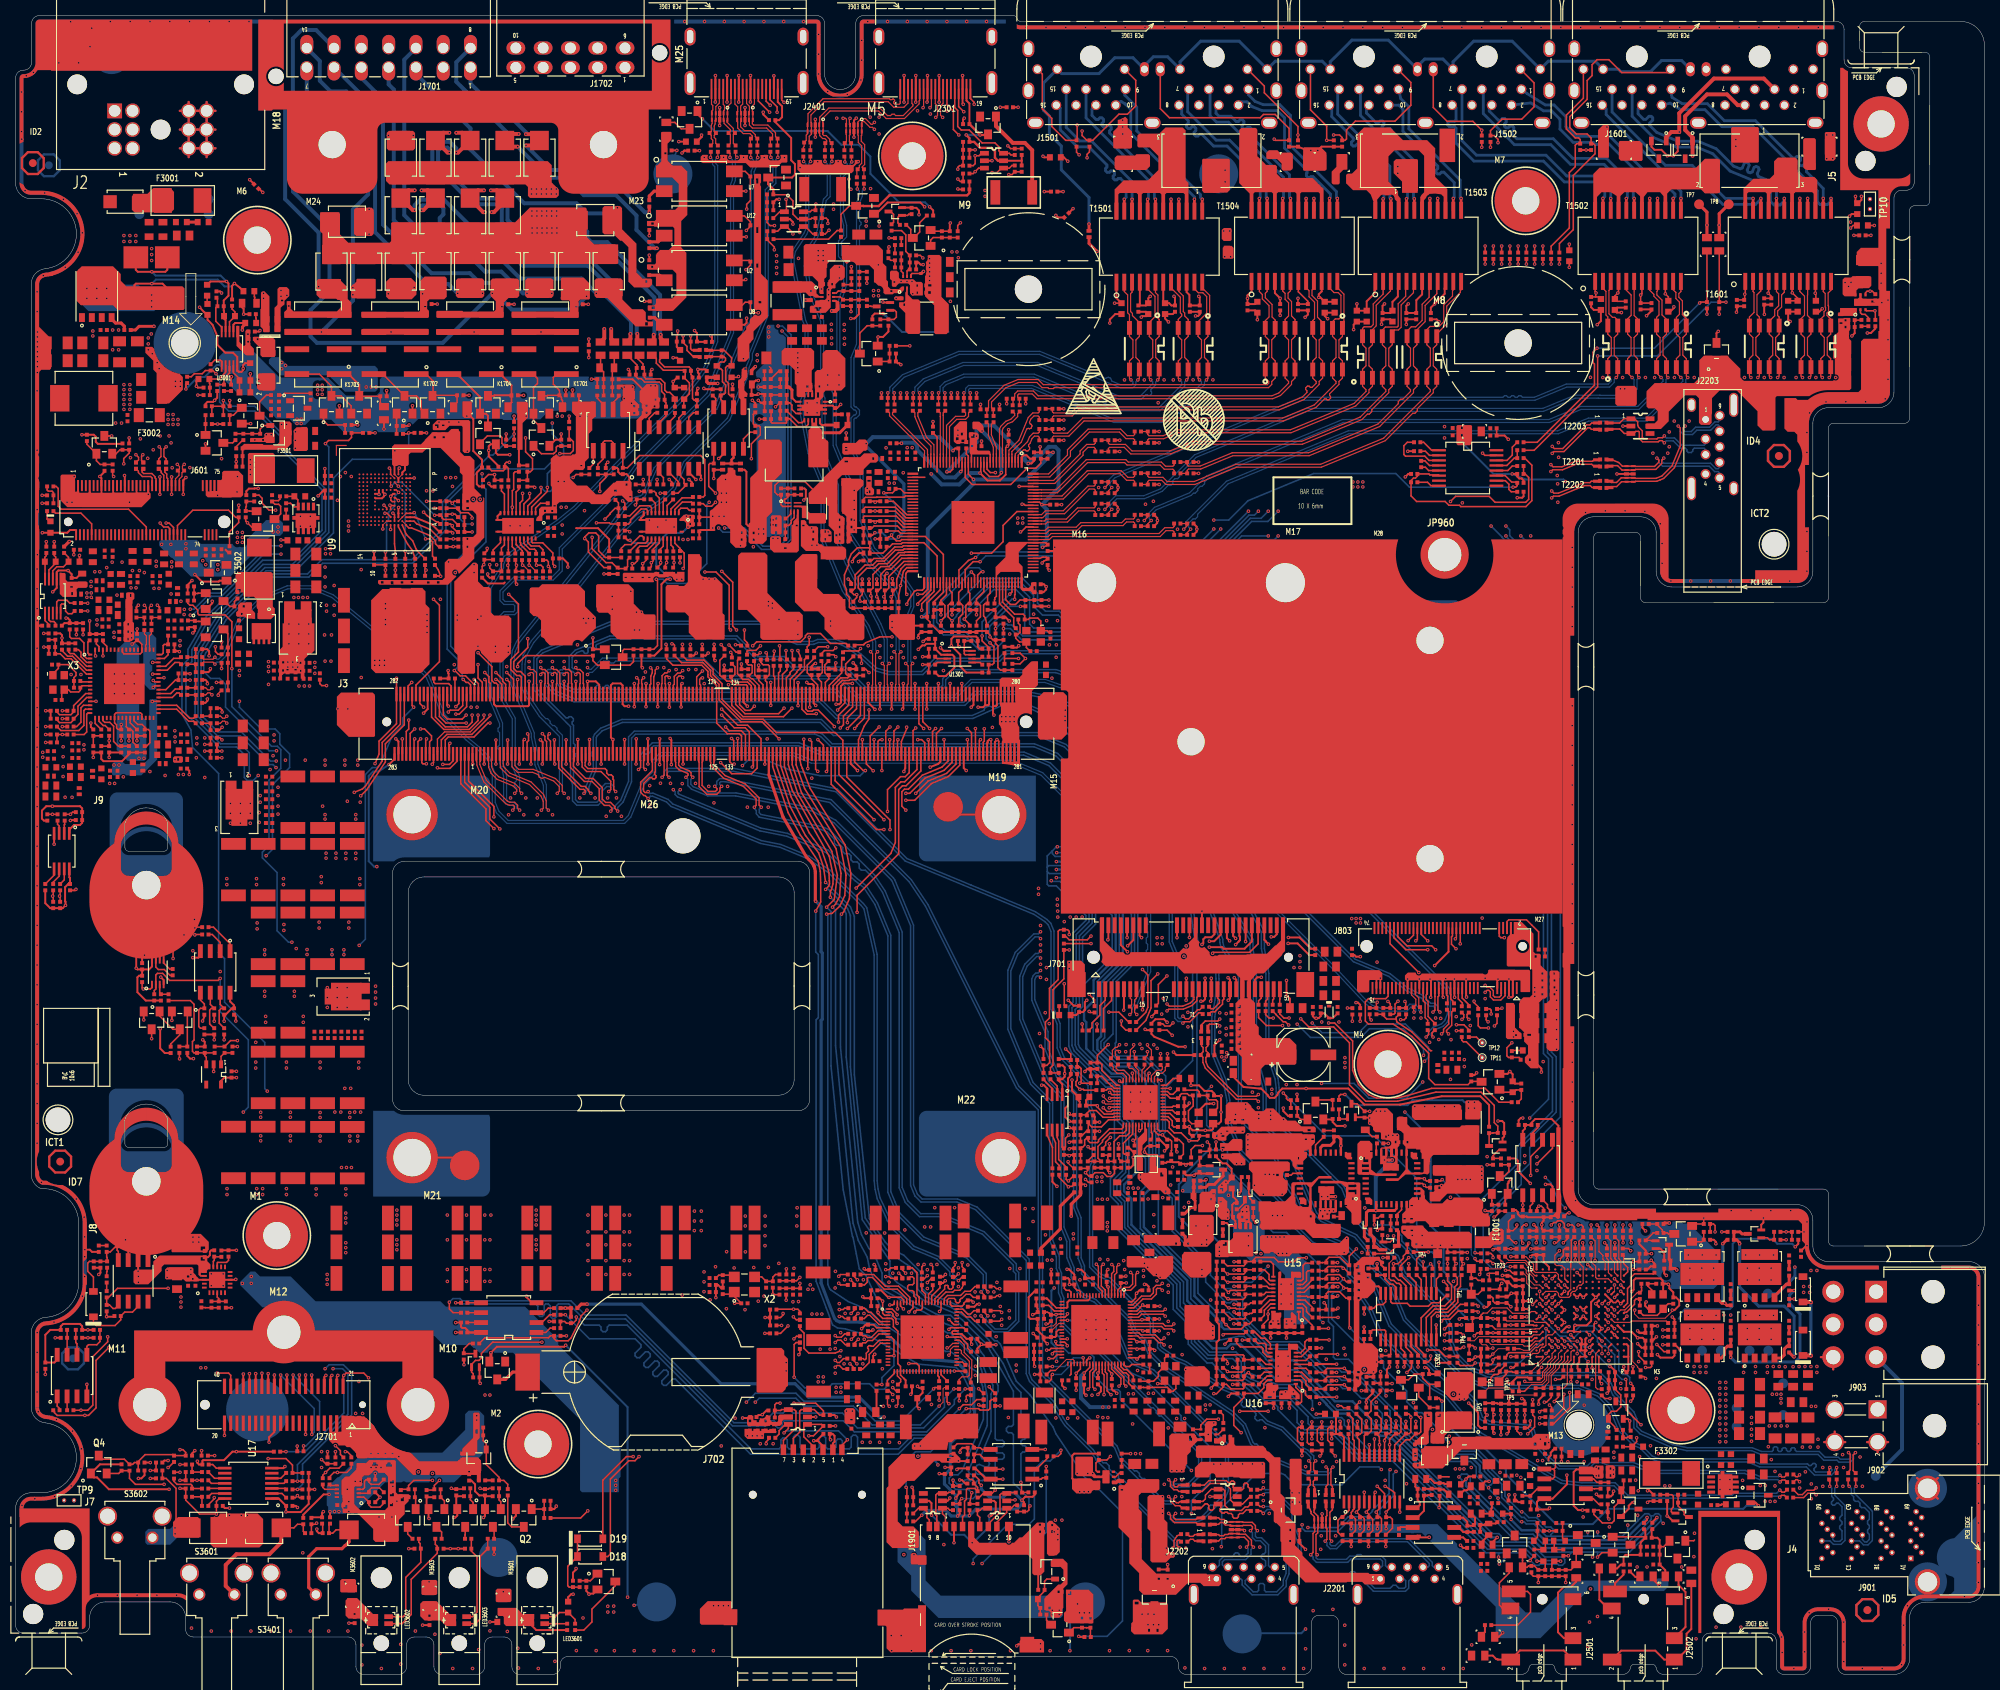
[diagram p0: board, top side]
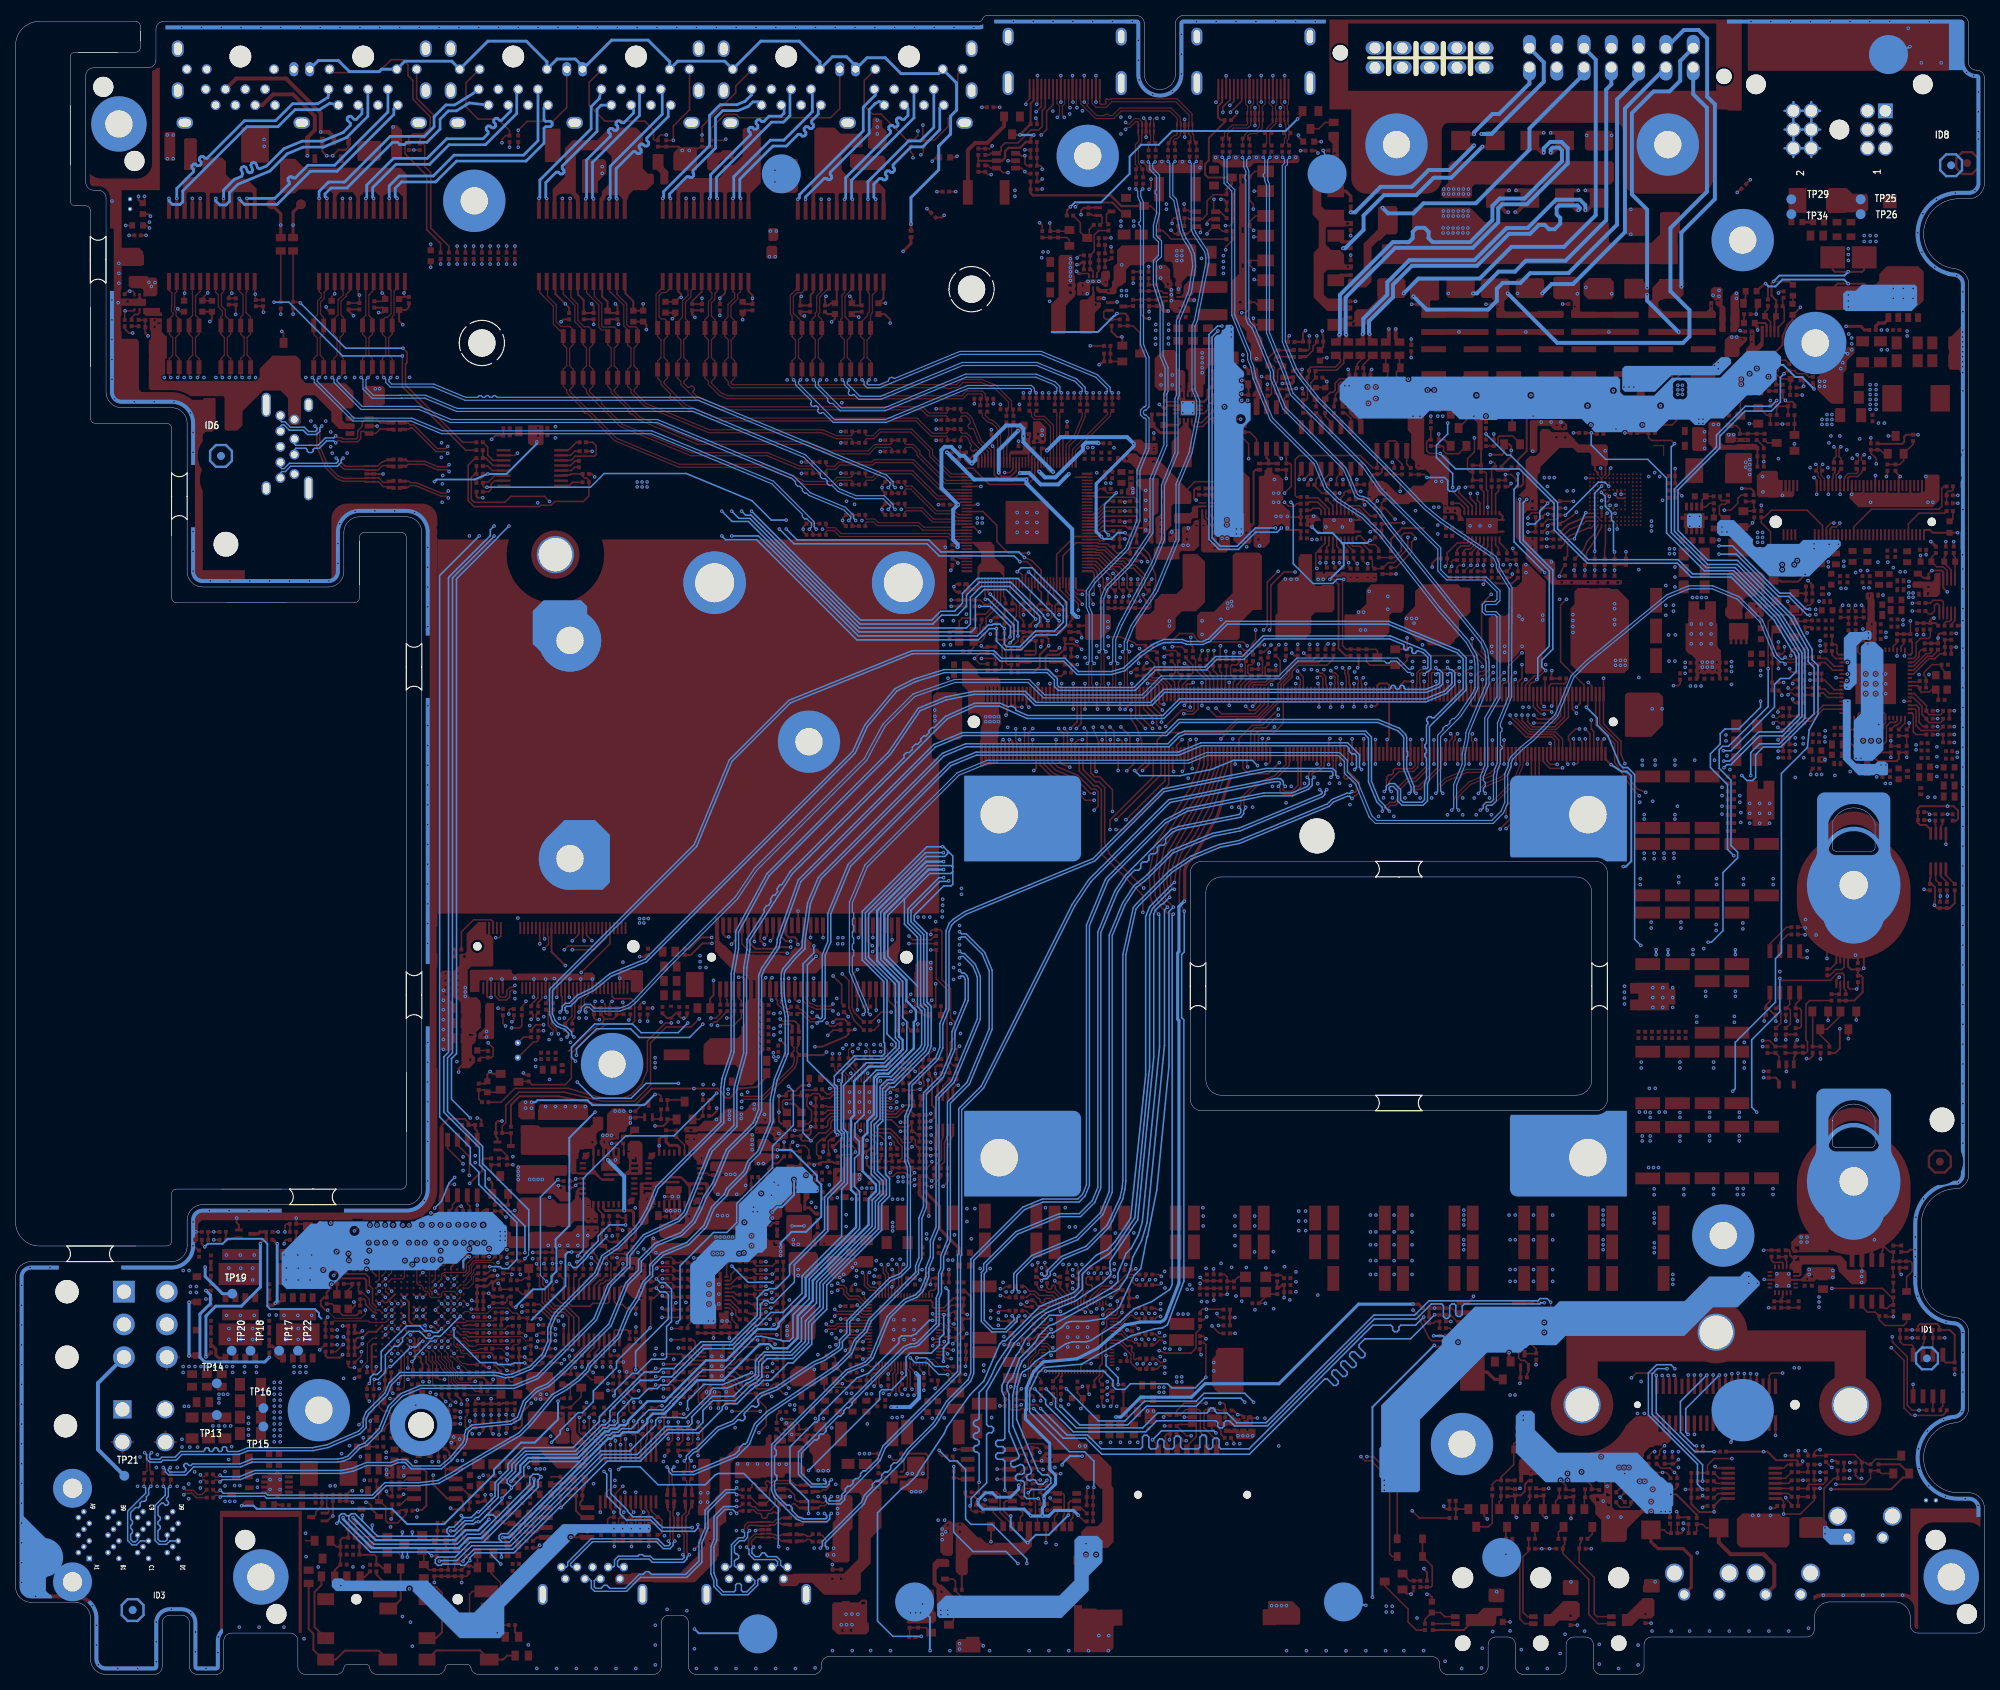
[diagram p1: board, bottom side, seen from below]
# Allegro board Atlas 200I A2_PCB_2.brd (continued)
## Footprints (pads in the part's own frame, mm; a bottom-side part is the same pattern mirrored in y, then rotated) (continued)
MLF8A-050-0203L
  rect 0.254x0.559 smd: 1(-0.75,-1.389) 2(-0.25,-1.389) 3(0.25,-1.389) 4(0.75,-1.389) 5(0.75,1.389) 6(0.25,1.389) 7(-0.25,1.389) 8(-0.75,1.389)
  rect 1.524x1.27 smd: 9(0,0)
MLF10B-050-0301L
  rect 0.254x0.533 smd: 1(-1,-0.417) 2(-0.5,-0.417) 4(0.5,-0.417) 5(1,-0.417) 6(1,0.417) 7(0.5,0.417) 9(-0.5,0.417) 10(-1,0.417)
  rect 0.432x0.686 smd: 3(0,-0.417) 8(0,0.417)
MLF14A-050-0404L
  rect 0.559x0.254 smd: 1(-1.629,-0.75) 7(1.629,-0.75) 8(1.629,0.75) 14(-1.629,0.75)
  rect 0.254x0.559 smd: 2(-1,-1.629) 3(-0.5,-1.629) 4(0,-1.629) 5(0.5,-1.629) 6(1,-1.629) 9(1,1.629) 10(0.5,1.629) 11(0,1.629) 12(-0.5,1.629) 13(-1,1.629)
  custom 0.508x0.508 smd: 15(0,0)
MLF20J-050-0404L
  rect 0.254x0.61 smd: 1(-1,-1.652) 2(-0.5,-1.652) 3(0,-1.652) 4(0.5,-1.652) 5(1,-1.652) 11(1,1.652) 12(0.5,1.652) 13(0,1.652) 14(-0.5,1.652) 15(-1,1.652)
  rect 0.61x0.254 smd: 6(1.652,-1) 7(1.652,-0.5) 8(1.652,0) 9(1.652,0.5) 10(1.652,1) 16(-1.652,1) 17(-1.652,0.5) 18(-1.652,0) 19(-1.652,-0.5) 20(-1.652,-1)
  rect 2.032x2.032 smd: 21(0,0)
MLF24D-050-0604L
  rect 0.559x0.254 smd: 1(-2.629,-0.75) 12(2.629,-0.75) 13(2.629,0.75) 24(-2.629,0.75)
  rect 0.254x0.559 smd: 2(-2.25,-1.629) 3(-1.75,-1.629) 4(-1.25,-1.629) 5(-0.75,-1.629) 6(-0.25,-1.629) 7(0.25,-1.629) 8(0.75,-1.629) 9(1.25,-1.629) 10(1.75,-1.629) 11(2.25,-1.629) 14(2.25,1.629) 15(1.75,1.629) 16(1.25,1.629) 17(0.75,1.629) 18(0.25,1.629) 19(-0.25,1.629) 20(-0.75,1.629) 21(-1.25,1.629) 22(-1.75,1.629) 23(-2.25,1.629)
  rect 4.064x2.032 smd: 25(0,0)
MLF36A-065-0707L
  rect 0.254x0.635 smd: 1(-2.604,-3.072) 9(2.602,-3.063) 27(-2.598,3.078)
  rect 0.305x0.813 smd: 2(-1.95,-3.306) 3(-1.3,-3.306) 4(-0.65,-3.306) 5(0,-3.306) 6(0.65,-3.306) 7(1.3,-3.306) 8(1.95,-3.306) 20(1.95,3.306) 21(1.3,3.306) 22(0.65,3.306) 23(0,3.306) 24(-0.65,3.306) 25(-1.3,3.306) 26(-1.95,3.306)
  custom 0.238x0.238 smd: 10(2.926,-2.926) 19(2.926,2.926) 28(-2.926,2.926) 36(-2.926,-2.926)
  rect 0.813x0.305 smd: 11(3.306,-1.95) 12(3.306,-1.3) 13(3.306,-0.65) 14(3.306,0) 15(3.306,0.65) 16(3.306,1.3) 17(3.306,1.95) 29(-3.306,1.95) 30(-3.306,1.3) 31(-3.306,0.65) 32(-3.306,0) 33(-3.306,-0.65) 34(-3.306,-1.3) 35(-3.306,-1.95)
  rect 0.635x0.254 smd: 18(3.059,2.599)
  rect 0.813x0.813 smd: 37(-1.421,-0.68) 38(-1.421,0.52)
  rect 0.305x2.591 smd: 39(-0.47,-0.65)
  rect 0.305x1.575 smd: 40(0.157,0.07)
MLF48A-040-0606L
  rect 0.203x0.61 smd: 1(-2.2,-2.879) 2(-1.8,-2.879) 3(-1.4,-2.879) 4(-1,-2.879) 5(-0.6,-2.879) 6(-0.2,-2.879) 7(0.2,-2.879) 8(0.6,-2.879) 9(1,-2.879) 10(1.4,-2.879) 11(1.8,-2.879) 12(2.2,-2.879) 25(2.2,2.879) 26(1.8,2.879) 27(1.4,2.879) 28(1,2.879) 29(0.6,2.879) 30(0.2,2.879) 31(-0.2,2.879) 32(-0.6,2.879) 33(-1,2.879) 34(-1.4,2.879) 35(-1.8,2.879) 36(-2.2,2.879)
  rect 0.61x0.203 smd: 13(2.879,-2.2) 14(2.879,-1.8) 15(2.879,-1.4) 16(2.879,-1) 17(2.879,-0.6) 18(2.879,-0.2) 19(2.879,0.2) 20(2.879,0.6) 21(2.879,1) 22(2.879,1.4) 23(2.879,1.8) 24(2.879,2.2) 37(-2.879,2.2) 38(-2.879,1.8) 39(-2.879,1.4) 40(-2.879,1) 41(-2.879,0.6) 42(-2.879,0.2) 43(-2.879,-0.2) 44(-2.879,-0.6) 45(-2.879,-1) 46(-2.879,-1.4) 47(-2.879,-1.8) 48(-2.879,-2.2)
  rect 4.445x4.445 smd: 49(0,0)
MLF64AG-050-0909L
  rect 0.254x0.559 smd: 1(-3.75,-4.379) 2(-3.25,-4.379) 3(-2.75,-4.379) 4(-2.25,-4.379) 5(-1.75,-4.379) 6(-1.25,-4.379) 7(-0.75,-4.379) 8(-0.25,-4.379) 9(0.25,-4.379) 10(0.75,-4.379) 11(1.25,-4.379) 12(1.75,-4.379) 13(2.25,-4.379) 14(2.75,-4.379) 15(3.25,-4.379) 16(3.75,-4.379) 33(3.75,4.379) 34(3.25,4.379) 35(2.75,4.379) 36(2.25,4.379) 37(1.75,4.379) 38(1.25,4.379) 39(0.75,4.379) 40(0.25,4.379) 41(-0.25,4.379) 42(-0.75,4.379) 43(-1.25,4.379) 44(-1.75,4.379) 45(-2.25,4.379) 46(-2.75,4.379) 47(-3.25,4.379) 48(-3.75,4.379)
  rect 0.559x0.254 smd: 17(4.379,-3.75) 18(4.379,-3.25) 19(4.379,-2.75) 20(4.379,-2.25) 21(4.379,-1.75) 22(4.379,-1.25) 23(4.379,-0.75) 24(4.379,-0.25) 25(4.379,0.25) 26(4.379,0.75) 27(4.379,1.25) 28(4.379,1.75) 29(4.379,2.25) 30(4.379,2.75) 31(4.379,3.25) 32(4.379,3.75) 49(-4.379,3.75) 50(-4.379,3.25) 51(-4.379,2.75) 52(-4.379,2.25) 53(-4.379,1.75) 54(-4.379,1.25) 55(-4.379,0.75) 56(-4.379,0.25) 57(-4.379,-0.25) 58(-4.379,-0.75) 59(-4.379,-1.25) 60(-4.379,-1.75) 61(-4.379,-2.25) 62(-4.379,-2.75) 63(-4.379,-3.25) 64(-4.379,-3.75)
  rect 5.207x5.207 smd: 65(0,0)
MLF76L-040-0909L
  rect 0.203x0.61 smd: 1(-3.6,-4.405) 2(-3.2,-4.405) 3(-2.8,-4.405) 4(-2.4,-4.405) 5(-2,-4.405) 6(-1.6,-4.405) 7(-1.2,-4.405) 8(-0.8,-4.405) 9(-0.4,-4.405) 10(0,-4.405) 11(0.4,-4.405) 12(0.8,-4.405) 13(1.2,-4.405) 14(1.6,-4.405) 15(2,-4.405) 16(2.4,-4.405) 17(2.8,-4.405) 18(3.2,-4.405) 19(3.6,-4.405) 39(3.6,4.405) 40(3.2,4.405) 41(2.8,4.405) 42(2.4,4.405) 43(2,4.405) 44(1.6,4.405) 45(1.2,4.405) 46(0.8,4.405) 47(0.4,4.405) 48(0,4.405) 49(-0.4,4.405) 50(-0.8,4.405) 51(-1.2,4.405) 52(-1.6,4.405) 53(-2,4.405) 54(-2.4,4.405) 55(-2.8,4.405) 56(-3.2,4.405) 57(-3.6,4.405)
  rect 0.61x0.203 smd: 20(4.405,-3.6) 21(4.405,-3.2) 22(4.405,-2.8) 23(4.405,-2.4) 24(4.405,-2) 25(4.405,-1.6) 26(4.405,-1.2) 27(4.405,-0.8) 28(4.405,-0.4) 29(4.405,0) 30(4.405,0.4) 31(4.405,0.8) 32(4.405,1.2) 33(4.405,1.6) 34(4.405,2) 35(4.405,2.4) 36(4.405,2.8) 37(4.405,3.2) 38(4.405,3.6) 58(-4.405,3.6) 59(-4.405,3.2) 60(-4.405,2.8) 61(-4.405,2.4) 62(-4.405,2) 63(-4.405,1.6) 64(-4.405,1.2) 65(-4.405,0.8) 66(-4.405,0.4) 67(-4.405,0) 68(-4.405,-0.4) 69(-4.405,-0.8) 70(-4.405,-1.2) 71(-4.405,-1.6) 72(-4.405,-2) 73(-4.405,-2.4) 74(-4.405,-2.8) 75(-4.405,-3.2) 76(-4.405,-3.6)
  rect 5.588x5.588 smd: 77(0,0)
MLF76Q-040-0909L
  rect 0.203x0.61 smd: 1(-3.6,-4.379) 2(-3.2,-4.379) 3(-2.8,-4.379) 4(-2.4,-4.379) 5(-2,-4.379) 6(-1.6,-4.379) 7(-1.2,-4.379) 8(-0.8,-4.379) 9(-0.4,-4.379) 10(0,-4.379) 11(0.4,-4.379) 12(0.8,-4.379) 13(1.2,-4.379) 14(1.6,-4.379) 15(2,-4.379) 16(2.4,-4.379) 17(2.8,-4.379) 18(3.2,-4.379) 19(3.6,-4.379) 39(3.6,4.379) 40(3.2,4.379) 41(2.8,4.379) 42(2.4,4.379) 43(2,4.379) 44(1.6,4.379) 45(1.2,4.379) 46(0.8,4.379) 47(0.4,4.379) 48(0,4.379) 49(-0.4,4.379) 50(-0.8,4.379) 51(-1.2,4.379) 52(-1.6,4.379) 53(-2,4.379) 54(-2.4,4.379) 55(-2.8,4.379) 56(-3.2,4.379) 57(-3.6,4.379)
  rect 0.61x0.203 smd: 20(4.379,-3.6) 21(4.379,-3.2) 22(4.379,-2.8) 23(4.379,-2.4) 24(4.379,-2) 25(4.379,-1.6) 26(4.379,-1.2) 27(4.379,-0.8) 28(4.379,-0.4) 29(4.379,0) 30(4.379,0.4) 31(4.379,0.8) 32(4.379,1.2) 33(4.379,1.6) 34(4.379,2) 35(4.379,2.4) 36(4.379,2.8) 37(4.379,3.2) 38(4.379,3.6) 58(-4.379,3.6) 59(-4.379,3.2) 60(-4.379,2.8) 61(-4.379,2.4) 62(-4.379,2) 63(-4.379,1.6) 64(-4.379,1.2) 65(-4.379,0.8) 66(-4.379,0.4) 67(-4.379,0) 68(-4.379,-0.4) 69(-4.379,-0.8) 70(-4.379,-1.2) 71(-4.379,-1.6) 72(-4.379,-2) 73(-4.379,-2.4) 74(-4.379,-2.8) 75(-4.379,-3.2) 76(-4.379,-3.6)
  rect 6.35x6.35 smd: 77(0,0)
MOUNT3-2009F
  round 2.591 hole 2.591 unplated: (-4.75,2) (4.75,-2)
  round 7.112 hole 3.505: 1(0,0)
PIDC36-DRF-C
  round 3.251 hole 2.489: 37(-3,-2.15) 38(9,-2.15)
  rect 0.711x0.711 hole 0.356: A1(0,0)
  round 0.711 hole 0.356: A2(0.75,-1.4) A3(1.5,-0.7) A4(2.25,0) A5(3,-1.4) A6(3.75,-0.7) A7(4.5,0) A8(5.25,-1.4) A9(6,-0.7) B1(0,3.8) B2(0.75,2.4) B3(1.5,3.1) B4(2.25,3.8) B5(3,2.4) B6(3.75,3.1) B7(4.5,3.8) B8(5.25,2.4) B9(6,3.1) C1(0,7.6) C2(0.75,6.2) C3(1.5,6.9) C4(2.25,7.6) C5(3,6.2) C6(3.75,6.9) C7(4.5,7.6) C8(5.25,6.2) C9(6,6.9) D1(0,11.4) D2(0.75,10) D3(1.5,10.7) D4(2.25,11.4) D5(3,10) D6(3.75,10.7) D7(4.5,11.4) D8(5.25,10) D9(6,10.7)
PMR0203-165RQ-A
  round 2.997 hole 2.997 unplated: (-8.4,-7.3) (0,-7.3)
  rect 2.794x2.794 hole 1.829: 1(0,0)
  round 2.794 hole 1.829: 2(-4.2,0) 3(-8.4,0) 4(0,5.5) 5(-4.2,5.5) 6(-8.4,5.5)
PPWC0304-RF
  round 2.54 hole 2.54 unplated: (-16.6,-3.4) (-5.9,2.4) (4.8,-3.4)
  rect 1.905x1.905 hole 1.499: 1(0,0)
  round 1.905 hole 1.499: 2(-2.3,0) 3(-9.5,0) 4(-11.8,0) 5(0,2.4) 6(-2.3,2.4) 7(-9.5,2.4) 8(-11.8,2.4) 9(0,4.8) 10(-2.3,4.8) 11(-9.5,4.8) 12(-11.8,4.8)
QFP128HG-040-1414L
  rect 0.305x1.397 smd: 1(-6.251,-7.717) 32(6.251,-7.717) 65(6.251,7.717) 96(-6.251,7.717)
  rect 0.203x1.397 smd: 2(-5.8,-7.717) 3(-5.4,-7.717) 4(-5,-7.717) 5(-4.6,-7.717) 6(-4.2,-7.717) 7(-3.8,-7.717) 8(-3.4,-7.717) 9(-3,-7.717) 10(-2.6,-7.717) 11(-2.2,-7.717) 12(-1.8,-7.717) 13(-1.4,-7.717) 14(-1,-7.717) 15(-0.6,-7.717) 16(-0.2,-7.717) 17(0.2,-7.717) 18(0.6,-7.717) 19(1,-7.717) 20(1.4,-7.717) 21(1.8,-7.717) 22(2.2,-7.717) 23(2.6,-7.717) 24(3,-7.717) 25(3.4,-7.717) 26(3.8,-7.717) 27(4.2,-7.717) 28(4.6,-7.717) 29(5,-7.717) 30(5.4,-7.717) 31(5.8,-7.717) 66(5.8,7.717) 67(5.4,7.717) 68(5,7.717) 69(4.6,7.717) 70(4.2,7.717) 71(3.8,7.717) 72(3.4,7.717) 73(3,7.717) 74(2.6,7.717) 75(2.2,7.717) 76(1.8,7.717) 77(1.4,7.717) 78(1,7.717) 79(0.6,7.717) 80(0.2,7.717) 81(-0.2,7.717) 82(-0.6,7.717) 83(-1,7.717) 84(-1.4,7.717) 85(-1.8,7.717) 86(-2.2,7.717) 87(-2.6,7.717) 88(-3,7.717) 89(-3.4,7.717) 90(-3.8,7.717) 91(-4.2,7.717) 92(-4.6,7.717) 93(-5,7.717) 94(-5.4,7.717) 95(-5.8,7.717)
  rect 1.397x0.305 smd: 33(7.717,-6.251) 64(7.717,6.251) 97(-7.717,6.251) 128(-7.717,-6.251)
  rect 1.397x0.203 smd: 34(7.717,-5.8) 35(7.717,-5.4) 36(7.717,-5) 37(7.717,-4.6) 38(7.717,-4.2) 39(7.717,-3.8) 40(7.717,-3.4) 41(7.717,-3) 42(7.717,-2.6) 43(7.717,-2.2) 44(7.717,-1.8) 45(7.717,-1.4) 46(7.717,-1) 47(7.717,-0.6) 48(7.717,-0.2) 49(7.717,0.2) 50(7.717,0.6) 51(7.717,1) 52(7.717,1.4) 53(7.717,1.8) 54(7.717,2.2) 55(7.717,2.6) 56(7.717,3) 57(7.717,3.4) 58(7.717,3.8) 59(7.717,4.2) 60(7.717,4.6) 61(7.717,5) 62(7.717,5.4) 63(7.717,5.8) 98(-7.717,5.8) 99(-7.717,5.4) 100(-7.717,5) 101(-7.717,4.6) 102(-7.717,4.2) 103(-7.717,3.8) 104(-7.717,3.4) 105(-7.717,3) 106(-7.717,2.6) 107(-7.717,2.2) 108(-7.717,1.8) 109(-7.717,1.4) 110(-7.717,1) 111(-7.717,0.6) 112(-7.717,0.2) 113(-7.717,-0.2) 114(-7.717,-0.6) 115(-7.717,-1) 116(-7.717,-1.4) 117(-7.717,-1.8) 118(-7.717,-2.2) 119(-7.717,-2.6) 120(-7.717,-3) 121(-7.717,-3.4) 122(-7.717,-3.8) 123(-7.717,-4.2) 124(-7.717,-4.6) 125(-7.717,-5) 126(-7.717,-5.4) 127(-7.717,-5.8)
  rect 5.512x5.512 smd: 129(0,0)
RF8-FSC-FDMS86181
  rect 0.762x1.143 smd: 1(-1.905,-2.725) 2(-0.635,-2.725) 3(0.635,-2.725) 4(1.905,-2.725)
  rect 5.588x2.819 smd: 5(0,0.313)
  rect 0.457x0.965 smd: 6(1.778,2.75) 8(-1.778,2.75)
  rect 4.699x1.397 smd: 7(0,2.814)
RF8-NXP-PSMN1R0
  rect 0.762x1.143 smd: 1(-1.905,-2.725) 2(-0.635,-2.725) 3(0.635,-2.725) 4(1.905,-2.725)
  rect 4.191x2.692 smd: 5(0,0.25)
  rect 0.457x0.965 smd: 6(1.778,2.75) 8(-1.778,2.75)
  rect 4.699x1.524 smd: 7(0,2.75)
RF8-TOS-TPCC8105
  rect 0.356x0.762 smd: 1(-0.975,-1.625) 2(-0.325,-1.625) 3(0.325,-1.625) 4(0.975,-1.625) 5(0.975,1.625) 6(0.325,1.625) 7(-0.325,1.625)
  custom 0.623x0.623 smd: 8(0,0.653)
RHOLE168-T244B188
  round 6.198 hole 4.267: 1(0,0)
RHOLE168-T244B188B
  round 6.198 hole 4.267: 1(0,0)
RHOLE189-254
  round 6.604 hole 4.801: 1(0,0)
RTSW4-RG
  round 1.575 hole 1.067: 1(-2.25,-0.825) 2(2.25,-0.825)
  round 2.438 hole 1.93: 3(-3.5,1.925) 4(3.5,1.925)
RUSB9-180-0726J
  round 1.27 hole 0.864: 1(-0.9,9.155) 2(-0.9,6.655) 3(-0.9,4.655) 4(-0.9,2.155) 5(0.9,1.655) 6(0.9,3.655) 7(0.9,5.655) 8(0.9,7.655) 9(0.9,9.655)
  oval 1.194x3.099 hole 0.787x2.692: 10(-2.71,0.325) 12(2.71,11.025)
  oval 1.194x1.803 hole 0.787x1.397: 11(2.71,0.325) 13(-2.71,11.025)
RUSB9-200-1417A
  round 1.118 hole 0.711: 1(-3.5,5.53) 2(-1,5.53) 3(1,5.53) 4(3.5,5.53) 5(4,7.03) 6(2,7.03) 7(0,7.03) 8(-2,7.03) 9(-4,7.03)
  oval 1.27x2.667 hole 0.762x2.159: 10(-6.4,3.53) 11(6.4,3.53)
RUSB19-050-1512
  rect 0.254x2.591 smd: 1(4.5,5.22) 2(4,5.22) 3(3.5,5.22) 4(3,5.22) 5(2.5,5.22) 6(2,5.22) 7(1.5,5.22) 8(1,5.22) 9(0.5,5.22) 10(0,5.22) 11(-0.5,5.22) 12(-1,5.22) 13(-1.5,5.22) 14(-2,5.22) 15(-2.5,5.22) 16(-3,5.22) 17(-3.5,5.22) 18(-4,5.22) 19(-4.5,5.22)
  oval 1.422x3.099 hole 0.813x2.489: 20(-7.25,4.46) 21(7.25,4.46)
  oval 1.422x2.286 hole 0.813x1.702: 22(-7.25,-1.5) 23(7.25,-1.5)
RWBC0202-165R-A
  round 2.997 hole 2.997 unplated: (-0.2,-3.368)
  rect 2.337x2.337 hole 1.829: 1(1.9,3.932)
  round 2.337 hole 1.829: 2(-2.3,3.932) 3(1.9,9.432) 4(-2.3,9.432)
SBAT2-3209
  rect 3.15x4.775 smd: 1(-16.47,0) 2(14.57,0)
SC0402
  rect 0.508x0.508 smd: 1(-0.406,0) 2(0.406,0)
SC0402-PA
  rect 0.508x0.508 smd: 1(-0.406,0) 2(0.406,0)
SC0402-PB
  rect 0.508x0.508 smd: 1(-0.406,0) 2(0.406,0)
SC0402-PD
  rect 0.508x0.508 smd: 1(-0.406,0) 2(0.406,0)
SC0603-TB
  rect 0.762x0.813 smd: 1(-0.699,0) 2(0.699,0)
SC0603-TC
  rect 0.762x0.813 smd: 1(-0.699,0) 2(0.699,0)
SC0603-TD
  rect 0.762x0.813 smd: 1(-0.699,0) 2(0.699,0)
SC0603B
  rect 0.762x1.041 smd: 1(-0.699,0) 2(0.699,0)
SC0805-TD
  rect 0.991x1.27 smd: 1(-0.813,0) 2(0.813,0)
SC1206-TD
  rect 1.295x1.651 smd: 1(-1.346,0) 2(1.346,0)
SC1206-TF
  rect 1.295x1.651 smd: 1(-1.346,0) 2(1.346,0)
SC1206E
  rect 1.295x1.905 smd: 1(-1.346,0) 2(1.346,0)
SCAPC2-0707B
  rect 3.302x1.397 smd: 1(-2.551,0) 2(2.551,0)
SD3-2618C
  rect 1.397x1.27 smd: 1(1.065,-2.795) 2(-1.065,-2.795)
  custom 0.887x0.887 smd: 3(0,0)
SD1107S
  rect 0.864x1.118 smd: 1(1.626,0) 2(-1.626,0)
SD1710A
  rect 1.727x1.676 smd: 1(-1.93,0) 2(1.93,0)
SD1814C
  rect 2.489x2.413 smd: 1(-2.195,0) 2(2.195,0)
SD2211
  rect 2.184x1.626 smd: 1(2.14,0) 2(-2.14,0)
SDA4-0606
  rect 1.118x0.61 smd: 1(-0.95,-0.45) 2(-0.95,0.45) 3(0.95,0.45) 4(0.95,-0.45)
SDIM0226-32
  round 1.651 hole 1.651 unplated: (-12.5,0)
  round 1.143 hole 1.143 unplated: (12.5,0)
  rect 0.508x2.032 smd: 1(-11.8,-4.1) 2(-11.4,4.1) 3(-11,-4.1) 4(-10.6,4.1) 5(-10.2,-4.1) 6(-9.8,4.1) 7(-9.4,-4.1) 8(-9,4.1) 9(-8.6,-4.1) 10(-8.2,4.1) 11(-7.8,-4.1) 12(-7.4,4.1) 13(-7,-4.1) 14(-6.6,4.1) 15(-6.2,-4.1) 16(-5.8,4.1) 17(-2.2,-4.1) 18(-1.8,4.1) 19(-1.4,-4.1) 20(-1,4.1) 21(-0.6,-4.1) 22(-0.2,4.1) 23(0.2,-4.1) 24(0.6,4.1) 25(1,-4.1) 26(1.4,4.1) 27(1.8,-4.1) 28(2.2,4.1) 29(2.6,-4.1) 30(3,4.1) 31(3.4,-4.1) 32(3.8,4.1) 33(4.2,-4.1) 34(4.6,4.1) 35(5,-4.1) 36(5.4,4.1) 37(5.8,-4.1) 38(6.2,4.1) 39(6.6,-4.1) 40(7,4.1) 41(7.4,-4.1) 42(7.8,4.1) 43(8.2,-4.1) 44(8.6,4.1) 45(9,-4.1) 46(9.4,4.1) 47(9.8,-4.1) 48(10.2,4.1) 49(10.6,-4.1) 50(11,4.1) 51(11.4,-4.1) 52(11.8,4.1)
  rect 2.286x3.2 smd: 53(-14.65,-3.5) 54(14.65,-3.5)
SDIM02161-20B
  round 1.143 hole 1.143 unplated: (-41,0.25)
  round 1.6 hole 1.6 unplated: (41,0.25)
  rect 0.305x1.778 smd: 1(-30,-3.861) 3(-29.5,-3.861) 5(-29,-3.861) 7(-28.5,-3.861) 9(-28,-3.861) 11(-27.5,-3.861) 13(-27,-3.861) 15(-26.5,-3.861) 17(-26,-3.861) 19(-25.5,-3.861) 21(-25,-3.861) 23(-24.5,-3.861) 25(-24,-3.861) 27(-23.5,-3.861) 29(-23,-3.861) 31(-22.5,-3.861) 33(-22,-3.861) 35(-21.5,-3.861) 37(-21,-3.861) 39(-20.5,-3.861) 41(-20,-3.861) 43(-19.5,-3.861) 45(-19,-3.861) 47(-18.5,-3.861) 49(-18,-3.861) 51(-17.5,-3.861) 53(-17,-3.861) 55(-16.5,-3.861) 57(-16,-3.861) 59(-15.5,-3.861) 61(-15,-3.861) 63(-14.5,-3.861) 65(-14,-3.861) 67(-13.5,-3.861) 69(-13,-3.861) 71(-12.5,-3.861) 73(-12,-3.861) 75(-11.5,-3.861) 77(-11,-3.861) 79(-10.5,-3.861) 81(-10,-3.861) 83(-9.5,-3.861) 85(-9,-3.861) 87(-8.5,-3.861) 89(-8,-3.861) 91(-7.5,-3.861) 93(-7,-3.861) 95(-6.5,-3.861) 97(-6,-3.861) 99(-5.5,-3.861) 101(-5,-3.861) 103(-4.5,-3.861) 105(-4,-3.861) 107(-3.5,-3.861) 109(-3,-3.861) 111(-2.5,-3.861) 113(-2,-3.861) 115(-1.5,-3.861) 117(-1,-3.861) 119(-0.5,-3.861) 121(0,-3.861) 123(0.5,-3.861) 125(1,-3.861) 133(3,-3.861) 135(3.5,-3.861) 137(4,-3.861) 139(4.5,-3.861) 141(5,-3.861) 143(5.5,-3.861) 145(6,-3.861) 147(6.5,-3.861) 149(7,-3.861) 151(7.5,-3.861) 153(8,-3.861) 155(8.5,-3.861) 157(9,-3.861) 159(9.5,-3.861) 161(10,-3.861) 163(10.5,-3.861) 165(11,-3.861) 167(11.5,-3.861) 169(12,-3.861) 171(12.5,-3.861) 173(13,-3.861) 175(13.5,-3.861) 177(14,-3.861) 179(14.5,-3.861) 181(15,-3.861) 183(15.5,-3.861) 185(16,-3.861) 187(16.5,-3.861) 189(17,-3.861) 191(17.5,-3.861) 193(18,-3.861) 195(18.5,-3.861) 197(19,-3.861) 199(19.5,-3.861) 201(20,-3.861) 203(20.5,-3.861) 205(21,-3.861) 207(21.5,-3.861) 209(22,-3.861) 211(22.5,-3.861) 213(23,-3.861) 215(23.5,-3.861) 217(24,-3.861) 219(24.5,-3.861) 221(25,-3.861) 223(25.5,-3.861) 225(26,-3.861) 227(26.5,-3.861) 229(27,-3.861) 231(27.5,-3.861) 233(28,-3.861) 235(28.5,-3.861) 237(29,-3.861) 239(29.5,-3.861) 241(30,-3.861) 243(30.5,-3.861) 245(31,-3.861) 247(31.5,-3.861) 249(32,-3.861) 251(32.5,-3.861) 253(33,-3.861) 255(33.5,-3.861) 257(34,-3.861) 259(34.5,-3.861) 261(35,-3.861) 263(35.5,-3.861) 265(36,-3.861) 267(36.5,-3.861) 269(37,-3.861) 271(37.5,-3.861) 273(38,-3.861) 275(38.5,-3.861) 277(39,-3.861) 279(39.5,-3.861) 281(40,-3.861) 283(-40,-3.861) 285(-39.5,-3.861) 287(-39,-3.861) 289(-38.5,-3.861) 291(-38,-3.861) 293(-37.5,-3.861) 295(-37,-3.861) 297(-36.5,-3.861) 299(-36,-3.861) 301(-35.5,-3.861) 303(-35,-3.861) 305(-34.5,-3.861) 307(-34,-3.861) 309(-33.5,-3.861) 311(-33,-3.861) 313(-32.5,-3.861) 315(-32,-3.861) 317(-31.5,-3.861) 319(-31,-3.861) 321(-30.5,-3.861)
  rect 0.305x1.88 smd: 2(-29.75,3.811) 4(-29.25,3.811) 6(-28.75,3.811) 8(-28.25,3.811) 10(-27.75,3.811) 12(-27.25,3.811) 14(-26.75,3.811) 16(-26.25,3.811) 18(-25.75,3.811) 20(-25.25,3.811) 22(-24.75,3.811) 24(-24.25,3.811) 26(-23.75,3.811) 28(-23.25,3.811) 30(-22.75,3.811) 32(-22.25,3.811) 34(-21.75,3.811) 36(-21.25,3.811) 38(-20.75,3.811) 40(-20.25,3.811) 42(-19.75,3.811) 44(-19.25,3.811) 46(-18.75,3.811) 48(-18.25,3.811) 50(-17.75,3.811) 52(-17.25,3.811) 54(-16.75,3.811) 56(-16.25,3.811) 58(-15.75,3.811) 60(-15.25,3.811) 62(-14.75,3.811) 64(-14.25,3.811) 66(-13.75,3.811) 68(-13.25,3.811) 70(-12.75,3.811) 72(-12.25,3.811) 74(-11.75,3.811) 76(-11.25,3.811) 78(-10.75,3.811) 80(-10.25,3.811) 82(-9.75,3.811) 84(-9.25,3.811) 86(-8.75,3.811) 88(-8.25,3.811) 90(-7.75,3.811) 92(-7.25,3.811) 94(-6.75,3.811) 96(-6.25,3.811) 98(-5.75,3.811) 100(-5.25,3.811) 102(-4.75,3.811) 104(-4.25,3.811) 106(-3.75,3.811) 108(-3.25,3.811) 110(-2.75,3.811) 112(-2.25,3.811) 114(-1.75,3.811) 116(-1.25,3.811) 118(-0.75,3.811) 120(-0.25,3.811) 122(0.25,3.811) 124(0.75,3.811) 134(3.25,3.811) 136(3.75,3.811) 138(4.25,3.811) 140(4.75,3.811) 142(5.25,3.811) 144(5.75,3.811) 146(6.25,3.811) 148(6.75,3.811) 150(7.25,3.811) 152(7.75,3.811) 154(8.25,3.811) 156(8.75,3.811) 158(9.25,3.811) 160(9.75,3.811) 162(10.25,3.811) 164(10.75,3.811) 166(11.25,3.811) 168(11.75,3.811) 170(12.25,3.811) 172(12.75,3.811) 174(13.25,3.811) 176(13.75,3.811) 178(14.25,3.811) 180(14.75,3.811) 182(15.25,3.811) 184(15.75,3.811) 186(16.25,3.811) 188(16.75,3.811) 190(17.25,3.811) 192(17.75,3.811) 194(18.25,3.811) 196(18.75,3.811) 198(19.25,3.811) 200(19.75,3.811) 202(20.25,3.811) 204(20.75,3.811) 206(21.25,3.811) 208(21.75,3.811) 210(22.25,3.811) 212(22.75,3.811) 214(23.25,3.811) 216(23.75,3.811) 218(24.25,3.811) 220(24.75,3.811) 222(25.25,3.811) 224(25.75,3.811) 226(26.25,3.811) 228(26.75,3.811) 230(27.25,3.811) 232(27.75,3.811) 234(28.25,3.811) 236(28.75,3.811) 238(29.25,3.811) 240(29.75,3.811) 242(30.25,3.811) 244(30.75,3.811) 246(31.25,3.811) 248(31.75,3.811) 250(32.25,3.811) 252(32.75,3.811) 254(33.25,3.811) 256(33.75,3.811) 258(34.25,3.811) 260(34.75,3.811) 262(35.25,3.811) 264(35.75,3.811) 266(36.25,3.811) 268(36.75,3.811) 270(37.25,3.811) 272(37.75,3.811) 274(38.25,3.811) 276(38.75,3.811) 278(39.25,3.811) 280(39.75,3.811) 282(-39.75,3.811) 284(-39.25,3.811) 286(-38.75,3.811) 288(-38.25,3.811) 290(-37.75,3.811) 292(-37.25,3.811) 294(-36.75,3.811) 296(-36.25,3.811) 298(-35.75,3.811) 300(-35.25,3.811) 302(-34.75,3.811) 304(-34.25,3.811) 306(-33.75,3.811) 308(-33.25,3.811) 310(-32.75,3.811) 312(-32.25,3.811) 314(-31.75,3.811) 316(-31.25,3.811) 318(-30.75,3.811) 320(-30.25,3.811)
  round 0 smd: 126(1.25,3.811) 127(1.5,-4.095) 128(1.75,3.811) 129(2,-4.095) 130(2.25,3.811) 131(2.5,-4.095) 132(2.75,3.811)
  rect 2.997x5.156 smd: 322(-44,1) 323(44,1)
SED40-32M-H
  round 1.245 hole 1.245 unplated: (-10.1,0)
  round 0.864 hole 0.864 unplated: (10.1,0)
  rect 0.406x1.981 smd: 1(7.6,-2.368) 2(6.8,-2.368) 3(6,-2.368) 4(5.2,-2.368) 5(4.4,-2.368) 6(3.6,-2.368) 7(2.8,-2.368) 8(2,-2.368) 9(1.2,-2.368) 10(0.4,-2.368) 11(-0.4,-2.368) 12(-1.2,-2.368) 13(-2,-2.368) 14(-2.8,-2.368) 15(-3.6,-2.368) 16(-4.4,-2.368) 17(-5.2,-2.368) 18(-6,-2.368) 19(-6.8,-2.368) 20(-7.6,-2.368) 21(7.6,2.368) 22(6.8,2.368) 23(6,2.368) 24(5.2,2.368) 25(4.4,2.368) 26(3.6,2.368) 27(2.8,2.368) 28(2,2.368) 29(1.2,2.368) 30(0.4,2.368) 31(-0.4,2.368) 32(-1.2,2.368) 33(-2,2.368) 34(-2.8,2.368) 35(-3.6,2.368) 36(-4.4,2.368) 37(-5.2,2.368) 38(-6,2.368) 39(-6.8,2.368) 40(-7.6,2.368)
SF2-0302A
  rect 1.295x1.803 smd: 1(-1.346,0) 2(1.346,0)
SF1913
  rect 1.27x3.15 smd: 1(-2.362,0) 2(2.362,0)
SF6127
  rect 2.286x3.175 smd: 1(-2.54,0) 2(2.54,0)
SL4-0102
  rect 0.406x0.889 smd: 1(-0.406,-0.864) 2(-0.406,0.864) 3(0.406,0.864) 4(0.406,-0.864)
SL0402C
  rect 0.483x0.66 smd: 1(-0.4,0) 2(0.4,0)
SL0805
  rect 0.94x1.27 smd: 1(-0.851,0) 2(0.851,0)
SL0805-TD
  rect 0.94x1.27 smd: 1(-0.851,0) 2(0.851,0)
SL0806A
  rect 0.762x1.651 smd: 1(-0.821,0) 2(0.821,0)
SL0806B
  rect 0.94x1.803 smd: 1(-0.851,0) 2(0.851,0)
SL1008H
  rect 1.321x2.032 smd: 1(-1.26,0) 2(1.26,0)
SOP4-100-256B
  rect 1.524x2.134 smd: 1(-1.27,-4.496) 2(1.27,-4.496) 3(1.27,4.496) 4(-1.27,4.496)
SOP8-20-91C
  rect 0.254x0.965 smd: 1(-0.75,-1.584) 2(-0.25,-1.584) 3(0.25,-1.584) 4(0.75,-1.584) 5(0.75,1.584) 6(0.25,1.584) 7(-0.25,1.584) 8(-0.75,1.584)
SOP8-26-118C
  rect 0.356x1.651 smd: 1(-0.975,-2.276) 2(-0.325,-2.276) 3(0.325,-2.276) 4(0.975,-2.276) 5(0.975,2.276) 6(0.325,2.276) 7(-0.325,2.276) 8(-0.975,2.276)
SOP8-50-150B
  rect 0.635x1.981 smd: 1(-1.905,-2.648) 2(-0.635,-2.648) 3(0.635,-2.648) 4(1.905,-2.648) 5(1.905,2.648) 6(0.635,2.648) 7(-0.635,2.648) 8(-1.905,2.648)
SOP8-50-154C
  rect 0.635x1.778 smd: 1(-1.905,-2.667) 2(-0.635,-2.667) 3(0.635,-2.667) 4(1.905,-2.667) 5(1.905,2.667) 6(0.635,2.667) 7(-0.635,2.667) 8(-1.905,2.667)
SOP8-50-154M
  rect 0.635x1.778 smd: 1(-1.905,-2.667) 2(-0.635,-2.667) 3(0.635,-2.667) 4(1.905,-2.667) 5(1.905,2.667) 6(0.635,2.667) 7(-0.635,2.667) 8(-1.905,2.667)
SOP8-50-173
  rect 0.635x1.778 smd: 1(-1.905,-2.667) 2(-0.635,-2.667) 3(0.635,-2.667) 4(1.905,-2.667) 5(1.905,2.667) 6(0.635,2.667) 7(-0.635,2.667) 8(-1.905,2.667)
SOP8-50-208
  rect 0.635x1.778 smd: 1(-1.905,-3.556) 2(-0.635,-3.556) 3(0.635,-3.556) 4(1.905,-3.556) 5(1.905,3.556) 6(0.635,3.556) 7(-0.635,3.556) 8(-1.905,3.556)
SOP10-20-118
  rect 0.254x1.473 smd: 1(-1,-2.212) 2(-0.5,-2.212) 3(0,-2.212) 4(0.5,-2.212) 5(1,-2.212) 6(1,2.212) 7(0.5,2.212) 8(0,2.212) 9(-0.5,2.212) 10(-1,2.212)
SOP10-20-124A
  rect 0.254x1.651 smd: 1(-1,-2.184) 2(-0.5,-2.184) 3(0,-2.184) 4(0.5,-2.184) 5(1,-2.184) 6(1,2.184) 7(0.5,2.184) 8(0,2.184) 9(-0.5,2.184) 10(-1,2.184)
SOP14-26-173C
  rect 0.356x1.727 smd: 1(-1.95,-3.014) 2(-1.3,-3.014) 3(-0.65,-3.014) 4(0,-3.014) 5(0.65,-3.014) 6(1.3,-3.014) 7(1.95,-3.014) 8(1.95,3.014) 9(1.3,3.014) 10(0.65,3.014) 11(0,3.014) 12(-0.65,3.014) 13(-1.3,3.014) 14(-1.95,3.014)
SOP14-50-150
  rect 0.635x1.778 smd: 1(-3.81,-2.667) 2(-2.54,-2.667) 3(-1.27,-2.667) 4(0,-2.667) 5(1.27,-2.667) 6(2.54,-2.667) 7(3.81,-2.667) 8(3.81,2.667) 9(2.54,2.667) 10(1.27,2.667) 11(0,2.667) 12(-1.27,2.667) 13(-2.54,2.667) 14(-3.81,2.667)
SOP16-26-208-255
  rect 0.305x1.778 smd: 1(-2.275,-3.683) 2(-1.625,-3.683) 3(-0.975,-3.683) 4(-0.325,-3.683) 5(0.325,-3.683) 6(0.975,-3.683) 7(1.625,-3.683) 8(2.275,-3.683) 9(2.275,3.683) 10(1.625,3.683) 11(0.975,3.683) 12(0.325,3.683) 13(-0.325,3.683) 14(-0.975,3.683) 15(-1.625,3.683) 16(-2.275,3.683)
SOP24-26-173A
  rect 0.356x1.676 smd: 1(-3.575,-2.988) 2(-2.925,-2.988) 3(-2.275,-2.988) 4(-1.625,-2.988) 5(-0.975,-2.988) 6(-0.325,-2.988) 7(0.325,-2.988) 8(0.975,-2.988) 9(1.625,-2.988) 10(2.275,-2.988) 11(2.925,-2.988) 12(3.575,-2.988) 13(3.575,2.988) 14(2.925,2.988) 15(2.275,2.988) 16(1.625,2.988) 17(0.975,2.988) 18(0.325,2.988) 19(-0.325,2.988) 20(-0.975,2.988) 21(-1.625,2.988) 22(-2.275,2.988) 23(-2.925,2.988) 24(-3.575,2.988)
SOT23
  rect 1.016x1.27 smd: 1(-1.016,-1.143) 2(1.016,-1.143) 3(0,1.143)
SOT23-3
  rect 0.635x1.016 smd: 1(-0.955,-1.122) 2(0.955,-1.122) 3(0,1.122)
SOT23-5
  rect 0.508x1.016 smd: 1(-0.95,-1.3) 2(0,-1.3) 3(0.95,-1.3) 4(0.95,1.3) 5(-0.95,1.3)
SOT23-6A
  rect 0.61x1.143 smd: 1(-0.95,-1.225) 2(0,-1.225) 3(0.95,-1.225) 4(0.95,1.225) 5(0,1.225) 6(-0.95,1.225)
SOT23D
  rect 0.61x1.118 smd: 1(-0.95,-1.135) 2(0.95,-1.135) 3(0,1.135)
SOT523-3A
  rect 0.381x1.016 smd: 1(-0.5,-0.864) 2(0.5,-0.864)
  rect 0.508x1.016 smd: 3(0,0.864)
SOT666-6
  rect 0.254x0.406 smd: 1(-0.5,-0.749) 2(0,-0.749) 3(0.5,-0.749) 4(0.5,0.749) 5(0,0.749) 6(-0.5,0.749)
SOT-PPAK-8-0303G
  rect 0.406x1.016 smd: 1(-0.975,-1.522) 2(-0.325,-1.522) 3(0.325,-1.522) 4(0.975,-1.522) 5(0.975,1.522) 6(0.325,1.522) 7(-0.325,1.522)
  custom 0.656x0.656 smd: 8(0,0.655)
SPL0302E
  rect 1.27x2.235 smd: 1(-1.035,0) 2(1.035,0)
SPL0404L
  rect 1.448x3.81 smd: 1(-1.775,0) 2(1.775,0)
SPL0707N
  rect 2.489x3.404 smd: 1(-3.094,0) 2(3.094,0)
SR3-4926B
  rect 2.007x4.293 smd: 1(0,1.975) 2(-4.8,-1.975) 3(4.8,-1.975)
SR0402-TA
  rect 0.508x0.508 smd: 1(-0.406,0) 2(0.406,0)
SR0402-TB
  rect 0.508x0.508 smd: 1(-0.406,0) 2(0.406,0)
SR0603-TB
  rect 0.711x0.813 smd: 1(-0.737,0) 2(0.737,0)
SR0603B
  rect 0.711x0.94 smd: 1(-0.737,0) 2(0.737,0)
SR0805-TB
  rect 0.838x1.143 smd: 1(-0.927,0) 2(0.927,0)
SR2512-TE
  rect 1.524x3.175 smd: 1(-3.302,0) 2(3.302,0)
SR2512B-TF
  rect 2.845x3.175 smd: 1(-2.64,0) 2(2.64,0)
SRLY8-87-224
  rect 0.762x3.175 smd: 1(-3.81,-2.718) 2(-0.61,-2.718) 3(1.6,-2.718) 4(3.81,-2.718) 5(3.81,2.718) 6(1.6,2.718) 7(-0.61,2.718) 8(-3.81,2.718)
SSIM0107-50-1927
  round 1.016 hole 1.016 unplated: (-7,7.45) (7,7.45)
  rect 0.711x1.372 smd: 1(3.27,13.22) 2(0.73,13.22) 3(-1.81,13.22) 4(4.42,13.22) 5(2,13.22) 6(-0.54,13.22) 7(-3.08,13.22)
  rect 1.727x1.981 smd: 8(9.875,-8.3) 9(-9.875,-8.3)
STFM24-40-280
  rect 0.508x2.184 smd: 1(-5.5,-4.56) 2(-4.5,-4.56) 3(-3.5,-4.56) 4(-2.5,-4.56) 5(-1.5,-4.56) 6(-0.5,-4.56) 7(0.5,-4.56) 8(1.5,-4.56) 9(2.5,-4.56) 10(3.5,-4.56) 11(4.5,-4.56) 12(5.5,-4.56) 13(5.5,4.56) 14(4.5,4.56) 15(3.5,4.56) 16(2.5,4.56) 17(1.5,4.56) 18(0.5,4.56) 19(-0.5,4.56) 20(-1.5,4.56) 21(-2.5,4.56) 22(-3.5,4.56) 23(-4.5,4.56) 24(-5.5,4.56)
SX4-0303K
  rect 1.397x1.346 smd: 1(-1.298,-0.973) 2(1.298,-0.973) 3(1.298,0.973) 4(-1.298,0.973)
TB10-138S-A
  oval 2.413x1.702 hole 1.397: 1(0,0) 2(3.5,0) 3(7,0) 4(10.5,0) 5(14,0) 6(0,-2.5) 7(3.5,-2.5) 8(7,-2.5) 9(10.5,-2.5) 10(14,-2.5)
TB14-138S
  oval 1.676x2.489 hole 1.321: 1(0,0) 2(3.5,0) 3(7,0) 4(10.5,0) 5(14,0) 6(17.5,0) 7(21,0) 8(0,-2.5) 9(3.5,-2.5) 10(7,-2.5) 11(10.5,-2.5) 12(14,-2.5) 13(17.5,-2.5) 14(21,-2.5)
TP2-50-5MIL
  round 0.559 hole 0.254: 1(0,0) 2(1.27,0)
TP45_45-SMD
  rect 1.143x1.143 smd: 1(0,0)
TP50-SMD
  round 1.27 smd: 1(0,0)
TP50-SMD-OSP
  round 1.27 smd: 1(0,0)
unnamed#2
  round 0 smd: 1(-0.027,1.163)
VAF6-1406E
  round 1.346 hole 1.346 unplated: (5.5,-0.1)
  rect 1.524x2.159 smd: 1(-2.25,-4.029) 3(0.5,-4.029) 6(5.5,-4.029)
  rect 1.524x2.388 smd: 2(-2.25,3.944)
  rect 1.524x2.286 smd: 4(4.3,3.993)
  rect 1.524x3.048 smd: 5(6.5,3.574)
WSA1-1405
  round 3.505 hole 3.505 unplated: (0,0)

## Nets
3V3_PWR_EN: R2849.2 R3205.1 R3206.2
AGND_AUDIO: C2501.2 C2502.2 C2503.2 C2504.2 C2505.1 C2506.1 C2507.1 C2508.1 C2509.2 C2510.2 C2511.2 C2512.2 C2515.2 C2519.2 C2520.2 C2521.2 C2523.2 C2527.2 C2528.2 C2529.2 C2530.2 C2531.2 C2532.2 D2501.1 D2502.1 D2503.2 D2504.1 J3.302 J3.305 LB2504.2 LB2509.2 R2508.1 R2509.1 R2510.2 R2515.2 R2520.2 SG1.1 U4.4
AVDDH: C1405.1 C1406.1 C1407.1 C1415.1 C1416.1 C1417.1 C1418.1 C1419.1 C1420.1 C1421.1 C1433.1 LB1402.2 U6.1 U6.11 U6.17 U6.23 U6.33 U6.36 U6.88 U6.96 U6.106 U6.119
AVDDL: C1409.1 C1410.1 C1413.1 C1414.1 C1422.1 C1423.1 C1424.1 LB1403.2 U6.6 U6.14 U6.28 U6.34 U6.101 U6.111 U6.124
DVDD_PHY0_RG: C1220.2 R1238.1 U1201.29
DVDDIO: C1401.1 C1429.1 LB1406.2 R118.2 R1351.1 R1352.1 R1353.1 R1354.1 R1355.1 R1356.1 R1357.1 R1358.1 R1359.1 R1360.1 R1361.1 U6.18 U6.70
DVDDIO_1: C1403.1 C1427.1 LB1407.2 R184.1 R185.1 R204.1 R257.1 R258.1 R273.1 U6.55 U6.69
DVDDIO_2: C1402.1 C1428.1 LB1405.2 U6.39 U6.54
DVDDL: C1404.1 C1411.1 C1412.1 C1425.1 LB1404.1 U6.21 U6.53 U6.71
GND: C1.2 C2.2 C3.2 C4.2 C5.2 C6.2 C7.2 C8.2 C9.2 C10.2 C11.1 C12.2 C13.2 C14.2 C15.2 C16.2 C17.2 C18.2 C19.2 C20.2 C21.2 C22.2 C23.2 C24.2 C25.2 C26.2 C27.2 C28.2 C29.2 C30.2 C31.2 C32.2 C33.2 C34.2 C35.2 C36.2 C37.2 C39.1 C40.1 C41.1 C42.2 C43.1 C44.1 C45.2 C46.2 C47.2 C48.2 C49.2 C50.2 C51.2 C52.2 C53.2 C54.2 C55.2 C56.2 C57.2 C58.2 C59.2 C60.2 C61.2 C62.2 C63.2 C64.2 C65.2 C66.2 C67.2 C68.2 C69.2 C70.2 C71.2 C72.2 C73.2 C74.1 C75.1 C76.2 C77.2 C78.1 C79.2 C80.1 C81.2 C82.2 C84.2 C85.2 C86.2 C87.2 C88.2 C89.2 C90.2 C91.2 C92.2 C93.1 C97.1 C102.1 C103.1 C104.1 C105.2 C106.1 C107.1 C108.1 C111.2 C112.2 C113.2 C114.2 C115.2 C116.2 C117.2 C118.2 C119.2 C120.2 C121.2 C122.2 C125.2 C126.2 C129.1 C130.1 C131.2 C137.2 C138.2 C139.1 C142.2 C143.2 C144.2 C145.2 C146.2 C147.2 C148.2 C149.2 C150.2 C151.2 C152.2 C153.2 C154.2 C155.2 C156.2 C157.2 C158.2 C159.2 C160.2 C161.2 C163.1 C164.1 C165.1 C166.2 C167.1 C168.2 C170.2 C171.2 C172.2 C173.2 C174.2 C175.2 C176.2 C177.2 C178.2 C179.2 C180.2 C181.2 C182.2 C183.2 C184.2 C185.2 C186.2 C187.2 C188.2 C189.1 C190.1 C191.1 C192.1 C193.1 C301.1 C401.2 C402.2 C403.2 C404.2 C405.2 C406.2 C407.2 C408.2 C409.2 C410.2 C411.2 C412.2 C413.2 C414.2 C415.2 C416.2 C417.2 C418.2 C419.2 C420.2 C421.2 C422.2 C423.2 C424.2 C425.2 C426.2 C601.2 C603.2 C604.2 C605.2 C606.2 C607.2 C608.2 C609.2 C610.2 C619.2 C620.2 C621.2 C622.2 C701.2 C706.2 C707.2 C708.2 C709.2 C710.2 C711.2 C712.2 C713.2 C714.2 C715.2 C716.2 C717.2 C718.2 C719.2 C724.2 C725.2 C726.2 C727.2 C728.2 C731.2 C802.2 C814.2 C815.2 C816.2 C817.2 C818.2 C819.2 C820.2 C821.2 C822.2 C834.1 C835.1 C836.1 C837.1 C839.2 C902.2 C903.2 C904.2 C905.2 C906.2 C907.2 C908.2 C909.2 C910.2 C911.2 C1001.2 C1002.2 C1003.2 C1004.2 C1005.2 C1008.2 C1009.2 C1010.2 C1011.2 C1012.2 C1013.2 C1014.2 C1015.1 C1016.2 C1105.2 C1106.2 C1107.2 C1108.2 C1201.1 C1202.2 C1203.1 C1204.1 C1205.1 C1206.1 C1207.1 C1208.1 C1209.1 C1210.1 C1211.1 C1212.1 C1213.2 C1214.1 C1215.1 C1216.1 C1217.1 C1218.1 C1219.1 C1220.1 C1301.2 C1302.2 C1303.2 C1304.2 C1305.2 C1306.2 C1307.2 C1308.2 C1309.2 C1310.2 C1311.2 C1312.2 C1313.2 C1314.2 C1315.2 C1316.2 C1317.1 C1318.2 C1319.2 C1320.1 C1321.1 C1322.2 C1323.2 C1324.2 C1325.2 C1326.2 C1327.2 C1328.2 C1329.2 C1330.2 C1331.2 C1332.2 C1333.2 C1334.2 C1335.2 C1336.2 C1337.2 C1401.2 C1402.2 C1403.2 C1404.2 C1405.2 C1406.2 C1407.2 C1408.2 C1409.2 C1410.2 C1411.2 C1412.2 C1413.2 C1414.2 C1415.2 C1416.2 C1417.2 C1418.2 C1419.2 C1420.2 C1421.2 C1422.2 C1423.2 C1424.2 C1425.2 C1426.1 C1427.2 C1428.2 C1429.2 C1430.2 C1431.2 C1432.2 C1433.2 C1434.1 C1435.2 C1436.2 C1437.2 C1439.2 C1440.2 C1441.2 C1442.2 C1443.2 C1445.2 C1501.1 C1502.1 C1503.1 C1504.1 C1505.1 C1506.1 C1507.1 C1509.1 C1510.1 C1511.1 C1512.1 C1513.1 C1514.1 C1515.1 C1516.1 C1517.1 C1518.1 C1519.1 C1520.1 C1521.1 C1522.1 C1523.1 C1524.1 C1525.1 C1526.1 C1527.1 C1528.1 C1529.1 C1601.1 C1602.2 C1603.2 C1604.1 C1606.1 C1607.1 C1608.2 C1609.2 C1610.2 C1611.2 C1612.2 C1613.2 C1615.2 C1616.2 C1617.2 C1620.1 C1621.1 C1622.1 C1623.1 C1624.1 C1625.1 C1626.1 C1630.1 C1631.2 C1632.2 C1633.2 C1634.2 C1635.1 C1636.1 C1637.1 C1638.2 C1639.2 C1640.2 C1641.2 C1644.1 C1645.1 C1646.1 C1647.1 C1701.2 C1702.2 C1707.2 C1708.2 C1709.2 C1710.2 C1711.2 C1712.2 C1803.2 C1805.1 C1806.1 C1809.1 C1811.1 C1812.1 C1813.2 C1815.2 C1818.2 C1819.2 C1820.2 C1821.2 C1822.2 C1823.2 C1901.2 C1902.2 C1903.2 C1906.2 C1907.2 C1908.2 C1909.2 C2001.2 C2002.2 C2003.1 C2004.1 C2005.1 C2006.1 C2007.2 C2008.2 C2009.2 C2010.2 C2011.1 C2012.2 C2013.2 C2014.2 C2015.2 C2016.2 C2017.2 C2018.2 C2019.2 C2020.1 C2021.1 C2022.2 C2023.2 C2024.2 C2025.1 C2026.2 C2027.2 C2028.2 C2029.2 C2030.2 C2031.2 C2032.2 C2033.1 C2034.1 C2035.1 C2036.1 C2037.1 C2038.1 C2039.1 C2040.1 C2041.2 C2042.2 C2043.2 C2044.2 C2045.1 C2046.1 C2047.1 C2111.2 C2112.2 C2113.2 C2114.2 C2115.2 C2116.2 C2117.1 C2118.1 C2119.2 C2120.2 C2121.2 C2122.2 C2123.2 C2124.2 C2125.2 C2126.2 C2127.2 C2128.2 C2129.2 C2202.1 C2206.1 C2210.1 C2301.2 C2302.2 C2303.2 C2401.2 C2402.2 C2403.2 C2513.2 C2514.2 C2701.2 C2702.2 C2703.2 C2704.2 C2705.2 C2706.2 C2711.2 C2712.2 C2713.2 C2714.1 C2801.2 C2802.2 C2803.2 C2804.2 C2805.2 C2806.2 C2807.2 C2808.2 C2809.2 C2810.2 C2811.2 C2812.2 C2813.2 C2909.1 C2910.1 C2911.1 C2912.1 C2913.1 C2914.1 C2915.1 C2916.1 C2921.2 C3002.2 C3004.1 C3005.2 C3006.2 C3007.2 C3009.2 C3011.2 C3012.2 C3013.2 C3015.2 C3016.1 C3017.1 C3018.2 C3019.1 C3020.1 C3102.1 C3103.2 C3104.2 C3105.2 C3106.2 C3107.2 C3108.2 C3111.2 C3112.2 C3113.2 C3114.2 C3115.2 C3116.2 C3117.2 C3119.2 C3122.2 C3123.2 C3124.2 C3126.2 C3127.2 C3128.2 C3129.2 C3130.2 C3131.2 C3132.2 C3133.2 C3136.2 C3137.2 C3138.2 C3140.2 C3141.2 C3142.2 C3143.2 C3144.2 C3145.2 C3146.2 C3147.2 C3201.2 C3202.2 C3203.2 C3208.2 C3209.2 C3210.2 C3212.2 C3213.1 C3215.2 C3216.2 C3217.2 C3218.2 C3220.2 C3223.2 C3224.2 C3225.2 C3302.2 C3304.2 C3305.2 C3306.2 C3307.2 C3308.2 C3309.2 C3310.2 C3311.2 C3312.2 C3313.2 C3316.2 C3401.2 C3402.1 C3403.1 C3404.2 C3406.2 C3407.2 C3408.1 C3501.2 C3503.2 C3504.2 C3505.2 C3507.2 C3508.2 C3509.2 C3510.2 C3511.2 C3512.2 C3513.2 C3514.2 C3515.2 C3516.2 C3517.2 C3519.2 C3521.2 C3522.2 C3523.2 C3524.2 C3525.2 C3526.2 C3527.2 C3528.2 C3529.2 C3530.2 C3531.2 C3532.2 C3601.2 C3602.2 C3603.2 C3604.2 C3605.2 C3606.2 C3607.2 C3610.2 C3611.2 C3612.2 C3613.2 C3614.2 C3615.2 C3616.2 C3617.2 D2.2 D3.3 D4.2 D5.2 D7.3 D8.3 D9.3 D2201.3 D2201.8 D2202.3 D2202.8 D2203.3 D2203.8 D2303.3 D2303.8 D2305.3 D2305.8 D2403.3 D2403.8 D2405.3 D2405.8 D3301.3 D3302.3 D3402.2 D3601.2 D3602.2 F3001.1 J1.2 J2.3 J2.4 J2.7 J2.8 J2.11 J2.12 J3.1 J3.7 J3.12 J3.13 J3.19 J3.25 J3.30 J3.31 J3.36 J3.37 J3.42 J3.43 J3.48 J3.49 J3.54 J3.55 J3.60 J3.61 J3.66 J3.67 J3.72 J3.73 J3.78 J3.79 J3.84 J3.85 J3.90 J3.91 J3.96 J3.97 J3.102 J3.103 J3.108 J3.109 J3.140 J3.151 J3.154 J3.168 J3.171 J3.176 J3.183 J3.190 J3.195 J3.204 J3.210 J3.216 J3.222 J3.223 J3.228 J3.234 J3.240 J3.241 J3.246 J3.252 J3.253 J3.258 J3.264 J3.265 J3.266 J3.267 J3.268 J3.269 J3.270 J3.271 J3.285 J3.298 J3.308 J3.311 J3.322 J3.323 J8.1 J9.1 J601.1 J601.3 J601.9 J601.15 J601.21 J601.27 J601.33 J601.39 J601.45 J601.51 J601.57 J601.69 J601.71 J601.73 J601.75 J601.76 J601.77 J701.4 J701.9 J701.15 J701.18 J701.21 J701.26 J701.27 J701.29 J701.34 J701.35 J701.37 J701.40 J701.43 J701.50 J701.53 J701.54 J702.5 J702.8 J702.9 J803.3 J803.5 J803.11 J803.27 J803.33 J803.39 J803.45 J803.51 J803.57 J803.71 J803.73 J803.76 J803.77 J901.37 J901.38 J901.A3 J901.A6 J901.A9 J901.B3 J901.B6 J901.B9 J901.C3 J901.C6 J901.C9 J901.D3 J901.D6 J901.D9 J902.2 J902.4 J903.6 J1901.6 J1901.10 J1901.11 J1901.12 J1901.13 J1901.14 J2001.2 J2201.4 J2201.7 J2201.10 J2201.11 J2202.4 J2202.7 J2202.10 J2202.11 J2203.4 J2203.7 J2203.10 J2203.11 J2301.2 J2301.5 J2301.8 J2301.11 J2301.17 J2301.20 J2301.21 J2301.22 J2301.23 J2401.2 J2401.5 J2401.8 J2401.11 J2401.17 J2401.20 J2401.21 J2401.22 J2401.23 J2701.7 J2701.12 J2701.20 J2701.26 J2701.28 J2701.30 J2701.33 J2701.35 J2701.37 JP960.1 M1.1 M2.1 M3.1 M4.1 M5.1 M10.1 M11.1 M12.1 M15.1 M16.1 M17.1 M19.1 M20.1 M21.1 M22.1 M27.1 M28.1 Q2.2 Q701.2 Q702.2 Q801.2 Q1003.2 Q1004.2 Q1102.1 Q1102.2 Q1102.3 Q1104.1 Q1104.2 Q1104.3 Q1105.2 Q1106.2 Q1107.2 Q1701.2 Q1702.2 Q1703.2 Q1704.2 Q1803.2 Q1804.2 Q1902.2 Q2101.2 Q2901.2 Q3101.2 Q3103.2 Q3104.2 Q3105.2 Q3106.2 Q3201.2 Q3302.2 Q3304.2 Q3401.2 Q3402.2 Q3502.2 Q3503.2 Q3601.2 Q3602.2 Q3604.2 Q3605.2 Q3606.2 R10.2 R11.2 R12.2 R13.2 R20.1 R23.1 R51.1 R55.2 R61.2 R62.1 R63.1 R83.1 R84.1 R85.1 R107.1 R108.1 R110.1 R111.1 R121.1 R127.1 R128.1 R129.1 R130.2 R131.2 R132.2 R135.2 R137.1 R142.2 R143.1 R149.1 R150.1 R151.1 R152.1 R153.2 R154.2 R155.2 R156.2 R166.2 R177.1 R179.2 R187.2 R208.1 R221.1 R235.1 R236.1 R240.1 R242.1 R244.1 R246.1 R255.1 R263.2 R276.1 R279.2 R283.1 R289.1 R292.2 R296.2 R297.2 R306.2 R308.2 R310.2 R311.2 R312.2 R313.2 R315.2 R317.2 R319.2 R321.2 R323.2 R334.1 R343.2 R347.2 R348.2 R349.2 R350.1 R353.2 R354.1 R357.1 R358.1 R361.2 R363.2 R365.2 R388.1 R391.2 R713.2 R822.1 R1001.1 R1005.1 R1013.1 R1014.1 R1016.1 R1033.1 R1034.1 R1035.1 R1105.1 R1113.2 R1114.1 R1117.1 R1201.2 R1203.2 R1204.1 R1205.2 R1213.2 R1214.2 R1216.2 R1217.2 R1218.2 R1222.2 R1239.2 R1241.2 R1242.2 R1243.2 R1244.2 R1245.2 R1362.2 R1363.2 R1364.2 R1365.2 R1366.2 R1367.2 R1368.2 R1369.2 R1370.2 R1371.2 R1372.2 R1373.1 R1374.1 R1375.1 R1376.1 R1377.1 R1378.1 R1379.1 R1380.1 R1381.1 R1382.1 R1401.2 R1403.1 R1405.1 R1408.1 R1606.2 R1609.1 R1616.1 R1620.1 R1621.1 R1626.1 R1632.2 R1633.1 R1634.2 R1635.2 R1636.2 R1637.1 R1638.1 R1639.1 R1641.1 R1643.1 R1702.1 R1709.1 R1712.1 R1715.1 R1806.1 R1820.2 R1822.1 R1833.2 R1901.2 R1916.2 R1917.2 R2006.1 R2007.2 R2037.2 R2101.1 R2141.1 R2201.2 R2204.1 R2205.2 R2208.1 R2213.2 R2216.1 R2217.1 R2310.1 R2408.1 R2623.2 R2624.2 R2625.2 R2626.2 R2627.2 R2628.2 R2646.2 R2647.2 R2706.2 R2707.2 R2708.2 R2727.1 R2728.1 R2729.1 R2730.1 R2731.1 R2732.1 R2733.1 R2734.1 R2735.1 R2736.1 R2737.1 R2738.1 R2739.1 R2740.1 R2741.1 R2742.1 R2746.1 R2747.1 R2748.1 R2781.2 R2815.2 R2816.2 R2819.2 R2821.2 R2822.2 R2824.2 R2828.2 R2890.1 R2894.1 R2895.1 R2896.1 R2897.1 R2898.1 R2899.1 R2932.1 R2933.1 R2943.1 R2986.2 R3001.2 R3007.2 R3008.1 R3010.1 R3014.1 R3015.1 R3021.1 R3109.1 R3111.2 R3114.1 R3118.1 R3120.1 R3128.1 R3132.2 R3137.2 R3138.2 R3201.1 R3202.2 R3210.1 R3214.2 R3216.1 R3219.1 R3305.1 R3310.2 R3407.1 R3506.2 R3507.1 R3508.1 R3509.1 R3510.1 R3511.1 R3512.1 R3513.2 R3514.2 R3515.2 R3516.2 R3517.2 R3518.2 R3519.2 R3520.2 R3521.2 R3522.2 R3523.2 R3524.2 R3525.2 R3526.2 R3527.1 R3528.1 R3529.1 R3530.1 R3531.1 R3532.1 R3533.1 R3534.1 R3540.2 R3541.2 R3542.2 R3543.2 R3544.2 R3545.2 R3546.2 R3547.2 R3548.2 R3549.2 R3550.2 R3551.1 R3552.1 R3553.1 R3554.1 R3555.1 R3556.1 R3557.1 R3558.1 R3559.1 R3560.1 R3561.1 R3562.1 R3563.1 R3564.1 R3565.1 R3566.1 R3567.1 R3568.1 R3569.2 R3570.1 R3571.2 R3572.2 R3573.1 R3574.2 R3575.2 R3576.1 R3577.1 R3578.1 R3579.2 R3580.1 R3581.2 R3582.2 R3583.1 R3584.2 R3585.2 R3586.1 R3587.1 R3588.1 R3589.1 R3590.1 R3591.1 R3592.1 R3603.2 R3604.1 R3616.2 R3617.1 R3801.1 S3401.1 S3401.3 S3401.4 S3601.1 S3601.3 S3601.4 S3602.1 S3602.3 S3602.4 SG1.2 TP4.1 TP9.1 TP10.1 TP15.1 TP16.1 TP19.1 TP29.1 TP34.1 U1.31 U1.32 U1.33 U1.34 U1.37 U1.38 U2.3 U3.B14 U3.D14 U3.E5 U3.E11 U3.G7 U3.G8 U3.G9 U3.G11 U3.H7 U3.H9 U3.H11 U3.J7 U3.J8 U3.J9 U3.J11 U3.K4 U3.L5 U3.L6 U3.L7 U3.L8 U3.N5 U3.N6 U3.P4 U3.R7 U5.4 U6.12 U6.118 U6.129 U7.3 U8.3 U9.A6 U9.C4 U9.D4 U9.E7 U9.G5 U9.H10 U9.J5 U9.K8 U9.N1 U9.N2 U9.N5 U9.P4 U9.P6 U10.4 U11.31 U11.32 U11.33 U11.34 U11.37 U11.38 U12.3 U13.2 U14.2 U15.11 U15.12 U15.13 U15.25 U16.11 U16.12 U16.13 U16.25 U17.7 U301.65 U701.2 U1001.2 U1002.12 U1201.49 U1301.1 U1401.7 U1601.15 U1602.6 U1602.7 U1603.5 U1604.2 U1901.2 U1902.2 U2001.4 U2002.77 U2003.4 U2101.51 U2101.61 U2101.77 U2201.5 U2201.7 U2202.5 U2202.7 U2203.5 U2203.7 U2205.2 U2206.2 U2701.4 U2701.9 U2703.12 U2704.4 U2801.4 U2802.2 U2803.4 U2804.4 U2805.4 U2903.11 U2903.12 U2903.13 U2903.25 U2904.11 U2904.12 U2904.13 U2904.25 U3001.5 U3002.7 U3101.2 U3101.3 U3101.15 U3102.3 U3103.3 U3201.8 U3201.18 U3201.21 U3202.2 U3401.2 U3402.3 X1.2 X1.4 X2.2 X1201.2 X1201.4 X1301.2 X1301.4 X2001.2 X2001.4
V11_VDD_CORE: C1426.2 C1432.1 C1437.1 C1441.1 C1442.1 C1443.1 C1445.1 L1401.2 LB1401.1 LB1403.1 LB1404.2 R1402.2 R1403.2 U1401.2
VCC_5G_1V8: C835.2 C836.2 C837.2 LB802.2 R829.2 R830.2 R841.2 R851.2
VCC_CAN: C1638.1 LB8.2 LB9.2 U1604.3
VDD: C43.2 C44.2 C45.1 C74.2 C75.2 C125.1 C126.1 F3002.2 J3.272 J3.273 J3.274 J3.275 J3.276 J3.277 J3.278 J3.279 J3.280 J3.281 L3001.2
VDDO2: C142.1 C143.1 C144.1 LB3.2 U301.33
VDDO3: C145.1 C146.1 C147.1 LB4.2 U301.36
VDDO4: C148.1 C149.1 C150.1 LB5.2 U301.43
VDDO5: C151.1 C152.1 C153.1 LB6.2 U301.49
VDDOX: C156.1 C157.1 C158.1 LB7.2 U301.22 U301.29 U301.52 U301.57
4G_PWR_EN: R2851.1 R3134.1
5G_PWR_EN: R2852.1 R3123.1
1911_HBOOT_OK: J3.284 R147.1 R362.2 R363.1
1911_HBOOT_OK_R: R160.2 R356.2 R357.2 R2840.2
1911_OS_OK: J3.286 R145.1 R352.2 R353.1
1911_OS_OK_R: R159.2 R350.2 R351.2 R2837.2
8367_XTAL_IN: C1318.1 R1310.2 U6.90 X1301.1
8367_XTAL_OUT: R1326.1 U6.89
$17I27535\1V8_VDD_0: C412.1 C415.1 C416.1 C417.1 LB403.2 U301.32
$17I27535\1V8_VDD_1: C418.1 C419.1 C420.1 C421.1 LB405.2 U301.46
$17I27535\1V8_VDD_2: C422.1 C423.1 C424.1 C425.1 LB406.2 U301.60
$17I27535\3V3_IO: C408.1 C409.1 C414.1 LB401.1 LB402.2 R262.1 R305.1 R307.1 R309.1 R314.1 R316.1 R318.1 R320.1 R322.1 R324.1 R325.1 R326.1 R327.1 R328.1 R329.1 R332.1 R333.1
$17I27535\3V3_VDDIN: C401.1 C403.1 C404.1 C407.1 C413.1 LB404.2 U301.13
$17I27535\3V3_VDDS: C402.1 C405.1 C406.1 C410.1 C411.1 LB401.2 U301.40
$17I27535\$10N2449: R302.2 U301.17
$17I27535\$10N2450: R303.2 U301.18
$17I27535\$10N2469: R301.2 U301.8
$17I27535\$10N2470: R304.2 U301.16
$17I27535\CLK_OUT0B_0_N: U301.23
$17I27535\CLK_OUT0B_0_P: U301.24
$17I27535\CLK_OUT0T_7_N: U301.58
$17I27535\CLK_OUT0T_7_P: U301.59
$17I27535\CLK_OUT1_1_N: U301.30
$17I27535\CLK_OUT1_1_P: U301.31
$17I27535\CLK_OUT7_6_N: U301.53
$17I27535\CLK_OUT7_6_P: U301.54
$17I27535\CSB_A0_LC33: R315.1 R318.2 U301.19
$17I27535\FDEC_LC33: R307.2 R308.1 U301.42
$17I27535\FINC_DFT_LC33: R305.2 R306.1 U301.48
$17I27535\I2C1_SPI0_LC33: R316.2 R317.1 U301.39
$17I27535\LOL_A_LC33: R324.2 U301.3
$17I27535\LOL_B_LC33: R325.2 U301.4
$17I27535\LOL_C_LC33: R326.2 U301.5
$17I27535\LOL_D_LC33: R327.2 U301.47
$17I27535\OE0_LC33: R312.1 R332.2 U301.11
$17I27535\OE1_LC33: R313.1 R333.2 U301.41
$17I27535\PLL_SEL0_LC33: R310.1 U301.26
$17I27535\PLL_SEL1_LC33: R309.2 R311.1 U301.27
$17I27535\SDO_A1_LC33: R302.1 R314.2 R319.1
$51I54824\3V3_ADC: C32.1 C33.1 LB1.1 R18.2 U3.J5
$51I54824\$2N4737: C12.1 R14.1 X1.3
$51I54824\$2N4739: C11.2 R15.1 X1.1
$51I54824\$2N39663: R61.1 U3.H1 U3.H2 U3.H3 U3.H4 U3.J1 U3.J2 U3.J3 U3.J4
$51I54824\$2N40757: R20.2 U3.A1 U3.B1
$51I54824\$3N2669: R18.1 U3.E4
$51I54824\$3N2675: C35.1 U3.F11
$51I54824\$3N6111: C34.1 C36.1 U3.K5
$51I54824\BREAKER_STATE10: U3.P7
$51I54824\BREAKER_STATE11: U3.P2
$51I54824\BREAKER_STATE13: U3.P3
$51I54824\GPIO6: U3.R15
$51I54824\GPIO7: U3.P12
$51I54824\GPIO14: U3.N15
$51I54824\GPIO15: U3.M12
$51I54824\GPIO16: U3.B13
$51I54824\GPIO18: U3.D12
$51I54824\GPIO22: U3.A11
$51I54824\MCU_RST_N: C10.1 R2.1 U3.M5
$51I54824\RST_OUT_N/NC: U3.M6
$51I54824\SD5000_ISP/NC: R5.1 U3.M7
$51I54824\SD5000_RTCK/NC: R13.1 U3.M10
$51I54824\SD5000_SEL/NC: R11.1 U3.R9
$51I54824\SD5000_TCK/BOOT0: R10.1 R16.2 U3.M9
$51I54824\SD5000_TDI/NC: R9.1 U3.M8
$51I54824\SD5000_TDO/NC: U3.P9
$51I54824\SD5000_TMS/NC: R7.1 U3.N9
$51I54824\SD5000_TRST_N/NC: R12.1 U3.N8
$51I54824\SD5000_XTAL1: R15.2 R17.1 U3.R8
$51I54824\SD5000_XTAL2: R14.2 R17.2 U3.P8
$51I54824\TEST_MOD/NC: R8.1 U3.M11 U3.N10 U3.P10 U3.R10
$51I54824\WDT_EN/NC: R6.1 U3.N7
$61I15303\$4N4760: C53.1 R74.1
$61I15303\CS: U11.12
$61I15303\MODE: U11.13
$61I15303\REF: U11.14
$61I15303\SW: R74.2 U11.1 U11.2 U11.3 U11.4 U11.36 U11.39
$71I24443\$4N4760: C1.1 R19.1
$71I24443\CS: U1.12
$71I24443\MODE: U1.13
$71I24443\PG: U1.23
$71I24443\PG_POWER: U1.35
$71I24443\REF: U1.14
$71I24443\SW: R19.2 U1.1 U1.2 U1.3 U1.4 U1.36 U1.39
/ALARM_IN0: D1712.2 J1701.1 R1705.1
/ALARM_IN1: D1713.2 J1701.8 R1704.1
/ALARM_IN2: D1711.2 J1701.3 R1707.1
/ALARM_IN3: D1714.2 J1701.10 R1706.1
/ALM_IN0: J3.263 R79.2 U7.4
/ALM_IN1: J3.261 R78.2 U12.4
/ALM_IN2: J3.259 R80.2 U2.4
/ALM_IN3: J3.257 R81.2 U8.4
/CLKREQ_5G_LTE: J3.315 R832.2
/CLKREQ_M2: D3.2 J601.52 R130.1 R604.2
/EMMC_RESET: C1812.2 J3.203 R1809.1 R1810.2
/EN_TEC_BACKWARD: R1024.2 R1104.1 R1105.2 R1106.2
/FACTORYSET_MCU: C3616.1 R2833.2 R3620.2
/LED_4G: J701.42 R30.1
/LED_5G: J803.10 R831.1 R848.1
/LED_HEALTHY_G: Q3602.3 R3602.1
/LED_HEALTHY_R: Q3601.3 R3601.1
/LED_M2_R: D701.2 R611.2
/LED_PHY0_ACT: R1211.2 R1214.1 R1630.2 U1201.37
/LED_PHY0_LINK: R1205.1 R1212.2 R1629.2 U1201.35
/LED_PHY1_ACT: R1354.2 R1367.1 R1506.2 U6.81
/LED_PHY1_LINK: R1353.2 R1368.1 R1505.2 U6.82
/LED_PHY2_ACT: R1356.2 R1366.1 R1508.2 U6.78
/LED_PHY2_LINK: R1355.2 R1371.1 R1507.2 U6.79
/LED_PHY3_ACT: R1358.2 R1363.1 R1504.2 U6.76
/LED_PHY3_LINK: R1357.2 R1365.1 R1503.2 U6.77
/LED_PHY4_ACT: R1360.2 R1362.1 R1501.2 U6.72
/LED_PHY4_LINK: R1359.2 R1364.1 R1502.2 U6.73
/LED_POWER_G: Q3606.3 R3615.1
/LED_POWER_R: Q3605.3 R3614.1
/LED_SATA: Q3604.3 R3609.1
/OC0_USB30_REAR_1: R2032.1 R2140.1 U2002.25
/OC1_USB30_REAR_1: R2139.1 R2143.2 U2101.67
/OC_USB30_REAR_1: R2139.2 R2140.2 R2215.1 U2203.3
/OE0: R2943.2 R2983.2 U2904.22
/OE1: R2933.2 R2988.2 U2903.22
/OE2: R143.2 R198.2 U16.22
/OE3: R108.2 R199.2 U15.22
/PCH_IRQ_TPM_SPI: R218.2 R283.2 R284.2 R2782.2
/PERST_5G_LTE: J3.294 R852.2
/PERST_M2_R: C601.1 D3.1 R56.2 R606.2
/PEWAKE_5G_LTE: J3.314 R833.2
/PEWAKE_M2: J601.54 R89.2 R131.1
/PFO_ADM708: Q3401.3 R3403.2 U10.6
/PFO_Q_ADM708: R3408.1 R3413.1 R3414.2 U3402.5
/PG_24711_POWER: R3022.1 R3023.1 U3.H14
/PLL_INT: R266.1 R268.1
/PLL_LOS: R265.1 R270.1
/PLL_RST: R267.1 R269.1
/POWER_BTN_MCU: C3617.1 R2827.2 R3621.2
/RESET_1V8: R235.2 R3420.1 U3401.1
/RST_4G_LTE: J3.290 R713.1 R714.1
/RST_4G_LTE_R: C701.1 C710.1 J701.22 Q701.3 R701.1
/RST_5G_LTE_R: C93.2 J803.67 Q801.3
/RST_ADM6823: R3419.2 U10.5
/RST_BTN_MCU: C3408.2 R2831.2 R3423.1 R3425.2 U10.1
/RST_MCU_1911_R: R2848.2 R3424.1 U10.2
/RST_Q_ADM6823: C3407.1 R234.1 R236.2 R3426.2 U3401.3
/RST_SPIRST_TPM: C168.1 J2701.39 Q4.3 R169.2 R174.1 R2780.1 R2781.1
/RST_USB_HUB: J3.229 R116.1 R346.2 R349.1
/RST_USB_HUB_R: C131.1 R137.2 R138.2 R229.2 R2038.2 U2002.24
/RTL8367_RST: C138.1 R118.1 R121.2 R139.2 U6.91
/SYS_RST_IN: J3.297 R234.2 R3420.2
/TEC_TRIM1_ON: Q1002.1 R1014.2 R1025.2
/TEC_TRIM2_ON: Q1001.1 R1013.2 R1026.2
/TPM_RST: J3.225 R2760.1
/TPM_RST_R: Q4.2 R168.2 R174.2 R2760.2
/WAKE_PHY0: J3.231 R70.1 R293.2 R296.1
/WAKE_PHY0_R: R179.1 R237.2 R1215.1 R1221.2
AC_HPOUT_L: C2521.1 R2519.2 R2524.1
AC_HPOUT_R: C2520.1 R2516.2 R2525.1
AC_IN_L: C2502.1 C2504.1 D2502.2 J3.306 LB2503.2 R2502.1 R2509.2
AC_IN_R: C2501.1 C2503.1 D2501.2 J3.304 LB2502.2 R2507.1 R2508.2
AC_MICBIAS0: J3.300 R2503.1 R2504.1
AC_MICBIAS0_L: C2506.2 R2501.1 R2503.2
AC_MICBIAS0_R: C2507.2 R2504.2 R2506.1
AC_OUT_L: C2524.1 J3.309
AC_OUT_R: C2517.1 J3.307
ALARM_OUT0_REF0: D1707.2 J1701.4 K1701.3 K1701.6
ALARM_OUT0_REF1: D1708.2 J1701.5 K1701.4 K1701.5 R1703.2
ALARM_OUT1_REF0: D1705.2 J1701.12 K1702.3 K1702.6
ALARM_OUT1_REF1: D1706.2 J1701.11 K1702.4 K1702.5 R1710.2
ALARM_OUT2_REF0: D1709.2 J1701.6 K1704.3 K1704.6
ALARM_OUT2_REF1: D1710.2 J1701.7 K1704.4 K1704.5 R1716.2
ALARM_OUT3_REF0: D1703.2 J1701.14 K1703.3 K1703.6
ALARM_OUT3_REF1: D1704.2 J1701.13 K1703.4 K1703.5 R1713.2
ALM_OUT0: J3.251 R1701.1 R1702.2
ALM_OUT1: J3.249 R1708.1 R1709.2
ALM_OUT2: J3.247 R1714.1 R1715.2
ALM_OUT3: J3.245 R1711.1 R1712.2
BOARD_ID0: R2718.1 R2734.2 R2853.1 U2703.4
BOARD_ID1: R2717.1 R2733.2 R2854.1 U2703.5
BOARD_ID2: R2716.1 R2732.2 R2855.1 U2703.6
BOARD_ID3: R2715.1 R2731.2 R2856.1 U2703.7
BOARD_ID4: R2714.1 R2730.2 R2857.1 U2703.8
BOARD_ID5: R2713.1 R2729.2 R2858.1 U2703.9
BOARD_ID6: R2712.1 R2728.2 R2859.1 U2703.10
BOARD_ID7: R2711.1 R2727.2 R2860.1 U2703.11
BOM_ID0: R2719.1 R2735.2 R2864.1 U2703.13
BOM_ID1: R2720.1 R2736.2 R2865.1 U2703.14
BOM_ID2: R2721.1 R2737.2 R2866.1 U2703.15
BOOT_SEL0: J3.137 R146.1
BOOT_SEL0_R: R85.2 R205.2 R259.1
BOOT_SEL1: J3.135 R148.1
BOOT_SEL1_R: R84.2 R158.2 R260.1
BOOT_SEL2: J3.133 R68.1
BOOT_SEL2_R: R67.2 R177.2 R261.1
BPWR_DET_USB2: R229.1 R2102.2 U2101.2
BPWR_VL817_HUB1: R2009.1 U2002.45
CAN0_RX: J3.145 R2931.1 R2999.2
CAN0_RX_R: R1640.2 R1647.2 U2904.6
CAN0_TX: J3.143 R44.2 R2934.1
CAN0_TX_R: R1648.2 R2938.2 U1604.1
CAN_H: C1640.1 R31.1 R188.2 R1649.1 T1602.1 U1604.7
CAN_H_R: C1643.1 D1722.2 J1702.7 R31.2 T1602.2
CAN_L: C1641.1 R87.1 R188.1 R1650.1 T1602.4(TP-4) U1604.6
CAN_L_R: C1642.1 D1719.2 J1702.6 R87.2 T1602.3
CARD_DETECT: J1901.9 R1912.2 U1902.6(TP-6)
CFG_PHY0_LDO0: R1210.2 R1213.1 U1201.36
CH1_MDI0_N: J1502.2 T1502.14
CH1_MDI0_P: J1502.1 T1502.13
CH1_MDI1_N: J1502.6 T1502.17
CH1_MDI1_P: J1502.3 T1502.16
CH1_MDI2_N: J1502.5 T1502.20
CH1_MDI2_P: J1502.4 T1502.19
CH1_MDI3_N: J1502.8 T1502.23
CH1_MDI3_P: J1502.7 T1502.22
CH1_TRX0N_N: R197.1 U6.108
CH1_TRX0P_P: R1315.1 U6.107
CH1_TRX1N_N: R1316.1 U6.110
CH1_TRX1P_P: R1314.1 U6.109
CH1_TRX2N_N: R1313.1 U6.113
CH1_TRX2P_P: R1312.1 U6.112
CH1_TRX3N_N: R1311.1 U6.115
CH1_TRX3P_P: R1309.1 U6.114
CH2_MDI0_N: J1502.10 T1503.14
CH2_MDI0_P: J1502.9 T1503.13
CH2_MDI1_N: J1502.14 T1503.17
CH2_MDI1_P: J1502.11 T1503.16
CH2_MDI2_N: J1502.13 T1503.20
CH2_MDI2_P: J1502.12 T1503.19
CH2_MDI3_N: J1502.16 T1503.23
CH2_MDI3_P: J1502.15 T1503.22
CH2_TRX0N_N: R1308.1 U6.121
CH2_TRX0P_P: R1307.1 U6.120
CH2_TRX1N_N: R1306.1 U6.123
CH2_TRX1P_P: R1305.1 U6.122
CH2_TRX2N_N: R1304.1 U6.126
CH2_TRX2P_P: R1303.1 U6.125
CH2_TRX3N_N: R1302.1 U6.128
CH2_TRX3P_P: R1301.1 U6.127
CH3_MDI0_N: J1501.2 T1504.14
CH3_MDI0_P: J1501.1 T1504.13
CH3_MDI1_N: J1501.6 T1504.17
CH3_MDI1_P: J1501.3 T1504.16
CH3_MDI2_N: J1501.5 T1504.20
CH3_MDI2_P: J1501.4 T1504.19
CH3_MDI3_N: J1501.8 T1504.23
CH3_MDI3_P: J1501.7 T1504.22
CH3_TRX0N_N: R1335.1 U6.3
CH3_TRX0P_P: R1336.1 U6.2
CH3_TRX1N_N: R1337.1 U6.5
CH3_TRX1P_P: R1338.1 U6.4
CH3_TRX2N_N: R1339.1 U6.8
CH3_TRX2P_P: R1340.1 U6.7
CH3_TRX3N_N: R1341.1 U6.10
CH3_TRX3P_P: R1342.1 U6.9
CH4_MDI0_N: J1501.10 T1501.14
CH4_MDI0_P: J1501.9 T1501.13
CH4_MDI1_N: J1501.14 T1501.17
CH4_MDI1_P: J1501.11 T1501.16
CH4_MDI2_N: J1501.13 T1501.20
CH4_MDI2_P: J1501.12 T1501.19
CH4_MDI3_N: J1501.16 T1501.23
CH4_MDI3_P: J1501.15 T1501.22
CH4_TRX0N_N: R1343.1 U6.25
CH4_TRX0P_P: R1344.1 U6.24
CH4_TRX1N_N: R1345.1 U6.27
CH4_TRX1P_P: R1346.1 U6.26
CH4_TRX2N_N: R1347.1 U6.30
CH4_TRX2P_P: R1348.1 U6.29
CH4_TRX3N_N: R1349.1 U6.32
CH4_TRX3P_P: R1350.1 U6.31
CLK_100M_5G_L2_N: C2633.1 R2643.2 R2647.1
CLK_100M_5G_L2_P: C2634.1 R2642.2 R2646.1
CLK_100M_BUF_5G_L1_N: R2643.1 U301.50
CLK_100M_BUF_5G_L1_P: R2642.1 U301.51
CLK_100M_BUF_5G_N: C2633.2 J803.53 R805.2
CLK_100M_BUF_5G_P: C2634.2 J803.55 R805.1
CLK_100M_BUF_M2_L1_N: R2617.1 U301.37
CLK_100M_BUF_M2_L1_P: R2618.1 U301.38
CLK_100M_BUF_M2_N: C2624.2 J601.53 R612.1
CLK_100M_BUF_M2_P: C2623.2 J601.55 R612.2
CLK_100M_BUF_PCIE_L1_N: R2615.1 U301.34
CLK_100M_BUF_PCIE_L1_P: R2616.1 U301.35
CLK_100M_BUF_WIFI_L1_N: R2614.1 U301.44
CLK_100M_BUF_WIFI_L1_P: R2613.1 U301.45
CLK_100M_BUF_WIFI_N: C2619.2 J701.11 R100.2
CLK_100M_BUF_WIFI_P: C2620.2 J701.13 R100.1
CLK_100M_M2_L2_N: C2624.1 R2617.2 R2625.1
CLK_100M_M2_L2_P: C2623.1 R2618.2 R2626.1
CLK_100M_PCIE_L2_N: C2622.1 R2615.2 R2627.1
CLK_100M_PCIE_L2_P: C2621.1 R2616.2 R2628.1
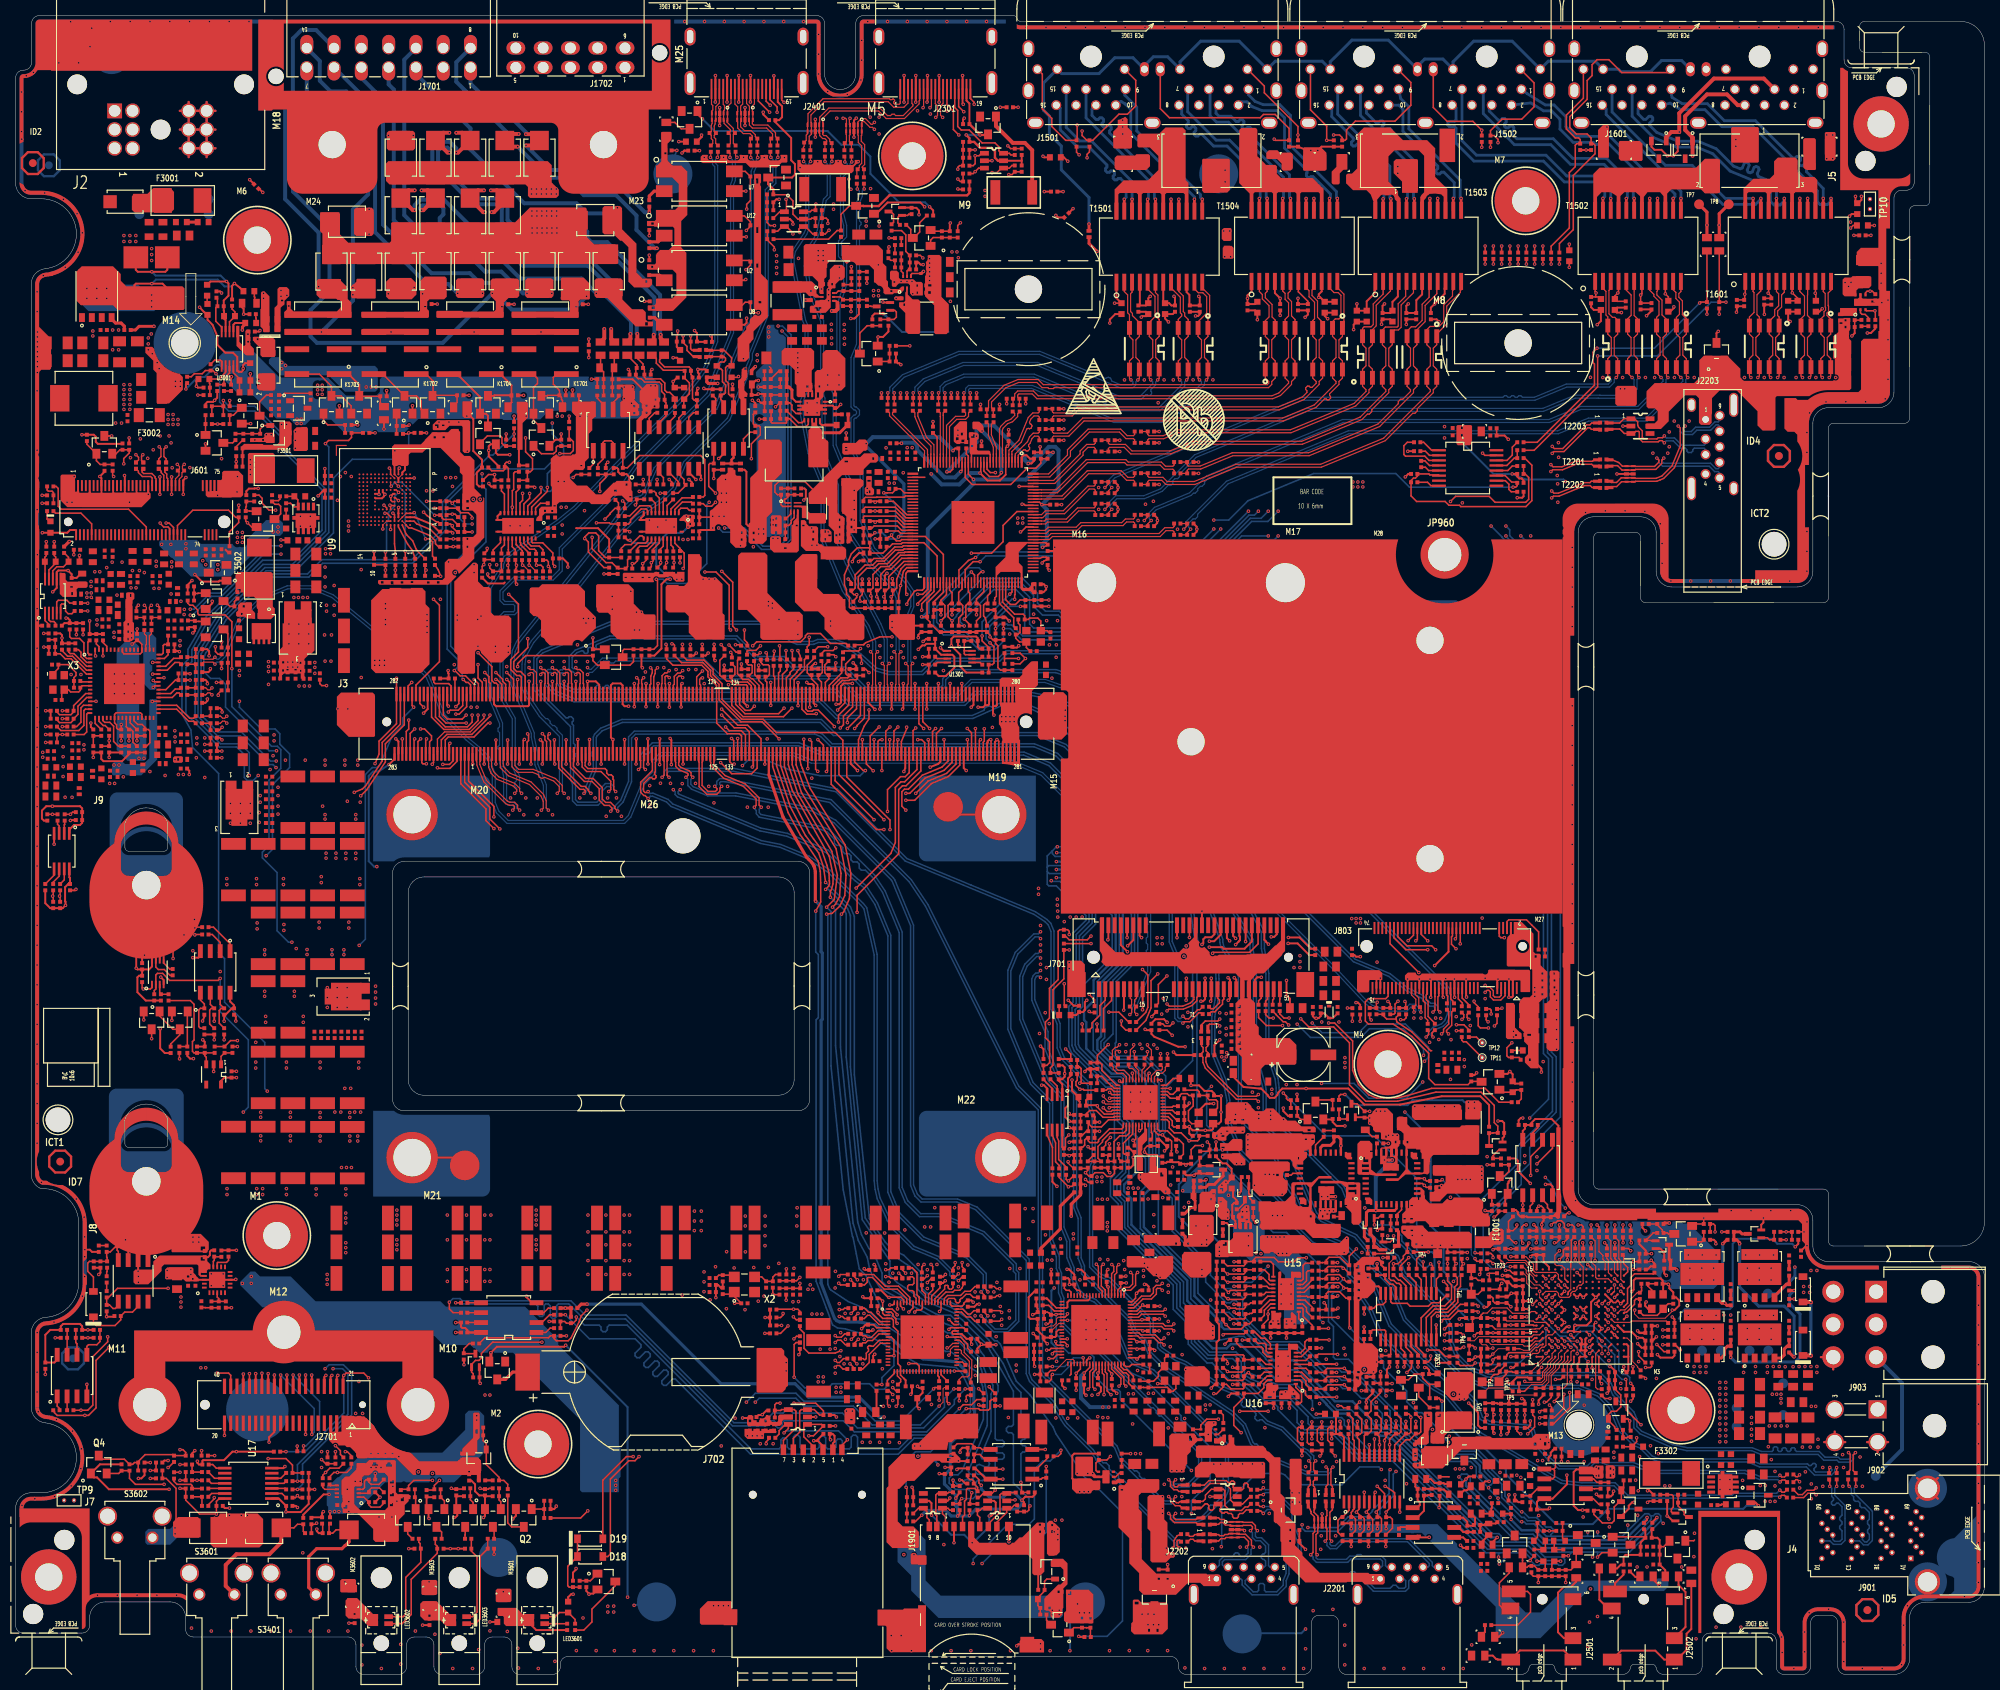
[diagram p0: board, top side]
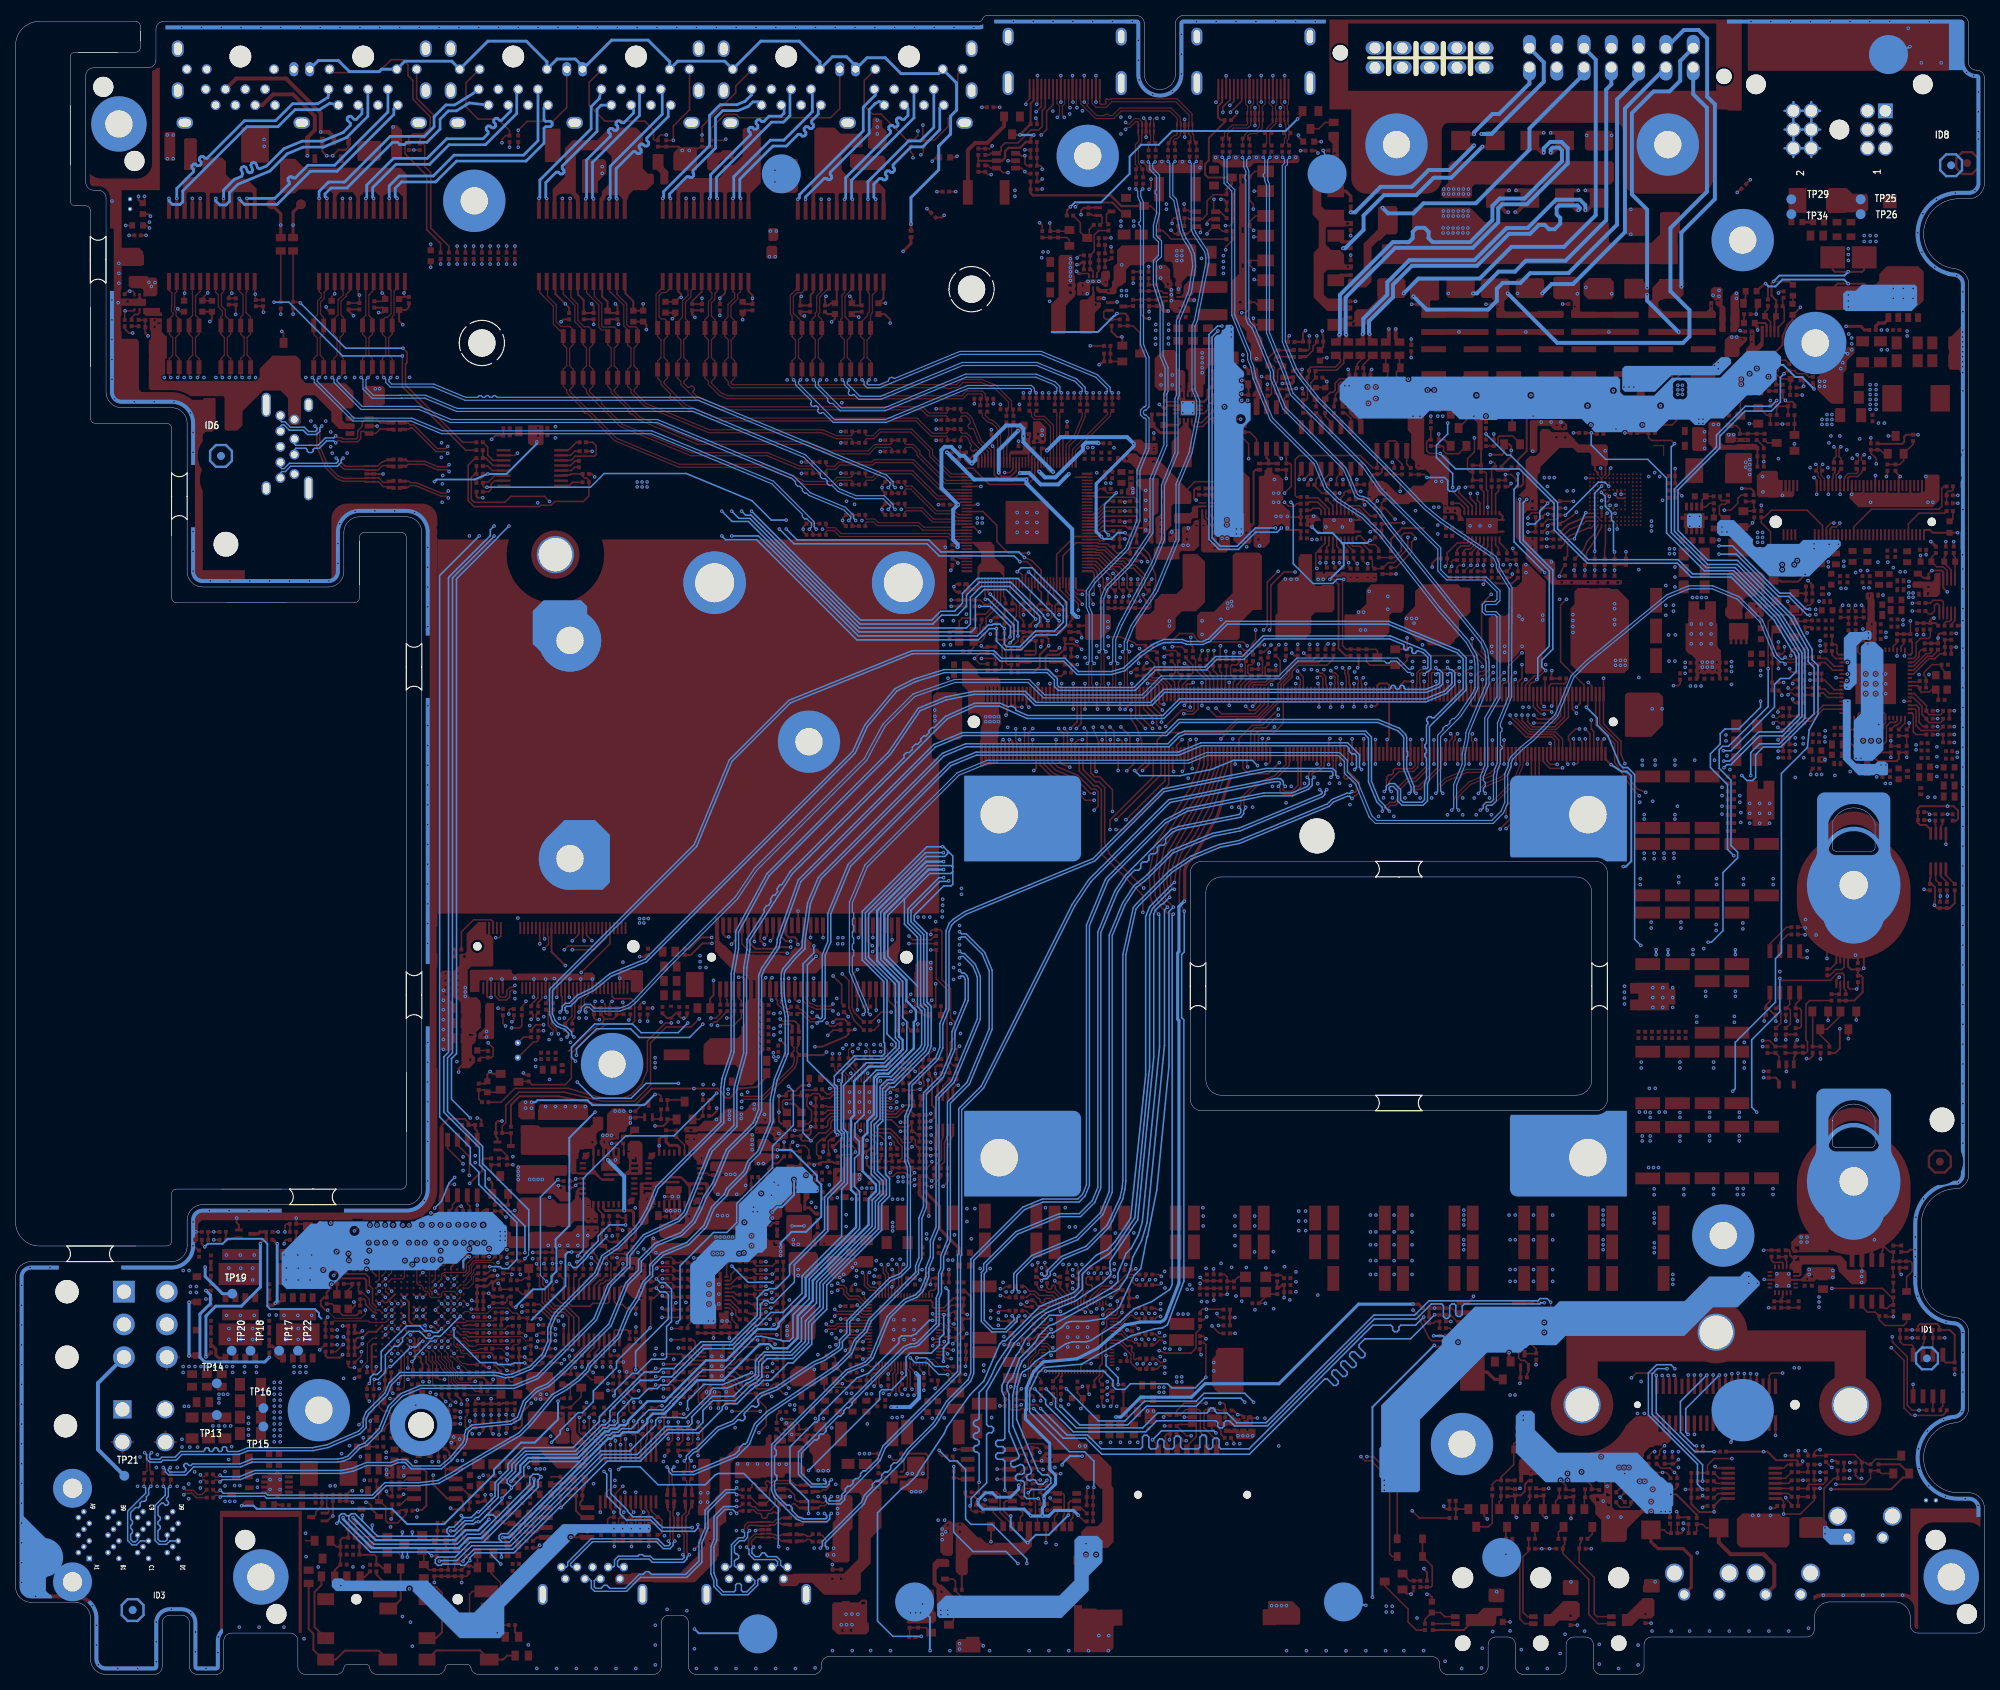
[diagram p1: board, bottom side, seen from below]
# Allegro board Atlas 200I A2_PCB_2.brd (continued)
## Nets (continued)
CLK_100M_WIFI_L2_N: C2619.1 R2614.2 R2623.1
CLK_100M_WIFI_L2_P: C2620.1 R2613.2 R2624.1
COUPON1: TP9.2
COUPON2: TP10.2
DEVSLP_M2: R55.1 R57.2 R602.1
EMMC_CLK: J3.199 R1808.1 R1833.1
EMMC_CMD: J3.201 R114.1 R1811.2
EMMC_DATA0: J3.207 R1816.2 R1825.1
EMMC_DATA0_R: R1825.2 U9.A3
EMMC_DATA1: J3.209 R1817.2 R1826.1
EMMC_DATA1_R: R1826.2 U9.A4
EMMC_DATA2: J3.211 R1818.2 R1827.1
EMMC_DATA2_R: R1827.2 U9.A5
EMMC_DATA3: J3.213 R1819.2 R1828.1
EMMC_DATA3_R: R1828.2 U9.B1 U9.B2
EMMC_DATA4: J3.215 R1815.2 R1829.1
EMMC_DATA4_R: R1829.2 U9.A2 U9.B3
EMMC_DATA5: J3.217 R1814.2 R1830.1
EMMC_DATA5_R: R1830.2 U9.B4 U9.C3 U9.D1 U9.D2
EMMC_DATA6: J3.219 R1813.2 R1831.1
EMMC_DATA6_R: R1831.2 U9.B5 U9.C5
EMMC_DATA7: J3.221 R1812.2 R1832.1
EMMC_DATA7_R: R1832.2 U9.A8 U9.B6 U9.B7
EMMC_DS: J3.205 R1807.1 R1820.1
EMMC_POWER_EN: J3.197 R1805.1 R1806.2 R1821.1 R1822.2
EN_MCU_HOT1: R2813.1 R3505.1
EN_MCU_HOT2: R2812.1 R3539.1
EN_TEC_FORWARD: R1022.2 R1117.2 R1119.1
EN_TEC_PWR: R1015.1 R1016.2 R1023.2
EN_TEC_PWR_R: C1011.1 Q1004.3 R1001.2 U11.22
FACTORYSET_1911: J3.288 R274.1 R278.2 R279.1
FACTORYSET_1911_R: R275.2 R276.2 R277.2 R2839.2
GATE_24711: C3003.1 R3009.1 U3001.7
GE_RV1: R1509.1 RV1501.3 T1501.15 T1501.18 T1501.21 T1501.24
GE_RV2: R1510.1 RV1501.2 T1504.15 T1504.18 T1504.21 T1504.24
GE_RV3: R1511.1 RV1502.3 T1503.15 T1503.18 T1503.21 T1503.24
GE_RV4: R1512.1 RV1601.2 T1502.15 T1502.18 T1502.21 T1502.24
GE_RV5: R1631.1 RV1601.3 T1601.15 T1601.18 T1601.21 T1601.24
HDMI0_CEC: J3.239 R2301.2 R2302.1
HDMI0_HOTPLUG: C2302.1 J3.237 R2308.1 R2309.2 R2310.2
HDMI0_SCL: J3.230 R2305.1 R2317.2
HDMI0_SDA: J3.232 R2306.1 R2307.2
HDMI0_TX0_C_N: D2305.4 D2305.7 J2301.9 R144.2 R212.2
HDMI0_TX0_C_P: D2305.5 D2305.6 J2301.7 R136.2 R212.1
HDMI0_TX0_N: J3.220 R144.1
HDMI0_TX0_P: J3.218 R136.1
HDMI0_TX1_C_N: D2303.1 D2303.10 J2301.6 R211.2 R300.2
HDMI0_TX1_C_P: D2303.2 D2303.9 J2301.4 R211.1 R299.2
HDMI0_TX1_N: J3.214 R300.1
HDMI0_TX1_P: J3.212 R299.1
HDMI0_TX2_C_N: D2303.4 D2303.7 J2301.3 R210.2 R331.2
HDMI0_TX2_C_P: D2303.5 D2303.6 J2301.1 R210.1 R330.2
HDMI0_TX2_N: J3.208 R331.1
HDMI0_TX2_P: J3.206 R330.1
HDMI0_TX_5V: C2301.1 D2307.3 J2301.18 R2307.1 R2308.2 R2317.1 U13.5
HDMI0_TX_CEC: J2301.13 R2302.2 U13.3
HDMI0_TX_DDC_SCL_C: J2301.15 R2305.2 U13.6(TP-6)
HDMI0_TX_DDC_SDA_C: J2301.16 R2306.2 U13.4
HDMI0_TX_HPD_C: J2301.19 R2309.1 U13.1
HDMI0_TXC_C_N: D2305.1 D2305.10 J2301.12 R213.2 R393.2
HDMI0_TXC_C_P: D2305.2 D2305.9 J2301.10 R213.1 R392.2
HDMI0_TXC_N: J3.226 R393.1
HDMI0_TXC_P: J3.224 R392.1
HDMI1_CEC: J3.235 R2401.2 R2402.1
HDMI1_HOTPLUG: C2402.1 J3.233 R2406.1 R2407.2 R2408.2
HDMI1_SCL: J3.27 R2403.1 R2417.2
HDMI1_SDA: J3.29 R2404.1 R2405.2
HDMI1_TX0_C_N: D2405.4 D2405.7 J2401.9 R215.2 R395.2
HDMI1_TX0_C_P: D2405.5 D2405.6 J2401.7 R215.1 R394.2
HDMI1_TX0_N: J3.17 R395.1
HDMI1_TX0_P: J3.15 R394.1
HDMI1_TX1_C_N: D2403.1 D2403.10 J2401.6 R214.2 R397.2
HDMI1_TX1_C_P: D2403.2 D2403.9 J2401.4 R214.1 R396.2
HDMI1_TX1_N: J3.11 R397.1
HDMI1_TX1_P: J3.9 R396.1
HDMI1_TX2_C_N: D2403.4 D2403.7 J2401.3 R217.2 R399.2
HDMI1_TX2_C_P: D2403.5 D2403.6 J2401.1 R217.1 R398.2
HDMI1_TX2_N: J3.5 R399.1
HDMI1_TX2_P: J3.3 R398.1
HDMI1_TX_3V3: C2303.1 C2403.1 D2408.3 R2301.1 R2401.1
HDMI1_TX_5V: C2401.1 D2407.3 J2401.18 R2405.1 R2406.2 R2417.1 U14.5
HDMI1_TX_CEC: J2401.13 R2402.2 U14.3
HDMI1_TX_DDC_SCL_C: J2401.15 R2403.2 U14.6(TP-6)
HDMI1_TX_DDC_SDA_C: J2401.16 R2404.2 U14.4
HDMI1_TX_HPD_C: J2401.19 R2407.1 U14.1
HDMI1_TXC_C_N: D2405.1 D2405.10 J2401.12 R216.2 R401.2
HDMI1_TXC_C_P: D2405.2 D2405.9 J2401.10 R216.1 R400.2
HDMI1_TXC_N: J3.23 R401.1
HDMI1_TXC_P: J3.21 R400.1
HEALTHY_LED_MCU_G: R2836.2 R3603.1 R3606.1
HEALTHY_LED_MCU_R: R2834.2 R3604.2 R3605.1
HOT_RST_FAULT: J3.295 R157.1 R360.2 R361.1
HOT_RST_FAULT_R: R161.2 R354.2 R355.2 R2838.2
HUB_1V2_LX: L2001.1 U2002.39
HUB_1V2_SWR: L2101.1 U2101.52
HUB_3V3_LX: LB2002.1 R2033.1 U2002.21
HUB_PWR_EN: R127.2 R2850.1 R3102.2 R3103.1
I2C0_MCU_SCL: R28.2 R2869.2 R3017.1
I2C0_MCU_SDA: R27.2 R2870.2 R3016.1
I2C3_MCU_SCL: R37.1 R2874.1 R2882.1 R2883.1 R2885.1
I2C3_MCU_SDA: R38.1 R2873.1 R2881.1 R2884.1 R2886.1
I2C4_MCU_SCL: R35.2 R120.1 R1029.2
I2C4_MCU_SDA: R36.2 R123.1 R1028.2
I2C6_SCL: J3.6 R98.1 R2871.2
I2C6_SDA: J3.4 R99.1 R2868.2
I2C7_MCU_SCL: R271.1 R304.1 R320.2 R321.1
I2C7_MCU_SDA: R272.1 R303.1 R322.2 R323.1
I2C7_SCL: J3.2 R53.2 R2026.1 R2754.2
I2C7_SCL_HUB0: R2024.1 U2002.36
I2C7_SCL_HUB1: R2022.1 U2101.34
I2C7_SCL_R: R2022.2 R2024.2 R2029.2 R2030.1
I2C7_SDA: J3.320 R52.2 R2027.1 R2755.2
I2C7_SDA_HUB0: R2023.1 U2002.37
I2C7_SDA_HUB1: R2021.1 U2101.35
I2C7_SDA_R: R2021.2 R2023.2 R2028.2 R2031.1
I2C8_SCL: J3.318 R92.2 R2750.1
I2C8_SCL_R: R90.1 R95.2 R2702.2 R2710.2 R2753.2
I2C8_SDA: J3.316 R93.2 R2751.1
I2C8_SDA_R: R91.1 R94.2 R2701.2 R2709.2 R2752.2
I2CS_SCL: J3.10 R96.1 R2867.2
I2CS_SDA: J3.8 R97.1 R2872.2
INT_1911_MCU: J3.255 R69.1 R364.2 R365.1
INT_1911_MCU_R: R65.1 R164.2 R358.2 R359.2
INT_MCU_1911: J3.243 R71.1 R294.2 R297.1
INT_MCU_1911_R: R66.1 R220.2 R286.2 R289.2
LM75_INLET0_A0: R2891.1 R2894.2 U2804.7
LM75_INLET0_A1: R2893.1 R2896.2 U2804.6
LM75_INLET0_A2: R2892.1 R2895.2 U2804.5
LM75_INLET1_A0: R23.2 R24.1 U2803.7
LM75_INLET1_A1: R21.1 R2899.2 U2803.6
LM75_INLET1_A2: R22.1 R62.2 U2803.5
LM75_INLET2_A0: R2887.1 R2890.2 U2805.7
LM75_INLET2_A1: R2889.1 R2898.2 U2805.6
LM75_INLET2_A2: R2888.1 R2897.2 U2805.5
M2_LED: J601.10 R611.1
MAC_GND: C139.2 C1508.2 C1530.2 C1531.2 C1532.2 C1533.2 C1534.2 C1535.2 C1536.2 C1537.2 C1538.2 C1539.2 C1540.2 C1627.2 C1628.2 C1629.2 C1630.2 C1635.2 C1636.2 C1637.2 D16.2 D17.2 J1501.25 J1501.26 J1501.27 J1501.28 J1501.29 J1501.30 J1501.31 J1502.25 J1502.26 J1502.27 J1502.28 J1502.29 J1502.30 J1502.31 J1601.4 J1601.5 J1601.25 J1601.26 J1601.27 J1601.28 J1601.29 J1601.30 J1601.31 M7.1 R1632.1 R1634.1 R1635.1 R1636.1 RV1501.1 RV1502.1 RV1601.1
MCU1_SWCLK: R25.2 R2802.2 U3.C7
MCU1_SWDIO: R26.2 R2801.2 U3.D7
MCU2_SWCLK: R4.1 R2807.2 U3.C1
MCU2_SWDIO: R3.1 R2808.2 U3.C2
MCU_BOOT0: R2828.1 R2829.1 TP6.1 U3.A8
MCU_EN_VCC_DISK: R1027.2 R3303.1 R3310.1
MCU_VREF: C2802.1 C2803.1 C2810.1 R2811.1 U3.F4 U3.K3 U2802.1
MDCK_V33: R1330.2 R1331.1 U6.93
MDI_CH1_0_N: C1316.1 D1501.2 D1501.7 R197.2 T1502.11
MDI_CH1_0_P: C1310.1 D1501.1 D1501.8(TP-8) R1315.2 T1502.12
MDI_CH1_1_N: C1311.1 D1501.4 D1501.5 R1316.2 T1502.8
MDI_CH1_1_P: C1312.1 D1501.3 D1501.6 R1314.2 T1502.9
MDI_CH1_2_N: C1313.1 D13.3 D13.6 R1313.2 T1502.5
MDI_CH1_2_P: C1314.1 D13.4 D13.5 R1312.2 T1502.6
MDI_CH1_3_N: C1315.1 D13.1 D13.8(TP-8) R1311.2 T1502.2
MDI_CH1_3_P: C1309.1 D13.2 D13.7 R1309.2 T1502.3
MDI_CH2_0_N: C1308.1 D1502.2 D1502.7 R1308.2 T1503.11
MDI_CH2_0_P: C1301.1 D1502.1 D1502.8(TP-8) R1307.2 T1503.12
MDI_CH2_1_N: C1302.1 D1502.4 D1502.5 R1306.2 T1503.8
MDI_CH2_1_P: C1303.1 D1502.3 D1502.6 R1305.2 T1503.9
MDI_CH2_2_N: C1304.1 D12.3 D12.6 R1304.2 T1503.5
MDI_CH2_2_P: C1305.1 D12.4 D12.5 R1303.2 T1503.6
MDI_CH2_3_N: C1306.1 D12.1 D12.8(TP-8) R1302.2 T1503.2
MDI_CH2_3_P: C1307.1 D12.2 D12.7 R1301.2 T1503.3
MDI_CH3_0_N: C1322.1 D1503.2 D1503.7 R1335.2 T1504.11
MDI_CH3_0_P: C1329.1 D1503.1 D1503.8(TP-8) R1336.2 T1504.12
MDI_CH3_1_N: C1328.1 D1503.4 D1503.5 R1337.2 T1504.8
MDI_CH3_1_P: C1327.1 D1503.3 D1503.6 R1338.2 T1504.9
MDI_CH3_2_N: C1326.1 D11.3 D11.6 R1339.2 T1504.5
MDI_CH3_2_P: C1325.1 D11.4 D11.5 R1340.2 T1504.6
MDI_CH3_3_N: C1324.1 D11.1 D11.8(TP-8) R1341.2 T1504.2
MDI_CH3_3_P: C1323.1 D11.2 D11.7 R1342.2 T1504.3
MDI_CH4_0_N: C1330.1 D1504.2 D1504.7 R1343.2 T1501.11
MDI_CH4_0_P: C1337.1 D1504.1 D1504.8(TP-8) R1344.2 T1501.12
MDI_CH4_1_N: C1336.1 D1504.4 D1504.5 R1345.2 T1501.8
MDI_CH4_1_P: C1335.1 D1504.3 D1504.6 R1346.2 T1501.9
MDI_CH4_2_N: C1334.1 D10.2 D10.7 R1347.2 T1501.5
MDI_CH4_2_P: C1333.1 D10.1 D10.8(TP-8) R1348.2 T1501.6
MDI_CH4_3_N: C1332.1 D10.4 D10.5 R1349.2 T1501.2
MDI_CH4_3_P: C1331.1 D10.3 D10.6 R1350.2 T1501.3
MDI_PHY0_0_N: D1601.1 D1601.8(TP-8) R196.2 T1601.12
MDI_PHY0_0_P: D1601.2 D1601.7 R195.2 T1601.11
MDI_PHY0_1_N: D1601.3 D1601.6 R1317.2 T1601.9
MDI_PHY0_1_P: D1601.4 D1601.5 R190.2 T1601.8
MDI_PHY0_2_N: D14.1 D14.8(TP-8) R191.2 T1601.6
MDI_PHY0_2_P: D14.2 D14.7 R192.2 T1601.5
MDI_PHY0_3_N: D14.3 D14.6 R193.2 T1601.3
MDI_PHY0_3_P: D14.4 D14.5 R194.2 T1601.2
MDIO_V33: R1332.1 R1333.2 U6.94
MUSIM1_CLK: J803.32 R801.1
MUSIM1_DATA: J803.34 R803.1
MUSIM1_RST: J803.30 R802.1
ONLINE_TPM: J2701.21 R200.1 R202.2
P0LED0: R1351.2 R1370.1 U6.86
P0LED2: R1352.2 R1369.1 U6.84
PCA9555A_A0: R2743.1 R2748.2 U2703.21
PCA9555A_A1: R2744.1 R2747.2 U2703.2
PCA9555A_A2: R2745.1 R2746.2 U2703.3
PCA9555B_A0: R1030.1 R1035.2 U1002.21
PCA9555B_A1: R1031.1 R1034.2 U1002.2
PCA9555B_A2: R1032.1 R1033.2 U1002.3
PCB_ID0: R2722.1 R2738.2 R2861.1 U2703.16
PCB_ID1: R2723.1 R2739.2 R2862.1 U2703.17
PCB_ID2: R2724.1 R2740.2 R2863.1 U2703.18
PCIE_EP_RC_FLAG: J3.313 R208.2
PG_ADJ_TEC: R73.2 R1006.2
PHX_GND: C1631.1 C1632.1 C1633.1 C1634.1 C1642.2 C1643.2 C1703.1 C1704.1 C1705.1 C1706.1 D1703.1 D1704.1 D1705.1 D1706.1 D1707.1 D1708.1 D1709.1 D1710.1 D1711.1 D1712.1 D1713.1 D1714.1 D1715.1 D1716.1 D1717.1 D1718.1 D1719.1 D1720.1 D1721.1 D1722.1 J1701.2 J1701.9 J1702.5 J1702.10 M6.1 M23.1 M24.1 R1633.2 R1637.2 R1638.2 R1639.2 R1703.1 R1710.1 R1713.1 R1716.1
PHY0_MDI0_N: J1601.10 T1601.13
PHY0_MDI0_P: J1601.9 T1601.14
PHY0_MDI1_N: J1601.14 T1601.16
PHY0_MDI1_P: J1601.11 T1601.17
PHY0_MDI2_N: J1601.13 T1601.19
PHY0_MDI2_P: J1601.12 T1601.20
PHY0_MDI3_N: J1601.16 T1601.22
PHY0_MDI3_P: J1601.15 T1601.23
PLL_X1: C140.2 R264.1 R301.1 X3.1
PLL_X2: C141.2 R264.2 U301.9 X3.3
PLLVDDL0: C1408.1 C1431.1 LB1401.2 U6.116
POWER_EN: J3.301 R51.2 R54.1 R250.1 R1036.2
POWER_LED_MCU_G: R2835.2 R3616.1 R3619.1
POWER_LED_MCU_R: R2832.2 R3617.2 R3618.1
PWR_EN_5G: R117.1 R850.2
PWR_TEC_BACKWARD: Q1105.3 R1101.1 R1102.1 R1112.1 R1115.2
PWR_TEC_FORWARD: C1107.1 Q1106.3 R1103.1 R1108.1 R1120.1
REFER_2V5: C2509.1 C2510.1 R2510.1 R2511.2 R2517.1 R2518.1
RGMII0_MDCK: J3.170 R1236.1 R1245.1 R1246.2
RGMII0_MDIO: J3.172 R1235.1 R1247.2
RGMII0_RST: J3.174 R122.1 R344.2 R347.1
RGMII0_RST_R: C1213.1 R140.2 R178.2 R1222.1 U1201.13
RGMII0_RXCK: J3.202 R1227.2
RGMII0_RXD0: J3.198 R1223.2
RGMII0_RXD1: J3.196 R1224.2
RGMII0_RXD2: J3.194 R1225.2
RGMII0_RXD3: J3.192 R1226.2
RGMII0_RXDV: J3.200 R1228.2
RGMII0_TXCK: R402.2 U1201.21
RGMII0_TXD0: R404.2 U1201.19
RGMII0_TXD1: R405.2 U1201.18
RGMII0_TXD2: R406.2 U1201.17
RGMII0_TXD3: R407.2 U1201.16
RGMII0_TXEN: R403.2 U1201.20
RGMII1_MDCK: J3.134 R1319.1 R1329.1
RGMII1_MDIO: J3.136 R1325.2 R1334.1
RGMII1_RST: J3.138 R119.1 R345.2 R348.1
RGMII1_RXCK: J3.166 R1324.2
RGMII1_RXCK_R: C97.2 R184.2 R1324.1 U6.62
RGMII1_RXD0: J3.162 R1322.2
RGMII1_RXD0_R: C190.2 R204.2 R1322.1 U6.60
RGMII1_RXD1: J3.160 R1321.2
RGMII1_RXD1_R: C191.2 R257.2 R1321.1 U6.59
RGMII1_RXD2: J3.158 R1320.2
RGMII1_RXD2_R: C192.2 R258.2 R1320.1 U6.58
RGMII1_RXD3: J3.156 R1318.2
RGMII1_RXD3_R: C193.2 R273.2 R1318.1 U6.57
RGMII1_RXDV: J3.164 R1323.2
RGMII1_RXDV_R: C189.2 R185.2 R1323.1 U6.61
RGMII1_TXCK: C1317.2 R408.2 U6.63
RGMII1_TXD0: R410.2 U6.65
RGMII1_TXD1: R411.2 U6.66
RGMII1_TXD2: R412.2 U6.67
RGMII1_TXD3: R413.2 U6.68
RGMII1_TXEN: R409.2 U6.64
RGMII_CLK_PHY0: C184.1 R1227.1 R1240.2 R1242.1 U1201.28
RGMII_DV_PHY0: C183.1 R1206.2 R1228.1 R1241.1 U1201.27
RGMII_PHY0_D0: C188.1 R1202.2 R1203.1 R1223.1 U1201.26
RGMII_PHY0_D1: C187.1 R1207.2 R1224.1 R1239.1 U1201.25
RGMII_PHY0_D2: C186.1 R1208.2 R1225.1 R1244.1 U1201.24
RGMII_PHY0_D3: C185.1 R1209.2 R1226.1 R1243.1 U1201.23
RS232_RX: D17.1 J1601.6 LB1604.2 TP8.1
RS232_TX: D16.1 J1601.3 LB1603.2 TP7.1
RS485_RXD_N: D1720.2 J1702.8 LB1605.2
RS485_RXD_P: D1721.2 J1702.9 LB1606.2
RS485_TXD_N: D1716.2 J1702.3 LB1608.2
RS485_TXD_P: D1717.2 J1702.4 LB1607.2
RST_5G_LTE: J3.292 R821.1
RSV_GPIO: J3.282 Q1.2 R280.2 R281.2 R288.1 R390.2 R391.1
RSV_GPIO_R: C170.1 Q1.3 R281.1 R282.2 R290.2 R388.2 R389.2 R2842.2
RSV_WAKE: J3.141 R247.2
RTL8367_INT: R1361.2 R1372.1 U6.19
SATA_LED: D18.1 D19.1 R135.1 R3611.1
SATA_RX+: C135.2 J601.41 R617.2
SATA_RX-: C134.2 J601.43 R616.2
SATA_TX+: C132.2 J601.49 R615.2
SATA_TX-: C133.2 J601.47 R614.2
SD_CLK: J1901.5 R63.2 R64.1 R77.2
SD_CMD: J1901.3 R1904.2 U1901.6(TP-6)
SD_DATA0: J1901.7 R1905.2 U1902.1
SD_DATA1: J1901.8 R1906.2 U1902.3
SD_DATA2: J1901.1 R1902.2 U1901.1
SD_DATA3: J1901.2 R1903.2 U1901.3
SDIO_CLK: J3.169 R77.1 U1901.4
SDIO_CMD: J3.167 R1904.1 R1911.2
SDIO_DATA0: J3.165 R1905.1 R1910.2
SDIO_DATA1: J3.163 R1906.1 R1909.2
SDIO_DATA2: J3.161 R1902.1 R1908.2
SDIO_DATA3: J3.159 R1903.1 R1907.2
SDIO_DETECT: C1901.1 J3.155 R1901.1 R1912.1 R1918.2
SDIO_POWER_EN: J3.157 R1915.1
SDIO_VOUT: J3.153 R64.2 R1907.1 R1908.1 R1909.1 R1910.1 R1911.1 R1918.1
SENSE_LTE_3V3: R2824.1 R2825.2 U3.L3
SENSE_LTE_3V8: R2820.2 R2821.1 U3.G4
SENSE_TEC_OUT: R2822.1 R2823.2 U3.K2
SENSE_VBAT_3V0: R3216.2 R3217.2 R3221.2 U3.K1
SENSE_VCC_3V3: R2818.2 R2819.1 U3.G3
SENSE_VCC_5V0: R2816.1 R2817.2 U3.F3
SENSE_VIN_12V0: R2814.2 R2815.1 U3.E3
SERDES0_RX_N: C134.1 J3.38 R616.1
SERDES0_RX_P: C135.1 J3.40 R617.1
SERDES0_TX_N: C133.1 J3.39 R614.1
SERDES0_TX_P: C132.1 J3.41 R615.1
SERDES1_RX_N: C95.2 J3.44
SERDES1_RX_P: C96.2 J3.46
SERDES1_TX_N: C915.1 J3.45
SERDES1_TX_P: C916.1 J3.47
SERDES2_RX_N: C83.2 J3.50
SERDES2_RX_P: C94.2 J3.52
SERDES2_TX_N: C901.1 J3.51
SERDES2_TX_P: C913.1 J3.53
SERDES3_RX_N: J3.56 J803.41
SERDES3_RX_P: J3.58 J803.43
SERDES3_TX_N: C810.1 J3.57
SERDES3_TX_P: C811.1 J3.59
SERDES4_RX_N: J3.86 J701.23
SERDES4_RX_P: J3.88 J701.25
SERDES4_TX_N: C722.1 J3.87
SERDES4_TX_P: C723.1 J3.89
SERDES_CLK0_N: C2622.2 J3.32
SERDES_CLK0_P: C2621.2 J3.34
SLOT_SEL0: J3.312 R142.1
SLOT_SEL1: J3.310 R187.1
SPI0_CLK: J3.189 R106.1
SPI0_CS0: J3.193 R101.1
SPI0_MISO: J3.185 R105.1
SPI0_MOSI: J3.187 R102.1
SPI2_CLK: J3.177 R2758.1
SPI2_CLK_R: R173.1 R376.2 R2758.2
SPI2_CS0: J3.181 R2763.1
SPI2_CS0_R: R170.1 R295.2 R2763.2
SPI2_MISO: J3.173 R2762.1
SPI2_MISO_R: R72.1 R378.2 R2762.2
SPI2_MOSI: J3.175 R2761.1
SPI2_MOSI_R: R171.1 R377.2 R2761.2
SPI_CLK_HUB0: R2019.1 U2002.34
SPI_CS_HUB: R2003.2 R2016.2 R2020.2 R2036.1 R2037.1
SPI_CS_HUB0: R2020.1 U2002.32
SPI_CS_HUB1: R2016.1 U2101.45
SPI_MCU_CLK: R2810.1 R2878.1 U2801.6
SPI_MCU_CS: R2805.2 R2876.2 U2801.1
SPI_MCU_MISO: R2803.1 R2806.2 U3.F13
SPI_MCU_MOSI: R2809.1 R2875.1 U2801.5
SPI_MISO_HUB: R2002.1 R2013.2 R2017.2
SPI_MISO_HUB0: R2017.1 U2002.33
SPI_MISO_HUB1: R2013.1 U2101.46
SPI_MOSI_HUB: R2004.1 R2014.2 R2018.2
SPI_MOSI_HUB0: R2018.1 U2002.35
SPI_MOSI_HUB1: R2014.1 U2101.47
SPI_SCK_HUB: R2001.2 R2015.2 R2019.2
SPI_SCK_HUB1: R2015.1 U2101.44
SPWR_DET_REAR_HUB1: R2008.1 U2002.44
SPWR_DET_USB2: R2103.2 U2101.76
SYS_RST_OUT: J3.293 R115.1 R342.2 R343.1
SYS_RST_OUT_R: R124.2 R334.2 R335.2 R2780.2 R2847.2
TAISHAN_POROFF_IN: R150.2 R2846.2 R2952.2 R2990.2
TAISHAN_POROFF_OUT: R152.2 R2845.2 R2955.2 R2993.2
TAISHAN_POWEROFF_IN: J3.299 R154.1 R2948.1 R2973.2
TAISHAN_POWEROFF_OUT: J3.287 R156.1 R2949.1 R2975.2
TAISHAN_SLEEP_IN: J3.291 R155.1 R2922.1 R2974.2
TAISHAN_SLEEP_IN_R: R151.2 R2843.2 R2921.2 R2991.2
TAISHAN_SLEEP_OUT: J3.289 R153.1 R2923.1 R2976.2
TAISHAN_SLEEP_OUT_R: R149.2 R2844.2 R2956.2 R2992.2
TEC+: C1101.2 D1102.2 J903.1 J903.5 Q1101.1 Q1101.2 Q1101.3 Q1104.5 Q1104.6 Q1104.7 Q1104.8 R1113.1 TP18.1 TP20.1
TEC-: C1102.2 D1101.2 J903.2 J903.4 Q1102.5 Q1102.6 Q1102.7 Q1102.8 Q1103.1 Q1103.2 Q1103.3 R1114.2 TP17.1 TP22.1
TEC_GND: J2001.1 Q1001.2 R1010.1 U11.11 U11.15
TEC_TRIM1: Q1002.3 R1002.2 R1011.2
TEC_TRIM2: Q1001.3 Q1002.2 R1008.1 R1010.2
TPM_CLK: R181.2 R182.2 R2776.2
TPM_CS_N: R175.2 R287.2 R2777.2
TPM_INT: J3.191 R2759.1
TPM_INT_R: R103.1 R291.2 R292.1 R2759.2
TPM_MISO: R219.2 R285.2 R2778.2
TPM_MOSI: R180.2 R183.2 R2779.2
TPM_ON_LINE1: J2701.6 J2701.31
TPM_ONLINE: J3.227 R202.1
TPM_TYPE: R203.2 R2783.2 R2784.1
TYPE_ID0: R125.1 R2725.1 R2741.2 U2703.19
TYPE_ID1: R126.1 R2726.1 R2742.2 U2703.20
UART0_RX: J3.14 R41.2 R2928.1
UART0_RX_R: R1614.1 R1644.1 U2904.3
UART0_TX: J3.16 R47.2 R2937.1
UART0_TX_R: R1642.1 R2941.2 U1601.11
UART1_RX: J3.18 R2946.1 R2997.2
UART1_RX_R: R33.2 R2879.1 U2904.8
UART1_TX: J3.20 R42.2 R2947.1
UART1_TX_R: R34.2 R2954.2 U3.D1
UART2_RX: J3.147 R40.2 R2929.1
UART2_RX_R: R1603.1 R1611.1 U2904.4
UART2_TX: J3.149 R46.2 R2936.1
UART2_TX_R: R1601.1 R2940.2 U1603.4
UART3_RX: J3.26 R39.2 R2930.1
UART3_RX_R: R1625.1 R1652.2 U2904.5
UART3_TX: J3.28 R45.2 R2935.1
UART3_TX_R: R1651.2 R2939.2 U1602.5
UART6_RX: J3.24 R82.2
UART6_TX: J3.22 R60.2
UART_DEBUG_MCU: R76.2 R227.2 U3.E1
UART_MCU_DEBUG: R29.2 R228.2 U3.E2
UART_RS485_N: D1715.2 J1702.1 LB1601.2
UART_RS485_P: D1718.2 J1702.2 LB1602.2
UART_RTX_EN: J3.321 R43.2 R2945.1
UART_RTX_EN_R: R1602.1 R1609.2 R1610.1 R2953.2
UART_RXD_5G: R806.1 TP12.1(TP-1)
UART_RXD_MODULE: J803.62 R806.2
UART_TXD_5G: R807.1 TP11.1(TP-1)
UART_TXD_MODULE: J803.64 R807.2
UHT_ALARM: J3.303 R414.2 R2841.2
UPDATE_MODE: J3.139 R83.2
USB1_5V0: C56.1 C57.1 C58.1 C59.1 C60.1 C73.1 C2202.2 D9.1 D9.2 J2201.1 LB2201.2 R2204.2
USB2_5V0: C61.1 C62.1 C63.1 C64.1 C65.1 C71.1 C2206.2 D7.1 D7.2 J2202.1 LB2202.2 R2208.2
USB2_CONN_DN2: R251.1 R2221.2 T2204.2 U2205.6(TP-6)
USB2_CONN_DN3: R253.1 R2231.2 T2209.2 U2205.1
USB2_CONN_DP2: R252.1 R2220.2 T2204.3 U2205.4
USB2_CONN_DP3: R254.1 R2230.2 T2209.3 U2205.3
USB2_DM1_HUB0: R2111.1 U2002.54
USB2_DM1_HUB1: R2112.1 U2101.57
USB2_DN1: J3.123 R2111.2 R2112.2
USB2_DN2: J3.116 R2221.1 T2204.1
USB2_DN3: J3.117 R2231.1 T2209.1
USB2_DP1: J3.125 R2109.2 R2110.2
USB2_DP1_HUB0: R2109.1 U2002.53
USB2_DP1_HUB1: R2110.1 U2101.56
USB2_DP2: J3.118 R2220.1 T2204.4(TP-4)
USB2_DP3: J3.119 R2230.1 T2209.4(TP-4)
USB3_0_CONN_RX_N: D2202.1 D2202.10 J2202.5 R2227.2 T2207.2
USB3_0_CONN_RX_P: D2202.2 D2202.9 J2202.6 R2226.2 T2207.3
USB3_0_CONN_TX_N: D2202.4 D2202.7 J2202.8 R2229.2 T2208.2
USB3_0_CONN_TX_P: D2202.5 D2202.6 J2202.9 R2228.2 T2208.3
USB3_0_RX_N: J3.104 R2227.1 T2207.1
USB3_0_RX_P: J3.106 R2226.1 T2207.4(TP-4)
USB3_0_TX_N: C123.1 J3.105
USB3_0_TX_P: C124.1 J3.107
USB3_1_CONN_RX_N: D2203.1 D2203.10 J2201.5 R2224.2 T2206.2
USB3_1_CONN_RX_P: D2203.2 D2203.9 J2201.6 R2225.2 T2206.3
USB3_1_CONN_TX_N: D2203.4 D2203.7 J2201.8 R2223.2 T2205.2
USB3_1_CONN_TX_P: D2203.5 D2203.6 J2201.9 R2222.2 T2205.3
USB3_1_RX_N: J3.98 R2224.1 T2206.1
USB3_1_RX_P: J3.100 R2225.1 T2206.4(TP-4)
USB3_1_TX_N: C127.1 J3.99
USB3_1_TX_P: C128.1 J3.101
USB3_2_RX_N: C99.1 C2132.1 J3.92
USB3_2_RX_N_HUB0: C99.2 U2002.47
USB3_2_RX_N_HUB1: C2132.2 U2101.59
USB3_2_RX_P: C98.1 C2133.1 J3.94
USB3_2_RX_P_HUB0: C98.2 U2002.48
USB3_2_RX_P_HUB1: C2133.2 U2101.60
USB3_2_TX_N: C101.1 C2130.1 J3.93
USB3_2_TX_N_HUB0: C101.2 U2002.50
USB3_2_TX_N_HUB1: C2130.2 U2101.62
USB3_2_TX_P: C100.1 C2131.1 J3.95
USB3_2_TX_P_HUB0: C100.2 U2002.51
USB3_2_TX_P_HUB1: C2131.2 U2101.63
USB3_5V0: C66.1 C67.1 C68.1 C69.1 C70.1 C72.1 C2210.2 D8.1 D8.2 J2203.1 LB2203.2 R2216.2 U2206.5
USB20_4G_DN: J701.36 R709.1 T1.1
USB20_4G_DP: J701.38 R708.1 T1.4(TP-4)
USB20_4G_HUB0_DN: R2130.1 U2002.66
USB20_4G_HUB0_DP: R2128.1 U2002.65
USB20_4G_HUB1_DN: R2129.1 U2101.21
USB20_4G_HUB1_DP: R2127.1 U2101.20
USB20_4G_HUB_DN: C715.1 R709.2 R2129.2 R2130.2 T1.2
USB20_4G_HUB_DP: C716.1 R708.2 R2127.2 R2128.2 T1.3
USB20_5G_HUB0_DN: R2126.1 U2002.75
USB20_5G_HUB0_DP: R2124.1 U2002.74
USB20_5G_HUB1_DN: R2125.1 U2101.6
USB20_5G_HUB1_DP: R2123.1 U2101.5
USB20_5G_HUB_DN: J803.9 R2125.2 R2126.2
USB20_5G_HUB_DP: J803.7 R2123.2 R2124.2
USB20_D_HUB0_DN: R2138.1 U2002.8
USB20_D_HUB0_DP: R2136.1 U2002.7
USB20_D_HUB1_DN: R2137.1 U2101.72
USB20_D_HUB1_DP: R2135.1 U2101.71
USB20_D_HUB_CONN_DN: J2203.2 R2219.2 T2203.2 U2206.1
USB20_D_HUB_CONN_DP: J2203.3 R2218.2 T2203.3 U2206.3
USB20_D_HUB_DN: R2137.2 R2138.2 R2219.1 T2203.1
USB20_D_HUB_DP: R2135.2 R2136.2 R2218.1 T2203.4(TP-4)
USB30_5G_HUB0_RX_N: R2122.1 U2002.72
USB30_5G_HUB0_RX_P: R2108.1 U2002.71
USB30_5G_HUB0_TX_N: C2106.1 U2002.69
USB30_5G_HUB0_TX_P: C2103.1 U2002.68
USB30_5G_HUB1_RX_N: R2121.1 U2101.12
USB30_5G_HUB1_RX_P: R2107.1 U2101.11
USB30_5G_HUB1_TX_N: C2105.1 U2101.9
USB30_5G_HUB1_TX_P: C2104.1 U2101.8
USB30_5G_HUB_RX_N: R231.1 R2121.2 R2122.2
USB30_5G_HUB_RX_P: R230.1 R2107.2 R2108.2
USB30_5G_HUB_TX_N: C2105.2 C2106.2 R233.1
USB30_5G_HUB_TX_P: C2103.2 C2104.2 R232.1
USB30_D_HUB0_RX_N: R2134.1 U2002.5
USB30_D_HUB0_RX_P: R2132.1 U2002.4
USB30_D_HUB0_TX_N: C2110.1 U2002.2
USB30_D_HUB0_TX_P: C2108.1 U2002.1
USB30_D_HUB1_RX_N: R2133.1 U2101.69
USB30_D_HUB1_RX_P: R2131.1 U2101.68
USB30_D_HUB1_TX_N: C2109.1 U2101.66
USB30_D_HUB1_TX_P: C2107.1 U2101.65
USB30_D_HUB_CONN_RX_N: D2201.5 D2201.6 J2203.5 R2210.2 T2201.2
USB30_D_HUB_CONN_RX_P: D2201.4 D2201.7 J2203.6 R2209.2 T2201.3
USB30_D_HUB_CONN_TX_N: D2201.2 D2201.9 J2203.8 R2211.2 T2202.2
USB30_D_HUB_CONN_TX_P: D2201.1 D2201.10 J2203.9 R2212.2 T2202.3
USB30_D_HUB_RX_N: R2133.2 R2134.2 R2210.1 T2201.1
USB30_D_HUB_RX_P: R2131.2 R2132.2 R2209.1 T2201.4(TP-4)
USB30_D_HUB_TX_N: C2109.2 C2110.2 R2211.1 T2202.1
USB30_D_HUB_TX_P: C2107.2 C2108.2 R2212.1 T2202.4(TP-4)
USB30_PWR0_EN1: R88.2 R238.2 R2217.2 U2002.26 U2203.4
USB30_PWR1_EN1: C80.2 Q2101.1 R189.1 R2141.2 R2142.1
USB_12M_X0_HUB1: C78.2 R109.2 R110.2 R222.1 U2101.75
USB_12M_XI_HUB1: R111.2 R112.2 R223.1 U2101.74
USB_25M_XI_HUB1: R2011.1 U2002.55
USB_25M_XO_HUB1: R2012.1 U2002.56
USB_PWR_EN: R58.2 R2203.2 R2207.2 U2201.4 U2202.4
USIM0_CLK: C104.2 J702.3 R705.2 R801.2 U701.3
USIM0_DATA: C105.1 J702.7 R706.2 R722.1 R803.2 U701.4
USIM0_DECT: R48.2 R50.2 R104.1
USIM0_DECT_R: J702.4 R104.2 U701.6(TP-6)
USIM0_PWR: C111.1 C724.1 C725.1 C726.1 C727.1 C728.1 J702.1 R32.2 R49.2 R722.2 U701.5
USIM0_RST: C103.2 J702.2 R704.2 R802.2 U701.1
USIM1_DECT: J803.66 R50.1
USIM1_PWR: J803.36 R49.1
V_3V3_4G: C112.1 C706.1 C707.1 C708.1 C709.1 C712.1 C717.1 C718.1 C719.1 J701.2 J701.24 J701.39 J701.41 J701.52 LB702.2 LB703.2
V_3V3_HUB: C2001.1 C2024.1 R162.2 R163.2 R2030.2 R2031.2 R2034.1 R2035.1 R2036.2 U2001.8 U2003.8
V_3V3_USBHUB0: C76.1 C77.1 C2111.1 C2113.1 C2114.1 C2115.1 C2116.1 C2117.2 C2118.2 C2119.1 LB2101.2 R109.1 R112.1 R162.1 R206.1 R207.1 R337.1 R2102.1 R2103.1 R2142.2 R2143.1 U2101.4 U2101.22 U2101.48 U2101.53 U2101.54 U2101.55 U2101.73
V_5V0_HUB: C2021.2 C2026.1 C2028.1 C2029.1 C2030.1 C2031.1 C2032.1 C2033.2 LB2001.2 U2002.20 U2002.38
V_12V0_CON_IN: C38.1 C3008.1 C3010.1 D3001.1 J2.1 J2.2 J2.5 J2.6 J2.9 J2.10 R3003.2 R3004.2 R3005.2 R3006.2 R3012.1 R3013.2 R3018.1 R3019.1 TP25.1 TP26.1 U3001.9
V_12V0_IN: C3016.2 C3017.2 C3018.1 C3019.2 C3020.2 D5.1 L3001.1 Q3001.1 Q3001.2 Q3001.3 R3002.2
V_12V0_SENSE: C3001.1 Q3001.5 Q3001.6 Q3001.7 Q3001.8 R86.2 R3011.2 R3018.2 R3019.2
V_ADJ_TEC: C1103.1 C1104.1 F1001.1 Q1101.5 Q1101.6 Q1101.7 Q1101.8 Q1103.5 Q1103.6 Q1103.7 Q1103.8
V_AVDD_1V0_PHY0: C1208.2 C1209.2 C1212.2 R59.2 U1201.4 U1201.9 U1201.47
V_AVDD_3V3_PHY0: C1205.2 C1206.2 C1207.2 LB1202.2 U1201.1 U1201.12
V_BAT_3V0: D15.2 J3.283 R3220.1 R3221.1
V_DV11_HUB: C2002.1 C2004.2 C2005.2 C2007.1 C2009.1 C2010.1 C2013.1 C2015.1 C2016.1 C2018.1 C2019.1 C2038.2 C2039.2 C2040.2 C2041.1 C2042.1 C2043.1 C2044.1 C2045.2 C2046.2 C2047.2 L2001.2 U2002.3 U2002.9 U2002.12 U2002.22 U2002.40 U2002.46 U2002.49 U2002.61 U2002.67 U2002.70 U2002.76
V_DV12_HUB: C42.1 C2120.1 C2121.1 C2122.1 C2123.1 C2124.1 C2125.1 C2126.1 C2127.1 C2128.1 C2129.1 L2101.2 U2101.3 U2101.7 U2101.13 U2101.19 U2101.25 U2101.31 U2101.49 U2101.50 U2101.58 U2101.64 U2101.70
V_DV33_HUB: C2003.2 C2006.2 C2008.1 C2011.2 C2012.1 C2014.1 C2017.1 C2020.2 C2034.2 C2035.2 C2036.2 C2037.2 LB2002.2 R163.1 R201.2 R298.2 R336.2 R2008.2 R2009.2 R2032.2 R2033.2 R2038.1 U2002.6 U2002.15 U2002.29 U2002.43 U2002.52 U2002.58 U2002.64 U2002.73
V_DVDD_1V0_PHY0: C1210.2 C1211.2 C1214.2 C1215.2 L1201.1 R59.1 U1201.22
V_HOT_12V0_D1: C3503.1 C3504.1 C3509.1 C3511.1 C3512.1 C3513.1 C3514.1 C3515.1 D3501.3 R3507.2 R3508.2 R3509.2 R3510.2 R3511.2 R3512.2 R3513.1 R3514.1 R3515.1 R3516.1 R3517.1 R3518.1 R3524.1 R3525.1 R3526.1 R3527.2 R3528.2 R3529.2 R3568.2 R3569.1 R3570.2 R3571.1 R3572.1 R3573.2 R3574.1 R3575.1 R3576.2 R3577.2 R3578.2 R3579.1 R3582.1 R3583.2
V_HOT_12V0_D2: C3525.1 C3526.1 C3527.1 C3528.1 C3529.1 C3530.1 C3531.1 C3532.1 D3502.3 R3561.2 R3562.2 R3563.2 R3564.2 R3565.2 R3566.2 R3567.2 R3584.1 R3585.1 R3586.2 R3587.2 R3588.2 R3589.2 R3590.2 R3591.2 R3592.2
V_HOT_12V0_D3: C113.1 C114.1 C115.1 C116.1 C117.1 C118.1 C119.1 C120.1 D6.3 R3519.1 R3520.1 R3521.1 R3522.1 R3523.1 R3530.2 R3531.2 R3532.2 R3533.2 R3534.2 R3541.1 R3542.1 R3543.1 R3544.1 R3545.1 R3546.1 R3547.1 R3548.1 R3549.1 R3550.1 R3551.2 R3552.2 R3553.2 R3554.2 R3555.2 R3556.2 R3557.2 R3558.2 R3559.2 R3560.2 R3580.2 R3581.1
V_HOT_12V_1: C3501.1 C3502.2 C3505.1 C3507.1 C3508.1 C3516.1 D6.1 D6.2 D3501.1 D3501.2 Q3501.5 Q3501.6 Q3501.7 Q3501.8
V_HOT_12V_2: C3517.1 C3518.2 C3519.1 C3521.1 C3522.1 C3524.1 D3502.1 D3502.2 Q3504.5 Q3504.6 Q3504.7 Q3504.8
V_HUB_3V3: C2112.1 LB2101.1 R176.2
V_HUB_5V0: C2027.1 LB2001.1 R186.2
V_LTE_3V3: C711.1 C731.1 C3136.1 C3137.1 C3138.1 C3140.1 D1.1 L3103.2 LB702.1 LB703.1 R128.2 R701.2 R2825.1 R3126.2
V_LTE_3V8: C84.1 C85.1 C86.1 C87.1 C88.1 C89.1 C90.1 C91.1 C92.1 C814.1 C815.1 C816.1 C817.1 C818.1 C819.1 C820.1 C821.1 C822.1 C839.1 C3122.1 C3123.1 C3124.1 C3126.1 D4.1 D801.1 J803.2 J803.4 J803.70 J803.72 J803.74 L3102.2 R117.2 R129.2 R831.2 R2820.1 R3116.2
V_LTV_3V3: C1703.2 C1704.2 C1705.2 C1706.2 LB1702.2 U2.1 U7.1 U8.1 U12.1
V_SDCARD_V33: C1902.1 C1903.1 C1904.1 C1906.1 J1901.4 Q1901.3 R1917.1 U1901.5 U1902.5
V_STBY_1V8: C107.2 C108.2 C164.2 C165.2 C166.1 C426.1 C834.2 C1320.2 C1801.2 C2025.2 C2714.2 C2911.2 C2912.2 C2915.2 C2916.2 C3217.1 C3218.1 C3406.1 LB403.1 LB405.1 LB406.1 LB802.1 LB1407.1 Q1.1 Q4.1 Q1801.2 R39.1 R40.1 R41.1 R42.1 R43.1 R44.1 R45.1 R46.1 R47.1 R78.1 R79.1 R80.1 R81.1 R92.1 R93.1 R167.2 R168.1 R200.2 R278.1 R280.1 R291.1 R293.1 R294.1 R295.1 R342.1 R344.1 R345.1 R346.1 R352.1 R360.1 R362.1 R364.1 R376.1 R377.1 R378.1 R390.1 R841.1 R1237.1 R1319.2 R1325.1 R1802.2 R2754.1 R2755.1 R2826.2 R2973.1 R2974.1 R2975.1 R2976.1 R2985.1 R2986.1 R2997.1 R2999.1 R3210.2 R3211.2 U15.23 U15.24 U16.23 U16.24 U17.1 U1301.2 U2003.1 U2704.1 U2903.23 U2903.24 U2904.23 U2904.24 U3201.1 U3201.19 U3201.20 U3401.5
V_STBY_3V3: C4.1 C5.1 C6.1 C7.1 C13.1 C14.1 C15.1 C16.1 C17.1 C18.1 C19.1 C20.1 C21.1 C22.1 C23.1 C24.1 C102.2 C106.2 C129.2 C130.2 C136.2 C154.1 C155.1 C1012.1 C1016.1 C1603.1 C1615.1 C1616.1 C1617.1 C1645.2 C1646.2 C1802.2 C1905.1 C1907.1 C1909.1 C2701.1 C2711.1 C2712.1 C2713.1 C2801.1 C2805.1 C2806.1 C2807.1 C2808.1 C2809.1 C2811.1 C2812.1 C2813.1 C2909.2 C2910.2 C2913.2 C2914.2 C3208.1 C3209.1 C3210.1 C3212.1 C3214.1 C3216.1 C3220.1 C3223.1 C3225.1 C3402.2 C3404.1 D1702.1 D2408.1 LB1.2 LB3.1 LB4.1 LB5.1 LB6.1 LB7.1 LB9.1 LB10.1 LB402.1 LB404.1 LB1610.2 LB1701.1 LB1703.1 LB1704.1 LB1705.1 LB2501.2 LB2506.1 LB2801.1 LB3001.2 LB3601.2 LB3602.2 LB3603.2 Q3.2 Q1802.2 Q1901.2 Q3202.1 Q3202.2 Q3202.3 R2.2 R3.2 R4.2 R5.2 R6.2 R7.2 R8.2 R9.2 R16.1 R21.2 R22.2 R24.2 R25.1 R26.1 R27.1 R28.1 R33.1 R34.1 R35.1 R36.1 R37.2 R38.2 R54.2 R90.2 R91.2 R96.2 R97.2 R98.2 R99.2 R141.1 R165.1 R209.1 R227.1 R228.1 R239.1 R241.1 R243.1 R245.1 R249.2 R277.1 R282.1 R284.1 R286.1 R335.1 R351.1 R355.1 R356.1 R359.1 R389.1 R414.1 R1019.2 R1030.2 R1031.2 R1032.2 R1106.1 R1601.2 R1607.1 R1610.2 R1611.2 R1619.2 R1622.2 R1627.1 R1628.2 R1642.2 R1644.2 R1647.1 R1648.1 R1651.1 R1652.1 R1804.2 R1914.1 R2025.1 R2215.2 R2703.1 R2704.1 R2705.1 R2711.2 R2712.2 R2713.2 R2714.2 R2715.2 R2716.2 R2717.2 R2718.2 R2719.2 R2720.2 R2721.2 R2722.2 R2723.2 R2724.2 R2725.2 R2726.2 R2743.2 R2744.2 R2745.2 R2749.1 R2784.2 R2803.2 R2804.2 R2805.1 R2809.2 R2810.2 R2818.1 R2829.2 R2830.2 R2887.2 R2888.2 R2889.2 R2891.2 R2892.2 R2893.2 R2942.1 R2984.2 R2990.1 R2991.1 R2992.1 R2993.1 R3023.2 R3102.1 R3125.2 R3136.2 R3202.1 R3204.1 R3206.1 R3213.2 R3403.1 R3404.1 R3405.1 R3406.2 R3408.2 R3410.2 R3412.1 R3422.1 R3423.2 R3424.2 R3607.1 R3613.1 U1.17 U1.18 U1.19 U1.20 U1.21 U3.A15 U3.C15 U3.D9 U3.E8 U3.E9 U3.E10 U3.L9 U3.L10 U3.P6 U3.R1 U3.R3 U3.R5 U5.8 U10.8 U15.1 U16.1 U1002.24 U1602.14 U1603.8 U2701.8 U2703.24 U2704.8 U2801.8 U2803.8 U2804.8 U2805.8 U2903.1 U2904.1 U3201.15 U3201.16 U3201.17 U3402.2
V_STBY_5V0: C159.1 C160.1 C161.1 C2513.1 C2514.1 C3108.1 C3115.1 C3116.1 C3117.1 F3301.1 L3101.2 LB8.1 LB2505.1 R172.1 R238.1 R1616.2 R2203.1 R2207.1 R2817.1 R3104.1 R3106.2 RT1.2(TP-2) RT2.2(TP-2) U2201.6 U2202.6 U2203.6
V_STBY_12V0: C2.1 C3.1 C8.1 C9.1 C37.1 C3105.1 C3106.1 C3111.1 C3119.1 C3127.1 C3128.1 C3129.1 C3131.1 C3201.1 C3202.1 C3203.1 F3002.1 F3302.1 F3501.1 F3502.1 L1001.1 L3104.1 R712.1 R1012.1 R1112.2 R1118.2 R1120.2 R2814.1 R3110.2 R3119.2 R3411.2 R3416.2 U1.24 U1.29 U1.40 U3101.4 U3101.5 U3101.6 U3102.1
V_STBY_TEC_12V0: C46.1 C47.1 C52.1 C54.1 C55.1 C1003.1 C1004.1 C1005.1 L1001.2 U11.24 U11.29 U11.40
V_TEC_OUT: D1101.1 D1102.1 R2823.1
V_TPM_3V3: C162.2 C167.2 C2702.1 C2703.1 C2704.1 C2705.1 C2706.1 J2701.1 J2701.2 J2701.3 Q3.3 R169.1 R182.1 R183.1 R209.2 R285.1 R287.1 R3801.2 U17.14
V_VCC_1V8_EMMC: C1805.2 C1806.2 C1809.2 C1814.2 C1821.1 C1822.1 C1823.1 Q1801.3 R1810.1 R1811.1 R1812.1 R1813.1 R1814.1 R1815.1 R1816.1 R1817.1 R1818.1 R1819.1 U9.C6 U9.M4 U9.N4 U9.P3 U9.P5
V_VCC_3V3: C109.2 C603.1 C604.1 C605.1 C606.1 C607.1 C608.1 C609.1 C610.1 C619.1 C620.1 C621.1 C622.1 C1216.2 C1430.1 C1435.1 C1436.1 C1439.1 D2.1 D701.1 J601.2 J601.4 J601.12 J601.14 J601.16 J601.18 J601.70 J601.72 J601.74 LB1203.1 LB1402.1 LB1405.1 LB1406.1 Q3202.5 Q3202.6 Q3202.7 Q3202.8 R89.1 R602.2 R604.1 R606.1 R1328.2 R1331.2 R1332.2 R1406.2 U1401.5
V_VCC_3V3_EMMC: C39.2 C40.2 C41.2 C1816.2 C1818.1 C1819.1 C1820.1 Q1802.3 U9.E6 U9.F5 U9.J10 U9.K9
V_VCC_AUDIO_5V0: C2511.1 C2512.1 C2515.1 LB2505.2 R2511.1 U4.8
V_VCC_DISK_5V0: C110.2 C905.1 C907.1 C909.1 C911.1 C3307.1 C3308.1 C3309.1 C3310.1 C3311.1 D3301.1 D3301.2 J902.1 Q3303.5 Q3303.6 Q3303.7 Q3303.8 TP14.1
V_VCC_DISK_12V0: C902.1 C903.1 C904.1 C906.1 C908.1 C910.1 C3302.1 C3303.2 C3305.1 C3306.1 C3313.1 C3316.1 D3302.1 D3302.2 J902.3 Q3301.5 Q3301.6 Q3301.7 Q3301.8 R3306.2 TP13.1
V_VCC_LED_3V3: C3606.1 LB3602.1 LED3601.1 LED3601.2 R3608.1
V_VDD_3V3_PHY0: C1204.2 C1217.2 C1218.2 C1219.2 LB2.1 LB1202.1 LB1203.2 R178.1 R1210.1 R1211.1 R1212.1 R1221.1 U1201.30 U1201.31
V_VDD_3V3_PHY0_LED: J1501.17 J1501.19 J1501.21 J1501.23 J1502.17 J1502.19 J1502.21 J1502.23 J1601.21 J1601.23 LB2.2
V_VDDI_EMMC: C1813.1 U9.C1 U9.C2
VRT: J903.3 R1018.1 R1020.1 TP21.1
VRT_DET: C1015.2 R1017.2 U3.L4
XGND: C140.1 C141.1 U301.7 U301.10 X3.2 X3.4
XTAL_IN_PHY0: C1202.1 R1219.1 U1201.45 X1201.1
XTAL_OUT_PHY0: R1220.1 U1201.46
$4N67725: C176.1 J3.188 R402.1
$4N67726: C175.1 J3.186 R403.1
$4N67727: C174.1 J3.184 R404.1
$4N67728: C173.1 J3.182 R405.1
$4N67729: C172.1 J3.180 R406.1
$4N67779: C182.1 J3.152 R408.1
$4N67780: C181.1 J3.150 R409.1
$4N67781: C180.1 J3.148 R410.1
$4N67782: C179.1 J3.146 R411.1
$4N67783: C178.1 J3.144 R412.1
$4N67784: C177.1 J3.142 R413.1
$4N68414: D18.2 J3.319
$4N68429: D19.2 J3.317
$4N70341: C171.1 J3.178 R407.1
$7N42483: L1201.2 U1201.32
$7N42484: R1204.2 U1201.48
$7N42485: R1235.2 U1201.15
$7N42486: R1216.1 U1201.38
$7N42487: R1201.1 U1201.39
$7N42488: R1218.1 U1201.40
$7N42489: R1217.1 U1201.41
$7N42494: C1201.2 R1236.2 U1201.14
$7N42503: R1215.2 U1201.34
$7N42505: R1202.1 R1206.1 R1207.1 R1208.1 R1209.1 R1237.2 R1238.2 R1240.1 R1246.1 R1247.1
$7N42508: C1203.2 R1219.2 R1220.2 X1201.3
$7N63630: R196.1 U1201.3
$7N63631: R1317.1 U1201.6
$7N63632: R190.1 U1201.5
$7N63633: R191.1 U1201.8
$7N63634: R192.1 U1201.7
$7N63635: R193.1 U1201.11
$7N63636: R194.1 U1201.10
$7N63637: R195.1 U1201.2
$8N44565: R1373.2 U6.20
$8N44574: R1377.2 U6.48
$8N44575: R1376.2 U6.46
$8N44576: R1375.2 U6.47
$8N44577: R1381.2 U6.52
$8N44578: R1380.2 U6.51
$8N44579: R1379.2 U6.50
$8N44580: R1378.2 U6.49
$8N44589: C1319.1 R1310.1 R1326.2 X1301.3
$8N44608: R1374.2 U6.56
$8N44609: R1382.2 U6.13
$8N114121: R1329.2 U1301.3
$8N114122: R1334.2 U1301.4
$8N114763: R1330.1 U1301.6
$8N114764: R1333.1 U1301.5
$8N118897: C1321.2 R1328.1 U1301.7 U1301.8
$9N34271: C1801.1 Q1801.1 R1801.1 R1802.1 R1823.1
$9N34273: C1816.1 R1803.2
$9N34274: C1803.1 Q1804.1 R1805.2
$9N34275: Q1804.3 R1824.2
$9N34276: C1802.1 Q1802.1 R1803.1 R1804.1 R1824.1
$9N34280: R1807.2 U9.H5
$9N34284: R1809.2 U9.K5
$9N34299: C1811.2 R1808.2 U9.M6
$9N34313: C1814.1 R1801.2
$9N34316: C1815.1 Q1803.1 R1821.2
$9N34317: Q1803.3 R1823.2
$9N48264: R114.2 U9.M5
$11N32664: C1904.2 C1905.2 Q1901.1 R1913.1 R1914.2
$11N32665: Q1902.3 R1913.2
$11N32666: C1908.1 Q1902.1 R1915.2 R1916.1
$12N62032: R2002.2 U2001.2
$12N62036: R2034.2 U2001.3
$12N62037: R2001.1 U2001.6
$12N65908: R2003.1 U2001.1
$12N67333: R2004.2 U2001.5
$12N67903: R2035.2 U2001.7
$12N120728: R2005.1 U2002.57
$12N120770: R2006.2 U2002.23
$12N120777: R2005.2 R2007.1
$12N135137: C2022.1 R2010.1 R2012.2 X2001.1
$12N135139: C2023.1 R2010.2 R2011.2 X2001.3
$12N159486: R2025.2 U2003.5
$12N159487: R2028.1 U2003.6
$12N159488: R2029.1 U2003.7
$12N159489: R2026.2 U2003.2
$12N159490: R2027.2 U2003.3
$12N201123: R201.1 U2002.18
$12N201711: R298.1 U2002.41
$12N202119: R336.1 U2002.27
$13N103139: LB2201.1 U2201.1
$13N103140: R2201.1 R2202.2
$13N103141: R2202.1 U2201.2
$13N103146: LB2202.1 U2202.1
$13N103147: R2205.1 R2206.2
$13N103148: R2206.1 U2202.2
$13N120944: LB2203.1 U2203.1
$13N120945: R2213.1 R2214.2
$13N120946: R2214.1 U2203.2
$13N183700: C123.2 R2229.1 T2208.1
$13N183701: C124.2 R2228.1 T2208.4(TP-4)
$13N184734: C127.2 R2223.1 T2205.1
$13N184735: C128.2 R2222.1 T2205.4(TP-4)
$13N189150: J2202.2 R253.2
$13N189151: J2202.3 R254.2
$13N189902: J2201.2 R251.2
$13N189903: J2201.3 R252.2
$14N18861: D2307.1 RT1.1
$15N26586: D2407.1 RT2.1
$16N25599: J2501.5 R2505.1
$16N25600: C2505.2 R2501.2 R2502.2
$16N25603: C2508.2 R2506.2 R2507.2
$16N25607: LB2501.1 R2505.2
$16N25609: J2501.4 LB2503.1
$16N25610: J2501.3 LB2502.1
$16N25611: J2501.1 J2501.2 LB2504.1
$16N31377: C2517.2 R2513.1
$16N31378: C2516.1 R2512.2 U4.2
$16N31379: C2519.1 R2512.1 R2513.2 R2514.1
$16N31380: C2516.2 C2518.1 R2514.2 U4.1
$16N31381: C2518.2 R2515.1 R2516.1
$16N31382: R2517.2 U4.3
$16N31384: R2518.2 U4.5
$16N31385: C2522.2 R2519.1 R2520.1
$16N31386: C2524.2 R2522.1
$16N31387: C2523.1 R2521.1 R2522.2 R2523.1
$16N31388: C2522.1 C2525.2 R2521.2 U4.7
$16N31389: C2525.1 R2523.2 U4.6
$16N33792: J2502.5 R2526.2
$16N33793: C2526.1 C2527.1 C2530.1 C2532.1 D2504.2 LB2507.1 R2525.2
$16N33794: LB2506.2 R2526.1
$16N33796: J2502.1 J2502.2 LB2509.1
$16N33797: C2526.2 C2528.1 C2529.1 C2531.1 D2503.1 LB2508.1 R2524.2
$16N33798: J2502.3 LB2507.2
$16N33799: J2502.4 LB2508.2
$17N28562: C301.2 R262.2 R263.1 R267.2 U301.6
$17N28564: R266.2 R329.2 U301.12
$17N28570: R265.2 R328.2 U301.25
$17N31574: R246.2 U301.62
$17N31614: R245.2 U301.61
$17N31654: R244.2 U301.15
$17N31694: R243.2 U301.14
$17N31774: R242.2 U301.2
$17N31814: R241.2 U301.1
$17N31854: R240.2 U301.64
$17N31894: R239.2 U301.63
$20N51827: Q3101.3 R3105.2
$20N51829: C3101.2 Q3102.4 R3104.2 R3105.1 R3307.1
$20N51832: C3102.2 Q3101.1 R3103.2
$20N51834: C3101.1 Q3102.1 Q3102.2 Q3102.3 R165.2 R172.2
$20N62168: C3109.1 R3107.1 R3115.2 U3101.7
$20N62169: C3113.1 R3109.2 R3110.1 U3101.10
$20N62170: C3110.2 L3101.1 R3113.2 U3101.11 U3101.12
$20N62171: C3112.1 U3101.9
$20N62172: C3110.1 U3101.13
$20N62173: R3114.2 U3101.1
$20N62174: C3104.1 R3108.1 U3101.8
$20N62175: C3107.1 R3113.1
$20N62176: C3103.1 C3114.1 R3108.2
$20N62177: C3109.2 R3106.1 R3107.2
$20N62178: R3112.1 R3115.1
$20N62179: R3111.1 R3112.2
$20N137111: C3121.1 U3102.4
$20N137112: R3120.2 R3121.2
$20N137115: R3121.1 R3122.1
$20N137116: C3120.1 R3117.1 R3122.2 U3102.6
$20N137117: C3120.2 R3116.1 R3117.2
$20N137118: C3121.2 L3102.1 U3102.2
$20N137120: Q3103.3 R134.1
$20N155997: C3132.1 Q3105.1 R3123.2 R3137.1
$20N155998: Q3105.3 R3124.1 R3125.1
$20N155999: C3133.1 Q3103.1 R3124.2
$20N181723: C3135.1 U3103.4
$20N181724: R3131.2 R3132.1
$20N181725: R3130.1 R3131.1
$20N181726: C3134.1 R3127.1 R3130.2 U3103.6
$20N181727: C3134.2 R3126.1 R3127.2
$20N181728: C3135.2 L3103.1 U3103.2
$20N181729: C3144.1 R133.2 R3128.2 R3129.1 U3103.5
$20N181730: C3141.1 C3142.1 C3143.1 C3145.1 L3104.2 R3129.2 U3103.1
$20N182986: C3146.1 Q3106.1 R3134.2 R3138.1
$20N182987: Q3106.3 R3135.1 R3136.1
$20N182988: C3147.1 Q3104.1 R3135.2
$20N206297: Q3104.3 R133.1
$20N206729: C3130.1 R134.2 R3118.2 R3119.1 U3102.5
$20N212013: C3314.2 Q3102.5 Q3102.6 Q3102.7 Q3102.8 R176.1 R186.1
$20N224028: C3314.1 R3307.2
$46N78710: J601.50 R56.1
$46N78948: J601.38 R57.1
$47N12417: Q702.3 R702.1 R712.2
$47N12418: C713.1 Q701.1 R702.2
$47N12419: C714.1 Q702.1 R714.2
$47N12435: J701.14 R704.1
$47N12436: J701.12 R705.1
$47N12437: J701.10 R706.1
$47N22092: D1.2 R30.2
$47N42209: C722.2 J701.31
$47N42210: C723.2 J701.33
$47N53979: J701.32 R52.1
$47N53980: J701.30 R53.1
$47N73755: J701.45 R101.2
$47N73822: J701.47 R102.2
$47N73889: J701.49 R105.2
$47N73956: J701.51 R106.2
$47N81118: J701.5 R60.1
$47N81388: J701.3 R82.1
$47N82024: J701.46 R247.1
$47N85605: J701.8 R32.1
$47N85919: J701.44 R48.1
$48N878: R2702.1 U2701.6
$48N879: R2701.1 U2701.5
$48N883: R2705.2 R2707.1 U2701.1
$48N884: R2703.2 R2706.1 U2701.2
$48N885: R2704.2 R2708.1 U2701.3
$48N77079: R2709.1 U2703.23
$48N77769: R2710.1 U2703.22
$48N193018: J2701.32 R2777.1
$48N195194: J2701.34 R2776.1
$48N196898: J2701.36 R2782.1
$48N218401: R2749.2 U2704.5
$48N218402: R2752.1 U2704.6
$48N218403: R2753.1 U2704.7
$48N218404: R2750.2 U2704.2
$48N218405: R2751.2 U2704.3
$48N306521: J2701.29 R2778.1
$48N306854: J2701.27 R2779.1
$48N317514: J2701.24 R2783.1
$48N323981: J2701.22 R94.1
$48N324314: J2701.23 R95.1
$48N350896: C162.1 R248.2
$48N350897: C137.1 Q2.1 R250.2 R255.2
$48N350898: Q2.3 R256.2
$48N350899: C136.1 Q3.1 R248.1 R249.1 R256.1
$48N361351: R167.1 U17.8
$48N361353: R173.2 U17.2
$48N361355: R171.2 U17.3
$48N361356: R180.1 U17.12
$48N361357: R181.1 U17.13
$48N361360: R170.2 U17.5
$48N361361: R72.2 U17.4
$48N361364: R175.1 U17.10
$48N361367: R219.1 U17.11
$49N882: R1604.1 U1603.6
$49N883: R1608.1 U1603.7
$49N884: R1603.2 U1603.1
$49N885: C1602.1 LB1601.1 R1605.2 R1606.1 R1608.2
$49N886: C1601.2 LB1602.1 R1604.2 R1605.1 R1607.2
$49N888: R1602.2 U1603.2 U1603.3
$49N2995: C1604.2 C1647.2 LB1610.1 U1601.16
$49N2996: C1612.1 U1601.2
$49N2997: C1613.1 R1645.2 R1646.2 U1601.6
$49N2998: C1605.1 U1601.3
$49N2999: C1614.1 U1601.5
$49N3000: R1615.1 U1601.14
$49N3001: R113.1 R1646.1 U1601.13
$49N3003: C1606.2 LB1603.1 R1615.2
$49N3004: C1607.2 LB1604.1 R113.2
$49N3011: R1623.1 U1602.10
$49N3012: R1624.1 U1602.9
$49N3013: R1618.1 U1602.12
$49N3014: R1617.1 U1602.11
$49N3015: R1625.2 U1602.2
$49N3016: R1626.2 U1602.3
$49N3017: R1627.2 U1602.4
$49N3019: C1609.1 LB1608.1 R1613.2 R1621.2 R1623.2
$49N3020: C1608.1 LB1607.1 R1613.1 R1622.1 R1624.2
$49N3021: C1611.1 LB1606.1 R1612.2 R1618.2 R1619.1
$49N3022: C1610.1 LB1605.1 R1612.1 R1617.2 R1620.2
$49N3024: R1628.1 U1602.13
$49N3026: R1614.2 U1601.12
$49N3027: C1614.2 U1601.4
$49N3028: C1605.2 U1601.1
$49N16304: C1620.2 C1621.2 C1622.2 C1623.2 C1624.2 C1625.2 C1626.2 T1601.1 T1601.4 T1601.7 T1601.10
$49N44760: C1627.1 R1631.2
$49N114414: R1641.2 U1604.8
$49N114415: R1640.1 U1604.4
$49N129020: C1644.2 R1649.2 R1650.2
$49N138534: R1643.2 U1601.10
$49N141022: R1645.1 U1601.8
$49N175637: C1629.1 J1601.24 R1630.1
$49N175638: C1628.1 J1601.22 R1629.1
$49N191454: C163.2 C1639.1 LB10.2 U1604.5
$50N3043: C1701.1 Q1701.1 R1701.2
$50N3048: D1701.1 K1701.8 Q1701.3
$50N3052: C1702.1 D1701.3 K1701.1 LB1701.2
$50N3713: R1704.2 U12.2
$50N3720: R1705.2 U7.2
$50N3727: D1702.3 LB1702.1
$50N4340: R1706.2 U8.2
$50N4347: R1707.2 U2.2
$50N21517: C1707.1 Q1702.1 R1708.2
$50N21522: D1723.1 K1702.8 Q1702.3
$50N21526: C1708.1 D1723.3 K1702.1 LB1703.2
$50N22342: C1709.1 Q1703.1 R1711.2
$50N22347: D1724.1 K1703.8 Q1703.3
$50N22351: C1710.1 D1724.3 K1703.1 LB1704.2
$50N23194: C1711.1 Q1704.1 R1714.2
$50N23199: D1725.1 K1704.8 Q1704.3
$50N23203: C1712.1 D1725.3 K1704.1 LB1705.2
$51N3749: R2806.1 U2801.2
$51N3750: R2804.1 U2801.7
$51N3751: R2830.1 U2801.3
$51N3757: R225.2 R2801.1 TP1.1
$51N24526: R226.2 R2802.1 TP2.1
$51N56983: C2804.1 LB2801.2 R2811.2
$51N107406: R2812.2 U3.P11
$51N107414: R2813.2 U3.N11
$51N178691: R2832.1 U3.R14
$51N179012: R2834.1 U3.R12
$51N179013: R2835.1 U3.R13
$51N179014: R2836.1 U3.R11
$51N189941: R2853.2 U3.C4
$51N189942: R2854.2 U3.C3
$51N189943: R2855.2 U3.D6
$51N189944: R2856.2 U3.D5
$51N189945: R2857.2 U3.K15
$51N189946: R2858.2 U3.B7
$51N189947: R2859.2 U3.A7
$51N189948: R2860.2 U3.B11
$51N189949: R2861.2 U3.C11
$51N189950: R2862.2 U3.D11
$51N189951: R2863.2 U3.A10
$51N189952: R2864.2 U3.B10
$51N189953: R2865.2 U3.C10
$51N189954: R2866.2 U3.D10
$51N190892: R2867.1 U3.B6
$51N190893: R2872.1 U3.B5
$51N190894: R2870.1 U3.A5
$51N190895: R2871.1 U3.A4
$51N190896: R2868.1 U3.A3
$51N190897: R2869.1 U3.A6
$51N190904: R2873.2 U3.B3
$51N190905: R2874.2 U3.B4
$51N218764: R2882.2 U2804.2
$51N218765: R2881.2 U2804.1
$51N218772: R2884.2 U2803.1
$51N218773: R2883.2 U2803.2
$51N218779: R2885.2 U2805.2
$51N218780: R2886.2 U2805.1
$51N221791: R123.2 U3.C5
$51N221836: R120.2 U3.C6
$51N230666: R2833.1 U3.G1
$51N230667: R2827.1 U3.G2
$51N230670: R2831.1 U3.N3
$51N231127: R2844.1 U3.L2
$51N231129: R2845.1 U3.A14
$51N231131: R2847.1 U3.M15
$51N231578: R2840.1 U3.F2
$51N231581: R2838.1 U3.F1
$51N231582: R2837.1 U3.L1
$51N234739: R2848.1 U3.P14
$51N234742: R2843.1 U3.N12
$51N234743: R2846.1 U3.P15
$51N235080: R2842.1 U3.P13
$51N235403: R2841.1 U3.N13
$51N235404: R2839.1 U3.N14
$51N243463: R65.2 U3.C8
$51N243466: R66.2 U3.R4
$51N249168: R203.1 U3.A13
$51N251938: R126.2 U3.B9
$51N251939: R125.2 U3.C9
$51N262712: R268.2 U3.B12
$51N262713: R269.2 U3.A12
$51N262907: R270.2 U3.C12
$51N266287: R2878.2 U3.E12
$51N266288: R2875.2 U3.F12
$51N266290: R2876.1 U3.E13
$51N266291: C25.1 C26.1 C27.1 C28.1 C29.1 C30.1 C31.1 R2826.1 U3.E6 U3.E7 U3.F5 U3.G5 U3.H5 U3.K11 U3.L11
$51N266293: R2879.2 U3.D2
$51N267635: R271.2 U3.D4
$51N267689: R272.2 U3.D3
$51N275573: R76.1 TP5.1
$51N275625: R29.1 TP3.1
$51N277380: R225.1 R2808.1 TP23.1
$51N277381: R226.1 R2807.1 TP24.1
$52N3046: J803.52 R829.1 R832.1
$52N3047: J803.54 R830.1 R833.1
$52N43522: D801.2 R848.2
$52N52006: J803.50 R851.1 R852.1
$52N58402: C810.2 J803.47
$52N58403: C811.2 J803.49
$52N66878: J803.6 R850.1
$52N80474: C802.1 Q801.1 R821.2 R822.2
$52N90661: J803.31 R230.2
$52N90662: J803.29 R231.2
$52N90958: J803.37 R232.2
$52N90959: J803.35 R233.2
$53N3925: C901.2 J901.A5
$53N3926: C913.2 J901.A4
$53N3927: C915.2 J901.B5
$53N3928: C916.2 J901.B4
$53N4325: C83.1 J901.C5
$53N4326: C94.1 J901.C4
$53N4327: C95.1 J901.D5
$53N4328: C96.1 J901.D4
$55N2035: R1401.1 U6.40
$55N9367: C1440.1 R1405.2 R1406.1 U1401.4
$55N9368: L1401.1 U1401.6
$55N9369: C1434.2 U1401.3
$55N9370: C1438.2 R1407.1 R1408.2 U1401.1
$55N9373: C1438.1 R1402.1 R1407.2
$59N2622: C1501.2 C1502.2 C1503.2 C1504.2 C1505.2 C1506.2 C1507.2 T1501.1 T1501.4 T1501.7 T1501.10
$59N14331: C1509.2 C1510.2 C1511.2 C1512.2 C1513.2 C1514.2 C1515.2 T1502.1 T1502.4 T1502.7 T1502.10
$59N15275: C1516.2 C1517.2 C1518.2 C1519.2 C1520.2 C1521.2 C1522.2 T1503.1 T1503.4 T1503.7 T1503.10
$59N16235: C1523.2 C1524.2 C1525.2 C1526.2 C1527.2 C1528.2 C1529.2 T1504.1 T1504.4 T1504.7 T1504.10
$59N71921: C1508.1 R1509.2
$59N72965: C1538.1 R1510.2
$59N73577: C1539.1 R1511.2
$59N73961: C1540.1 R1512.2
$59N94279: C1532.1 J1501.18 R1503.1
$59N94285: C1533.1 J1501.20 R1504.1
$59N94881: C1530.1 J1501.24 R1501.1
$59N94883: C1531.1 J1501.22 R1502.1
$59N95912: C1536.1 J1502.22 R1507.1
$59N95918: C1537.1 J1502.24 R1508.1
$59N96488: C1534.1 J1502.18 R1505.1
$59N96493: C1535.1 J1502.20 R1506.1
$60N1213: C3312.1 Q3302.1 R3303.2
$60N1214: Q3304.3 R3308.1 R3309.2
$60N1215: C3304.1 Q3304.1 R3305.2 R3306.1
$60N1222: Q3302.3 R3301.2 R3302.2
$60N1223: C3301.1 Q3301.4 R3301.1 R3304.1
$60N1224: C3303.1 R3304.2
$60N1225: C110.1 R75.2
$60N1226: C3315.1 Q3303.4 R75.1 R3309.1
$60N1227: C3301.2 F3302.2 Q3301.1 Q3301.2 Q3301.3 R3302.1
$60N1228: C3315.2 F3301.2 Q3303.1 Q3303.2 Q3303.3 R3308.2
$61N1194: R1002.1 R1003.1 R1004.2
$61N1196: R1006.1 R1007.2 U11.23
$61N1197: R1007.1 U11.35
$61N1198: R1003.2 R1004.1 U11.16
$61N1203: C1001.1 Q1003.1 R1015.2
$61N1204: Q1003.3 R1009.1 R1012.2
$61N1210: R1008.2 R1011.1
$61N1212: C1002.1 Q1004.1 R1009.2
$61N3534: R1017.1 R1021.2 U5.7
$61N3535: C1013.1 C1014.1 R1019.1 R1020.2 U1001.1
$61N3537: R1018.2 U5.5
$61N3538: R1021.1 U5.6
$61N11152: C48.1 C49.1 C50.1 C51.1 C82.1 C1008.1 C1009.1 C1010.1 F1001.2 R1005.2 U11.17 U11.18 U11.19 U11.20 U11.21
$61N12065: R1028.1 U1002.23
$61N12066: R1029.1 U1002.22
$61N12078: R1022.1 U1002.18
$61N12079: R1024.1 U1002.17
$61N12080: R1023.1 U1002.16
$61N12081: R1026.1 U1002.15
$61N12082: R1025.1 U1002.14
$61N12083: R1027.1 U1002.13
$61N12094: R1036.1 U1002.19
$61N14206: R2849.1 U1002.5
$61N14207: R2850.2 U1002.6
$61N14208: R2851.2 U1002.7
$61N14209: R2852.2 U1002.8
$61N15063: R73.1 U1002.4
$61N18483: R259.2 U1002.9
$61N18484: R260.2 U1002.10
$61N18485: R261.2 U1002.11
$61N21443: R58.1 U1002.20
$62N1670: Q1102.4 R1103.2 R1107.1
$62N1671: C1105.1 Q1105.1 R1104.2
$62N1672: Q1103.4 R1101.2 R1111.2
$62N1673: Q1101.4 R1108.2 R1110.2
$62N1674: C1103.2 R1110.1
$62N1675: C1104.2 R1111.1
$62N1681: C1101.1 R1109.2
$62N1682: C1102.1 R1107.2
$62N1688: Q1104.4 R1102.2 R1109.1
$62N1689: C1106.1 Q1106.1 R1116.2
$62N1690: C1108.1 Q1107.1 R1119.2
$62N1691: Q1107.3 R1115.1 R1116.1 R1118.1
$63N1348: R3001.1 R3006.1 U3001.10
$63N1354: R3022.2 U3001.1
$63N1355: R3020.1 R3021.2
$63N1356: C3006.1 C3008.2
$63N1357: D3001.2 F3001.2
$63N1358: C3007.1 R3004.1 R3005.1
$63N1361: C3002.1 C3009.1 U3001.4
$63N1362: C3011.1 R3020.2 U3001.3
$63N1363: C3003.2 R3007.1
$63N1364: C3005.1 R3002.1 R3008.2 U3001.6
$63N1366: Q3001.4 R3009.2
$63N1373: C3004.2 R3003.1 R3010.2 U3001.2
$63N6227: R3015.2 U3002.2
$63N6228: R3014.2 U3002.1
$63N6229: R3017.2 U3002.5
$63N6230: C3014.1 R3012.2 U3002.10
$63N6231: C3014.2 R3011.1 U3002.9
$63N6232: R3016.2 U3002.4
$63N6233: C3015.1 R3013.1 U3002.8
$63N6234: C3012.1 C3013.1 LB3001.1 U3002.6
$63N33494: C38.2 R86.1 U3001.8
$63N39199: C81.1 C3010.2
$63N39814: C3001.2 R132.1
$64N2060: R2101.2 U2101.1
$64N79526: C79.1 Q2101.3 R88.1
$64N90990: R189.2 U2101.40
$64N121818: C121.1 R223.2 R224.2 X2.3
$64N121819: C122.1 R206.2 R222.2 R224.1 X2.1
$64N128273: R207.2 R221.2 X2.4
$64N151332: R337.2 U2101.10 U2101.16 U2101.28
$65N2030: C3601.1 LED3602.4 R3601.2
$65N2031: C3602.1 LED3602.3 R3602.2
$65N2032: C3603.1 LB3601.1 LED3602.1 LED3602.2
$65N2035: C3604.1 Q3601.1 R3605.2
$65N2036: C3605.1 Q3602.1 R3606.2
$65N3589: D3601.1 R3607.2 R3620.1 S3601.2
$65N5635: C3607.1 LED3601.3 R3609.2
$65N5639: LED3601.4 R3608.2
$65N6291: D3602.1 R3613.2 R3621.1 S3602.2
$65N14395: C3611.1 LED3603.4 R3614.2
$65N14396: C3612.1 LED3603.3 R3615.2
$65N14399: C3614.1 Q3605.1 R3618.2
$65N14400: C3615.1 Q3606.1 R3619.2
$65N14401: C3613.1 LB3603.1 LED3603.1 LED3603.2
$65N31335: C3610.1 Q3604.1 R3611.2
$66N179178: R2921.1 U2904.10
$66N179179: R2922.2 U2904.14
$66N179181: R2923.2 U2903.14
$66N179183: R2931.2 U2904.18
$66N179184: R2930.2 U2904.19
$66N179185: R2929.2 U2904.20
$66N179186: R2928.2 U2904.21
$66N179206: R2934.2 U2903.18
$66N179207: R2935.2 U2903.19
$66N179210: R2936.2 U2903.20
$66N179211: R2937.2 U2903.21
$66N179213: R2938.1 U2903.6
$66N179214: R2939.1 U2903.5
$66N179215: R2940.1 U2903.4
$66N179216: R2941.1 U2903.3
$66N179223: R2932.2 U2903.2
$66N179232: R2942.2 U2904.2
$66N179233: R2948.2 U2904.15
$66N179234: R2949.2 U2903.15
$66N179235: R2946.2 U2904.16
$66N179236: R2947.2 U2903.16
$66N179237: R2945.2 U2903.17
$66N179250: R2952.1 U2904.9
$66N179251: R2956.1 U2903.10
$66N179252: R2954.1 U2903.8
$66N179253: R2955.1 U2903.9
$66N179254: R2953.1 U2903.7
$66N182594: C2921.1 Q2901.1 R2985.2
$66N182597: Q2901.3 R198.1 R199.1 R2983.1 R2984.1 R2988.1
$66N371722: R67.1 U16.10
$66N371723: R68.2 U16.14
$66N371725: R69.2 U15.14
$66N371727: R103.2 U16.18
$66N371729: R71.2 U16.20
$66N371730: R70.2 U16.21
$66N371746: R115.2 U15.18
$66N371747: R116.2 U15.19
$66N371750: R119.2 U15.20
$66N371751: R122.2 U15.21
$66N371753: R124.1 U15.6
$66N371754: R138.1 U15.5
$66N371755: R139.1 U15.4
$66N371756: R140.1 U15.3
$66N371763: R107.2 U15.2
$66N371772: R141.2 U16.2
$66N371773: R148.2 U16.15
$66N371774: R157.2 U15.15
$66N371775: R146.2 U16.16
$66N371776: R147.2 U15.16
$66N371777: R145.2 U15.17
$66N371787: R158.1 U16.9
$66N371788: R164.1 U15.10
$66N371789: R160.1 U15.8
$66N371790: R161.1 U15.9
$66N371796: R159.1 U15.7
$66N371797: R166.1 U16.7
$66N380792: R205.1 U16.8
$66N381197: R218.1 U16.6
$66N382007: R220.1 U16.4
$66N382412: R237.1 U16.3
$66N382709: R274.2 U2904.17
$66N382710: R275.1 U2904.7
$66N465451: R288.2 U16.19
$66N465452: R290.1 U16.5
$67N1252: C3510.1 Q3502.1 R3505.2 R3506.1
$67N1255: C3506.1 Q3501.4 R3502.1 R3504.1
$67N1256: Q3502.3 R3503.2 R3504.2
$67N1257: C3506.2 F3501.2 Q3501.1 Q3501.2 Q3501.3 R3503.1
$67N25225: C3523.1 Q3503.1 R3539.2 R3540.1
$67N25227: C3518.1 R3536.2
$67N25228: C3520.1 Q3504.4 R3536.1 R3538.1
$67N25229: Q3503.3 R3537.2 R3538.2
$67N25230: C3520.2 F3502.2 Q3504.1 Q3504.2 Q3504.3 R3537.1
$67N65911: C3502.1 R3502.2
$71N1685: R3201.2 U1.22
$71N1693: R3222.1 U1.16
$71N1694: J1.1 R3223.2 U1.11 U1.15
$71N1695: R3222.2 R3223.1
$71N10807: C3213.2 Q3201.1 R3205.2
$71N10810: C3214.2 Q3202.4 R1.1 R3203.1 R3204.2
$71N10812: Q3201.3 R3203.2
$71N22877: R3217.1 U5.1 U5.2
$71N22878: R3218.2 R3220.2 U5.3
$71N22879: R3218.1 R3219.2
$71N29605: C109.1 R1.2
$71N32366: C3222.1 R3208.1 R3214.1 U3201.3
$71N32367: C3215.1 U3201.13
$71N32368: C3224.1 R3213.1 U3201.14
$71N36219: C3222.2 R3208.2 R3211.1
$71N37634: D15.3 U3202.1
$73N2320: R3404.2 R3419.1 U10.7
$73N2325: C3403.2 D3401.2 R3401.2 R3409.1 R3411.1 R3416.1 U3402.4
$73N2326: R3405.2 R3426.1 U10.3
$73N2329: R3406.1 U3402.1
$73N2330: R3401.1 R3407.2
$73N2331: D3401.1 R3410.1 U3402.7
$73N2332: Q3401.1 Q3402.3 R3412.2
$73N2333: C3401.1 Q3402.1 R3413.2
$73N2338: R3409.2 R3415.1
$73N2339: R3414.1 R3415.2
$73N4160: D3402.1 R3422.2 R3425.1 S3401.2
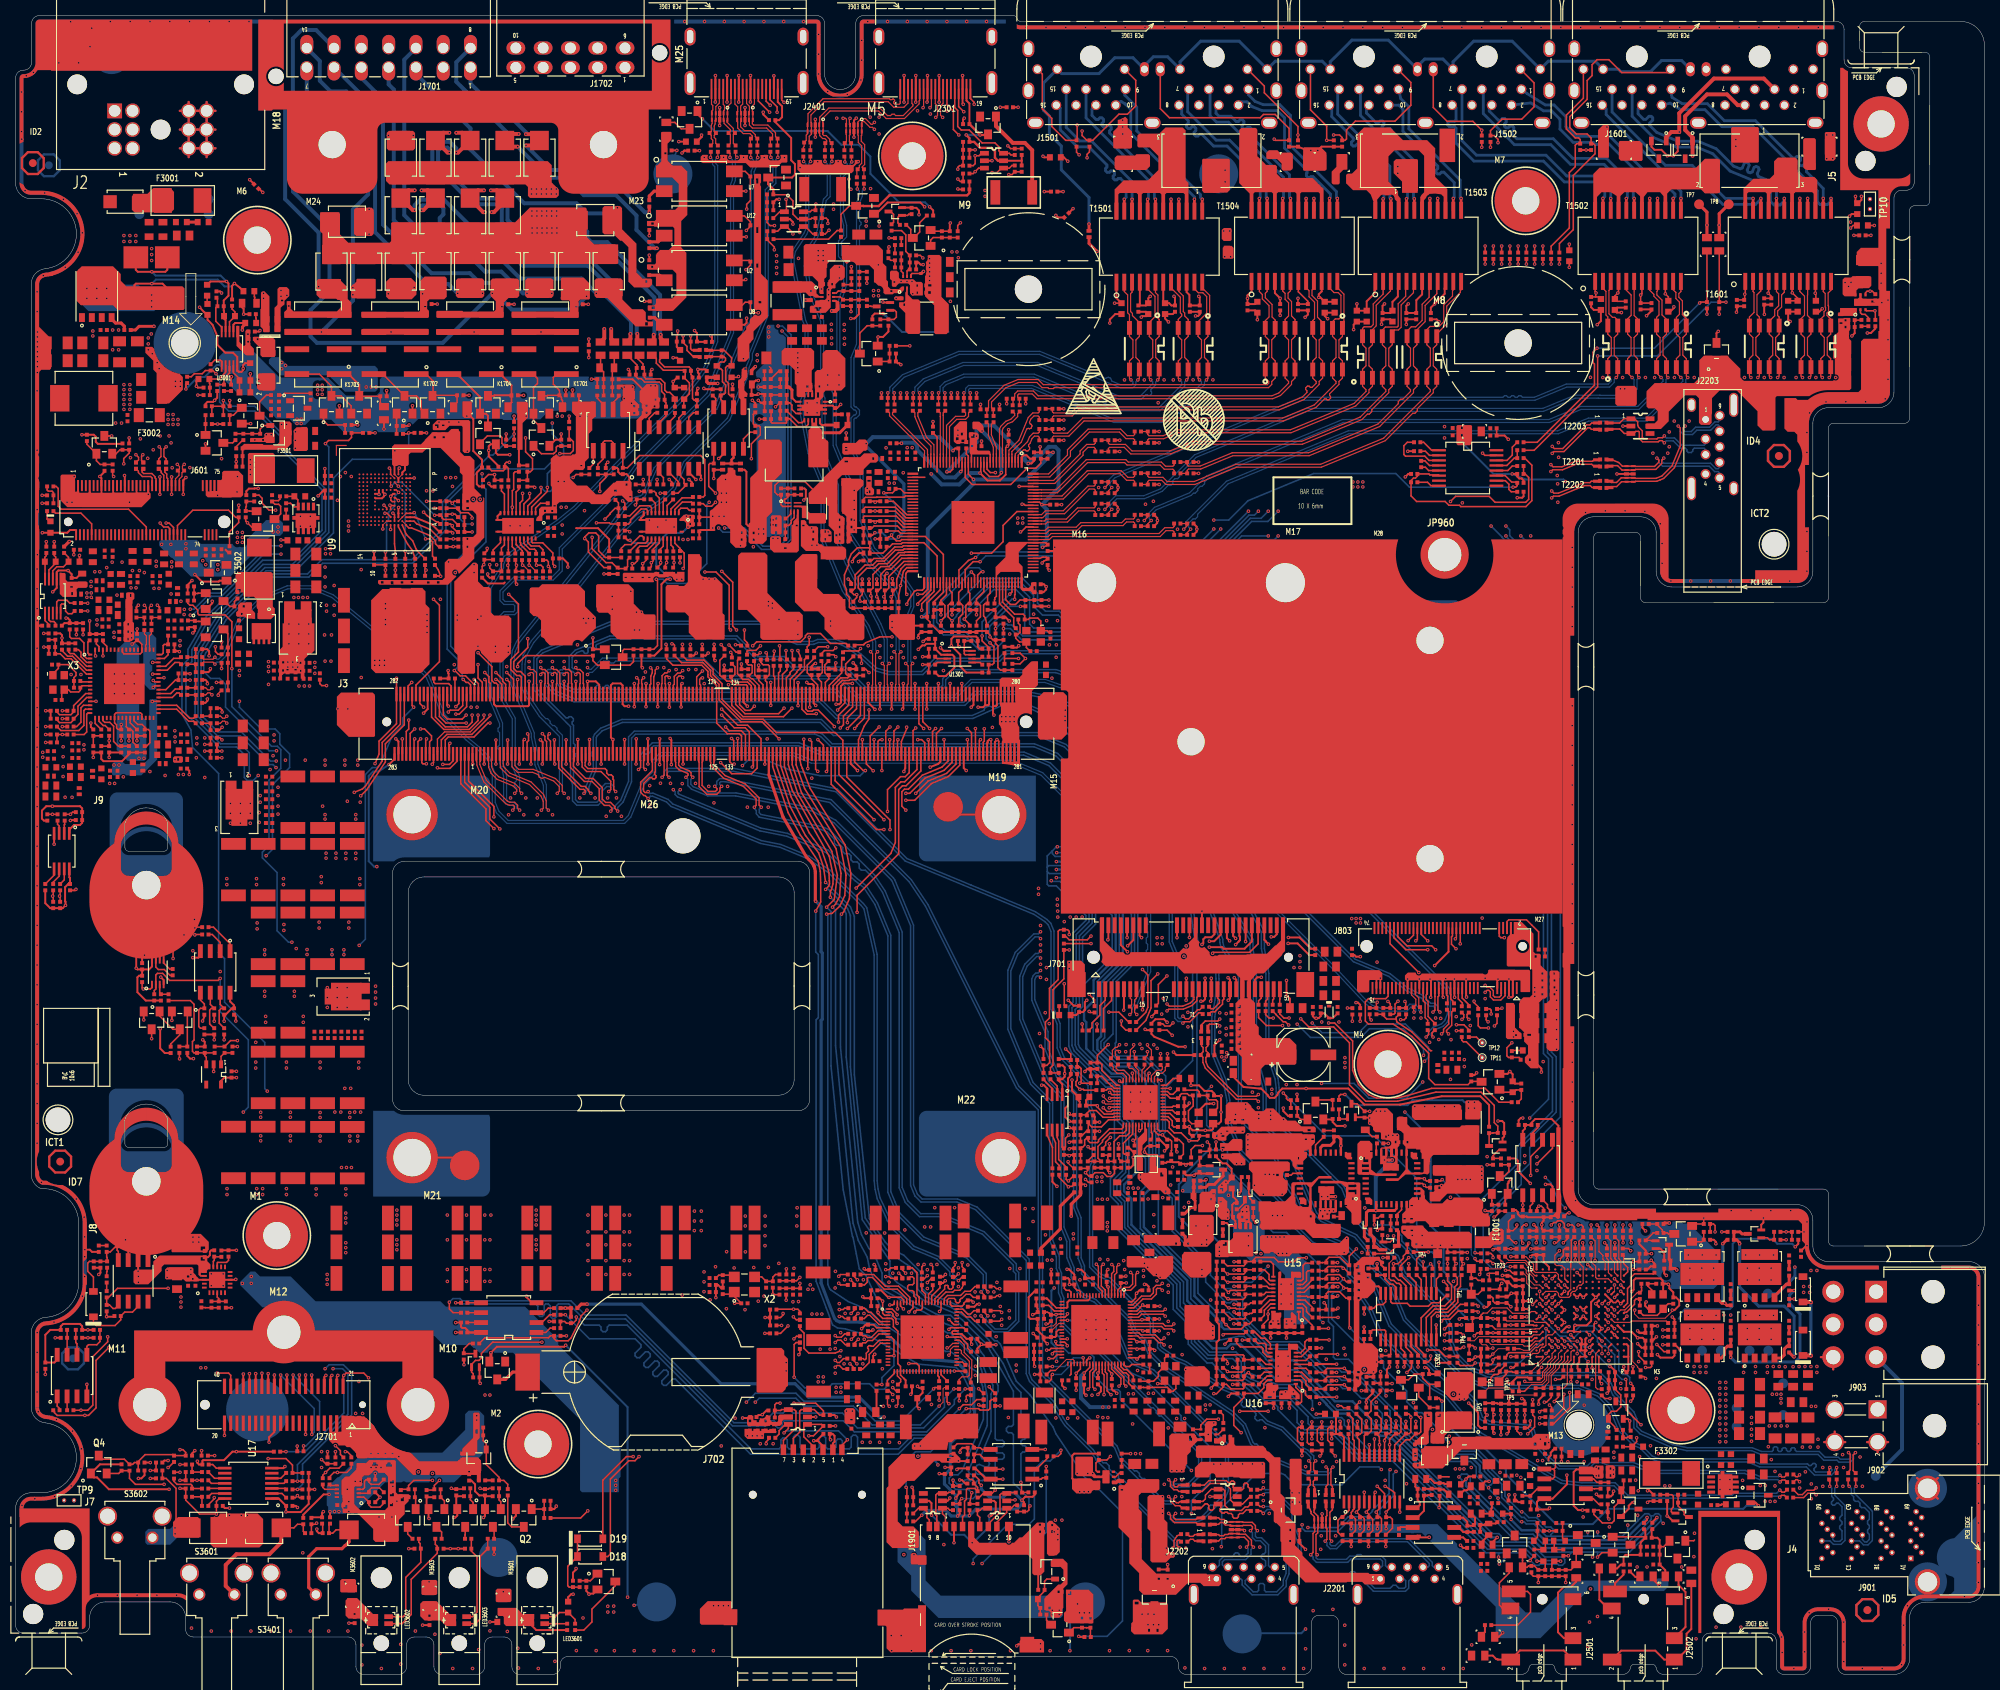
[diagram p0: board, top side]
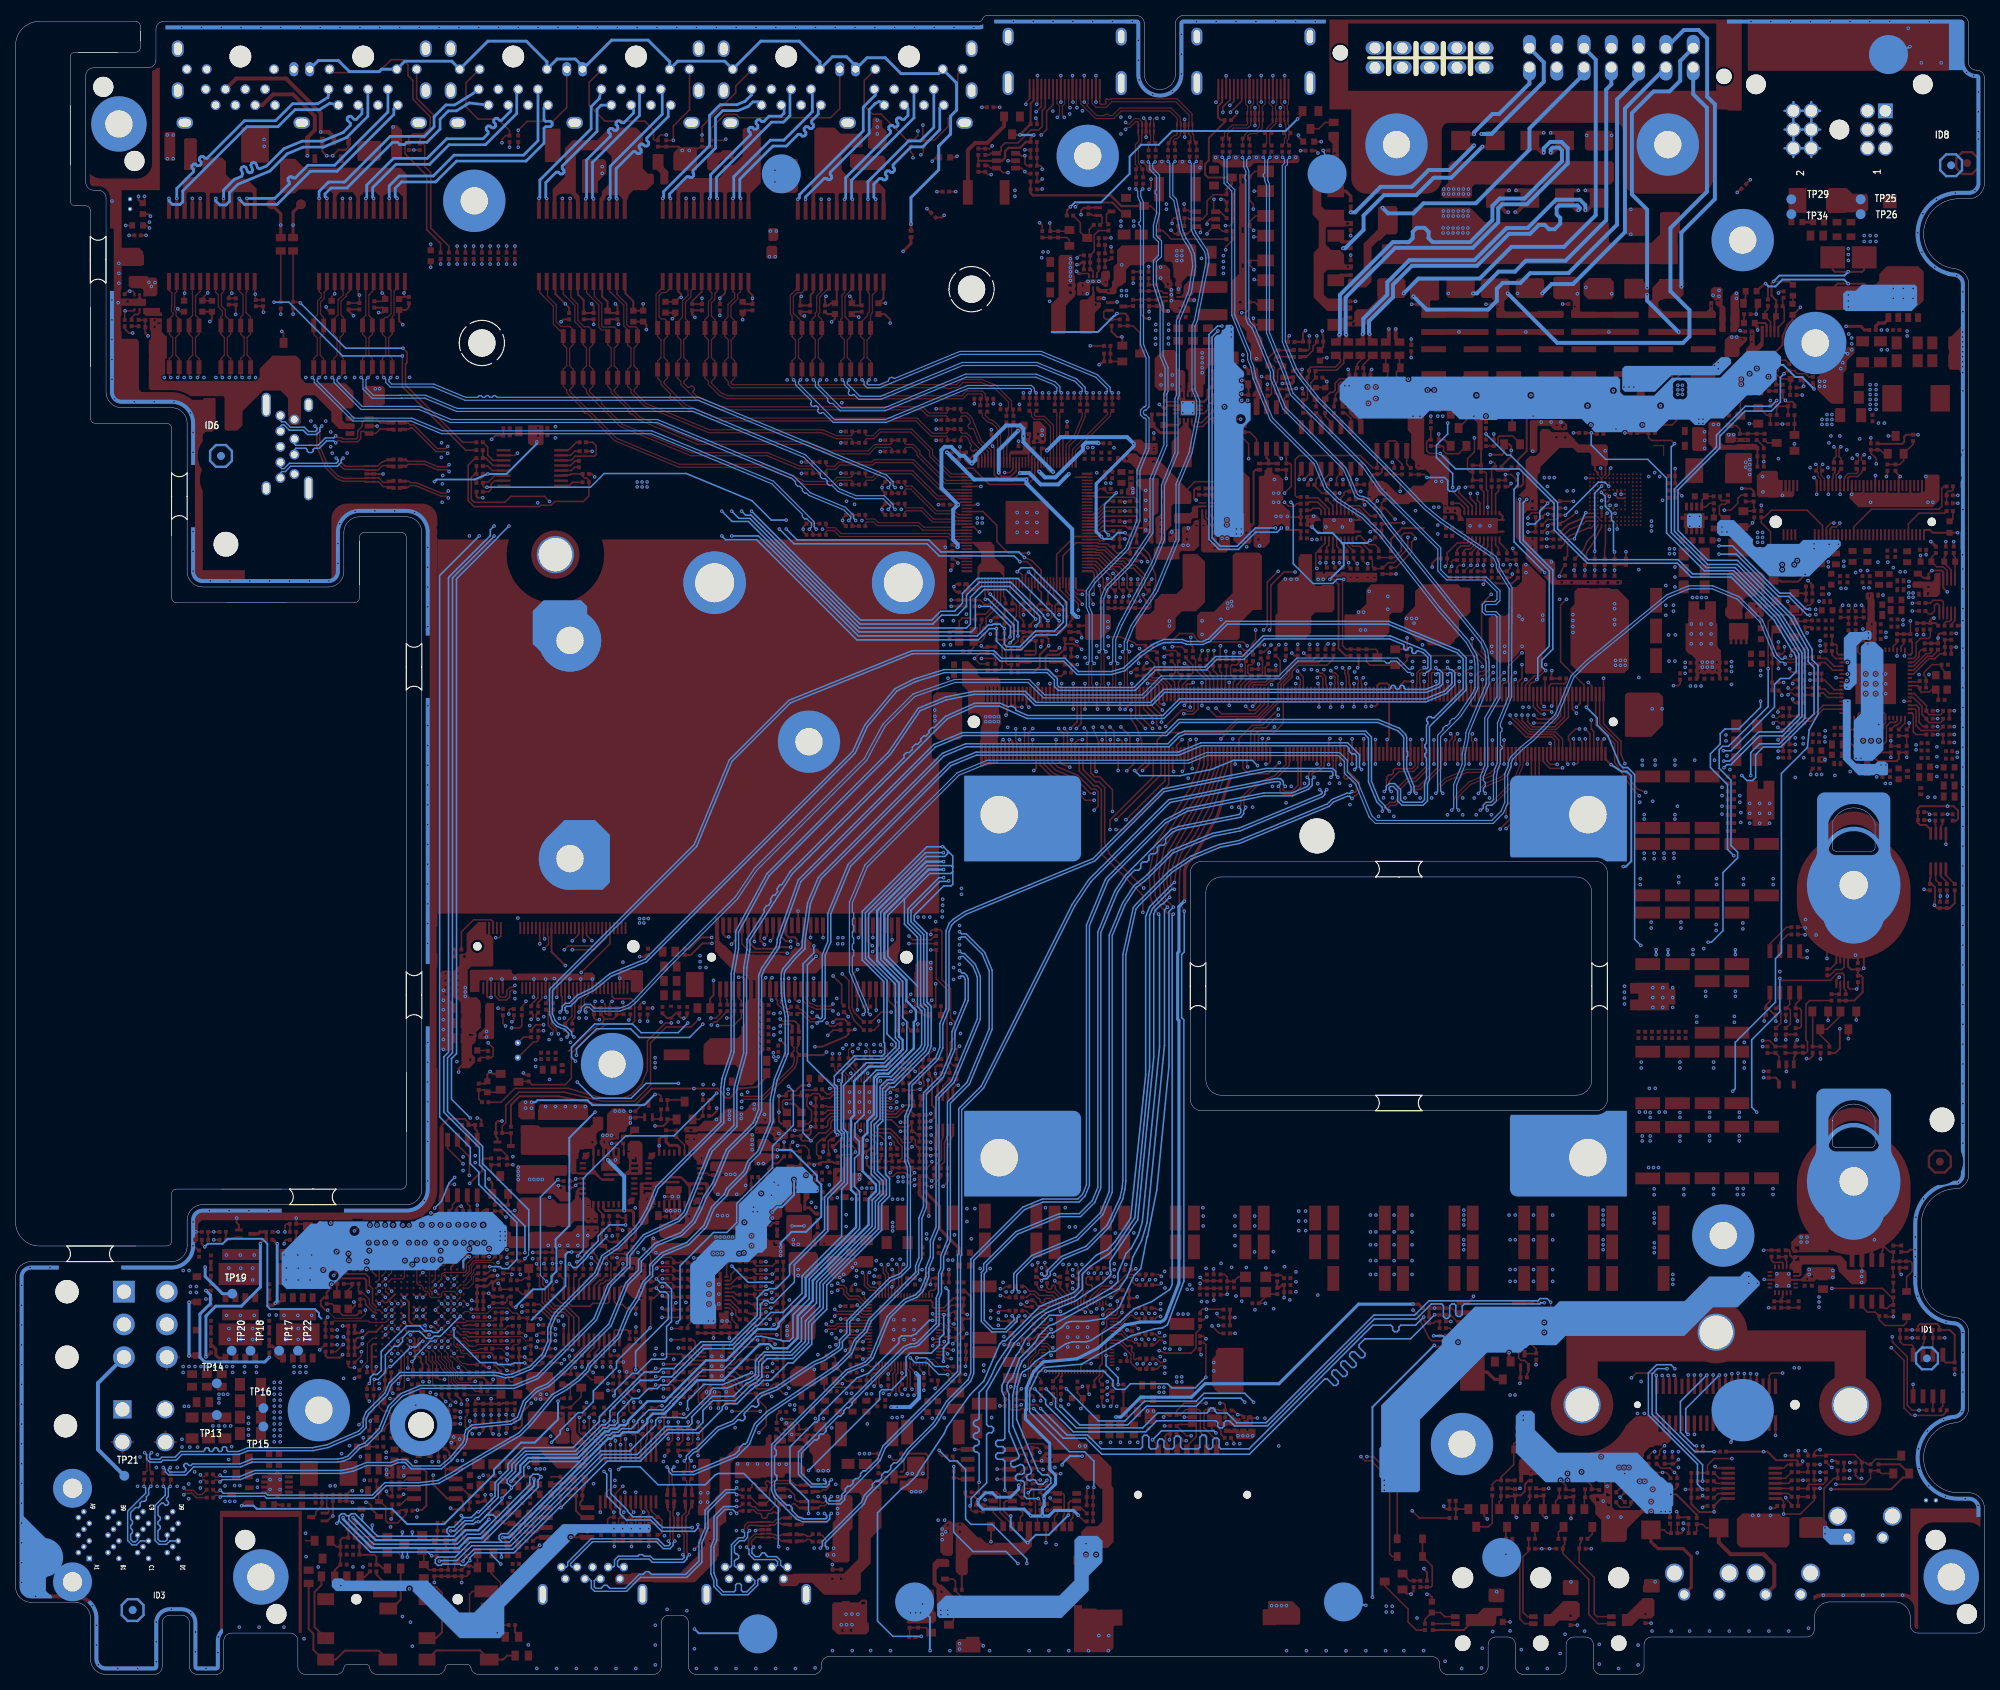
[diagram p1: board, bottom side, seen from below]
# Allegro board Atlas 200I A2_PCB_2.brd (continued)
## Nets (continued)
Pads without a net: D2 3; D15 1; D16 3; D17 3; D1701 2; D1702 2; D1723 2; D1724 2; D1725 2; D2307 2; D2407 2; D2408 2; D2501 3; D2502 3; D2503 3; D2504 3; ID1 1; ID2 1; ID3 1; ID4 1; ID5 1; ID6 1; ID7 1; ID8 1; J3 33 35 62 63 64 65 68 69 70 71 74 75 76 77 80 81 82 83 110 111 112 113 114 115 120 121 122 124 126 127 128 129 130 131 132 179 236 238 242 244 248 250 254 256 260 262 296; J4 1; J5 1; J7 1; J601 5 6 7 8 11 13 17 19 20 22 23 24 25 26 28 29 30 31 32 34 35 36 37 40 42 44 46 48 56 58 59 60 61 62 63 64 65 66 67 68; J701 1 6 7 16 17 19 20 28 48; J702 6; J803 1 8 12 13 14 15 16 17 18 19 20 21 22 23 24 25 26 28 38 40 42 44 46 48 56 58 59 60 61 63 65 68 69 75; J901 A1 A2 A7 A8 B1 B2 B7 B8 C1 C2 C7 C8 D1 D2 D7 D8; J1601 1 2 7 8 17 18 19 20; J2203 12 13; J2301 14; J2401 14; J2501 6; J2502 6; J2701 4 5 8 9 10 11 13 14 15 16 17 18 19 25 38 40; K1701 2 7; K1702 2 7; K1703 2 7; K1704 2 7; NOREF#2 1; NOREF#3 1; NOREF#5 1; NOREF#13 1; NOREF#15 1; NOREF#16 1; NOREF#19 1; NOREF#21 1; NOREF#22 1; NOREF#30 1; RV1502 2; U1 5 6 7 8 9 10 25 26 27 28 30; U3 A2 A9 B2 B8 B15 C13 C14 D8 D13 D15 E14 E15 F14 F15 G12 G13 G14 G15 H12 H13 H15 J12 J13 J14 J15 K12 K13 K14 L12 L13 L14 L15 M1 M2 M3 M4 M13 M14 N1 N2 N4 P1 P5 R2 R6; U6 15 16 22 35 37 38 41 42 43 44 45 74 75 80 83 85 87 92 95 97 98 99 100 102 103 104 105 117; U9 A1 A7 A9 A10 A11 A12 A13 A14 B8 B9 B10 B11 B12 B13 B14 C7 C8 C9 C10 C11 C12 C13 C14 D3 D12 D13 D14 E1 E2 E3 E5 E8 E9 E10 E12 E13 E14 F1 F2 F3 F10 F12 F13 F14 G1 G2 G3 G10 G12 G13 G14 H1 H2 H3 H12 H13 H14 J1 J2 J3 J12 J13 J14 K1 K2 K3 K6 K7 K10 K12 K13 K14 L1 L2 L3 L12 L13 L14 M1 M2 M3 M7 M8 M9 M10 M11 M12 M13 M14 N3 N6 N7 N8 N9 N10 N11 N12 N13 N14 P1 P2 P7 P8 P9 P10 P11 P12 P13 P14; U11 5 6 7 8 9 10 25 26 27 28 30; U16 17; U17 6 9; U301 20 21 28 55 56; U1001 3; U1002 1; U1201 33 42 43 44; U1601 7 9; U1602 1 8; U1902 4; U2002 10 11 13 14 16 17 19 28 30 31 42 59 60 62 63; U2101 14 15 17 18 23 24 26 27 29 30 32 33 36 37 38 39 41 42 43; U2201 3; U2202 3; U2205 5; U2206 4 6; U2701 7; U2703 1; U2802 3; U2803 3; U2804 3; U2805 3; U3002 3; U3101 14; U3201 2 4 5 6 7 9 10 11 12; U3401 4; U3402 6 8

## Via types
v1: diameter 0.457, hole 0.203, TOP to BOTTOM, 4335 vias

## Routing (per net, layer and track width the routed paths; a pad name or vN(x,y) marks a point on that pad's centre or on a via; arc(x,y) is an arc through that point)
3V3_PWR_EN: length 36.4
  TOP w0.203: v1(159.03,57.99) 158.72,58.29 R3206.2 R3205.1 ; R2849.2 178.15,39.54 v1(178.05,39.44)
  ART03 w0.178: v1(159.03,57.99) 161.47,57.99 163.53,55.93 163.53,50.85 164.62,49.76 164.62,44.09 167.3,41.41 168.28,41.41 169.18,42.3 172.08,42.3 173.44,40.94 176.55,40.94 v1(178.05,39.44)
AGND_AUDIO: length 1399.2
  TOP w0.178: 54.1,118.45 54.1,119.99 55.02,120.91 58.31,120.91 60.07,122.66 v1(60.07,123.06)
  TOP w0.203: 215.32,17.25 215.21,17.14 D2504.1 ; D2503.2 203.45,15.62 v1(202.88,15.05) ; C2504.2 194.65,12.6 194.4,12.85 C2502.2 ; C2504.2 R2509.1 R2508.1 C2503.2 C2501.2 v1(198.8,11.79) ; C2504.2 v1(195.29,11.79) ; C2508.1 v1(199.14,15.21) ; R2515.2 183.82,25.35 183.83,25.34 ; J3.302 53.85,122.81 55.1,121.55 57.94,121.55 58.55,122.16 v1(58.55,123.06) ; C2505.1 194.23,14.68 v1(194.23,14.6) ; 54.1,118.45 J3.305
  TOP w0.254: v1(181.29,17.59) 181.28,17.58 U4.4 ; v1(182.56,21.4) 182.63,21.46 C2519.2
  ART03 w0.152: 77.72,123.19 75.69,121.15 63.47,121.15 62.97,120.65 61.21,120.65
  ART03 w0.203: 81.71,134.72 81.71,134.04 79.6,131.93 78.71,131.93 ; 81.71,134.72 79.43,134.72 78.71,134.01 78.71,131.93 ; 81.71,134.72 82.4,134.72 83.49,135.81 92.15,135.81 97.24,140.91 103.82,140.91 105.18,142.26 108.3,142.26 108.99,142.95 114.79,142.95 115.48,142.26 120.8,136.94 120.8,134.53 132.1,123.24 132.1,121.69 132.1,108.67 130.89,107.45 130.89,104.2 132.35,102.74 134.01,102.74 ; 78.71,131.93 78.71,130.82 76.58,128.68 76.58,123.74 74.91,122.07 63.01,122.07 62.61,121.67 ; 134.01,102.74 134.01,103.48 133.73,103.76 132.74,103.76 131.8,104.7 131.8,107.07 133.02,108.29 133.02,122.07 133.02,125.23 127.64,130.6 127.64,131.52 125.2,133.96 125.2,134.65 123.17,136.68 122.41,136.68 115.23,143.87 105.48,143.87 103.44,141.82 96.86,141.82 96.25,141.21 91.77,136.73 83.11,136.73 82.07,135.69 79.1,135.69 77.8,134.39 77.8,130.98 75.69,128.87 75.69,124.21 74.31,122.83 62.63,122.83 ; 134.01,102.74 134.01,102.01 133.34,101.34 131.91,101.34 129.67,103.58 129.67,108.21 130.88,109.43 130.88,122.73 121.2,132.41 120.17,132.41 117.09,135.49 117.09,138.92 114.29,141.73 109.49,141.73 108.81,141.05 107.8,141.05 105.68,141.05 104.32,139.69 97.74,139.69 92.65,134.59 84.11,134.59 77.72,128.21 77.72,123.19 ; v1(60.07,123.06) 60.6,123.59 73.81,123.59 74.88,124.66 74.88,129.36 76.84,131.32 76.84,134.88 79.6,137.64 91.39,137.64 94.52,140.78 96.48,142.74 103.06,142.74 105.11,144.78 115.61,144.78 122.62,137.77 126.22,137.77 129.11,134.88 129.11,133.59 131.43,130.12 133.93,127.61 133.93,107.89 132.72,106.68 132.72,105.28 133.1,104.9 133.86,104.9 134.11,105.16 134.11,105.66 v1(133.6,106.17) 135.51,108.08 135.51,126.16 134.45,128.72 131.93,131.24 130.05,134.06 130.05,135.09 125.18,139.95 123.06,139.95 116.08,146.94 109.14,146.94 107.95,145.74 104.92,145.74 102.72,143.55 96.14,143.55 94.19,141.59 91.05,138.45 79.26,138.45 75.95,135.14 75.95,131.75 73.99,129.79 73.99,124.92 73.33,124.26 61.67,124.26
  ART04 w0.254: SG1.1 181.1,17.78 v1(181.29,17.59)
  BOTTOM w0.203: 195.07,20.12 v1(195.34,20.38) ; 195.07,20.12 196.29,18.9 196.9,18.9 197.18,18.61 197.18,18.21 196.88,17.91 196.88,17.73 ; 195.07,20.12 194.07,20.12 193.34,20.85 v1(193.17,20.85) 193.02,20.85 191.01,22.86 191.01,24.58 189.36,26.23 189.36,27 187.26,29.1 180.99,29.1 177.62,32.46 177.62,33.06 171.9,38.78 170.06,38.78 169.62,39.23 168.07,39.23 164.62,42.67 160.76,42.67 157.38,46.05 157.38,48.32 156.39,49.31 156.06,49.31 155.88,49.49 154.95,49.49 153.24,51.21 153.24,52.53 148.74,57.02 148.74,61.24 146.63,63.35 146.63,68.75 146.56,68.82 146.56,69.33 147.12,69.89 147.12,75.37 147.5,75.75 147.5,76.76 144.92,79.34 141.36,79.34 141.04,79.66 141.04,80.98 141.15,81.09 141.15,88.88 143.92,91.65 143.92,97.87 135.62,106.17 v1(133.6,106.17) 133.48,106.17 132.97,105.66 ; 138.51,99.51 138.51,96.24 136.84,94.58 136.84,88.31 ; 138.51,99.51 135.27,102.74 132.56,102.74 132.31,103 ; 138.51,99.51 140.63,97.38 140.63,92.1 136.84,88.31 ; 136.84,88.31 136.84,85.67 136.3,85.12 136.3,80.83 136.47,80.42 139.7,77.19 140.21,76.68 141.73,76.68 142.04,76.37 142.04,71.55 142.77,70.81 142.77,64.19 141.71,63.12 141.71,61.78 142.65,60.84 142.65,57.49 149.78,50.35 149.78,47.65 151.71,45.72 151.71,42.77 153.13,41.35 156.52,41.35 157.61,40.26 157.61,38.48 157.73,38.36 158.39,37.92 161.26,36.73 163.07,36.73 163.4,36.39 163.4,36.05 166.49,32.96 166.56,32.96 166.61,32.91 167.01,32.91 167.05,32.96 170.05,32.96 170.41,32.6 170.41,31.99 173.75,28.65 177.47,28.65 189.15,16.97 190.09,16.97 ; 190.09,16.97 192.52,16.97 ; 190.09,16.97 190.5,17.38 190.5,17.78 190.22,18.06 189.4,18.06 180.14,27.32 ; 192.52,16.97 194.19,16.97 195.46,15.7 ; 192.52,16.97 185.48,24.01 185.48,24.96 v1(185.1,25.34) 185.46,25.69 186.14,25.69 186.55,25.28 186.55,24.38 190.86,20.07 ; v1(202.25,15.05) 202.25,15.68 202.24,15.7 ; 192.29,20.21 192.96,19.53 193.12,19.53 ; 192.29,20.21 192.05,20.45 191.24,20.45 190.86,20.07 ; 192.29,20.21 192.29,20.22 190.12,22.4 v1(190.12,22.61) 188.91,23.81 v1(188.91,23.94) 188.91,24.09 ; 132.31,103 132.31,101.36 132.51,101.15 133.46,101.15 137.26,97.35 137.26,96.72 135.62,95.08 135.62,86.24 135.08,85.7 135.08,80.59 135.43,79.73 139.83,75.34 140.39,75.34 140.92,74.8 140.92,64.13 140.41,63.62 140.41,61.35 141.43,60.33 141.43,56.99 148.46,49.95 148.46,46.84 150.39,44.91 150.39,42.37 152.81,39.95 153.44,39.95 155.6,37.79 155.78,37.72 156.59,37.72 157.16,37.15 157.65,36.95 157.68,36.92 157.92,36.68 158.18,36.51 159.97,34.72 161.47,34.72 161.87,34.31 161.87,33.96 164.85,30.99 168.76,30.99 172.38,27.37 176.59,27.37 v1(182.56,21.4) 182.78,21.4 188.58,15.6 190.35,15.6 ; 132.31,103 132.31,103.56 ; 188.91,24.09 188.74,24.09 187.32,25.51 187.32,26.59 186.6,27.32 180.14,27.32 ; 188.91,24.09 189.1,24.28 189.18,24.28 189.46,24.56 189.46,24.96 188.38,26.05 188.38,26.83 186.98,28.23 180.52,28.23 177.13,31.62 176.67,31.62 176.31,31.98 175.62,31.98 175.29,32.31 175.29,33.45 174.02,34.72 174.02,34.82 173.43,35.41 172.59,35.41 171.33,36.67 170.21,36.67 169.77,37.11 168.87,37.11 168.41,37.57 164.19,41.78 160.5,41.78 157.53,44.75 157.33,44.75 155.64,46.44 154.1,46.44 151.64,48.89 151.64,51.11 146.56,56.19 146.56,62.27 145.82,63.01 145.82,69.53 146.3,70.01 146.3,75.55 143.4,78.46 141.09,78.46 139.19,80.36 139.19,81.19 139.67,81.67 139.67,88.56 143.1,91.99 143.1,97.53 135.71,104.93 133.32,104.93 132.97,105.28 132.97,105.66 ; 132.97,105.66 132.31,105 132.31,103.56 ; 209.77,20.35 209.7,20.35 209.43,20.61 208.96,20.61 208.03,19.68 ; 209.77,20.35 210.04,20.35 210.3,20.61 210.7,20.61 210.99,20.33 210.99,19.81 211.05,19.75 ; 209.77,20.35 209.77,19.9 206.58,16.71 195.89,16.71 194.62,17.98 192.95,17.98 190.86,20.07 ; 202.82,15.7 202.24,15.7 ; 202.82,15.7 207,15.7 211.05,19.75 ; 202.82,15.7 202.88,15.63 v1(202.88,15.05) ; 202.24,15.7 199.62,15.7 ; 203.02,17.73 206.08,17.73 206.76,18.41 ; 203.02,17.73 201.57,17.73 ; 203.02,17.73 202.9,17.86 v1(202.9,18.26) ; 196.88,17.73 201.57,17.73 ; 196.88,17.73 196.31,17.73 194.73,19.3 193.74,19.3 193.5,19.53 193.12,19.53 ; 199.62,15.7 v1(199.14,15.21) ; 199.62,15.7 195.46,15.7 ; 132.31,103.56 132.51,103.76 135.59,103.76 141.55,97.8 141.55,91.72 138.71,88.88 138.71,84.23 138.2,83.72 138.2,80.05 140.73,77.52 142.09,77.52 143.68,75.93 143.68,71.79 144.86,70.61 144.86,68.91 144.3,68.35 144.3,66.8 144.91,66.19 144.91,62.59 144.25,61.92 144.25,57.19 150.72,50.71 150.72,48.18 152.81,46.1 152.81,43.2 153.24,42.77 154.12,42.77 154.36,42.87 156.88,43.37 157.53,43.37 160.3,40.6 160.3,40.49 161.73,39.06 164.39,39.06 168.59,34.86 168.59,34.79 169.45,33.93 171.29,33.93 172.75,32.48 172.75,32.31 173.54,31.52 174.78,31.52 175.24,31.06 175.94,31.06 176.29,30.71 176.75,30.71 180.14,27.32 ; v1(208.03,20.42) 208.03,19.68 ; 208.03,19.68 206.76,18.41 ; 211.05,19.75 211.05,19.63 v1(211.3,19.38) ; 206.76,18.41 v1(206.76,19.15) ; 195.46,15.7 196.1,15.06 198.37,15.06 198.68,14.75 198.68,14.31 198.37,13.99 197.92,13.99 197.77,14.15 195.5,14.15 195.34,13.99 194.9,13.99 194.29,14.6 v1(194.23,14.6) 194.23,14.96 193.6,15.6 191.52,15.6 ; v1(201.63,18.26) 201.63,17.78 201.57,17.73 ; 190.35,15.6 190.18,15.43 v1(190.18,15.05) ; 190.35,15.6 191.52,15.6 ; 191.52,15.6 191.45,15.53 191.45,15.33 v1(190.28,14.16) ; 193.12,19.53 v1(193.17,19.58)
  vias: v1(186.74,3.78) v1(201.61,3.62) v1(201.85,6.71) v1(201.98,10.97) v1(202.88,7.43) v1(207.96,13.78) v1(209.23,13.78) v1(213.68,13.78) v1(215.24,15.11) v1(215.32,18.11)
AVDDH: length 57.2
  TOP w0.203: U6.23 120.18,154.6 119.85,154.27 v1(119.44,154.27) ; U6.17 122.58,156.7 122.68,156.79 ; v1(131.71,144.59) 132.23,144.8 C1415.1 132.11,145.18 U6.106 ; C1419.1 v1(131.62,150.06) 131.31,150.38 U6.119 ; U6.88 125.78,138.31 125.59,138.11 125.59,137.91 125.54,137.86 C1420.1 ; U6.11 124.98,156.5 124.77,156.72
  TOP w0.254: v1(129.87,155.35) 130.28,155.35 130.61,155.68 C1407.1 130.1,155.96 129.65,156.41 129.29,156.41 129.03,156.15 U6.1
  ART03 w0.381: v1(119.44,154.27) 118.61,153.43 116.7,153.43 115.98,154.15 v1(113.84,154.15)
  BOTTOM w0.508: v1(131.71,144.59) 131.67,144.63 131.67,144.98 132.26,145.57 132.26,149.43 v1(131.62,150.06) 133.76,152.2 133.76,157.06 133.34,157.48 132.51,157.48 131.37,156.34 130.86,156.34 v1(129.87,155.35) 129.41,155.8 129.41,156.29 125.48,160.22 123.66,160.22 123.24,159.81 v1(123.24,158.85) 123.24,158.06 v1(119.44,154.27)
AVDDL: length 48.3
  TOP w0.203: C1424.1 118.18,158.73 U6.28 118.18,154.3 118.16,154.28 ; U6.124 130.48,152.4 v1(128.7,152.4) ; U6.34 116.6,153.58 ; v1(127.2,157.57) 127.19,157.57 126.98,157.37 U6.6 126.98,153.91 ; v1(128.88,146.56) 128.96,146.56 129.6,147.2 130.48,147.2 U6.111 ; U6.14 123.78,154.21 v1(123.69,154.11) ; U6.101 131.36,143.18 131.74,143.33 132.16,143.33 C1422.1 132.2,142.96 131.89,142.84 131.7,142.65 131.7,142.62 v1(131.65,142.57)
  TOP w0.254: C1414.1 127.36,157.72 v1(127.2,157.57) ; v1(123.69,154.11) 124.64,153.16 126.24,153.16 126.98,153.91
  ART04 w0.254: v1(131.65,142.57) 131.65,143.05 129.54,145.16 129.54,145.9 v1(128.88,146.56) 128.67,146.56 127.99,147.24 127.99,151.74 128.55,152.3 128.61,152.3 v1(128.7,152.4) 128.7,156.07 v1(127.2,157.57)
  BOTTOM w0.508: v1(123.69,154.11) 122.49,154.11 121.03,152.65 118.77,152.65 v1(117.42,154)
DVDD_PHY0_RG: length 12.1
  TOP w0.203: U1201.29 143.65,70.49 143.65,68.67 143.51,68.53 v1(143.31,68.53) 143.31,68.48 143.51,68.27 C1220.2 ; R1238.1 137.59,63.12 v1(137.21,63.5)
  ART04 w0.254: v1(137.21,63.5) 139.14,65.43 140.21,65.43 v1(143.31,68.53)
DVDDIO: length 67.4
  TOP w0.203: R1353.1 R1354.1 ; R1354.1 125.68,132.26 125.98,131.95 125.98,129.16 126.31,128.83 R1358.1 ; R1354.1 125.35,132.71 v1(124.97,133.1) 124.97,133.33 R1351.1 ; C1401.1 116.9,137.46 118.58,139.14 U6.70 ; C1401.1 116.9,135.38 117.27,135.01 LB1406.2 117.61,134.53 118.43,133.72 R1360.1 ; C1401.1 v1(116.21,135.67) ; C1429.1 121.92,156.57 122.18,156.3 U6.18 122.18,153.96 v1(122.86,153.29) ; R1361.1 v1(133.05,156.77)
  TOP w0.254: R118.2 v1(128.87,137.02) ; R1351.1 124.44,133.86 123.37,133.86 R1352.1 R1355.1 R1357.1 R1359.1 R1360.1 ; R1358.1 R1356.1
  BOTTOM w0.203: v1(124.97,133.1) 124.92,133.15 124.92,134.44 127.49,137.02 v1(128.87,137.02)
  BOTTOM w0.508: v1(116.21,135.67) 116.44,135.67 116.99,136.22 116.99,146.91 122.86,152.78 v1(122.86,153.29) 129.57,153.29 v1(133.05,156.77)
DVDDIO_1: length 30.3
  TOP w0.203: U6.69 118.18,143.49 116.49,145.18 U6.55 113.73,145.18 113.59,145.03 112.47,145.03 112.09,144.65 C1427.1 111.71,144.32 111.24,143.85 LB1407.2 109.54,144.41 109.55,144.41 ; 109.55,144.41 C1403.1 ; 109.55,144.41 109.44,144.53 107.95,144.53 107.18,143.76 106.83,142.91 106.83,142.33 106.3,141.04 106.3,139.77 106.55,139.16 106.55,138.55 106.93,138.17 106.93,136.92 107.06,136.79 R273.1 R258.1 R257.1 R204.1 R185.1 R184.1
DVDDIO_2: length 14.5
  TOP w0.203: U6.54 113.62,145.58 113.46,145.41 112.95,145.41 112.34,146.02 v1(112.34,146.18) 112.09,145.92 111.96,145.92 C1428.1 ; v1(111.34,151.57) 111.77,151.57 111.78,151.58 112.46,151.58 112.85,151.97 C1402.1 113.49,152.09 114.01,151.58 U6.39
  BOTTOM w0.203: v1(111.34,151.57) 112.85,150.06 112.85,146.68 v1(112.34,146.18)
DVDDL: length 46.8
  TOP w0.203: U6.21 120.98,157.2 C1425.1 ; C1412.1 109.88,146.13 v1(110.21,146.46) ; v1(113.23,145.92) 113.29,145.98 U6.53 116.68,145.98 118.98,143.68 U6.71 118.98,138.82 117.81,137.65 C1411.1
  TOP w0.254: C1425.1 120.5,157.28 v1(120.22,157)
  BOTTOM w0.254: v1(110.21,146.46) 111.15,146.46 111.94,145.67 112.98,145.67 v1(113.23,145.92)
  BOTTOM w0.406: v1(113.23,145.92) 113.92,146.61 113.92,152.73 109.09,157.56 v1(109.09,157.89)
  BOTTOM w0.508: v1(120.22,157) 118.49,158.72 109.93,158.72 v1(109.09,157.89)
GND: length 1624.7
  TOP w0.127: v1(207.65,46.74) 207.63,46.72 207.63,46.24 208.18,45.69 211.56,45.69 212.47,46.61 v1(212.47,46.74) ; U9.N5 U9.P6
  TOP w0.203: 96.67,167.77 96.85,167.59 R3111.2 ; R2933.1 v1(85.21,142.6) ; v1(188.14,156.67) 188.42,156.39 U1601.15 ; U9.G5 48.31,150.45 48.13,150.62 48.13,151.11 v1(48.11,151.13) ; R323.2 v1(12,117.64) ; Q3502.2 30.28,147.19 v1(29.74,147.73) 29.52,147.95 C3510.2 ; v1(125.07,119.91) 125.1,119.88 J3.267 ; R2216.1 C2210.1 236.7,173.74 R2213.2 ; C1105.2 v1(227.08,55.75) ; v1(172.36,34.95) 171.96,34.54 R2748.1 ; v1(107.14,174.83) R3118.1 C3130.2 ; v1(129.08,150.11) 129.34,150.11 129.47,149.98 U6.118 ; v1(119.7,44.26) 119.91,44.47 U2101.51 121.62,44.47 C2115.2 ; v1(134.67,80.22) 135.33,79.56 R1245.2 ; U9.E7 47.6,149.63 v1(47.24,149.99) ; U9.N2 U9.N1 51.09,153.45 v1(51.12,153.48) ; R1369.2 v1(123.23,135.93) ; C1637.1 v1(238.38,185.88) ; v1(209.77,53.12) 209.6,52.96 C26.2 ; C35.2 199.9,57.4 199.64,57.66 v1(199.14,57.66) ; J3.271 126.1,119.71 125.9,119.91 v1(125.86,119.91) ; R312.2 v1(5.99,123.62) ; v1(125.65,154.18) 125.02,154.18 124.58,154.61 U6.12 ; v1(77.85,150.54) 78.13,150.26 R152.1 ; 140.28,67.44 v1(140.28,68.07) ; J601.57 v1(21.51,151.38) ; U9.P6 48.1,154.6 v1(47.94,154.75) ; C2125.2 115.89,36.74 v1(115.67,36.96) ; v1(167.28,28.02) 167.51,28.25 R2729.1 ; R1626.1 v1(82.27,153.29) ; C1647.1 C1604.1 ; R310.2 v1(15.56,119.77) ; C158.2 v1(13.55,119.77) ; C3104.2 97.97,163.12 v1(97.46,162.61) ; v1(118.49,46.56) 118.69,46.76 U2101.61 ; R3138.2 C3146.2 117.5,185.14 Q3106.2 ; v1(78.77,146.57) 78.61,146.73 R149.1 ; v1(216.51,58.55) R1117.1 215.27,57.78 Q1107.2 ; v1(169.26,28.02) 168.78,28.49 R2727.1 ; J601.51 v1(20.01,151.38) ; v1(89.41,148.56) 89.31,148.46 87.91,148.46 87.68,148.23 ; C1404.2 v1(106.53,159.26) ; J601.1 v1(7.51,153.67) ; U3.R7 v1(206.66,45.95) ; R308.2 v1(26.45,117.59) ; R313.2 26.2,120.16 v1(26.47,119.89) ; v1(128.17,22.39) 128.16,22.38 127.23,22.38 U1901.2 ; R2141.1 100.15,43.38 v1(99.82,43.05) ; C3402.1 14.92,54.67 14.44,54.19 U3402.3 ; U9.A6 v1(48.1,146.88) ; C2812.2 v1(3.81,38.48) ; R1364.2 v1(120.1,135.93) ; R2742.1 v1(173.23,34.92) ; R244.1 v1(3.86,121.59) ; R321.2 v1(3.86,119.56) ; C25.2 v1(209.8,53.97) ; R1105.1 v1(229.36,56.77) ; C139.1 v1(199.26,180.5) ; R263.2 v1(3.62,131.79) ; U9.P4 49.1,154.63 v1(49.21,154.75) ; R1113.2 v1(228.09,48.16)
  TOP w0.254: C3015.2 v1(8.19,143.55) ; C1626.1 231.33,174.81 v1(231.7,175.18) ; v1(111.23,176.07) 111.31,175.99 Q3103.2 ; C1622.1 C1621.1 220.75,174.8 v1(220.7,174.75) ; C1517.1 C1518.1 v1(178.36,173.18) ; C1416.2 131.87,139.85 v1(132.17,139.55) 132.17,139.18 131.83,138.84 C1406.2 ; v1(102.59,129.69) 102.46,129.69 102.08,129.31 C171.2 C172.2 ; U2904.11 61.81,148.59 U2904.12 63.69,148.09 U2904.25 63.69,146.59 U2904.13 ; C1328.2 v1(134.43,162.36) ; v1(39.66,154.69) C40.1 C41.1 ; v1(105.23,124.46) 105.64,124.46 105.85,124.67 J3.190 105.85,126.78 106.2,127.13 v1(107.32,127.13) ; J701.15 144.55,85.28 v1(144.53,85.25) ; U2803.4 v1(132.05,28.86) ; v1(125.73,42.29) C2119.2 123.95,42.29 v1(123.89,42.35) ; U3201.8 28.19,50.62 v1(28.25,50.67) ; J3.223 114.1,116.26 v1(113.92,115.82) ; C1815.2 v1(25.91,160.4) C1803.2 ; v1(67.55,116.79) 67.6,116.84 J3.37 67.6,119.6 v1(67.31,119.89) ; R3310.2 209.5,23.62 209.36,23.62 v1(209.3,23.56) ; v1(183.11,86.87) 183.11,86.89 183.03,86.98 J803.39 183.03,89 183.28,89.26 v1(183.41,89.26) ; C2025.1 135.2,78.94 R1245.2 ; v1(116.85,123.84) J3.234 v1(116.85,127.11) ; R361.2 v1(156.26,51.88) ; v1(207.26,49.1) 207.52,49.35 207.52,50.55 207.77,50.8 210.97,50.8 211.23,50.55 C12.2 ; v1(173.66,71.37) 173.61,71.42 C1011.2 172.95,71.48 Q1004.2 ; C3133.2 111.94,172.27 111.25,171.58 v1(110.62,171.58) 110.57,171.53 Q3105.2 ; v1(159.77,89.43) 159.26,89.43 158.95,89.12 J701.43 ; v1(188.72,65.38) C713.2 ; v1(89.15,171.73) 89.31,171.57 R1633.1 ; C1330.2 v1(120.81,164.4) ; U3.G8 v1(200.26,45.96) 199.86,45.56 U3.G7 ; C1504.1 C1501.1 151.87,174.47 151.66,174.27 v1(151.33,174.27) ; C2711.2 166.84,33.43 v1(166.81,33.4) ; v1(171.29,16.41) R2746.1 R2747.1 ; J2701.35 v1(30.79,38.58) ; v1(79.57,116.79) 79.57,117.04 79.6,117.07 J3.85 v1(79.6,120.01) ; v1(209.17,174.29) 209.8,174.93 C1510.1 C1509.1 ; U13.2 v1(125.22,194.18) ; C182.2 C181.2 v1(95.3,129.46) ; C3611.2 v1(61.37,15.42) ; v1(144.37,174.12) 144.5,174.24 145,174.24 C1507.1 144.97,174.8 C1503.1 ; v1(83.85,124.08) J3.102 v1(83.85,127.11) ; v1(31.34,172.39) 31.21,172.26 R3008.1 ; R242.1 R240.1 R246.1 ; R242.1 6.26,134.86 R3015.1 ; R242.1 6.95,135.25 6.69,135.51 v1(6.48,135.51) ; C1608.2 87.63,166.88 87.5,167 v1(87.5,167.41) 88.44,167.41 C1644.1 ; R3132.2 112.04,184.25 v1(112.01,184.28) ; v1(202.84,173.15) 203.31,173.62 C1515.1 202.4,175.04 202.06,175.39 C1512.1 ; C1428.2 R1381.1 ; C1428.2 v1(110.24,145.67) ; C1428.2 C1427.2 ; 125.35,124.21 125.35,123.19 v1(125.48,123.06) ; 125.35,124.21 J3.268 ; 125.35,124.21 125.72,124.21 125.85,124.33 J3.270 ; C619.2 v1(7.47,143.64) ; v1(112.41,135.06) 113.24,135.9 C1317.1 ; C1620.1 C1623.1 224.26,174.5 v1(224.28,174.47) ; v1(22.62,140.32) 22.07,139.78 R3540.2 C3523.2 ; v1(113.54,168.02) 113.36,168.2 113.16,168.2 112.93,168.43 C3132.2 R3137.2 ; R3214.2 v1(27.69,47.04) ; J3.265 124.6,119.47 124.66,119.53 124.66,119.72 124.85,119.91 v1(125.07,119.91) ; R349.2 v1(156.26,47.47) ; 196.6,27.43 196.6,27.81 196.88,28.09 196.88,28.45 197.13,28.7 197.13,28.75 197.33,28.96 R3216.1 ; R1217.2 150.24,72.9 150.52,73.18 v1(150.52,73.29) ; R1217.2 C1202.2 ; R1217.2 R1218.2 R1201.2 R1216.2 150.42,70.23 150.47,70.28 ; R315.2 R323.2 ; v1(186.08,86.89) 186.08,86.89 186.06,86.92 186.06,86.99 186.03,87.02 J803.27 v1(186.03,89.2) ; v1(128.65,131.95) 128.42,131.72 127.94,131.72 R1366.2 R1363.2 ; C104.1 105.02,33.27 v1(105.27,33.02) ; C1301.2 v1(146.66,152.65) ; C1302.2 v1(151.72,155.52) ; C1422.2 132.36,141.86 v1(132.56,141.66) ; v1(181.48,86.87) 181.53,86.91 J803.45 181.53,89.08 v1(181.4,89.2) ; R1822.1 24.36,162.99 24.61,163.25 25.32,163.25 v1(25.53,163.45) 25.86,163.78 C3011.2 ; D2201.3 D2201.8 v1(205.38,154) ; v1(36.14,21.41) 35.94,21.61 C166.2 ; C3616.2 38.01,20.15 C3408.1 39.31,20.71 v1(39.47,20.88) ; U3.J8 v1(201.06,46.76) ; v1(201.06,46.76) U3.H9 ; v1(201.06,46.76) U3.J9 ; v1(135.13,70.16) 135.23,70.06 R1243.2 R1244.2 ; v1(55.5,124.22) 55.35,124.37 J3.308 ; R2819.2 v1(191.52,35.38) ; R2819.2 R2822.2 R2824.2 193.55,35.13 193.29,35.38 v1(193.17,35.38) ; R2819.2 R2816.2 190.07,34.72 189.99,34.8 R2815.2 R2821.2 ; v1(169.42,39.8) 168.78,39.8 168.77,39.81 R166.2 ; C1641.2 v1(91.95,165.51) ; R1214.2 150.83,69.09 150.52,69.39 150.52,70.23 ; J3.195 107.1,116.83 v1(107.98,115.95) ; R1712.1 v1(46.1,159.27) ; C3402.1 C3403.1 13.83,55.49 v1(14.1,55.75) ; J601.15 11.01,153.46 v1(10.8,153.67) 11.4,154.28 C601.2 ; C1016.2 174.57,52.07 R1035.1 v1(174.61,52.68) ; v1(191.77,39.37) 192.13,39.37 R20.1 ; v1(173.23,34.92) 173.23,35.25 174.04,36.07 R2740.1 ; U9.J5 48.42,151.45 v1(48.11,151.13) ; v1(205.06,44.35) U3.N6 ; v1(78.1,116.79) J3.79 v1(78.1,119.93) ; v1(116.38,132.51) 116.43,132.51 116.76,132.84 C1320.1 ; C2116.2 C2127.2 ; C2127.2 108.84,48.26 v1(108.65,48.45) ; C2127.2 109.7,48.28 C2111.2 ; v1(26.49,123.45) 26.49,123.7 26.23,123.95 R2628.2 ; J3.252 v1(121.35,127.11) ; v1(121.54,201.42) 121.45,201.51 J2301.17 v1(121.45,205.1) ; R135.2 71.48,13.06 71.88,13.46 v1(71.88,13.59) ; v1(63.37,156.46) 61.85,156.46 61.6,156.72 Q1704.2 60.93,157.81 60.68,157.56 v1(60.68,157.02) 60.68,156.26 61.93,155.02 R150.1 ; v1(190.68,51.18) 191.29,51.18 C15.2 191.69,51.13 192.2,50.62 C16.2 C17.2 ; Q3302.2 212.51,19.69 211.89,20.32 v1(211.81,20.32) C3312.2 ; R187.2 R142.2 55.54,128.38 55.47,128.45 v1(55.47,128.78) ; v1(15.75,137.16) 15.49,136.91 R2646.2 ; v1(73.86,166.17) R1606.2 C1602.2 ; J3.73 v1(76.6,119.93) 76.35,120.18 J3.72 76.35,126.9 76.58,127.13 77.6,127.13 77.85,126.87 J3.78 77.85,124.46 78.1,124.21 v1(78.61,124.21) ; v1(52.32,123.32) 52.85,123.84 J3.298 ; v1(22.28,115.44) 22.28,115.93 C426.2 ; R357.1 v1(169.55,50.76) ; R2625.2 24.34,124.64 24.6,124.89 v1(24.6,125.13) ; v1(146.09,41.57) 145.9,41.76 C2013.2 ; C164.1 C165.1 v1(161.34,34.16) ; C1520.1 176.29,173.84 C1516.1 175.18,173.71 v1(175.18,173.2) ; v1(218.06,55.24) 218.06,55.5 217.81,55.75 C1108.2 ; J3.12 61.35,124.46 61.6,124.21 65.72,124.21 65.85,124.33 J3.30 v1(65.85,127.39) ; v1(107.82,199.64) 107.52,199.34 D2305.3 D2305.8 v1(107.52,197.21) ; R343.2 v1(156.26,48.76) ; R1204.1 150.72,75.59 v1(150.75,75.56) 151.77,75.56 152.48,74.85 153.39,74.85 153.7,74.55 C1203.1 153.76,74.2 v1(154.6,74.2) v1(154.6,72.14) 154.6,70.94 154.31,70.65 X1201.2 153.58,70.01 153.37,69.8 v1(152.58,69.8) 150.95,69.8 150.52,70.23 ; C1712.2 v1(65.15,164.08) ; v1(152.55,89.31) J701.27 152.55,86.61 152.3,86.36 v1(152.02,86.36) ; v1(101.47,127.25) 101.68,127.05 102.18,127.05 102.35,126.88 J3.176 102.35,124.57 v1(102.62,124.31) ; v1(79.35,124.14) J3.84 v1(79.35,127.11) ; C1809.1 57.85,157.76 57.91,157.7 57.91,156.93 v1(57.92,156.92) ; v1(110.85,127.11) 110.85,127.11 J3.210 v1(110.85,123.84) ; v1(132.82,51.94) C2021.1 C2026.2 ; v1(116.4,180.85) 116.38,180.86 116.07,180.86 115.8,181.13 R3128.1 C3144.2 ; R3801.1 58.45,24.87 58.93,24.38 58.93,23.49 59.46,22.96 R3617.1 ; J3.25 v1(64.6,116.79) ; R235.1 v1(28.45,80.54) ; v1(26.49,121.5) 26.12,121.13 R2627.2 ; v1(140.34,64.36) 140.08,64.62 R1241.2 R1203.2 C188.2 ; v1(72.1,116.79) J3.55 v1(72.1,119.93) ; C1305.2 v1(141.61,156.88) ; R1637.1 v1(73.51,168.93) ; v1(13.97,153.8) 14.01,153.76 J601.27 ; R354.1 v1(169.55,51.8) ; v1(95.89,200.41) 95.89,200.13 C2401.2 ; v1(9.65,122.05) 9.65,121.53 R319.2 ; U3.B14 v1(196.26,50.75) ; R1242.2 143,65 143.33,65.33 v1(143.33,66.32) 143.41,66.4 143.41,66.74 143.51,66.84 C1220.1 143.33,67.03 142.8,67.56 C184.2 ; R311.2 R310.2 ; v1(155.52,86.49) 155.75,86.71 J701.35 155.75,89.12 v1(155.5,89.37) ; C2804.2 207.01,31.39 v1(207.01,32.51) 207.01,32.53 206.76,32.79 U2802.2 ; Q1804.2 v1(30.15,160.45) ; U701.2 v1(102.62,33.02) ; Q3503.2 24.49,136.68 25.22,137.41 v1(25.22,137.67) ; R108.1 C108.1 ; C108.1 160.96,43.31 160.96,43.31 v1(160.96,43.15) ; C108.1 C107.1 C102.1 ; C1609.2 84.83,166.36 v1(84.33,165.86) 84.33,165.28 R1620.1 R1621.1 ; R2896.1 v1(9.27,43.18) R2895.1 ; C79.2 57.5,40.36 v1(57.5,39.73) ; C1201.1 137.9,77.62 R1222.2 ; v1(60.48,144.45) 60.48,144.18 R155.2 ; U3.L8 203.06,46.35 v1(202.66,45.96) U3.L7 ; C190.1 110.46,140.49 v1(110.44,140.51) ; v1(82.4,127.11) 82.35,127.06 J3.96 v1(82.35,124.14) ; v1(184.53,89.2) J803.33 184.53,86.89 v1(184.55,86.87) ; v1(115.45,205.1) J2301.5 115.45,201.71 v1(115.44,201.7) ; Q1702.2 v1(50.9,162.75) ; C1805.1 v1(28.3,155.57) C1806.1 ; C2010.2 139.19,36.83 139.19,36.32 138.84,35.97 138.84,35.94 v1(138.81,35.92) ; R1377.1 110.26,149.22 v1(110.24,149.25) 110.21,149.22 R1375.1 ; R2731.1 R2729.1 ; v1(147.35,67.16) 147.7,67.51 R1205.2 147.55,67.79 146.74,68.6 R179.2 ; v1(2.77,135.18) 2.77,134.79 3.02,134.53 R3014.1 ; C1313.2 141.36,149.78 141.36,149.48 v1(141.39,149.46) 141.36,149.43 141.36,149.13 C1314.2 ; v1(92.74,201.71) 92.75,201.73 J2401.8 v1(92.75,205.1) ; v1(120.73,26.29) 120.87,26.43 C2813.2 ; C2810.2 C2803.2 C2802.2 204.32,36.3 204.11,36.09 v1(204.11,36.07) ; v1(159.26,173.79) C1527.1 158.97,174.98 C1523.1 ; v1(93.85,124.21) 93.35,124.71 J3.140 ; C3617.2 19.08,27.43 v1(19.56,27.43) ; v1(199.23,44.61) 198.91,44.61 U3.E5 ; R1401.2 110.11,150.49 v1(110.24,150.37) 110.36,150.49 R1376.1 ; v1(95.25,163.45) 95.58,163.12 C3103.2 ; Q1701.2 69.24,158.39 C1701.2 v1(69.98,159.13) ; 102.41,162.76 104.8,162.76 C3107.2 105.36,162.45 v1(105.82,162.92) ; C2007.2 134.21,37.06 v1(134.58,36.69) ; v1(192.58,150.95) 193.22,150.95 193.4,151.13 R1643.1 ; C1901.2 R1901.2 115.12,23.64 v1(114.97,24.01) ; C92.2 166.37,84.43 166.62,84.18 v1(166.8,84.18) 166.85,84.18 166.88,84.2 167.13,84.2 167.39,84.45 C89.2 167.84,84.81 D4.2 168.94,84.2 C88.2 ; C105.2 96.29,33.86 v1(95.76,33.32) 95.71,33.27 95.28,33.27 C724.2 ; v1(140.08,94.23) 140.15,94.3 J701.4 ; v1(63.1,119.86) J3.19 v1(63.1,116.79) ; X2001.2 146.98,37.3 v1(146.47,37.3) ; v1(32.51,29.79) 32.51,30.43 33.19,31.11 J2701.12 ; v1(139.01,70.85) C186.2 138.38,71.53 138.2,71.71 C185.2 ; U3.J11 v1(201.06,48.36) U3.H11 v1(200.26,48.36) U3.G11 ; C725.2 102.72,29.97 ; 102.72,29.97 v1(102.36,29.97) ; 102.72,29.97 102.87,29.97 103.55,29.29 J702.5 ; R255.1 C137.2 69.06,21.21 69.34,21.49 v1(69.34,21.59) ; J3.253 121.6,116.27 v1(121.92,115.95) ; R2647.2 18.44,136.91 v1(18.19,137.16) ; C1401.2 117.72,136.46 C1411.2 R1362.2 v1(118.67,135.93) ; C1813.2 55.89,146.6 v1(56.05,146.43) ; C2009.2 137.03,36.07 v1(137.29,35.81) ; v1(121.08,24.94) 121.36,24.94 121.82,24.49 R63.1 ; v1(53.02,20) 52.96,20.07 Q3601.2 52.71,21.46 R3604.1 52.81,22.73 C3604.2 ; v1(155.53,35.67) 155.91,36.04 R143.1 ; R1222.2 C1213.2 ; R1222.2 137.47,77.67 v1(137.13,77.34) ; C1613.2 178.61,154 v1(178.23,153.62) ; v1(118.62,131.7) 119.01,131.31 U1301.1 ; v1(93.7,184.41) 92.33,184.41 U12.3 ; C2017.2 v1(146.76,47.24) ; v1(207.57,22.07) 207.32,22.07 206.88,21.64 206.88,21.25 U1001.2 ; C1610.2 81.46,167.25 v1(81.61,167.4) ; C1529.1 C1528.1 167.89,174.27 168.25,173.91 v1(168.28,173.91) ; R3518.2 114.95,134.75 115.16,134.54 C1430.2 ; v1(148.5,79.84) 148.89,79.45 C716.2 ; Q3101.2 152.06,64.24 ; 152.06,64.24 C3102.1 ; 152.06,64.24 151.35,64.24 v1(151.14,64.03) 150.14,64.03 149.89,64.29 C1208.1 ; C175.2 107.8,128.98 C176.2 107.82,129.36 v1(107.42,129.77) ; v1(110.19,41.07) 109.98,40.87 C2122.2 ; v1(112.45,140.56) 112.5,140.51 C97.1 ; v1(87.25,153.29) 86.33,154.2 U1602.6 ; J701.40 v1(157.75,94.01) ; U1602.7 87.6,154.08 87.88,153.8 v1(87.88,153.29) ; C1424.2 v1(117.65,160.72) ; R3007.2 v1(29.25,174.5) 29.25,175.17 29.05,175.37 R132.2 ; R365.2 v1(156.26,52.94) ; R358.1 v1(169.55,52.83) ; v1(107.14,190.51) 106.88,190.77 v1(106.88,191.82) ; v1(193.29,71.37) 193.04,71.37 192.76,71.09 C2801.2 ; U2805.4 23.7,92.2 23.44,91.95 v1(22.73,91.95) ; v1(101.09,150.65) 101.35,150.9 101.35,151.97 101.17,152.15 R1408.1 ; v1(209.77,53.12) 210.19,52.7 R11.2 209.7,52.35 209.3,51.94 R13.2 ; U17.7 34.34,26.46 v1(34.54,26.67) ; v1(85.47,127.11) 85.35,126.99 J3.108 85.35,125.53 85.35,125.53 v1(85.35,124.11) ; C3103.2 96.04,162.09 R3109.1 ; C3103.2 C3114.2 95.91,164.26 v1(95.25,164.26) 95.12,164.13 C163.1 94.39,165.44 C1639.2 94.93,165.99 v1(95.25,165.99) ; C28.2 C27.2 191.39,48.46 v1(191.82,48.89) C14.2 C13.2 C23.2 ; C102.1 v1(162.99,43.15) ; C102.1 C106.1 165,43.79 R107.1 ; v1(175.73,16.41) R2728.1 R2730.1 ; C1322.2 v1(134.43,159.77) ; R350.1 v1(169.57,49.73) ; C3113.2 C3112.2 C3104.2 ; v1(169.57,48.56) 169.43,48.42 R334.1 ; v1(18.51,153.62) J601.45 v1(18.51,151.38) ; v1(162.99,89.03) 162.99,87.12 163.44,86.68 C85.2 ; v1(111.76,141.25) 111.48,140.97 C189.1 ; v1(96.85,127.25) J3.154 v1(96.85,124.31) ; v1(105.19,129.76) 105.13,129.7 105.13,128.98 ; C103.1 v1(105.16,31.88) ; 105.13,128.98 105.1,129.01 C173.2 ; 105.13,128.98 C174.2 ; v1(27.69,166.47) 27.64,166.42 R3021.1 ; R3138.2 119.81,186.13 v1(119.88,186.19) ; R347.2 v1(156.24,44.97) ; v1(115.23,15.37) 115.23,14.91 115.46,14.67 J1901.11 ; C1310.2 151.47,146.59 151.47,146.89 v1(151.5,146.91) 151.47,146.94 151.47,147.23 C1316.2 ; C3406.2 v1(28.32,77.37) ; v1(194.72,57.68) 195.07,57.33 C34.2 C36.2 ; v1(101.09,119.96) 101.1,119.96 J3.171 ; v1(205.94,174.7) 205.36,174.7 205.11,174.95 C1514.1 205.4,175.34 C1511.1 ; J701.34 155.35,94.46 v1(155.7,94.11) ; v1(115.35,127.11) J3.228 v1(115.35,123.84) ; J2701.28 v1(36.39,38.4) ; v1(83.41,132.14) 83.49,132.07 R83.1 ; J803.71 v1(175.03,89.33) 174.62,89.33 174.53,89.23 J803.73 ; v1(196.22,62.86) 196.85,62.86 197.1,62.61 U2801.4 ; v1(91.24,201.71) 91.25,201.73 J2401.5 v1(91.25,205.1) ; v1(82.6,120.01) J3.97 v1(82.6,116.71) ; C1321.1 120.85,132 v1(121.03,131.83) ; v1(198.01,57.66) 197.99,57.64 R10.2 ; U3.G9 v1(200.26,46.76) ; v1(82.35,147.19) 82.35,146.67 82.27,146.59 U2903.13 ; U9.K8 47.1,151.66 v1(47.37,151.38) 47.24,151.26 47.24,151.13 46.99,150.88 46.17,150.88 U9.H10 ; U3401.2 v1(25.4,77.34) ; R1034.1 v1(172.94,44.57) ; v1(210.44,43.31) 210.08,42.95 209.83,42.95 ; v1(37.97,38.4) 37.97,38.25 37.99,38.23 J2701.26 ; C1711.2 v1(62.92,159.13) ; R236.1 C3407.2 24.26,81.15 v1(24,81.41) ; v1(93.65,178.95) 93.55,178.85 U2.3 ; Q3401.2 v1(16.43,83.96) ; R1702.1 v1(70.99,161.42) ; C192.1 v1(108.59,140.51) ; v1(115.89,34.1) 115.63,34.35 C2129.2 116.32,36.12 C2125.2 ; J1901.10 v1(127.4,17.02) ; Q801.2 191.34,77.04 v1(191.64,77.34) 192,76.99 C802.2 192.29,75.79 R822.1 ; C1634.2 84.82,168.91 v1(84.33,168.91) ; R1833.2 C1811.1 R1820.2 v1(58.55,146.56) ; 183.64,54.86 R85.1 R84.1 185.43,54.15 R177.1 v1(186.18,54.13) ; v1(89.41,147.07) 89.15,146.81 87.85,146.81 C2911.1 C2912.1 ; v1(227.58,173.56) 227.33,173.81 C1625.1 C1624.1 ; v1(48.77,120.01) 49.1,119.68 J3.285 ; R1239.2 C187.2 135.22,66.64 v1(135.13,66.55) 135.03,66.65 C2024.2 ; v1(113.85,127.11) 113.85,127.11 J3.222 113.85,123.93 v1(113.74,123.82) ; U7.3 v1(93.65,190.28) ; 25.76,177.42 26.21,177.42 v1(26.42,177.22) ; v1(123.44,124.08) 124.1,124.08 124.35,124.33 ; C157.2 v1(15.59,134.11) ; C3501.2 34.84,145.51 34.07,145.51 v1(34.04,145.54) ; U3.E11 v1(198.66,49.15) ; C1407.2 R1372.2 131.39,156.87 131.39,157.48 v1(131.39,157.48) ; v1(81.1,120.01) J3.91 v1(81.1,116.79) ; v1(89.75,205.1) J2401.2 89.75,201.73 v1(89.74,201.71) ; C3601.2 v1(55.75,16.13) v1(56.77,16.13) C3612.2 ; v1(4.76,138.87) 5.28,139.39 U3002.7 5.28,141.42 5.47,141.62 6.72,141.62 v1(6.73,141.6) 7.19,141.15 C3012.2 7.82,140.66 8.37,141.21 C3013.2 ; U2903.11 80.55,148.68 80.17,148.3 U2903.12 81.27,148.09 v1(81.28,148.08) ; R1371.2 R1369.2 ; C2006.1 135.79,51.28 135.1,51.97 v1(134.85,51.97) ; C3213.1 157.16,63.71 Q3201.2 157.16,61.98 v1(156.87,61.7) ; v1(161.04,94.61) 161.42,94.61 161.75,94.95 J701.50 ; C1525.1 C1524.1 165.74,174.45 v1(165.38,174.09) ; R2101.1 v1(96.09,43.75) ; R279.2 64.14,139.98 v1(64.26,139.85) ; C3607.2 70.87,9.91 71.25,10.29 v1(71.5,10.29) ; C1334.2 v1(114.31,164.4) ; Q2.2 64.16,20.34 v1(63.75,19.94) ; U3.P4 v1(205.06,43.55) U3.N5 ; C714.2 188.54,59.44 v1(188.47,59.51) ; J3.151 96.1,116.93 96.09,116.92 v1(96.09,116.78) ; C1606.1 v1(216.92,174.5) ; v1(30.02,191.74) 30.57,191.19 R1639.1 ; v1(94.25,205.1) J2401.11 94.25,201.73 v1(94.24,201.71) ; R1806.1 v1(27.46,163.42) ; v1(24.98,129.02) 24.98,128.83 24.73,128.57 R2623.2 ; v1(128.4,3.66) 128.6,3.87 J1901.14 ; v1(109.35,127.11) J3.204 109.35,124.66 v1(110.21,123.8) ; C1315.2 141.36,152.58 141.36,152.28 v1(141.39,152.26) 141.36,152.23 141.36,151.94 C1309.2 ; C1519.1 182.25,173.84 v1(182.55,173.53) ; v1(156.08,39.39) 156.16,39.32 R391.2 R292.2 ; J3.42 v1(68.85,127.39) ; R3506.2 29.59,151.79 29.92,152.12 30.63,152.12 30.66,152.15 v1(31.12,152.15) ; v1(169.6,46.99) 169.4,46.79 C131.2 ; J1.2 v1(168.28,61.29) ; J2701.20 v1(26.79,30.66) ; C2713.2 7.61,100.58 v1(7.74,100.71) ; C167.1 26.57,21.59 26.82,21.34 v1(27.43,21.34) ; R2781.2 22.63,28.35 v1(22.99,28.7) ; U2703.12 v1(177.52,20.81) ; R1632.2 133.68,186.9 v1(133.41,187.17) ; U3.D14 v1(197.06,50.75) ; v1(113.94,201.7) 113.95,201.71 J2301.2 v1(113.95,205.1) ; C1306.2 v1(146.66,159.44) ; v1(119.82,22.63) 119.8,22.61 119.8,22.54 119.52,22.27 U1902.2 ; C1812.1 v1(45.97,144.02) ; C1325.2 v1(129.55,163) ; R2741.1 175.87,39.12 v1(176.2,39.45) 176.2,39.45 R1033.1 ; v1(170.49,70.36) 169.42,70.36 168.91,70.87 C1002.2 168.86,71.2 Q1003.2 ; R1635.2 v1(126.29,201.04) ; C2014.2 C2013.2 ; C2013.2 C2012.2 ; C2001.2 v1(56.44,43.87) ; C1707.2 50.34,160.16 v1(50.47,160.28) ; C130.1 v1(163.37,34.16) ; v1(191.44,158.44) 190.96,158.93 C1604.1 ; U2001.4 66.24,47.68 65.53,48.39 v1(65.53,48.51) ; v1(191.8,63.55) 191.47,63.23 191.47,63.05 191.36,62.93 Q702.2 191.36,61.41 191.05,61.1 R713.2 ; J3.258 122.85,124.37 v1(122.56,124.08) ; v1(142.11,85.22) 142.15,85.25 J701.9 ; v1(212.47,46.74) 212.76,46.74 213.36,47.34 213.36,47.95 212.95,48.36 C11.1 212.6,49.02 212.09,49.53 212.09,49.91 v1(211.96,50.04) 211.89,50.11 C12.2 ; 73.53,10.36 v1(73.53,10.29) ; 73.53,10.36 73.2,10.7 C3610.2 ; 73.53,10.36 74.09,10.36 Q3604.2 ; v1(58.62,116.78) 58.62,117.17 58.6,117.19 J3.1 ; C1710.2 v1(47.59,164.69) ; J3.240 v1(118.35,127.11) ; C2301.2 121.51,199.49 v1(121.67,199.64) ; v1(60.01,20.13) 60.2,20.32 Q3605.2 R3617.1 ; C1331.2 v1(113.49,164.4) ; v1(112.35,123.84) J3.216 v1(112.35,127.11) ; C3602.2 v1(50.42,16.13) ; C731.2 135.71,85.78 v1(135,86.49) ; v1(182.19,44.83) 182.19,44.37 182.21,44.35 U1002.12 ; v1(229.74,54.99) 229.64,54.99 229.03,54.38 R1114.1 ; C42.2 108.99,51.89 v1(108.84,52.04) ; J3.264 124.35,124.33 ; 124.35,124.33 124.71,124.33 124.85,124.47 J3.266 ; C2117.1 114.96,36.09 v1(114.81,35.94) ; C93.1 187.1,76.89 v1(187.38,77.16) ; C1522.1 C1521.1 171.6,173.14 v1(171.6,172.52) ; U8.3 93.5,173.13 93.75,173.39 v1(93.75,173.98) ; R263.2 C301.1 ; Q1703.2 v1(41.53,162.75) ; R1370.2 C1420.2 125.68,136.42 R1367.2 R1368.2 126.98,135.61 v1(127.45,135.14) ; C2019.2 R2006.1 130.91,47.32 131.08,46.91 R137.1 130.97,46.37 v1(130.45,46.15) ; v1(235.97,189.61) 235.97,188.96 C1636.1 236.31,188.73 236.73,189.15 v1(236.73,189.61) ; v1(209.12,47.78) 208.99,47.65 208.99,47.28 209.37,46.9 X1.4 ; R3114.1 105.11,164.77 104.95,164.92 ; R3407.1 9.8,54.2 9.53,54.48 v1(8.89,54.48) ; C715.2 153.75,80.72 v1(154.43,81.41) ; TP4.1 182.37,54.99 ; v1(132.51,137.02) R121.1 C138.2 ; M19.1 120.31,110.3 ; C3224.2 26.52,54.38 26.54,54.41 C3215.2 v1(28.32,54.41) ; R1379.1 110.39,147.95 v1(110.24,147.8) 110.08,147.95 R1378.1 ; C90.2 171.7,92.28 171.91,92.07 v1(172.47,92.07) ; C1324.2 v1(123.75,162.93) ; v1(80.39,129.13) 80.26,129.26 C170.2 ; v1(70.6,116.79) J3.49 v1(70.6,119.89) ; R2899.1 R62.1 121.43,29.07 121.13,28.78 v1(121.13,28.5) ; C1611.2 78.74,167.25 v1(78.59,167.4) ; C1702.2 v1(70.56,164.77) ; C1215.1 136.47,73.47 136.31,73.63 C1214.1 135.48,74.9 v1(135.48,76.25) ; C2123.2 109.8,44.04 v1(109.96,44.2) ; v1(116.89,201.7) 116.95,201.76 J2301.8 v1(116.95,205.1) ; v1(29.21,38.53) 29.21,38.43 29.19,38.41 J2701.37 ; R2734.1 R2732.1 v1(173.51,16.41) ; v1(141.22,36.07) 140.9,36.39 140.77,36.39 140.59,36.58 C2011.1 ; C2020.1 v1(130.51,43.74) ; R23.1 118.5,25.72 v1(118.47,25.76) ; v1(28.25,83.82) 28.25,84.4 C2811.2 ; v1(117.3,116.38) 118.34,116.82 118.6,117.08 J3.241 ; J701.26 v1(152.15,97.92) ; C1603.2 v1(71.43,164.77) ; J2401.17 v1(97.25,205.07) ; v1(22.81,78.99) 22.38,78.99 22.02,79.35 C3401.2 ; R127.1 v1(153.95,68.3) ; v1(131.76,194.75) 131.9,194.61 C1635.1 ; J3.66 74.85,126.95 74.41,127.39 v1(73.35,127.39) J3.60 ; v1(169.85,32.47) 169.93,32.4 C2712.2 ; C2126.2 122.96,47.17 123.29,47.5 v1(123.57,47.5) ; v1(49.12,149.7) 49.1,149.68 U9.D4 U9.C4 ; v1(61.6,119.86) J3.13 v1(61.6,116.79) ; R353.2 v1(156.26,49.79) ; J3.31 v1(66.1,116.79) ; C24.2 C20.2 194.36,54.63 v1(194.31,54.58) ; J601.39 17.01,151.4 v1(17.02,151.38) ; J601.57 21.51,153.2 v1(21.84,153.54) ; v1(131.6,75.59) 131.88,75.59 132.29,75.18 U2003.4 ; C12.2 211.29,50.05 X1.2 ; U10.4 18.99,89.08 v1(18.62,89.45) ; R2216.1 235.86,172.06 v1(235.51,171.7) ; C2714.1 7.09,109.6 v1(7.04,109.55) ; v1(185.17,45.59) 185.29,45.72 R2828.2 ; C1526.1 v1(162.18,174.35) ; R2626.2 24.34,127.58 24.6,127.33 v1(24.6,127.09) ; 133.2,144.12 C1415.2 ; C1329.2 v1(134.43,158.32) ; C3002.2 C3009.2 v1(30.11,166.85) ; v1(60.55,141.16) 60.55,140.94 60.8,140.69 R154.2 ; U3.K4 v1(201.86,42.75) ; R2408.1 C2402.2 97.56,189.23 v1(97.92,189.23) ; v1(80.85,127.11) J3.90 v1(80.85,124.14) ; R2733.1 v1(164.97,28.07) ; C2003.1 139.93,51.79 v1(140.08,51.94) ; R2624.2 24.56,131.52 24.82,131.26 v1(24.82,130.68) ; R1609.1 75.69,155.24 v1(75.95,155.5) ; v1(218.36,172.29) 218.14,172.06 D8.3 ; C1333.2 v1(116.74,164.4) ; v1(75.46,141.17) R153.2 R156.2 ; v1(102.57,197.21) D2303.8 D2303.3 v1(102.57,199.49) ; C1640.2 R1641.1 88.37,164.87 v1(88.27,164.97) ; C193.1 107.16,140.13 v1(106.78,140.51) ; C2120.2 118.96,51.02 v1(119.25,51.31) ; v1(198.95,25.56) 198.95,25.11 198.97,25.08 198.97,24.4 197.12,22.54 U5.4 195.52,22.54 195.12,22.15 R3219.1 196.55,21.16 v1(196.72,21.34) ; C3613.2 v1(52.2,6.32) ; v1(147.75,14.1) R2208.1 147.73,13.46 C2206.1 ; v1(56.2,20.13) 56.39,20.13 56.64,20.38 Q3606.2 56.52,21.34 R3616.2 56.62,22.86 C3615.2 ; v1(136.25,51.92) 136.68,51.92 137.16,51.43 C2005.1 C2004.1 ; v1(202.74,23.11) 203.02,22.83 C1015.1 ; C2030.2 C2031.2 C2029.2 130.62,39.59 v1(130.68,39.52) ; 209.83,42.95 C30.2 ; 209.83,42.95 C21.2 C22.2 C18.2 ; v1(156.3,89.37) 156.55,89.12 J701.37 ; R2890.1 v1(26.75,81.41) ; v1(100.35,124.28) J3.168 v1(100.35,127.23) ; Q1105.2 223.88,57.68 224.16,57.96 v1(224.16,58.55) ; R1715.1 v1(63.93,161.42) ; R151.1 61.01,152.37 60.71,152.68 v1(60.71,152.78) ; v1(150.11,86.49) 150.15,86.52 J701.21 v1(150.15,89.31) ; v1(93.09,129.62) C179.2 C180.2 ; v1(23.6,175.39) 24.13,174.8 C81.2 24.61,173.77 25.27,173.12 25.88,171.63 25.88,170.56 26.9,169.54 27.89,169.54 28.43,169 U3001.5 28.43,167.27 28.61,167.09 28.97,167.09 29.18,167.31 v1(29.18,167.53) 29.18,167.96 29.44,168.21 C3005.2 ; D2202.3 D2202.8 157.48,18.57 v1(157.61,18.44) ; J803.51 v1(180.03,89.2) ; J3.48 v1(70.35,127.39) ; v1(213.49,41.63) 212.83,42.29 R12.2 ; 150.52,70.23 150.47,70.28 ; C1304.2 v1(141.61,158.33) ; J3.311 55.6,119.34 v1(55.7,119.44) ; U3.L6 v1(203.46,44.35) 203.06,43.95 U3.L5 ; R289.1 v1(169.42,36.63) ; v1(90.17,155.98) 90.2,155.98 90.81,156.59 U1604.2 ; v1(156.26,46.5) 156.53,46.23 R348.2 ; C1607.1 v1(218.49,174.5) ; C1336.2 v1(117.56,164.4) ; D3.3 v1(12.32,158.88) ; v1(93.55,200.99) D2405.3 D2405.8 v1(93.55,198.7) ; C3614.2 60.3,22.86 R3617.1 ; C1323.2 v1(126.19,162.93) ; J701.18 v1(148.95,94.52) ; v1(16.54,92.27) 16.22,91.96 C3404.2 ; v1(123.89,42.35) 123.34,41.81 C2114.2 ; v1(123.89,42.35) 123.34,42.9 C2128.2 ; C1335.2 v1(119.99,164.4) ; v1(162.59,72.64) 162.59,72.26 163.2,71.65 C1001.2 ; J2001.2 v1(175.56,65.99) ; C1502.1 148.4,174.51 C1506.1 147.42,173.94 v1(147.85,173.51) ; v1(66.57,152.27) 66.47,152.37 R276.1 ; v1(73.6,119.93) J3.61 v1(73.6,116.79) ; v1(140.34,173.35) 140.34,173.81 141.03,174.51 C1505.1 ; U2205.2 153.18,22.81 v1(153.18,22.81) ; Q1803.2 v1(24.36,157.86) ; v1(148.95,67.03) 148.84,67.13 R1213.2 ; C1326.2 v1(127.11,163) ; C3304.2 182.28,38.53 R3305.1 181.28,39.06 180.98,39.37 v1(180.72,39.37) ; R1016.1 164.36,74.4 v1(164.34,74.42) ; R297.2 v1(156.08,38.25) ; C2018.2 v1(146.69,45.59) ; v1(83.95,120.07) 83.95,120.01 84.1,119.86 J3.103 v1(84.1,116.71) ; v1(38.8,151.19) 39.49,151.88 C1820.2 39.66,151.07 39.68,151.05 C1819.2 ; R388.1 v1(169.42,37.68) ; C2002.2 142.37,51.03 142.39,51.05 v1(142.39,51.1) ; J3.7 v1(60.1,116.79) ; v1(69.15,116.79) 69.1,116.84 J3.43 v1(69.1,119.89) ; C2909.1 C2910.1 R2932.1 ; R317.2 v1(22.38,127.55) ; v1(59.58,37.34) 59.5,37.43 C80.1 59.5,39.4 Q2101.2 ; X1201.4 151.73,72.3 152.62,73.2 153.09,73.2 153.12,73.23 v1(153.65,73.23) ; C25.2 209.07,54.38 208.25,55.2 C1106.2 ; C3603.2 v1(42.75,6.58) ; v1(144.78,50.04) 145.03,50.04 145.31,49.76 C2016.2 ; R1636.2 v1(131.93,190.22) ; 150.47,70.28 v1(150.52,70.28) ; R2205.2 v1(143,28.32) ; v1(190.12,89.2) 190.12,89.15 190.03,89.06 J803.11 ; v1(174.65,56.97) 174.85,57.17 R1014.1 R1013.1 ; R1374.1 108.25,142.89 v1(108.1,142.75) ; C1612.2 178.56,156.92 v1(178.55,156.91) ; U14.2 99.31,186.69 99.7,186.31 v1(99.7,186.05) ; R130.2 v1(14.57,158.62) ; J2701.33 v1(32.39,38.58) ; R283.1 v1(169.42,38.74) ; v1(212.67,175.44) 212.67,175.28 212.2,174.81 C1513.1 ; C2302.2 R2310.1 v1(123.06,195.58) ; v1(25.48,81.41) R2898.1 R2897.1 ; C1327.2 v1(134.43,160.91) ; R55.2 v1(3.4,151.26) ; Q701.2 190.7,68.81 190.91,69.01 C701.2 190.91,70.74 190.65,70.99 v1(190.12,70.99) ; C2015.2 v1(146.66,44.07) ; C2202.1 R2204.1 164.64,16.83 v1(165.43,16.05) ; C1405.2 v1(123.88,158.21) ; Q3402.2 v1(20.04,83.9) ; J803.57 v1(178.53,89.2) ; v1(167.56,20.59) D2203.3 D2203.8 ; R1709.1 v1(52.71,159.27) ; v1(115.86,187.26) 115.86,187.8 115.52,188.14 C3147.2 114.78,188.14 114.75,188.17 Q3104.2 ; U3103.3 114.83,177.35 v1(115.06,177.11) ; Q1106.2 210.94,54.62 v1(211.33,54.23) 211.43,54.13 C1107.2 ; J2701.7 v1(37.19,30.78) ; U2206.2 v1(206.14,160.14) ; C168.2 16.54,25.55 16.13,25.15 v1(15.75,25.15) ; M21.1 56.31,66.3 ; R1634.2 v1(237.95,184.61) ; v1(90.3,200.99) D2403.3 D2403.8 v1(90.3,198.7) ; C3606.2 v1(60.83,6.73) ; C3004.1 23.19,165.91 v1(23.19,165.25) 23.37,165.07 R3010.1 ; C1337.2 v1(123.25,164.4) ; C1414.2 v1(127.36,159.68) ; v1(118.45,205.1) J2301.11 118.45,201.71 v1(118.44,201.7) ; v1(70.82,142.06) 70.82,142.54 70.2,143.16 R2943.1 ; J3.183 104.1,115.94 v1(103.99,115.82) ; v1(43.87,160.28) C1709.2 ; J3.269 125.6,119.63 125.86,119.89 v1(125.86,119.91) ; C710.2 145.72,84.43 v1(145.72,84.38) ; C2303.2 120.91,190.5 v1(120.84,190.56) ; R296.2 v1(156.08,37.19) ; U3.J7 v1(201.06,45.96) 200.66,45.56 U3.H7 ; J601.51 v1(20.01,153.62) ; J2701.30 v1(34.79,38.4) ; R3120.1 v1(109.17,178.46) ; J3.54 v1(71.85,127.39) ; C1311.2 146.42,148.35 146.42,148.06 v1(146.44,148.03) 146.42,148 146.42,147.71 C1312.2 ; J3.36 v1(67.35,127.39) ; J1901.6 v1(120.35,16.89) ; v1(90.88,129.46) C177.2 C178.2 ; v1(153.35,89.31) J701.29 153.35,86.55 153.29,86.49 153.29,86.38 v1(153.26,86.36) ; C191.1 v1(109.45,140.51) ; C1307.2 v1(146.66,157.99) ; C129.1 v1(162.36,34.16) ; R1364.2 R1365.2 ; C31.2 v1(191.72,45.85) ; R363.2 v1(156.26,50.85) ; C1308.2 v1(146.66,154.1) ; v1(58.17,164.08) C1708.2 ; U2804.4 v1(9.14,37.21) ; C1303.2 v1(151.72,154.07) ; C2008.2 v1(136.02,36.45) ; U2704.4 v1(4.94,106.5) ; v1(107.55,146.82) 107.8,147.07 R1380.1 C1412.2 C1403.2 ; R2037.2 v1(68.43,45.28) ; C19.2 v1(207.42,39.47) ; C1332.2 v1(111.05,164.4) ; R2894.1 v1(5.08,43.18) ; J3.67 v1(75.1,116.79) ; J3.246 v1(119.85,127.11) ; C1419.2 v1(134.15,150.06) ; J3.109 v1(85.6,116.79) ; R131.2 v1(28.62,149.99) ; J803.5 191.53,89.2 v1(191.52,89.2) 191.85,89.2 192.03,89.03 J803.3 192.03,87 191.9,86.87 v1(191.52,86.87) 191.53,86.88 J803.5
  TOP w0.305: 243.87,25.2 J901.38 ; J901.38 246.53,22.55 ; J901.38 246.53,25.2 ; J901.38 243.87,22.55 ; 22.2,197.05 J2.7 ; J2.7 21.07,198.18 ; J2.7 22.2,199.31 ; J2.7 23.33,198.18 ; 23.37,195.78 J2.12 ; J2.12 25.63,195.78 ; J2.12 24.5,194.65 ; J2.12 24.5,196.91 ; J902.4 233.3,31.15 ; J902.4 231.95,29.8 ; J902.4 234.65,29.8 ; R1638.1 v1(87.71,195.47) ; 21.07,200.58 J2.3 ; J2.3 22.2,199.45 ; J2.3 23.33,200.58 ; J2.3 22.2,201.71 ; 231.53,40.7 J903.6 233.11,39.12 ; 24.5,197.05 J2.8 ; J2.8 25.63,198.18 ; J2.8 24.5,199.31 ; J2.8 23.37,198.18 ; J2.11 22.2,196.91 ; J2.11 23.33,195.78 ; J2.11 22.2,194.65 ; J2.11 21.07,195.78 ; J2.4 24.5,201.71 ; J2.4 25.63,200.58 ; J2.4 23.37,200.58 ; J2.4 24.5,199.45 ; v1(210.57,44.7) 209.86,44.7 C29.2 C30.2 ; v1(87.97,197.47) 87.97,197.24 C1631.2 ; J902.2 240.15,29.8 ; J902.2 238.8,28.45 ; J902.2 237.45,29.8
  ART02 w0.305: 101,202.42 J2401.20 ; J2401.20 100.11,204.15 ; J2401.20 101.89,204.15 ; J2401.20 101,205.88 ; 161,11.53 J2202.4 ; J2202.4 160.26,12.26 ; J2202.4 161.74,12.26 ; S3401.1 34,11.22 ; S3401.1 33.03,10.25 ; S3401.1 34.97,10.25 ; S3401.1 34,9.28 ; 220.35,151.08 J2203.11 ; J2203.11 219.58,152.16 ; J2203.11 221.13,152.16 ; J2203.11 220.35,153.24 ; 22.58,10.25 S3601.1 ; S3601.1 23.55,11.22 ; S3601.1 24.52,10.25 ; S3601.1 23.55,9.28 ; 233.11,39.12 J903.6 ; J903.6 231.53,40.7 ; J903.6 233.11,42.27 ; J903.6 234.68,40.7 ; J2202.7 157.5,14.5 ; J2202.7 158.24,13.76 ; J2202.7 157.5,13.03 ; J2202.7 156.76,13.76 ; 11.8,18.9 S3602.3 ; S3602.3 11.8,21.7 ; S3602.3 13.2,20.3 ; S3602.3 10.4,20.3 ; J2401.22 101.89,210.11 ; J2401.22 101,208.79 ; J2401.22 100.11,210.11 ; J2401.22 101,211.43 ; 243.87,25.2 J901.38 ; J901.38 246.53,22.55 ; J901.38 243.87,22.55 ; J901.38 246.53,25.2 ; S3601.3 23.7,13 ; S3601.3 20.9,13 ; S3601.3 22.3,11.6 ; S3601.3 22.3,14.4 ; 39.75,11.6 S3401.4 ; S3401.4 39.75,14.4 ; S3401.4 41.15,13 ; S3401.4 38.35,13 ; 215.93,153.99 J2203.4 ; J2203.4 216.74,154.8 ; J2203.4 216.74,153.18 ; 177.76,13.76 J2201.7 ; J2201.7 179.24,13.76 ; J2201.7 178.5,13.03 ; J2201.7 178.5,14.5 ; 181.26,12.26 J2201.4 ; J2201.4 182.74,12.26 ; J2201.4 182,11.53 ; S3602.4 18.8,21.7 ; S3602.4 20.2,20.3 ; S3602.4 17.4,20.3 ; S3602.4 18.8,18.9 ; 27.9,13 S3601.4 ; S3601.4 30.7,13 ; S3601.4 29.3,11.6 ; S3601.4 29.3,14.4 ; J2401.23 86.5,211.43 ; J2401.23 87.39,210.11 ; J2401.23 86.5,208.79 ; J2401.23 85.61,210.11 ; J2201.11 184.9,12.03 ; J2201.11 183.83,10.26 ; J2201.11 185.97,10.26 ; J2201.11 184.9,8.5 ; J2301.21 111.59,204.14 ; J2301.21 110.7,205.87 ; J2301.21 109.81,204.14 ; J2301.21 110.7,202.41 ; J2202.10 151.1,12.03 ; J2202.10 150.03,10.26 ; J2202.10 152.17,10.26 ; J2202.10 151.1,8.5 ; J2202.11 164.97,10.26 ; J2202.11 163.9,12.03 ; J2202.11 162.83,10.26 ; J2202.11 163.9,8.5 ; J2203.10 215.71,152.16 ; J2203.10 214.16,152.16 ; J2203.10 214.93,153.89 ; J2203.10 214.93,150.43 ; J902.2 240.15,29.8 ; J902.2 238.8,28.45 ; J902.2 237.45,29.8 ; J902.2 238.8,31.15 ; J901.37 245.2,13.68 ; J901.37 247,11.87 ; J901.37 243.4,11.87 ; J901.37 245.2,10.07 ; J2401.21 86.5,205.88 ; J2401.21 86.5,202.42 ; J2401.21 87.39,204.15 ; J2401.21 85.61,204.15 ; S3602.1 14.02,17.55 ; S3602.1 13.05,16.58 ; S3602.1 13.05,18.52 ; S3602.1 12.08,17.55 ; J2301.22 126.09,210.1 ; J2301.22 124.31,210.1 ; J2301.22 125.2,211.42 ; J2301.22 125.2,208.78 ; 109.81,210.1 J2301.23 ; J2301.23 110.7,211.42 ; J2301.23 110.7,208.78 ; J2301.23 111.59,210.1 ; 233.3,28.45 J902.4 ; J902.4 233.3,31.15 ; J902.4 234.65,29.8 ; J902.4 231.95,29.8 ; 124.31,204.14 J2301.20 ; J2301.20 125.2,205.87 ; J2301.20 125.2,202.41 ; J2301.20 126.09,204.14 ; 172.1,8.5 J2201.10 ; J2201.10 172.1,12.03 ; J2201.10 173.17,10.26 ; J2201.10 171.03,10.26 ; J2203.7 219.35,157.49 ; J2203.7 218.54,156.68 ; J2203.7 218.54,158.3 ; 31.35,13 S3401.3 ; S3401.3 32.75,14.4 ; S3401.3 32.75,11.6 ; S3401.3 34.15,13
  ART03 w0.305: 22.2,194.65 J2.11 ; J2.11 22.2,196.91 ; J2.11 21.07,195.78 ; J2.11 23.33,195.78 ; J2.7 23.33,198.18 ; J2.7 21.07,198.18 ; J2.7 22.2,199.31 ; J2.7 22.2,197.05 ; J2401.20 101,205.88 ; J2401.20 101.89,204.15 ; J2401.20 101,202.42 ; J2401.20 100.11,204.15 ; J2.3 23.33,200.58 ; J2.3 22.2,199.45 ; J2.3 21.07,200.58 ; J2.3 22.2,201.71 ; 86.5,202.42 J2401.21 ; J2401.21 85.61,204.15 ; J2401.21 86.5,205.88 ; J2401.21 87.39,204.15 ; J2.12 25.63,195.78 ; J2.12 24.5,196.91 ; J2.12 23.37,195.78 ; J2.12 24.5,194.65 ; J2.4 25.63,200.58 ; J2.4 24.5,201.71 ; J2.4 24.5,199.45 ; J2.4 23.37,200.58 ; 23.37,198.18 J2.8 ; J2.8 25.63,198.18 ; J2.8 24.5,197.05 ; J2.8 24.5,199.31 ; J2203.10 215.71,152.16 ; J2203.10 214.93,150.43 ; J2203.10 214.16,152.16 ; J2203.10 214.93,153.89 ; 11.8,18.9 S3602.3 ; S3602.3 11.8,21.7 ; S3602.3 10.4,20.3 ; S3602.3 13.2,20.3 ; 109.81,204.14 J2301.21 ; J2301.21 110.7,205.87 ; J2301.21 110.7,202.41 ; J2301.21 111.59,204.14 ; 23.55,9.28 S3601.1 22.58,10.25 ; S3602.1 13.05,18.52 ; S3602.1 13.05,16.58 ; S3602.1 12.08,17.55 ; S3602.1 14.02,17.55 ; J2203.11 221.13,152.16 ; J2203.11 220.35,151.08 ; J2203.11 219.58,152.16 ; 216.74,153.18 J2203.4 ; J2203.4 215.93,153.99 ; J2203.4 216.74,154.8
  ART04 w0.254: v1(177.52,20.81) 177.52,20 SG1.2
  ART04 w0.305: J2.4 24.5,201.71 ; J2.4 23.37,200.58 ; J2.4 25.63,200.58 ; J2.4 24.5,199.45 ; J2.12 24.5,196.91 ; J2.12 24.5,194.65 ; J2.12 25.63,195.78 ; J2.12 23.37,195.78 ; 23.37,198.18 J2.8 ; J2.8 24.5,197.05 ; J2.8 24.5,199.31 ; J2.8 25.63,198.18 ; 21.07,195.78 J2.11 ; J2.11 23.33,195.78 ; J2.11 22.2,196.91 ; J2.11 22.2,194.65 ; 21.07,198.18 J2.7 ; J2.7 22.2,197.05 ; J2.7 23.33,198.18 ; J2.7 22.2,199.31 ; 23.55,9.28 S3601.1 22.58,10.25 ; 22.2,199.45 J2.3 ; J2.3 22.2,201.71 ; J2.3 23.33,200.58 ; J2.3 21.07,200.58
  ART05 w0.305: 31.35,13 S3401.3 ; S3401.3 34.15,13 ; S3401.3 32.75,11.6 ; S3401.3 32.75,14.4 ; 183.83,10.26 J2201.11 ; J2201.11 184.9,12.03 ; J2201.11 184.9,8.5 ; J2201.11 185.97,10.26 ; J901.37 245.2,13.68 ; J901.37 243.4,11.87 ; J901.37 245.2,10.07 ; J901.37 247,11.87 ; S3601.4 29.3,14.4 ; S3601.4 29.3,11.6 ; S3601.4 27.9,13 ; S3601.4 30.7,13 ; S3602.4 20.2,20.3 ; S3602.4 17.4,20.3 ; S3602.4 18.8,18.9 ; S3602.4 18.8,21.7 ; 23.55,9.28 S3601.1 ; S3601.1 23.55,11.22 ; S3601.1 24.52,10.25 ; S3601.1 22.58,10.25 ; S3401.4 39.75,14.4 ; S3401.4 39.75,11.6 ; S3401.4 38.35,13 ; S3401.4 41.15,13 ; J2203.7 218.54,158.3 ; J2203.7 219.35,157.49 ; J2203.7 218.54,156.68 ; J2202.7 157.5,14.5 ; J2202.7 156.76,13.76 ; J2202.7 158.24,13.76 ; J2202.7 157.5,13.03 ; J903.6 233.11,42.27 ; J903.6 234.68,40.7 ; J903.6 231.53,40.7 ; J903.6 233.11,39.12 ; 100.11,204.15 J2401.20 ; J2401.20 101,202.42 ; J2401.20 101.89,204.15 ; J2401.20 101,205.88 ; J2201.4 182.74,12.26 ; J2201.4 182,11.53 ; J2201.4 181.26,12.26 ; 10.4,20.3 S3602.3 ; S3602.3 11.8,18.9 ; S3602.3 11.8,21.7 ; S3602.3 13.2,20.3 ; 85.61,210.11 J2401.23 ; J2401.23 87.39,210.11 ; J2401.23 86.5,208.79 ; J2401.23 86.5,211.43 ; 177.76,13.76 J2201.7 ; J2201.7 178.5,13.03 ; J2201.7 178.5,14.5 ; J2201.7 179.24,13.76 ; J2401.22 101.89,210.11 ; J2401.22 101,208.79 ; J2401.22 100.11,210.11 ; J2401.22 101,211.43 ; J2202.10 152.17,10.26 ; J2202.10 151.1,8.5 ; J2202.10 151.1,12.03 ; J2202.10 150.03,10.26 ; J2301.23 111.59,210.1 ; J2301.23 110.7,211.42 ; J2301.23 110.7,208.78 ; J2301.23 109.81,210.1 ; 214.16,152.16 J2203.10 ; J2203.10 214.93,153.89 ; J2203.10 215.71,152.16 ; J2203.10 214.93,150.43 ; J2202.4 161.74,12.26 ; J2202.4 161,11.53 ; J2202.4 160.26,12.26 ; J2202.11 163.9,12.03 ; J2202.11 162.83,10.26 ; J2202.11 163.9,8.5 ; J2202.11 164.97,10.26 ; 109.81,204.14 J2301.21 ; J2301.21 110.7,205.87 ; J2301.21 111.59,204.14 ; J2301.21 110.7,202.41 ; 243.87,25.2 J901.38 ; J901.38 243.87,22.55 ; J901.38 246.53,25.2 ; J901.38 246.53,22.55 ; 172.1,8.5 J2201.10 ; J2201.10 171.03,10.26 ; J2201.10 173.17,10.26 ; J2201.10 172.1,12.03 ; S3601.3 22.3,14.4 ; S3601.3 22.3,11.6 ; S3601.3 20.9,13 ; S3601.3 23.7,13 ; 237.45,29.8 J902.2 ; J902.2 238.8,28.45 ; J902.2 238.8,31.15 ; J902.2 240.15,29.8 ; J2203.11 221.13,152.16 ; J2203.11 219.58,152.16 ; J2203.11 220.35,153.24 ; J2203.11 220.35,151.08 ; 12.08,17.55 S3602.1 ; S3602.1 14.02,17.55 ; S3602.1 13.05,16.58 ; S3602.1 13.05,18.52 ; 124.31,204.14 J2301.20 ; J2301.20 125.2,202.41 ; J2301.20 126.09,204.14 ; J2301.20 125.2,205.87 ; J2301.22 125.2,211.42 ; J2301.22 125.2,208.78 ; J2301.22 124.31,210.1 ; J2301.22 126.09,210.1 ; J2401.21 86.5,205.88 ; J2401.21 85.61,204.15 ; J2401.21 87.39,204.15 ; J2401.21 86.5,202.42 ; 233.3,28.45 J902.4 ; J902.4 231.95,29.8 ; J902.4 233.3,31.15 ; J902.4 234.65,29.8 ; 215.93,153.99 J2203.4 ; J2203.4 216.74,154.8 ; J2203.4 216.74,153.18 ; 33.03,10.25 S3401.1 ; S3401.1 34,11.22 ; S3401.1 34.97,10.25 ; S3401.1 34,9.28
  BOTTOM w0.254: v1(32.51,29.79) 32.26,30.33 ; v1(9.55,208.81) 10.01,208.56 ; v1(135.21,3.04) 135.24,3.07 135.24,7.32 136.25,8.33 ; v1(165.44,5.83) 164.89,5.28 159.46,5.28 ; 79.88,8.97 v1(79.32,8.86) ; v1(17.53,169.42) 18.11,169.65
  BOTTOM w0.305: 22.2,194.65 J2.11 ; J2.11 22.2,196.91 ; J2.11 21.07,195.78 ; J2.11 23.33,195.78 ; J2.4 25.63,200.58 ; J2.4 24.5,199.45 ; J2.4 23.37,200.58 ; J2.4 24.5,201.71 ; J2.12 25.63,195.78 ; J2.12 24.5,194.65 ; J2.12 24.5,196.91 ; J2.12 23.37,195.78 ; J2.8 25.63,198.18 ; J2.8 24.5,199.31 ; J2.8 23.37,198.18 ; J2.8 24.5,197.05 ; J2.7 22.2,199.31 ; J2.7 21.07,198.18 ; J2.7 22.2,197.05 ; J2.7 23.33,198.18 ; 21.07,200.58 J2.3 ; J2.3 22.2,201.71 ; J2.3 23.33,200.58 ; J2.3 22.2,199.45
  BOTTOM w0.381: v1(228.19,52.25) 228.19,51.05 225.98,48.84 TP19.1
  vias: v1(0.76,203) v1(0.76,200.46) v1(0.76,197.92) v1(0.79,196.95) v1(0.81,21.69) v1(1.21,190.34) v1(1.37,205.08) v1(2.29,205.51) v1(2.47,22.54) v1(2.76,177.37) v1(2.76,174.83) v1(2.79,172.21) v1(2.79,171.58) v1(2.79,170.94) v1(2.79,170.31) v1(2.79,169.67) v1(2.79,169.04) v1(2.79,168.4) v1(2.79,167.77) v1(2.79,167) v1(2.76,164.67) v1(2.76,157.05) v1(2.76,149.43) v1(2.79,143.64) v1(2.76,141.81) v1(2.76,139.27) v1(2.76,136.73) v1(2.76,131.65) v1(2.76,129.11) v1(2.76,126.57) v1(2.76,124.03) v1(2.76,121.49) v1(2.76,118.95) v1(2.76,116.41) v1(2.76,113.87) v1(2.76,111.33) v1(2.76,108.79) v1(2.76,106.25) v1(2.76,103.71) v1(2.76,101.17) v1(2.76,98.63) v1(2.76,96.09) v1(2.76,93.55) v1(2.76,91.01) v1(2.76,88.47) v1(2.76,85.93) v1(2.76,83.39) v1(2.76,80.85) v1(2.76,78.31) v1(2.76,75.77) v1(2.76,73.23) v1(2.76,70.69) v1(2.76,68.15) v1(2.76,43.85) v1(2.76,41.31) v1(2.76,38.77) v1(2.76,36.23) v1(2.9,33.69) v1(3.32,63.13) v1(3.56,179.45) v1(3.74,190.04) v1(4.92,45.19) v1(4.99,22.82) v1(5.24,32.69) v1(5.54,206.74) v1(6.14,189.23) v1(6.1,119) v1(6.1,117.73) v1(6.1,116.46) v1(6.1,115.19) v1(6.36,180.52) v1(6.6,150.37) v1(7.06,212.01) v1(7.13,24.19) v1(7.24,150.37) v1(7.3,31.22) v1(7.78,60.99) v1(7.89,187.38) v1(8.01,182.45) v1(8.08,206.74) v1(8.44,28.94) v1(8.37,26.4) v1(8.56,184.93) v1(8.56,48.52) v1(8.79,58.66) v1(8.86,56.12) v1(8.86,53.58) v1(8.86,51.04) v1(9.76,211.19) v1(10.16,141.45) v1(10.44,135.28) v1(10.44,134.64) v1(10.5,10.16) v1(10.8,141.45) v1(11.68,141.99) v1(12.07,114.3) v1(12.16,212.04) v1(12.45,172.47) v1(12.45,169.93) v1(12.38,142.68) v1(12.62,133.68) v1(12.62,133.04) v1(12.67,128.35) v1(12.67,127.08) v1(12.67,125.81) v1(12.7,114.3) v1(12.83,160.53) v1(13.04,10.16) v1(13.21,172.47) v1(13.21,169.93) v1(13.59,160.53) v1(13.65,142.68) v1(13.82,115.14) v1(13.94,128.35) v1(13.94,127.08) v1(13.94,125.81) v1(14.61,150.37) v1(14.7,212.04) v1(14.73,156.08) v1(14.99,141.6) v1(15.21,128.35) v1(15.21,127.08) v1(15.21,125.81) v1(15.58,10.16) v1(15.88,141.6) v1(16,158.5) v1(16.51,141.35) v1(16.94,156.01) v1(17.02,171.45) v1(17.02,170.69) v1(17.02,169.93) v1(17.24,212.04) v1(17.4,171.96) v1(17.65,157.1) v1(18.03,142.8) v1(18.03,142.16) v1(18.12,10.16) v1(18.16,168.27) v1(18.42,167.51) v1(18.54,158.88) v1(19.43,51.82) v1(19.43,50.93) v1(19.69,158.88) v1(19.78,212.04) v1(19.94,157.99) v1(20.02,142.72) v1(20.02,142.09) v1(20.08,154.8) v1(20.45,120.27) v1(20.45,119.63) v1(20.5,165.89) v1(20.5,165.23) v1(20.66,10.16) v1(21.13,165.89) v1(21.13,165.23) v1(21.08,132.61) v1(21.08,131.98) v1(21.64,136.63) v1(21.62,135.97) v1(22.32,212.04) v1(22.35,154.81) v1(22.48,51.94) v1(22.48,51.31) v1(22.56,5.94) v1(22.73,92.84) v1(22.75,56.09) v1(22.75,55.46) v1(23.51,56.09) v1(23.51,55.46) v1(24,142.87) v1(24.38,142.37) v1(24.86,212.04) v1(25.1,51.38) v1(25.1,49.86) v1(25.1,5.56) v1(25.91,151.26) v1(25.93,142.37) v1(25.93,141.73) v1(26.24,90.17) v1(26.62,51.38) v1(26.62,49.86) v1(27.09,102.08) v1(27.09,101.32) v1(27.11,62.32) v1(27.11,61.56) v1(27.4,212.04) v1(27.43,20.4) v1(27.64,5.56) v1(28.45,153.67) v1(28.4,151.69) v1(28.7,128.78) v1(28.7,128.14) v1(28.96,20.4) v1(29.72,20.4) v1(29.94,212.04) v1(30.18,5.56) v1(30.8,81.09) v1(30.8,78.55) v1(30.8,77.79) v1(30.9,102.08) v1(30.9,101.32) v1(30.92,62.32) v1(30.92,61.56) v1(30.98,96.41) v1(30.98,95.64) v1(31.19,166.15) v1(31.19,165.52) v1(31.69,62.32) v1(31.69,61.56) v1(31.8,177.16) v1(31.8,176.53) v1(32.07,84.42) v1(32.07,83.65) v1(32.44,129.92) v1(32.44,129.29) v1(32.44,128.65) v1(32.44,127) v1(32.64,116.08) v1(32.72,5.56) v1(33.02,117.86) v1(33.15,120.52) v1(33.15,119.76) v1(33.66,113.8) v1(33.66,112.74) v1(33.66,111.38) v1(33.66,110.36) v1(34.35,102.08) v1(34.35,101.32) v1(34.41,96.2) v1(34.41,95.44) v1(34.61,117.28) v1(34.73,78.55) v1(34.73,77.79) v1(34.73,62.32) v1(34.73,61.56) v1(35.26,5.56) v1(35.89,159.41) v1(35.88,158.31) v1(35.88,157.29) v1(36.35,126.8) v1(36.89,84.42) v1(36.89,83.65) v1(37.03,126.8) v1(37.15,117.28) v1(37.69,126.8) v1(37.8,5.56) v1(38.38,129.82) v1(38.38,129.18) v1(38.38,128.42) v1(38.54,62.29) v1(38.54,61.53) v1(38.93,96.51) v1(38.93,95.75) v1(39.05,78.55) v1(39.05,77.79) v1(39.2,102.34) v1(39.2,101.57) v1(39.24,28.57) v1(39.62,133.35) v1(39.69,142.05) v1(39.69,140.78) v1(39.69,139.51) v1(39.69,129.98) v1(39.69,117.28) v1(39.69,116.65) v1(39.75,144.4) v1(39.75,143.76) v1(39.88,137.16) v1(39.88,136.4) v1(39.96,51.31) v1(39.96,50.67) v1(39.96,50.04) v1(40.15,5.56) v1(40.39,144.4) v1(40.39,143.76) v1(40.51,133.35) v1(40.45,129.98) v1(40.86,139.69) v1(40.86,137.15) v1(40.86,135.88) v1(41.34,123.86) v1(41.8,65.02) v1(42.23,117.28) v1(42.23,116.65) v1(42.34,59.18) v1(42.34,58.55) v1(42.34,57.91) v1(42.34,55.37) v1(42.34,54.74) v1(42.34,54.1) v1(42.44,65.02) v1(42.35,62.29) v1(42.35,61.53) v1(42.55,23.75) v1(42.61,123.86) v1(42.62,5.56) v1(42.74,96.51) v1(42.74,95.75) v1(42.74,22.16) v1(42.74,20.89) v1(43.07,65.02) v1(43.56,24.76) v1(43.88,117.28) v1(43.88,116.65) v1(44.01,78.55) v1(44.01,77.79) v1(44.15,102.08) v1(44.15,101.32) v1(44.2,24.76) v1(44.41,3.76) v1(44.41,1.22) v1(45.59,26.54) v1(46.23,26.54) v1(46.61,20.19) v1(46.86,26.54) v1(46.91,0.76) v1(48.26,20.19) v1(48.39,24.13) v1(48.9,22.22) v1(49.39,3.86) v1(49.39,1.32) v1(51.27,5.56) v1(53.78,5.15) v1(54.31,160.65) v1(54.41,2.69) v1(55.37,58.93) v1(55.37,55.75) v1(55.37,51.94) v1(55.37,50.42) v1(55.58,160.65) v1(56.07,0.76) v1(56.64,135.89) v1(56.64,135.25) v1(56.85,160.65) v1(57.83,58.93) v1(57.83,55.75) v1(57.83,51.94) v1(57.83,50.42) v1(58.61,0.76) v1(58.8,142.37) v1(58.8,141.35) v1(59.26,135.33) v1(59.29,131.9) v1(59.39,3.18) v1(59.69,135.76) v1(60.17,58.93) v1(60.17,55.75) v1(60.17,51.94) v1(60.17,50.42) v1(60.83,55.75) v1(60.83,51.94) v1(60.83,50.42) v1(60.83,5.59) v1(60.96,58.93) v1(61.53,131.89) v1(61.53,131.13) v1(63.07,5.51) v1(63.18,131.89) v1(63.18,131.13) v1(63.22,110.28) v1(63.42,147.34) v1(63.48,112.43) v1(64.41,3.36) v1(64.5,0.82) v1(64.69,147.34) v1(65.18,110.28) v1(65.43,112.43) v1(65.85,129.93) v1(65.96,147.34) v1(66.91,112.43) v1(66.91,110.28) v1(67.03,0.76) v1(67.35,129.93) v1(68.85,129.93) v1(68.86,110.28) v1(69.16,1.68) v1(70.1,147.45) v1(70.1,146.3) v1(70.35,129.93) v1(70.89,112.43) v1(71.85,129.93) v1(71.92,3.05) v1(72.06,132.08) v1(72.37,112.43) v1(72.77,7.24) v1(73.35,129.93) v1(73.41,58.93) v1(73.41,56.77) v1(73.41,55.12) v1(73.41,53.09) v1(73.41,51.31) v1(74.32,112.43) v1(74.46,3.05) v1(75.75,110.08) v1(75.71,58.93) v1(75.71,56.77) v1(75.71,55.12) v1(75.71,53.09) v1(75.71,51.31) v1(75.92,112.43) v1(76.52,138.29) v1(76.52,136.65) v1(76.79,3.04) v1(77.06,112.45) v1(77.7,110.08) v1(78.04,58.93) v1(78.04,56.77) v1(78.04,55.12) v1(78.04,53.09) v1(78.04,51.31) v1(78.05,165.15) v1(78.05,163.67) v1(78.74,58.93) v1(78.74,56.77) v1(78.74,55.12) v1(78.74,53.09) v1(78.74,51.31) v1(78.9,138.95) v1(78.99,163.07) v1(79.12,165.15) v1(79.33,3.04) v1(79.38,133.98) v1(79.63,136.27) v1(80.01,133.98) v1(80.26,136.27) v1(80.77,128.6) v1(81.32,114.02) v1(81.37,111.58) v1(81.87,3.04) v1(82.7,114.32) v1(83.13,129.16) v1(83.41,148.08) v1(83.99,114.31) v1(84.41,3.04) v1(84.46,147.19) v1(84.71,128.9) v1(85.5,114.27) v1(85.5,48.67) v1(85.82,212.04) v1(86.31,128.9) v1(86.95,3.04) v1(87.25,128.9) v1(87.2,114.3) v1(88.32,194.61) v1(88.32,127.1) v1(88.29,51.64) v1(88.29,50.37) v1(88.29,49.1) v1(88.36,212.04) v1(88.9,113.92) v1(89.07,48.05) v1(89.51,8.81) v1(89.49,3.04) v1(89.76,52.3) v1(90.14,8.81) v1(90.22,148.56) v1(90.53,151.54) v1(90.53,150.37) v1(90.5,29.31) v1(90.8,194.61) v1(90.78,8.81) v1(90.9,212.04) v1(90.86,148.56) v1(91.06,153.29) v1(91.16,151.54) v1(91.16,150.37) v1(91.19,54.23) v1(91.16,46.91) v1(91.31,113.92) v1(91.41,8.81) v1(92.15,52.15) v1(92.28,32.87) v1(92.96,144.78) v1(93.44,212.04) v1(93.37,194.61) v1(93.55,46.79) v1(93.58,58.8) v1(93.58,57.53) v1(93.6,54.2) v1(93.85,111.25) v1(93.85,30.61) v1(94.49,30.61) v1(94.62,144.65) v1(94.67,52.2) v1(95.11,169.28) v1(95.12,168.53) v1(95.1,30.61) v1(95.25,47.88) v1(95.5,29.59) v1(95.73,30.61) v1(95.98,212.04) v1(96.01,194.59) v1(95.99,48.54) v1(96.12,58.8) v1(96.12,57.53) v1(96.11,56.27) v1(96.11,55) v1(96.53,137.07) v1(96.52,111.25) v1(96.55,52.22) v1(96.56,137.63) v1(97.04,136.79) v1(97.05,137.41) v1(97.16,148.11) v1(97.16,147.47) v1(97.6,182) v1(97.6,181.24) v1(97.6,180.48) v1(97.6,179.72) v1(97.91,135.34) v1(97.89,52.73) v1(98.52,212.04) v1(98.6,194.59) v1(98.83,40) v1(98.83,38.94) v1(99.7,47.8) v1(99.82,52.09) v1(100.33,135.15) v1(100.33,133.41) v1(100.41,47.83) v1(100.61,193.29) v1(101.06,212.04) v1(101.52,163.12) v1(101.52,161.85) v1(102.11,147.07) v1(102.13,144.86) v1(102.13,46.23) v1(102.79,163.12) v1(102.79,161.85) v1(102.77,144.86) v1(102.77,46.23) v1(102.87,194.06) v1(102.99,210.39) v1(102.99,207.85) v1(102.99,205.31) v1(103.19,41.72) v1(103.4,46.23) v1(104.15,203.05) v1(104.15,166.69) v1(104.15,165.42) v1(104.27,177.62) v1(104.27,176.99) v1(104.27,176.22) v1(104.46,41.72) v1(104.65,171.45) v1(104.65,170.69) v1(105.14,51.71) v1(105.1,49.58) v1(105.12,41.81) v1(105.12,38.64) v1(105.23,36.83) v1(105.23,36.19) v1(105.31,199.64) v1(105.49,194.08) v1(105.6,166.69) v1(105.6,165.42) v1(105.64,47.57) v1(105.65,180.53) v1(105.65,179.13) v1(105.71,40.78) v1(105.82,43.84) v1(105.84,36.83) v1(105.84,36.19) v1(106.25,39.84) v1(106.3,171.4) v1(106.3,170.64) v1(106.31,50.63) v1(106.39,46.31) v1(106.43,42.99) v1(106.66,202.69) v1(107.55,151.88) v1(107.55,150.61) v1(107.55,149.43) v1(107.55,148.07) v1(108.05,194.06) v1(108.41,204.54) v1(108.51,209.62) v1(108.51,207.08) v1(108.59,29.78) v1(108.72,50.63) v1(108.66,39.84) v1(108.8,46.31) v1(108.84,42.99) v1(109.09,186.44) v1(109.09,185.8) v1(109.09,56.64) v1(109.28,212.04) v1(109.35,131.96) v1(109.6,199.77) v1(109.6,29.78) v1(109.65,190.6) v1(110.74,199.77) v1(110.74,197.61) v1(110.74,186.44) v1(110.74,185.8) v1(110.85,131.96) v1(110.85,130.44) v1(110.81,29.78) v1(111.29,34.39) v1(111.45,56.62) v1(111.63,157.35) v1(111.6,52.68) v1(111.82,212.04) v1(112.05,152.82) v1(112.01,50.32) v1(112.08,29.78) v1(112.35,131.96) v1(112.35,130.44) v1(112.3,4.98) v1(112.41,134.3) v1(112.35,3.04) v1(112.5,51.47) v1(112.49,37.55) v1(112.49,35.14) v1(112.68,152.82) v1(113.35,29.73) v1(113.56,178.7) v1(113.57,4.98) v1(113.7,34.39) v1(113.85,131.96) v1(113.85,130.44) v1(113.92,15.37) v1(114.05,57.02) v1(114.33,178.7) v1(114.36,212.04) v1(114.35,157.38) v1(114.91,51.47) v1(114.89,3.04) v1(114.96,178.7) v1(114.99,157.38) v1(115.02,44.54) v1(115.02,43.27) v1(115.02,42) v1(115.35,130.44) v1(115.67,200.58) v1(115.75,52.59) v1(116.29,44.54) v1(116.29,43.27) v1(116.29,42) v1(116.9,212.04) v1(116.93,51.92) v1(116.93,49.51) v1(117.32,200.18) v1(117.43,3.04) v1(117.56,44.54) v1(117.56,43.27) v1(117.56,42) v1(118.16,52.59) v1(119.44,212.04) v1(119.48,200.56) v1(119.89,176.15) v1(119.97,3.04) v1(120.09,182.49) v1(120.73,182.49) v1(120.9,181.74) v1(120.85,159.61) v1(120.85,158.98) v1(120.92,52.16) v1(120.92,49.75) v1(121.51,149.05) v1(121.51,147.78) v1(121.51,146.51) v1(121.98,212.04) v1(122.12,52.53) v1(122.51,3.04) v1(122.78,149.05) v1(122.78,147.78) v1(122.78,146.51) v1(123.05,49.07) v1(123.05,46) v1(124.05,149.05) v1(124.05,147.78) v1(124.05,146.51) v1(124.52,212.04) v1(125.27,121.49) v1(125.46,49.07) v1(125.46,46) v1(125.86,50.29) v1(126.29,47.2) v1(126.46,44.79) v1(127.32,32.96) v1(127.5,133.46) v1(127.51,52.07) v1(127.59,3.04) v1(128.33,39.69) v1(128.33,38.93) v1(128.8,52.07) v1(129.48,59.75) v1(129.92,55.88) v1(130.49,59.75) v1(130.49,58.1) v1(130.56,136.02) v1(130.56,135) v1(131.32,82.22) v1(131.45,96.07) v1(131.45,93.59) v1(131.45,91.1) v1(131.45,3.94) v1(131.45,3.25) v1(132.05,84.89) v1(132.08,56.39) v1(132.23,135.18) v1(132.21,90.68) v1(132.21,89.15) v1(132.59,132.08) v1(132.56,83.49) v1(132.67,3.04) v1(132.91,127.8) v1(133.21,18.29) v1(133.27,144.6) v1(133.41,32.91) v1(133.48,132.08) v1(133.45,130.48) v1(133.63,135.18) v1(133.67,18.65) v1(133.67,17.96) v1(133.67,17.27) v1(133.99,55.88) v1(134.62,123.7) v1(134.59,122.91) v1(134.59,122.35) v1(134.94,32.85) v1(135.13,91.31) v1(135.13,90.55) v1(135.66,56.51) v1(135.66,55.88) v1(136.14,25.78) v1(136.21,32.91) v1(136.2,9.04) v1(136.45,7.9) v1(137.06,7.9) v1(137.29,45.49) v1(137.29,44.22) v1(137.29,42.95) v1(137.5,25.77) v1(137.72,7.9) v1(138.05,35.81) v1(138.14,25.77) v1(138.56,45.49) v1(138.56,44.22) v1(138.56,42.95) v1(138.76,60.96) v1(138.9,152.26) v1(138.9,149.46) v1(139.06,53.26) v1(139.37,60.96) v1(139.88,45.49) v1(139.88,44.22) v1(139.88,42.95) v1(140.03,60.96) v1(140.08,53.21) v1(140.29,3.04) v1(142.11,53.09) v1(142.22,166.07) v1(142.24,51.94) v1(142.42,80.8) v1(142.37,79.88) v1(142.72,35.99) v1(142.83,3.06) v1(143,74.7) v1(143,73.43) v1(143,72.16) v1(143.26,32.13) v1(143.36,35.99) v1(143.64,28.32) v1(143.89,38.99) v1(143.96,148.03) v1(144.2,80.85) v1(144.27,74.7) v1(144.27,73.43) v1(144.27,72.16) v1(144.27,28.32) v1(144.45,80.29) v1(144.48,7.72) v1(144.65,51.82) v1(144.65,51.05) v1(144.76,166.07) v1(144.78,52.73) v1(145.24,60.98) v1(145.19,52.22) v1(145.24,7.75) v1(145.24,6.37) v1(145.2,3.05) v1(145.29,36.07) v1(145.54,74.7) v1(145.54,73.43) v1(145.54,72.16) v1(145.92,36.07) v1(145.92,6.37) v1(145.97,80.77) v1(145.97,58.98) v1(145.97,57.45) v1(146,7.72) v1(146.3,51.31) v1(146.41,80.31) v1(146.38,50.49) v1(146.61,6.37) v1(146.79,50.93) v1(146.99,84.7) v1(147.12,61.16) v1(147.08,22.8) v1(147.08,21.28) v1(147.08,20.64) v1(147.19,86.72) v1(147.3,166.07) v1(147.32,24.38) v1(147.59,16.2) v1(147.57,15.34) v1(147.74,3.05) v1(147.83,49.91) v1(147.83,49.02) v1(147.83,45.29) v1(147.83,43.71) v1(147.83,31.62) v1(148.08,42.04) v1(148.39,15.32) v1(148.47,166.07) v1(148.91,32.83) v1(149.01,146.91) v1(149.61,41.02) v1(149.57,24.97) v1(149.57,22.81) v1(149.57,20.65) v1(149.89,59.92) v1(149.92,32.83) v1(149.96,0.84) v1(150.06,39.12) v1(150.08,16.2) v1(150.34,84.94) v1(150.36,83.07) v1(150.44,60.55) v1(151.01,166.07) v1(152.15,51.94) v1(152.15,51.18) v1(152.49,0.76) v1(152.59,34.56) v1(152.61,33.95) v1(152.96,30.78) v1(153.19,34.58) v1(153.55,166.07) v1(153.67,32.26) v1(153.67,26.97) v1(154.43,84.87) v1(154.43,82.39) v1(154.55,26.97) v1(154.81,66.42) v1(155.03,0.76) v1(155.07,181.86) v1(155.26,84.77) v1(155.26,82.87) v1(155.26,82.04) v1(155.83,181.86) v1(156.08,41.83) v1(156.08,27) v1(156.46,71.83) v1(156.59,65.53) v1(157.05,16.33) v1(157.23,65.53) v1(157.35,27) v1(157.57,0.76) v1(157.76,73.15) v1(157.76,72.52) v1(158.62,74.69) v1(158.62,27) v1(158.88,62.74) v1(159.39,72.7) v1(159.44,71.86) v1(159.44,71.32) v1(159.56,16.33) v1(159.89,27) v1(160.02,61.59) v1(160.02,24.71) v1(160.02,22.3) v1(160.06,18.44) v1(160.11,0.76) v1(160.25,64.15) v1(160.55,56.11) v1(160.81,64.15) v1(160.78,20.65) v1(160.96,72.26) v1(160.96,71.73) v1(160.96,71.2) v1(161.11,75.06) v1(161.11,74.47) v1(161.09,56.11) v1(161.37,64.13) v1(161.62,56.11) v1(161.93,40.82) v1(161.93,39.55) v1(161.93,38.28) v1(161.95,54) v1(162.15,56.11) v1(162.31,50.06) v1(162.31,48.79) v1(162.31,47.52) v1(162.43,61.59) v1(162.48,54) v1(162.61,71.2) v1(162.65,0.76) v1(162.69,56.11) v1(163.02,54) v1(163.2,40.82) v1(163.2,39.55) v1(163.2,38.28) v1(163.58,50.06) v1(163.58,48.79) v1(163.58,47.52) v1(163.72,23.3) v1(163.75,22.11) v1(163.96,90.68) v1(164.62,23.29) v1(164.72,92.2) v1(164.72,91.44) v1(164.72,90.68) v1(164.65,22.1) v1(165.19,0.76) v1(165.44,26.65) v1(165.44,3.29) v1(166.41,8.17) v1(167.36,59.49) v1(167.45,17.78) v1(167.38,16.05) v1(167.51,61.29) v1(167.64,27.3) v1(167.92,59.49) v1(168.48,59.49) v1(168.95,8.34) v1(169.01,59.46) v1(169.29,17.78) v1(169.42,27.3) v1(170.38,54.1) v1(170.49,79.12) v1(170.49,78.49) v1(170.49,77.85) v1(170.46,6.31) v1(170.46,3.77) v1(170.46,1.23) v1(170.71,55.93) v1(172.96,0.76) v1(173.66,70.74) v1(174.5,72.26) v1(174.5,34.92) v1(174.61,91.37) v1(175.06,72.26) v1(175.5,0.76) v1(175.62,72.26) v1(176.07,69.16) v1(176.63,69.16) v1(177.19,69.16) v1(178.04,0.76) v1(179.12,56.31) v1(179.32,84.2) v1(179.27,34.87) v1(179.45,72.85) v1(180.24,84.2) v1(180.39,56.31) v1(180.39,55.04) v1(180.58,0.76) v1(180.72,72.85) v1(181.34,81.09) v1(181.66,55.04) v1(181.99,72.85) v1(182.12,84.2) v1(182.52,81.45) v1(182.74,55.04) v1(182.77,84.15) v1(182.88,62.71) v1(183.12,0.76) v1(183.26,160.07) v1(183.26,158.62) v1(183.26,72.85) v1(184.09,81.43) v1(184.2,55.04) v1(184.53,72.85) v1(184.66,26.36) v1(184.76,84.38) v1(184.96,63.5) v1(185.22,26.36) v1(185.5,63.5) v1(185.66,0.76) v1(185.8,78.87) v1(185.8,77.98) v1(185.75,26.36) v1(186.03,63.5) v1(186.56,83.24) v1(186.56,63.5) v1(186.69,26.54) v1(188.04,65.07) v1(188.04,64.54) v1(188.04,64.01) v1(188.04,63.47) v1(188.09,97.03) v1(188.47,89.31) v1(188.47,86.69) v1(190.37,25.91) v1(192.11,82.49) v1(192.11,81.77) v1(195.2,27.43) v1(195.83,27.43) v1(197.63,87.76) v1(197.63,86.49) v1(197.63,85.27) v1(197.63,84) v1(197.63,82.73) v1(197.63,81.46) v1(197.63,80.19) v1(197.72,153.8) v1(197.76,152.73) v1(197.79,150.37) v1(197.87,158.01) v1(197.89,156.13) v1(199.08,27.29) v1(199.64,144.57) v1(199.64,142.03) v1(199.64,139.49) v1(199.64,136.95) v1(199.64,134.41) v1(199.64,124.25) v1(199.64,121.71) v1(199.64,119.17) v1(199.64,116.63) v1(199.64,114.09) v1(199.64,111.55) v1(199.64,109.01) v1(199.64,106.47) v1(199.64,103.93) v1(199.64,101.39) v1(199.64,98.85) v1(199.64,96.31) v1(199.64,93.77) v1(199.64,81.07) v1(199.64,78.53) v1(199.64,75.99) v1(199.64,73.45) v1(199.64,70.91) v1(199.64,68.37) v1(199.64,63.29) v1(200.06,60.79) v1(200.25,37.54) v1(201.17,34.54) v1(201.17,27.3) v1(201.35,149.05) v1(203.57,166.37) v1(203.88,149.26) v1(204.93,26.24) v1(204.93,25.68) v1(205.82,164.92) v1(206.11,166.37) v1(206.38,164.92) v1(206.42,149.26) v1(207.77,24.92) v1(208.1,23.56) v1(208.28,27.94) v1(209.03,166.37) v1(208.96,149.2) v1(209.68,29.34) v1(209.98,156.67) v1(210.2,166.37) v1(210.93,147.61) v1(211.16,145.08) v1(211.16,142.54) v1(211.89,156.67) v1(212.09,159.39) v1(212.09,157.49) v1(212.3,140.27) v1(212.74,166.37) v1(212.72,160.78) v1(214.63,160.78) v1(214.84,140.26) v1(215.28,166.37) v1(215.27,39.5) v1(215.27,38.73) v1(215.52,4.57) v1(216.03,39.5) v1(216.03,38.73) v1(216.79,39.5) v1(216.79,38.73) v1(217.38,140.26) v1(218.09,6.06) v1(218.57,37.46) v1(218.57,36.7) v1(218.57,35.94) v1(218.57,35.18) v1(218.57,34.42) v1(218.57,33.65) v1(218.57,32.89) v1(218.57,32.13) v1(218.57,31.37) v1(218.57,30.61) v1(218.57,29.84) v1(219.33,37.46) v1(219.33,36.7) v1(219.33,35.94) v1(219.33,35.18) v1(219.33,34.42) v1(219.33,33.65) v1(219.33,32.89) v1(219.33,32.13) v1(219.33,31.37) v1(219.33,30.61) v1(219.33,29.84) v1(219.92,140.26) v1(220.03,59.5) v1(221.26,6.06) v1(221.62,39.5) v1(221.62,38.73) v1(221.73,166.37) v1(222.46,140.26) v1(222.57,59.5) v1(223.14,39.5) v1(223.14,38.73) v1(223.75,24.23) v1(223.8,6.06) v1(224.27,166.37) v1(224.41,24.23) v1(224.38,22.2) v1(224.66,39.5) v1(224.66,38.73) v1(224.79,29.21) v1(225,140.26) v1(225.03,22.2) v1(225.11,59.5) v1(225.17,27.56) v1(225.43,39.5) v1(225.64,26.03) v1(225.64,24.18) v1(225.64,22.2) v1(226.19,39.5) v1(226.49,4.8) v1(226.56,2.81) v1(226.81,166.37) v1(226.95,39.47) v1(227.54,140.26) v1(227.65,59.5) v1(227.97,39.47) v1(228.07,0.76) v1(228.35,166.37) v1(228.73,39.5) v1(228.8,23.91) v1(229.16,29.16) v1(229.44,5.44) v1(229.44,2.9) v1(229.49,39.5) v1(229.54,25.99) v1(229.74,159.31) v1(229.74,156.77) v1(229.74,146.61) v1(229.74,144.07) v1(229.74,141.53) v1(229.74,58.05) v1(230.02,7.91) v1(230.08,161.83) v1(230.16,29.16) v1(230.25,51.82) v1(230.25,39.5) v1(230.3,34.39) v1(230.3,24.43) v1(230.3,22.53) v1(230.89,166.37) v1(230.86,34.39) v1(231.01,51.82) v1(231.01,39.5) v1(231.01,38.73) v1(231.16,30.16) v1(231.16,29.16) v1(231.78,26.54) v1(231.78,24.13) v1(232.19,163.24) v1(232.52,8.36) v1(233.43,166.37) v1(234.32,28.19) v1(234.44,26.54) v1(234.35,24.13) v1(234.46,6.72) v1(234.46,4.18) v1(234.46,1.64) v1(234.73,163.26) v1(236.55,27.89) v1(236.85,0.76) v1(236.86,24.13) v1(237.27,163.26) v1(239.26,181.01) v1(239.26,179.74) v1(239.26,178.47) v1(239.34,175.97) v1(239.39,0.76) v1(239.78,163.63) v1(240.14,189.01) v1(240.14,176.31) v1(240.14,173.77) v1(240.14,171.23) v1(240.14,168.69) v1(240.14,166.15) v1(241.88,1.24) v1(242.14,6.31) v1(242.14,3.77) v1(242.62,8.81) v1(248.1,52.2) v1(249.93,10.01) v1(250.64,52.19) v1(251.74,49.9) v1(251.74,47.36) v1(251.74,44.82) v1(251.74,42.28) v1(251.74,39.74) v1(251.74,37.2) v1(251.74,34.66) v1(251.74,32.12) v1(251.74,29.58) v1(251.74,27.04) v1(251.74,24.5) v1(251.74,21.96) v1(251.74,19.42) v1(251.74,16.88) v1(251.74,14.34) v1(251.74,11.8)
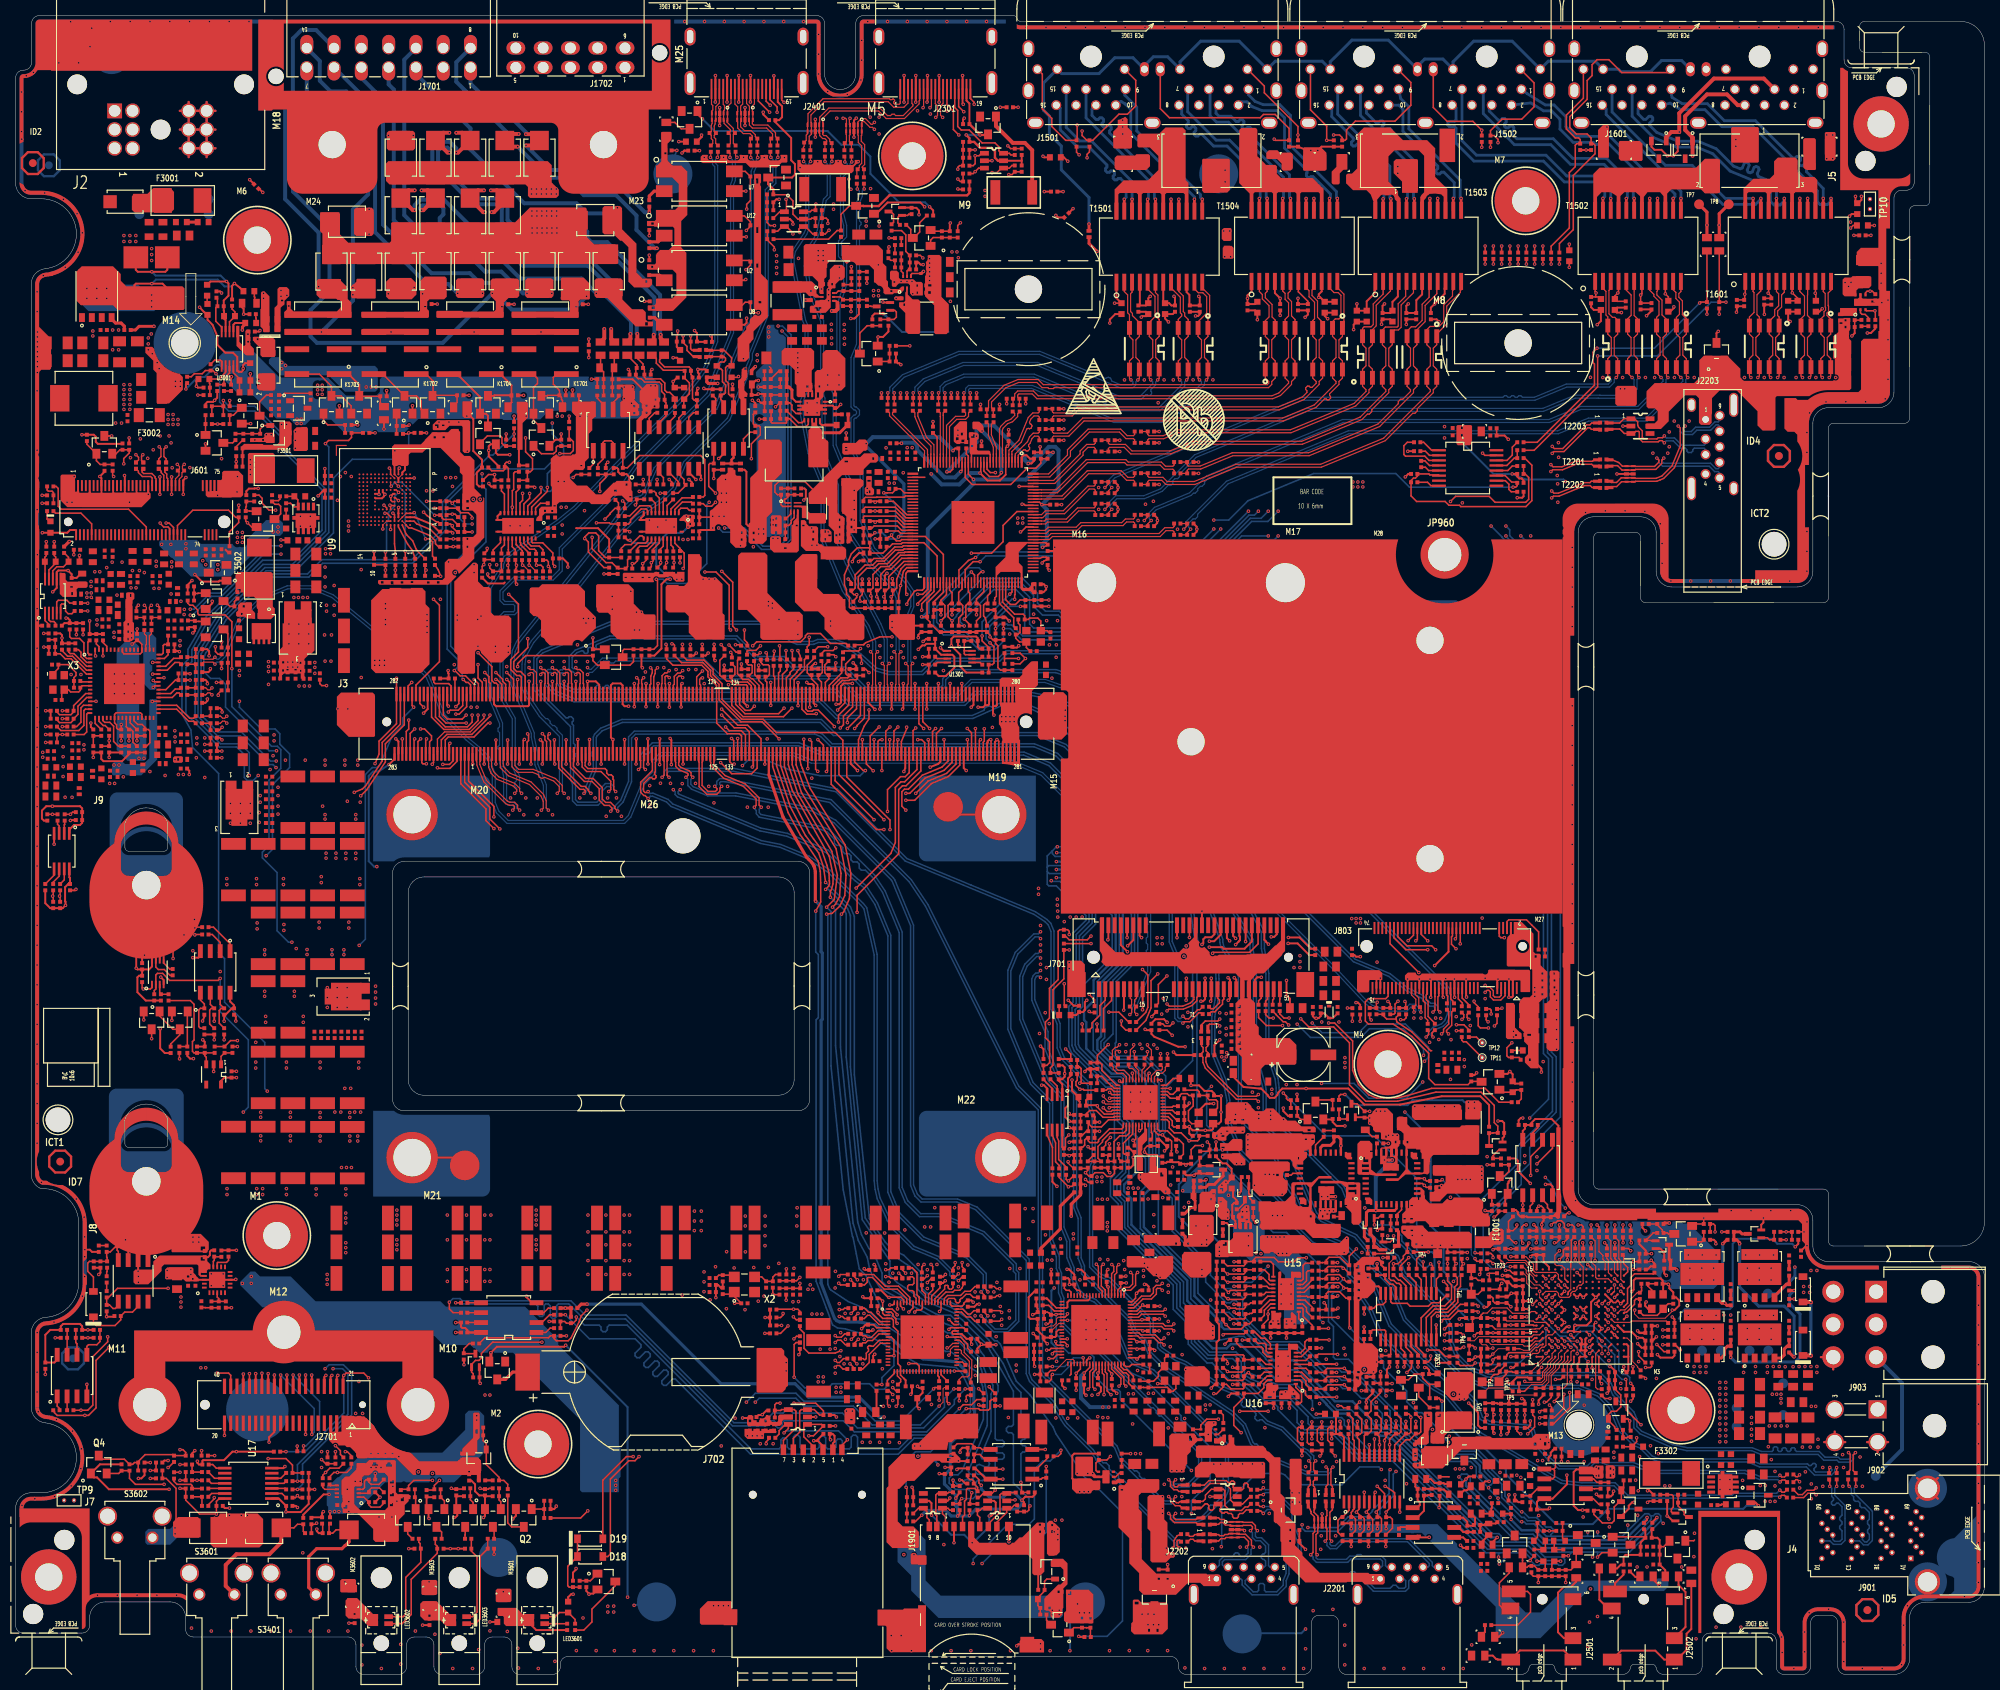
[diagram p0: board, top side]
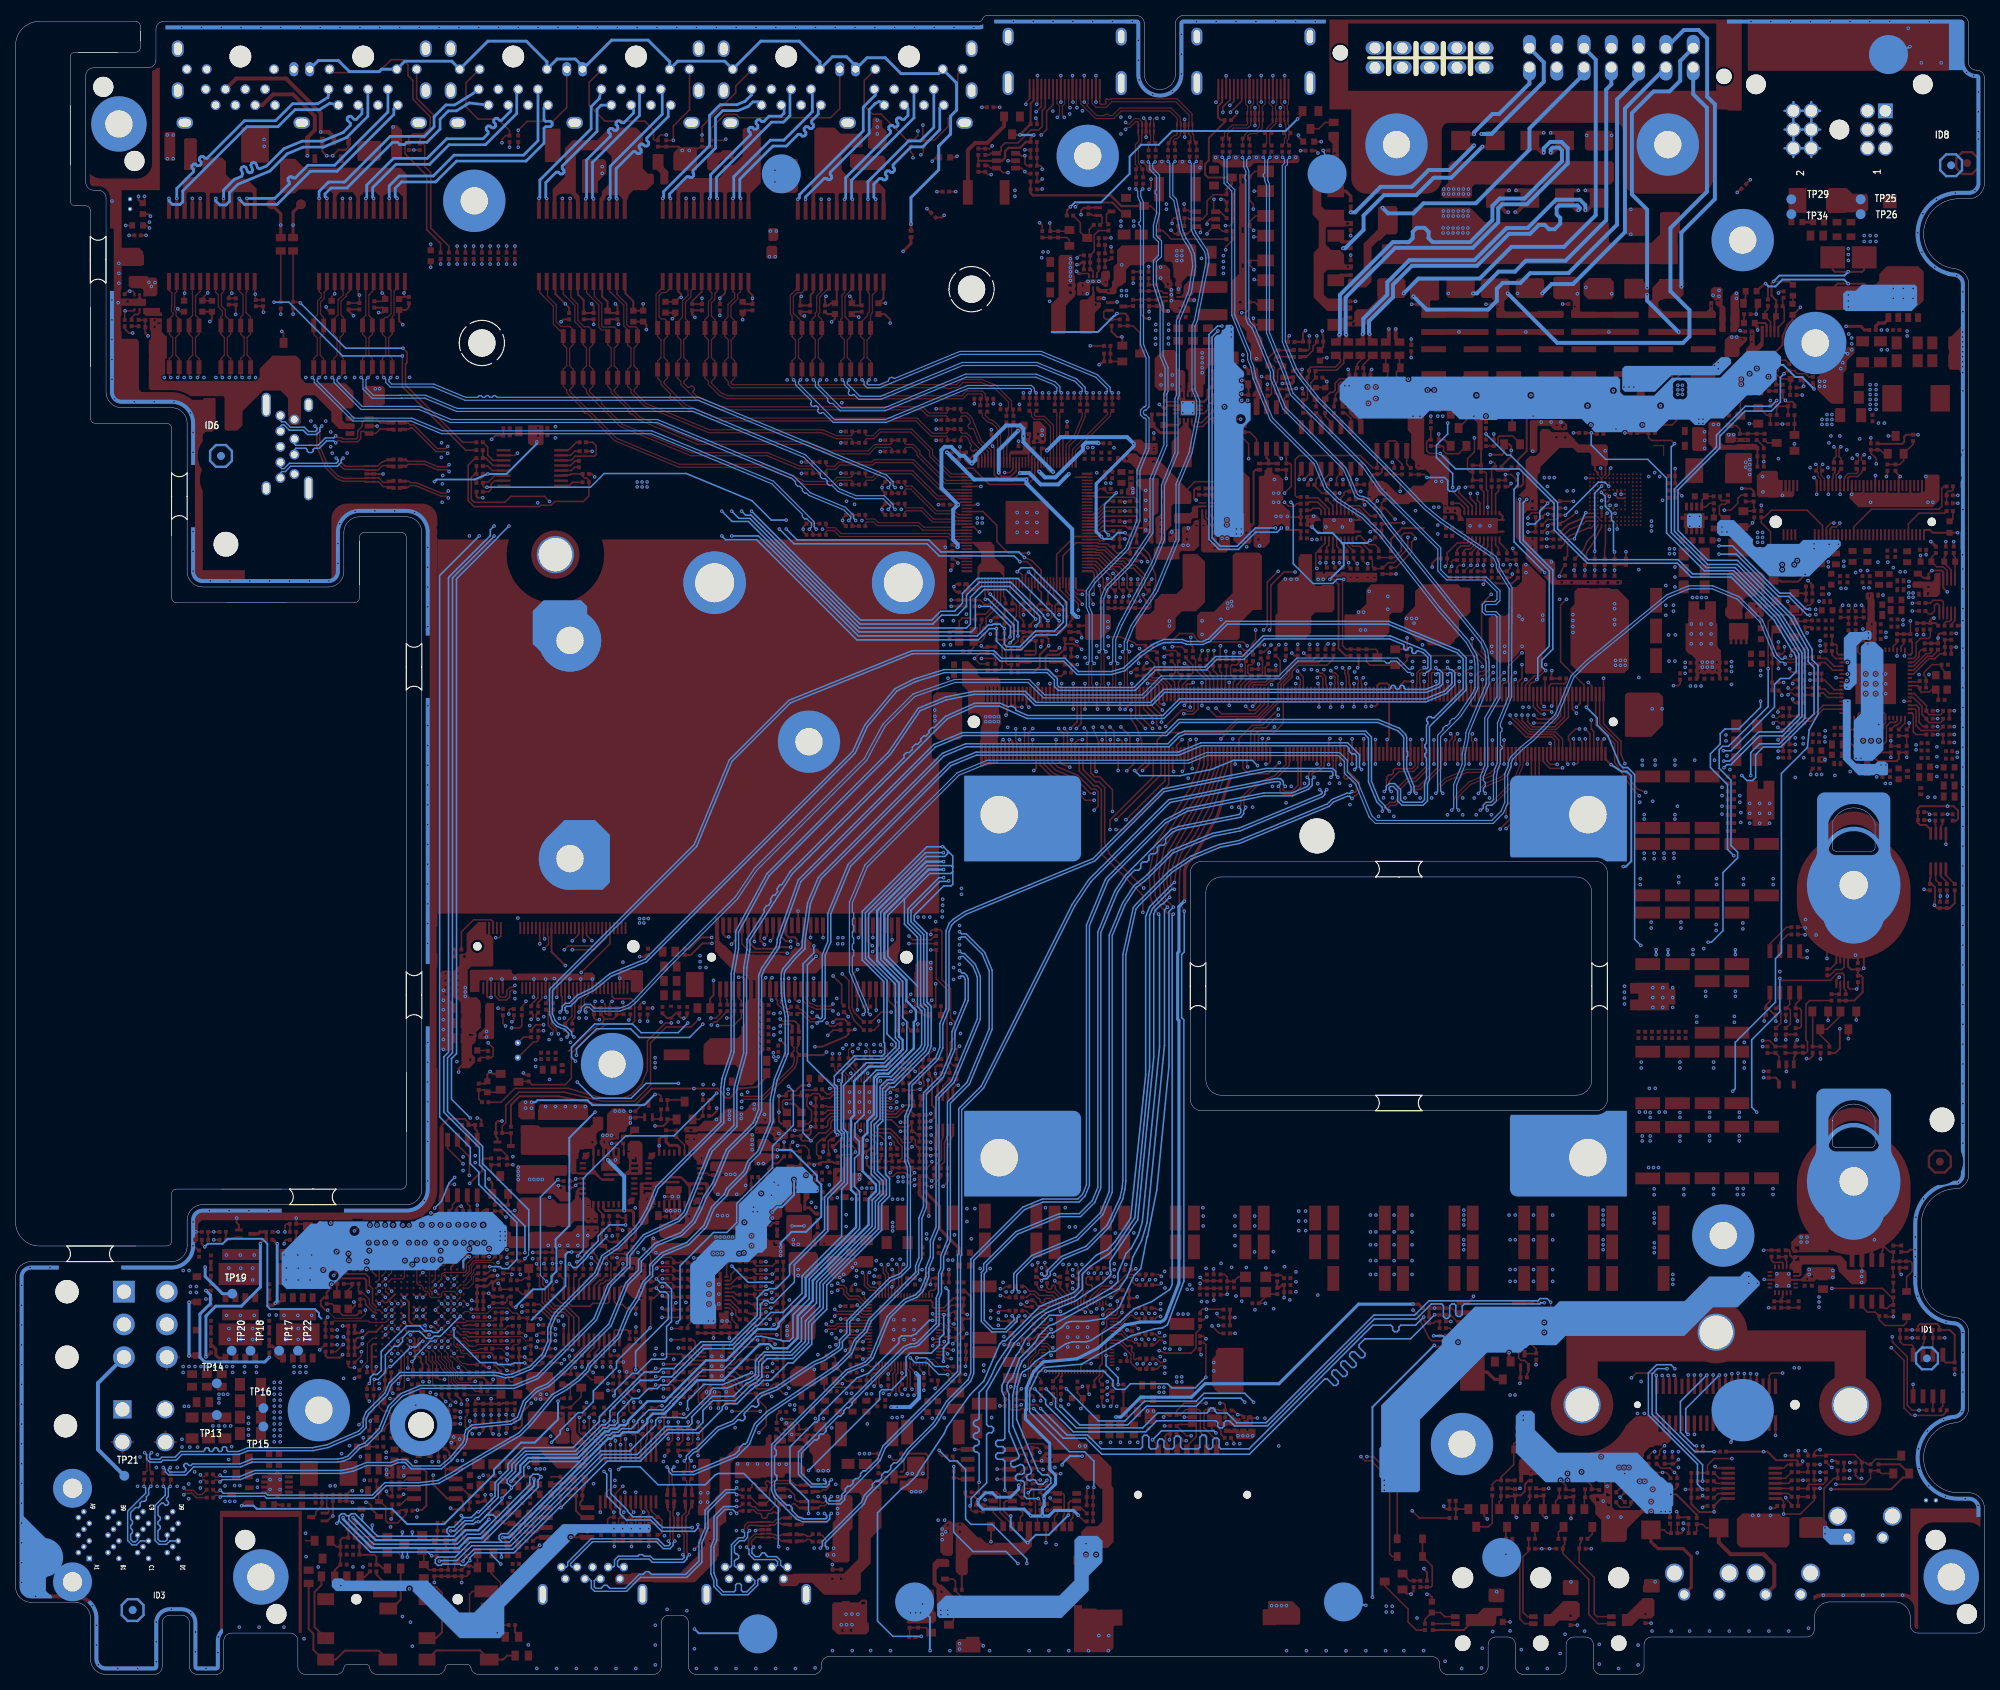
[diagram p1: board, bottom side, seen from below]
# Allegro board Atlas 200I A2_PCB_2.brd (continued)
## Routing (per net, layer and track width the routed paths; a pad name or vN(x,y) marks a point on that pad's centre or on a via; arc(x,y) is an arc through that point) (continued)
V11_VDD_CORE: length 11.1
  TOP w0.203: L1401.2 102.77,151.49 101.24,153.01 97.87,153.01 97.38,152.53 97.38,151.66 97.71,151.33 R1402.2 98.17,150.04 98.37,149.84 U1401.2
VCC_5G_1V8: length 9.9
  TOP w0.203: 177.06,84.07 177.06,84.3 R851.2 ; 177.06,84.07 177.14,83.71 179.07,82.42 181.48,80.01 181.61,80.01 ; 177.06,84.07 175.85,84.07 175.41,84.51 R829.2 R830.2
VCC_CAN: length 4.3
  TOP w0.305: C1638.1 91.82,155.83 92.08,156.08 U1604.3 ; C1638.1 LB8.2 ; C1638.1 LB9.2
VDD:
  vias: v1(13.89,165.46) v1(13.89,164.82) v1(13.89,164.19) v1(13.89,163.55) v1(13.89,162.92) v1(13.89,162.28) v1(14.66,165.46) v1(14.66,164.82) v1(14.66,164.19) v1(14.66,163.55) v1(14.66,162.92) v1(14.66,162.28) v1(126.47,122.86) v1(126.47,122.22) v1(127,122.86) v1(127,122.22) v1(127.53,122.86) v1(127.53,122.22) v1(128.07,122.86) v1(128.07,122.22)
VDDO3: length 0.8
  TOP w0.203: v1(17.53,124.82) 17.54,124.83 U301.36
  vias: v1(12.62,116.66) v1(13.26,116.66)
VDDO4: length 0.7
  TOP w0.203: v1(17.58,128.32) 17.58,128.33 U301.43
  vias: v1(17.75,139.32) v1(18.39,139.32)
VDDOX: length 13
  TOP w0.203: v1(13.55,121.85) C158.1 13.16,121.22 12.95,121.42 12.95,121.81 12.69,122.07 U301.22 12.69,123.15 12.9,123.36 16.01,123.36 16.19,123.17 U301.29 ; v1(14.94,132.18) 15.04,132.18 15.52,132.66 C157.1 15.67,132.66 16.19,132.14 U301.52 16.19,131.13 15.99,130.92 13.9,130.92 13.69,131.12 U301.57
  vias: v1(15.82,117.53) v1(16.46,117.53)
4G_PWR_EN: length 210.7
  TOP w0.203: v1(121.17,186.22) 120.83,185.88 R3134.1 ; R2851.1 v1(179.86,39.44)
  ART03 w0.178: v1(179.86,39.44) 176.72,42.58 174.26,42.58 172.06,44.79 172.06,48.49 170.31,50.24 169.4,50.24 166.4,53.25 166.4,69.52 161.87,74.04 161.87,75.29 161.28,75.88 159.12,75.88 155.99,72.76 153.46,72.76 152.02,74.2 152.02,76.1 149.48,78.64 149.48,80.14 148.95,80.67 146.31,81.76 141.03,81.76 140.71,82.08 136.04,82.08 130.54,87.58 130.54,99.43 v1(131.19,100.08)
  ART04 w0.178: v1(121.17,186.22) 117.7,182.75 116.31,182.75 115.6,182.04 115.6,178.96 123.48,171.07 128.54,171.07 137.69,161.92 137.69,149.92 144.87,142.74 144.87,127.61 131.95,114.69 131.95,100.84 v1(131.19,100.08)
5G_PWR_EN: length 197.1
  TOP w0.203: R2852.1 181.15,40.08 181.48,40.41 v1(181.48,40.84) ; R3123.1 v1(114.68,170.43)
  ART03 w0.178: v1(131.19,100.84) 131.66,100.37 131.66,99.66 130.92,98.92 130.92,87.74 135.99,82.68 142.11,82.68 142.62,82.17 146.26,82.17 147.05,81.97 149.09,81.12 150.13,81.03 150.51,80.87 151.33,80.05 151.33,78.14 153.74,75.73 157.31,75.73 158.61,77.02 162.37,77.02 163.44,75.96 163.44,73.95 166.78,70.61 166.78,53.9 169.4,51.28 170.62,51.28 172.44,49.46 172.44,46.1 173.76,44.78 175.53,44.78 179.47,40.84 v1(181.48,40.84)
  ART04 w0.178: v1(114.68,170.43) 128.64,170.43 137.19,161.89 137.19,149.71 144.49,142.4 144.49,127.76 131.19,114.46 v1(131.19,100.84)
1911_HBOOT_OK: length 269.5
  TOP w0.203: J3.284 49.35,121.88 47.02,119.55 47.02,117.17 44.89,113.99 44.49,113.59 v1(43.43,113.16) ; R147.1 158.21,50.84 158.2,50.85 R363.1 157.72,50.55 157.51,50.34 155.51,50.34 v1(155.47,50.3) 155.39,50.3 R362.2
  ART04 w0.178: v1(43.43,113.16) 40.36,113.16 35.94,108.74 35.94,99.88 33.05,96.98 33.05,74.7 29.24,70.89 29.24,54.99 45.9,38.33 45.9,35.61 56.62,24.89 70.74,24.89 76.87,18.76 128.07,18.76 131.37,15.46 136.87,15.46 145.24,23.82 154.84,23.82 158.15,27.14 158.15,27.57 159.36,28.78 159.36,34.46 159.73,34.83 159.73,49.7 160.63,50.6 v1(160.63,52.37)
  BOTTOM w0.203: v1(155.47,50.3) 158.55,50.3 v1(160.63,52.37)
1911_HBOOT_OK_R: length 48.7
  TOP w0.203: v1(196.06,34.92) 196.34,34.92 196.95,35.53 R2840.2 ; R356.2 170.68,50.38 v1(170.31,50.75) 169.77,51.28 168.3,51.28 168.1,51.08 R357.2 167.61,50.76 167.61,50.76 R160.2
  ART03 w0.178: v1(196.06,34.92) 196.06,34.74 195.5,34.18 189.82,34.18 187.59,36.41 181.22,36.41 180.63,35.81 175.84,35.81 v1(175.77,35.74)
  BOTTOM w0.203: v1(170.31,50.75) 169.83,50.27 169.24,50.27 168.38,49.4 168.38,45.26 169.01,44.63 169.01,40.69 169.27,40.44 170.95,40.44 172.77,38.61 173.43,38.61 175.62,36.42 175.62,35.97 175.77,35.81 v1(175.77,35.74)
1911_OS_OK: length 254
  TOP w0.203: R145.1 158.21,49.78 158.2,49.79 R353.1 157.72,49.39 157.6,49.26 155.8,49.26 v1(155.54,49.01) 154.85,49.7 R352.2 ; v1(44.26,112.71) 45.05,113.5 47.42,117.05 47.42,119.38 49.85,121.81 J3.286
  ART04 w0.178: v1(44.26,112.71) 44.08,112.53 41.21,112.53 39.57,110.9 39.37,110.9 36.73,108.25 36.73,99.36 33.94,96.56 33.94,61.37 30.58,58.01 30.58,55.04 46.58,39.04 51.87,39.04 57.2,33.71 68.46,33.71 72.54,29.63 72.54,25.63 78.65,19.52 128.47,19.52 128.82,19.17 131.77,16.22 136.24,16.22 151.41,31.39 153.57,31.39 157.14,34.96 157.14,40.1 156.55,40.69 156.55,43.79 157.32,44.56 157.32,47.91 156.86,48.36 156.86,48.82 156.46,49.22 156,49.22 155.67,49.09 155.59,49.01 v1(155.54,49.01)
1911_OS_OK_R: length 52.2
  TOP w0.203: 170.33,49.55 170.81,49.55 R351.2 ; 170.33,49.55 170.33,49.68 169.77,50.24 168.38,50.24 168.12,49.99 R350.2 167.62,49.73 167.61,49.72 R159.2 ; 170.33,49.55 v1(170.33,49.55) ; R2837.2 203.2,37.49 v1(203.4,37.29)
  ART03 w0.178: v1(172.97,39.09) 172.97,38.52 173.29,38.2 177.23,38.2 177.92,37.5 179.79,37.5 180.29,38 188.16,38 189.52,36.64 197.51,36.64 198.86,37.99 200.52,37.99 201.55,36.96 203.07,36.96 v1(203.4,37.29)
  BOTTOM w0.203: v1(172.97,39.09) 172.97,41.43 168.78,45.62 168.78,48.72 169.14,49.07 169.85,49.07 v1(170.33,49.55)
8367_XTAL_IN: length 11.4
  TOP w0.203: C1318.1 132.49,133.71 132.29,133.9 X1301.1 131.48,135.13 131.1,135.51 130.05,135.51 129.87,135.33 129.41,135.33 129.41,135.81 129.21,136.02 128.12,136.02 126.58,137.55 U6.90
8367_XTAL_OUT: length 6.7
  TOP w0.203: U6.89 126.18,137.37 128.02,135.53 128.02,134.47 R1326.1
$17I27535\1V8_VDD_1: length 0.7
  TOP w0.203: U301.46 17.58,129.83 v1(17.58,129.82)
  vias: v1(14.81,139.39) v1(15.44,139.39)
$17I27535\3V3_IO: length 95.4
  TOP w0.203: R314.1 v1(9.97,117.64)
  TOP w0.254: R329.1 R332.1 v1(3.86,123.62) ; R316.1 22.34,128.41 v1(22.38,128.37) ; v1(26.45,118.45) R307.1 R333.1 ; R324.1 R325.1 R326.1 v1(5.95,132.95) 5.95,133.32 5.72,133.54 R262.1 ; v1(21,131.2) 20.93,131.28 R327.1 R305.1 ; R314.1 R322.1 10.98,117.44 11.27,117.15 13.65,117.15 14.54,118.04 R318.1 R328.1 R309.1 ; R320.1 v1(3.86,120.57)
  ART03 w0.254: v1(19.18,115.32) 19.81,115.95 19.81,118.24 20.96,119.38 20.96,131.15 v1(21,131.2)
  ART04 w0.254: v1(21,131.2) 22.38,129.83 v1(22.38,128.37) ; v1(3.48,118.29) 4.42,119.23 4.42,120.01 v1(3.86,120.57) 4.37,121.08 4.37,123.11 v1(3.86,123.62) 3.86,131.01 4.24,131.39 4.24,132.11 3.08,133.27 3.08,133.81 3.34,134.06 4.83,134.06 v1(5.95,132.95) 6.53,132.95 9.47,135.89 12.07,135.89 13.01,136.83 v1(13.01,138.45) ; v1(26.45,118.45) 25.48,118.45 23.5,116.46 20.32,116.46 v1(19.18,115.32) 18.92,115.06 16.51,115.06 15.75,115.82 12.45,115.82 10.61,117.66 9.99,117.66 v1(9.97,117.64) 9.42,117.09 5.41,117.09 4.85,117.65 v1(3.48,117.65)
$17I27535\3V3_VDDIN: length 0.7
  TOP w0.203: v1(10.31,124.83) 10.31,124.83 U301.13
  vias: v1(8.76,119.25) v1(8.76,118.62)
$17I27535\3V3_VDDS: length 0.8
  TOP w0.203: v1(17.65,126.62) 17.86,126.83 U301.40
  vias: v1(14.88,133.6) v1(14.88,132.97)
$17I27535\$10N2449: length 1.8
  TOP w0.203: U301.17 10.19,122.01 R302.2
$17I27535\$10N2450: length 2.2
  TOP w0.203: U301.18 10.69,122.27 11.24,121.73 11.49,121.73 R303.2
$17I27535\$10N2469: length 1.3
  TOP w0.203: R301.2 8.42,127.33 U301.8
$17I27535\$10N2470: length 4.6
  TOP w0.203: U301.16 9.27,123.33 9.12,123.17 9.12,120.9 8.79,120.57 R304.2
$17I27535\CSB_A0_LC33: length 6.2
  TOP w0.203: U301.19 11.19,122.37 11.43,122.13 12.08,122.13 12.57,121.64 12.57,119.68 13.17,119.08 R315.1 R318.2
$17I27535\FDEC_LC33: length 15.2
  TOP w0.203: R308.1 R307.2 v1(24.26,118.45) ; v1(19.02,127.86) 18.99,127.83 U301.42
  ART04 w0.178: v1(24.26,118.45) 25.15,119.33 25.15,120.52 24,121.67 23.12,121.67 19.02,125.76 v1(19.02,127.86)
$17I27535\FINC_DFT_LC33: length 3.5
  TOP w0.203: U301.48 18.74,130.83 18.92,131.01 18.92,131.98 19.07,132.13 R305.2 R306.1
$17I27535\I2C1_SPI0_LC33: length 3.9
  TOP w0.203: R316.2 R317.1 20.49,127.55 19.27,126.33 U301.39
$17I27535\LOL_A_LC33: length 2.9
  TOP w0.203: R324.2 8.05,131.46 8.38,131.13 8.38,130.56 9.11,129.83 U301.3
$17I27535\LOL_B_LC33: length 3.8
  TOP w0.203: U301.4 9.1,129.33 7.48,130.95 7.01,130.95 6.81,131.16 R325.2
$17I27535\LOL_C_LC33: length 4.8
  TOP w0.203: U301.5 9.1,128.83 7.3,130.62 6.66,130.62 5.95,131.34 R326.2
$17I27535\LOL_D_LC33: length 1.9
  TOP w0.203: R327.2 19.56,130.8 19.09,130.33 U301.47
$17I27535\OE0_LC33: length 6.2
  TOP w0.203: R332.2 5.31,123.44 5.64,123.11 7.09,123.11 7.44,123.47 R312.1 7.44,124.28 8.99,125.83 U301.11
$17I27535\OE1_LC33: length 14.3
  TOP w0.203: R313.1 R333.2 v1(24.26,119.3) ; v1(17.65,127.51) 17.84,127.33 U301.41
  ART04 w0.178: v1(17.65,127.51) 18.42,126.75 18.42,125.73 22.99,121.16 24,121.16 24.77,120.4 24.77,119.81 v1(24.26,119.3)
$17I27535\PLL_SEL0_LC33: length 1.8
  TOP w0.203: U301.26 14.69,122.08 R310.1
$17I27535\PLL_SEL1_LC33: length 5.5
  TOP w0.203: R309.2 16.8,119.08 17.22,119.51 17.22,121.01 17.02,121.22 R311.1 16.57,121.52 16.23,121.87 15.65,121.87 15.19,122.32 U301.27
$17I27535\SDO_A1_LC33: length 2.3
  TOP w0.203: R302.1 R319.1 R314.2
$51I54824\3V3_ADC: length 7
  TOP w0.203: U3.J5 v1(201.86,43.55)
  ART03 w0.178: v1(201.86,43.55) 201.17,42.86 201.17,38.86 v1(202.18,37.85)
$51I54824\$2N4737: length 2.7
  TOP w0.203: X1.3 209.84,49.32 209.32,49.83 R14.1 C12.1
$51I54824\$2N4739: length 5.1
  TOP w0.203: R15.1 208.75,46.06 210.55,46.06 211.29,46.81 X1.1 211.94,47.55 C11.2
$51I54824\$2N39663: length 9.1
  TOP w0.203: U3.H1 U3.J1
  TOP w0.254: U3.H1 200.53,40.63 200.53,40.05 200.32,39.84 200.32,39.23 R61.1 ; U3.J3 201.32,42.49 201.32,43.01 U3.J4 ; U3.J3 201.32,42.21 201.32,41.69 U3.J2 ; U3.J3 U3.H3 ; U3.H3 200.79,42.23 200.79,41.68 U3.H2 U3.J2 ; U3.H3 200.86,42.56 200.86,42.95 U3.H4 ; U3.J2 201.24,41.33 201.24,40.97 U3.J1
$51I54824\$2N40757: length 3.9
  TOP w0.127: U3.B1 195.86,40.54 195.2,39.88 194.69,39.88 194.56,39.75
  TOP w0.203: U3.A1 U3.B1 ; 194.56,39.75 R20.2
$51I54824\$3N2669: length 6
  TOP w0.203: R18.1 201.55,40 v1(201.68,40.13) ; U3.E4 198.27,43.15 v1(198.67,42.75)
  BOTTOM w0.178: v1(198.67,42.75) 199.3,42.75 201.3,40.76 201.3,40.51 v1(201.68,40.13)
$51I54824\$3N2675: length 7.7
  TOP w0.102: 199.45,49.37 199.45,52.27
  TOP w0.203: 199.45,52.27 199.45,52.98 199.52,53.05 199.52,55.73 C35.1 ; U3.F11 199.12,48.81 199.12,49.04 199.45,49.37
$51I54824\$3N6111: length 16.8
  TOP w0.203: U3.K5 202.44,44.13 202.44,44.93 v1(202.66,45.15) ; C36.1 C34.1 195.07,55.55 195.02,55.5 v1(195.02,55.37)
  ART04 w0.178: v1(195.02,55.37) 196.47,53.92 196.47,53.34 199.81,49.99 199.81,48.09 200.28,47.62 200.91,47.62 201.55,46.99 201.55,46.27 v1(202.66,45.15)
$51I54824\MCU_RST_N: length 24.1
  TOP w0.203: R2.1 C10.1 207.33,29.27 207.9,29.84 v1(207.9,30.35) ; U3.M5 v1(204.26,44.35)
  ART04 w0.178: v1(204.26,44.36) 204.26,44.37 204.85,44.96 208.15,44.96 208.66,44.45 208.66,41.15 208.41,40.89 208.15,40.89 207.71,40.45 207.71,39.95 207.86,39.79 207.86,39.58 208.13,39.32 208.13,38.55 207.99,38.41 207.99,34.3 206.5,32.82 206.5,31.75 v1(207.9,30.35)
$51I54824\SD5000_ISP/NC: length 15.2
  TOP w0.203: v1(196.09,55.37) 195.96,55.5 R5.1 ; U3.M7 v1(204.26,45.15)
  ART04 w0.178: v1(204.26,45.15) 202.81,46.61 202.44,46.61 201.68,47.37 201.68,48.77 196.98,53.47 196.98,54.48 v1(196.09,55.37)
$51I54824\SD5000_RTCK/NC: length 9.4
  TOP w0.203: U3.M10 v1(203.47,47.57) ; R13.1 v1(207.47,51.94)
  ART04 w0.178: v1(203.47,47.57) 203.9,48 204.81,48 204.89,47.92 205.26,47.92 205.38,48.05 206.98,48.05 207.71,48.78 207.71,51.7 v1(207.47,51.94)
$51I54824\SD5000_SEL/NC: length 7.4
  TOP w0.203: R11.1 210.03,51.38 207.62,51.38 207.14,50.9 207.14,49.91 206.73,49.5 206.73,47.63 U3.R9
$51I54824\SD5000_TCK/BOOT0: length 15.4
  TOP w0.203: U3.M9 v1(204.26,46.75) ; R16.2 R10.1 197.99,55.75 197.61,55.37 v1(197.36,55.37)
  ART04 w0.178: v1(204.26,46.75) 204.03,46.99 202.6,46.99 202.21,47.37 202.21,48.86 198.5,52.58 198.5,53.67 198.32,53.85 197.74,53.85 197.36,54.23 v1(197.36,55.37)
$51I54824\SD5000_TDI/NC: length 10.9
  TOP w0.203: U3.M8 v1(204.26,45.95) ; R9.1 211.4,41.4 v1(210.49,42.32)
  ART04 w0.178: v1(204.26,45.95) 204.75,45.47 208.23,45.47 209.08,44.61 209.08,43.27 210.03,42.32 v1(210.49,42.32)
$51I54824\SD5000_TMS/NC: length 9.8
  TOP w0.203: U3.N9 v1(205.06,46.75) ; R7.1 v1(211.25,43.31)
  ART04 w0.178: v1(211.25,43.31) 209.93,44.63 209.93,45.59 208.33,47.19 206.31,47.19 205.87,46.75 v1(205.06,46.75)
$51I54824\SD5000_TRST_N/NC: length 10.3
  TOP w0.203: R12.1 v1(211.25,42.29) ; U3.N8 v1(205.06,45.95)
  ART04 w0.178: v1(205.06,45.95) 205.61,45.95 206.14,46.48 207.14,46.48 207.65,45.97 208.53,45.97 209.55,44.96 209.55,43.48 210.24,42.8 210.74,42.8 v1(211.25,42.29)
$51I54824\SD5000_XTAL1: length 3.9
  TOP w0.203: U3.R8 206.36,46.45 206.6,46.45 207.62,47.47 207.62,47.95 207.82,48.16 R17.1 R15.2
$51I54824\SD5000_XTAL2: length 5.6
  TOP w0.152: U3.P8 205.86,46.75 206.4,46.75 207.14,47.49 207.14,48.13 207.98,48.97 R17.2
  TOP w0.203: R14.2 208.51,49.63 208.53,49.61 208.53,49.2 R17.2
$51I54824\TEST_MOD/NC: length 13.4
  TOP w0.203: R8.1 v1(211.25,44.2) ; v1(205.86,47.55) U3.P10 205.21,47.7 204.91,47.7 U3.N10
  TOP w0.254: U3.R10 v1(205.86,47.55) ; v1(204.26,47.55) U3.N10 U3.M11
  ART04 w0.178: v1(211.25,44.2) 211.25,44.96 208.66,47.55 v1(205.86,47.55) v1(204.26,47.55)
$51I54824\WDT_EN/NC: length 7.6
  TOP w0.152: R6.1 211.68,45.34 207.26,45.34 207.09,45.16 205.05,45.16 U3.N7
$61I15303\$4N4760: length 1.9
  TOP w0.203: R74.1 173.98,68.98 C53.1
$71I24443\$4N4760: length 1.1
  TOP w0.203: R19.1 169.94,58.73 C1.1
/ALARM_IN0: length 36.2
  TOP w0.406: R1705.1 v1(81.27,187.56)
  TOP w0.508: v1(65.46,197.59) 66.37,197.59 D1712.2 66.55,196.14 v1(65.46,196.14)
  BOTTOM w0.508: J1701.1 58.34,204.08 62.25,200.18 63.09,200.18 65.46,197.81 v1(65.46,197.59) ; v1(65.46,196.14) 68.61,192.99 71.27,192.99 73.43,190.83 77.44,190.83 80.71,187.56 v1(81.27,187.56)
/ALARM_IN1: length 45.3
  TOP w0.406: v1(82.25,182.95) 82.23,182.96 R1704.1
  TOP w0.508: v1(64.39,195.99) 63.53,195.99 D1713.2 63.58,197.61 v1(64.52,197.61)
  BOTTOM w0.508: v1(64.39,195.99) 68.38,192 70.63,192 72.87,189.76 77.01,189.76 79.63,187.15 79.63,185.31 81.99,182.95 v1(82.25,182.95) ; v1(64.52,197.61) 63.22,197.61 56.52,204.32 56.52,206.82 J1701.8
/ALARM_IN2: length 36
  BOTTOM w0.508: v1(77.19,188.15) 76.47,187.43 73.23,187.43 71.93,188.72 65.23,188.72 58.34,195.6 58.34,198.32 51.34,205.32 J1701.3
/ALARM_IN3: length 50.9
  BOTTOM w0.508: v1(74.47,177.16) 72.57,179.07 64.72,179.07 60.66,183.13 53.91,183.13 49.85,187.2 49.85,207.15 J1701.10
/ALM_IN0: length 110.3
  TOP w0.203: v1(93.76,187.98) 93.76,188.59 94.23,189.07 R79.2 93.57,192.82 U7.4 ; v1(124.23,121.31) 124.23,119.71 124.1,119.58 J3.263
  ART04 w0.178: v1(93.76,187.98) 93.76,187.61 93.05,186.9 93.05,173.38 96.09,170.34 97.24,170.34 97.62,170.73 101.25,170.73 103,168.97 103,164.45 105.79,161.66 116.05,161.66 119.58,158.13 121.48,158.13 124.42,155.19 124.42,153.67 124.59,153.5 124.59,144.17 131.14,137.62 131.14,121.87 130.2,120.93 124.61,120.93 v1(124.23,121.31)
/ALM_IN1: length 103.5
  TOP w0.203: v1(93.72,185.24) 94.23,185.75 R78.2 94.23,186.34 93.47,187.1 U12.4 ; v1(123.75,119.91) 123.6,119.76 J3.261
  ART04 w0.178: v1(93.72,185.24) 94.6,184.36 94.6,172.91 96.4,171.11 96.92,171.11 97.3,171.49 101.56,171.49 110.63,162.42 118.71,162.42 125.18,155.95 125.18,153.98 125.35,153.82 125.35,144.72 131.9,138.17 131.9,136.96 132.84,136.02 132.84,134.11 131.95,133.22 131.95,121.41 129.98,119.44 124.22,119.44 v1(123.75,119.91)
/ALM_IN2: length 100.8
  TOP w0.203: v1(123.1,121.34) J3.259 ; v1(93.68,180.21) 94.23,180.76 R80.2 94.08,181.39 U2.4
  ART04 w0.178: v1(93.68,180.21) 94.22,179.66 94.22,172.75 96.24,170.73 97.08,170.73 97.46,171.11 101.4,171.11 103.38,169.13 103.38,164.61 105.95,162.04 117,162.04 120.53,158.51 121.64,158.51 124.8,155.34 124.8,153.82 124.97,153.66 124.97,144.42 131.52,137.87 131.52,121.62 130.45,120.55 123.89,120.55 v1(123.1,121.34)
/ALM_IN3: length 99.6
  TOP w0.203: 94.23,176 R81.2 ; 94.23,176 94.21,176.03 93.57,176.03 93.22,175.67 U8.4 ; 94.23,176 94.23,175.16 94.72,174.68 v1(95.25,174.68) ; J3.257 122.6,120.79 v1(122.05,121.35)
  ART04 w0.178: v1(95.25,174.68) 95.43,174.68 97.07,173.04 97.07,172.55 97.75,171.87 101.72,171.87 110.79,162.8 121.33,162.8 124.68,159.45 124.68,157 126.89,154.79 126.89,153.71 126.75,153.37 126.75,143.95 132.27,138.43 132.72,138.43 134.19,136.96 134.19,130.43 132.41,128.65 132.41,121.11 130.37,119.06 123.94,119.06 122.68,120.31 122.68,120.71 v1(122.05,121.35)
/CLKREQ_5G_LTE: length 269.7
  TOP w0.203: R832.2 176.76,84.68 176.91,84.84 176.91,85.98 v1(177.29,86.36) ; J3.315 56.6,117.13 55.7,116.23 54.18,116.23 v1(54.1,116.31)
  ART03 w0.178: v1(177.29,86.36) 176.59,85.66 174.43,85.66 174.12,85.98 174.12,89.76 177.34,92.99 177.34,113.13 169.52,120.95 169.52,143.61 157.05,156.08 129.92,156.08 125.92,160.08 117.62,160.08 116.72,160.98 107.37,160.98 106.8,160.42 104.89,160.42 100.94,156.46 73.41,156.46 71.4,154.46 66.54,154.46 63.72,151.64 54.74,151.64 53.5,152.88 47.47,152.88 44.96,150.36 44.96,124.26 37.59,116.89 37.59,112.14 38.84,110.9 44.6,110.9 49.07,115.37 53.16,115.37 v1(54.1,116.31)
/CLKREQ_M2: length 16.4
  TOP w0.203: v1(19.3,147.7) 19.69,147.7 20.26,147.13 J601.52 ; v1(13.87,155.3) 13.87,155.98 14.57,156.68 R130.1 R604.2 13.39,157.1 12.88,156.59 D3.2
  ART04 w0.178: v1(13.87,155.3) 16,153.16 16,151 19.3,147.7 v1(19.3,147.7)
/EMMC_RESET: length 80.2
  TOP w0.203: R1810.2 v1(47.44,141.67) R1809.1 47.4,142.34 C1812.2 ; v1(109.98,115.93) 109.1,116.81 J3.203
  ART04 w0.178: v1(47.44,141.67) 47.92,141.18 57.73,137.54 74.9,137.54 77.57,137.27 93.28,136.38 94.41,135.97 95.48,135.22 96.19,134.74 97.38,133.56 99.96,131.84 100.5,131.84 100.8,131.54 100.8,129.92 101.77,127.59 101.99,127.36 103.16,124.54 104.17,121.48 104.5,120.91 104.89,120.46 108.69,116.66 109.25,116.66 v1(109.98,115.93)
/EN_TEC_BACKWARD: length 64.8
  TOP w0.203: R1104.1 v1(227.08,56.77) R1105.2 R1106.2 ; R1024.2 v1(178.67,52.68)
  ART03 w0.178: v1(227.08,56.77) 226.5,57.34 217.86,57.34 217.59,57.06 210.66,57.06 208.6,59.12 201.28,59.12 199.3,59.94 197.23,62.01 197.23,64.27 v1(195.11,66.39)
  ART04 w0.178: v1(195.11,66.39) 194.44,67.06 193.1,67.06 191.25,65.21 191.25,63.08 184.05,55.88 181.53,55.88 181.19,55.54 181.19,55.1 180.66,54.57 180.33,54.57 179.13,53.38 179.13,53.14 v1(178.67,52.68)
/FACTORYSET_MCU: length 216.3
  TOP w0.203: R3620.2 C3616.1 38.47,19.26 v1(38.61,19.4) ; R2833.2 199.52,37.6 v1(199.45,37.54)
  ART03 w0.178: v1(204.34,40.26) 205.57,39.03 208.07,39.03 208.85,39.81 209.81,39.81 211.33,38.29 211.33,37.65 209,35.33 209,30.79 207.93,29.72 204.47,29.72 201.56,26.81 195.08,26.81 193.41,28.48 176.07,28.48 176.07,28.49 173.9,28.49 169.27,23.85 163.61,23.85 162.97,23.21 162.97,20.55 161.39,18.97 157.12,18.97 156.46,18.31 149.04,18.31 143.16,12.43 83.6,12.43 81.6,14.44 70.89,14.44 58.7,26.63 49.33,26.63 44.29,21.59 39.37,21.59 38.61,20.83 38.61,19.41 v1(38.61,19.4)
  ART04 w0.178: v1(204.34,40.26) 203.96,39.88 203.96,39.62 202.69,38.35 200.27,38.35 v1(199.45,37.54)
/LED_4G: length 37.6
  TOP w0.203: v1(134.49,88.59) 134.49,85.88 R30.1
  TOP w0.254: J701.42 158.55,94.03 157.61,93.09 154.94,93.09 154.74,93.29 v1(153.1,93.29)
  ART04 w0.178: v1(134.49,88.59) 134.49,89.01 135.45,89.97 138.35,89.97 142.33,93.94 142.82,93.94 145.16,91.6 145.16,89.44 145.78,88.82 146.87,88.37 148.17,88.37 148.89,89.09 148.89,89.25 152.93,93.29 v1(153.1,93.29)
/LED_5G: length 25.5
  TOP w0.203: R831.1 193.02,78.95 192.83,79.15 R848.1 191.47,79.15 191.26,79.35 191.26,80.39 v1(191.9,81.03) ; J803.10 190.28,94.72 190.48,94.51 v1(190.93,94.51)
  ART04 w0.178: v1(191.9,81.03) 192.66,81.03 196.11,84.48 196.11,92.71 194.31,94.51 v1(190.93,94.51)
/LED_HEALTHY_G: length 1.8
  TOP w0.203: Q3602.3 50.29,18.01 R3602.1
/LED_HEALTHY_R: length 1.8
  TOP w0.203: Q3601.3 54.64,18.26 R3601.1
/LED_M2_R: length 1.6
  TOP w0.203: R611.2 4.04,148.21 4.32,147.93 D701.2
/LED_PHY0_ACT: length 137.9
  TOP w0.203: R1211.2 R1214.1 151.79,68.66 151.59,68.45 v1(150.5,68.45) 149.48,69.47 148.59,69.47 147.95,70.11 147.95,70.87 147.65,71.17 U1201.37 ; R1630.2 v1(196.93,180.92)
  ART04 w0.178: v1(196.93,180.92) 168.58,152.57 168.58,134.52 152.59,95.92 v1(150.13,93.46)
  BOTTOM w0.203: v1(150.5,68.45) 151.51,69.47 151.51,91.16 150.13,92.54 v1(150.13,93.46)
/LED_PHY0_LINK: length 136.2
  TOP w0.203: R1212.2 148.21,67.18 148.26,67.23 148.26,68.4 148.06,68.6 R1205.1 v1(147.09,69.21) 146.56,69.21 146.06,69.71 U1201.35 ; R1629.2 v1(197.99,180.92)
  ART04 w0.178: v1(149.83,92.13) 149.86,92.15 149.91,92.15 150.38,92.62 150.39,92.62 150.66,92.89 150.66,92.9 151.1,93.34 151.1,93.89 153.45,96.24 169.49,134.98 169.49,152.43 v1(197.99,180.92)
  BOTTOM w0.203: v1(149.83,92.13) 150.95,91.01 150.95,78.74 147.45,75.23 147.45,69.57 v1(147.09,69.21)
/LED_PHY1_ACT: length 112.8
  TOP w0.203: R1367.1 v1(125.68,134.16) R1354.2 ; U6.81 122.98,141.02 v1(122.58,141.43) ; R1506.2 v1(194.82,180.92)
  ART04 w0.178: v1(194.82,180.92) 194.52,180.21 160.86,146.55 v1(160.66,146.05)
  BOTTOM w0.203: v1(160.66,146.05) 157.24,146.05 144.41,133.22 129.16,133.22 127.76,134.62 127.25,134.62 127.14,134.73 126.25,134.73 v1(125.68,134.16) 125.68,132.16 125.37,131.85 123.7,131.85 121.69,133.86 119.25,133.86 118.14,134.98 118.14,136.98 v1(122.58,141.43)
/LED_PHY1_LINK: length 117.7
  TOP w0.203: R1353.2 v1(126.7,134.16) R1368.1 ; v1(124.05,141.45) 123.83,141.45 123.38,141.01 U6.82 ; R1505.2 v1(195.88,180.92)
  ART04 w0.178: v1(195.88,180.92) 161.93,146.97 v1(161.93,146.05)
  BOTTOM w0.203: v1(161.93,146.05) 161.44,145.57 157.46,145.57 144.61,132.71 129.03,132.71 127.58,134.16 v1(126.7,134.16) 126.7,132.54 125.6,131.44 123.53,131.44 121.62,133.35 119,133.35 117.73,134.62 117.73,137.54 122.15,141.96 123.55,141.96 v1(124.05,141.45)
/LED_PHY2_ACT: length 109.8
  TOP w0.203: U6.78 121.78,141.72 122.81,142.75 v1(123.7,142.75) ; R1366.1 128.83,131.01 v1(129.51,130.33) 128.83,129.64 R1356.2 ; R1508.2 v1(192.7,180.92)
  ART04 w0.178: v1(123.7,142.75) 125.19,142.75 129.95,138 129.95,130.76 v1(129.51,130.33) ; v1(192.7,180.92) 192.52,180.48 161.16,149.13 161.16,148.72 159.39,146.94 v1(154.56,146.94)
  BOTTOM w0.203: v1(154.56,146.94) 152.65,145.03 135.59,145.03 134.04,143.48 124.43,143.48 v1(123.7,142.75)
/LED_PHY2_LINK: length 104.9
  TOP w0.203: U6.79 122.18,138.88 122.38,138.68 R1371.1 122.12,137.38 121.87,137.13 121.87,135.58 v1(121.67,135.38) 122.38,134.67 R1355.2 ; R1507.2 v1(193.76,180.92)
  ART04 w0.178: v1(193.76,180.92) 193.46,180.21 162.48,149.22 v1(161.93,149.22)
  BOTTOM w0.203: v1(121.67,135.38) 125.45,139.17 128.3,139.17 129.41,138.05 129.41,134.24 129.92,133.73 144.35,133.73 158.52,147.9 160.6,147.9 v1(161.93,149.22)
/LED_PHY3_ACT: length 108.4
  TOP w0.203: 126.82,130.28 126.87,130.33 v1(128.63,130.33) ; 126.82,130.28 R1358.2 ; 126.82,130.28 R1363.1 ; R1504.2 v1(190.58,180.92) ; U6.76 120.98,141.68 122.2,142.9 v1(123.11,143.28)
  ART04 w0.178: v1(123.11,143.28) 123.11,142.67 123.74,142.04 124.92,142.04 129.44,137.52 129.44,131.14 v1(128.63,130.33) ; v1(190.58,180.92) 189.8,179.04 160.09,149.33 160.01,149.13 158.45,147.57 154.31,147.57 v1(153.67,146.94)
  BOTTOM w0.203: v1(123.11,143.28) 123.83,143.99 133.83,143.99 135.38,145.54 152.27,145.54 v1(153.67,146.94)
/LED_PHY3_LINK: length 105.1
  TOP w0.203: R1503.2 v1(191.64,180.92) ; v1(121.67,134.49) 121.63,134.53 R1357.2 120.95,135.51 121.46,136.02 121.46,137.12 121.2,137.38 R1365.1 120.95,138.81 121.38,139.24 U6.77
  ART04 w0.178: v1(160.66,149.22) 191.14,179.71 v1(191.64,180.92)
  BOTTOM w0.203: v1(121.67,134.49) 121.16,135 121.16,135.76 124.97,139.57 128.65,139.57 130.05,138.18 130.05,134.75 130.56,134.24 144.28,134.24 158.35,148.31 159.74,148.31 v1(160.66,149.22)
/LED_PHY4_ACT: length 102
  TOP w0.203: R1501.2 v1(188.47,180.92) ; R1360.2 v1(118.67,135.17) 119.18,135.67 119.18,137.12 118.92,137.38 R1362.1 118.67,137.8 119.38,138.51 U6.72
  ART04 w0.178: v1(188.47,180.92) 186.98,177.34 161.26,151.61 160.5,151.61 v1(158.12,149.22)
  BOTTOM w0.203: v1(118.67,135.17) 119.31,135.8 119.31,135.95 123.95,140.59 129.16,140.59 131.06,138.68 131.06,137.41 132.08,136.4 133.86,136.4 135,135.25 144.15,135.25 v1(158.12,149.22)
/LED_PHY4_LINK: length 101.3
  TOP w0.203: U6.73 119.78,139.09 120.1,138.78 R1364.1 119.84,137.38 119.59,137.13 119.59,135.67 v1(120.1,135.17) R1359.2 ; R1502.2 v1(189.53,180.92)
  ART04 w0.178: v1(159.39,149.22) 161.32,151.15 161.34,151.15 188.41,178.22 v1(189.53,180.92)
  BOTTOM w0.203: v1(120.1,135.17) 120.68,135.74 120.68,135.92 124.87,140.11 128.88,140.11 130.56,138.43 130.56,137.03 131.7,135.89 133.73,135.89 134.87,134.75 144.21,134.75 158.18,148.72 158.88,148.72 v1(159.39,149.22)
/LED_POWER_G: length 1.5
  TOP w0.203: Q3606.3 57.66,17.91 57.63,17.88 R3615.1
/LED_POWER_R: length 1.6
  TOP w0.203: Q3605.3 61.37,18.77 R3614.1
/LED_SATA: length 9
  TOP w0.203: R3609.1 72.87,5.69 73.91,6.73 73.91,8.38 76.91,11.38 Q3604.3
/OC0_USB30_REAR_1: length 48.4
  TOP w0.127: R2032.1 131.87,44.34 132.75,44.7 133.1,44.7 133.48,45.08 133.48,45.59 133.71,45.82 U2002.25
  TOP w0.203: v1(105.84,41.53) 105.1,41.22 101.73,41.22 101.12,41.83 101.12,43.79 100.58,44.32 R2140.1 ; v1(134.9,46.27) 134.9,46.14 134.58,45.82 U2002.25
  ART04 w0.178: v1(105.84,41.53) 105.84,43.1 106.93,44.19 107.56,44.19 108.2,44.83 111.13,44.83 111.86,44.1 116.47,44.1 118.48,46.1 120.19,46.1 123.11,43.18 124.12,43.18 125.52,41.78 130.05,41.78 133.73,45.47 134.1,45.47 v1(134.9,46.27)
/OC1_USB30_REAR_1: length 22.7
  TOP w0.203: U2101.67 116.29,46.94 116.08,46.74 115.57,46.74 v1(115.32,46.48) ; R2143.2 97.63,46.85 v1(99.77,46.85) 100.32,46.85 100.58,46.58 R2139.1
  ART04 w0.178: v1(99.77,46.85) 103.77,46.85 104.94,48.02 106.67,48.02 107.7,46.99 108.84,46.99 110.24,45.59 114.43,45.59 v1(115.32,46.48)
/OC_USB30_REAR_1: length 281.3
  TOP w0.203: v1(99.75,45.87) 100.13,45.49 R2139.2 ; U2203.3 237.39,174.93 v1(238.46,174.93) 238.51,174.88 R2215.1
  ART03 w0.178: v1(195.91,78.61) 195.07,77.77 195.07,68.07 v1(193.55,66.55) ; v1(97.16,29.59) 101.85,24.89 115.72,24.89 116.46,24.16 122.81,24.16 123.5,23.47 124.66,23.47 125.35,24.16 129.32,24.16 130.9,25.74 130.9,26.18 132.79,28.07 136.21,28.07 137.47,29.32 145.28,29.32 146.54,30.58 150.55,30.58 153.34,33.38 154.61,33.38 161.39,40.16 166.28,40.16 167.14,41.02 168.66,41.02 169.47,41.83 v1(170.36,41.83)
  ART04 w0.178: v1(195.91,78.61) 197.1,79.81 197.1,148.06 198.77,149.73 219.48,149.73 226.49,156.74 226.49,160.38 230.94,164.82 ; v1(99.75,45.87) 101.12,44.5 101.12,41.61 101.11,41.58 100.89,40.26 97.16,36.52 v1(97.16,29.59) ; v1(170.36,41.83) 170.87,41.83 180.98,51.93 180.98,52.7 180.99,52.72 180.99,53.13 182.44,54.57 184.4,54.57 192.27,62.44 192.27,65.26 v1(193.55,66.55)
  ART04 w0.203: v1(238.46,174.93) 238.46,170.72 232.56,164.82 230.94,164.82
/OE0: length 71.3
  TOP w0.203: v1(69.14,142.14) 69.14,142.19 68.91,142.42 R2943.2 68.91,143.86 67.6,145.16 66.3,145.16 66.19,145.27 U2904.22 ; R2983.2 25.97,130.87 25.63,131.22 v1(25.63,131.83)
  ART03 w0.178: v1(44.32,127.89) v1(44.32,141.73)
  ART04 w0.178: v1(25.63,131.83) 27.2,131.83 31.46,127.57 39.08,127.57 39.4,127.89 v1(44.32,127.89) ; v1(44.32,141.73) 44.32,144.75 44.73,145.16 49.84,145.16 52.75,142.24 56.52,142.24 57.15,142.87 68.45,142.87 69.14,142.19 v1(69.14,142.14)
/OE1: length 72.7
  TOP w0.203: R2988.2 v1(26.42,132.46) ; U2903.22 84.55,145.11 85.21,144.46 R2933.2 85.47,144.12 85.74,143.85 85.74,142 v1(85.61,141.87)
  ART03 w0.178: v1(85.61,141.87) 85.59,141.85 75.48,141.85 75.26,141.63 75.23,141.63 66.54,132.93 66.54,132.51 65.82,131.8 65.51,131.8 v1(62.99,129.29)
  ART04 w0.178: v1(62.99,129.29) 61.78,128.08 59.38,128.08 59.18,128.27 53.72,128.27 53.49,128.5 39.47,128.5 38.93,127.95 31.66,127.95 27.15,132.46 v1(26.42,132.46)
/OE2: length 240.4
  TOP w0.203: v1(25.98,125.6) 25.98,125.81 R198.2 ; U16.22 160.58,37.77 160.45,37.64 160.45,37.64 160.12,37.32 160.12,37.31 160.1,37.29 160.1,36.78 159.36,36.04 R143.2 157.53,35.53 156.24,34.24 156.24,31.95 v1(157.18,31.01)
  ART03 w0.178: v1(157.18,31.01) 154.83,28.67 152.82,28.67 152.01,27.86 147.67,27.86 144.9,25.09 134.98,25.09 128.58,18.69 78.98,18.69 74.69,22.99 67.85,22.99 59.98,30.86 45.13,30.86 43.1,32.89 43.1,40.87 37.14,46.84 37.14,57.79 33.35,61.57 33.35,73.04 31.81,74.59 31.81,76.02 33.83,78.05 33.83,99.45 32.36,100.92 32.36,101.86 25.19,109.03 25.19,114.95 22.74,117.41 22.74,122.35 v1(25.98,125.6)
/OE3: length 255
  TOP w0.152: v1(160.63,46.23) 160.63,46.66 160.98,47.02 U15.22
  TOP w0.203: v1(160.63,46.23) 160.63,45.53 160,44.91 R108.2 ; R199.2 v1(25.76,127.25)
  ART03 w0.178: v1(25.76,127.25) 25.37,127.63 24.38,127.63 22.43,125.68 22.43,117.04 23.34,116.13 23.34,115.31 24.81,113.84 24.81,108.87 31.98,101.7 31.98,100.76 33.45,99.29 33.45,78.21 31.43,76.18 31.43,74.43 32.97,72.89 32.97,61.42 36.75,57.63 36.75,46.68 42.72,40.72 42.72,32.73 44.97,30.48 59.82,30.48 67.7,22.61 74.53,22.61 78.82,18.31 128.74,18.31 135.14,24.71 145.06,24.71 147.81,27.46 152.17,27.46 152.98,28.27 156.85,28.27 v1(160.22,31.65)
  ART04 w0.178: v1(160.22,31.65) 160.12,31.75 160.12,34.15 160.49,34.52 160.49,46.09 v1(160.63,46.23)
/PCH_IRQ_TPM_SPI: length 191.3
  TOP w0.203: R2782.2 v1(25.53,28.07) ; R284.2 170.93,38.74 v1(170.41,39.27) 168.22,39.27 167.97,39.01 R283.2 166.84,38.74 R218.2
  ART04 w0.178: v1(154.64,16.38) 152.81,18.21 142.91,18.21 138.21,13.51 127.42,13.51 125.05,15.89 122.17,15.89 120.61,14.33 73.96,14.33 70.11,18.17 32.65,18.17 25.53,25.3 v1(25.53,28.07) ; v1(170.41,39.27) 171.1,39.27 171.26,39.1 171.26,35.7 170.61,35.05 170.61,32.85 170.47,32.71 170.47,31.36 170.78,31.05 170.78,30.67 v1(175.16,26.29)
  BOTTOM w0.203: v1(175.16,26.29) 174.83,26.62 172.39,26.62 170.1,24.33 164.03,24.33 162.76,25.6 162.33,25.78 159.11,25.78 154.69,21.36 154.69,16.51 154.64,16.46 v1(154.64,16.38)
/PERST_5G_LTE: length 178.5
  TOP w0.203: v1(52.32,124.08) 51.85,124.55 J3.294 ; R852.2 178.33,84.23 178.09,83.98 v1(177.64,83.98)
  ART03 w0.178: v1(54.48,137.92) 53.75,137.18 53.75,127.16 52.32,125.74 v1(52.32,124.08) ; v1(133.6,99.44) 133.62,99.43 134.36,99.43 139.61,104.67 159.82,104.67 167.64,96.85 167.64,85.77 v1(169.72,83.69)
  ART04 w0.178: v1(177.64,83.98) 174.79,83.98 174.16,83.35 173.62,83.35 172.52,84.45 170.49,84.45 v1(169.72,83.69) ; v1(133.6,99.44) 130.94,99.44 115.94,114.44 109.59,114.44 108.46,115.57 108.46,116.2 104.87,119.8 104.25,120.72 103.5,121.46 101.72,123.14 101.48,123.64 101.02,125.45 99.71,127.08 99.3,128.3 98.55,130.3 98.33,131.19 98.34,131.44 98.49,131.89 98.5,132.09 98.38,132.28 97.41,132.97 96.63,133.71 93.7,135.8 92.39,136.02 82.11,136.02 81.41,135.76 76.45,135.76 75.18,137.03 55.37,137.03 v1(54.48,137.92)
/PERST_M2_R: length 5.3
  TOP w0.203: R56.2 C601.1 10.85,155.22 10.36,155.7 D3.1 9.14,157.81 R606.2
/PEWAKE_5G_LTE: length 157.1
  TOP w0.203: v1(173.86,83.95) 173.66,84.15 R833.2 ; J3.314 56.85,124.54 v1(56.46,124.15)
  ART03 w0.178: v1(96.39,120.01) 95.89,119.51 91.57,119.51 90.55,120.52 79.38,120.52 75.54,116.69 75.54,116.61 75.07,116.14 58.61,116.14 58.18,116.57 58.18,119.24 56.01,121.41 56.01,123.7 v1(56.46,124.15) ; v1(167.51,83.69) 167.51,84.33 166.65,85.19 166.65,96.34 159.45,103.54 139.92,103.54 134.29,97.92 v1(133.65,97.92)
  ART04 w0.178: v1(173.86,83.95) 172.8,85.01 168.76,85.01 167.51,83.77 v1(167.51,83.69) ; v1(96.39,120.01) 96.9,120.52 98.3,120.52 101.09,117.73 102.24,117.22 103.12,116.59 103.66,115.16 107.65,111.18 112.15,111.18 116.81,106.52 126.24,102.61 130.18,98.68 132.88,98.68 v1(133.65,97.92)
/PEWAKE_M2: length 14.4
  TOP w0.203: R89.2 27.43,146.58 28.62,147.77 R131.1 28.22,148.44 27.31,149.35 22.73,149.35 20.76,147.37 J601.54
/PFO_ADM708: length 17.2
  TOP w0.203: v1(20.19,91.84) 20.19,92.83 19.99,93.03 R3403.2 19.46,92.68 19.25,92.47 18.69,92.47 18.49,92.27 U10.6 ; Q3401.3 v1(17.45,81.55)
  ART03 w0.178: v1(17.45,81.55) 18.53,81.55 19.51,82.52 19.51,91.15 v1(20.19,91.84)
/PFO_Q_ADM708: length 43.7
  TOP w0.203: v1(21.03,78.96) 21.01,78.98 R3413.1 ; v1(19.56,49.53) 13.08,49.53 11.91,48.36 R3414.2 R3408.1 12.04,47.4 12.49,46.94 12.78,46.94 13.17,47.33 U3402.5
  ART03 w0.178: v1(19.56,49.53) 20.45,50.42 20.45,56.95 22.48,58.98 22.48,72.9 21.33,74.05 21.33,78.66 v1(21.03,78.96)
/PG_24711_POWER: length 377.1
  TOP w0.203: v1(25.71,166.85) 25.29,167.26 R3022.1 24.34,167.26 23.93,166.85 22.91,166.85 22.53,166.47 R3023.1 ; U3.H14 v1(200.26,51.55)
  ART03 w0.178: v1(51.66,25.98) 51.93,26.25 58.51,26.25 70.7,14.06 80.73,14.06 82.73,12.05 147.01,12.05 152.63,17.68 160.63,17.68 164.58,21.63 164.85,21.63 166.64,23.42 169.37,23.42 174.06,28.1 175.91,28.1 175.91,28.1 193.25,28.1 194.93,26.43 201.82,26.43 204.6,29.21 207.96,29.21 209.43,30.68 209.43,35.22 211.71,37.5 211.71,38.45 209.27,40.89 205.99,40.89 203.52,43.37 203.21,43.37 201.55,45.03 201.55,50.27 v1(200.26,51.55) ; v1(43.61,33.48) 43.54,33.55 43.54,42.06 38.11,47.49 38.11,57.4 33.78,61.72 33.78,73.32 v1(32.28,74.82)
  ART04 w0.178: v1(51.66,25.98) 51.66,26.64 45.54,32.77 44.32,32.77 v1(43.61,33.48)
  BOTTOM w0.203: v1(32.28,74.82) 31.95,75.15 31.95,81.08 26.8,86.23 26.8,91.82 26.04,92.58 26.04,115.57 22.7,118.91 22.48,121.16 21.34,123.19 21.34,129.41 22.1,130.17 22.1,131.49 23.13,133.22 24.45,135.7 31.68,142.93 35.46,142.93 39.3,146.77 39.3,151.96 33.93,157.33 33.93,158.83 30.7,162.06 27.32,162.06 26.16,163.22 26.16,166.39 v1(25.71,166.85)
/PLL_INT: length 333.3
  TOP w0.203: R266.1 v1(5.99,122.61) ; R268.1 v1(191.69,52.31)
  ART03 w0.178: v1(24.26,120.14) 24.26,121.89 31.06,128.69 31.06,147.73 39.03,155.7 60.69,155.7 62.76,157.77 70.36,157.77 71.34,158.75 95.86,158.75 99.75,162.64 103.05,162.64 103.84,163.42 126.86,163.42 126.94,163.5 143.35,163.5 145.71,161.14 156.12,161.14 169.61,147.65 187.57,147.65 189.64,145.58 192.57,145.58 v1(193.04,146.05)
  ART04 w0.178: v1(5.99,122.61) 5.99,122.86 9.27,126.14 11.71,126.14 15.88,121.97 21.67,121.97 22.99,120.65 23.75,120.65 v1(24.26,120.14)
  BOTTOM w0.203: v1(191.69,52.31) 190.36,52.31 190.12,52.07 189.36,52.07 188.21,53.21 188.21,57.97 193.09,62.85 193.09,64.44 194.18,65.53 194.18,67.58 198.11,71.51 198.11,140.98 v1(193.04,146.05)
/PLL_LOS: length 301.4
  TOP w0.203: R270.1 193.17,57.4 193.44,57.67 v1(193.73,57.67) ; R265.1 v1(14.54,119.77)
  ART03 w0.178: v1(26.42,155.96) 26.42,153.54 19.3,146.43 19.3,144.4 18.91,144 18.91,136.54 20.42,135.03 v1(20.42,121.06) ; v1(193.73,57.67) 193.73,59 190.94,61.79 190.94,72.96 192.58,74.6 192.58,90.12 186.12,96.58 186.12,106.27 170.5,121.89 170.5,144.05 155.96,158.59 145.56,158.59 144.87,159.28 134.25,159.28 132.6,160.93 122.93,160.93 122.34,161.52 107.34,161.52 106.7,160.88 104.75,160.88 100.71,156.84 73.03,156.84 71.02,154.84 64.92,154.84 62.23,152.15 56.29,152.15 v1(56.03,152.4)
  ART04 w0.178: v1(26.42,155.96) 26.92,156.46 32.89,156.46 33.66,155.7 49.86,155.7 50.29,155.27 52.48,155.27 55.35,152.4 v1(56.03,152.4) ; v1(14.54,119.77) 15.83,121.06 v1(20.42,121.06)
/PLL_RST: length 319.8
  TOP w0.203: R267.1 v1(3.61,133.54) ; v1(191.08,51.84) 191.62,51.84 192,51.46 R269.1
  ART03 w0.178: v1(44.03,37.58) 43.94,37.67 43.94,42.29 38.63,47.6 38.63,58.04 36.21,60.46 36.21,77.99 34.8,79.4 34.8,94.03 35.56,94.79 35.56,98.26 32.77,101.06 32.77,101.99 25.57,109.19 25.57,115.19 v1(23.18,117.59) ; v1(53.47,25.78) 53,25.31 53,22.67 65.88,9.78 76.2,9.78 76.89,10.46 80.13,10.46 80.6,9.99 148.04,9.99 149.76,8.28 159.03,8.28 161.76,11.01 161.76,11.86 163.44,13.54 163.44,15.37 165.7,17.63 166.13,17.63 169.01,20.51 170.99,20.51 171.76,21.28 172.95,21.28 175.17,23.5 175.17,24.42 v1(175.64,24.89)
  ART04 w0.178: v1(44.03,37.58) 44.03,36.94 53.47,27.51 v1(53.47,25.78) ; v1(23.18,117.59) 22.05,118.72 10.2,118.72 9.3,117.82 8.12,117.82 4.91,121.03 4.91,132.24 v1(3.61,133.54) ; v1(175.64,24.89) 175.79,25.04 175.79,26.44 176.33,26.98 177.94,26.98 185.28,34.33 186.6,34.33 186.94,34.67 186.94,35.69 185.38,37.25 185.38,41.57 184.66,42.29 184.66,46.86 187.45,49.66 188.21,49.66 190.4,51.84 v1(191.08,51.84)
/POWER_BTN_MCU: length 215.7
  TOP w0.203: v1(17.27,26.16) R3621.2 C3617.1 ; R2827.2 197.87,35.58 197.33,35.05 v1(197.33,35)
  ART03 w0.178: v1(36.83,15.6) 37.47,16.23 37.47,20.89 39.06,22.48 41.25,22.48 41.85,23.08 44.39,23.08 48.71,27.39 59.34,27.39 71.53,15.2 83.38,15.2 85.29,13.28 138.13,13.28 144.07,19.23 156.18,19.23 156.69,19.74 161.07,19.74 161.87,20.54 161.87,24.13 162.53,24.79 167.87,24.79 173.75,30.67 178.99,30.67 180.42,29.25 190.31,29.25 191.77,30.7 191.77,30.79 192.69,31.71 194.99,31.71 195.02,31.69 195.65,31.69 197.33,33.37 v1(197.33,35)
  ART04 w0.178: v1(36.83,15.6) 36.2,16.23 25.17,16.23 16.76,24.64 16.76,25.65 v1(17.27,26.16)
/RESET_1V8: length 2.7
  TOP w0.203: U3401.1 26.35,79.28 R3420.1 R235.2
/RST_4G_LTE: length 256.3
  TOP w0.203: J3.290 50.85,124.28 v1(51.05,124.08) ; R713.1 R714.1 190.19,59.15 189.71,58.67 v1(189.61,58.67)
  ART03 w0.178: v1(170.54,41) 169.95,40.41 169.09,40.41 166.27,37.59 160.12,37.59 154.32,31.79 153.07,31.79 151.11,29.82 147.17,29.82 144.84,27.49 134,27.49 130,23.49 127.08,23.49 125.65,22.07 101.27,22.07 96.14,27.2 74.73,27.2 68.34,33.59 60.36,33.59 56.2,37.76 56.2,43.44 44.07,55.57 44.07,58.93 41.33,61.67 41.33,70.95 42.28,71.9 42.28,74.31 41.64,74.95 41.64,75.42 41.95,75.72 41.95,91.37 44.07,93.49 v1(44.07,93.52)
  ART04 w0.178: v1(189.61,58.67) 185.13,54.19 183.12,54.19 181.94,53.01 181.94,52.23 170.7,41 v1(170.54,41)
  BOTTOM w0.203: v1(44.07,93.52) 44.86,94.31 44.86,115.44 45.74,116.33 46.35,116.33 46.78,116.76 48.31,120.44 49.66,121.79 49.66,122.68 v1(51.05,124.08)
/RST_4G_LTE_R: length 89.1
  TOP w0.203: Q701.3 R701.1 189.46,69.44 189.48,69.47 C701.1 190.09,70.34 189.64,70.79 189.64,73 187.94,74.7 182.16,74.7 177.23,73.53 173.16,73.53 171.07,75.62 171.07,81.03 169.04,83.06 165.86,83.06 v1(164.82,84.1) ; v1(147.66,89.6) 146.56,88.5 146.56,86.08 C710.1 ; J701.22 150.55,94.67 150.55,94.66 v1(150.55,94.54)
  ART03 w0.178: v1(164.82,84.1) 164.31,84.1 163.76,83.54 163.76,83.13 163.39,82.77 160.93,82.77 160.44,83.26 160.44,93.26 160.21,93.48 160.21,98.96 158.29,100.89 151.74,100.89 150.55,99.69 v1(150.55,94.54)
  ART04 w0.178: v1(147.66,89.6) 147.66,90.91 149.61,92.86 149.61,93.6 v1(150.55,94.54)
/RST_5G_LTE_R: length 26.9
  TOP w0.203: Q801.3 187.96,76.07 C93.2 186.27,75.66 182.03,75.66 181.23,76.45 181.23,79.68 179.07,81.84 176.65,83.44 173.48,83.44 173.1,83.82 173.1,86.28 173.51,86.69 175.72,86.69 176.03,87 J803.67
/RST_ADM6823: length 1.9
  TOP w0.203: U10.5 18.99,91.26 19.76,90.49 R3419.2
/RST_BTN_MCU: length 264.7
  TOP w0.203: R3423.1 16.22,88.08 v1(16.38,87.93) 17.28,87.93 17.49,88.13 U10.1 ; R2831.2 194.56,33.27 194.82,33.02 194.82,31.75 v1(193.93,30.86) ; R3425.2 39.38,19.26 C3408.2
  TOP w0.254: v1(38.63,18.64) 38.63,18.38 38.89,18.12 R3425.2
  ART03 w0.178: v1(193.93,30.86) 193.46,31.33 192.85,31.33 192.15,30.64 192.15,30.55 190.47,28.87 173.52,28.87 168.91,24.26 163.07,24.26 162.41,23.6 162.41,20.53 161.23,19.35 156.92,19.35 156.26,18.69 148.87,18.69 142.99,12.81 84.47,12.81 82.46,14.82 71.05,14.82 58.85,27.01 48.87,27.01 44.55,22.69 42.08,22.69 41.48,22.1 39.21,22.1 37.97,20.86 37.97,19.3 v1(38.63,18.64)
  ART04 w0.178: v1(38.63,18.64) 37.97,18.64 31.12,25.5 31.12,32.97 27.05,37.03 27.05,39.12 22.99,43.18 22.99,53.21 24.13,54.36 24.13,57.66 22.73,59.05 22.73,76.2 18.03,80.9 18.03,83.31 16.38,84.96 v1(16.38,87.93)
/RST_MCU_1911_R: length 297.5
  TOP w0.203: v1(26.24,89.28) 25.98,89.03 19.76,89.03 18.86,89.93 18.19,89.93 17.99,89.73 U10.2 17.99,87.93 17.78,87.72 R3424.1 ; R2848.2 v1(204.09,57.66)
  ART04 w0.178: v1(204.09,57.66) 205.07,56.68 207.11,56.68 209.32,54.47 209.32,49.76 211.84,47.24 211.84,45.74 212.1,45.48 212.1,41.16 209.59,38.65 209.59,30.31 210.15,29.76 210.15,28.92 207.24,26.01 207.24,22.71 205.49,20.95 205.49,18.57 203.2,16.28 189.85,16.28 189.29,15.72 175.39,15.72 173.69,17.42 170.38,17.42 168.34,19.47 166.91,19.47 166.32,20.07 163.99,20.07 163.61,19.68 142.17,19.68 137.19,14.7 131.06,14.7 127.76,18 75.58,18 70.23,23.34 54.35,23.34 52.83,24.86 52.83,27.6 43.43,37 43.43,40 28.52,54.91 28.52,71.45 v1(29.21,72.14)
  BOTTOM w0.203: v1(29.21,72.14) 29.85,72.77 29.85,81.41 26.24,85.01 v1(26.24,89.28)
/RST_Q_ADM6823: length 14.1
  TOP w0.203: R234.1 C3407.1 ; C3407.1 24.26,79.37 24.45,79.18 U3401.3 ; C3407.1 R236.2 22.89,79.73 22.68,79.93 22.68,81.18 22.89,81.38 22.89,85.97 22.41,86.44 R3426.2
/RST_SPIRST_TPM: length 29.6
  TOP w0.203: R169.2 C168.1 ; R169.2 15.24,27.18 15.01,26.95 R174.1 13.94,27.61 11.13,27.61 Q4.3 ; R169.2 15.72,27.3 16.61,28.19 20.19,28.19 R2780.1 R2781.1 21.82,28.47 21.46,28.83 v1(21.08,28.83) ; v1(25.88,38.66) 27.31,38.66 27.59,38.37 J2701.39
  ART03 w0.178: v1(21.08,28.83) 21.08,33.86 v1(25.88,38.66)
/RST_USB_HUB: length 319.6
  TOP w0.203: v1(107.81,100.88) 112.25,105.32 112.83,106.7 112.83,113.79 113.54,114.5 114.02,114.5 115.6,116.08 J3.229 ; R346.2 155.5,47.01 v1(155.63,47.01) 155.66,46.99 156.47,46.99 156.57,46.88 157.52,46.88 157.72,47.09 R349.1 158.19,47.47 158.39,47.67 158.78,47.67 R116.1
  ART03 w0.178: v1(44.2,111.89) 48.51,116.2 51.08,116.2 52.6,117.73 54.53,117.73 56.39,115.87 56.39,112.27 61.04,107.62 79.38,107.62 83.57,111.81 v1(89.56,111.81)
  ART04 w0.178: v1(155.63,47.01) 154.71,46.1 154.71,44.4 155.37,43.74 155.37,43.31 154.2,42.14 154.2,35.76 153.97,35.53 152,35.53 149.35,32.88 149.35,31.87 146.18,28.7 138.58,22.48 134.66,22.48 132.6,20.42 129.08,20.42 127.97,21.54 79.9,21.54 77.71,21.97 73.71,25.97 73.71,29.97 68.75,34.92 57.71,34.92 52.43,40.21 48.47,40.21 36.96,51.72 36.96,78.79 35.18,80.57 35.18,92.97 35.92,93.7 35.92,96.96 37.82,98.87 37.82,105.82 43.9,111.89 v1(44.2,111.89) ; v1(107.81,100.88) 104.51,104.18 101.27,106.58 97.88,108.85 93.89,109.64 91.72,111.81 v1(89.56,111.81)
/RST_USB_HUB_R: length 69.3
  TOP w0.203: U2002.24 133.53,46.22 133.46,46.16 v1(133.44,46.16) 133.41,46.13 R229.2 132.53,46.38 132.29,46.48 R137.2 R2038.2 ; v1(167.82,47.68) 168.1,47.4 C131.1 R138.2
  ART03 w0.178: v1(167.23,34.75) 165.63,34.75 158.03,27.15 158.03,26.94 157.25,26.16 v1(150.8,26.16)
  ART04 w0.178: v1(167.23,34.75) 167.23,38.78 166.33,39.68 166.33,40.37 165.73,40.97 165.73,44.62 167.82,46.71 v1(167.82,47.68)
  BOTTOM w0.203: v1(133.44,46.16) 133.46,46.13 133.46,43.65 134.01,43.1 134.01,42.27 135.05,41.22 137.78,41.22 138.3,40.7 138.3,38.35 140.13,36.52 141.41,36.52 141.68,36.26 141.68,35.28 v1(150.8,26.16)
/RTL8367_RST: length 138.3
  TOP w0.203: R139.2 167.63,45.79 167.64,45.8 v1(169.6,45.8) ; U6.91 126.98,137.86 127.58,137.26 128.24,137.26 128.81,137.83 R118.1 C138.1 R121.2 v1(132.51,137.83)
  ART03 w0.178: v1(172.67,54.13) 172.67,56.79 171.31,58.15 171.31,67.46 164.87,73.9 164.87,75.89 162.82,77.94 158.23,77.94 156.93,76.64 154.12,76.64 152.25,78.52 152.25,80.43 150.99,81.68 150.39,81.92 148.41,82.52 147.04,82.52 145.2,83.29 140.01,83.29 138.81,84.48 136.27,84.48 133.73,87.02 133.73,92.46 133.08,93.1 133.08,99.66 133.41,99.98 133.91,99.98 137.4,103.47 137.4,132.94 v1(132.51,137.83)
  ART04 w0.178: v1(169.6,45.8) 170.03,45.8 172.67,48.43 v1(172.67,54.13)
/SYS_RST_IN: length 57.5
  TOP w0.203: J3.297 52.1,116.96 52.25,116.81 v1(52.68,116.81) ; v1(28.45,81.3) 27.56,81.3 R3420.2 R234.2
  ART04 w0.178: v1(28.45,81.3) 28.91,81.76 28.91,97.74 31.62,100.46 31.62,105.28 33.15,106.81 33.15,109.16 40.01,116.03 51.89,116.03 v1(52.68,116.81)
/TEC_TRIM1_ON: length 10.3
  TOP w0.203: R1025.2 181.72,52.42 v1(181.47,52.67) ; R1014.2 175.29,55.6 Q1002.1 176.3,55.47 176.73,55.9 v1(176.73,56.26)
  BOTTOM w0.203: v1(176.73,56.26) 176.73,56.08 179.15,53.67 179.15,53.55 180.5,52.2 180.99,52.2 v1(181.47,52.67)
/TEC_TRIM2_ON: length 11.7
  TOP w0.203: v1(180.52,52.91) 180.52,52.91 180.52,52.23 R1026.2 ; v1(174.28,57.66) 174.24,57.69 Q1001.1 174.75,58.55 175.03,58.83 R1013.2
  BOTTOM w0.203: v1(174.28,57.66) 176.38,57.66 177.77,56.26 177.77,55.61 179.55,53.84 179.55,53.72 180.36,52.91 v1(180.52,52.91)
/TPM_RST: length 46.3
  TOP w0.203: R2760.1 85.41,129.79 88.14,129.79 89.12,128.81 89.12,128.11 90.22,127.01 90.22,125 93.02,122.2 95.73,122.2 v1(97.92,120.01) ; J3.225 114.6,115.67 114.1,115.16 113.49,115.16 111.82,113.5 v1(111.82,110.71)
  ART04 w0.178: v1(97.92,120.01) 97.99,120.01 100.53,117.47 101.89,116.78 102.24,116.2 102.36,115.57 103.34,114.72 107.37,110.69 111.81,110.69 v1(111.82,110.71)
/TPM_RST_R: length 186.5
  TOP w0.203: v1(84.18,132.21) 84.33,132.21 84.51,132.03 R2760.2 ; v1(19.05,24.38) 15.37,24.38 14.61,25.15 R174.2 R168.2 13.23,25.78 Q4.2
  ART04 w0.178: v1(84.18,132.21) 83.77,132.61 78.84,132.61 75.57,129.34 75.57,123.62 74.96,123.01 74.96,119.28 73.15,117.47 73.15,116.2 72.52,115.57 62.08,115.57 61.09,116.56 61.09,116.89 59.87,118.11 47.37,118.11 46.58,118.9 37.97,118.9 36.32,117.25 36.32,116.64 34.49,114.81 27.69,114.81 24.51,111.63 24.51,91.19 21.97,88.65 16.13,88.65 15.37,87.88 15.37,82.4 21.97,75.79 21.97,30.61 18.8,27.43 18.8,24.64 v1(19.05,24.38)
/WAKE_PHY0: length 189.7
  TOP w0.203: v1(153.67,36.02) 153.7,36.02 153.71,36 154.01,36 154.84,36.83 R293.2 155.29,37.22 155.88,36.63 157.4,36.63 157.53,36.75 R296.1 157.54,37.2 R70.1 ; J3.231 116.1,115.9 114.2,113.99 113.74,113.99 113.26,113.51 113.26,105.28 107.92,99.95 v1(107.92,97.76)
  ART04 w0.178: v1(107.92,97.76) 107.92,77.11 101.07,70.26 96.8,70.26 81.23,54.69 81.23,34.98 90.48,25.73 117.25,25.73 117.78,26.26 118.64,26.26 119.05,25.86 119.91,25.86 120.35,25.42 124.79,25.42 126.04,24.18 127.28,24.18 128.83,25.73 133.53,25.73 134.14,26.35 142.68,26.35 145.49,28.65 148.47,31.63 148.47,33.01 150.53,35.08 150.88,35.08 151.8,36 153.63,36 153.64,36.02 v1(153.67,36.02)
/WAKE_PHY0_R: length 69.8
  TOP w0.203: R179.1 R1215.1 145.14,67.79 144.78,67.44 v1(144.78,67) 144.83,67 145.16,66.67 146.36,66.67 146.58,66.45 R1221.2 ; R237.2 166.84,35.57 167.62,35.57 167.63,35.57 v1(169.43,35.57)
  ART04 w0.178: v1(153.37,75.44) 152.23,75.44 152.03,75.23 151.62,74.96 151.61,74.95 151,74.55 151,74.55 150.98,74.53 150.97,74.54 147.96,73.28 144.78,70.1 v1(144.78,67) ; v1(169.43,35.57) 168.28,36.73 168.28,39.03 167.25,40.06 167.25,40.75 166.65,41.35 166.65,44.12 v1(167.67,45.14)
  BOTTOM w0.203: v1(167.67,45.14) 167.28,45.52 167.28,52.4 162.99,56.69 161.29,56.69 160.02,57.96 160.02,60.4 155.42,65 155.42,67.77 152.76,70.43 152.76,74.83 v1(153.37,75.44)
AC_HPOUT_L: length 22.4
  TOP w0.203: C2521.1 191.77,19.91 v1(191.8,19.89)
  TOP w0.254: R2524.1 209.23,19.82 v1(209.23,20.13) ; R2519.2 191.69,20.62 C2521.1
  BOTTOM w0.305: v1(191.8,19.89) 191.8,19.85 193.16,18.49 194.83,18.49 196.1,17.22 206.32,17.22 v1(209.23,20.13)
AC_HPOUT_R: length 33.5
  TOP w0.254: v1(210.5,20.13) 209.91,19.53 R2525.1 ; C2520.1 186.36,25.4 v1(186.02,25.06) R2516.2
  BOTTOM w0.305: v1(186.02,25.06) 186.02,24.19 192.74,17.47 194.41,17.47 195.68,16.2 206.79,16.2 210.5,19.92 v1(210.5,20.13)
AC_IN_L: length 261.9
  TOP w0.203: J3.306 54.85,123.08 55.37,122.55 57.28,122.55 v1(57.79,123.06) ; v1(195.12,14.53) R2502.1 196.17,14.29 R2509.2 C2504.1 194.78,13.92 C2502.1 194.03,13.92 193.85,13.73 LB2503.2 193.26,14.6 193.27,14.6 D2502.2
  ART03 w0.203: v1(57.79,123.06) 57.33,122.61 57.33,121.86 58.21,120.98 62.87,120.98 63.34,121.46 75.48,121.46 77.34,123.32 77.34,128.4 83.94,135 92.48,135 97.58,140.09 104.16,140.09 105.51,141.45 107.97,141.45 108.64,141.45 109.33,142.14 114.45,142.14 117.5,139.09 117.5,135.66 120.29,132.87 121.32,132.87 131.29,122.9 131.29,109.26 130.07,108.04 130.07,103.86 132.11,101.82 v1(132.82,101.82)
  BOTTOM w0.203: v1(195.12,14.53) 195.12,14.65 193.72,16.05 188.77,16.05 177.05,27.78 172.55,27.78 168.93,31.39 165.28,31.39 164.35,32.32 164.35,33.87 163.09,35.13 160.2,35.13 158.38,36.94 158.11,37.13 157.91,37.26 157.84,37.31 157.5,37.45 157.23,37.71 157.21,37.72 156.79,38.14 156.79,38.15 156.79,38.42 156.79,38.42 156.79,39.8 156.08,40.51 152.82,40.51 150.8,42.53 150.8,45.14 148.92,47.01 148.92,50.07 141.83,57.16 141.83,60.5 140.82,61.52 140.82,63.45 141.96,64.59 141.96,70.33 141.3,70.99 141.3,75.13 140.58,75.85 139.89,75.85 135.78,79.96 135.48,80.67 135.48,85.53 136.03,86.07 136.03,94.91 137.67,96.55 137.67,98.03 133.97,101.73 132.92,101.73 v1(132.82,101.82)
AC_IN_R: length 263.2
  TOP w0.203: v1(57.79,122.05) 55.2,122.05 54.35,122.89 J3.304 ; v1(198.15,14.53) R2507.1 197.03,14.22 R2508.2 C2503.1 C2501.1 199.46,13.41 LB2502.2 200.14,15.64 D2501.2
  ART03 w0.152: 76.96,123.57 75.15,121.76 63.22,121.76 62.74,121.28 58.55,121.28 v1(57.79,122.05)
  ART03 w0.203: 76.96,123.57 76.96,128.6 83.77,135.41 92.31,135.41 97.41,140.5 103.99,140.5 105.35,141.86 108.13,141.86 108.13,141.86 108.47,141.86 109.16,142.54 114.62,142.54 119.3,137.86 119.3,135.28 121.21,133.37 121.39,133.37 131.7,123.07 131.7,108.96 130.48,107.75 130.48,104.04 132.18,102.34 133.35,102.34 v1(133.48,102.21)
  BOTTOM w0.203: v1(198.15,14.53) 198.07,14.6 195.91,14.6 194.01,16.51 188.96,16.51 177.25,28.22 172.77,28.22 169.19,31.8 166.14,31.8 165.76,32.18 165.76,33.05 163.15,35.66 160.43,35.66 158.77,37.32 158.77,37.32 158.19,37.56 157.47,38.04 157.2,38.31 157.2,40.09 156.35,40.94 152.97,40.94 151.21,42.7 151.21,45.34 149.35,47.19 149.35,50.21 142.24,57.32 142.24,60.67 141.24,61.67 141.24,63.27 142.37,64.39 142.37,70.53 141.63,71.26 141.63,75.39 140.75,76.27 140.05,76.27 136.12,80.19 135.89,80.75 135.89,85.29 136.43,85.84 136.43,94.74 138.07,96.39 138.07,98.2 134.07,102.21 v1(133.48,102.21)
AC_MICBIAS0: length 263.9
  TOP w0.203: v1(59.31,123.06) 59.31,122.37 58.17,121.22 54.92,121.22 53.35,122.8 J3.300 ; R2503.1 v1(196.7,18.41) R2504.1
  ART03 w0.203: v1(59.31,123.06) 60.17,123.92 73.56,123.92 74.42,124.79 74.42,129.59 76.35,131.52 76.35,134.97 79.43,138.05 91.22,138.05 94.36,141.19 96.31,143.14 102.89,143.14 104.94,145.19 115.77,145.19 122.73,138.23 126.34,138.23 129.62,134.95 129.62,133.68 131.66,130.62 134.19,128.09 135.1,125.89 135.1,108.43 133.12,106.45 133.12,105.81 v1(133.52,105.41)
  BOTTOM w0.203: v1(196.7,18.41) 196.2,18.41 194.9,19.71 193.9,19.71 193.47,20.14 193.15,20.14 190.6,22.69 190.6,24.41 188.85,26.16 188.85,26.93 187.15,28.64 180.71,28.64 177.32,32.03 176.84,32.03 176.28,32.59 176.28,33.83 172.38,37.73 170.06,37.73 169.62,38.17 168.39,38.17 164.29,42.27 160.59,42.27 156.97,45.88 156.97,47.47 156.49,47.95 156.06,47.95 155.78,47.67 155.3,47.67 155.27,47.68 152.63,50.32 152.63,52.56 148.34,56.85 148.34,61.07 146.23,63.18 146.23,69.46 146.63,69.87 146.63,75.86 146.48,76.01 146.48,77.2 144.76,78.92 141.21,78.92 139.6,80.52 139.6,81.02 140.74,82.16 140.74,89.05 143.51,91.82 143.51,97.7 135.8,105.41 v1(133.52,105.41)
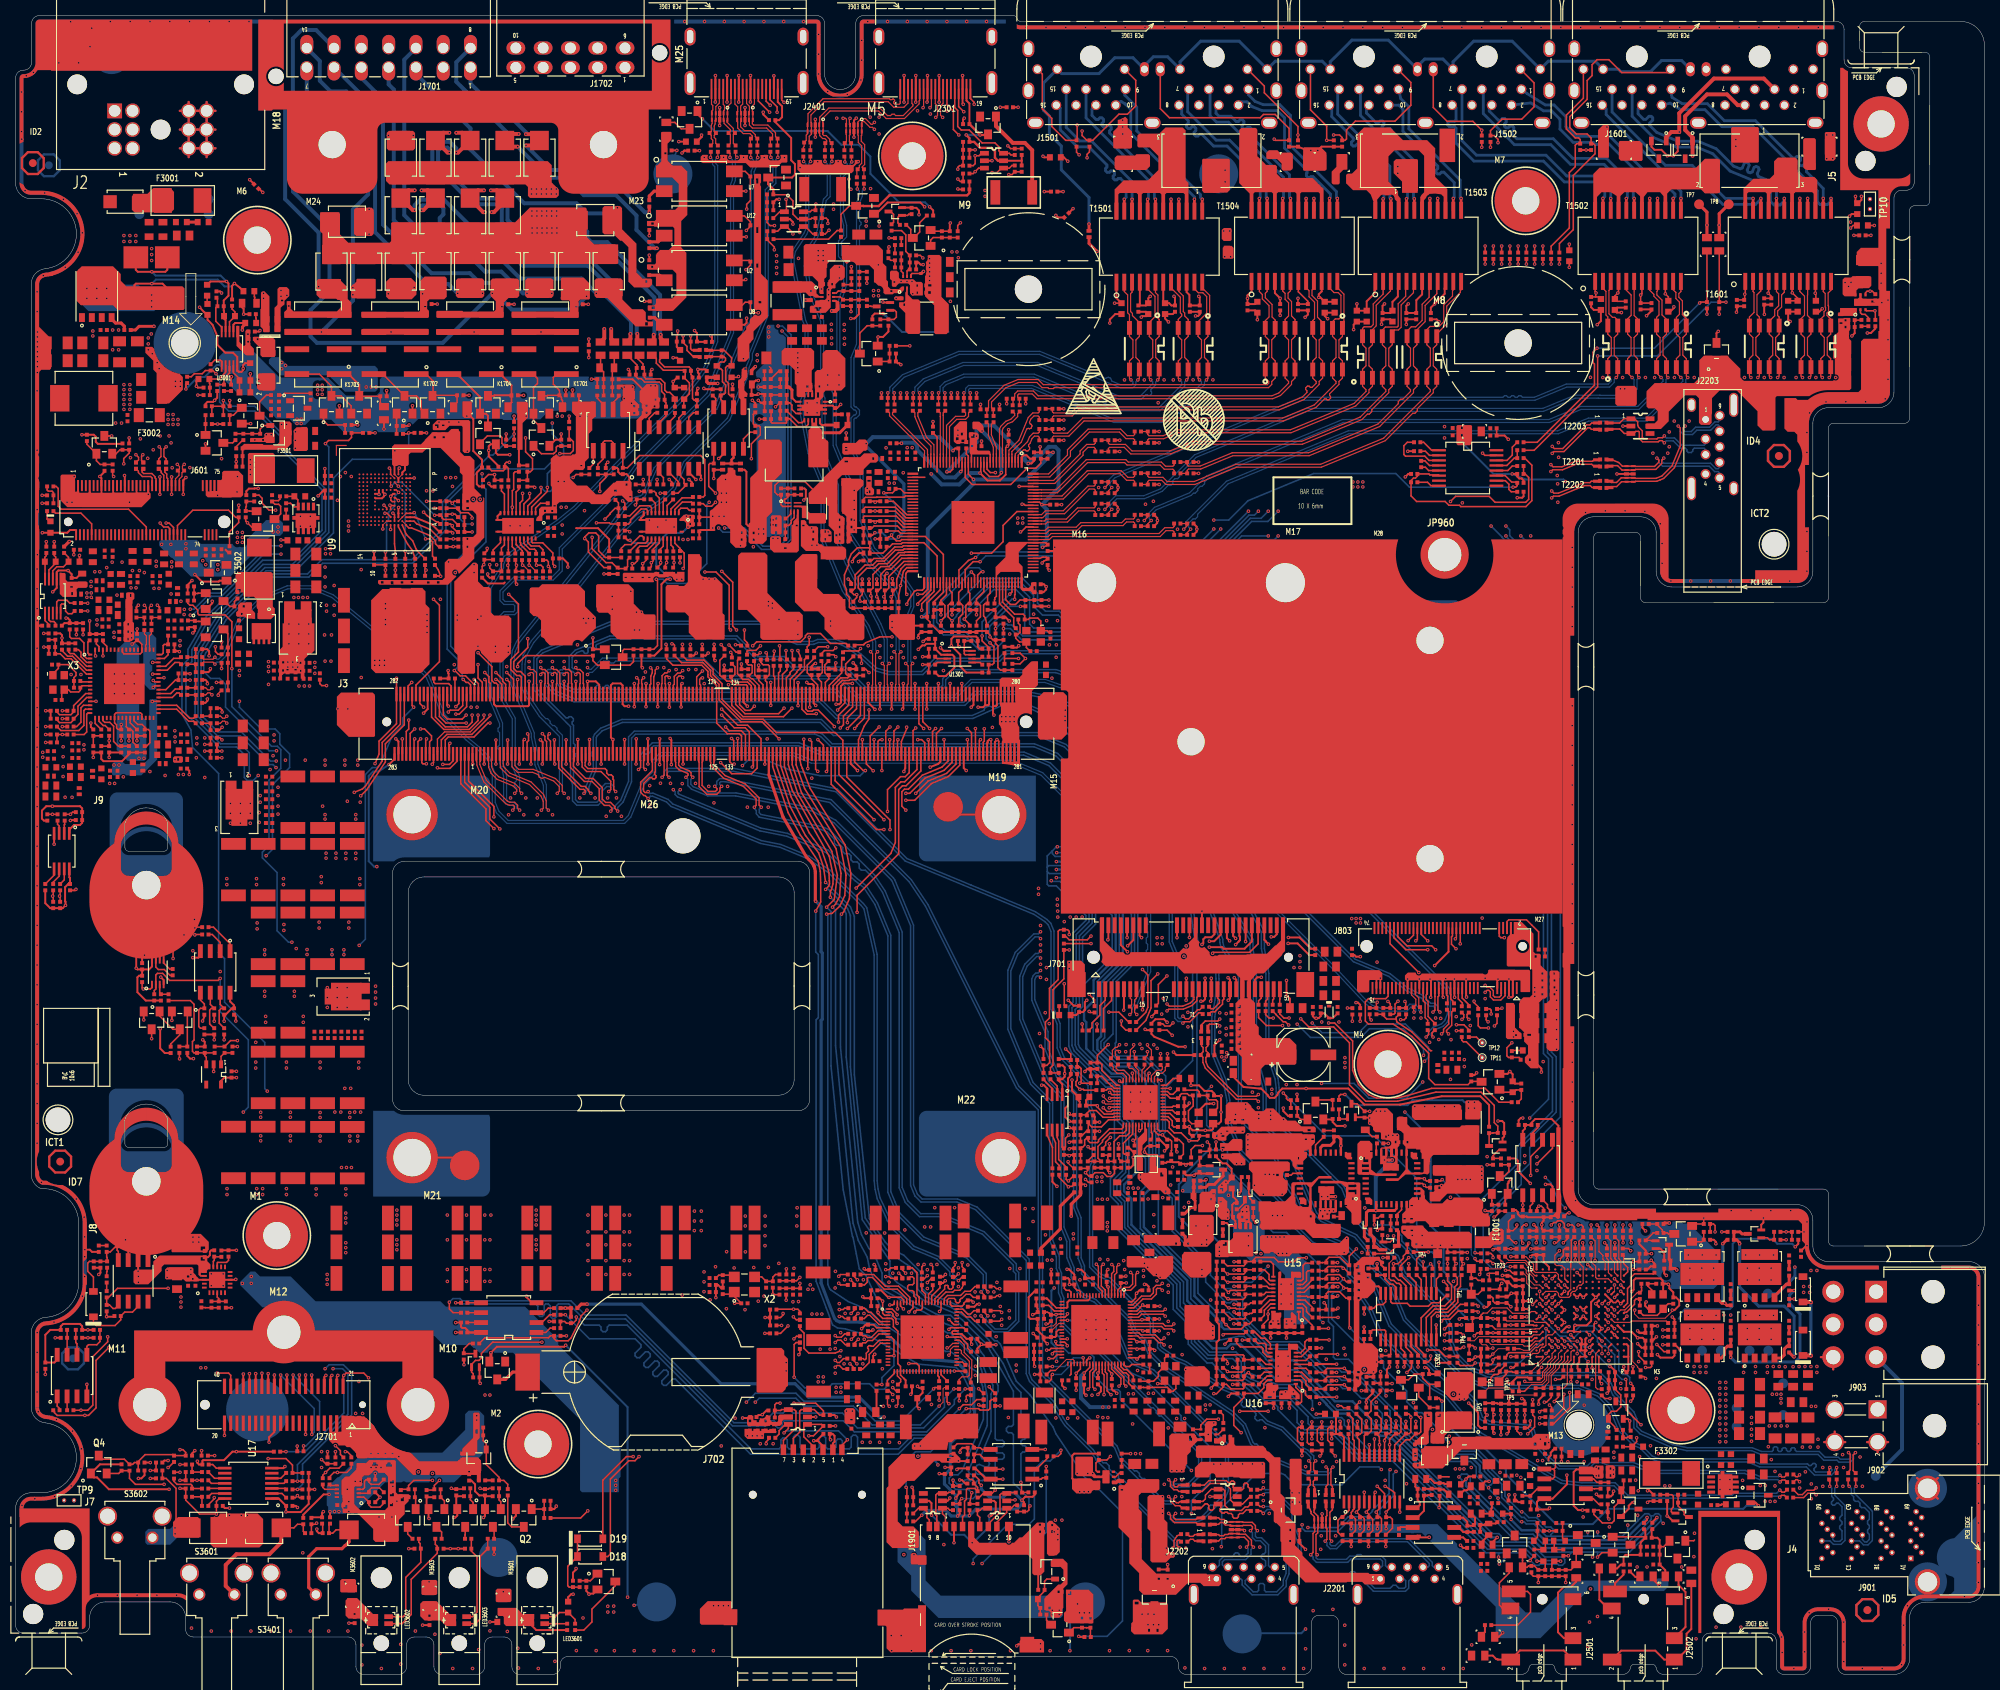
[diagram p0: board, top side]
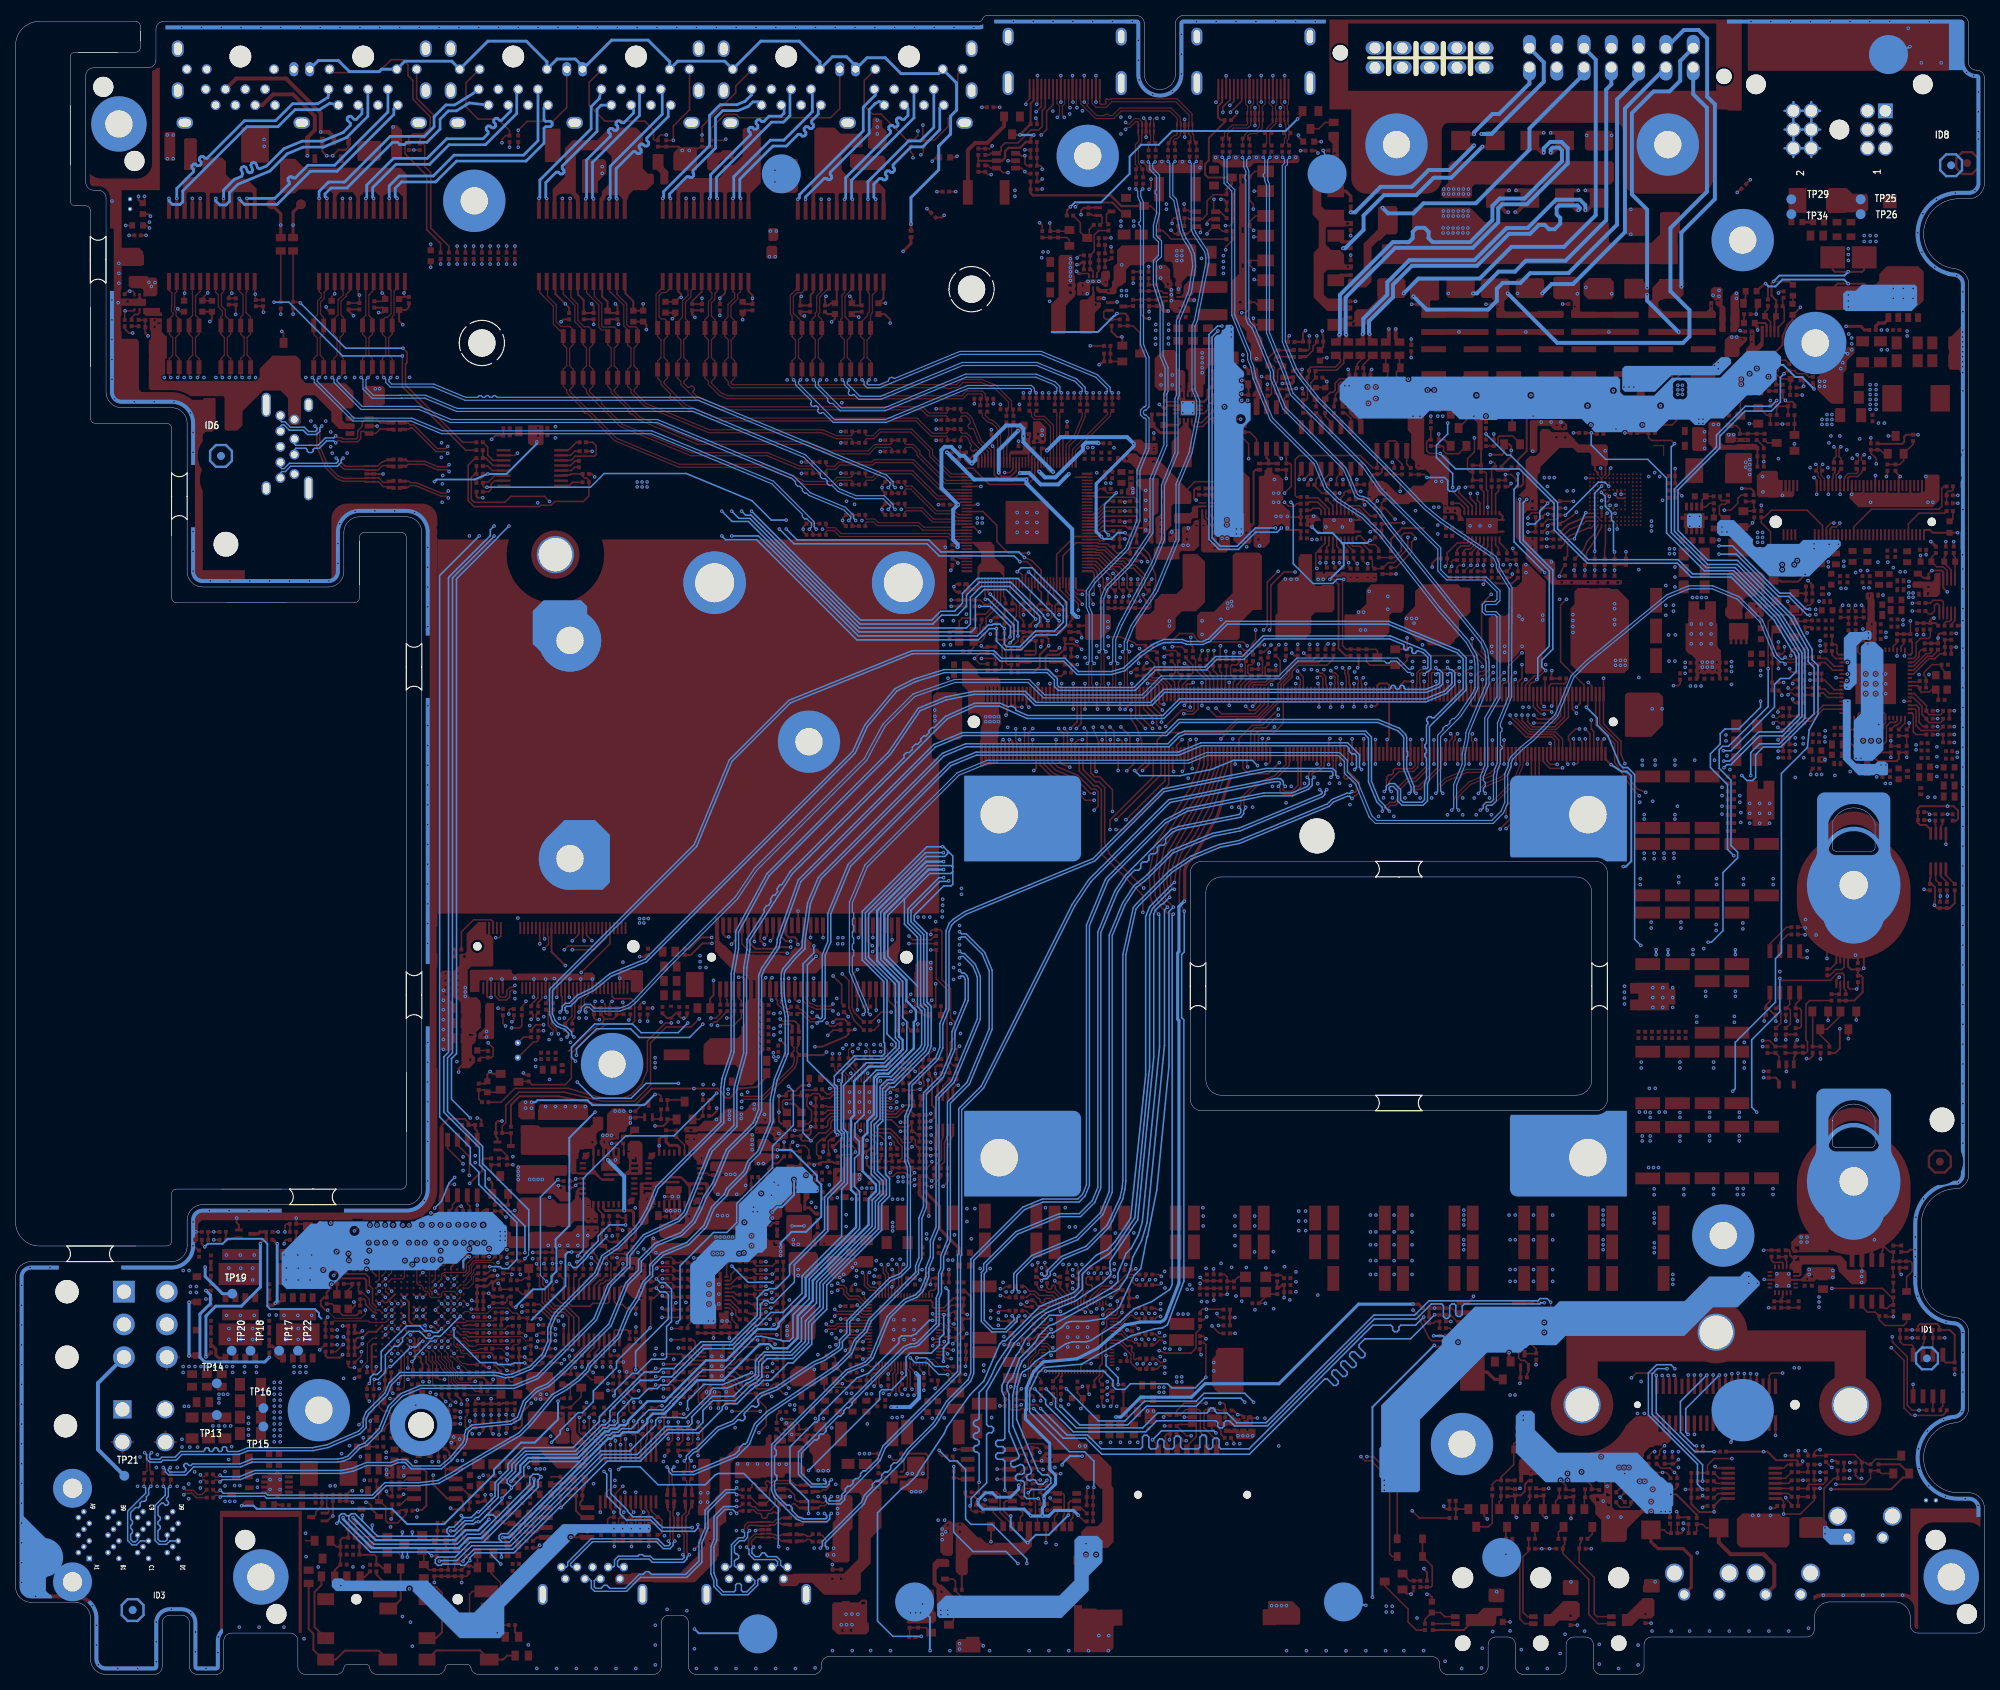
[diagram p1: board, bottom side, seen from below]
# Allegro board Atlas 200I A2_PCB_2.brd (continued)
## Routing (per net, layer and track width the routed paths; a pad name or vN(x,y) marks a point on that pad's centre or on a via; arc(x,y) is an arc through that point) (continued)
AC_MICBIAS0_L: length 2.5
  TOP w0.203: R2501.1 195.17,17.6 R2503.2 C2506.2
AC_MICBIAS0_R: length 2.4
  TOP w0.203: R2506.1 198.4,17.47 R2504.2 C2507.2
AC_OUT_L: length 250
  TOP w0.203: J3.309 55.1,119.87 55.49,120.26 58.79,120.26 60.58,122.05 v1(60.83,122.05)
  TOP w0.254: C2524.1 189.42,16.98 v1(190.02,17.58)
  ART03 w0.305: v1(133.48,103.25) 132.59,103.25 131.34,104.5 131.34,107.26 132.56,108.48 132.56,121.88 132.56,121.88 132.56,123.6 123.3,132.86 121.68,136.76 115.04,143.41 105.67,143.41 103.63,141.36 97.05,141.36 91.96,136.27 83.3,136.27 82.21,135.18 79.24,135.18 78.26,134.2 78.26,130.9 76.07,128.72 76.07,123.95 74.57,122.45 62.78,122.45 62.38,122.05 v1(60.83,122.05)
  BOTTOM w0.305: v1(190.02,17.58) 189.2,17.58 176.53,30.25 176.1,30.25 175.75,30.61 175.05,30.61 174.59,31.06 172.73,31.06 171.48,32.32 171.48,32.73 170.76,33.45 169.28,33.45 168.13,34.6 168.13,34.67 165.06,37.74 161.7,37.74 157.08,42.37 155.85,42.37 155.31,41.83 153.53,41.83 152.2,43.17 152.2,46 150.27,47.93 150.27,50.52 143.1,57.68 143.1,61.03 142.16,61.97 142.16,62.84 143.87,64.54 143.87,66.59 143.84,66.62 143.84,68.88 143.26,69.47 143.26,71.02 142.42,71.86 142.42,76.53 141.88,77.06 140.55,77.06 137.31,80.3 137.31,83.67 137.03,83.95 137.03,85.19 138.25,86.41 138.25,89.07 141.09,91.91 141.09,97.57 135.41,103.25 v1(133.48,103.25)
AC_OUT_R: length 247
  TOP w0.203: v1(60.83,123.06) 60.83,122.91 58.51,120.59 55.31,120.59 54.6,119.88 J3.307
  TOP w0.254: C2517.1 188.02,24.32 188.47,24.76 v1(188.98,24.76)
  ART03 w0.254: 128.55,133.63 129.4,132.36 130.38,129.99 132,128.38 132.34,127.55 133.05,126.85 133.12,126.85 133.47,126.49
  ART03 w0.305: 128.55,133.63 128.55,134.79 126.16,137.18 122.55,137.18 115.42,144.32 105.29,144.32 103.25,142.28 96.67,142.28 95.79,141.4 94.71,140.32 91.58,137.18 79.79,137.18 77.34,134.74 77.34,131.06 75.31,129.03 75.31,124.46 74.06,123.21 61.23,123.21 61.09,123.06 v1(60.83,123.06) ; 133.47,126.49 133.47,122.26 133.47,108.1 132.26,106.88 132.26,104.98 132.97,104.27 v1(133.48,104.27)
  BOTTOM w0.305: v1(188.98,24.76) 187.78,25.96 187.78,26.78 186.79,27.77 180.33,27.77 176.94,31.17 176.48,31.17 176.12,31.52 175.43,31.52 174.97,31.98 174.28,31.98 173.96,32.29 173.96,32.53 171.46,35.03 169.2,35.03 163.95,40.28 161.35,40.28 157.34,44.29 154.99,44.29 154.65,44.64 154.65,45.07 151.18,48.54 151.18,50.9 144.7,57.37 144.7,61.52 145.36,62.18 145.36,71.32 144.96,71.73 144.96,76.12 143.1,77.98 140.92,77.98 138.74,80.17 138.74,81.38 139.22,81.86 139.22,88.75 142,91.53 142,97.99 135.72,104.27 v1(133.48,104.27)
ALARM_OUT0_REF0: length 46.4
  ART03 w0.508: v1(67.38,172.21) 68.77,173.6 v1(68.77,177.16)
  BOTTOM w0.508: v1(65.58,177.16) 65.09,177.16 62.3,179.96 60.2,179.96 58.8,181.36 53.71,181.36 48.5,186.57 48.5,203.31 47.84,203.97 J1701.4
ALARM_OUT0_REF1: length 53.6
  BOTTOM w0.508: v1(73.23,176.78) 71.53,175.08 63.64,175.08 62.54,176.19 62.54,177.74 61.77,178.51 59.51,178.51 58.27,179.76 53.34,179.76 47.12,185.98 47.12,202.03 44.34,204.8 J1701.5
ALARM_OUT1_REF0: length 40
  ART04 w0.508: v1(48.15,172.21) 47.74,172.62 47.74,176.36 47.8,176.43 v1(47.8,177.11) ; J1701.12 42.65,206.95 42.65,200.68 47.8,195.53 47.8,182.45 51.12,179.13 v1(51.12,177.93)
ALARM_OUT1_REF1: length 34.7
  ART04 w0.508: v1(52.2,177.11) 52.02,177.29 52.02,180.03 48.91,183.15 48.91,197.85 46.25,200.51 46.25,207.06 J1701.11
ALARM_OUT2_REF0: length 42.5
  ART03 w0.508: v1(58.81,172.21) 59.88,173.28 v1(59.88,177.16)
  BOTTOM w0.508: v1(56.69,177.16) 55.5,178.36 52.76,178.36 46.1,185.02 46.1,200.89 J1701.6
ALARM_OUT2_REF1: length 64.5
  BOTTOM w0.508: J1701.7 37.34,202.73 35.58,200.97 35.58,190.22 40.26,185.54 40.26,177.45 37.83,175.02 37.83,171.63 38.65,170.81 54.79,170.81 v1(61.14,177.16)
ALARM_OUT3_REF0: length 42.4
  BOTTOM w0.508: v1(43.26,177.9) 43.26,187.91 45.21,189.86 45.21,200.28 42.42,203.07 40.39,203.07 39.01,204.44 39.01,206.98 J1701.14 ; v1(43.26,176.99) 43.26,176.24 v1(39.22,172.21)
ALARM_OUT3_REF1: length 40.7
  BOTTOM w0.508: v1(38.86,178.03) 38.86,184.96 34.57,189.26 34.57,201.42 35.56,202.41 35.56,209.85 36.65,210.95 38.54,210.95 J1701.13
ALM_OUT0: length 199.5
  TOP w0.203: R1702.2 R1701.1 71.27,158.39 71.53,158.14 71.53,157 71.15,156.62 v1(69.8,156.62) ; J3.251 121.1,116.65 119.63,115.19 117.46,114.29 115.32,112.14 v1(114.17,112.14)
  ART04 w0.178: v1(33.46,118.49) 34.42,118.49 36.46,120.54 60.19,120.54 63.07,117.65 70.28,117.65 71.5,118.87 71.5,122.62 74.26,125.38 74.26,130.26 78.83,134.84 82.74,134.84 83.14,135.24 92.03,135.24 93.64,134.87 93.93,134.7 95.74,133.41 96.54,132.61 96.83,131.87 96.83,131.07 96.85,131.05 96.95,130.81 96.99,130.77 98.66,126.41 99.02,123.83 99.26,123.24 100.63,121.87 102.88,120.94 103.48,120.54 106.54,115.96 109.17,113.33 112.98,113.33 v1(114.17,112.14)
  BOTTOM w0.203: v1(33.46,118.49) 32.51,118.49 26.92,124.08 26.92,127 26.16,127.76 25.02,127.76 24.14,128.64 24.14,130.42 24.38,131.06 24.7,131.37 27,135.29 32.47,140.77 37.6,140.77 39.38,142.54 50.91,142.54 55.19,146.82 55.19,150.22 59.61,154.64 67.82,154.64 v1(69.8,156.62)
ALM_OUT1: length 185.6
  TOP w0.203: R1708.1 50.29,159.14 v1(50.42,159.27) R1709.2 ; J3.249 120.6,116.79 119.4,115.59 117.01,114.6 v1(115.44,113.03)
  ART04 w0.127: v1(115.44,113.03) 115.44,112.31 114.46,111.33 113.46,111.33
  ART04 w0.178: v1(33.4,116.33) 34.32,116.33 35.08,117.09 35.08,117.69 37.15,119.76 47.12,119.76 47.9,118.97 60.47,118.97 62.48,116.96 62.48,116.78 62.92,116.35 70.78,116.35 73.03,118.59 73.03,122.76 74.87,124.6 74.87,129.8 78.47,133.4 82.26,133.4 82.64,133.78 89.27,133.78 89.73,133.32 92.29,133.32 93.45,132.17 93.45,130.56 95.91,128.09 97.41,124.48 97.41,123.02 101.71,118.73 104.01,117.22 109.09,112.14 112.65,112.14 113.46,111.33
  BOTTOM w0.203: v1(33.4,116.33) 33.02,116.71 32.51,116.71 28.83,120.4 25.89,120.4 23.39,122.89 23.39,130.96 23.44,131.11 26.36,135.8 32.14,141.58 35.92,141.58 40.77,146.43 40.77,153.46 43.18,155.88 48.58,155.88 50.42,157.72 v1(50.42,159.27)
ALM_OUT2: length 195
  TOP w0.203: R1714.1 v1(63.93,159.13) R1715.2 ; J3.247 120.1,117 119.09,115.99 116.61,114.96 114.68,113.03 v1(114.17,113.03)
  ART04 w0.127: v1(114.17,113.03) 114.62,112.58 114.62,111.96 114.36,111.7 113.73,111.7 112.9,112.52 109.3,112.52
  ART04 w0.178: v1(33.43,117.17) 33.68,117.17 36.65,120.14 47.37,120.14 47.97,119.54 54.01,119.54 54.35,119.89 60.33,119.89 62.87,117.35 70.41,117.35 72.64,119.58 72.64,123.01 74.56,124.93 74.56,130.03 78.99,134.45 93.59,134.45 93.73,134.38 93.78,134.34 93.98,134.14 93.98,131.41 97.56,127.83 97.74,127.39 98.04,126.66 98.04,123.83 100.8,121.08 101.23,120.9 102.5,120.65 103.11,120.32 103.27,120.17 106.52,115.3 109.3,112.52
  BOTTOM w0.203: v1(63.93,159.13) 61.22,156.42 60.81,156.42 54.74,150.35 54.74,146.95 50.79,143 39.26,143 37.44,141.17 32.3,141.17 26.68,135.55 23.83,130.96 23.79,130.85 23.79,123.07 25.96,120.9 28.96,120.9 32.69,117.17 v1(33.43,117.17)
ALM_OUT3: length 185.9
  TOP w0.203: v1(114.17,110.87) 113.67,111.38 113.67,113.23 114,113.56 114.5,113.56 116.29,115.35 118.81,116.4 119.6,117.19 J3.245 ; v1(39.74,157.89) 40.14,158.29 42.7,158.29 43.08,158.67 R1711.1 R1712.2
  ART04 w0.178: v1(29.97,115.32) 30.44,115.79 31.7,115.79 31.88,115.61 34.14,115.61 35.46,116.93 35.46,117.53 37.31,119.38 46.86,119.38 47.68,118.57 60.45,118.57 62.1,116.91 62.1,116.73 62.79,116.04 71.98,116.04 72.64,116.71 72.64,117.73 74.17,119.25 74.17,123.11 75.17,124.12 75.17,129.56 78.63,133.02 82.42,133.02 82.8,133.4 89.11,133.4 89.78,132.74 92.33,132.74 92.8,132.27 92.8,130.62 95.3,128.12 95.3,124.49 101.57,118.22 102.24,117.86 103.89,116.71 108.97,111.63 112.4,111.63 113.16,110.87 v1(114.17,110.87)
  BOTTOM w0.203: v1(29.97,115.32) 29.97,118.24 28.83,119.38 26.29,119.38 23.01,122.66 23.01,131.11 23.09,131.42 26.04,136.06 31.97,141.99 35.67,141.99 40.16,146.48 40.16,157.47 v1(39.74,157.89)
BOARD_ID0: length 34.2
  TOP w0.203: U2703.4 172.32,21.21 171.96,20.85 v1(171.96,20.81) 172,20.81 172.42,20.4 R2718.1 172.44,20.19 172.76,20.19 172.96,19.99 172.96,18.47 R2734.2 ; R2853.1 v1(195.45,32.16)
  ART04 w0.178: v1(171.96,20.81) 173.19,22.05 178.83,22.05 188.35,31.57 194.84,31.57 195.43,32.16 v1(195.45,32.16)
BOARD_ID1: length 45.8
  TOP w0.203: R2733.2 164.85,29.54 164.4,29.99 164.4,31.55 164.54,31.7 R2717.1 v1(164.97,32.38) ; R2854.1 195.55,33.01 v1(195.45,32.92) ; U2703.5 v1(172.97,23.37)
  ART04 w0.178: v1(164.97,32.38) 165.32,32.04 165.32,32 167.04,30.27 167.04,30.03 168.12,28.96 169.06,28.96 171.17,26.85 171.17,25.16 v1(172.97,23.37) 173.91,22.43 178.67,22.43 188.19,31.95 194.46,31.95 195.43,32.92 v1(195.45,32.92)
BOARD_ID2: length 53.1
  TOP w0.203: v1(207.14,35.05) 207.44,35.36 R2855.1 ; U2703.6 173.62,21.24 173.23,20.85 v1(173.23,20.81) 173.27,20.81 173.53,20.55 R2716.1 173.79,20.17 174.05,19.9 174.05,18.45 R2732.2
  ART04 w0.178: v1(173.23,20.81) 174.08,21.67 179.99,21.67 181.16,20.5 192.3,20.5 192.7,20.1 194.75,20.1 195.24,19.62 201.28,19.62 202.77,21.11 202.77,22.17 205.51,24.92 205.51,33.43 v1(207.14,35.05)
BOARD_ID3: length 45.3
  TOP w0.203: R2731.2 165.86,29.54 165.66,29.74 165.66,31.42 165.94,31.7 R2715.1 v1(166.24,32.38) ; U2703.7 174.27,23.26 v1(174.37,23.37) ; R2856.1 v1(191.77,40.77)
  ART04 w0.178: v1(166.24,32.38) 166.67,32.38 168.35,30.7 168.98,30.7 169.25,30.42 169.25,29.95 172.28,26.93 172.28,25.46 v1(174.37,23.37) 174.47,23.27 175.9,23.27 185.79,33.15 187.33,33.15 188.21,34.04 188.21,35.69 191.14,38.61 191.14,40.13 v1(191.77,40.77)
BOARD_ID4: length 59
  TOP w0.203: R2730.2 175.17,18.46 175.17,19.98 174.96,20.19 174.67,20.19 R2714.1 174.65,20.66 v1(174.5,20.81) 174.5,20.85 174.92,21.27 U2703.8 ; v1(209.04,39.37) 209.68,39.37 209.83,39.52 R2857.1
  ART04 w0.178: v1(174.5,20.81) 174.97,21.28 179.84,21.28 182.01,19.11 201.31,19.11 206.27,24.08 206.27,27.4 208.79,29.91 208.79,30.73 207.9,31.62 207.9,32.56 209.09,33.76 209.09,37.29 208.6,37.79 208.6,38.16 208.74,38.3 208.74,39.06 v1(209.04,39.37)
BOARD_ID5: length 83.1
  TOP w0.203: U2703.9 175.57,23.19 v1(174.63,24.13) ; v1(200.98,55.37) 201.04,55.31 R2858.1 ; R2729.2 167.39,29.54 166.94,29.99 166.94,31.43 167.21,31.7 R2713.1 v1(167.51,32.38)
  ART03 w0.178: v1(184.02,61.21) 189.71,61.21 193.17,57.76 193.17,57.57 193.97,56.77 194.29,56.77 195.58,55.48 195.58,55 197.83,52.74 199.19,52.74 199.54,53.09 199.54,53.94 v1(200.98,55.37)
  ART04 w0.178: v1(184.02,61.21) 181.89,59.08 179.45,59.08 177.2,56.83 177.2,56.07 176.66,55.52 173.84,55.52 173.52,55.84 171.35,55.84 167.08,51.57 167.08,46.72 165.2,44.84 165.2,40.75 165.8,40.15 165.8,39.46 166.7,38.56 166.7,34.53 167.01,34.21 167.03,34.21 167.51,33.73 v1(167.51,32.38) 168.15,31.75 168.46,31.75 169.63,30.58 169.63,30.11 172.66,27.09 172.66,26.1 v1(174.63,24.13)
BOARD_ID6: length 56.5
  TOP w0.203: v1(208.46,32.04) 208.44,32.04 206.58,33.9 R2859.1 ; U2703.10 176.22,21.3 175.77,20.85 v1(175.77,20.81) R2712.1 176.31,20.17 176.57,19.91 176.57,18.75 R2728.2
  ART04 w0.178: v1(175.77,20.81) 175.77,20.52 179.17,17.12 188.82,17.12 189.75,18.05 194.04,18.05 194.29,17.79 203.09,17.79 203.71,18.41 203.71,20.24 206.65,23.19 206.65,27.08 209.17,29.59 209.17,31.33 v1(208.46,32.04)
BOARD_ID7: length 91.3
  TOP w0.203: v1(200.41,57.66) 200.84,57.66 201.04,57.45 R2860.1 ; v1(175.64,24.13) 175.68,24.13 176.71,23.44 176.87,23.28 U2703.11 ; v1(168.78,32.38) R2711.1 168.48,31.7 168.28,31.5 168.28,30.05 R2727.2
  ART04 w0.178: v1(200.41,57.66) 198.65,58.39 198.03,58.8 197.41,59.42 197.41,67.34 195.38,69.37 190.78,69.37 187.07,65.66 187.07,63.34 182.35,58.62 179.53,58.62 177.58,56.67 177.58,55.91 176.77,55.09 173.33,55.09 172.96,55.46 171.62,55.46 170.89,54.74 170.89,48.28 170.31,47.7 169.57,47.7 166.27,44.4 166.27,41.19 166.87,40.59 166.87,39.9 167.89,38.88 167.89,33.27 v1(168.78,32.38) 168.78,31.97 170.02,30.74 170.02,30.27 173.08,27.21 173.08,26.54 175.48,24.13 v1(175.64,24.13)
BOM_ID0: length 21.7
  TOP w0.203: R2864.1 183.77,44.83 v1(183.26,44.32) ; U2703.13 177.52,29.31 178.31,30.1 178.79,30.1 R2719.1 179.98,30.89 180.21,31.11 180.21,32.79 180.04,32.97 ; 180.04,32.97 R2735.2 ; 180.04,32.97 v1(180.21,32.97)
  ART04 w0.178: v1(180.21,32.97) 180.96,33.72 180.96,36.95 182.97,38.95 182.97,40.33 182.03,41.27 182.03,43.09 v1(183.26,44.32)
BOM_ID1: length 23.2
  TOP w0.203: v1(183.26,43.56) 183.52,43.81 R2865.1 ; U2703.14 176.87,29.45 R2720.1 178.74,30.89 178.94,31.09 v1(178.94,32.97) 178.94,33.15 178.66,33.43 R2736.2
  ART04 w0.178: v1(178.94,32.97) 178.94,32.43 179.38,31.99 179.9,31.99 181.48,33.57 181.48,36.79 183.36,38.67 183.36,40.48 182.41,41.43 182.41,42.71 v1(183.26,43.56)
BOM_ID2: length 24.5
  TOP w0.203: R2737.2 177.67,32.79 177.67,31.11 177.44,30.89 R2721.1 176.94,30.89 176.22,30.17 v1(176.22,29.46) U2703.15 ; R2866.1 v1(183.26,41.78)
  ART04 w0.178: v1(183.26,41.78) 184.12,40.92 184.12,38.07 182.35,36.3 182.35,33.36 178.45,29.46 v1(176.22,29.46)
BOOT_SEL0: length 127.2
  TOP w0.203: R146.1 155.63,42.9 v1(155.09,42.37) ; J3.137 v1(92.6,120.07)
  ART03 w0.178: v1(92.6,120.07) 92.99,120.46 96.58,120.46 97.02,120.02 97.02,119.49 98.68,117.82 98.68,109.21 105.4,102.49 105.4,80.78 124.59,61.59 131.29,61.59 132.72,60.17 135.8,60.17 136.46,59.51 142.06,59.51 143.64,57.92 150.33,57.92 151.19,57.06 153.93,57.06 156.15,54.85 156.15,53.95 156.73,53.36 156.73,50.65 156.46,50.38 156.07,50.38 155.67,50.77 155.28,50.77 154.89,50.38 154.89,48.75 154.31,48.16 154.31,43.13 155.07,42.37 v1(155.09,42.37)
BOOT_SEL0_R: length 23.6
  TOP w0.203: R259.1 v1(183.64,52.7) R85.2 ; v1(169.55,41.05) 169.49,41.1 167.11,41.1 R205.2
  ART04 w0.178: v1(183.64,52.7) 183.64,52.68 171.36,40.4 170.19,40.4 v1(169.55,41.05)
BOOT_SEL1: length 128.1
  TOP w0.203: R148.1 v1(157.33,42.89) ; v1(91.82,120.07) 92.1,119.79 J3.135
  ART03 w0.178: v1(157.33,42.89) 156.47,42.89 154.7,44.66 154.7,46.75 155.62,47.68 155.73,47.68 156.13,48.08 156.25,48.08 157.11,48.94 157.11,53.52 156.53,54.1 156.53,55.01 153.2,58.33 143.78,58.33 142.22,59.89 136.62,59.89 135.96,60.55 133.11,60.55 131.69,61.98 124.94,61.98 106.71,80.21 106.71,101.72 99.06,109.37 99.06,117.98 97.42,119.63 97.42,120.05 96.7,120.76 92.52,120.76 v1(91.82,120.07)
BOOT_SEL1_R: length 26.3
  TOP w0.203: R84.2 184.55,52.9 v1(184.75,52.7) 184.55,52.5 R260.1 ; R158.2 v1(167.5,41.87)
  ART03 w0.178: v1(167.5,41.87) 168.14,41.87 169.16,42.9 172.02,42.9 173.39,41.53 v1(175.72,41.53)
  ART04 w0.178: v1(175.72,41.53) 182.97,48.78 182.97,49.52 183.93,50.49 183.93,51.71 184.75,52.53 v1(184.75,52.7)
BOOT_SEL2: length 121.3
  TOP w0.203: J3.133 91.6,117.08 91.9,116.78 v1(92.15,116.78) ; v1(154.86,43.56) 154.99,43.69 157.55,43.69 R68.1
  ART03 w0.178: v1(92.15,116.78) 92.4,117.03 93.4,117.03 93.66,116.77 93.66,115.44 97.36,111.74 97.36,108.94 100.65,105.65 101.79,104.89 103.16,102.84 103.16,81.37 123.98,60.55 130.81,60.55 131.95,59.41 135.48,59.41 136.14,58.75 140.7,58.75 143.15,56.3 153.62,56.3 154.9,55.01 154.9,51.48 154.51,51.08 154.51,49.28 v1(153.26,48.03)
  ART04 w0.178: v1(153.26,48.03) 154.18,47.12 154.18,44.25 v1(154.86,43.56)
BOOT_SEL2_R: length 28.2
  TOP w0.203: R261.1 185.45,52.44 v1(185.69,52.67) 185.45,52.91 R177.2 ; v1(168.45,42.91) 168.42,42.93 R67.2
  ART04 w0.178: v1(168.45,42.91) 168.48,42.91 169.08,42.31 169.08,40.85 169.95,39.98 171.66,39.98 184.19,52.5 184.19,52.8 184.56,53.17 185.19,53.17 v1(185.69,52.67)
BPWR_DET_USB2: length 42.1
  TOP w0.203: v1(132.16,44.96) 132.42,44.96 R229.1 ; R2102.2 v1(98.24,44.77) ; U2101.2 112.28,46.47 112.52,46.23 112.52,46 112.9,45.62 112.9,45.19 v1(113.06,45.03)
  ART03 w0.178: v1(98.24,44.77) 98.33,44.55 98.68,44.2 99.26,44.2 99.73,44.67 108.17,44.67 108.71,45.21 112.88,45.21 v1(113.06,45.03)
  ART04 w0.178: v1(113.06,45.03) 115.56,45.03 117.77,47.24 119.71,47.24 123.26,43.69 124.64,43.69 125.47,42.85 130.36,42.85 132.16,44.65 v1(132.16,44.96)
BPWR_VL817_HUB1: length 8.1
  TOP w0.203: v1(132.97,38.48) 132.84,38.35 132.84,37.85 132.59,37.59 R2009.1 ; U2002.45 137.36,40.3 137.66,40.6 v1(137.76,40.6)
  BOTTOM w0.178: v1(132.97,38.48) 134.11,38.48 135.64,40 137.16,40 v1(137.76,40.6)
CAN0_RX: length 75.4
  TOP w0.152: v1(65.02,142.29) 65.1,142.29 65.86,141.53 R2999.2
  TOP w0.203: v1(65.02,142.29) 64.95,142.37 R2931.1
  TOP w0.254: J3.145 94.6,116.52 v1(94.49,116.41)
  ART03 w0.178: v1(94.49,116.41) 94.49,116.94 93.55,117.88 91.72,117.88 90.87,117.03 90.87,116.27 90.3,115.7 82.22,115.7 81.43,114.91 58.47,114.91 57.74,115.64 57.4,116.45 57.4,118.74 54.61,121.54 54.61,124.76 56.05,126.2 56.05,127.42 57.11,128.49 57.11,134.1 65.02,142.02 v1(65.02,142.29)
CAN0_RX_R: length 41.4
  TOP w0.203: v1(94.36,155.96) 94.36,157.86 95.5,159 95.5,160.02 95.35,160.17 R1640.2 94.62,160.43 94.62,161.65 R1647.2 ; v1(65.02,151.51) 65.02,150.62 64.69,150.29 U2904.6
  ART03 w0.178: v1(65.02,151.51) 65.02,152.15 66.93,154.05 71.63,154.05 72.52,154.94 93.35,154.94 v1(94.36,155.96)
CAN0_TX: length 43.5
  TOP w0.203: R2934.1 81.79,142.88 v1(81.53,142.62) 81.53,142.11 81.28,141.86 ; v1(91.69,133.98) 91.52,134.16 91.52,139.72 89.82,141.42 v1(88.41,141.42) ; J3.143 94.1,120.91 93.57,121.44 92.18,121.44 v1(90.55,123.06)
  ART03 w0.178: v1(91.69,133.98) 87.71,133.98 86.07,132.34 86.07,131.2 87.87,129.39 88.25,129.39 89.27,128.38 89.27,124.35 v1(90.55,123.06)
  ART04 w0.152: v1(81.53,142.62) 82.48,141.99 84.94,140.97 87.32,140.97 v1(88.41,141.42)
CAN0_TX_R: length 14.3
  TOP w0.203: v1(89.76,151.54) 88.9,152.4 88.9,155.19 89.05,155.35 R1648.2 U1604.1 ; R2938.2 v1(82.68,151.54)
  ART03 w0.178: v1(89.76,151.54) v1(82.68,151.54)
CAN_H: length 10.7
  TOP w0.188: T1602.1 88.96,169 R31.1
  TOP w0.203: U1604.7 90.81,163.19 90.42,163.58 C1640.1 90.58,164.21 90.83,164.21 91.03,164.41 91.03,165.44 90.65,165.82 90.65,167.28 90.42,167.51 90.27,167.51 R1649.1 89.92,167.89 90.38,168.36 90.84,168.36 91.04,168.56 91.04,168.85 90.84,169.05 R188.2 T1602.1
CAN_H_R: length 94.4
  TOP w0.188: R31.2 87.34,169 T1602.2
  TOP w0.203: v1(85.61,171.72) C1643.1 85.61,170.85 86.11,170.36 86.11,169.85 86.91,169.05 T1602.2
  ART03 w0.508: v1(85.61,171.72) 85.61,172.54 76.64,181.51 48.59,181.51 v1(45.34,184.76) ; J1702.7 72.95,206.94 72.95,205.03 68.71,200.79 49.28,200.79 45.34,196.85 v1(45.34,187.95)
CAN_L: length 11.3
  TOP w0.188: R87.1 88.96,169.91 T1602.4
  TOP w0.203: U1604.6 92.08,163.93 C1641.1 91.64,164.06 91.44,164.26 91.44,165.61 91.06,165.99 91.06,167.64 91.29,167.87 R1650.1 91.82,168.91 90.87,169.86 R188.1 T1602.4
CAN_L_R: length 86.2
  TOP w0.188: T1602.3 87.34,169.91 R87.2
  TOP w0.203: T1602.3 86.78,169.86 86.58,170.07 C1642.1 v1(86.58,171.72)
  ART03 w0.508: v1(51,197.42) 52.33,198.75 70.23,198.75 76.43,204.95 76.43,206.92 J1702.6 ; v1(86.58,171.72) 86.41,171.88 86.41,173.48 76.84,183.05 62.19,183.05 v1(47.82,197.42)
CARD_DETECT: length 4.2
  TOP w0.203: R1912.2 115.8,21.32 U1902.6 116.87,20.87 116.87,20.13 117.18,19.81 J1901.9
CFG_PHY0_LDO0: length 6.5
  TOP w0.203: U1201.36 146.46,69.95 146.69,69.72 147.73,69.72 R1213.1 149.2,68.6 149.77,68.04 149.77,66.73 R1210.2
CH1_MDI0_N: length 28.9
  TOP w0.356: T1502.14 v1(212.58,189.34)
  BOTTOM w0.356: v1(212.58,189.34) 212.82,189.58 212.82,189.92 212.05,190.68 210,190.68 204.14,196.54 203.53,196.54 203.25,196.27 202.62,196.27 202.34,196.54 199.76,196.54 198.07,198.24 198.07,199.51 196.99,200.58 195.96,200.58 194.74,201.34 194.74,201.34 194.33,201.59 J1502.2
CH1_MDI0_P: length 28.8
  TOP w0.356: T1502.13 v1(213.58,189.34)
  BOTTOM w0.356: v1(213.58,189.34) 213.58,190.23 212.37,191.44 210.32,191.44 204.46,197.31 200.07,197.31 198.83,198.55 198.83,199.82 197.31,201.34 196.18,201.34 195.14,201.98 193.87,202.78 J1502.1
CH1_MDI1_N: length 34.3
  TOP w0.356: T1502.17 v1(209.58,189.34)
  ART03 w0.356: J1502.6 187.29,200.79 187.29,200.24 188.24,199.29 190.57,199.29 192.47,197.38 192.47,196.96 192.02,196.51 192.02,196.09 192.32,195.79 192.74,195.79 193.19,196.24 193.61,196.24 193.91,195.95 193.91,195.52 193.52,195.14 193.52,194.72 193.82,194.42 194.24,194.42 194.63,194.81 195.05,194.81 196.94,192.91 208.08,192.91 209.73,191.26 209.73,189.49 v1(209.58,189.34)
CH1_MDI1_P: length 34.3
  TOP w0.356: T1502.16 v1(210.58,189.34)
  ART03 w0.356: v1(210.58,189.34) 210.49,189.43 210.49,191.58 208.39,193.67 197.26,193.67 190.88,200.05 188.56,200.05 188.05,200.55 188.05,201.67 188.84,202.45 188.84,202.45 188.88,202.49 189.72,202.49 J1502.3
CH1_MDI2_N: length 28.6
  TOP w0.356: T1502.20 v1(206.58,189.34)
  BOTTOM w0.356: J1502.5 188.23,203.16 188.23,200.24 192.23,196.24 196.89,196.24 199.41,193.72 203.72,193.72 206.71,190.73 206.71,189.47 v1(206.58,189.34)
CH1_MDI2_P: length 28.5
  TOP w0.356: T1502.19 v1(207.58,189.34)
  BOTTOM w0.356: v1(207.58,189.34) 207.47,189.45 207.47,191.05 204.04,194.48 199.73,194.48 197.21,197 192.55,197 191.91,197.64 191.91,197.92 192.14,198.15 192.14,198.43 191.94,198.64 191.66,198.64 191.42,198.4 191.14,198.4 190.94,198.61 190.94,198.89 191.17,199.12 191.17,199.41 190.97,199.61 190.69,199.61 190.45,199.38 190.17,199.38 188.99,200.55 188.99,200.99 J1502.4
CH1_MDI3_N: length 31.2
  TOP w0.356: T1502.23 v1(203.58,189.34)
  BOTTOM w0.356: v1(203.58,189.34) 203.81,189.58 203.81,190.65 203,191.46 198.62,191.46 195.95,194.13 187.03,194.13 184.74,196.43 184.74,198.35 184.54,198.55 183.89,198.55 183.69,198.75 183.69,199.04 183.89,199.24 184.54,199.24 184.74,199.44 184.74,200.96 184.39,201.31 J1502.8
CH1_MDI3_P: length 31.2
  TOP w0.356: T1502.22 v1(204.58,189.34)
  BOTTOM w0.356: J1502.7 185.5,196.74 187.35,194.89 196.27,194.89 198.94,192.22 203.32,192.22 204.58,190.97 v1(204.58,189.34)
CH1_TRX0N_N: length 19
  TOP w0.155: R197.1 148.58,147.26 148.42,147.1 147.38,147.1 146.63,146.35 132.81,146.35 132.42,145.97 131.56,145.97 131.55,145.98 U6.108
CH1_TRX0P_P: length 19
  TOP w0.155: R1315.1 148.58,146.57 148.42,146.72 147.54,146.72 146.79,145.97 132.97,145.97 132.58,145.59 131.56,145.59 131.55,145.58 U6.107
CH1_TRX1N_N: length 14.1
  TOP w0.155: U6.110 131.28,146.78 131.29,146.76 132.03,146.76 132.44,147.17 136.02,147.17 136.6,147.75 141.86,147.75 142.33,148.22 143.37,148.22 143.52,148.38 R1316.1
CH1_TRX1P_P: length 14.1
  TOP w0.155: R1314.1 143.52,147.68 143.37,147.84 142.49,147.84 142.02,147.37 136.76,147.37 136.18,146.79 132.59,146.79 132.19,146.38 131.27,146.38 131.26,146.38 U6.109
CH1_TRX2N_N: length 9.1
  TOP w0.155: R1313.1 138.47,149.8 138.31,149.65 136.18,149.65 134.75,148.21 132.18,148.21 131.94,147.97 131.56,147.97 131.55,147.98 U6.113
CH1_TRX2P_P: length 9.1
  TOP w0.155: U6.112 131.55,147.58 131.56,147.59 132.1,147.59 132.34,147.83 134.91,147.83 136.34,149.26 138.31,149.26 138.47,149.11 R1312.1
CH1_TRX3N_N: length 9.9
  TOP w0.155: R1311.1 138.47,152.6 138.31,152.45 137.54,152.45 134.37,149.28 132.07,149.28 131.58,148.78 U6.115
CH1_TRX3P_P: length 9.9
  TOP w0.155: R1309.1 138.47,151.91 138.31,152.07 137.7,152.07 134.52,148.89 132.23,148.89 131.72,148.39 131.56,148.39 131.55,148.38 U6.114
CH2_MDI0_N: length 18.8
  TOP w0.356: T1503.14 v1(184.38,189.34)
  BOTTOM w0.356: v1(184.38,189.34) 184.5,189.46 184.5,191.38 183.17,192.72 182.88,192.72 182.65,192.48 182.37,192.48 182.17,192.69 182.17,192.97 182.4,193.2 182.4,193.48 177.93,197.96 177.93,200.79 177.41,201.31 J1502.10
CH2_MDI0_P: length 18.8
  TOP w0.356: T1503.13 v1(185.38,189.34)
  BOTTOM w0.356: J1502.9 177.65,202.14 178.69,201.1 178.69,198.27 185.26,191.7 185.26,189.46 v1(185.38,189.34)
CH2_MDI1_N: length 22
  TOP w0.356: T1503.17 v1(181.38,189.34)
  ART03 w0.356: J1502.14 171.54,200.79 171.54,200.24 173.24,198.53 173.24,197.82 172.88,197.46 172.88,196.74 173.6,196.02 174.32,196.02 174.68,196.38 175.4,196.38 176.02,195.76 177.27,195.76 179,194.02 179,193.3 178.77,193.07 178.77,192.35 179.49,191.63 180.21,191.63 180.44,191.87 181.16,191.87 181.48,191.54 181.48,189.44 v1(181.38,189.34)
CH2_MDI1_P: length 22
  TOP w0.356: T1503.16 v1(182.38,189.34)
  ART03 w0.356: J1502.11 173.97,202.49 173.13,202.49 173.09,202.45 173.09,202.45 172.3,201.67 172.3,200.55 176.34,196.52 177.58,196.52 182.25,191.86 182.25,189.48 v1(182.38,189.34)
CH2_MDI2_N: length 18.2
  TOP w0.356: v1(178.38,189.29) T1503.20
  BOTTOM w0.356: J1502.13 172.48,203.16 172.48,199.99 178.51,193.96 178.51,189.42 v1(178.38,189.29)
CH2_MDI2_P: length 18.1
  TOP w0.356: v1(179.38,189.29) T1503.19
  BOTTOM w0.356: v1(179.38,189.29) 179.27,189.4 179.27,194.27 176.23,197.31 176.23,197.6 176.46,197.83 176.46,198.11 176.26,198.31 175.98,198.31 175.75,198.08 175.46,198.08 175.26,198.29 175.26,198.57 175.49,198.8 175.49,199.08 175.29,199.28 175.01,199.28 174.78,199.05 174.49,199.05 173.24,200.3 173.24,200.99 J1502.12
CH2_MDI3_N: length 18.5
  TOP w0.356: T1503.23 v1(175.38,189.29)
  BOTTOM w0.356: v1(175.38,189.29) 175.48,189.39 175.48,193.15 173.3,195.34 173.01,195.34 172.77,195.1 172.49,195.1 172.29,195.3 172.29,195.59 172.53,195.82 172.53,196.11 172.33,196.31 172.04,196.31 171.8,196.07 171.52,196.07 171.32,196.27 171.32,196.56 171.56,196.79 171.56,197.08 168.8,199.84 168.8,200.99 J1502.16
CH2_MDI3_P: length 18.4
  TOP w0.356: T1503.22 v1(176.38,189.29)
  BOTTOM w0.356: v1(176.38,189.29) 176.25,189.43 176.25,193.47 169.56,200.15 169.56,203.16 J1502.15
CH2_TRX0N_N: length 15.2
  TOP w0.155: R1308.1 143.52,153.72 143.37,153.56 142.65,153.56 141.81,154.41 137.44,154.41 134.2,151.17 131.56,151.17 131.55,151.18 U6.121
CH2_TRX0P_P: length 15.2
  TOP w0.155: R1307.1 143.52,153.03 143.37,153.18 142.49,153.18 141.65,154.03 137.6,154.03 134.36,150.79 131.56,150.79 131.55,150.78 U6.120
CH2_TRX1N_N: length 20.5
  TOP w0.155: U6.123 131.55,151.98 131.56,151.97 133.45,151.97 137.32,155.83 142.39,155.83 142.7,155.52 146.94,155.52 147.47,154.99 148.42,154.99 148.58,155.14 R1306.1
CH2_TRX1P_P: length 20.5
  TOP w0.155: R1305.1 148.58,154.45 148.42,154.61 147.32,154.61 146.78,155.14 142.54,155.14 142.24,155.45 137.47,155.45 133.61,151.59 131.56,151.59 131.55,151.58 U6.122
CH2_TRX2N_N: length 10.6
  TOP w0.155: R1304.1 138.47,157.95 138.31,157.79 137.37,157.79 136.53,156.95 136.53,156.57 133.12,153.16 130.52,153.16 U6.126
CH2_TRX2P_P: length 10.6
  TOP w0.155: R1303.1 138.47,157.26 138.31,157.41 137.53,157.41 136.91,156.79 136.91,156.41 133.28,152.78 130.5,152.78 U6.125
CH2_TRX3N_N: length 16.6
  TOP w0.155: R1302.1 143.52,159.06 143.37,158.91 142.56,158.91 141.72,159.75 137.55,159.75 134.9,157.1 134.9,156.42 132.48,154 130.53,154 U6.128
CH2_TRX3P_P: length 16.6
  TOP w0.155: R1301.1 143.52,158.37 143.37,158.53 142.41,158.53 141.56,159.37 137.71,159.37 135.28,156.94 135.28,156.26 132.64,153.62 130.54,153.62 U6.127
CH3_MDI0_N: length 21.7
  TOP w0.356: T1504.14 v1(168.51,189.34)
  BOTTOM w0.356: J1501.2 157.26,201.73 157.94,201.73 158.47,201.2 158.63,201.1 159.86,200.61 161.81,200.61 162.74,199.68 162.74,195.8 165.63,192.91 165.63,192.62 165.54,192.53 165.54,192.25 165.74,192.04 166.02,192.04 166.12,192.14 166.4,192.14 168.63,189.9 168.63,189.47 v1(168.51,189.34)
CH3_MDI0_P: length 21.8
  TOP w0.356: T1504.13 v1(169.51,189.34)
  BOTTOM w0.356: J1501.1 158.11,202.64 158.95,201.8 158.98,201.78 160.01,201.37 162.13,201.37 163.5,200 163.5,196.11 169.39,190.22 169.39,189.46 v1(169.51,189.34)
CH3_MDI1_N: length 24.7
  TOP w0.356: T1504.17 v1(165.51,189.34)
  ART03 w0.356: J1501.6 152.28,200.79 152.28,200.24 153.22,199.29 153.22,198.58 152.92,198.27 152.92,197.55 153.64,196.83 154.35,196.83 154.66,197.14 155.38,197.14 156.1,196.42 156.1,195.7 155.79,195.4 155.79,194.68 156.51,193.96 157.23,193.96 157.53,194.27 158.25,194.27 159.65,192.86 163.17,192.86 165.61,190.42 165.61,189.44 v1(165.51,189.34)
CH3_MDI1_P: length 24.7
  TOP w0.356: T1504.16 v1(166.51,189.34)
  ART03 w0.356: J1501.3 154.71,202.49 153.86,202.49 153.83,202.45 153.83,202.45 153.04,201.67 153.04,200.55 159.97,193.62 163.49,193.62 166.37,190.74 166.37,189.48 v1(166.51,189.34)
CH3_MDI2_N: length 20.4
  TOP w0.356: T1504.20 v1(162.51,189.34)
  BOTTOM w0.356: v1(162.51,189.34) 162.61,189.45 162.61,192.06 155.54,199.13 154.01,199.13 153.19,199.96 153.19,203.19 J1501.5
CH3_MDI2_P: length 20.4
  TOP w0.356: T1504.19 v1(163.51,189.34)
  BOTTOM w0.356: J1501.4 153.95,200.96 153.95,200.27 154.33,199.89 155.86,199.89 156.54,199.21 156.82,199.21 157.05,199.44 157.33,199.44 157.53,199.24 157.53,198.95 157.31,198.73 157.31,198.44 157.51,198.24 157.79,198.24 158.02,198.47 158.3,198.47 158.5,198.27 158.5,197.98 158.28,197.76 158.28,197.47 163.37,192.38 163.37,189.48 v1(163.51,189.34)
CH3_MDI3_N: length 20.8
  TOP w0.356: T1504.23 v1(159.51,189.34)
  BOTTOM w0.356: v1(159.51,189.34) 159.63,189.46 159.63,191.81 155.37,196.06 153.64,196.06 152.14,197.57 151.85,197.57 151.63,197.35 151.35,197.35 151.14,197.55 151.14,197.83 151.37,198.05 151.37,198.34 151.17,198.54 150.88,198.54 150.66,198.32 150.38,198.32 150.17,198.52 150.17,198.8 150.4,199.03 150.4,199.31 149.56,200.15 149.56,200.97 J1501.8
CH3_MDI3_P: length 20.8
  TOP w0.356: T1504.22 v1(160.51,189.34)
  BOTTOM w0.356: v1(160.51,189.34) 160.39,189.46 160.39,192.12 155.69,196.82 153.96,196.82 150.32,200.47 150.32,203.18 J1501.7
CH3_TRX0N_N: length 5.9
  TOP w0.155: U6.3 128.18,156.29 128.2,156.31 128.2,156.56 129.78,158.13 130.04,158.76 130.5,159.23 131.14,159.23 131.29,159.39 R1335.1
CH3_TRX0P_P: length 5.9
  TOP w0.155: U6.2 128.58,155.5 128.58,156.15 128.58,156.15 128.58,156.4 129.26,157.08 129.48,157.08 129.61,156.96 129.83,156.96 130.05,157.17 130.05,157.39 129.92,157.52 129.92,157.74 130.1,157.92 130.36,158.55 130.66,158.85 131.14,158.85 131.29,158.69 R1336.1
CH3_TRX1N_N: length 8.6
  TOP w0.155: U6.5 127.38,156.54 127.39,156.55 127.39,157.04 128.66,158.3 129.88,161.24 130.46,161.82 131.14,161.82 131.29,161.98 R1337.1
CH3_TRX1P_P: length 8.6
  TOP w0.155: U6.4 127.78,156.54 127.77,156.55 127.77,156.88 128.98,158.09 129.68,159.77 129.88,159.85 130.03,159.79 130.24,159.87 130.36,160.16 130.27,160.36 130.12,160.42 130.03,160.63 130.2,161.03 130.61,161.44 131.14,161.44 131.29,161.29 R1338.1
CH3_TRX2N_N: length 7.6
  TOP w0.155: U6.8 126.18,159.74 126.33,160.09 127,160.76 127.65,161.03 128.14,161.52 128.14,161.74 R1339.1
CH3_TRX2P_P: length 7.6
  TOP w0.155: U6.7 126.58,156.54 126.56,156.56 126.56,159.66 126.65,159.88 127.21,160.43 127.86,160.7 128.52,161.36 128.52,161.74 R1340.1
CH3_TRX3N_N: length 5.4
  TOP w0.155: U6.10 125.38,156.54 125.39,156.55 125.39,157.42 124.77,158.94 124.77,160.38 R1341.1
CH3_TRX3P_P: length 5.4
  TOP w0.155: R1342.1 125.15,160.35 125.15,159.02 125.77,157.5 125.77,156.55 125.78,156.54 U6.9
CH4_MDI0_N: length 19.8
  TOP w0.356: T1501.14 v1(151.19,189.24)
  BOTTOM w0.356: v1(151.19,189.24) 151.21,189.26 151.21,189.51 148.79,191.92 148.51,191.92 148.34,191.75 148.05,191.75 147.85,191.95 147.85,192.23 148.02,192.41 148.02,192.69 143.03,197.69 143.03,200.74 142.29,201.47 142.29,201.47 141.78,201.79 141.32,201.68 J1501.10
CH4_MDI0_P: length 19.8
  TOP w0.356: T1501.13 v1(152.19,189.24)
  BOTTOM w0.356: J1501.9 142.2,203.09 142.26,202.59 143.79,201.05 143.79,198 151.97,189.82 151.97,189.46 v1(152.19,189.24)
CH4_MDI1_N: length 23.8
  TOP w0.356: T1501.17 v1(148.19,189.24)
  ART03 w0.356: J1501.14 136.53,200.79 136.53,200.24 141.29,195.47 141.29,194.75 140.39,193.85 140.39,193.13 141.11,192.42 141.83,192.42 142.73,193.32 143.45,193.32 144.36,192.4 147.22,192.4 148.29,191.34 148.29,189.34 v1(148.19,189.24)
CH4_MDI1_P: length 23.8
  TOP w0.356: T1501.16 v1(149.19,189.24)
  ART03 w0.356: v1(149.19,189.24) 149.05,189.38 149.05,191.65 147.53,193.17 144.68,193.17 137.29,200.55 137.29,201.67 138.08,202.45 138.08,202.45 138.11,202.49 138.96,202.49 J1501.11
CH4_MDI2_N: length 19
  TOP w0.356: T1501.20 v1(145.19,189.24)
  BOTTOM w0.356: v1(145.19,189.24) 145.29,189.35 145.29,191.68 137.29,199.68 137.29,203.34 J1501.13
CH4_MDI2_P: length 19
  TOP w0.356: T1501.19 v1(146.19,189.24)
  BOTTOM w0.356: v1(146.19,189.24) 146.05,189.38 146.05,191.99 140.3,197.74 140.3,198.02 140.51,198.22 140.51,198.51 140.31,198.71 140.02,198.71 139.82,198.51 139.54,198.51 139.33,198.71 139.33,198.99 139.54,199.19 139.54,199.48 139.33,199.68 139.05,199.68 138.85,199.48 138.56,199.48 138.05,199.99 138.05,200.81 J1501.12
CH4_MDI3_N: length 20
  TOP w0.356: T1501.23 v1(142.19,189.24)
  BOTTOM w0.356: J1501.16 133.6,201.31 133.98,200.93 133.98,198.14 136.16,195.96 137.65,195.96 139.97,193.64 139.97,193.36 139.79,193.18 139.79,192.9 139.99,192.7 140.28,192.7 140.45,192.87 140.74,192.87 140.94,192.67 140.94,192.39 140.76,192.21 140.76,191.93 140.96,191.73 141.25,191.73 141.42,191.9 141.71,191.9 142.42,191.19 142.42,189.48 v1(142.19,189.24)
CH4_MDI3_P: length 20
  TOP w0.356: T1501.22 v1(143.19,189.24)
  BOTTOM w0.356: v1(143.19,189.24) 143.19,191.5 137.97,196.72 136.48,196.72 134.74,198.46 J1501.15
CH4_TRX0N_N: length 8.4
  TOP w0.155: R1343.1 121.84,161.84 121.84,161.55 121.68,161.39 120.55,161.39 119.39,160.24 119.39,156.55 119.38,156.54 U6.25
CH4_TRX0P_P: length 8.4
  TOP w0.155: U6.24 119.78,156.54 119.77,156.55 119.77,160.08 120.71,161.01 121.84,161.01 122.22,161.39 122.22,161.84 R1344.1
CH4_TRX1N_N: length 6.7
  TOP w0.155: U6.27 118.58,156.54 118.59,156.55 118.59,161.37 118.58,161.37 118.58,161.84 R1345.1
CH4_TRX1P_P: length 6.7
  TOP w0.155: U6.26 118.98,156.54 118.97,156.55 118.97,161.52 118.97,161.53 118.97,161.84 R1346.1
CH4_TRX2N_N: length 7.3
  TOP w0.155: U6.30 117.38,156.54 117.39,156.55 117.39,157.58 116.54,158.44 115.33,161.34 115.33,161.84 R1347.1
CH4_TRX2P_P: length 7.3
  TOP w0.155: R1348.1 115.71,161.84 115.71,161.42 116.86,158.65 117.77,157.74 117.77,156.55 117.78,156.54 U6.29
CH4_TRX3N_N: length 8.6
  TOP w0.155: U6.32 116.53,156.52 116.57,156.55 116.57,156.97 112.08,161.46 112.08,161.84 R1349.1
CH4_TRX3P_P: length 8.6
  TOP w0.155: U6.31 116.98,156.52 116.95,156.55 116.95,157.13 112.46,161.61 112.46,161.84 R1350.1
CLK_100M_5G_L2_N: length 1.8
  TOP w0.155: R2647.1 C2633.1 R2643.2
CLK_100M_5G_L2_P: length 1.8
  TOP w0.155: R2642.2 C2634.1 R2646.1
CLK_100M_BUF_5G_L1_N: length 2.6
  TOP w0.155: U301.50 17.19,132.03 17.16,132.07 17.16,133.23 17.42,133.5 R2643.1
CLK_100M_BUF_5G_L1_P: length 2.6
  TOP w0.155: R2642.1 16.51,133.5 16.78,133.23 16.78,132.12 16.69,132.03 U301.51
CLK_100M_BUF_5G_N: length 211.3
  TOP w0.155: J803.53 179.53,87.21 179.96,86.77 179.96,85.75 R805.2 180.24,85.47 v1(180.24,84.96) ; v1(17.41,137.15) 17.16,136.89 17.16,136.66 C2633.2
  ART04 w0.127: v1(17.41,137.15) 17.17,136.9 17.17,136.15 17.62,135.7 17.8,135.7 17.82,135.72 18,135.72 18.18,135.54 18.18,135.36 18.16,135.34 18.16,135.16 18.62,134.7 20.2,130.88 21.49,126.63 23.1,124.22 26.29,121.03 27.91,121.03 34.47,123.75 38.04,123.75 41.1,125.02 62.71,125.02 66.59,121.14 66.59,119.97 67.21,119.34 69.29,119.34 69.63,119.69 69.63,122.12 71.1,125.66 72.48,127.04 72.48,128.55 72.83,128.9 73.1,128.9 v1(73.35,129.16)
  BOTTOM w0.155: v1(73.35,129.16) 73.58,128.93 73.8,128.93 75.25,130.38 88.19,130.38 90.48,128.09 105.59,128.09 108.03,125.65 120.51,125.65 122.49,127.63 132.06,127.63 137.41,125.77 141.28,121.9 143.66,117.48 157.77,103.37 160.19,99.75 169.24,90.72 173.25,86.43 174,85.84 175.05,85.47 178.28,85.47 178.79,85.98 179.48,85.98 179.96,85.5 179.96,85.17 180.16,84.96 v1(180.24,84.96)
CLK_100M_BUF_5G_P: length 211.3
  TOP w0.155: C2634.2 16.78,136.66 16.78,136.89 v1(16.52,137.15) ; v1(179.35,84.96) 179.3,85.02 R805.1 179.58,85.88 179.58,86.61 179.03,87.17 J803.55
  ART04 w0.127: v1(16.52,137.15) 16.79,136.88 16.79,135.99 18.29,134.49 19.84,130.75 21.14,126.46 22.8,123.98 26.13,120.65 27.99,120.65 34.55,123.37 38.11,123.37 41.18,124.64 62.55,124.64 66.21,120.99 66.21,119.81 67.05,118.96 69.45,118.96 70.02,119.53 70.02,122.05 71.42,125.45 72.86,126.89 72.86,128.4 72.99,128.52 73.1,128.52 v1(73.35,128.27)
  BOTTOM w0.155: v1(179.35,84.96) 179.46,84.96 179.58,85.08 179.58,85.34 179.32,85.6 178.94,85.6 178.44,85.09 174.99,85.09 173.82,85.5 172.99,86.15 168.97,90.45 159.9,99.51 157.48,103.13 143.35,117.25 140.97,121.67 137.2,125.44 132,127.25 122.65,127.25 120.67,125.27 107.87,125.27 105.43,127.71 90.32,127.71 88.04,130 76.97,130 76.71,129.74 76.35,129.74 76.09,130 75.41,130 73.96,128.54 73.62,128.54 v1(73.35,128.27)
CLK_100M_BUF_M2_L1_N: length 3.2
  TOP w0.203: R2617.1 20.96,125.9 20.67,125.9 20.09,125.33 U301.37
CLK_100M_BUF_M2_L1_P: length 3.2
  TOP w0.203: R2618.1 21.05,126.41 20.47,126.41 19.89,125.83 U301.38
CLK_100M_BUF_M2_N: length 36.2
  TOP w0.155: v1(25.18,125.67) 24.93,125.92 24.65,125.92 24.39,125.65 C2624.2 ; v1(20.74,155.23) 21.02,154.95 21.02,154.65 R612.1 20.96,154.28 20.96,153.83 20.51,153.38 J601.53
  ART04 w0.127: v1(25.18,125.67) 24.93,125.92 24.42,125.92 23.72,126.61 23.72,135.2 23.1,137.68 21.91,139.3 20.51,142.68 20.51,152.23 20.5,152.24 20.5,153.88 21.06,154.43 21.06,154.91 v1(20.74,155.23)
CLK_100M_BUF_M2_P: length 36.3
  TOP w0.155: J601.55 21.01,153.34 21.34,153.67 21.34,154.15 R612.2 21.4,154.65 21.4,155 v1(21.63,155.23) ; C2623.2 24.39,126.57 24.65,126.3 24.93,126.3 v1(25.18,126.55)
  ART04 w0.127: v1(25.18,126.55) 24.93,126.3 24.57,126.3 24.1,126.77 24.1,135.24 23.45,137.84 22.24,139.49 20.89,142.75 20.89,152.08 21.02,152.2 21.29,152.2 21.41,152.33 21.41,152.58 21.29,152.71 21.01,152.71 20.88,152.84 20.88,153.72 21.44,154.27 21.44,155.04 v1(21.63,155.23)
CLK_100M_BUF_PCIE_L1_N: length 5.5
  TOP w0.203: R2615.1 22.84,122.28 22.2,122.28 20.65,123.83 U301.34
CLK_100M_BUF_PCIE_L1_P: length 5.6
  TOP w0.203: U301.35 20.66,124.33 22.31,122.67 22.83,122.67 R2616.1
CLK_100M_BUF_WIFI_L1_N: length 3.4
  TOP w0.203: U301.44 19.45,128.83 20.44,129.81 20.98,129.81 R2614.1
CLK_100M_BUF_WIFI_L1_P: length 3.4
  TOP w0.203: R2613.1 21.05,130.34 20.27,130.34 19.25,129.33 U301.45
CLK_100M_BUF_WIFI_N: length 175.4
  TOP w0.155: C2619.2 23.93,129.7 24.08,129.86 25.31,129.86 v1(25.56,129.6) ; v1(142.9,84.65) 143.13,84.88 143.13,85.44 R100.2 143.13,85.9 143.13,86.56 142.95,86.74 J701.11
  BOTTOM w0.155: v1(142.9,84.65) 143.15,84.9 143.15,85.3 145.19,90.2 145.19,92.05 145.01,92.23 145.01,92.85 145.19,93.03 145.19,93.65 145.01,93.83 145.01,94.45 145.19,94.62 145.19,95.24 145.01,95.42 145.01,96.04 145.19,96.22 145.19,96.84 145.01,97.02 145.01,97.64 145.19,97.81 145.19,98.96 143.27,103.6 131.52,115.35 127.79,116.89 102.06,116.89 99.67,117.88 82.86,117.88 82.09,117.11 82.09,115.62 80.64,114.17 78.9,109.96 78.11,109.17 63.01,109.17 61.67,110.51 61.14,111.79 61.14,115.4 61.12,115.48 60.71,116.49 60.71,116.84 60.46,117.44 59.22,118.67 57.81,119.84 54.74,122.91 52.67,127.89 51.91,128.66 51.9,128.66 50.92,129.65 40.55,138.15 37.86,139.27 34.91,139.27 31.69,137.93 28.78,135.03 26.98,130.69 26.96,130.62 26.19,129.86 25.82,129.86 v1(25.56,129.6)
CLK_100M_BUF_WIFI_P: length 175.5
  TOP w0.155: v1(25.56,130.49) 25.31,130.24 24.08,130.24 23.93,130.39 C2620.2 ; J701.13 143.75,86.75 143.51,86.51 143.51,85.87 R100.1 143.51,85.47 143.51,84.93 v1(143.79,84.65)
  BOTTOM w0.155: v1(25.56,130.49) 25.82,130.24 26.04,130.24 26.63,130.83 28.46,135.24 31.47,138.26 34.83,139.65 37.94,139.65 40.75,138.48 51.17,129.93 52.06,129.04 52.06,129.04 52.99,128.11 55.06,123.12 58.06,120.12 59.48,118.96 60.78,117.65 61.09,116.91 61.09,116.56 61.49,115.6 61.52,115.44 61.52,111.87 61.99,110.73 63.17,109.55 77.95,109.55 78.58,110.18 80.32,114.39 81.71,115.78 81.71,117.27 82.7,118.26 99.75,118.26 102.14,117.27 127.86,117.27 131.73,115.67 143.59,103.81 145.57,99.04 145.57,90.13 143.54,85.22 143.54,84.9 v1(143.79,84.65)
CLK_100M_M2_L2_N: length 2.1
  TOP w0.203: R2617.2 C2624.1 R2625.1
CLK_100M_M2_L2_P: length 2.1
  TOP w0.203: R2626.1 C2623.1 R2618.2
CLK_100M_PCIE_L2_N: length 2
  TOP w0.203: R2627.1 C2622.1 R2615.2
CLK_100M_PCIE_L2_P: length 2.1
  TOP w0.203: R2616.2 C2621.1 R2628.1
CLK_100M_WIFI_L2_N: length 2.1
  TOP w0.203: R2623.1 C2619.1 R2614.2
CLK_100M_WIFI_L2_P: length 2.1
  TOP w0.203: R2624.1 C2620.1 R2613.2
DEVSLP_M2: length 2.8
  TOP w0.203: R57.2 4.04,151.94 4.19,151.79 4.67,151.79 4.85,151.61 R55.1 R602.1
EMMC_CLK: length 76.5
  TOP w0.203: v1(109.45,123.72) 109.45,122.58 108.82,121.63 108.1,119.91 J3.199 ; R1808.1 55.4,148.84 v1(56.01,148.84) 56.36,148.84 R1833.1
  ART04 w0.178: v1(56.01,148.84) 55.87,148.7 55.05,146.73 55.05,144.31 55.12,144.14 55.48,143.79 56.15,143.51 69.39,143.51 69.81,143.34 70.61,143.01 78.86,143.01 78.87,143.01 79.3,143.01 79.31,143.01 80.2,143.01 80.21,143.01 80.64,143.01 80.95,142.71 80.95,142.69 80.96,142.67 81.1,142.3 82.81,140.59 83.74,139.96 85.45,139.62 87.73,139.4 90.85,139.19 92.52,139.02 93.52,138.88 95.63,138.67 96.03,138.63 96.97,138.63 97.14,138.62 98.94,137.42 100.61,136.3 101.68,135.23 102.04,135.08 102.72,134.52 103.95,133.17 104.58,132.23 104.67,132 104.67,129.68 104.71,129.55 106.29,127.19 108.05,125.42 v1(109.45,123.72)
EMMC_CMD: length 73.9
  TOP w0.203: R114.1 v1(49.98,141.67) R1811.2 ; v1(108.6,119.91) J3.201
  ART04 w0.178: v1(108.6,119.91) 108.6,120.62 108.11,122.1 106.11,124.81 102.1,128.82 101.75,129.65 101.75,131.66 100.99,132.43 100.22,132.94 99.74,132.94 99.58,133.01 97.97,134.08 96.34,135.71 96.1,135.81 94.78,136.66 93.27,137.22 92.32,137.36 90.71,137.51 84.08,137.97 82.57,138.12 77.28,138.64 76.54,138.79 73.74,138.79 73.59,138.64 73.59,138.6 73.45,138.45 73.25,138.45 73.11,138.6 73.11,138.64 72.97,138.79 72.77,138.79 72.63,138.64 72.63,138.6 72.49,138.45 72.29,138.45 72.15,138.6 72.15,138.64 72.01,138.79 71.81,138.79 71.66,138.64 71.66,138.6 71.52,138.45 71.32,138.45 71.18,138.6 71.18,138.64 71.04,138.79 63.78,138.79 63.5,139.06 59.94,139.06 59.76,138.89 59.76,138.65 59.62,138.51 59.42,138.51 59.28,138.65 59.28,138.87 59.14,139.01 58.94,139.01 58.79,138.87 58.79,138.65 58.65,138.51 58.08,138.51 57.21,138.59 50.11,141.54 v1(49.98,141.67)
EMMC_DATA0: length 77.9
  TOP w0.203: v1(110.1,119.91) J3.207 ; R1825.1 52.52,141.8 v1(52.64,141.67) 52.52,141.54 R1816.2
  ART04 w0.178: v1(52.64,141.67) 52.78,141.81 54.6,141.81 55.74,141.34 56.46,140.61 57.24,140.61 57.47,140.85 57.47,141.78 57.61,141.92 57.99,141.92 58.13,141.78 58.13,140.85 58.4,140.59 61.09,140.59 61.47,140.97 71.27,140.97 71.65,141.35 72.01,141.35 72.19,141.17 72.19,140.86 72.37,140.69 72.72,140.69 72.9,140.86 72.9,141.22 73.08,141.4 73.43,141.4 73.61,141.22 73.61,140.86 73.79,140.69 77.37,140.69 77.85,140.59 78.04,140.72 78.14,141.19 78.33,141.31 78.56,141.27 78.68,141.08 78.59,140.61 78.72,140.42 78.95,140.37 79.14,140.5 79.23,140.97 79.42,141.1 79.65,141.05 79.78,140.86 79.69,140.39 79.82,140.2 85.37,139.09 87.68,138.87 90.8,138.65 92.46,138.49 93.46,138.35 96,138.1 96.95,138.1 100.29,135.87 101.38,134.78 101.57,134.7 102.76,133.51 103.15,132.58 103.15,132 104.36,129.09 105.57,127.28 107.42,125.42 109.13,123.11 110.1,120.18 v1(110.1,119.91)
EMMC_DATA0_R: length 5.3
  TOP w0.203: R1825.2 51.56,144.09 51.34,144.41 50.93,145.41 50.17,146.18 50.05,146.35 U9.A3
EMMC_DATA1: length 77.9
  TOP w0.203: J3.209 110.6,119.7 110.8,119.91 v1(111.12,119.91) ; R1817.2 v1(51.25,141.67) R1826.1
  ART04 w0.178: v1(111.12,119.91) 110.66,119.44 109.91,119.44 109.79,119.49 109.6,119.68 109.6,120.1 108.57,123.23 107.39,124.82 105.42,126.79 104.32,128.27 103.84,129.18 102.4,132.65 102.4,133.19 101.65,133.94 99.46,134.6 98.37,135.69 96.55,136.44 96.31,136.64 95.56,137.15 94.59,137.66 94.09,137.81 94.03,137.82 93.94,137.86 93.63,137.95 93.41,137.97 92.41,138.11 90.77,138.27 87.65,138.49 83.97,138.85 79.07,139.82 78.95,139.85 77.78,140.08 71.5,140.08 71.12,140.46 62.1,140.46 61.72,140.08 56.56,140.08 56.05,140.29 55.19,141.15 54.73,141.34 54.22,141.34 53.51,141.05 52.59,141.05 52.16,141.24 51.92,141.63 51.92,142.22 51.38,142.75 50.75,142.75 50.52,142.52 50.52,141.93 50.79,141.67 v1(51.25,141.67)
EMMC_DATA1_R: length 4.9
  TOP w0.203: U9.A4 49.1,147.21 50.27,145.02 50.9,144.17 R1826.2
EMMC_DATA2: length 78.5
  TOP w0.203: R1827.1 v1(48.71,141.67) R1818.2 ; J3.211 v1(111.1,115.95)
  ART04 w0.178: v1(48.71,141.67) 57.44,138.05 74.82,138.05 75.44,137.92 77.29,137.72 77.79,137.71 85.86,137.36 92,136.96 92.82,136.89 93.28,136.81 94.65,136.29 95.48,135.71 96.1,135.37 97.62,133.85 99.56,132.56 100.1,132.56 100.74,132.13 101.18,131.7 101.18,129.79 102.02,127.76 102.25,127.53 103.44,124.65 104.45,121.61 104.68,121.2 106.88,119 108.41,117.9 108.83,117.97 109.14,117.74 109.21,117.32 109.52,117.09 109.94,117.16 110.25,116.94 110.32,116.51 v1(111.1,115.95)
EMMC_DATA2_R: length 4.3
  TOP w0.203: U9.A5 48.6,145.03 48.71,144.14 R1827.2
EMMC_DATA3: length 78.4
  TOP w0.203: J3.213 111.6,121 v1(112.14,121.54) ; R1828.1 55.33,145.67 v1(56.13,145.67) 56.74,145.67 R1819.2
  ART04 w0.178: v1(56.13,145.67) 56.37,145.67 56.95,146.25 56.95,148.31 57.18,148.54 57.58,148.54 57.71,148.41 57.71,147.06 57.66,147.01 57.66,146.23 57.84,146.05 61.73,146.05 63.57,145.29 69.76,145.29 71.36,144.63 77.44,144.63 78.47,144.58 79.21,144.54 79.21,144.54 80.29,144.49 80.61,144.45 83.42,143.9 85.61,143.9 91.3,142.76 97.04,140.39 99.98,139.02 102.31,138.16 104.48,136.95 106.16,135.27 107.23,131.75 107.42,131.47 107.42,131.47 107.77,130.94 108.21,130.5 108.68,130.19 108.95,129.91 108.95,129.9 110.52,128.34 110.55,128.34 111.29,127.6 112.82,123.9 112.82,123.18 v1(112.14,121.54)
EMMC_DATA3_R: length 5.2
  TOP w0.203: R1828.2 53.2,146.87 51.44,147.6 51.09,147.95 U9.B1 U9.B2
EMMC_DATA4: length 78.5
  TOP w0.203: J3.215 112.1,118.09 v1(112.1,119.91) ; R1829.1 55.91,144.65 55.93,144.68 v1(56.13,144.68) 56.77,144.68 R1815.2
  ART04 w0.178: v1(112.1,119.91) 111.63,121.05 111.63,122.6 111.83,123.58 111.4,125.76 108.61,128.55 108.04,129.41 108,129.49 108,129.69 107.81,130.23 106.88,131.36 105.75,135.09 104.55,136.29 104.28,136.48 104.08,136.44 103.85,136.09 103.65,136.05 103.48,136.16 103.44,136.36 103.68,136.71 103.64,136.9 103.18,137.21 102.68,137.41 102.49,137.34 102.36,137.01 102.17,136.93 101.99,137.01 101.91,137.19 102.05,137.52 101.97,137.71 101.79,137.78 101.6,137.71 101.47,137.38 101.28,137.3 101.1,137.38 101.02,137.56 101.16,137.89 101.08,138.08 100.89,138.15 100.71,138.08 100.57,137.75 100.44,137.69 100.22,137.78 100.14,137.97 100.26,138.26 100.19,138.45 98.98,138.95 97.26,139.81 90.93,142.44 85.5,143.52 82.91,143.52 79.83,144.13 78.46,144.2 71.05,144.2 69.64,144.78 63,144.78 61.74,145.3 58.94,145.3 58.8,145.16 58.8,144.79 58.66,144.65 58.46,144.65 58.32,144.79 58.32,145.16 58.18,145.3 57.98,145.3 57.83,145.16 57.83,144.79 57.69,144.65 57.49,144.65 57.35,144.79 57.35,145.16 57.21,145.3 56.75,145.3 v1(56.13,144.68)
EMMC_DATA4_R: length 6.2
  TOP w0.127: U9.A2 U9.B3
  TOP w0.203: U9.A2 50.1,147.41 50.44,147.07 50.79,147.07 53.19,146.07 53.85,145.41 53.85,145.05 54.25,144.65 R1829.2
EMMC_DATA5: length 76.7
  TOP w0.203: R1814.2 54.14,140.93 54.2,140.87 v1(54.52,140.87) 54.52,140.93 54.2,141.7 R1830.1 ; J3.217 112.6,119.71 112.65,119.76 112.65,121.03 v1(113.16,121.54)
  ART04 w0.178: v1(54.52,140.87) 54.92,140.46 55.51,140.08 56.72,139.57 63.75,139.57 64.01,139.32 65.31,139.32 65.56,139.42 79.14,139.42 83.91,138.47 87.62,138.11 90.74,137.89 92.37,137.73 93.37,137.59 93.56,137.57 93.81,137.5 94.93,137.01 95.06,136.96 95.07,136.95 95.36,136.82 96.35,136.12 96.39,136.1 96.56,136.03 97.91,134.67 100.53,133.88 100.8,133.61 100.8,133.16 102.44,131.52 103.4,129.18 104.1,127.88 104.93,126.76 107.05,124.64 108.19,123.11 109.19,120.05 109.19,119.58 109.5,119.28 110.17,119 111.19,119 112.43,119.51 112.65,119.73 112.65,120.31 v1(113.16,121.54)
EMMC_DATA5_R: length 9.5
  TOP w0.127: U9.D2 U9.C3 U9.B4
  TOP w0.203: R1830.2 53.47,143.45 53.47,145.29 53.09,145.67 v1(52.58,145.67) ; v1(51.12,149.03) 51.03,148.95 U9.D1 U9.D2
  BOTTOM w0.203: v1(52.58,145.67) 51.23,148.92 v1(51.12,149.03)
EMMC_DATA6: length 76.2
  TOP w0.203: R1813.2 56.26,150.49 v1(56.01,150.24) 55.75,150.49 R1831.1 ; v1(113.16,119.91) 113.16,119.89 113.1,119.83 J3.219
  ART04 w0.178: v1(113.16,119.91) 113.67,121.13 113.67,122.67 111.5,127.89 109.33,130.06 109.33,130.07 108.84,130.57 108.83,130.57 108.61,130.79 108.43,130.86 107.99,131.3 107.71,131.72 107.44,132.37 106.86,134.28 106.86,134.7 106.46,135.65 104.26,137.85 97.63,140.6 97.2,140.83 91.62,143.14 85.52,144.35 79.66,144.93 79,144.93 72.15,145.27 70.31,145.64 70.09,145.72 62.66,146.46 59.46,147.26 58.7,147.57 v1(58.55,147.57)
  BOTTOM w0.203: v1(58.55,147.57) 57.66,147.57 57.02,148.21 57.02,149.22 v1(56.01,150.24)
EMMC_DATA6_R: length 7.5
  TOP w0.203: R1831.2 v1(52.71,150.49) ; v1(48.39,148.97) 48.6,148.76 U9.C5 U9.B5
  ART03 w0.178: v1(52.71,150.49) 50.63,149.87 50.49,149.77 48.56,148.97 v1(48.39,148.97)
EMMC_DATA7: length 75.3
  TOP w0.203: v1(58.55,148.34) 58.55,148.54 58.06,149.02 57.1,149.02 56.74,149.38 R1812.2 R1832.1 ; J3.221 113.6,119.67 114.27,121.29 v1(114.27,121.51)
  ART04 w0.178: v1(58.55,148.34) 58.77,148.11 61.83,147.17 63.34,146.87 64.17,146.79 71.33,146.79 80.52,145.88 82.05,145.46 91.61,143.56 104.4,138.26 105.53,137.43 107.76,134.73 109.19,130.93 110.27,129.7 111.38,128.78 112.39,127.84 112.92,127.08 114.19,124.01 114.27,123.57 v1(114.27,121.51)
EMMC_DATA7_R: length 9.9
  TOP w0.102: U9.A8 U9.B7
  TOP w0.203: R1832.2 v1(53.72,149.61) ; U9.A8 v1(47.1,146.94) ; U9.B7 U9.B6
  ART03 w0.178: v1(47.1,146.94) 50.59,149.28 50.75,149.4 51.31,149.61 v1(53.72,149.61)
EMMC_DS: length 75.8
  TOP w0.203: R1807.1 55.78,147.58 v1(56,147.36) 56,147.17 56.62,146.56 R1820.1 ; J3.205 109.6,120.39 v1(110.74,121.54)
  ART04 w0.178: v1(56,147.36) 55.87,147.22 55.58,146.53 55.58,144.57 55.94,144.21 59.35,144.21 59.36,144.22 59.49,144.22 60.1,144.83 60.32,144.92 60.92,144.92 62.51,144.26 69.33,144.26 70.44,143.8 78.7,143.8 79.68,143.75 82.94,143.1 85.28,143.1 91.1,141.94 96.86,139.56 100.61,137.06 101.93,135.73 102.85,135.35 106.02,132.18 106.34,131.71 106.59,131.05 106.75,129.97 106.95,129.31 108.41,127.12 111.17,124.36 111.31,124.02 111.31,123.65 111.03,122.24 v1(110.74,121.54)
EMMC_POWER_EN: length 167.7
  TOP w0.203: R1806.2 v1(26.64,163.42) ; R1806.2 R1822.2 R1821.1 ; R1806.2 R1805.1 ; v1(108.98,115.95) 108.71,115.95 107.6,117.06 J3.197
  ART03 w0.178: v1(93.22,116.59) 93.22,114.66 89.79,111.23 83.67,111.23 78.87,106.43 40.77,106.43 36.2,111 36.2,112.65 33.53,115.32 v1(31.12,115.32)
  BOTTOM w0.203: v1(31.12,115.32) 30.48,114.68 29.72,114.68 29.34,115.06 29.34,117.98 28.35,118.97 26.1,118.97 21.84,123.23 21.84,129.16 22.61,129.92 22.61,131.44 24.9,135.57 31.72,142.39 35.5,142.39 39.75,146.64 39.75,152.09 34.37,157.47 34.37,158.97 30.65,162.69 27.38,162.69 v1(26.64,163.42) ; v1(108.98,115.95) 108.32,115.29 103.18,115.29 99.13,116.09 96.32,117.26 93.89,117.26 v1(93.22,116.59)
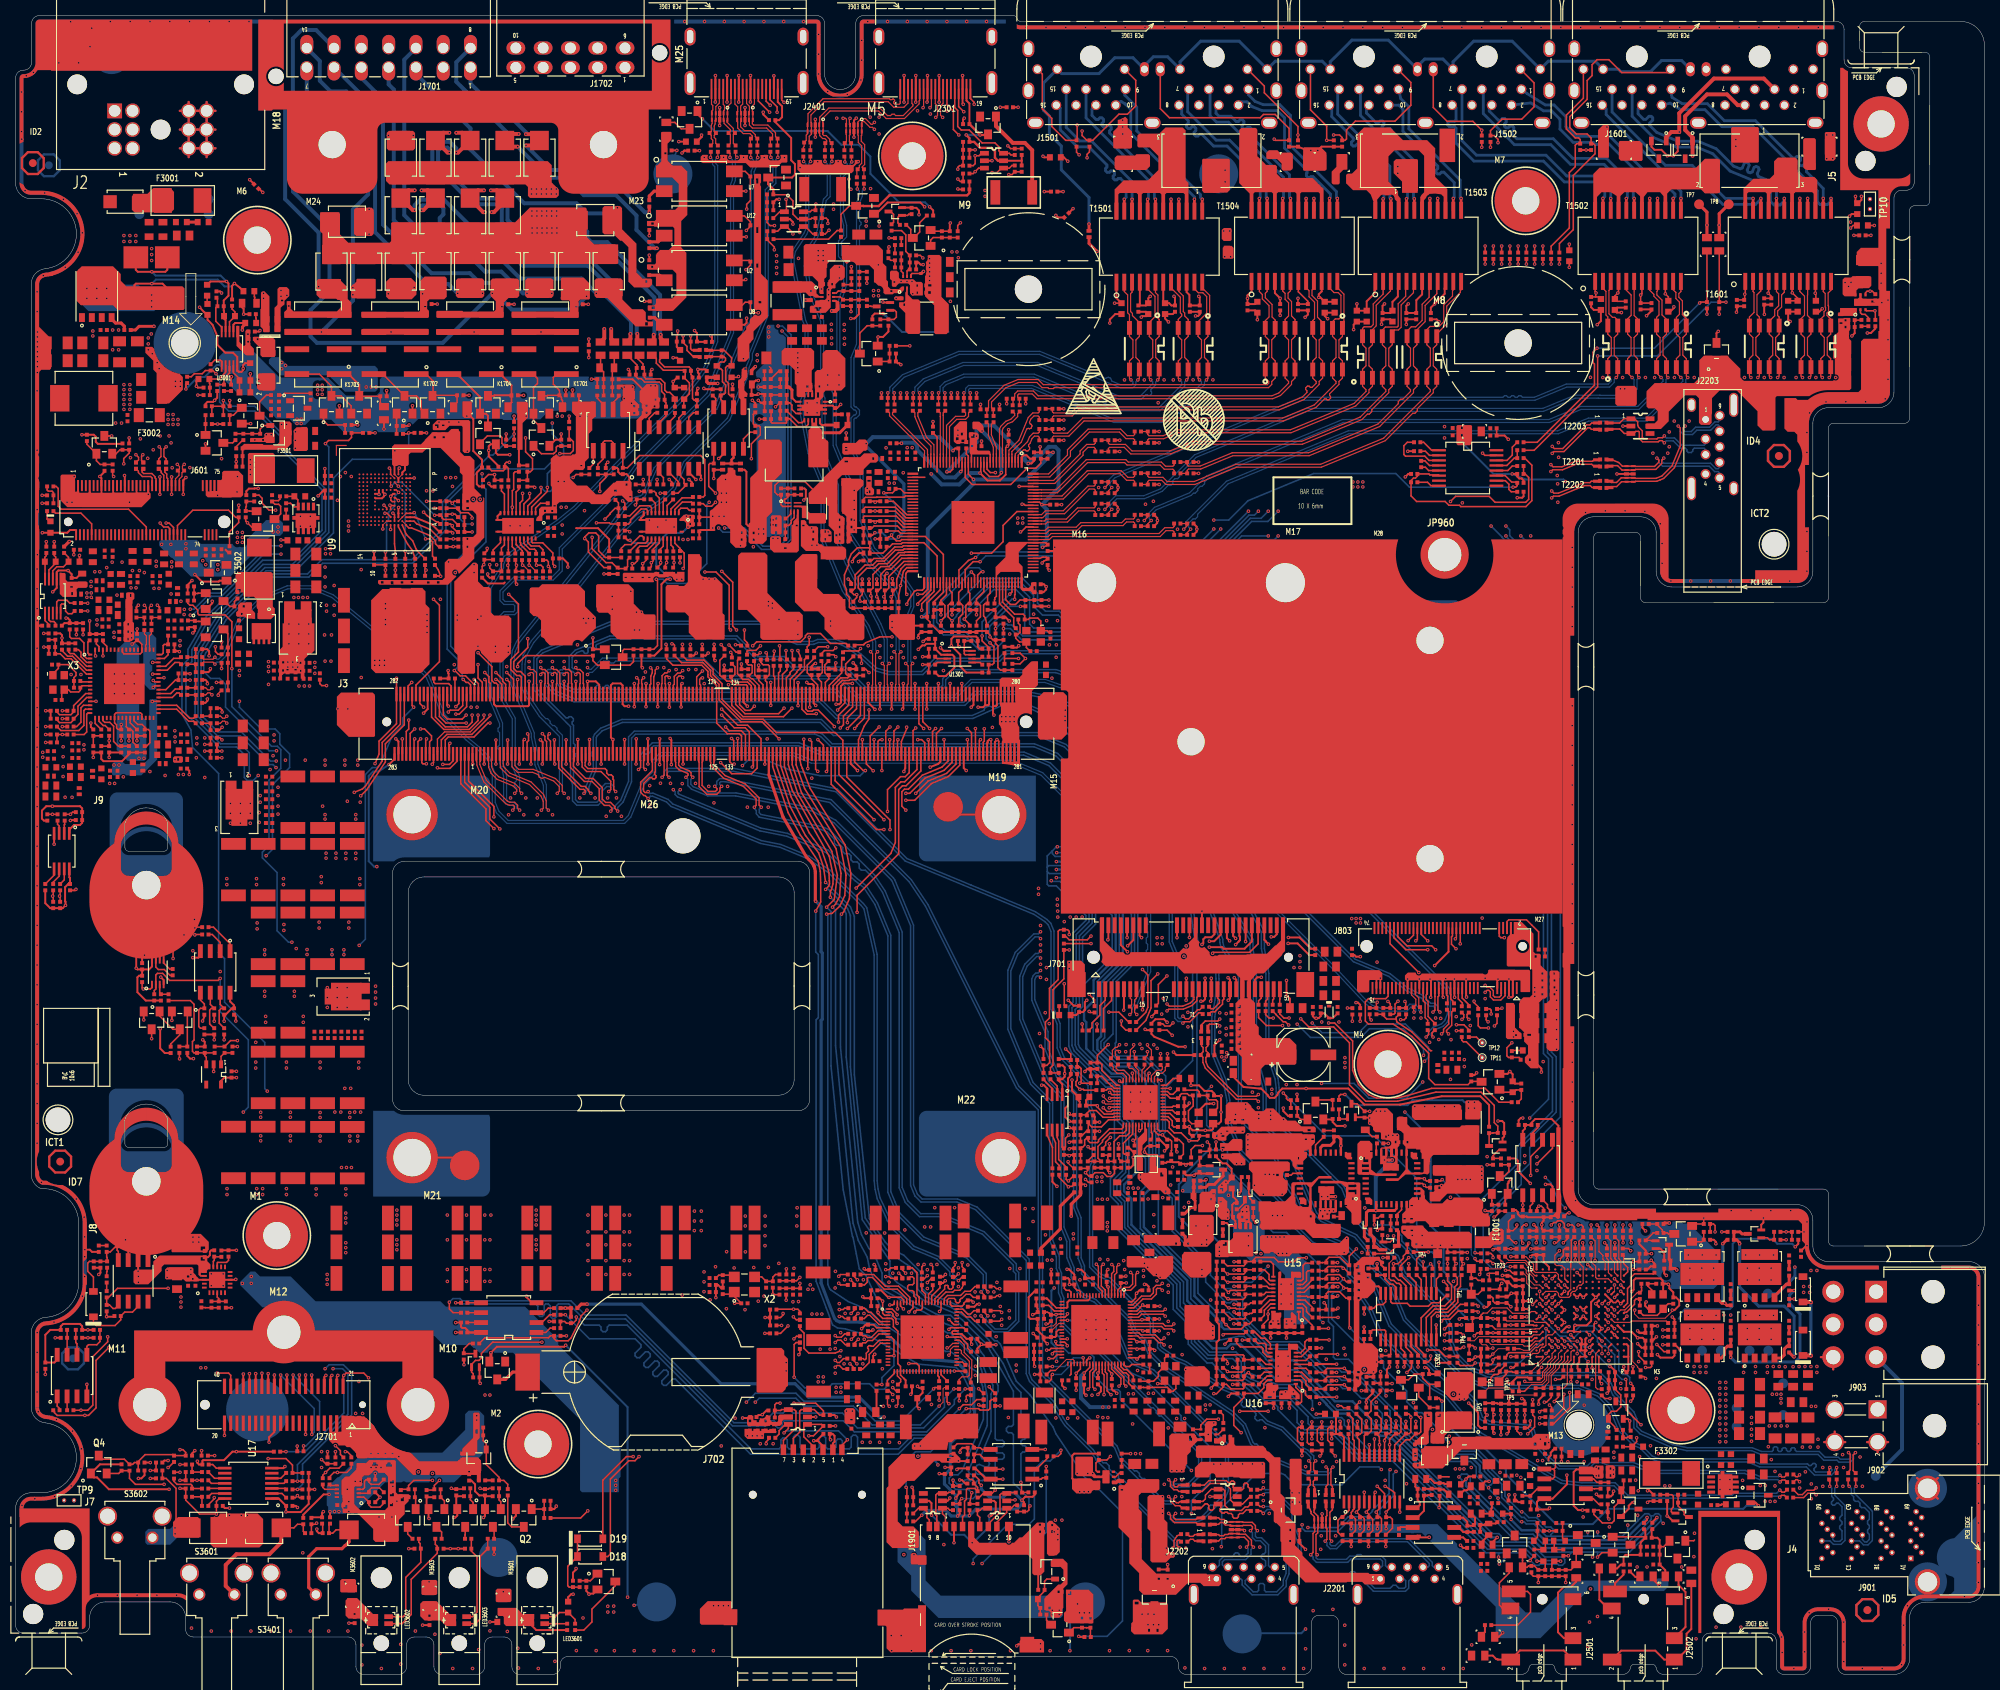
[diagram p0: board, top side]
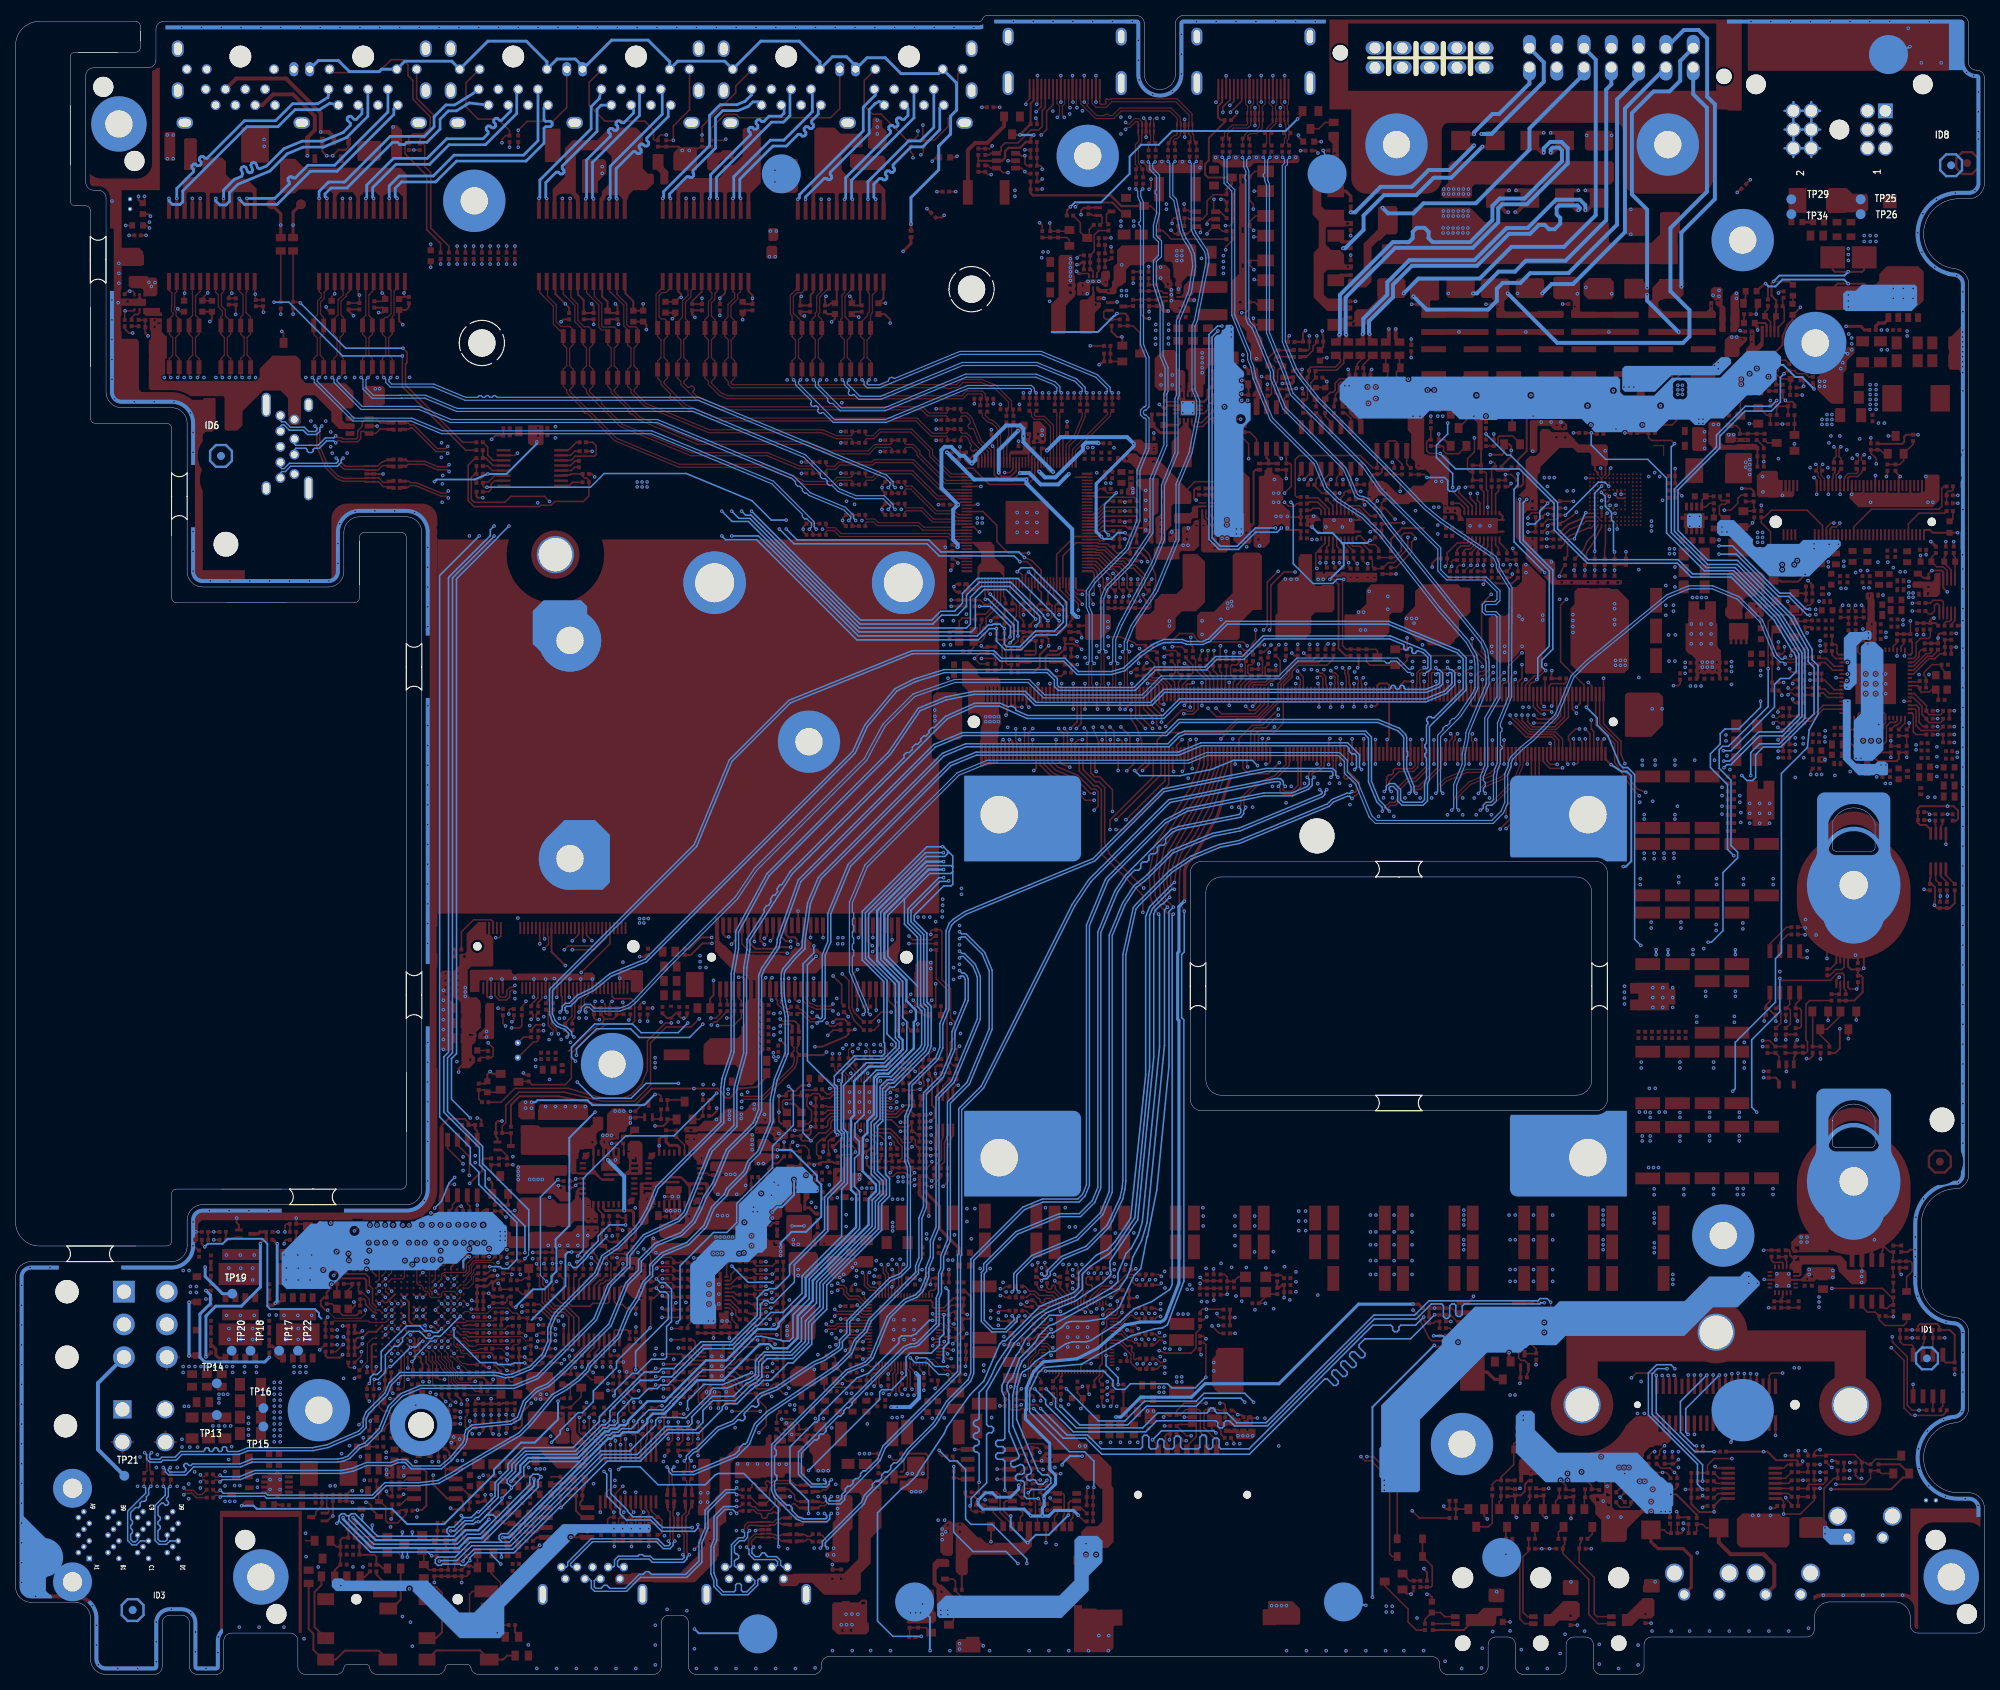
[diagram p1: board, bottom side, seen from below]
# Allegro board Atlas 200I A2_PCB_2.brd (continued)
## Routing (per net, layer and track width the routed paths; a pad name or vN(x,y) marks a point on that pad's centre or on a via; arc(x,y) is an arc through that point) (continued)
EN_MCU_HOT1: length 257.9
  TOP w0.203: R3505.1 31.22,151.28 31.62,150.88 31.62,150.24 32.51,149.35 v1(33.35,149.35) ; R2813.1 198.63,57.33 198.63,57.84 198.27,58.19 197.76,58.19 197.54,57.96 197.26,57.96 v1(196.95,57.66)
  ART03 w0.178: v1(33.35,149.35) 39.19,155.19 57.15,155.19 58.8,153.54 60.39,153.54 62.82,155.98 70.37,155.98 72.37,157.99 100.14,157.99 104.18,162.03 106.2,162.03 106.83,162.66 122.82,162.66 123.4,162.08 134.05,162.08 134.24,161.89 143.88,161.89 145.39,160.38 155.79,160.38 171.64,144.53 171.64,122.36 188.56,105.45 188.56,95.78 193.8,90.53 193.8,73.3 192.82,72.32 192.82,63.26 196.95,59.14 v1(196.95,57.66)
EN_MCU_HOT2: length 343.2
  TOP w0.203: v1(27.74,129.03) 27.74,135.05 26.87,135.91 23.53,135.91 23.37,136.08 23.37,136.52 22.73,137.16 22.35,137.16 22.07,137.44 R3539.1 ; R2812.1 207.14,57.55 v1(207.05,57.64)
  ART03 w0.178: v1(44.5,33.48) 45.06,33.48 45.6,34.02 45.6,36.17 44.73,37.03 44.73,42.65 39.01,48.36 39.01,58.39 36.6,60.8 36.6,78.43 35.18,79.86 35.18,93.68 v1(35.43,93.93)
  ART04 w0.178: v1(207.05,57.64) 210.32,54.36 210.32,49.77 212.94,47.15 212.94,41.17 209.97,38.2 209.97,30.95 211.16,29.76 211.16,27.65 209.98,26.47 209.98,21.71 203.97,15.7 190.09,15.7 189.74,15.34 168.97,15.34 166.24,18.07 166.24,19.31 165.87,19.68 164.76,19.68 164.38,19.3 142.33,19.3 137.34,14.32 130.9,14.32 127.6,17.62 75.37,17.62 70.38,22.61 54.23,22.61 52.2,24.64 52.2,26.72 45.74,33.18 44.8,33.18 v1(44.5,33.48)
  BOTTOM w0.203: v1(27.74,129.03) 27.74,124.15 32.83,119.06 33.58,119.06 34.01,118.62 34.01,116.23 32.5,114.72 32.5,106.34 31.65,105.49 31.65,104.75 33.53,102.87 33.53,95.4 35,93.93 v1(35.43,93.93)
EN_TEC_FORWARD: length 58.6
  TOP w0.203: R1119.1 R1117.2 217.75,57.78 217.96,57.58 v1(217.96,56.77) ; v1(178.66,53.47) 177.66,52.46 R1022.2
  ART03 w0.178: v1(217.96,56.77) 217.87,56.68 210.5,56.68 208.44,58.74 198.98,58.74 195.11,62.6 v1(195.11,64.64)
  ART04 w0.178: v1(178.66,53.47) 178.66,54.28 180.23,55.84 180.59,55.84 181.06,56.31 183.73,56.31 190.87,63.45 190.87,65.36 192.94,67.44 194.73,67.44 195.58,66.58 195.58,65.11 v1(195.11,64.64)
EN_TEC_PWR: length 36.6
  TOP w0.203: R1023.2 179.69,53.3 180.06,53.67 v1(180.42,53.67) ; v1(162.59,74.57) 162.99,74.17 162.99,73.87 163.2,73.67 R1016.2 R1015.1
  BOTTOM w0.203: v1(180.42,53.67) 180.42,53.73 179.69,54.46 179.69,63.64 174.24,69.09 168.07,69.09 v1(162.59,74.57)
EN_TEC_PWR_R: length 17.1
  TOP w0.203: R1001.2 181.36,62.48 180.92,62.48 v1(180.67,62.74) 180.43,62.98 U11.22 ; v1(173.66,72.24) C1011.1 172.04,73.2 Q1004.3
  ART03 w0.178: v1(173.66,72.24) 175.26,70.64 175.26,68 180.52,62.74 v1(180.67,62.74)
FACTORYSET_1911: length 30
  TOP w0.203: R274.1 64.14,142.93 64.14,142.4 v1(64.24,142.3) 64.24,141.96 64.14,141.86 R279.1 R278.2 ; v1(50.8,127.25) 50.35,126.8 J3.288
  ART03 w0.178: v1(50.8,127.25) 50.8,136.4 53.47,139.06 55.37,139.06 57.53,141.22 57.53,141.86 58.55,142.87 63.66,142.87 v1(64.24,142.3)
FACTORYSET_1911_R: length 245
  TOP w0.203: v1(203.8,55.37) 204.09,55.08 R2839.2 ; R275.2 R276.2 R277.2 66.01,154.28 66.29,154.56 66.29,155.96 65.41,156.84 v1(65.41,158.62)
  ART03 w0.178: v1(189.23,147.32) 188.14,148.41 169.93,148.41 156.43,161.9 146.02,161.9 143.26,164.67 141.72,164.67 141.29,165.1 111.06,165.1 110.15,164.19 99.95,164.19 95.27,159.51 71.02,159.51 70.13,158.62 v1(65.41,158.62)
  ART04 w0.178: v1(203.8,55.37) 203.35,54.93 201.87,54.93 201.45,55.35 201.45,55.85 201.09,56.21 201.09,57.78 200.84,58.03 198.27,59.09 197.85,59.51 197.85,68.59 195.07,71.37 v1(194.18,71.37)
  BOTTOM w0.203: v1(194.18,71.37) 196.6,73.79 196.6,78.99 195.95,79.64 195.95,140.55 190.65,145.85 190.65,145.9 v1(189.23,147.32)
GATE_24711: length 19.9
  TOP w0.254: U3001.7 27.93,173.14 28.15,173.37 C3003.1
  TOP w0.381: C3003.1 29.45,173.21 29.08,172.85 v1(29.08,172.47) ; R3009.1 15.37,172.47 15.84,172.94 v1(17.74,172.94)
  ART03 w0.381: v1(17.74,172.94) 19.89,175.08 22.56,175.08 24.44,174.32 26.29,172.47 v1(29.08,172.47)
HDMI0_CEC: length 136.9
  TOP w0.203: v1(118.75,121.35) 118.1,120.7 J3.239 ; R2302.1 R2301.2 121.16,191.52 v1(120.84,191.83)
  ART04 w0.178: v1(118.75,121.35) 121.41,118.68 130.81,118.68 133.35,121.22 133.35,126.28 134.57,127.51 134.57,137.81 132.24,140.14 131.09,140.14 127.13,144.11 127.13,153.29 127.27,153.63 127.27,154.95 125.06,157.16 125.06,159.61 121.49,163.18 110.95,163.18 98.81,175.33 98.81,175.74 96.08,178.47 96.08,183.26 96.8,183.98 98.08,183.98 98.41,183.65 101.11,183.65 102.25,184.8 111.33,184.8 111.66,185.13 115.53,185.13 120.27,189.86 120.27,191.26 v1(120.84,191.83)
HDMI0_HOTPLUG: length 144.9
  TOP w0.203: J3.237 117.6,120.66 117.6,120.66 117.6,120.96 v1(117.98,121.35) ; v1(120.84,193.1) 120.84,193.33 121.06,193.55 R2309.2 C2302.1 R2310.2 R2308.1
  ART04 w0.178: v1(120.84,193.1) 121.41,192.53 121.41,190.25 115.91,184.75 111.82,184.75 111.37,184.3 102.3,184.3 101.27,183.27 98.21,183.27 97.88,183.6 96.95,183.6 96.46,183.11 96.46,178.78 99.31,175.92 99.31,175.36 109.57,165.1 123.21,165.1 125.44,162.87 125.44,157.32 127.65,155.11 127.65,153.55 127.51,153.22 127.51,144.27 131.25,140.52 132.4,140.52 134.96,137.97 134.96,127 133.86,125.9 133.86,120.9 131.25,118.3 120.01,118.3 117.98,120.33 v1(117.98,121.35)
HDMI0_SCL: length 161.2
  TOP w0.203: v1(127.25,196.09) 127.61,195.73 R2305.1 R2317.2 ; J3.230 115.85,121.96 v1(116.46,121.35)
  ART04 w0.178: v1(127.25,196.09) 127.25,194.06 128.02,193.29 128.02,192.15 127.38,191.52 124.33,191.52 116.18,183.36 112.91,183.36 112.21,182.66 110.43,182.66 109.62,183.48 102.55,183.48 101.37,182.3 100.38,182.3 99.94,181.85 99.94,181.46 101.72,179.68 105.77,179.68 108.08,177.37 108.08,175.32 111.47,171.93 111.47,171.46 113.67,169.25 128.74,169.25 136.35,161.65 136.35,149.19 143.7,141.83 143.7,128.26 132.6,117.16 119.13,117.16 116.46,119.83 v1(116.46,121.35)
HDMI0_SDA: length 158
  TOP w0.203: v1(127.38,192.4) 127.79,192.4 R2306.1 R2307.2 ; J3.232 116.35,122.22 v1(117.22,121.35)
  ART04 w0.178: v1(127.38,192.4) 127.06,192.09 124.14,192.09 115.86,183.81 111.82,183.81 111.77,183.86 102.39,183.86 101.43,182.89 97.96,182.89 97.63,183.22 97.11,183.22 96.84,182.95 96.84,179.82 102.41,174.24 106,174.24 106.88,173.37 108.16,173.37 113.04,168.49 127.52,168.49 134.97,161.04 134.97,149.33 142.88,141.43 142.88,128.73 132.07,117.92 119.86,117.92 117.22,120.55 v1(117.22,121.35)
HDMI0_TX0_C_N: length 19.4
  TOP w0.155: v1(107.02,199.63) 106.93,199.54 106.93,198.85 D2305.4 D2305.7 107.02,197.52 106.93,197.43 106.93,196.67 107.15,196.45 R212.2 107.2,196.4 R144.2 ; J2301.9 117.45,201.17 v1(117.27,200.99)
  ART04 w0.127: v1(117.27,200.99) 116.94,200.66 116.81,200.33 116.81,200.33 116.67,200.01 116.33,199.67 115.51,199.67 113.9,200.34 113.69,200.25 113.28,200.43 113.19,200.63 112.69,200.84 107.34,200.84 106.73,200.23 106.73,199.91 v1(107.02,199.63)
HDMI0_TX0_C_P: length 19.4
  TOP w0.155: v1(106.13,199.63) 106.44,199.63 106.55,199.52 106.55,198.8 D2305.5 D2305.6 106.52,197.54 106.55,197.51 106.55,196.66 R212.1 106.29,196.4 R136.2 ; J2301.7 116.45,201.05 v1(116.39,200.99)
  ART04 w0.127: v1(106.13,199.63) 106.35,199.85 106.35,200.39 107.18,201.22 112.77,201.22 115.59,200.05 116.17,200.05 116.35,200.23 116.56,200.74 116.56,200.81 v1(116.39,200.99)
HDMI0_TX0_N: length 73.2
  TOP w0.155: R144.1 107.2,194.07 v1(107.24,194.03) ; v1(113.54,131.19) 113.29,130.94 113.29,127.02 113.35,126.96 J3.220
  BOTTOM w0.155: v1(113.54,131.19) 113.31,131.43 113.31,138.13 112.75,139.47 109.75,142.47 107.01,146.58 107.01,153.43 105.23,157.72 105.23,164.31 105.08,164.68 105.08,167.57 105.72,169.1 105.72,175.55 106.58,178.26 106.58,181.38 105.92,182.04 105.92,183.74 106.58,184.4 106.58,185.91 106.17,187.48 106.17,189.81 106.35,189.98 106.35,190.3 106.17,190.47 106.17,192.18 107.04,193.04 107.04,193.82 v1(107.24,194.03)
HDMI0_TX0_P: length 73.2
  TOP w0.155: v1(112.66,131.19) 112.91,130.94 112.91,127.03 112.85,126.97 J3.218 ; R136.1 106.38,194.63 106.38,194.05 v1(106.35,194.03)
  BOTTOM w0.155: v1(106.35,194.03) 106.4,194.03 106.65,193.78 106.65,193.2 105.79,192.33 105.79,187.44 106.2,185.86 106.2,184.56 105.54,183.9 105.54,181.88 106.2,181.22 106.2,178.32 105.33,175.61 105.33,169.18 104.7,167.64 104.7,164.6 104.85,164.23 104.85,157.65 106.63,153.35 106.63,146.46 109.46,142.23 112.43,139.26 112.93,138.06 112.93,131.47 v1(112.66,131.19)
HDMI0_TX1_C_N: length 20.7
  TOP w0.155: R300.2 104.7,196.39 R211.2 104.65,196.46 104.42,196.69 104.42,196.93 103.94,197.41 103.66,197.41 103.51,197.56 103.51,197.87 D2303.10 D2303.1 103.57,199.05 103.51,199.11 103.51,199.61 104.45,200.56 110.69,200.56 111.65,199.59 114,199.59 115.88,201.47 115.88,201.85 115.95,201.93 J2301.6
HDMI0_TX1_C_P: length 20.6
  TOP w0.155: J2301.4 114.95,201.53 115.08,201.4 115.08,201.22 113.84,199.97 112.86,199.97 112.68,200.15 112.4,200.15 112.22,199.97 111.81,199.97 110.85,200.94 104.29,200.94 103.13,199.77 103.13,199.13 103.07,199.08 D2303.2 D2303.9 103.07,197.77 103.12,197.71 103.12,197.41 103.5,197.03 103.78,197.03 104.01,196.8 104.01,196.61 R211.1 103.8,196.4 R299.2
HDMI0_TX1_N: length 72.1
  TOP w0.155: R300.1 104.7,194.09 v1(104.69,194.08) ; J3.214 111.85,126.94 111.79,126.99 111.79,129.44 v1(112.04,129.69)
  BOTTOM w0.155: v1(112.04,129.69) 111.79,129.94 111.79,132.81 110.97,134.79 106.77,142.64 105.54,145.63 105.54,152.59 103.81,156.76 103.81,163.71 103.63,164.13 103.63,173.65 102.06,177.44 101.54,180.66 101.68,182.11 101.97,182.84 102.04,182.95 102.12,183.13 102.43,183.6 102.74,184.07 103.18,185.14 103.96,189.07 104.47,189.58 104.47,193.86 v1(104.69,194.08)
HDMI0_TX1_P: length 72.2
  TOP w0.155: v1(103.8,194.08) 103.8,194.08 R299.1 ; J3.212 111.35,126.55 111.41,126.62 111.41,126.83 111.41,126.84 111.41,129.44 v1(111.16,129.69)
  BOTTOM w0.155: v1(111.16,129.69) 111.41,129.94 111.41,132.73 110.63,134.62 106.43,142.48 105.16,145.55 105.16,152.51 103.43,156.69 103.43,163.63 103.25,164.05 103.25,173.57 101.69,177.33 101.16,180.65 101.31,182.2 101.63,183.01 101.7,183.12 101.78,183.31 102.4,184.25 102.81,185.25 103.61,189.26 104.09,189.74 104.09,193.79 v1(103.8,194.08)
HDMI0_TX2_C_N: length 20.2
  TOP w0.155: J2301.3 114.45,201.57 113.92,201.04 112.62,201.04 111.91,201.75 103.71,201.75 102.01,200.05 102.01,199.11 102.07,199.05 D2303.4 D2303.7 102.07,197.59 101.78,197.31 101.78,196.68 R210.2 101.94,196.05 101.93,196.03 R331.2
HDMI0_TX2_C_P: length 20.2
  TOP w0.155: J2301.1 113.45,201.73 113.45,201.73 113.45,201.55 113.32,201.42 112.78,201.42 112.62,201.57 112.62,201.73 112.73,201.84 112.73,201.95 112.59,202.09 112.48,202.09 112.41,202.02 112.18,202.02 112.07,202.13 103.55,202.13 101.62,200.21 101.62,199.13 101.57,199.08 D2303.5 D2303.6 101.57,197.63 101.4,197.46 101.4,196.79 R210.1 101.13,196 101.02,195.89 R330.2
HDMI0_TX2_N: length 72.2
  TOP w0.155: v1(110.54,131.19) 110.29,130.94 110.29,126.94 110.35,126.89 J3.208 ; R331.1 101.93,194.11 v1(101.95,194.08)
  BOTTOM w0.155: v1(110.54,131.19) 110.31,131.43 110.31,132.46 109.44,134.56 106.36,139.17 103.68,145.63 103.68,152.7 102,156.76 101.01,161.71 101.01,163.33 101.63,164.8 101.63,172.99 101.31,173.75 99.85,181.11 99.85,181.7 100.01,182.52 101.47,184.75 101.73,185.36 101.73,193.85 v1(101.95,194.08)
HDMI0_TX2_P: length 72.2
  TOP w0.155: J3.206 109.85,126.89 109.91,126.95 109.91,130.94 v1(109.66,131.19) ; v1(101.07,194.08) 101.07,194.67 R330.1
  BOTTOM w0.155: v1(109.66,131.19) 109.93,131.47 109.93,132.38 109.1,134.38 106.02,138.99 103.3,145.55 103.3,152.62 101.63,156.65 100.63,161.67 100.63,163.41 101.24,164.88 101.24,172.92 100.94,173.64 99.47,181.07 99.47,181.74 99.55,182.18 99.65,182.67 101.13,184.92 101.35,185.44 101.35,193.8 v1(101.07,194.08)
HDMI0_TX_5V: length 20
  TOP w0.254: C2301.1 122.33,201.52 121.95,201.9 J2301.18 ; 129.03,194.18 R2307.1 ; 129.03,194.18 U13.5 ; 129.03,194.18 R2317.1
  TOP w0.305: U13.5 125.98,194.18 125.6,194.56 125.6,195.4 125.17,195.83 123.7,195.83 122.94,196.6 R2308.2 122.33,197.08 v1(121.92,197.48) ; D2307.3 124.64,197.48 v1(123.7,197.48) 123.7,197.51 C2301.1
  BOTTOM w0.305: v1(121.92,197.48) v1(123.7,197.48)
HDMI0_TX_CEC: length 14.3
  TOP w0.203: R2302.2 122.81,192.53 v1(123.06,192.79) 123.51,193.23 U13.3 ; J2301.13 119.45,201.35 120.27,200.53 120.27,198.18 v1(120.97,197.48)
  ART04 w0.178: v1(120.97,197.48) 120.97,194.88 v1(123.06,192.79)
HDMI0_TX_DDC_SCL_C: length 14.1
  TOP w0.203: J2301.15 120.45,201 120.83,200.62 120.83,198.58 121.29,198.12 122.3,198.12 123.95,196.47 125.6,196.47 126.11,195.96 126.11,195.45 126.43,195.13 U13.6 127.45,195.13 127.66,194.92 R2305.2
HDMI0_TX_DDC_SDA_C: length 16.2
  TOP w0.203: R2306.2 127.79,193.57 127.45,193.23 U13.4 126.43,193.23 125.86,192.66 v1(125.22,192.66) ; v1(121.6,200.47) 120.95,201.12 J2301.16
  ART04 w0.178: v1(121.6,200.47) 122.43,199.64 122.43,194.69 124.46,192.66 v1(125.22,192.66)
HDMI0_TX_HPD_C: length 12.4
  TOP w0.203: U13.1 123.86,195.13 123.55,194.82 v1(123.06,194.82) 123.06,193.8 122.81,193.55 R2309.1 ; v1(122.94,201.42) 122.94,201.68 122.45,202.16 J2301.19
  ART04 w0.203: v1(123.06,194.82) 123.57,195.33 123.57,196.34 122.94,196.98 v1(122.94,201.42)
HDMI0_TXC_C_N: length 23.2
  TOP w0.155: v1(118.89,199.74) 118.62,200.02 118.62,201.22 118.95,201.55 J2301.12 ; v1(110.14,198.21) 109.89,198.47 109.58,198.47 108.84,199.21 108.62,199.21 108.52,199.11 D2305.1 D2305.10 108.52,197.46 108.46,197.4 108.46,196.68 108.89,196.25 108.89,193.69 108.59,193.39 108.59,193.31 R213.2 108.8,193.08 R393.2
  ART04 w0.127: v1(110.14,198.21) 110.4,198.47 114.38,198.47 115.03,198.2 117.65,198.2 118.64,199.18 118.64,199.49 v1(118.89,199.74)
HDMI0_TXC_C_P: length 23.2
  TOP w0.155: v1(118.01,199.74) 118.24,199.97 118.24,201.22 117.95,201.51 J2301.10 ; R392.2 107.89,192.99 R213.1 108.2,193.31 108.2,193.55 108.51,193.85 108.51,196.09 108.08,196.52 108.08,197.43 108.02,197.49 D2305.9 D2305.2 108.02,199.08 108.07,199.2 108.46,199.59 108.99,199.59 109.74,198.85 109.89,198.85 v1(110.14,199.1)
  ART04 w0.127: v1(110.14,199.1) 110.4,198.85 114.45,198.85 114.85,198.68 115.11,198.58 117.5,198.58 118.26,199.34 118.26,199.49 v1(118.01,199.74)
HDMI0_TXC_N: length 69.5
  TOP w0.155: J3.226 114.85,129.49 v1(115.04,129.69) ; v1(108.84,190.56) 108.8,190.6 R393.1
  BOTTOM w0.155: v1(108.84,190.56) 108.59,190.3 108.59,189.6 108.23,188.74 108.23,186.47 108.43,186.26 108.43,186 108.23,185.8 108.23,170.58 107.52,168.86 107.52,162.75 107.67,162.59 107.81,162.59 108.23,162.18 108.23,161.59 107.81,161.17 107.67,161.17 107.52,161.01 107.52,157.31 108.69,154.48 108.69,148.07 110.17,144.49 114.25,140.41 115.19,139 115.19,136.94 114.81,136.02 114.81,129.92 v1(115.04,129.69)
HDMI0_TXC_P: length 69.4
  TOP w0.155: J3.224 114.35,126.95 114.47,127.07 114.47,129.38 v1(114.16,129.69) ; v1(107.95,190.56) 107.95,191.18 R392.1
  BOTTOM w0.155: v1(114.16,129.69) 114.43,129.96 114.43,136.1 114.81,137.01 114.81,138.89 113.95,140.17 109.84,144.28 108.31,147.99 108.31,154.41 107.14,157.23 107.14,161.17 107.52,161.55 107.65,161.55 107.85,161.74 107.85,162.02 107.65,162.21 107.52,162.21 107.14,162.59 107.14,168.94 107.85,170.65 107.85,188.81 108.2,189.67 108.2,190.3 v1(107.95,190.56)
HDMI1_CEC: length 120.4
  TOP w0.203: v1(97.31,182.75) 97.31,183.11 96.39,184.02 R2401.2 R2402.1 ; v1(117.04,119.91) 117.04,119.77 117.1,119.71 J3.235
  ART04 w0.178: v1(97.31,182.75) 97.54,182.75 101.35,178.94 104.48,178.94 107.67,175.75 107.67,175.19 111.09,171.77 111.09,171.3 113.52,168.87 128.58,168.87 135.35,162.11 135.35,149.56 143.31,141.6 143.31,128.62 132.22,117.54 119.42,117.54 v1(117.04,119.91)
HDMI1_HOTPLUG: length 129.6
  TOP w0.203: v1(97.33,185.86) 96.77,185.86 96.37,186.26 R2407.2 R2408.2 C2402.1 R2406.1 ; v1(115.7,119.91) 116.21,119.91 116.6,119.52 J3.233
  ART03 w0.178: v1(97.33,185.86) 97.75,185.86 100.41,183.2 v1(100.41,181.65)
  ART04 w0.178: v1(115.7,119.91) 118.83,116.78 132.76,116.78 144.09,128.11 144.09,142.17 136.73,149.53 136.73,161.81 128.9,169.63 114.69,169.63 108.46,175.86 108.46,177.53 105.93,180.06 102,180.06 v1(100.41,181.65)
HDMI1_SCL: length 121.6
  TOP w0.203: v1(104.18,186.14) 104.18,186.58 104.15,186.6 104.15,186.61 103.95,186.82 R2417.2 R2403.1 ; v1(65.25,119.94) 65.1,119.78 J3.27
  ART03 w0.178: v1(90.17,147.07) 89.55,146.44 84.91,146.44 84.81,146.34 79.66,146.34 78.96,147.04 78.57,147.04 77.9,146.37 75.15,146.37 73.84,145.06 70.04,145.06 67.29,142.31 67.29,141.1 57.9,131.7 57.9,124.26 58.07,124.08 v1(58.42,124.08)
  ART04 w0.178: v1(97.79,172.97) 97.79,175.39 95.31,177.86 95.31,183.58 96.98,185.24 99.39,185.24 99.72,185.57 101.45,185.57 101.83,185.95 103.99,185.95 v1(104.18,186.14) ; v1(58.42,124.08) 58.92,123.58 61.61,123.58 v1(65.25,119.94)
  BOTTOM w0.203: v1(97.79,172.97) 98.35,172.97 99.45,171.87 99.45,145.62 98.16,144.32 95.67,144.32 93.46,146.53 90.7,146.53 v1(90.17,147.07)
HDMI1_SDA: length 118.7
  TOP w0.203: v1(65.66,120.65) 65.79,120.53 65.79,119.8 65.6,119.61 J3.29 ; R2405.2 R2404.1 103.84,184.78 v1(104.32,185.27)
  ART03 w0.178: v1(59.18,124.08) 59.18,124.21 58.67,124.71 58.4,124.71 58.28,124.84 58.28,131.54 67.67,140.94 67.67,142.15 70.2,144.68 74,144.68 75.28,145.96 84.97,145.96 85.07,146.06 89.93,146.06 v1(90.93,147.07)
  ART04 w0.178: v1(59.18,124.08) 59.31,123.95 61.85,123.95 65.15,120.65 v1(65.66,120.65) ; v1(104.32,185.27) 102.18,185.27 101.23,184.31 99.28,184.31 99,184.59 96.87,184.59 95.69,183.42 95.69,178.14 98.3,175.54 v1(98.3,172.34)
  BOTTOM w0.203: v1(98.3,172.34) 99.05,171.59 99.05,145.79 97.99,144.73 95.83,144.73 93.5,147.07 v1(90.93,147.07)
HDMI1_TX0_C_N: length 8.8
  TOP w0.155: J2401.9 93.25,201.45 92.99,201.19 92.99,200.51 93.05,200.45 D2405.4 D2405.7 93.05,199.22 92.99,199.16 92.99,198.53 93.48,198.04 94.34,198.04 94.87,197.52 94.87,197.28 R215.2 95.13,197.02 R395.2
HDMI1_TX0_C_P: length 8.8
  TOP w0.155: R394.2 94.23,196.95 R215.1 94.49,197.21 94.49,197.36 94.18,197.66 93.32,197.66 92.61,198.37 92.61,199.14 92.55,199.2 D2405.6 D2405.5 92.55,200.45 92.61,200.51 92.61,201.09 92.25,201.45 J2401.7
HDMI1_TX0_N: length 106.7
  TOP w0.155: v1(95.17,194.59) 95.13,194.63 R395.1 ; v1(68.33,110.87) 68.05,111.15 68.05,112.08 67.71,112.89 66.12,114.48 63.42,115.6 62.54,116.48 62.54,117.28 62.6,117.34 J3.17
  BOTTOM w0.155: v1(68.33,110.87) 68.07,111.12 68.07,114.13 66.98,116.77 66.98,118.06 66.52,120.27 66.52,120.78 63.91,127.09 63.91,129.74 64.07,131.23 64.58,132.33 76.4,147.09 77.93,149.2 77.94,149.21 79.25,150.52 79.72,150.72 80.28,150.83 80.72,151.12 81.59,153.2 81.59,153.21 82.21,154.58 89.96,162.33 91.57,166.22 91.57,167.05 93.9,172.69 94.45,173.24 94.72,173.89 94.72,191.69 94.82,191.8 94.82,192.29 94.72,192.39 94.72,192.76 95,193.43 95,194.41 v1(95.17,194.59)
HDMI1_TX0_P: length 106.7
  TOP w0.155: v1(67.44,110.87) 67.67,111.1 67.67,112 67.39,112.67 65.9,114.16 63.2,115.28 62.16,116.32 62.16,117.29 62.1,117.35 J3.15 ; v1(94.29,194.59) 94.29,195.27 R394.1
  BOTTOM w0.155: v1(67.44,110.87) 67.69,111.12 67.69,114.05 66.6,116.69 66.6,118.02 66.14,120.23 66.14,120.7 63.53,127.02 63.53,129.76 63.7,131.33 63.73,131.39 64.25,132.53 76.1,147.32 77.6,149.39 77.62,149.43 79.03,150.84 79.61,151.08 80.13,151.19 80.42,151.38 81.2,153.28 81.2,153.3 81.9,154.8 89.63,162.54 91.19,166.29 91.19,167.13 93.58,172.91 94.12,173.45 94.34,173.97 94.34,192.83 94.62,193.51 94.62,194.26 v1(94.29,194.59)
HDMI1_TX1_C_N: length 8.1
  TOP w0.155: R397.2 92.05,196.42 92.05,197.54 R214.2 92.05,197.94 92.05,198.32 91.24,199.14 91.24,199.37 D2403.10 D2403.1 91.3,201.13 91.75,201.58 J2401.6
HDMI1_TX1_C_P: length 8
  TOP w0.155: R396.2 91.67,196.38 91.67,197.51 R214.1 91.44,197.75 91.67,197.98 91.67,198.16 90.86,198.98 90.86,199.37 D2403.9 D2403.2 90.8,200.57 90.92,200.69 90.92,201.26 90.75,201.42 J2401.4
HDMI1_TX1_N: length 107.6
  TOP w0.155: v1(92.51,194.61) 92.33,194.79 R397.1 ; J3.11 61.1,117.36 61.04,117.3 61.04,116.45 61.3,115.81 61.97,115.15 64.01,114.3 64.64,113.67 64.64,113.28 v1(64.9,113.03)
  BOTTOM w0.155: v1(92.51,194.61) 92.3,194.4 92.3,192.62 92.48,192.44 92.48,192.16 92.3,191.98 92.3,191.63 92.08,191.08 92.08,172.1 89.9,166.86 89.01,164.16 79.68,154.84 77.62,151.88 70.1,144.36 70.1,141.55 68.94,140.39 64.04,140.39 62.51,138.86 62.51,137.91 62.78,137.64 64.01,137.64 64.39,137.26 64.39,136.32 64.01,135.95 62.78,135.95 62.51,135.67 62.51,125.43 64.08,122.69 64.08,116.56 64.64,115.21 64.64,113.28 v1(64.9,113.03)
HDMI1_TX1_P: length 107.7
  TOP w0.155: v1(91.63,194.61) 91.63,195.13 R396.1 ; v1(64.01,113.03) 64.26,113.28 64.26,113.51 63.8,113.98 61.75,114.82 60.98,115.59 60.66,116.37 60.66,117.27 60.6,117.33 J3.9
  BOTTOM w0.155: v1(91.63,194.61) 91.92,194.32 91.92,191.7 91.69,191.15 91.69,172.17 89.55,166.99 88.67,164.36 79.39,155.08 77.32,152.12 69.72,144.52 69.72,141.71 68.78,140.77 63.88,140.77 62.13,139.01 62.13,137.75 62.62,137.26 63.85,137.26 64.01,137.1 64.01,136.48 63.85,136.33 62.62,136.33 62.13,135.83 62.13,125.32 63.7,122.59 63.7,116.48 64.26,115.13 64.26,114.67 64.01,114.42 64.01,113.95 64.26,113.7 64.26,113.28 v1(64.01,113.03)
HDMI1_TX2_C_N: length 7.9
  TOP w0.155: R399.2 89.79,196.42 89.79,196.98 89.6,197.17 89.6,197.42 89.82,197.64 R217.2 89.6,197.95 89.6,198.63 89.71,198.91 89.71,199.35 D2403.7 D2403.4 89.8,201.12 90.25,201.57 J2401.3
HDMI1_TX2_C_P: length 7.8
  TOP w0.155: J2401.1 89.25,201.43 89.42,201.26 89.42,200.69 89.3,200.57 D2403.5 D2403.6 89.33,199.4 89.33,198.98 89.22,198.71 89.22,197.95 R217.1 89,197.64 89.22,197.42 89.22,197.01 89.41,196.82 89.41,196.38 R398.2
HDMI1_TX2_N: length 107.9
  TOP w0.155: v1(64.64,110.87) 64.39,111.12 64.39,111.51 64.01,111.89 63.39,111.89 63.06,112.02 60.37,114.71 59.54,116.73 59.54,117.07 59.6,117.13 J3.5 ; v1(90.01,194.61) 90.07,194.68 R399.1
  BOTTOM w0.155: v1(64.64,110.87) 64.52,110.87 64.26,111.12 64.26,111.5 63.88,111.88 63.31,111.88 62.97,112.22 62.97,115.21 62.77,116.25 62.45,116.99 62.45,122.03 61.01,125.51 61.01,129.16 60.96,139.32 62.59,141.95 62.59,142.4 62.94,143.16 69.74,147.81 71.87,149.54 76.98,154.84 85.57,163.43 88.1,166.62 88.56,167.35 90.04,170.95 90.04,193.58 89.76,193.86 89.76,194.37 v1(90.01,194.61)
HDMI1_TX2_P: length 108
  TOP w0.155: v1(63.76,110.87) 63.99,111.11 63.99,111.36 63.85,111.51 63.31,111.51 62.84,111.7 60.05,114.49 59.16,116.65 59.16,117.07 59.1,117.12 J3.3 ; v1(89.12,194.61) 89.16,194.66 R398.1
  BOTTOM w0.155: v1(89.12,194.61) 89.38,194.35 89.38,193.7 89.66,193.42 89.66,171.02 88.22,167.53 87.79,166.84 85.29,163.68 76.71,155.11 71.61,149.82 69.52,148.12 62.63,143.42 62.2,142.48 62.2,142.06 60.58,139.43 60.63,129.16 60.63,125.43 62.07,121.96 62.07,121.57 61.87,121.38 61.87,121.01 62.07,120.81 62.07,119.24 61.85,119.02 61.85,118.78 62.07,118.56 62.07,116.91 62.4,116.13 62.59,115.17 62.59,112.06 63.15,111.5 63.73,111.5 63.88,111.34 63.88,111 v1(63.76,110.87)
HDMI1_TX_3V3: length 30.3
  TOP w0.203: D2408.3 106.93,188.39 105.85,187.31 C2403.1 105.37,185.23 104.27,184.12 R2401.1
  TOP w0.254: R2301.1 C2303.1
  TOP w0.305: D2408.3 108.71,188.39 108.74,188.37 110.69,188.37 112.07,189.74 122.02,189.74 122.33,190.04 C2303.1
HDMI1_TX_5V: length 27.7
  TOP w0.203: R2405.1 R2417.1 102.11,186.82 101.98,186.69 U14.5 100.33,186.69 99.7,187.32 99.7,189.02 98.9,189.81 97.23,189.81 R2406.2
  TOP w0.254: J2401.18 97.75,201.71 98.3,201.17 98.3,199.77 97.92,199.39 C2401.1 97.43,199.14 99.47,197.1 99.47,194.23 99.95,193.75 99.95,192.4 99.57,192.02 D2407.3
  TOP w0.305: R2406.2 97.18,190.52 96.52,191.19 D2407.3
HDMI1_TX_CEC: length 25
  TOP w0.203: R2402.2 97.73,185.14 98.33,185.74 U14.3 98.87,185.74 99.7,184.91 v1(99.7,184.78) ; J2401.13 95.25,201.85 v1(96.7,200.41)
  ART03 w0.178: v1(96.7,200.41) 96.7,199.29 99.07,196.91 99.07,194.39 98.93,194.25 98.93,191.13 97.41,189.61 97.41,187.07 v1(99.7,184.78)
HDMI1_TX_DDC_SCL_C: length 23
  TOP w0.203: v1(96.77,201.29) 96.25,201.82 J2401.15 ; v1(102.64,188.62) 102.59,188.57 R2403.2 102.11,187.83 101.92,187.64 U14.6
  ART03 w0.178: v1(102.64,188.62) 101.63,188.62 100.08,190.17 100.08,193.78 100.22,193.92 100.22,197.47 99.19,198.5 99.19,201.8 98.81,202.18 97.66,202.18 v1(96.77,201.29)
HDMI1_TX_DDC_SDA_C: length 23.2
  TOP w0.203: v1(97.66,200.41) 97.66,201.09 96.75,202 J2401.16 ; R2404.2 102.24,184.78 101.28,185.74 U14.4 100.78,185.74 100.46,185.42 100.46,185.08 v1(100.56,184.98)
  ART03 w0.178: v1(97.66,200.41) 97.66,199.42 99.83,197.25 99.83,194.08 99.7,193.94 99.7,188.21 100.56,187.35 v1(100.56,184.98)
HDMI1_TX_HPD_C: length 19.8
  TOP w0.203: J2401.19 98.25,201.98 v1(98.55,201.68) ; v1(98.81,189.23) 98.86,189.18 98.86,187.84 98.65,187.64 U14.1 98,187.64 R2407.1
  ART03 w0.178: v1(98.55,201.68) 98.17,201.68 97.18,200.68 97.18,199.36 99.45,197.09 99.45,194.24 99.31,194.1 99.31,189.74 v1(98.81,189.23)
HDMI1_TXC_C_N: length 9.8
  TOP w0.155: J2401.12 94.75,201.46 94.49,201.19 94.49,200.53 94.55,200.47 D2405.1 D2405.10 94.55,199.22 94.49,199.16 94.49,198.91 94.65,198.75 96.48,198.75 97.46,197.77 97.46,197.29 R216.2 97.7,197.01 R401.2
HDMI1_TXC_C_P: length 9.9
  TOP w0.155: R400.2 96.8,196.92 R216.1 97.08,197.2 97.08,197.61 96.32,198.37 94.49,198.37 94.11,198.75 94.11,199.16 94.05,199.22 D2405.9 D2405.2 94.05,200.47 94.11,200.53 94.11,201.17 93.75,201.52 J2401.10
HDMI1_TXC_N: length 105.5
  TOP w0.155: J3.23 64.1,117.31 64.04,117.25 64.04,116.58 64.52,116.1 66.39,116.1 69.23,114.92 70.1,114.05 70.1,113.28 v1(70.36,113.03) ; v1(97.76,194.61) 97.76,195.27 R401.1
  BOTTOM w0.155: v1(97.76,194.61) 97.51,194.37 97.51,191.29 96.53,190.3 96.53,174.35 94.49,169.41 94.49,168.67 94.08,167.69 93.79,166.21 91.61,160.94 85.98,155.32 84.63,152.06 83.04,150.48 79.88,148.43 77.57,146.13 70.15,136.63 66.46,132.38 65.47,130.61 65.46,130.6 65.33,129.59 65.33,126.62 65.64,125.87 67.47,123.13 67.99,122.61 68.22,122.61 68.55,122.28 68.55,122.05 68.88,121.72 69.11,121.72 69.44,121.39 69.44,121.16 70.13,120.47 70.13,113.26 v1(70.36,113.03)
HDMI1_TXC_P: length 105.5
  TOP w0.155: v1(69.47,113.03) 69.72,113.28 69.72,113.89 69.01,114.6 67.85,115.08 67.52,114.95 67.15,115.1 67.02,115.43 66.31,115.72 64.36,115.72 63.66,116.43 63.66,117.24 63.6,117.3 J3.21 ; v1(96.87,194.61) 96.8,194.68 R400.1
  BOTTOM w0.155: v1(96.87,194.61) 97.13,194.35 97.13,191.44 96.15,190.46 96.15,174.42 94.11,169.49 94.11,168.75 93.72,167.8 93.42,166.32 91.28,161.16 85.66,155.53 84.3,152.28 82.8,150.78 79.64,148.73 77.29,146.39 69.86,136.87 66.15,132.6 65.13,130.79 65.12,130.77 65.09,130.71 64.95,129.62 64.95,126.54 65.3,125.69 67.18,122.89 69.75,120.31 69.75,113.31 v1(69.47,113.03)
HEALTHY_LED_MCU_G: length 218.4
  TOP w0.203: v1(53.47,24.89) 51.05,24.89 50.39,24.23 R3606.1 49.5,23.75 R3603.1 ; R2836.2 v1(206.15,57.66)
  ART03 w0.178: v1(206.15,57.66) 206.71,57.1 207.23,57.1 209.25,55.08 209.25,51.74 212.99,47.99 212.99,40.19 217.17,36.01 217.17,31.66 209.75,24.24 192.93,24.24 191.94,25.23 188.78,25.23 187.11,23.56 177.64,23.56 175.84,25.36 175.45,25.36 174.98,24.89 174.62,24.89 173.48,23.75 173.48,23.11 172.8,22.43 172.24,22.43 170.7,20.89 168.96,20.89 166.08,18.01 165.54,18.01 162.39,14.86 152.65,14.86 148.17,10.38 80.76,10.38 80.29,10.85 71.66,10.85 64.85,17.65 59.49,17.65 53.47,23.67 v1(53.47,24.89)
HEALTHY_LED_MCU_R: length 216.1
  TOP w0.203: R3604.2 53.59,23.65 R3605.1 53.7,24.23 v1(54.36,24.89) ; R2834.2 v1(202.06,57.66)
  ART03 w0.178: v1(54.36,24.89) 55.7,24.89 56.64,23.95 56.64,22.48 60.33,18.8 64.87,18.8 71.94,11.72 80.49,11.72 81.07,11.14 147.17,11.14 152.89,16.85 160.88,16.85 164.9,20.87 165.16,20.87 166.9,22.61 169.64,22.61 174.38,27.34 175.6,27.34 175.6,27.34 192.88,27.34 195.21,25.01 205.35,25.01 207.01,26.67 211.1,26.67 216.41,31.97 216.41,35.7 212.23,39.87 212.23,44.69 211.33,45.59 211.33,48.21 208.36,51.18 208.36,54.89 206.91,56.34 205.66,56.34 204.88,57.12 202.59,57.12 v1(202.06,57.66)
HOT_RST_FAULT: length 164.9
  TOP w0.203: R360.2 155.39,51.36 v1(155.45,51.36) 157.51,51.36 157.72,51.57 R361.1 157.74,51.9 R157.1 ; J3.295 51.6,119.67 v1(51.94,120.01)
  ART03 w0.178: v1(51.94,120.01) 52.58,119.38 53.54,119.38 56.77,116.15 56.77,113.03 60.3,109.5 80.39,109.5 83.26,112.37 86.08,112.37 88.9,115.19 90.42,115.19 91.31,116.08 91.31,116.56 92.21,117.46 93.4,117.46 94.01,116.85 94.01,115.93 98.07,111.86 98.07,109.15 103.07,104.15 104.36,102.22 104.36,100.42 103.54,99.61 103.54,81.88 124.21,61.21 130.86,61.21 132.28,59.79 135.64,59.79 136.3,59.13 140.86,59.13 143.31,56.68 153.78,56.68 155.45,55.01 v1(155.45,51.36)
HOT_RST_FAULT_R: length 39
  TOP w0.203: R161.2 167.61,51.79 167.61,51.8 R354.2 168.1,52.07 168.35,52.32 169.27,52.32 169.27,52.32 170.08,52.32 170.31,52.09 ; v1(170.26,52.09) 170.31,52.09 ; 170.31,52.09 170.38,52.09 R355.2 ; v1(197.49,37.85) 198.15,37.85 R2838.2
  ART03 w0.178: v1(197.49,37.85) 196.47,38.86 194.56,38.86 193.57,39.85 189.26,39.85 187.83,41.27 185.67,41.27 184.63,42.32 182.8,42.32 173.3,51.82 170.54,51.82 v1(170.26,52.09)
HUB_1V2_SWR: length 8.7
  TOP w0.203: v1(119.7,45.53) 120.13,45.09 120.13,45.06 120.28,44.92 120.31,44.92 120.36,44.87 U2101.52
  ART04 w0.305: v1(123.1,39.54) 120.52,42.11 120.52,44.7 v1(119.7,45.53)
HUB_PWR_EN: length 54.4
  TOP w0.203: v1(178.44,38.73) 179.01,39.31 R2850.1 ; 153.14,67.18 153.06,67.11 R3103.1 ; 153.14,67.18 R127.2 153.14,68 v1(152.83,68.3) ; 153.14,67.18 R3102.2
  ART03 w0.178: v1(178.44,38.73) 178.52,38.82 178.52,39.64 175.96,42.2 174.11,42.2 171.1,45.21 168.37,45.21 165.81,47.77 165.81,50.14 164.59,51.36 164.59,64.15 158.3,70.45 154.17,70.45 152.83,69.11 v1(152.83,68.3)
I2C0_MCU_SCL: length 286
  TOP w0.203: R2869.2 v1(191.77,44.83) 191.08,44.83 R28.2 ; v1(9.25,136.42) R3017.1
  ART03 w0.178: v1(191.77,44.83) 191.35,44.83 190.37,45.81 190.37,46.92 185.91,51.39 183.37,51.39 182.08,52.67 182.08,54.8 182.13,54.85 182.13,58.75 174.26,66.63 174.26,69.48 172.46,71.28 172.46,82.24 173.29,83.07 173.29,85.19 172.97,85.5 172.97,86.81 170.03,89.75 170.03,97.94 154.66,113.31 149.12,113.31 142.36,120.07 142.36,141.52 140.18,143.7 130,143.7 127.24,146.46 127.24,149.22 124.7,151.76 114.41,151.76 112.41,153.76 98.84,153.76 94.14,149.06 80.98,149.06 80.65,148.72 74.55,148.72 74.27,148.44 60.33,148.44 57.56,151.21 54.13,151.21 v1(53.52,151.82)
  ART04 w0.178: v1(22.4,135.89) 21.88,135.37 20.84,135.37 18.92,137.29 18.92,139.67 16.5,142.09 14.74,142.09 13.21,140.56 13.21,139.41 12.45,138.65 12.45,137.16 11.71,136.42 v1(9.25,136.42) ; v1(53.52,151.82) 52.96,151.26 51,151.26 49.33,152.93 45.19,152.93 44.28,152.02 41.91,152.02 39.62,149.73 39.62,147.78 35.56,143.71 v1(34.04,143.71)
  BOTTOM w0.203: v1(34.04,143.71) 31.82,143.71 26.41,138.3 25.12,138.3 22.7,135.89 v1(22.4,135.89)
I2C0_MCU_SDA: length 281.5
  TOP w0.203: R27.2 v1(191.77,43.81) R2870.2 ; v1(9.25,137.41) 9.22,137.44 R3016.1
  ART03 w0.178: v1(52.71,151.84) 53.77,150.77 57.42,150.77 61.32,146.87 77.32,146.87 77.89,147.45 81.59,147.45 81.92,147.78 82.63,147.78 82.79,147.61 84.21,147.61 84.68,148.08 93.7,148.08 99,153.38 110.78,153.38 112.78,151.38 124.54,151.38 126.85,149.07 126.85,146.31 131.04,142.13 131.33,142.13 141.54,131.92 141.54,120.35 148.96,112.93 154.5,112.93 169.65,97.78 169.65,89.59 172.59,86.65 172.59,85.35 172.91,85.03 172.91,83.6 172.08,82.76 172.08,71.05 173.88,69.25 173.88,65.77 181.08,58.57 181.08,54.95 181.65,54.37 181.65,53.98 181,53.34 181,52.48 182.48,51 183.21,51 183.83,50.38 183.83,50.33 185.77,48.39 188.37,48.39 189.99,46.77 189.99,45.59 v1(191.77,43.81)
  ART04 w0.178: v1(22.4,136.65) 21.9,137.16 21.46,137.16 21.21,136.91 19.94,136.91 19.3,137.54 19.3,139.83 16.66,142.47 14.58,142.47 12.83,140.72 12.83,139.57 12.07,138.81 12.07,137.79 11.68,137.41 v1(9.25,137.41) ; v1(34.04,144.78) 36.09,144.78 39.12,147.81 39.12,149.99 41.53,152.4 44.12,152.4 45.03,153.31 49.5,153.31 50.98,151.84 v1(52.71,151.84)
  BOTTOM w0.203: v1(22.4,136.65) 22.89,136.65 24.95,138.71 26.24,138.71 32.31,144.78 v1(34.04,144.78)
I2C3_MCU_SCL: length 310.8
  TOP w0.127: R2874.1 187.93,42.44 188.09,42.29 188.6,42.29 188.75,42.14 R37.1 189.38,41.78 v1(189.46,41.86)
  TOP w0.203: v1(134.06,28.75) 134.06,28.32 133.72,27.98 R2883.1 ; v1(22.99,94.87) 23.04,94.92 R2885.1 ; v1(11.81,43.31) 11.81,42.67 9.91,40.77 9.91,34.54 9.25,33.89 v1(8.38,33.89) R2882.1
  ART03 w0.178: 20.12,80.31 20.88,81.08 20.88,92.76 v1(22.99,94.87)
  ART03 w0.203: v1(11.81,43.31) 11.94,43.31 18.19,49.56 18.19,56.34 21.37,59.52 21.37,72.58 20.12,73.83 20.12,80.31
  ART04 w0.178: v1(189.46,41.86) 189.99,41.33 189.99,40.13 189.36,39.5 188.21,39.5 187.83,39.12 187.83,34.29 187.08,33.53 185.57,33.53 177.56,25.53 176.78,25.53 176.53,25.78 176.53,26.01 v1(176.28,26.26) ; v1(165.74,18.84) 162.08,15.19 152.58,15.19 151,16.76 143.89,16.76 139.17,12.04 124.99,12.04 v1(122.81,14.22) 121.39,12.8 73.44,12.8 69.6,16.64 25.4,16.64 17.78,24.26 17.78,28.29 13.47,32.6 8.85,32.6 8.38,33.07 v1(8.38,33.89)
  BOTTOM w0.203: v1(134.06,28.75) 132.69,27.38 131.75,27.38 130.66,26.29 130.66,19.94 129.97,19.25 127.25,19.25 122.81,14.81 v1(122.81,14.22) ; v1(165.74,18.84) 169.53,18.84 170.9,20.22 173.31,20.22 174.02,20.92 174.02,21.05 176.15,23.19 176.15,26.13 v1(176.28,26.26)
I2C3_MCU_SDA: length 307.9
  TOP w0.203: R2884.1 v1(132.18,26.67) ; v1(11.94,41.91) 10.31,40.28 10.31,34.19 9.35,33.23 v1(8.89,33.23) 5.33,33.23 4.98,33.59 4.98,33.74 R2881.1 ; R38.1 189.23,39.75 189.46,39.98 v1(189.46,40.33) 189.76,40.64 R2873.1 ; R2886.1 23.09,95.86 v1(22.99,95.76)
  ART03 w0.178: v1(11.94,41.91) 18.78,48.75 18.78,56.03 21.77,59.02 21.77,72.87 20.51,74.13 20.51,80.07 21.39,80.95 21.39,92.38 23.56,94.55 23.56,95.19 v1(22.99,95.76)
  ART04 w0.178: v1(189.46,40.33) 189.04,39.91 188,39.91 187.45,39.37 187.45,34.54 186.86,33.95 185.44,33.95 177.53,26.03 v1(177.04,26.03) ; v1(8.89,33.23) 13.38,33.23 18.16,28.45 18.16,24.51 25.6,17.07 69.71,17.07 73.59,13.18 120.98,13.18 122.53,14.73 123.44,14.73 v1(123.95,14.22) 125.73,12.45 138.79,12.45 143.49,17.14 151.51,17.14 153.09,15.57 161.37,15.57 v1(165,19.19)
  BOTTOM w0.203: v1(165,19.19) 165,18.77 165.41,18.36 169.62,18.36 171.07,19.81 174.18,19.81 174.98,20.61 174.98,21.18 176.68,22.88 176.68,25.68 v1(177.04,26.03) ; v1(123.95,14.22) 125.5,15.77 129.72,15.77 132.18,18.24 v1(132.18,26.67)
I2C4_MCU_SCL: length 11
  TOP w0.203: R120.1 R35.2 v1(189.48,46.43) ; v1(183.13,50.42) 183.64,49.91 R1029.2
  ART03 w0.178: v1(183.13,50.42) 183.13,50.16 185.39,47.91 188.31,47.91 189.48,46.74 v1(189.48,46.43)
I2C4_MCU_SDA: length 14.9
  TOP w0.203: v1(181.08,41.6) 182.55,41.6 183.36,40.79 R36.2 R123.1 ; v1(172.97,46.23) 172.94,46.26 R1028.2
  ART03 w0.178: v1(172.97,46.23) 173.91,45.29 177.39,45.29 v1(181.08,41.6)
I2C6_SCL: length 224.3
  TOP w0.203: J3.6 59.85,127.27 59.31,127.81 v1(59.31,129.54) ; R2871.2 v1(191.77,42.8) R98.1
  ART03 w0.178: v1(59.31,129.54) 60.3,130.53 60.3,132.48 69.67,141.85 69.67,142.85 71.12,144.3 74.15,144.3 74.88,145.02 89.75,145.02 90.94,146.21 92.92,146.21 99.7,153 110.58,153 112.72,150.86 124.52,150.86 126.39,148.99 126.39,145.38 131.31,140.46 132.46,140.46 141.16,131.76 141.16,120.2 148.81,112.55 154.34,112.55 169.27,97.62 169.27,87.9 171.91,85.25 171.91,83.6 171.55,83.24 171.55,71.03 173.49,69.09 173.49,65.14 179.59,59.04 179.59,53.13 188.84,43.88 188.84,43.8 189.33,43.31 191.26,43.31 v1(191.77,42.8)
I2C6_SDA: length 224.4
  TOP w0.127: v1(189.46,41.1) 190.14,41.78 R2868.2
  TOP w0.203: v1(58.81,127.63) 59.35,127.1 J3.4 ; v1(189.46,41.1) 189.13,40.77 R99.1
  ART03 w0.178: v1(58.81,127.63) 58.81,128.36 60.68,130.23 60.68,132.32 70.05,141.69 70.05,142.67 71.3,143.92 74.31,143.92 75.04,144.64 89.91,144.64 91.1,145.83 93.07,145.83 99.86,152.62 109.51,152.62 111.65,150.48 124.36,150.48 126.01,148.83 126.01,145.22 131.16,140.08 132.3,140.08 140.78,131.61 140.78,120.04 148.65,112.17 154.18,112.17 168.88,97.46 168.88,86.6 170.95,84.54 170.95,80.79 171.06,80.68 171.06,70.99 173.11,68.93 173.11,64.5 178.65,58.97 178.65,54.85 179.14,54.36 179.14,53.04 188.46,43.72 188.46,42.1 v1(189.46,41.1)
I2C7_MCU_SCL: length 332.4
  TOP w0.203: v1(187.17,54.1) 187.26,54.01 R271.1 ; R304.1 v1(5.99,120.57) R320.2 R321.1
  ART03 w0.178: v1(23.24,120.14) 23.37,120.27 23.37,122.08 30.3,129.01 30.3,148.04 38.76,156.5 51.72,156.5 55.27,160.06 93.59,160.06 98.1,164.57 109.99,164.57 110.99,165.57 141.36,165.57 141.88,165.05 143.42,165.05 146.18,162.29 156.67,162.29 170.17,148.79 189.66,148.79 v1(191.14,147.32)
  ART04 w0.178: v1(23.24,120.14) 22.73,120.14 21.3,121.58 15.33,121.58 11.3,125.61 9.39,125.61 7.62,123.84 7.62,122.2 v1(5.99,120.57)
  BOTTOM w0.203: v1(187.17,54.1) 187.17,57.51 192.28,62.61 192.28,64.61 193,65.34 193,67.55 197.58,72.12 197.58,79.22 196.98,79.82 196.98,140.72 191.62,146.08 191.62,146.84 v1(191.14,147.32)
I2C7_MCU_SDA: length 320.7
  TOP w0.203: R322.2 R323.1 v1(12,119.77) R303.1 ; v1(187.17,53.34) 187.2,53.31 187.2,53.2 187.4,53 R272.1
  ART03 w0.178: v1(23.24,119.38) 23.75,119.89 23.75,121.92 30.68,128.85 30.68,147.89 38.88,156.08 51.84,156.08 53.91,158.15 70.2,158.15 71.18,159.13 95.43,159.13 100.1,163.8 126.7,163.8 126.78,163.88 143.51,163.88 145.86,161.52 156.28,161.52 169.77,148.03 187.73,148.03 189.71,146.05 v1(191.14,146.05)
  ART04 w0.178: v1(23.24,119.38) 22.99,119.13 12.64,119.13 v1(12,119.77)
  BOTTOM w0.127: 186.69,54.48 186.69,53.82 v1(187.17,53.34)
  BOTTOM w0.203: v1(191.14,146.05) 191.14,145.99 196.47,140.66 196.47,79.75 197.1,79.12 197.1,72.23 192.6,67.72 192.6,65.51 186.69,59.6 186.69,54.48
I2C7_SCL: length 203.6
  TOP w0.203: v1(135.13,92.94) R53.2 134.44,89.23 133.05,87.83 133.05,78.16 132.72,77.83 R2026.1 R2754.2 ; J3.2 58.85,126.95 57.71,128.09 57.02,128.09 56.34,128.78 v1(56.26,128.78)
  ART03 w0.178: v1(58.7,150.74) 59.18,151.22 60.07,151.22 60.41,150.88 73.28,150.88 74.79,152.39 93.76,152.39 97.42,156.04 127.55,156.04 129.13,154.46 141.96,154.46 v1(145.92,150.49)
  ART04 w0.178: v1(135.13,92.94) 142.19,100 142.19,123.82 145.63,127.27 145.63,144.53 143.49,146.68 143.49,148.77 144.36,149.64 145.1,149.64 145.92,150.46 v1(145.92,150.49)
  BOTTOM w0.203: v1(58.7,150.74) 59.16,150.28 59.16,145.48 55.35,141.67 55.35,131.53 56.77,130.11 56.77,129.29 v1(56.26,128.78)
I2C7_SCL_HUB0: length 19.6
  TOP w0.203: R2024.1 v1(118.44,35.18) ; U2002.36 133.22,41.42 132.97,41.17 v1(132.97,41.12)
  ART04 w0.178: v1(132.97,41.12) 132.49,41.12 131.95,40.58 131.95,39.12 130.8,37.97 128.68,37.97 124.29,36.13 119.82,36.13 118.87,35.18 v1(118.44,35.18)
I2C7_SCL_HUB1: length 1.3
  TOP w0.203: U2101.34 118.29,38.3 118.44,38.15 R2022.1
I2C7_SCL_R: length 92.3
  TOP w0.203: R2030.1 135.62,63.91 v1(135.03,63.31) 134.93,63.31 134.73,63.51 R2029.2 ; R2022.2 117.91,36.8 v1(117.73,36.63)
  ART04 w0.178: v1(135.03,63.31) 134.45,63.88 132.59,63.88 131.41,62.7 108.01,62.7 98.65,53.34 97.82,53.34 97.28,52.81 97.28,52.17 94.08,48.97 94.08,35.28 v1(93.73,34.92)
  BOTTOM w0.203: v1(93.73,34.92) 94.87,36.07 100.08,36.07 101.09,35.05 107.7,35.05 110.24,32.51 113.61,32.51 v1(117.73,36.63)
I2C7_SDA: length 202
  TOP w0.203: v1(57.4,127.63) 57.79,127.25 58.04,127.25 58.35,126.94 J3.320 ; R2027.1 R2755.2 132.26,78.13 132.61,78.49 132.61,81.13 132.08,81.66 132.08,83.69 132.59,84.2 132.59,88.01 133.71,89.13 133.71,95.33 133.91,95.53 R52.2 134.93,95.53 135.13,95.33 135.13,94.92 v1(135.13,94.92)
  ART03 w0.178: v1(59.59,150.75) 59.97,150.37 74.17,150.37 75.1,151.29 81.77,151.29 82.48,152.01 93.92,152.01 97.58,155.66 127.32,155.66 129.06,153.92 141.48,153.92 144.91,150.49 v1(144.91,150.11)
  ART04 w0.178: v1(135.13,94.92) 136.45,94.92 141.81,100.28 141.81,124 145.25,127.45 145.25,144.36 143,146.61 143,149.1 144.02,150.11 v1(144.91,150.11)
  BOTTOM w0.203: v1(59.59,150.75) 59.59,145.34 55.8,141.55 55.8,131.9 57.28,130.43 57.28,127.76 v1(57.4,127.63)
I2C7_SDA_HUB0: length 18.8
  TOP w0.203: v1(132.51,40.51) 133.1,40.51 133.6,41.02 U2002.37 ; v1(119.7,34.73) 119.46,34.98 R2023.1
  ART04 w0.178: v1(119.7,34.73) 120.79,35.83 124.59,35.83 128.79,37.57 130.83,37.57 132.51,39.25 v1(132.51,40.51)
I2C7_SDA_HUB1: length 1.6
  TOP w0.203: U2101.35 118.69,38.44 119.46,37.67 R2021.1
I2C7_SDA_R: length 93
  TOP w0.127: R2021.2 119.1,36.8 118.95,36.65 118.95,34.92 v1(118.44,34.42)
  TOP w0.203: 135.03,62.56 133.84,63.75 R2028.2 ; 135.03,62.56 135.08,62.61 135.48,62.61 R2031.1 ; 135.03,62.56 v1(135.03,62.55)
  ART04 w0.178: v1(94.87,34.92) 94.46,35.33 94.46,48.39 108.39,62.32 131.66,62.32 132.84,63.5 134.07,63.5 v1(135.03,62.55)
  BOTTOM w0.203: v1(118.44,34.42) 116.03,32 109.86,32 107.44,34.42 101.09,34.42 100.08,35.43 95.38,35.43 v1(94.87,34.92)
I2C8_SCL: length 59.9
  TOP w0.203: R92.2 7.31,110.62 v1(7.04,110.34) R2750.1 ; v1(56.46,123.19) 56.9,123.19 57.85,124.14 J3.318
  ART04 w0.178: v1(7.04,110.34) 9.98,113.28 21.7,113.28 24.6,116.18 27.86,116.18 32.54,120.85 34.12,121.45 39.94,121.45 45.01,123.24 50.59,123.24 51.51,122.32 55.6,122.32 v1(56.46,123.19)
I2C8_SCL_R: length 260.5
  TOP w0.203: R95.2 41.48,26.46 40.31,26.46 v1(39.75,25.91) 39.4,25.55 R2702.2 ; v1(169.6,34.47) 170.03,34.47 170.31,34.19 R2710.2 ; R90.1 5.71,99.77 5.64,99.84 v1(5.64,99.85) 5.64,99.85 5.71,99.92 R2753.2
  ART03 w0.178: v1(169.6,34.47) 167.6,35.28 165.41,35.28 157.6,27.47 153.5,27.47 152.73,26.69 148.18,26.69 145.4,23.91 136.28,23.91 134.85,22.48 134.85,17.75 131.98,14.88 85.85,14.88 84.43,16.31 71.96,16.31 59.16,29.11 44.73,29.11 42.39,26.77 41.33,26.77 40.46,25.91 v1(39.75,25.91) 39.09,25.91 38.77,26.22 38.77,29.96 39.05,30.23 39.05,38.54 37.26,40.32 31.36,40.32 21.69,49.99 21.69,56.67 23.24,58.22 23.24,73.21 22.26,74.19 22.26,89.78 24.32,91.83 24.32,95.63 23.1,96.85 v1(22.94,96.85)
  ART04 w0.178: v1(22.94,96.85) 21.84,95.76 8.18,95.76 5.64,98.3 v1(5.64,99.85)
I2C8_SDA: length 61.3
  TOP w0.203: R93.2 v1(4.72,110.34) R2751.1 ; J3.316 57.35,124.28 56.77,123.7 55.74,123.7 v1(55.5,123.46)
  ART04 w0.178: v1(4.72,110.34) 4.72,110.36 5.36,111 6.99,111 9.78,113.79 21.67,113.79 24.44,116.56 27.71,116.56 32.32,121.18 33.98,121.83 39.69,121.83 44.76,123.62 50.75,123.62 51.56,122.82 54.86,122.82 v1(55.5,123.46)
I2C8_SDA_R: length 264.3
  TOP w0.203: R2709.2 v1(170.94,32.51) ; R94.2 43.05,26.49 42.47,25.91 v1(41.28,25.91) 40.82,25.91 40.26,25.35 R2701.2 ; R91.1 4.82,99.77 4.75,99.84 v1(4.75,99.85) 4.75,99.85 4.82,99.92 R2752.2
  ART03 w0.178: v1(170.94,32.51) 169.41,30.97 166.12,30.97 165.57,30.43 165.57,30.16 164.76,29.35 163.81,29.35 163.46,29 163.46,27.27 161.32,25.12 161.32,20.52 160.96,20.17 156.57,20.17 156.15,19.75 143.83,19.75 137.74,13.66 85.98,13.66 83.82,15.82 71.71,15.82 58.83,28.7 44.96,28.7 42.57,26.31 41.68,26.31 v1(41.28,25.91) 40.81,25.44 38.95,25.44 38.39,26 38.39,30.11 38.66,30.39 38.66,38.38 37.1,39.94 30.83,39.94 21.03,49.74 21.03,56.72 22.86,58.55 22.86,73.06 21.88,74.03 21.88,90.03 23.94,92.09 23.94,95.47 23.18,96.23 22.42,96.23 21.59,95.4 v1(21.59,94.87)
  ART04 w0.178: v1(4.75,99.85) 4.75,98.42 8.31,94.87 v1(21.59,94.87)
I2CS_SCL: length 216.1
  TOP w0.203: v1(60.17,128.52) 60.71,127.99 60.71,127.3 60.85,127.16 J3.10 ; R2867.2 R96.1 187.45,43.81 v1(187.07,43.43)
  ART03 w0.127: 103.57,148.25 103.91,148.59 108.31,148.59
  ART03 w0.178: v1(187.07,43.43) 186.31,44.2 185.42,44.2 177.39,52.22 177.39,58.44 172.35,63.49 172.35,67.96 170.71,69.61 170.57,69.61 169.53,70.65 169.53,82.84 170.19,83.5 170.19,84.22 168.12,86.29 168.12,97.15 153.87,111.4 148.33,111.4 140.01,119.72 140.01,131.08 132.54,138.56 131.6,138.56 125.15,145.01 125.15,148.62 124.05,149.72 109.44,149.72 108.31,148.59 ; 103.57,148.25 102.77,147.45 102.77,147.06 100.41,144.71 95.33,144.71 94.51,143.88 75.35,143.88 74.63,143.15 73.16,143.15 62,132 62,130.35 v1(60.17,128.52)
I2CS_SDA: length 219.7
  TOP w0.203: v1(187.2,41.86) 186.87,42.19 R2872.2 R97.1 ; v1(60.17,127.63) 60.35,127.46 J3.8
  ART03 w0.178: v1(187.2,41.86) 187.54,42.2 187.54,43.88 185.32,46.1 184.59,46.1 177.77,52.91 177.77,59.08 172.73,64.12 172.73,68.77 169.91,71.59 169.91,82.68 170.57,83.34 170.57,84.38 168.5,86.45 168.5,97.31 154.02,111.78 148.49,111.78 140.4,119.88 140.4,131.24 132.57,139.06 131.63,139.06 125.53,145.17 125.53,148.78 124.2,150.1 111.24,150.1 110.5,150.84 109.66,150.84 107.77,148.95 103.32,148.95 99.64,145.26 91.07,145.26 90.07,144.26 75.19,144.26 74.47,143.53 73,143.53 70.69,141.22 70.2,141.22 61.06,132.08 61.06,130.1 59.73,128.77 59.73,128.08 v1(60.17,127.63)
INT_1911_MCU: length 110.6
  TOP w0.203: v1(122.07,119.91) 122.1,119.88 J3.255 ; R364.2 155.38,52.43 155.5,52.43 155.51,52.42 157.52,52.42 157.72,52.62 R365.1 157.74,52.96 R69.1 158.83,53.26 159.06,53.49 161.39,53.49 161.95,52.93 163.96,52.93 164.47,53.44 v1(165.53,53.44)
  ART03 w0.178: v1(165.53,53.44) 165.66,53.57 165.66,64.28 158.59,71.35 152.35,71.35 151.6,72.1 151.6,75.96 149.1,78.46 149.1,79.9 148.76,80.24 146.13,81.33 140.93,81.33 140.56,81.7 133.52,81.7 121.45,93.76 121.45,119.3 v1(122.07,119.91)
INT_1911_MCU_R: length 26
  TOP w0.203: R164.2 167.59,52.82 167.6,52.83 R358.2 168.1,53.16 168.45,53.52 169.85,53.52 170.88,52.49 R359.2 171.04,53.67 v1(171.96,54.58) ; R65.1 185.27,47.47 183.78,45.97 v1(182.37,45.97)
  ART03 w0.178: v1(182.37,45.97) 182.37,46.1 176.91,51.56 174.42,51.56 171.96,54.03 v1(171.96,54.58)
INT_MCU_1911: length 135.5
  TOP w0.203: R294.2 154.91,38.28 155.47,37.72 157.35,37.72 157.53,37.9 R297.1 157.99,38.71 v1(158.12,38.71) 158.64,38.18 R71.1 ; J3.243 119.1,119.88 v1(119.07,119.91)
  ART03 w0.178: v1(119.07,119.91) 119.07,95.44 133.19,81.32 140.37,81.32 140.67,81.02 140.67,81 140.82,80.85 140.82,79.9 141.35,79.36 146.37,79.36 146.62,79.11 147.87,79.11 151.22,75.76 151.22,71.94 152.19,70.97 158.32,70.97 164.97,64.31 164.97,51.52 166.52,49.97 v1(166.52,47.73)
  ART04 w0.178: v1(166.52,47.73) 166.52,47.71 164.82,46 164.82,40.59 165.42,39.99 165.42,39.3 166.32,38.4 v1(166.32,34.01)
  BOTTOM w0.203: v1(158.12,38.71) 161.79,37.19 164.24,37.19 166.32,35.1 v1(166.32,34.01)
INT_MCU_1911_R: length 95.6
  TOP w0.203: R220.2 166.84,36.63 R289.2 167.97,36.83 168.29,37.15 v1(170.41,37.15) 170.93,36.63 R286.2 ; v1(209.04,37.97) 208.81,38.2 R66.1
  ART04 w0.178: v1(196.19,63.75) 196.65,64.21 196.65,67.03 195.07,68.6 192.53,68.6 189.7,65.78 189.7,64.47 182.88,57.66 179.8,57.66 178.38,56.24 178.38,55.63 175.74,52.98 175.74,49.96 169.22,43.43 168.04,43.43 167.97,43.36 167.97,42.67 168.69,41.95 168.69,40.69 168.95,40.44 168.95,39.61 169.22,39.33 169.7,39.33 169.94,39.09 169.94,39.07 170.21,38.8 170.8,38.8 170.88,38.72 170.88,38.01 170.49,37.62 170.49,37.23 v1(170.41,37.15) ; v1(198.76,59.82) 199.68,59.82 200.08,59.65 202.61,58.6 203.48,57.73 203.48,57.44 205.08,55.84 207.41,55.84 208.67,54.58 208.67,49.58 211.25,47 211.25,45.5 211.72,45.03 211.72,41.41 209.04,38.73 v1(209.04,37.97)
  BOTTOM w0.203: v1(198.76,59.82) 197.89,60.69 196.92,63.03 v1(196.19,63.75)
LM75_INLET0_A0: length 3.2
  TOP w0.203: R2891.1 R2894.2 U2804.7
LM75_INLET0_A1: length 3.3
  TOP w0.203: U2804.6 7.87,42.42 7.72,42.57 R2896.2 R2893.1
LM75_INLET0_A2: length 4.5
  TOP w0.203: R2892.1 R2895.2 10.82,42.7 10.41,42.29 9.35,42.29 9.14,42.09 U2804.5
LM75_INLET1_A0: length 12.1
  TOP w0.203: U2803.7 126.6,26.32 v1(126.62,26.34) ; R23.2 119.98,26.53 R24.1 v1(119.2,26.55)
  ART04 w0.178: v1(126.62,26.34) 126.16,26.8 122.25,26.8 121.08,27.96 120.32,27.96 119.2,26.85 v1(119.2,26.55)
LM75_INLET1_A1: length 3.3
  TOP w0.203: U2803.6 124.3,27.59 123.67,28.22 R2899.2 R21.1
LM75_INLET1_A2: length 5.4
  TOP w0.203: U2803.5 123.94,28.86 123.73,29.07 R62.2 122.92,29.27 122.61,29.59 120.76,29.59 R22.1
LM75_INLET2_A0: length 5.5
  TOP w0.203: R2890.2 26.11,83.54 26.11,85.17 26.39,85.45 R2887.1 26.24,85.95 U2805.7
LM75_INLET2_A1: length 5.5
  TOP w0.203: U2805.6 24.97,85.95 R2889.1 25.12,85.45 24.89,85.22 24.89,83.44 25.43,82.91 R2898.2
LM75_INLET2_A2: length 5.9
  TOP w0.203: R2897.2 23.7,82.91 23.5,83.11 23.5,85.24 23.7,85.45 R2888.1 24.21,86 23.7,86.51 U2805.5
M2_LED: length 7
  TOP w0.203: R611.1 5.11,148.97 8.38,148.97 9.76,147.6 J601.10
MAC_GND: length 212.9
  TOP w0.203: v1(136.4,194.94) 136.07,195.27 C1530.2 ; v1(235.33,185.55) 235.66,185.88 C1637.2 ; C1531.2 137.72,195.3 137.41,195 v1(137.41,194.56) ; C139.2 v1(199.26,183.48) ; C1534.2 v1(189.15,195.91) ; C1535.2 v1(188.04,195.91)
  TOP w0.254: C1628.2 v1(201.42,195.55) C1629.2 ; C1635.2 134.44,194.61 v1(134.94,194.12) ; C1636.2 235.47,187.34 v1(235.2,187.07) ; C1536.2 C1537.2 167.49,195.99 v1(167.01,195.5) ; R1632.1 135.06,187.47 v1(135.62,188.03) ; C1533.2 C1532.2 165.66,195.5 v1(166.12,195.5) ; R1634.1 v1(235.76,184.61) ; R1636.1 v1(134.34,190.22) ; R1635.1 v1(128.58,201.04) ; D16.2 209.79,195.97 210.19,195.58 211.07,195.58 v1(211.84,194.82) v1(212.6,194.82) 213.17,195.39 D17.2
  ART02 w0.229: J1501.28 147.03,199.05 ; J1501.28 145.79,198.11 ; J1501.28 145.79,199.99 ; J1501.28 144.54,199.05 ; J1501.31 130.83,208.55 ; J1501.31 129.89,207.3 ; J1501.31 128.95,208.55 ; J1501.31 129.89,209.79 ; J1502.29 167.05,199.05 ; J1502.29 164.56,199.05 ; J1502.29 165.8,198.11 ; J1502.29 165.8,199.99 ; J1502.25 197.64,208.55 ; J1502.25 196.7,209.79 ; J1502.25 196.7,207.3 ; J1502.25 195.76,208.55 ; 163.96,203.17 J1502.30 ; J1502.30 164.9,204.41 ; J1502.30 165.84,203.17 ; J1502.30 164.9,201.92 ; J1501.27 162.03,199.05 ; J1501.27 160.79,199.99 ; J1501.27 159.54,199.05 ; J1501.27 160.79,198.11 ; 229.56,199.05 J1601.27 ; J1601.27 230.8,198.11 ; J1601.27 230.8,199.99 ; J1601.27 232.05,199.05 ; 225.12,201.31 J1601.4 224.31,200.5 ; J1601.28 215.8,199.99 ; J1601.28 217.05,199.05 ; J1601.28 215.8,198.11 ; J1601.28 214.56,199.05 ; J1601.26 232.64,203.17 ; J1601.26 231.7,201.92 ; J1601.26 231.7,204.41 ; J1601.26 230.76,203.17 ; J1502.27 195.8,199.99 ; J1502.27 195.8,198.11 ; J1502.27 197.05,199.05 ; J1502.27 194.56,199.05 ; 163.96,208.55 J1502.31 ; J1502.31 165.84,208.55 ; J1502.31 164.9,209.79 ; J1502.31 164.9,207.3 ; 161.69,201.92 J1501.26 ; J1501.26 160.75,203.17 ; J1501.26 161.69,204.41 ; J1501.26 162.63,203.17 ; 199.9,207.3 J1601.31 ; J1601.31 200.84,208.55 ; J1601.31 198.96,208.55 ; J1601.31 199.9,209.79 ; 129.54,199.05 J1501.29 ; J1501.29 132.03,199.05 ; J1501.29 130.79,199.99 ; J1601.29 200.8,199.99 ; J1601.29 202.05,199.05 ; J1601.29 199.56,199.05 ; J1601.29 200.8,198.11 ; 128.95,203.17 J1501.30 ; J1501.30 129.89,204.41 ; J1501.30 130.83,203.17 ; J1501.30 129.89,201.92 ; 222.23,203.35 J1601.5 223.04,204.16 ; J1502.28 180.8,199.99 ; J1502.28 179.56,199.05 ; J1502.28 182.05,199.05 ; J1502.28 180.8,198.11 ; J1601.25 232.64,208.55 ; J1601.25 230.76,208.55 ; J1601.25 231.7,207.3 ; J1601.25 231.7,209.79 ; 198.96,203.17 J1601.30 ; J1601.30 199.9,204.41 ; J1601.30 200.84,203.17 ; J1601.30 199.9,201.92 ; J1501.25 162.63,208.55 ; J1501.25 161.69,207.3 ; J1501.25 160.75,208.55 ; J1501.25 161.69,209.79 ; J1502.26 197.64,203.17 ; J1502.26 195.76,203.17 ; J1502.26 196.7,201.92 ; J1502.26 196.7,204.41
  ART05 w0.229: J1501.31 130.83,208.55 ; J1501.31 129.89,209.79 ; J1501.31 128.95,208.55 ; J1501.31 129.89,207.3 ; J1502.29 165.8,199.99 ; J1502.29 165.8,198.11 ; J1502.29 164.56,199.05 ; J1502.29 167.05,199.05 ; 224.31,200.5 J1601.4 225.12,201.31 ; 161.69,207.3 J1501.25 ; J1501.25 160.75,208.55 ; J1501.25 162.63,208.55 ; J1501.25 161.69,209.79 ; 195.76,208.55 J1502.25 ; J1502.25 197.64,208.55 ; J1502.25 196.7,209.79 ; J1502.25 196.7,207.3 ; 229.56,199.05 J1601.27 ; J1601.27 232.05,199.05 ; J1601.27 230.8,199.99 ; J1601.27 230.8,198.11 ; 160.79,198.11 J1501.27 ; J1501.27 162.03,199.05 ; J1501.27 160.79,199.99 ; J1501.27 159.54,199.05 ; J1501.30 130.83,203.17 ; J1501.30 129.89,204.41 ; J1501.30 129.89,201.92 ; J1501.30 128.95,203.17 ; J1601.31 199.9,209.79 ; J1601.31 199.9,207.3 ; J1601.31 198.96,208.55 ; J1601.31 200.84,208.55 ; 222.23,203.35 J1601.5 223.04,204.16 ; J1501.26 162.63,203.17 ; J1501.26 161.69,204.41 ; J1501.26 161.69,201.92 ; J1501.26 160.75,203.17 ; J1601.28 217.05,199.05 ; J1601.28 215.8,198.11 ; J1601.28 214.56,199.05 ; J1601.28 215.8,199.99 ; J1502.30 164.9,204.41 ; J1502.30 164.9,201.92 ; J1502.30 165.84,203.17 ; J1502.30 163.96,203.17 ; 145.79,198.11 J1501.28 ; J1501.28 144.54,199.05 ; J1501.28 147.03,199.05 ; J1501.28 145.79,199.99 ; 180.8,198.11 J1502.28 ; J1502.28 179.56,199.05 ; J1502.28 180.8,199.99 ; J1502.28 182.05,199.05 ; J1601.26 232.64,203.17 ; J1601.26 231.7,201.92 ; J1601.26 230.76,203.17 ; J1601.26 231.7,204.41 ; 164.9,207.3 J1502.31 ; J1502.31 163.96,208.55 ; J1502.31 165.84,208.55 ; J1502.31 164.9,209.79 ; 200.8,198.11 J1601.29 ; J1601.29 199.56,199.05 ; J1601.29 200.8,199.99 ; J1601.29 202.05,199.05 ; 195.8,198.11 J1502.27 ; J1502.27 197.05,199.05 ; J1502.27 194.56,199.05 ; J1502.27 195.8,199.99 ; J1601.30 199.9,204.41 ; J1601.30 198.96,203.17 ; J1601.30 199.9,201.92 ; J1601.30 200.84,203.17 ; J1502.26 197.64,203.17 ; J1502.26 195.76,203.17 ; J1502.26 196.7,201.92 ; J1502.26 196.7,204.41 ; J1501.29 132.03,199.05 ; J1501.29 130.79,199.99 ; J1501.29 129.54,199.05 ; 231.7,207.3 J1601.25 ; J1601.25 232.64,208.55 ; J1601.25 231.7,209.79 ; J1601.25 230.76,208.55
  vias: v1(129.6,211.28) v1(132.14,211.28) v1(134.68,211.28) v1(137.22,211.28) v1(139.76,211.28) v1(141.99,199.39) v1(141.99,198.5) v1(141.99,197.61) v1(142.3,211.28) v1(144.84,211.28) v1(147.38,211.28) v1(149.92,211.28) v1(152.46,211.28) v1(154.94,185.17) v1(155,211.28) v1(155.12,192.96) v1(155.12,191.46) v1(155.7,185.17) v1(157.54,211.28) v1(160.08,211.28) v1(162.62,211.28) v1(165.16,211.28) v1(167.7,211.28) v1(170.24,211.28) v1(172.78,211.28) v1(175.32,211.28) v1(177.27,193.43) v1(177.27,192.57) v1(177.86,211.28) v1(180.4,211.28) v1(182.94,211.28) v1(185.48,211.28) v1(188.02,211.28) v1(190.56,211.28) v1(193.1,211.28) v1(195.64,211.28) v1(198.18,211.28) v1(200.72,211.28) v1(203.26,211.28) v1(204.09,198.5) v1(205.8,211.28) v1(208.34,211.28) v1(210.88,211.28) v1(213.42,211.28) v1(215.96,211.28) v1(218.5,211.28) v1(220.62,196.9) v1(220.62,196.04) v1(221.04,211.28) v1(223.58,211.28) v1(226.12,211.28) v1(228.66,211.28) v1(231.2,211.28) v1(232.28,197.48) v1(232.28,194.44) v1(233.05,197.48) v1(233.05,194.44) v1(235.33,186.31)
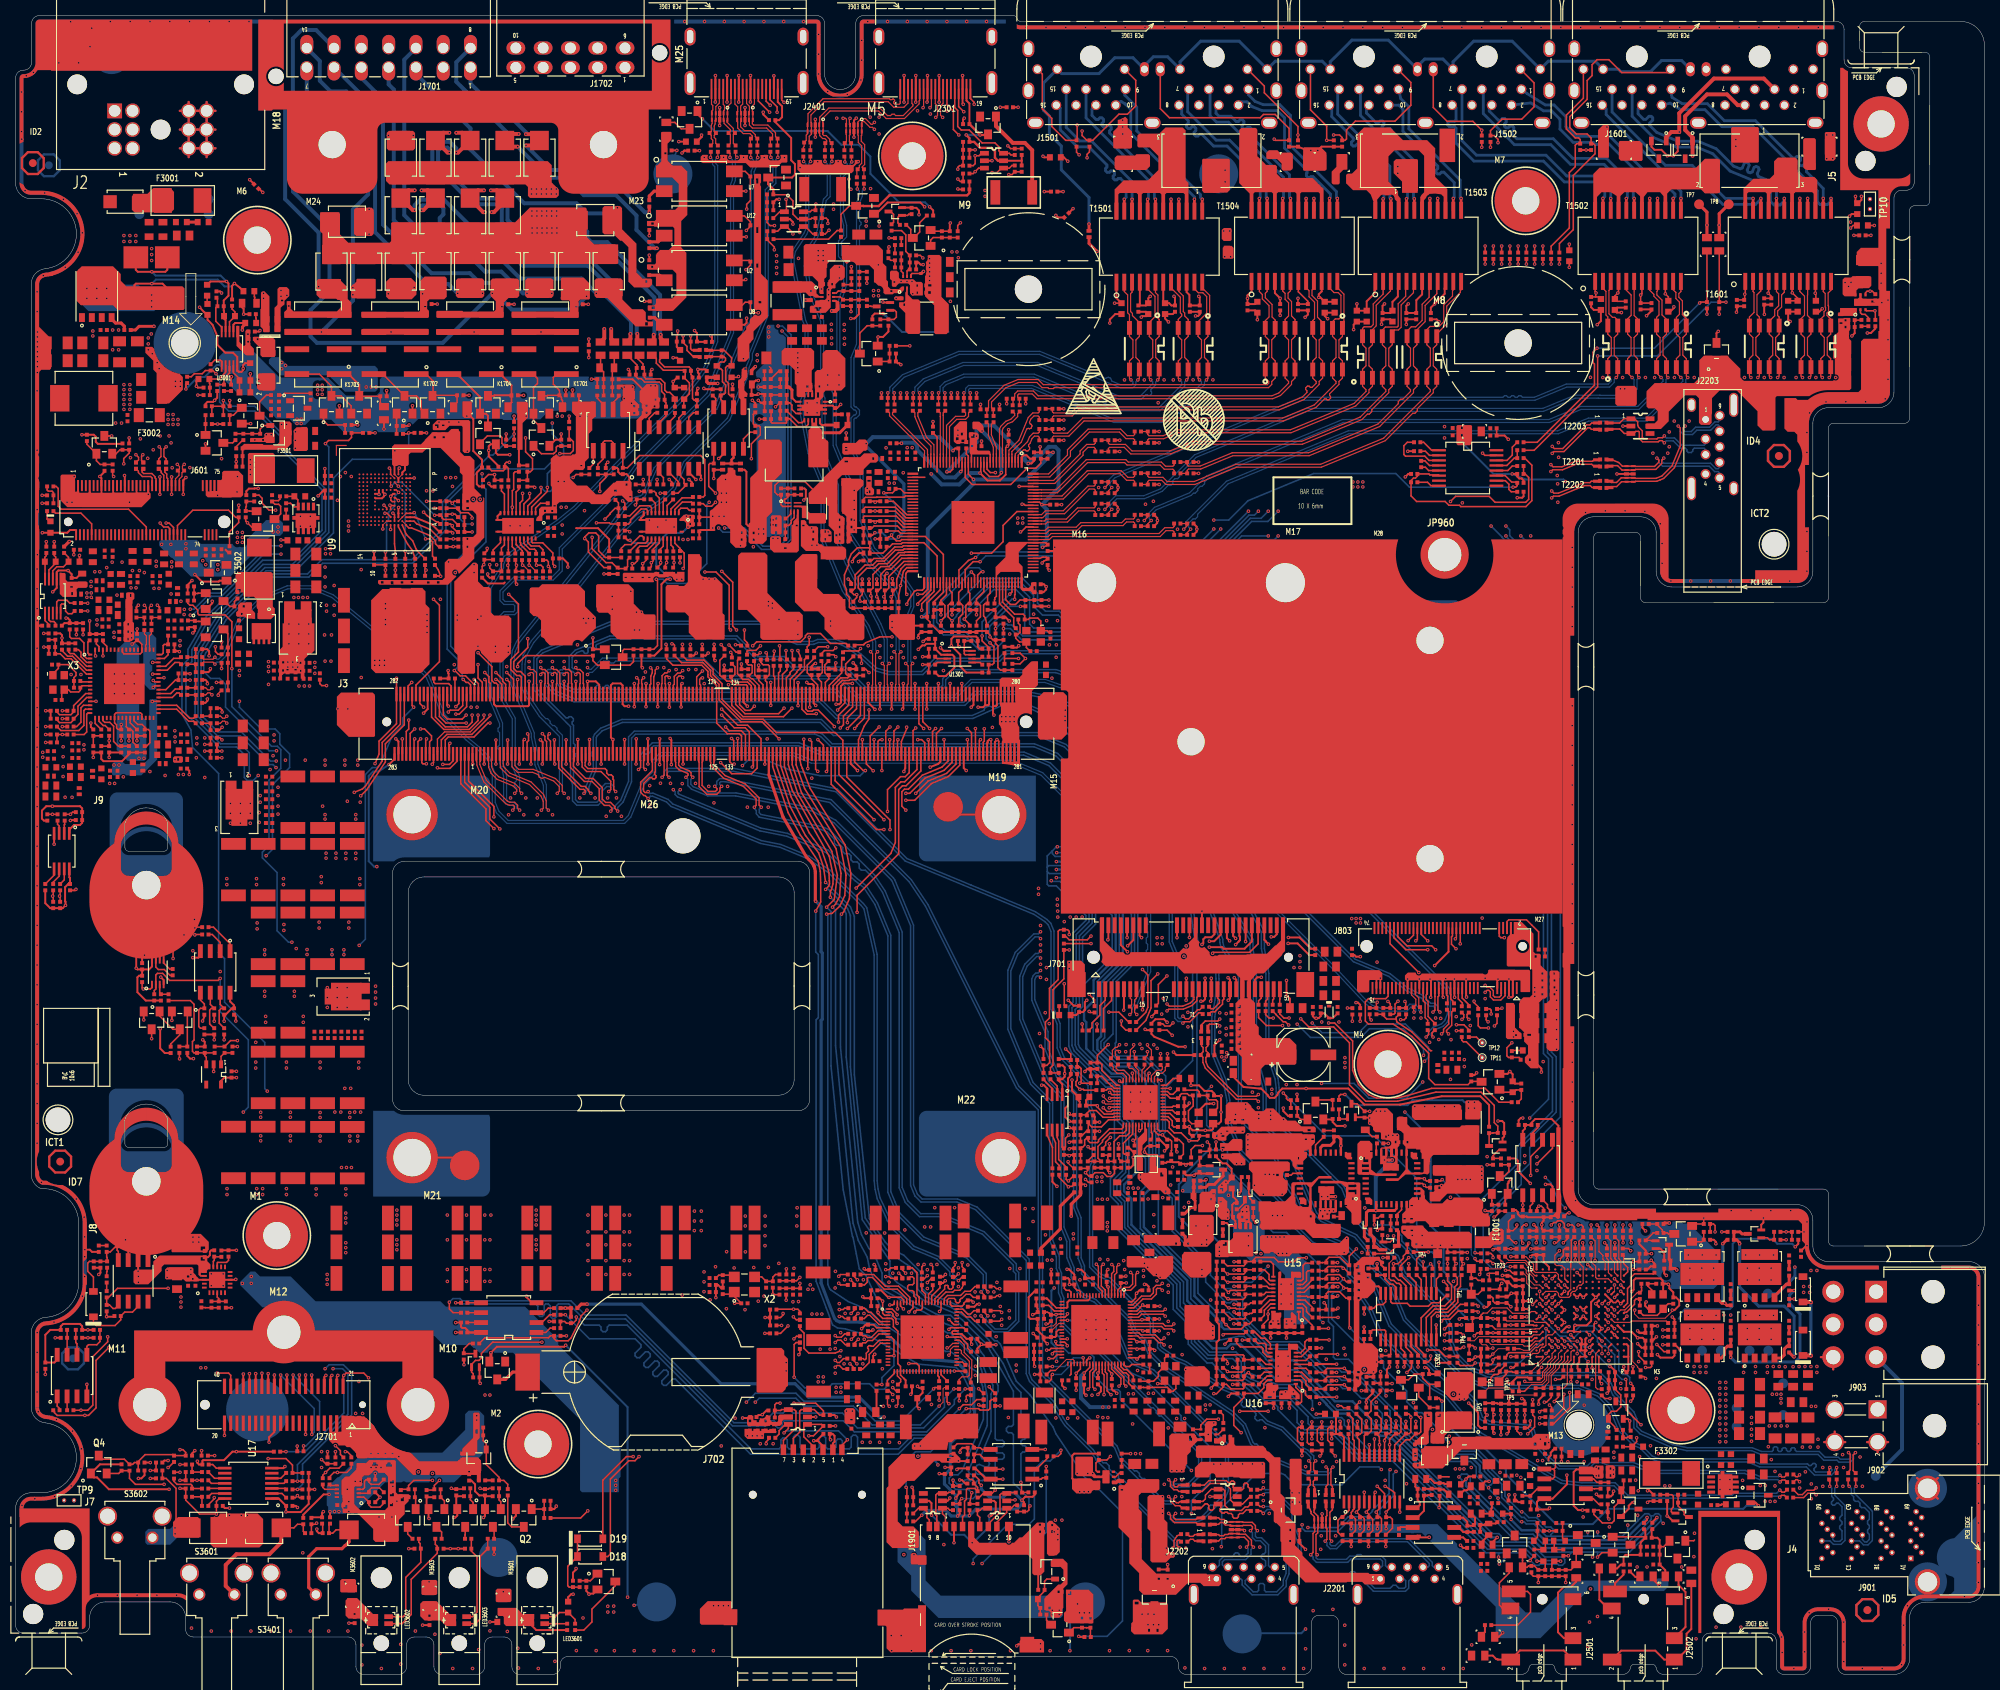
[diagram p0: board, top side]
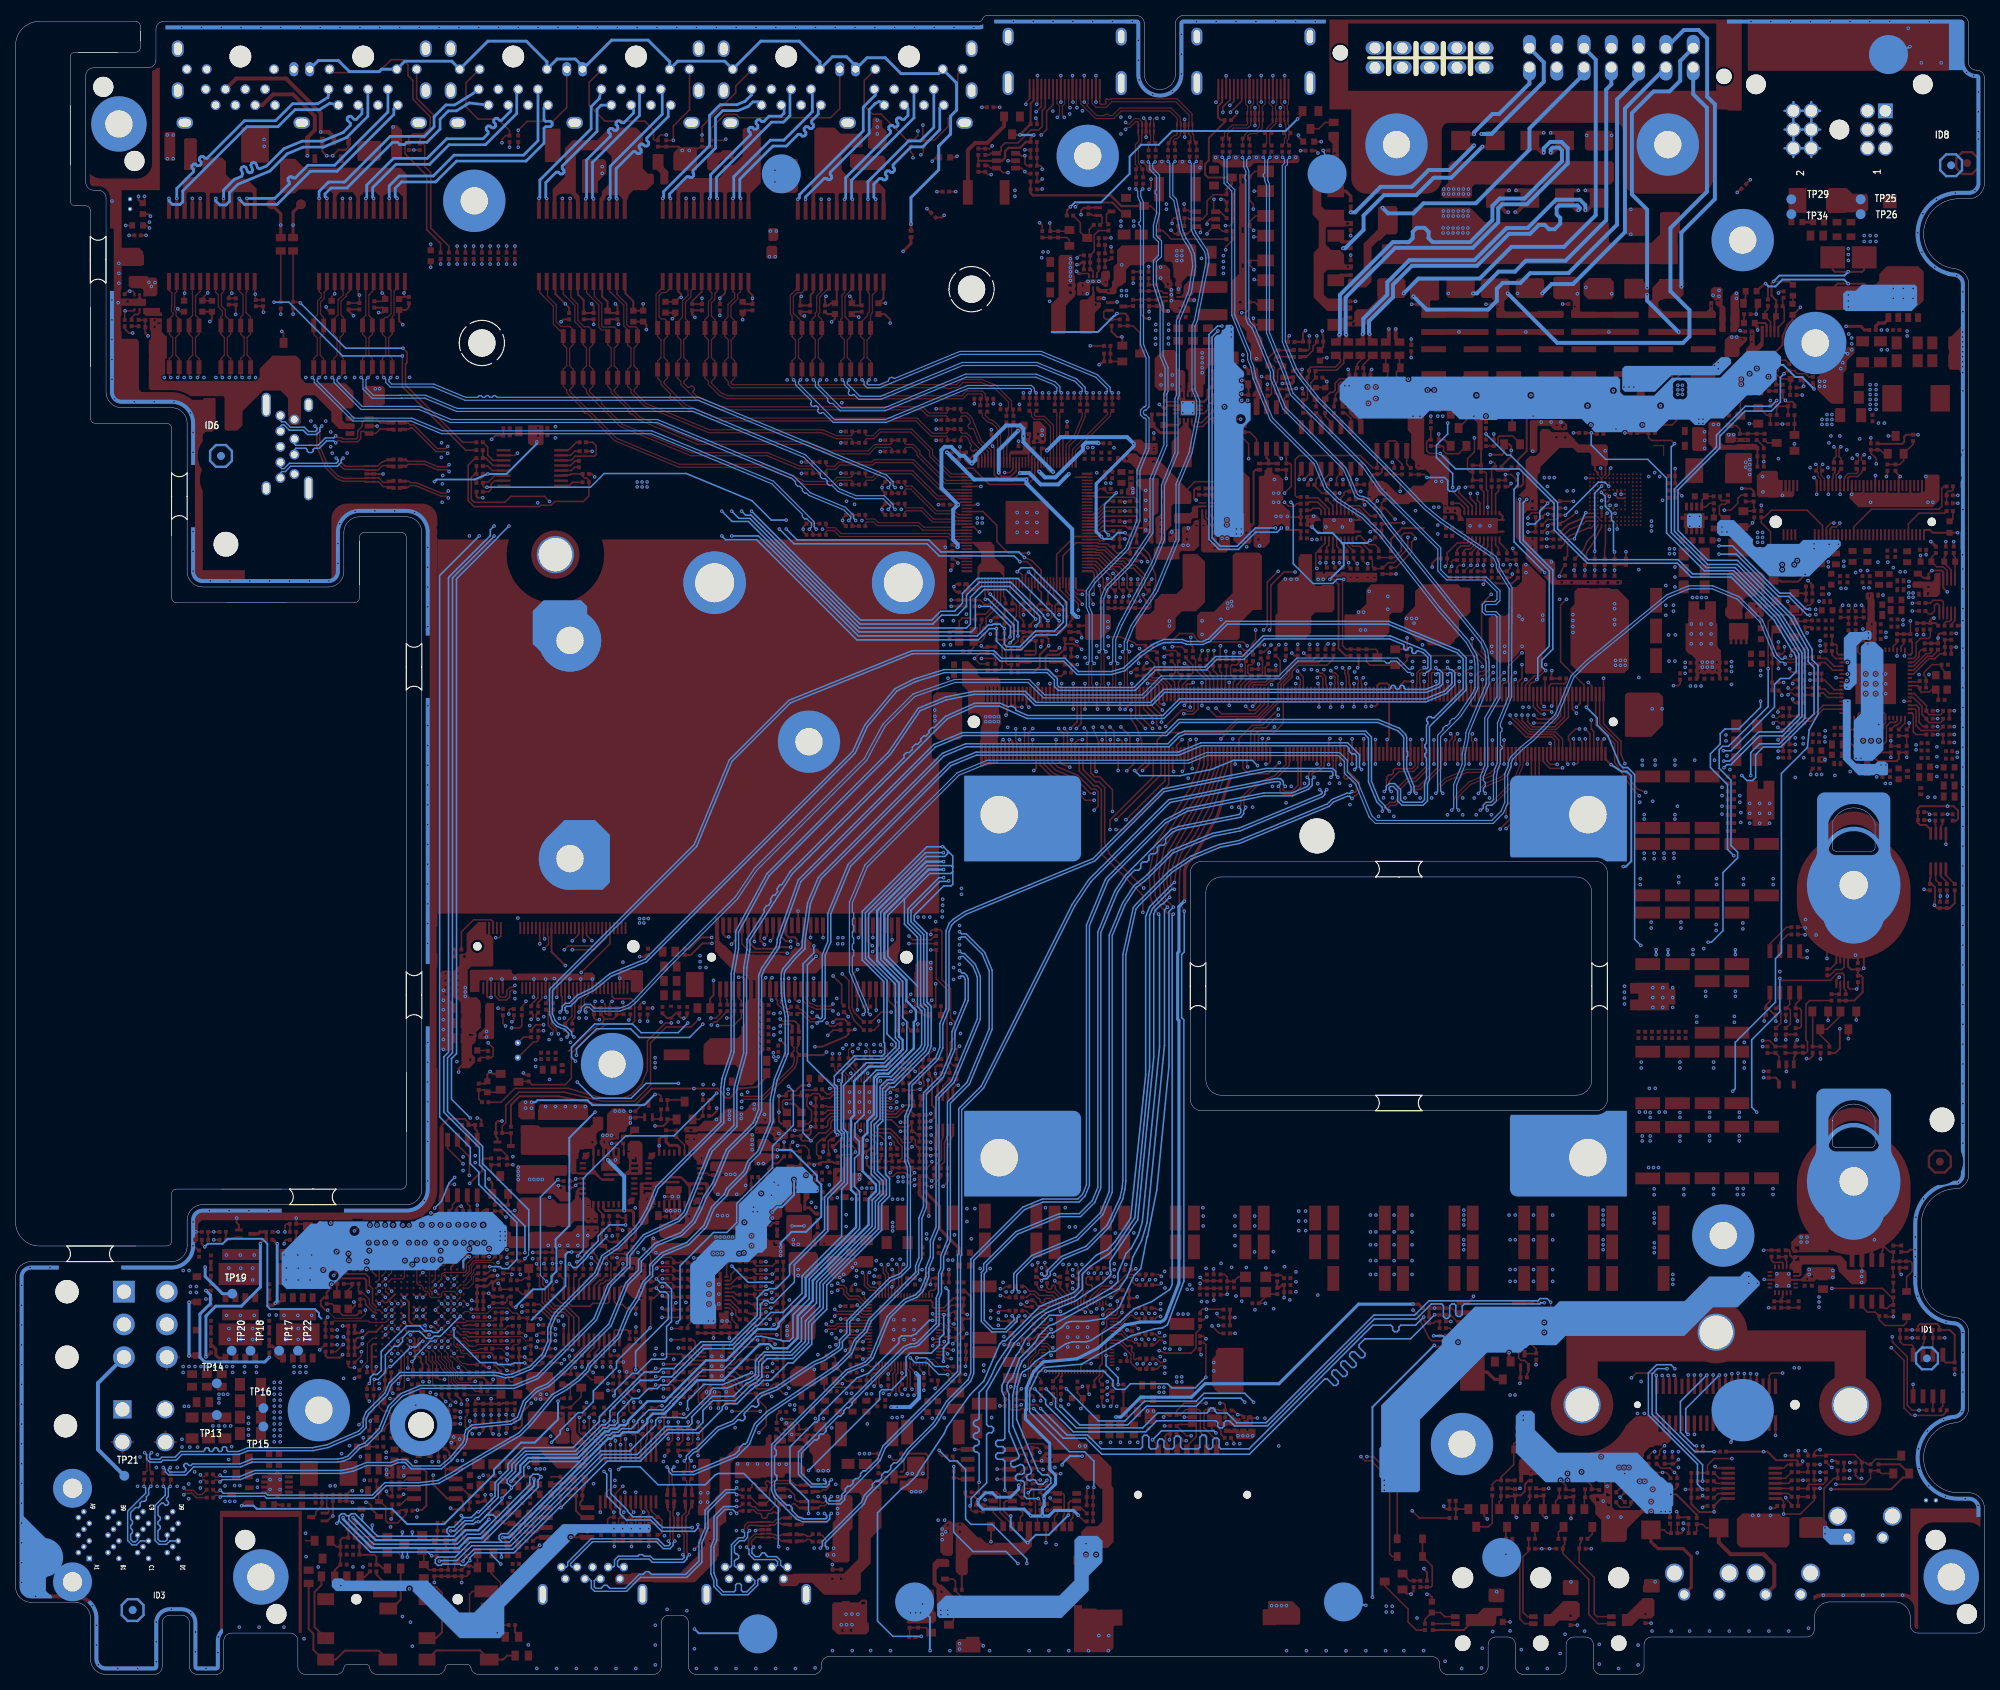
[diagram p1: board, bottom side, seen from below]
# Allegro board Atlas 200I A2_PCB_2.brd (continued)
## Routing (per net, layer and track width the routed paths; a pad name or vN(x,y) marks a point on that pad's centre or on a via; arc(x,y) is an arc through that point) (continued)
MCU1_SWCLK: length 13.1
  TOP w0.203: U3.C7 v1(197.06,45.15) ; R2802.2 189.48,39.01 v1(189.48,38.99) 189.23,38.86 R25.2
  ART04 w0.178: v1(189.48,38.99) 190.5,40 191.01,40.77 193.61,43.37 196.02,43.37 197.06,44.41 v1(197.06,45.15)
MCU1_SWDIO: length 13.6
  TOP w0.203: v1(190.6,50.16) 190.35,49.91 R26.2 R2801.2 ; U3.D7 v1(197.86,45.95)
  ART03 w0.178: v1(197.86,45.95) 197.09,45.95 196.47,45.34 195.33,45.34 194.31,46.35 193.8,46.35 193.55,46.61 193.55,48.89 192.28,50.16 v1(190.6,50.16)
MCU2_SWCLK: length 4.2
  TOP w0.127: R4.1 195.17,39.62 195.33,39.62 196.46,40.75 U3.C1
  TOP w0.203: R2807.2 R4.1
MCU2_SWDIO: length 15.9
  TOP w0.203: U3.C2 v1(196.27,41.17) ; R2808.2 189,51.16 v1(188.85,51.31) 189,51.46 R3.1
  ART03 w0.178: v1(188.85,51.31) 188.85,49.66 191.26,47.24 191.26,46.86 191.52,46.61 191.77,46.61 192.23,46.15 192.23,45.43 196.27,41.39 v1(196.27,41.17)
MCU_BOOT0: length 10.8
  TOP w0.152: 188.21,46.35 188.72,46.35 189.38,47.01 191.29,47.01 191.97,46.33 194.16,46.33 194.38,46.55 194.86,46.55 U3.A8
  TOP w0.203: 188.21,46.35 187.93,46.08 R2829.1 R2828.1 186.84,44.96 186.46,44.58 TP6.1
MCU_EN_VCC_DISK: length 70.1
  TOP w0.203: v1(182.55,52.86) 182.55,52.22 R1027.2 ; R3303.1 R3310.1 209.5,22.24 209.39,22.13 209.35,22.13 v1(209.3,22.07)
  ART03 w0.178: v1(210.69,28.32) 210.69,31.37 210.34,31.72 210.34,34.95 212.47,37.08 212.47,38.86 211.85,39.48 211.85,44.53 210.95,45.43 210.95,47.88 207.95,50.88 207.95,54.17 207.32,54.8 202.05,54.8 200.47,53.22 200.47,52.98 199.82,52.32 197.44,52.32 194.55,55.21 194.55,55.54 194.25,55.84 191.73,55.84 191.01,55.12 186.44,55.12 185.67,54.36 185.67,53.85 v1(186.18,53.34)
  ART04 w0.178: v1(182.55,52.86) 182.5,52.91 182.5,53.03 183.11,53.64 185.89,53.64 v1(186.18,53.34) ; v1(209.3,22.07) 208.66,22.71 208.66,26.29 v1(210.69,28.32)
MCU_VREF: length 17.7
  TOP w0.102: 199.47,42.75 v1(200.27,42.75)
  TOP w0.203: R2811.1 205.08,31.62 205.08,31.77 204.28,32.58 U2802.1 204.28,33.33 204.7,33.76 205.31,33.76 205.87,34.31 205.87,35.85 205.13,36.59 C2802.1 ; 199.47,42.75 199.07,43.15 U3.F4
  TOP w0.254: v1(204.47,39.5) 204.57,39.5 205.13,38.94 C2810.1 C2803.1 C2802.1 ; U3.K3 v1(201.86,41.95)
  BOTTOM w0.203: v1(204.47,39.5) 204.32,39.5 v1(201.86,41.95) 201.83,41.99 201.17,41.99 200.4,42.75 v1(200.27,42.75)
MDCK_V33: length 11.4
  TOP w0.203: v1(127.51,138.58) 127.78,138.86 U6.93 ; v1(123.95,133.22) 123.95,132.59 124.79,131.75 R1331.1 R1330.2
  BOTTOM w0.203: v1(127.51,138.58) 123.95,135.03 v1(123.95,133.22)
MDI_CH1_0_N: length 86.3
  TOP w0.155: v1(149.81,146.91) 150.25,147.36 C1316.1 R197.2 ; v1(213.57,166.37) 213,166.94 D1501.7 213,168.8 213.44,169.24 213.44,171.5 213,171.94 D1501.2 213,174.08 213.39,174.47 213.39,176.05 212.93,176.5 212.93,177.27 212.9,177.3 212.9,177.3 212.58,177.63 T1502.11
  BOTTOM w0.155: v1(149.81,146.91) 150.06,147.17 150.06,147.83 155.29,153.06 170.93,159.54 197.78,159.54 201.7,161.16 209.09,161.16 213.82,165.9 213.82,166.12 v1(213.57,166.37)
MDI_CH1_0_P: length 86.3
  TOP w0.155: R1315.2 C1310.1 150.25,146.47 v1(150.7,146.91) ; T1502.12 213.58,177.4 213.31,177.14 213.31,176.66 213.77,176.2 213.77,174.45 214.27,173.95 D1501.1 214.27,171.94 213.82,171.5 213.82,169.24 214.27,168.8 D1501.8 214.27,166.56 v1(214.46,166.37)
  BOTTOM w0.155: v1(150.7,146.91) 150.44,147.17 150.44,147.67 151,148.23 151.31,148.23 151.59,148.52 151.59,148.82 155.51,152.74 171,159.16 197.85,159.16 201.78,160.78 209.24,160.78 214.2,165.74 214.2,166.12 v1(214.46,166.37)
MDI_CH1_1_N: length 87.7
  TOP w0.155: T1502.8 209.58,177.57 210.11,177.04 210.11,176.8 210.77,176.14 210.77,174.4 210.46,174.08 D1501.4 210.46,171.94 210.9,171.5 210.9,169.24 210.46,168.8 D1501.5 210.46,166.94 v1(211.03,166.37) ; R1316.2 C1311.1 145.2,148.47 v1(144.76,148.03)
  BOTTOM w0.155: v1(211.03,166.37) 211.28,166.12 211.28,165.9 208.04,162.66 200.7,162.66 196.65,160.98 170.18,160.98 152.74,153.76 150.57,151.58 146.06,149.72 145.01,148.66 145.01,148.28 v1(144.76,148.03)
MDI_CH1_1_P: length 87.8
  TOP w0.155: v1(211.92,166.37) 211.73,166.56 D1501.6 211.73,168.8 211.28,169.24 211.28,171.5 211.73,171.94 D1501.3 211.73,173.83 211.15,174.41 211.15,176.3 210.49,176.96 210.49,177.42 210.58,177.51 T1502.9 ; v1(145.64,148.03) 145.2,147.59 C1312.1 R1314.2
  BOTTOM w0.155: v1(211.92,166.37) 211.66,166.12 211.66,165.74 208.2,162.28 200.78,162.28 196.72,160.6 170.26,160.6 152.96,153.44 152.48,152.96 152.48,152.74 152.16,152.41 151.93,152.41 151.61,152.08 151.61,151.86 151.28,151.53 151.06,151.53 150.78,151.26 146.28,149.39 145.39,148.5 145.39,148.28 v1(145.64,148.03)
MDI_CH1_2_N: length 89.3
  TOP w0.155: v1(139.7,149.46) 140.14,149.9 C1313.1 R1313.2 ; v1(207.31,166.37) 206.74,166.94 D13.3 206.74,168.8 207.19,169.24 207.19,171.5 206.74,171.94 D13.6 206.74,173.9 207.2,174.35 207.2,176.95 206.58,177.57 T1502.5
  BOTTOM w0.155: v1(207.31,166.37) 207.57,166.12 207.57,165.05 206.61,164.09 203.2,164.09 203.19,164.1 199.95,164.1 195.86,162.41 165.57,162.41 151.2,156.45 146.84,152.1 144.68,151.21 141.07,151.21 139.95,150.09 139.95,149.71 v1(139.7,149.46)
MDI_CH1_2_P: length 89.3
  TOP w0.155: R1312.2 C1314.1 140.14,149.01 v1(140.59,149.46) ; v1(208.2,166.37) 208.01,166.56 D13.4 208.01,168.8 207.57,169.24 207.57,171.5 208.01,171.94 D13.5 208.01,173.9 207.58,174.34 T1502.6
  BOTTOM w0.155: v1(208.2,166.37) 207.95,166.12 207.95,164.89 206.76,163.71 203.05,163.71 203.03,163.72 200.03,163.72 195.94,162.03 165.65,162.03 151.41,156.13 149.29,154.01 149.29,153.66 149.03,153.4 148.68,153.4 148.42,153.14 148.42,152.79 148.15,152.52 147.8,152.52 147.06,151.78 144.76,150.82 141.23,150.82 140.34,149.93 140.34,149.71 v1(140.59,149.46)
MDI_CH1_3_N: length 84.3
  TOP w0.155: R1311.2 C1315.1 140.14,152.7 v1(139.7,152.26) ; T1502.2 203.58,177.8 203.96,177.42 203.96,174.39 204.2,174.15 D13.8 204.2,171.94 204.65,171.5 204.65,169.24 204.2,168.8 D13.1 204.2,166.56 v1(204.39,166.37)
  BOTTOM w0.155: v1(139.7,152.26) 139.95,152.51 139.95,153.01 140.79,153.85 148.72,157.14 164.87,163.83 190.75,163.83 190.95,164.03 191.21,164.03 191.41,163.83 191.67,163.83 191.87,164.03 192.13,164.03 192.33,163.83 192.59,163.83 192.79,164.03 193.05,164.03 193.25,163.83 194.77,163.83 198.86,165.53 204.27,165.53 204.65,165.9 204.65,166.12 v1(204.39,166.37)
MDI_CH1_3_P: length 84.3
  TOP w0.155: R1309.2 C1309.1 140.14,151.81 v1(140.59,152.26) ; T1502.3 204.58,177.78 204.34,177.55 204.34,174.55 204.8,174.09 205.09,174.09 205.47,173.71 D13.7 205.47,171.94 205.03,171.5 205.03,169.24 205.47,168.8 D13.2 205.47,166.56 v1(205.28,166.37)
  BOTTOM w0.155: v1(205.28,166.37) 205.03,166.12 205.03,165.74 204.43,165.15 198.94,165.15 194.85,163.45 164.94,163.45 149.02,156.85 141.01,153.53 140.34,152.86 140.34,152.51 v1(140.59,152.26)
MDI_CH2_0_N: length 58.1
  TOP w0.155: T1503.11 184.38,177.62 184.28,177.52 184.28,176.81 183.16,175.69 183.16,173.53 182.55,172.92 181.41,172.92 180.99,172.51 D1502.2 180.99,170.58 181.44,170.13 181.44,167.87 180.99,167.43 D1502.7 180.99,165.24 181.44,164.8 181.44,164.58 175.45,158.59 167.37,155.24 156.52,155.24 151.17,153.03 147.68,153.03 147.15,153.56 145.35,153.56 145.2,153.72 C1308.1 R1308.2
MDI_CH2_0_P: length 58.1
  TOP w0.155: R1307.2 C1301.1 145.2,153.03 145.35,153.18 146.99,153.18 147.52,152.65 151.25,152.65 156.59,154.86 167.45,154.86 175.66,158.27 179.19,161.79 179.47,161.79 179.76,162.09 179.76,162.37 181.82,164.42 181.82,164.8 182.26,165.24 D1502.8 182.26,167.43 181.82,167.87 181.82,170.13 182.26,170.58 D1502.1 182.26,171.95 183.54,173.23 183.54,175.53 185.28,177.27 185.28,177.52 185.38,177.62 T1503.12
MDI_CH2_1_N: length 49.1
  TOP w0.155: R1306.2 C1302.1 150.25,155.17 150.41,155.01 151.92,155.01 156.03,156.72 165.82,156.72 174.73,160.41 177.33,163.01 177.33,163.28 177.63,163.58 177.9,163.58 178.9,164.58 178.9,164.8 178.45,165.24 D1502.5 178.45,167.43 178.9,167.87 178.9,170.13 178.45,170.58 D1502.4 178.45,172.33 178.99,172.87 179.56,172.87 180.39,173.7 180.39,175.77 181.28,176.66 181.28,177.82 181.38,177.93 T1503.8
MDI_CH2_1_P: length 49.2
  TOP w0.155: R1305.2 C1303.1 150.25,154.45 150.43,154.63 151.99,154.63 156.11,156.34 165.89,156.34 174.94,160.08 179.28,164.42 179.28,164.8 179.72,165.24 D1502.6 179.72,167.43 179.28,167.87 179.28,170.13 179.72,170.58 D1502.3 179.72,172.49 180.77,173.54 180.77,175.61 182.28,177.11 182.28,177.82 182.38,177.93 182.38,178.7 T1503.9
MDI_CH2_2_N: length 56.3
  TOP w0.155: T1503.5 178.38,177.93 178.28,177.82 178.28,176.8 177.32,175.83 177.32,172.97 177.19,172.85 175.67,172.85 175.29,172.47 D12.6 175.29,170.58 175.73,170.13 175.73,167.87 175.29,167.43 D12.3 175.29,165.24 175.73,164.8 175.73,164.58 172.45,161.3 172.45,161.3 164.95,158.19 151.03,158.19 148.04,156.95 143.18,156.95 142.34,157.79 140.3,157.79 140.14,157.95 C1304.1 R1304.2
MDI_CH2_2_P: length 56.4
  TOP w0.155: T1503.6 179.38,178.7 179.38,177.93 179.28,177.82 179.28,177.25 177.7,175.67 177.7,172.81 177.35,172.47 176.86,172.47 176.56,172.16 D12.5 176.56,170.58 176.11,170.13 176.11,167.87 176.56,167.43 D12.4 176.56,165.24 176.11,164.8 176.11,164.42 173.93,162.24 173.93,161.99 173.62,161.68 173.37,161.68 172.67,160.98 165.02,157.81 151.11,157.81 148.11,156.57 143.02,156.57 142.18,157.41 140.3,157.41 140.14,157.26 C1305.1 R1303.2
MDI_CH2_3_N: length 47
  TOP w0.155: R1302.2 C1306.1 145.2,159.06 145.36,158.9 147.17,158.9 149.01,159.66 163.49,159.66 171.66,163.05 173.19,164.58 173.19,164.8 172.75,165.24 D12.1 172.75,167.43 173.19,167.87 173.19,170.13 172.75,170.58 D12.8 172.75,172.67 172.95,172.87 173.83,172.87 174.12,173.16 174.12,175.81 175.38,177.07 T1503.2
MDI_CH2_3_P: length 47
  TOP w0.155: T1503.3 176.33,178.65 176.33,177.48 174.5,175.65 174.5,173 174.02,172.52 D12.7 174.02,170.58 173.57,170.13 173.57,167.87 174.02,167.43 D12.2 174.02,165.24 173.57,164.8 173.57,164.42 171.88,162.73 163.56,159.28 149.09,159.28 147.24,158.52 145.34,158.52 145.2,158.37 C1307.1 R1301.2
MDI_CH3_0_N: length 55.2
  TOP w0.155: R1335.2 C1322.1 132.97,159.39 133.13,159.23 134.92,159.23 136.87,161.18 162.5,161.18 166.56,162.86 169.34,165.64 169.34,165.86 168.9,166.3 D1503.7 168.9,168.49 169.34,168.94 169.34,171.19 168.9,171.64 D1503.2 168.9,173.54 169.24,173.89 169.72,173.89 169.98,174.14 169.98,176.91 169.62,177.27 169.09,177.27 168.51,177.85 T1504.11
MDI_CH3_0_P: length 55.2
  TOP w0.155: R1336.2 C1329.1 132.97,158.69 133.13,158.85 135.08,158.85 137.03,160.8 162.57,160.8 166.78,162.54 167.86,163.62 168.08,163.62 168.21,163.5 168.43,163.5 168.65,163.72 168.65,163.94 168.52,164.06 168.52,164.28 169.72,165.48 169.72,165.86 170.17,166.3 D1503.8 170.17,168.49 169.72,168.94 169.72,171.19 170.17,171.64 D1503.1 170.36,172.92 170.36,177.06 169.51,177.91 T1504.12
MDI_CH3_1_N: length 51.3
  TOP w0.155: T1504.8 165.51,177.87 165.89,177.5 165.89,176.73 166.59,176.03 166.59,173.9 166.36,173.67 D1503.4 166.36,171.64 166.8,171.19 166.8,168.94 166.36,168.49 D1503.5 166.36,166.3 166.8,165.86 166.8,165.64 166.27,165.11 166.05,165.11 165.89,165.27 165.67,165.27 165.45,165.05 165.45,164.83 165.61,164.67 165.61,164.45 165.03,163.87 161.97,162.6 136.14,162.6 135.36,161.82 133.13,161.82 132.97,161.98 C1328.1 R1337.2
MDI_CH3_1_P: length 51.3
  TOP w0.155: R1338.2 C1327.1 132.97,161.29 133.13,161.44 135.52,161.44 136.29,162.22 162.05,162.22 165.25,163.55 167.18,165.48 167.18,165.86 167.63,166.3 D1503.6 167.63,168.49 167.18,168.94 167.18,171.19 167.63,171.64 D1503.3 167.63,173.44 166.97,174.1 166.97,176.18 166.27,176.89 166.27,177.59 166.51,177.84 T1504.9
MDI_CH3_2_N: length 51.8
  TOP w0.155: R1339.2 127.92,162.86 C1326.1 128.14,163.87 128.14,164.26 128.51,164.64 130.54,164.64 131.15,164.03 161.13,164.03 162.01,164.39 163.26,165.64 163.26,165.86 162.81,166.3 D11.3 162.81,168.49 163.26,168.94 163.26,171.19 162.81,171.64 D11.6 162.81,173.83 163.26,174.27 163.26,175.96 162.81,176.4 162.81,177.16 162.51,177.47 T1504.5
MDI_CH3_2_P: length 51.8
  TOP w0.155: R1340.2 128.73,162.86 C1325.1 128.52,163.87 128.52,164.11 128.67,164.26 130.38,164.26 131,163.65 161.2,163.65 162.23,164.07 163.64,165.48 163.64,165.86 164.08,166.3 D11.4 164.08,168.49 163.64,168.94 163.64,171.19 164.08,171.64 D11.5 164.08,173.83 163.64,174.27 163.64,176.12 163.2,176.56 163.2,177.19 163.51,177.5 T1504.6
MDI_CH3_3_N: length 53.6
  TOP w0.155: R1341.2 124.57,161.49 C1324.1 124.78,162.5 124.78,163.39 126.76,165.37 128.56,166.12 131.14,166.12 131.8,165.45 160.53,165.45 160.72,165.64 160.72,165.86 160.27,166.3 D11.1 160.27,168.49 160.72,168.94 160.72,171.19 160.27,171.64 D11.8 160.27,173.66 160.76,174.14 160.76,175.58 159.89,176.45 159.89,177.02 159.51,177.4 T1504.2
MDI_CH3_3_P: length 53.7
  TOP w0.155: T1504.3 160.51,177.4 160.28,177.17 160.28,176.6 161.14,175.74 161.14,174.14 161.54,173.74 D11.7 161.54,171.64 161.1,171.19 161.1,168.94 161.54,168.49 D11.2 161.54,166.3 161.1,165.86 161.1,165.48 160.69,165.07 133.21,165.07 133.09,164.95 132.52,164.95 132.39,165.07 131.65,165.07 130.98,165.73 128.64,165.73 126.98,165.05 125.16,163.23 125.16,162.5 C1323.1 125.38,161.49 R1342.2
MDI_CH4_0_N: length 50.4
  TOP w0.155: v1(151.84,166.07) 151.65,166.26 D1504.7 151.65,168.49 152.09,168.94 152.09,171.19 151.65,171.64 D1504.2 151.65,173.52 152.76,174.62 152.76,176.75 152.27,177.24 151.69,177.24 151.19,177.74 T1501.11 ; R1343.2 121.62,162.96 C1330.1 v1(121.62,164.4)
  BOTTOM w0.155: v1(121.62,164.4) 121.84,164.62 121.84,164.98 122.21,165.35 130.39,165.35 140.93,160.98 147.48,160.98 152.09,165.59 152.09,165.81 v1(151.84,166.07)
MDI_CH4_0_P: length 50.4
  TOP w0.155: v1(152.73,166.07) 152.92,166.26 D1504.8 152.92,168.49 152.47,168.94 152.47,171.19 152.92,171.64 D1504.1 152.92,174.25 153.14,174.47 153.14,176.91 152.19,177.86 T1501.12 ; R1344.2 122.43,162.96 C1337.1 v1(122.43,164.4)
  BOTTOM w0.155: v1(122.43,164.4) 122.22,164.62 122.22,164.82 122.37,164.97 130.31,164.97 140.86,160.6 147.64,160.6 148.9,161.86 149.12,161.86 149.19,161.78 149.41,161.78 149.63,162 149.63,162.22 149.55,162.3 149.55,162.52 149.77,162.74 149.99,162.74 150.07,162.66 150.29,162.66 150.51,162.88 150.51,163.1 150.43,163.17 150.43,163.39 152.47,165.44 152.47,165.81 v1(152.73,166.07)
MDI_CH4_1_N: length 50.4
  TOP w0.155: R1345.2 118.37,162.96 C1336.1 v1(118.37,164.4) ; v1(149.3,166.07) 149.11,166.26 D1504.5 149.11,168.49 149.55,168.94 149.55,171.19 149.11,171.64 D1504.4 149.11,173.83 149.55,174.27 149.55,174.49 149.38,174.67 149.38,176.67 148.19,177.86 T1501.8
  BOTTOM w0.155: v1(149.3,166.07) 149.55,165.81 149.55,165.43 146.61,162.48 141.07,162.48 130.65,166.8 121.6,166.8 119.14,165.78 118.57,165.21 118.57,164.6 v1(118.37,164.4)
MDI_CH4_1_P: length 50.3
  TOP w0.155: T1501.9 149.19,177.4 149.76,176.83 149.76,174.82 149.93,174.65 149.93,174.27 150.38,173.83 D1504.3 150.38,171.64 149.93,171.19 149.93,168.94 150.38,168.49 D1504.6 150.38,166.26 v1(150.19,166.07) ; R1346.2 119.18,162.96 C1335.1 v1(119.18,164.4)
  BOTTOM w0.155: v1(150.19,166.07) 149.93,165.81 149.93,165.27 148.33,163.66 148.33,163.31 148.06,163.05 147.71,163.05 146.77,162.1 141,162.1 130.57,166.42 121.68,166.42 119.36,165.46 118.95,165.05 118.95,164.64 v1(119.18,164.4)
MDI_CH4_2_N: length 49.5
  TOP w0.155: v1(145.58,166.07) 145.39,166.26 D10.7 145.39,168.49 145.84,168.94 145.84,171.19 145.39,171.64 D10.2 145.39,173.43 146.13,174.17 146.13,176.79 145.19,177.73 T1501.5 ; R1347.2 115.12,162.96 C1334.1 v1(115.12,164.4)
  BOTTOM w0.155: v1(115.12,164.4) 115.33,164.62 115.33,165.12 116.41,166.19 121.5,168.3 131.09,168.3 141.57,163.96 144.2,163.96 145.84,165.59 145.84,165.81 v1(145.58,166.07)
MDI_CH4_2_P: length 49.5
  TOP w0.155: v1(115.93,164.4) C1333.1 115.93,162.96 R1348.2 ; T1501.6 146.19,177.27 146.51,176.94 146.51,173.98 146.66,173.83 D10.1 146.66,171.64 146.22,171.19 146.22,168.94 146.66,168.49 D10.8 146.66,166.26 v1(146.47,166.07)
  BOTTOM w0.155: v1(115.93,164.4) 115.71,164.62 115.71,164.96 116.63,165.87 121.57,167.92 131.01,167.92 136.19,165.78 141.5,163.58 144.36,163.58 144.94,164.16 145.16,164.16 145.26,164.07 145.47,164.07 145.69,164.29 145.69,164.51 145.6,164.6 145.6,164.82 146.22,165.44 146.22,165.81 v1(146.47,166.07)
MDI_CH4_3_N: length 49.7
  TOP w0.155: T1501.2 142.19,177.4 142.62,176.97 142.62,174.67 142.85,174.44 D10.4 142.85,171.64 143.3,171.19 143.3,168.94 142.85,168.49 D10.5 142.85,166.26 v1(143.04,166.07) ; v1(111.87,164.4) C1332.1 111.87,162.96 R1349.2
  BOTTOM w0.155: v1(111.87,164.4) 112.12,164.65 112.12,165.11 113.74,166.73 120.97,169.72 131.37,169.72 137.68,167.11 139.76,166.25 140.13,166.41 140.44,166.28 140.59,165.91 141.72,165.44 143.14,165.44 143.3,165.59 143.3,165.81 v1(143.04,166.07)
MDI_CH4_3_P: length 49.8
  TOP w0.155: R1350.2 112.68,162.96 C1331.1 v1(112.68,164.4) ; v1(143.93,166.07) 144.12,166.26 D10.6 144.12,168.49 143.68,168.94 143.68,171.19 144.12,171.64 D10.3 144.12,173.43 143.23,174.32 143.23,174.6 143,174.83 143,177.14 143.19,177.32 T1501.3
  BOTTOM w0.155: v1(143.93,166.07) 143.68,165.81 143.68,165.44 143.3,165.06 141.64,165.06 135.45,167.62 131.3,169.34 121.05,169.34 113.96,166.41 112.5,164.95 112.5,164.58 v1(112.68,164.4)
MDI_PHY0_0_N: length 158.2
  TOP w0.155: R196.2 v1(146.84,79.63) ; v1(232.6,166.37) 232.79,166.56 D1601.8 232.79,168.8 232.35,169.24 232.35,171.5 232.79,171.94 D1601.1 232.79,173.86 232.31,174.34 232.31,174.64 232.51,174.85 232.51,175.52 232.46,175.57 232.46,177.22 232.83,177.58 T1601.12
  ART04 w0.127: v1(232.6,166.37) 232.35,166.62 232.35,167.48 231.08,168.74 226.7,170.56 207.45,170.56 205.98,171.17 202.97,171.17 200.08,169.97 196.67,166.56 189.54,163.61 178.6,152.66 154.69,94.94 154.69,92.54 152.39,90.24 152.04,90.09 151.41,89.47 150.85,88.11 150.85,82.81 149.62,81.58 147.45,80.68 147.09,80.32 147.09,79.88 v1(146.84,79.63)
MDI_PHY0_0_P: length 158.2
  TOP w0.155: v1(231.71,166.37) 231.52,166.56 D1601.7 231.52,168.8 231.97,169.24 231.97,171.5 231.52,171.94 D1601.2 231.52,173.89 231.93,174.29 231.93,174.8 232.13,175 232.13,175.36 232.08,175.41 232.08,177.15 231.83,177.4 T1601.11 ; R195.2 147.73,79.01 v1(147.73,79.63)
  ART04 w0.127: v1(147.73,79.63) 147.47,79.88 147.47,80.16 147.67,80.36 149.84,81.26 151.23,82.65 151.23,88.04 151.73,89.25 152.26,89.77 152.6,89.92 155.07,92.38 155.07,94.86 178.92,152.45 189.76,163.28 196.88,166.24 200.3,169.65 203.04,170.79 205.91,170.79 207.38,170.18 226.62,170.18 227.03,170.01 227.1,169.84 227.07,169.79 227.14,169.63 227.38,169.53 227.54,169.6 227.56,169.65 227.73,169.72 227.96,169.62 228.03,169.46 228.01,169.41 228.08,169.24 228.32,169.14 228.48,169.21 228.5,169.26 228.67,169.33 228.9,169.23 228.97,169.07 228.95,169.02 229.02,168.85 229.25,168.76 229.42,168.82 229.44,168.87 229.6,168.94 229.84,168.85 229.91,168.68 229.89,168.63 229.96,168.46 230.19,168.37 230.36,168.44 230.38,168.49 230.54,168.55 230.87,168.42 231.97,167.32 231.97,166.62 v1(231.71,166.37)
MDI_PHY0_1_N: length 159.1
  TOP w0.155: T1601.9 229.83,176.97 229.81,176.94 229.81,174.33 230.25,173.89 D1601.3 230.25,171.94 229.81,171.5 229.81,169.24 230.25,168.8 D1601.6 230.25,166.56 v1(230.06,166.37) ; R1317.2 145.16,79.43 v1(145.16,79.88)
  ART04 w0.127: v1(230.06,166.37) 229.81,166.12 229.81,165.78 229.48,165.46 227.93,165.46 227.36,166.03 227.36,167.04 225.48,168.91 224.74,168.91 224.63,168.8 224.63,168.77 224.52,168.66 224.36,168.66 224.25,168.77 224.25,168.8 224.14,168.91 223.4,168.91 223.2,168.71 222.9,168.71 222.69,168.91 222.39,168.91 222.19,168.71 221.88,168.71 221.68,168.91 221.38,168.91 221.17,168.71 220.87,168.71 220.67,168.91 220.28,168.91 220.12,168.76 219.9,168.76 219.74,168.91 219.52,168.91 219.36,168.76 219.14,168.76 218.98,168.91 218.76,168.91 218.6,168.76 218.38,168.76 218.22,168.91 205.4,168.91 203.75,168.22 201.48,168.22 200.09,167.65 195.74,163.29 192.13,161.8 187.07,156.75 184.04,155.49 180.23,151.68 170.94,129.26 170.94,123.57 158.41,93.31 154.95,89.84 152.83,86.68 152.83,85.9 152.5,85.1 152.5,81.76 150.43,79.69 147.82,78.61 146.55,78.61 145.28,79.88 v1(145.16,79.88)
MDI_PHY0_1_P: length 158.9
  TOP w0.155: R190.2 145.69,79.3 145.67,79.31 145.67,80.09 145.16,80.6 v1(145.16,80.77) ; T1601.8 228.83,177.4 229.43,176.81 229.43,174.36 228.98,173.91 D1601.4 228.98,171.94 229.43,171.5 229.43,169.24 228.98,168.8 D1601.5 228.98,166.56 v1(229.17,166.37)
  ART04 w0.127: v1(145.16,80.77) 145.78,80.15 145.78,79.93 146.71,78.99 147.75,78.99 150.22,80.02 152.12,81.92 152.12,85.18 152.45,85.98 152.45,86.76 152.49,86.86 154.65,90.09 158.08,93.52 170.56,123.65 170.56,129.33 179.91,151.89 183.82,155.81 186.86,157.07 191.91,162.12 195.52,163.62 199.87,167.97 200.64,168.29 201.4,168.6 203.67,168.6 205.33,169.29 225.64,169.29 227.74,167.19 227.74,166.19 228.09,165.84 229.32,165.84 229.43,165.94 229.43,166.12 v1(229.17,166.37)
MDI_PHY0_2_N: length 155.9
  TOP w0.155: v1(225.98,166.37) 226.17,166.56 D14.8 226.17,168.8 225.73,169.24 225.73,171.5 226.17,171.94 D14.1 226.17,174.13 225.98,174.32 225.98,174.9 226.49,175.41 226.49,176.96 226.83,177.3 T1601.6 ; R191.2 142.97,79.26 142.97,80.1 143.4,80.53 v1(143.4,80.77)
  ART04 w0.127: v1(143.4,80.77) 143.4,80.68 143.99,80.09 143.99,79.92 146.18,77.72 148.16,77.72 151.01,78.9 153.39,81.28 153.39,84.66 153.74,85.5 154.95,87.32 157.03,89.39 157.86,91.39 158.98,92.51 159.27,92.95 172.06,123.83 172.06,129.38 181.08,151.17 183.54,153.63 190.54,156.52 201.04,167.02 201.72,167.31 205.66,167.31 206.7,167.74 225.18,167.74 225.73,167.19 225.73,166.62 v1(225.98,166.37)
MDI_PHY0_2_P: length 156.4
  TOP w0.155: R192.2 143.47,79.22 v1(143.47,79.88) ; v1(225.09,166.37) 224.9,166.56 D14.7 224.9,168.8 225.35,169.24 225.35,171.5 224.9,171.94 D14.2 224.9,173.59 225.6,174.29 225.6,175.06 226.11,175.57 226.11,177.11 225.83,177.39 T1601.5
  ART04 w0.127: v1(143.47,79.88) 143.49,79.88 144.07,79.3 144.07,79.07 144.22,78.92 144.45,78.92 144.61,78.76 144.61,78.53 144.76,78.38 144.99,78.38 145.25,78.12 145.25,77.89 145.4,77.74 145.63,77.74 146.03,77.34 148.24,77.34 151.22,78.58 153.77,81.13 153.77,84.58 154.08,85.32 155.25,87.08 157.35,89.18 158.18,91.17 159.27,92.27 159.61,92.77 172.44,123.75 172.44,129.31 181.41,150.95 183.76,153.3 190.75,156.2 201.25,166.7 201.8,166.93 205.73,166.93 206.78,167.36 217.49,167.36 217.61,167.25 217.61,167.09 217.72,166.98 217.87,166.98 217.99,167.09 217.99,167.25 218.1,167.36 218.26,167.36 218.37,167.25 218.37,167.09 218.48,166.98 218.64,166.98 218.75,167.09 218.75,167.25 218.86,167.36 219.02,167.36 219.13,167.25 219.13,167.09 219.24,166.98 219.4,166.98 219.51,167.09 219.51,167.25 219.62,167.36 219.78,167.36 219.89,167.25 219.89,167.09 220,166.98 220.16,166.98 220.27,167.09 220.27,167.25 220.38,167.36 225.02,167.36 225.35,167.03 225.35,166.62 v1(225.09,166.37)
MDI_PHY0_3_N: length 157
  TOP w0.155: v1(141.58,80.77) 141.25,80.44 141.04,80.44 140.66,80.06 140.66,79.23 R193.2 ; v1(223.44,166.37) 223.63,166.56 D14.6 223.63,168.8 223.19,169.24 223.19,171.5 223.63,171.94 D14.3 223.63,174.13 223.33,174.43 223.33,176.98 223.83,177.47 T1601.3
  ART04 w0.127: v1(141.58,80.77) 141.32,80.52 140.99,80.52 140.64,80.17 140.64,78.95 141.16,77.69 142.39,76.46 145.1,75.34 147.5,75.34 147.71,75.54 151.77,77.22 155.95,81.4 156.36,82.39 156.36,83.19 159.36,90.42 159.99,91.05 162.25,94.44 174.27,123.45 174.27,130.03 182.64,150.24 184.39,151.99 191.13,154.78 193.97,157.63 211.71,164.97 222.5,164.97 223.25,165.72 223.25,166.18 v1(223.44,166.37)
MDI_PHY0_3_P: length 157
  TOP w0.155: v1(141.57,79.88) 141.57,79.89 141.4,80.06 141.2,80.06 141.04,79.91 141.04,79.38 R194.2 ; v1(222.55,166.37) 222.36,166.56 D14.5 222.36,168.8 222.81,169.24 222.81,171.5 222.36,171.94 D14.4 222.36,174.13 222.95,174.72 222.95,177.28 222.83,177.4 T1601.2
  ART04 w0.127: v1(141.57,79.88) 141.32,80.14 141.14,80.14 141.02,80.02 141.02,79.02 141.48,77.9 141.66,77.72 141.86,77.72 142.11,77.47 142.11,77.27 142.6,76.78 145.18,75.72 147.35,75.72 147.49,75.86 151.56,77.55 155.63,81.62 155.98,82.47 155.98,83.26 159.04,90.64 159.69,91.3 161.91,94.62 173.89,123.53 173.89,130.11 182.32,150.45 184.17,152.31 190.91,155.1 193.76,157.95 211.63,165.35 216.5,165.35 216.61,165.46 216.61,165.67 216.72,165.79 216.88,165.79 216.99,165.67 216.99,165.46 217.1,165.35 217.26,165.35 217.37,165.46 217.37,165.67 217.48,165.79 217.64,165.79 217.75,165.67 217.75,165.46 217.86,165.35 218.02,165.35 218.13,165.46 218.13,165.67 218.24,165.79 218.4,165.79 218.51,165.67 218.51,165.46 218.62,165.35 218.78,165.35 218.89,165.46 218.89,165.67 219,165.79 219.16,165.79 219.27,165.67 219.27,165.46 219.38,165.35 222.35,165.35 222.87,165.88 222.87,166.05 v1(222.55,166.37)
MDIO_V33: length 14.3
  TOP w0.203: R1332.1 R1333.2 125.27,129.54 125.48,129.74 125.48,131.83 v1(124.97,132.33) ; U6.94 128.18,138.55 128.13,138.49 v1(128.13,137.92)
  BOTTOM w0.203: v1(128.13,137.92) 128.09,137.96 127.8,137.96 124.46,134.62 124.46,132.84 v1(124.97,132.33)
MUSIM1_CLK: length 12
  TOP w0.203: v1(184.65,94.36) 184.78,94.49 J803.32 ; v1(187.05,86.36) 187.05,86.18 187.58,85.65 R801.1
  ART03 w0.178: v1(187.05,86.36) 186.94,86.46 186.94,89.99 184.18,92.76 184.18,93.89 v1(184.65,94.36)
MUSIM1_DATA: length 14.4
  TOP w0.203: v1(184.73,93.09) 184.15,93.67 184.15,94.61 184.28,94.74 J803.34 ; R803.1 189.08,85.37 189.24,85.2 v1(189.24,84.72)
  ART03 w0.178: v1(189.24,84.72) 187.81,86.16 187.81,90.02 v1(184.73,93.09)
MUSIM1_RST: length 13.4
  TOP w0.203: R802.1 190.53,85.37 v1(190.63,85.47) ; J803.30 v1(185.28,93.73)
  ART03 w0.178: v1(190.63,85.47) 190.12,85.98 189.79,85.98 189.15,86.61 189.15,89.85 v1(185.28,93.73)
ONLINE_TPM: length 192.4
  TOP w0.203: v1(45.26,38.05) 44.65,38.66 42.39,38.66 v1(42.09,38.35) 41.99,38.26 J2701.21 ; v1(94.53,131.95) 95.04,132.46 100.69,132.46 101.3,133.07 101.3,133.24 101.58,133.53 103.23,133.53 104.5,132.26 106.5,132.26 R202.2 ; R200.1 v1(34.67,28.57)
  ART03 w0.178: v1(94.53,131.95) 94.29,131.7 94.29,129.82 v1(91.43,126.96) ; v1(45.26,38.05) 45.26,42.87 39.47,48.67 39.47,58.83 36.98,61.31 36.98,78.59 36.32,79.25 36.32,87.87 35.99,88.2 v1(35.99,93.12)
  ART04 w0.178: v1(35.99,93.12) 36.5,93.62 36.5,96.71 38.28,98.49 38.28,104.93 42.19,108.84 43.84,108.84 44.81,109.8 44.81,112.85 45.75,113.79 56.87,113.79 61.04,109.62 63.3,108.69 72.85,108.69 75.51,111.35 77.29,111.35 78.99,113.05 78.99,122.94 77.99,123.94 77.99,128.41 79.26,129.68 88.35,129.68 90.78,127.26 90.78,127.19 91.01,126.96 v1(91.43,126.96)
  BOTTOM w0.203: v1(42.09,38.35) 42.09,33.53 37.14,28.57 v1(34.67,28.57)
P0LED0: length 6.2
  TOP w0.203: R1351.2 124.37,135.55 124.15,135.78 124.15,137.17 124.35,137.38 R1370.1 124.66,138.37 124.98,138.7 U6.86
P0LED2: length 6.5
  TOP w0.203: U6.84 124.18,138.92 123.23,137.96 R1369.1 123.48,137.38 123.74,137.12 123.74,135.68 123.23,135.17 R1352.2
PCA9555A_A0: length 6.1
  TOP w0.203: R2748.2 172.64,32.74 172.64,31.04 172.44,30.84 R2743.1 172.09,30.35 172.32,30.12 U2703.21
PCA9555A_A1: length 5.3
  TOP w0.203: U2703.2 171.02,21.08 170.89,20.95 170.89,20.9 R2744.1 170,20.19 169.6,19.79 169.6,18.24 169.93,17.91 R2747.2
PCA9555A_A2: length 5
  TOP w0.203: U2703.3 171.67,21.24 171.48,21.05 171.48,20.96 171.3,20.78 R2745.1 171.58,20.19 171.83,19.93 171.83,18.45 R2746.2
PCA9555B_A0: length 4.2
  TOP w0.203: U1002.21 177.01,49.68 176.64,50.05 176.26,50.05 175.62,50.69 R1030.1 R1035.2
PCA9555B_A1: length 4.2
  TOP w0.203: R1031.1 R1034.2 174.01,44.19 175.57,44.19 175.71,44.05 U1002.2
PCA9555B_A2: length 3.1
  TOP w0.203: R1032.1 R1033.2 176.36,41.06 U1002.3
PCB_ID0: length 25.4
  TOP w0.203: R2738.2 176.4,32.79 176.4,31.11 176.17,30.89 R2722.1 175.77,30.4 175.57,30.2 v1(175.57,29.97) U2703.16 ; R2861.1 v1(183.26,42.8)
  ART04 w0.178: v1(175.57,29.97) 178.42,29.97 181.97,33.52 181.97,36.64 183.74,38.42 183.74,40.64 182.79,41.59 182.79,42.33 v1(183.26,42.8)
PCB_ID1: length 30.4
  TOP w0.203: R2739.2 175.13,32.79 175.13,31.24 174.78,30.89 R2723.1 174.9,30.48 174.9,29.99 174.92,29.97 v1(174.92,29.46) U2703.17 ; R2862.1 195.66,33.87 195.48,33.68 v1(195.45,33.68)
  ART03 w0.178: v1(181.71,31.42) 183.01,31.42 v1(183.87,30.56)
  ART04 w0.178: v1(183.87,30.56) 186.06,32.74 193.78,32.74 194.06,33.02 194.79,33.02 v1(195.45,33.68) ; v1(181.71,31.42) 181.28,31.42 178.85,28.99 175.39,28.99 v1(174.92,29.46)
PCB_ID2: length 40.5
  TOP w0.203: R2724.1 173.25,36.42 R2740.2 ; v1(182.88,45.34) 183.11,45.57 183.95,45.57 184.99,46.61 R2863.1 ; U2703.18 v1(174.27,30.2)
  TOP w0.254: R2740.2 172.59,36.4 v1(172.59,36.4)
  ART04 w0.178: v1(182.88,45.34) 180.54,45.34 176.23,41.02 174.09,41.02 171.74,38.67 171.74,35.53 171.51,35.3 171.51,30.9 173.42,28.99 173.81,28.99 174.27,29.45 v1(174.27,30.2) 173.96,30.5 173.96,35.03 v1(172.59,36.4)
PCIE_EP_RC_FLAG: length 43.2
  TOP w0.203: J3.313 56.1,117.19 55.66,116.74 v1(54.79,116.74) ; R208.2 39.02,127.09 39.27,126.85 v1(39.88,126.85)
  ART03 w0.178: v1(54.79,116.74) 54.79,116.23 53.42,114.86 49.71,114.86 43.94,109.09 38.93,109.09 36.68,111.34 36.68,118.8 39.88,122 v1(39.88,126.85)
PG_ADJ_TEC: length 30
  TOP w0.203: R73.2 v1(177.22,39.44) ; v1(182.96,63.47) 182.78,63.3 R1006.2
  ART04 w0.178: v1(184.4,50.42) 183.35,49.36 183.35,45.14 182.4,44.2 181.97,44.2 v1(177.22,39.44)
  BOTTOM w0.127: 185.19,53.36 185.19,52.89 185.2,52.89 185.2,52.52 185.19,52.52 185.19,51.21 v1(184.4,50.42)
  BOTTOM w0.203: 185.19,53.36 185.19,61.24 v1(182.96,63.47)
PHX_GND: length 49.8
  TOP w0.254: v1(31.7,190.12) 31.22,190.59 R1639.2 ; R1637.2 v1(73.51,171.3) ; v1(87.07,172.39) 87.39,172.07 C1642.2 87.43,170.94 R1633.2 ; R1703.1 v1(73.45,175.77) ; C1705.1 v1(81.27,182.07) ; v1(84.91,172.34) 84.91,171.88 84.8,171.77 C1643.2 84.8,170.29 85.18,169.91 C1634.1 ; R1716.1 v1(63.93,175.77) ; C1706.1 v1(80.66,176.14) ; C1631.1 v1(85.06,196.63) ; C1704.1 v1(81.27,184.56) ; R1710.1 v1(54.08,175.79) ; C1703.1 v1(84.81,195.5)
  TOP w0.305: R1638.2 85.77,195.47 v1(85.47,195.17)
  ART02 w0.229: J1702.10 64.16,209.68 ; J1702.10 64.16,207.62 ; J1702.10 62.77,208.65 ; J1702.10 65.54,208.65 ; 64.16,205.12 J1702.5 ; J1702.5 64.16,207.18 ; J1702.5 65.54,206.15 ; J1702.5 62.77,206.15 ; J1701.9 55.86,208.65 ; J1701.9 54.84,209.66 ; J1701.9 54.84,207.63 ; J1701.9 53.83,208.65 ; J1701.2 55.86,206.15 ; J1701.2 54.84,205.13 ; J1701.2 54.84,207.16 ; J1701.2 53.83,206.15
  ART05 w0.229: 64.16,205.12 J1702.5 ; J1702.5 64.16,207.18 ; J1702.5 65.54,206.15 ; J1702.5 62.77,206.15 ; J1701.2 55.86,206.15 ; J1701.2 53.83,206.15 ; J1701.2 54.84,205.13 ; J1701.2 54.84,207.16 ; 54.84,207.63 J1701.9 ; J1701.9 55.86,208.65 ; J1701.9 53.83,208.65 ; J1701.9 54.84,209.66 ; 62.77,208.65 J1702.10 ; J1702.10 64.16,209.68 ; J1702.10 65.54,208.65 ; J1702.10 64.16,207.62
  BOTTOM w0.203: v1(84.81,195.5) 84.56,194.89
  vias: v1(34.04,177.55) v1(34.04,176.78) v1(34.8,176.91) v1(66.17,190.55) v1(66.17,189.92) v1(66.22,187.73) v1(66.22,187.1) v1(66.24,185.55) v1(66.24,184.91) v1(66.8,190.55) v1(66.8,189.92) v1(66.85,187.73) v1(66.85,187.1) v1(66.88,185.55) v1(66.88,184.91) v1(67.44,190.55) v1(67.44,189.92) v1(67.49,187.73) v1(67.49,187.1) v1(67.51,185.55) v1(67.51,184.91) v1(68.07,190.55) v1(68.07,189.92) v1(68.12,187.73) v1(68.12,187.1) v1(68.15,185.55) v1(68.15,184.91) v1(68.71,190.55) v1(68.71,189.92) v1(68.76,187.73) v1(68.76,187.1) v1(68.78,185.55) v1(68.78,184.91) v1(69.34,190.55) v1(69.34,189.92) v1(69.39,187.73) v1(69.39,187.1) v1(69.42,185.55) v1(69.42,184.91)
PHY0_MDI0_N: length 29.9
  TOP w0.356: T1601.13 v1(232.83,189.34)
  BOTTOM w0.356: J1601.10 212.19,201.56 213.53,200.73 216.65,200.73 218.84,198.55 222.82,198.55 231.07,190.31 231.07,188.92 231.41,188.57 231.41,188.57 232.38,188.57 232.83,189.02 v1(232.83,189.34)
PHY0_MDI0_P: length 29.8
  TOP w0.356: T1601.14 v1(231.83,189.34)
  BOTTOM w0.356: J1601.9 212.37,202.63 212.45,202.3 213.75,201.5 216.97,201.5 219.15,199.31 223.14,199.31 227.94,194.51 228.22,194.51 228.44,194.72 228.72,194.72 228.92,194.52 228.92,194.24 228.71,194.03 228.71,193.74 228.91,193.54 229.19,193.54 229.41,193.75 229.69,193.75 229.89,193.55 229.89,193.27 229.68,193.06 229.68,192.77 231.83,190.62 v1(231.83,189.34)
PHY0_MDI1_N: length 41
  TOP w0.356: T1601.16 v1(229.83,189.34)
  ART03 w0.356: v1(229.83,189.34) 229.73,189.24 229.73,188.18 228.78,187.22 221.65,187.22 218.62,190.26 218.62,194.3 218.06,194.86 218.06,196.13 218.62,196.69 218.62,198.82 216.63,200.81 214.78,200.81 212.32,198.35 210.79,198.35 210.31,197.87 209.04,197.87 208.55,198.35 208.3,198.35 206.54,200.11 206.54,200.79 J1601.14
PHY0_MDI1_P: length 41
  TOP w0.356: T1601.17 v1(228.83,189.34)
  ART03 w0.356: v1(228.83,189.34) 228.97,189.21 228.97,188.49 228.46,187.98 221.97,187.98 219.38,190.58 219.38,199.14 216.94,201.57 214.47,201.57 212,199.11 208.62,199.11 207.3,200.43 207.3,201.67 208.09,202.45 208.09,202.45 208.13,202.49 208.97,202.49 J1601.11
PHY0_MDI2_N: length 29.6
  TOP w0.356: T1601.19 v1(226.83,189.34)
  BOTTOM w0.356: J1601.13 207.32,203.32 207.32,199.89 210.05,197.16 213.03,195.93 215.6,195.93 217.67,195.07 219.88,192.86 224,191.15 225.07,190.08 225.07,188.97 225.53,188.51 226.3,188.51 226.83,189.03 v1(226.83,189.34)
PHY0_MDI2_P: length 29.6
  TOP w0.356: T1601.20 v1(225.83,189.34)
  BOTTOM w0.356: v1(225.83,189.34) 225.83,190.4 224.43,191.8 223.5,192.18 223.37,192.51 223.6,193.07 223.49,193.34 223.23,193.44 222.97,193.34 222.72,192.74 222.46,192.64 222.19,192.73 222.08,192.99 222.33,193.6 222.23,193.86 221.96,193.97 221.7,193.86 221.45,193.25 221.19,193.14 220.31,193.5 218.1,195.72 215.75,196.69 213.18,196.69 210.48,197.81 209.57,198.72 209.57,199 209.97,199.4 209.97,199.68 209.77,199.88 209.48,199.88 209.08,199.49 208.8,199.49 208.08,200.2 208.08,200.83 J1601.12
PHY0_MDI3_N: length 27.9
  TOP w0.356: T1601.22 v1(223.83,189.34)
  BOTTOM w0.356: v1(223.83,189.34) 223.83,189.26 223.15,188.58 218.95,188.58 214.7,192.83 211.27,192.83 203.99,200.11 203.99,200.8 J1601.16
PHY0_MDI3_P: length 27.9
  TOP w0.356: T1601.23 v1(222.83,189.34)
  BOTTOM w0.356: v1(222.83,189.34) 219.26,189.34 217.41,191.2 217.41,191.48 217.56,191.63 217.56,191.92 217.36,192.12 217.07,192.12 216.92,191.97 216.64,191.97 215.01,193.59 211.59,193.59 204.75,200.43 J1601.15
PLL_X1: length 6.4
  TOP w0.203: R264.1 R301.1 7.48,127.88 7.75,128.14 7.75,128.52 6.73,129.54 C140.2 5.49,129.06 4.95,128.52 4.95,128.4 4.79,128.23 X3.1
PLL_X2: length 5.4
  TOP w0.203: U301.9 8.54,126.83 R264.2 8.3,126.24 8.09,126.03 7.06,126.03 6.77,126.33 X3.3 5.92,126.01 C141.2
PLLVDDL0: length 31.7
  TOP w0.203: U6.116 128.43,149.18 126.64,147.4 126.64,145.31 125.17,143.84 v1(122.58,143.84)
  ART03 w0.178: v1(104.22,146.56) 104.5,146.28 107.9,146.28 108.95,147.33 119.09,147.33 v1(122.58,143.84)
POWER_EN: length 442.3
  TOP w0.203: J3.301 53.1,119.65 53.34,119.89 53.34,120.4 52.45,121.28 v1(51.94,121.28) ; v1(73.38,20.98) 72.47,20.07 R250.1 ; R1036.2 v1(176.72,52.68) 177.29,52.68 177.98,53.36 177.98,53.67 R54.1 R51.2
  ART03 w0.178: v1(176.72,52.68) 176.72,53.66 173.03,57.34 v1(173.03,59.85) ; v1(194.31,146.05) 193.46,145.2 189.48,145.2 187.41,147.27 169.44,147.27 155.95,160.76 145.55,160.76 143.19,163.12 130.81,163.12 130.15,162.46 123.56,162.46 122.98,163.04 106.66,163.04 106.02,162.41 104.02,162.41 99.98,158.37 72.22,158.37 71,157.15 62.96,157.15 v1(59.83,154.01) ; v1(51.94,121.28) 51.94,122.43 50.24,124.13 50.24,136.86 53.21,139.83 54.86,139.83 v1(56.39,141.35)
  ART04 w0.178: v1(73.38,20.98) 75.98,18.38 127.91,18.38 131.22,15.08 137.03,15.08 145.37,23.42 155.71,23.42 159.36,27.07 159.36,28.24 159.82,28.69 159.82,31.39 159.75,31.45 159.75,31.58 159.74,31.59 159.74,34.31 160.11,34.67 160.11,49.54 163.5,52.93 164.34,52.93 171.25,59.85 v1(173.03,59.85) 173.69,60.5 181.34,60.5 184.02,63.19 184.02,64.01 192.91,72.9 192.91,80.52 196.5,84.1 196.5,143.86 v1(194.31,146.05)
  BOTTOM w0.203: v1(56.39,141.35) 60.33,145.29 60.33,152.04 59.83,152.53 v1(59.83,154.01)
POWER_LED_MCU_G: length 212.8
  TOP w0.203: v1(55.88,23.88) 55.98,23.77 R3616.1 57.4,23.77 R3619.1 ; R2835.2 v1(205.11,57.66)
  ART03 w0.178: v1(55.88,23.88) 55.88,22.17 59.89,18.16 64.88,18.16 71.82,11.23 80.44,11.23 80.91,10.76 148.01,10.76 152.49,15.24 162.23,15.24 165.39,18.4 166.04,18.4 168.91,21.27 170.12,21.27 174.12,25.27 174.82,25.27 175.29,25.74 176.09,25.74 177.89,23.94 186.83,23.94 189.31,26.42 193.22,26.42 195.01,24.62 205.6,24.62 207.19,26.21 211.18,26.21 216.79,31.82 216.79,35.86 212.61,40.03 212.61,44.94 211.82,45.73 211.82,48.37 208.81,51.38 208.81,54.97 207.07,56.72 206.05,56.72 v1(205.11,57.66)
POWER_LED_MCU_R: length 196.2
  TOP w0.203: R2832.2 206.86,54.63 v1(207.14,54.36) ; v1(59.56,23.88) 59.66,23.77 R3617.2 60.64,23.77 60.74,23.88 R3618.1
  ART03 w0.178: v1(207.14,54.36) 206.76,53.97 206.76,51.18 209.93,48.01 209.93,40.77 212.09,38.61 212.09,37.34 209.96,35.21 209.96,31.09 210.15,30.9 210.15,29.14 208.18,27.18 204.85,27.18 203.72,26.05 194.77,26.05 193.09,27.72 175.76,27.72 175.75,27.72 174.22,27.72 169.53,23.04 166.79,23.04 165.01,21.25 164.74,21.25 160.79,17.3 152.79,17.3 147.17,11.67 81.08,11.67 80.65,12.1 72.1,12.1 64.77,19.43 62.99,19.43 59.56,22.86 v1(59.56,23.88)
PWR_EN_5G: length 0.9
  TOP w0.203: R850.2 R117.1
PWR_TEC_BACKWARD: length 35.9
  TOP w0.381: R1115.2 211.48,57.91 v1(212.09,57.91) ; v1(221.11,55.24) 221.11,55.37 220.73,55.75 R1101.1 R1112.1 221.16,56.77 221.41,56.51 Q1105.3 ; R1102.1 228.02,40.74 v1(228.09,40.74)
  ART04 w0.381: v1(221.11,55.24) 220.11,55.24 219.59,55.76 219.59,57.19 218.87,57.91 v1(212.09,57.91)
  BOTTOM w0.381: v1(221.11,55.24) 221.11,49.68 223.55,47.24 226.82,47.24 228.09,45.97 v1(228.09,40.74)
PWR_TEC_FORWARD: length 40.8
  TOP w0.381: Q1106.3 212.06,53.26 C1107.1 R1120.1 212.85,52.07 v1(213.04,51.88) ; R1103.1 v1(219.96,40.66) ; R1108.1 v1(228.09,49.25)
  ART03 w0.381: v1(213.04,51.88) 213.04,50.76 214.55,49.25 v1(228.09,49.25)
  BOTTOM w0.381: v1(228.09,49.25) 227.52,48.68 227.52,47.56 228.85,46.23 228.85,40.69 228.24,40.08 220.55,40.08 v1(219.96,40.66)
RGMII0_MDCK: length 102.8
  TOP w0.203: R1236.1 v1(136.47,75.84) 136.65,76.02 136.65,77.72 136.45,77.93 R1246.2 R1245.1 ; v1(102.68,123.25) 102.62,123.19 101.47,123.19 100.85,123.81 J3.170
  ART03 w0.178: v1(136.47,75.84) 140.62,75.84 142.3,74.16 142.3,67.72 140.6,66.01 137,66.01 135.91,64.92 133.71,64.92 109.04,89.59 109.04,102.13 104.57,106.6 104.57,121.36 v1(102.68,123.25)
RGMII0_MDIO: length 100.8
  TOP w0.203: v1(105,121.59) 105,121.64 102.92,123.72 102.34,123.72 102.18,123.57 101.6,123.57 101.35,123.82 J3.172 ; R1247.2 136.14,76.2 135.99,76.04 135.99,75.56 v1(136.5,75.06) 136.93,75.06 137.03,74.95 R1235.1
  ART03 w0.178: v1(136.5,75.06) 136.86,75.42 140.62,75.42 141.92,74.11 141.92,67.88 140.44,66.4 136.84,66.4 135.75,65.3 133.87,65.3 109.42,89.75 109.42,102.29 105,106.71 v1(105,121.59)
RGMII0_RST: length 122.5
  TOP w0.203: J3.174 101.85,124.08 v1(101.85,124.08) ; R122.1 158.25,44.97 R347.1 157.72,44.84 157.2,44.32 155.79,44.32 v1(155.23,44.88) 154.99,45.12 154.99,45.14 154.94,45.19 154.94,45.23 154.85,45.32 R344.2
  ART03 w0.178: v1(155.23,44.88) 155.66,44.45 156.45,44.45 158.18,46.18 158.18,53.96 157.59,54.55 157.59,55.45 153.64,59.4 147.94,59.4 147.3,60.05 143.74,60.05 142.77,61.01 141.17,61.01 140.56,61.62 133.74,61.62 131.01,64.34 131.01,66.73 108.46,89.29 108.46,101.89 103.47,106.88 103.47,116.04 103.67,116.24 103.67,121.37 101.85,123.19 v1(101.85,124.08)
RGMII0_RST_R: length 71.2
  TOP w0.203: v1(140.13,80.8) 138.74,79.4 C1213.1 ; C1213.1 139.07,78.49 139.32,78.23 139.32,77.47 141.22,75.57 U1201.13 ; C1213.1 R1222.1 ; v1(168.38,44.4) 168.35,44.37 167.18,44.37 R140.2 ; R178.2 150.76,67.32 151.28,67.84 v1(152.21,67.84)
  ART03 w0.178: v1(140.13,80.8) 140.13,79.83 141.13,78.83 146.15,78.83 146.4,78.57 147.65,78.57 150.01,76.21 150.01,72.14 151.59,70.55 151.59,68.46 v1(152.21,67.84) 152.27,67.78 153.05,67.78 153.42,68.15 153.42,68.94 154.39,69.91 158.08,69.91 164.06,63.93 164.06,51.07 165.2,49.93 165.2,46.66 167.49,44.37 167.87,44.37 167.87,44.37 168.35,44.37 v1(168.38,44.4)
RGMII0_RXCK: length 76.9
  TOP w0.203: 141.45,67.44 v1(141.45,68.07) ; J3.202 108.85,122.66 107.91,121.73 107.91,121.65 v1(107.61,121.35)
  ART03 w0.178: v1(141.45,68.07) 141.45,69.14 140.89,69.7 140.28,69.7 139.7,69.11 138.09,69.11 135.72,71.48 133.53,71.48 111.33,93.67 111.33,103.08 108.15,106.25 108.15,114.63 108.51,114.99 108.51,116.28 107.61,117.18 v1(107.61,121.35)
RGMII0_RXD0: length 73.2
  TOP w0.203: v1(137.54,67.69) 137.8,67.44 138.26,67.44 ; J3.198 107.85,123.88 106.68,122.71 v1(106.68,122.11)
  ART03 w0.178: v1(137.54,67.69) 137.54,68.55 136.42,69.67 134.6,69.67 110.95,93.32 110.95,102.92 107.14,106.73 107.14,121.65 v1(106.68,122.11)
RGMII0_RXD1: length 75.3
  TOP w0.203: J3.196 107.35,124.11 106.17,122.94 106.17,121.82 v1(105.76,121.41)
  TOP w0.254: R1224.2 135.22,67.5 v1(135.13,67.41)
  ART03 w0.178: v1(105.76,121.41) 105.76,106.49 109.8,102.44 109.8,90.75 133.15,67.41 133.37,67.41 133.58,67.2 133.58,66.22 133.79,66.01 134.08,66.01 134.29,66.22 134.29,67.2 134.5,67.41 v1(135.13,67.41)
RGMII0_RXD2: length 75.8
  TOP w0.203: v1(105.54,122.17) 105.54,123.05 106.81,124.32 106.81,124.33 106.85,124.38 J3.194
  TOP w0.254: R1225.2 135.22,68.35 v1(135.13,68.26)
  ART03 w0.178: v1(135.13,68.26) 133.21,68.26 110.19,91.29 110.19,102.6 106.21,106.58 106.21,122.77 105.94,123.04 104.7,123.04 104.52,122.86 104.52,122.43 104.78,122.17 v1(105.54,122.17)
RGMII0_RXD3: length 78.7
  TOP w0.203: R1226.2 135.21,71.77 135.13,71.86 v1(135.13,71.96) ; J3.192 106.35,124.64 v1(105.42,123.71)
  ART03 w0.178: v1(105.42,123.71) 106.41,123.71 109.51,120.61 109.51,119.53 109.37,119.39 108.98,119.39 108.84,119.25 108.84,119.05 108.98,118.91 109.37,118.91 109.51,118.77 109.51,118.57 109.37,118.43 108.98,118.43 108.84,118.29 108.84,118.09 108.98,117.95 109.37,117.95 109.51,117.8 109.51,114.31 109.31,114.1 108.84,114.1 108.64,113.9 108.64,113.62 108.84,113.42 109.31,113.42 109.51,113.22 109.51,112.93 109.31,112.73 108.84,112.73 108.64,112.53 108.64,112.25 108.84,112.05 109.31,112.05 109.51,111.85 109.51,111.56 109.31,111.36 108.84,111.36 108.64,111.16 108.64,110.88 108.84,110.68 109.31,110.68 109.51,110.48 109.51,110.19 109.31,109.99 108.84,109.99 108.64,109.79 108.64,109.51 108.84,109.3 109.31,109.3 109.51,109.1 109.51,108.82 109.31,108.62 108.84,108.62 108.64,108.42 108.64,108.13 108.84,107.93 109.31,107.93 109.51,107.73 109.51,105.43 111.71,103.23 111.71,94.11 131.72,74.09 132.02,74.09 132.19,74.27 132.49,74.27 132.69,74.06 132.69,73.77 132.52,73.59 132.52,73.3 132.73,73.09 133.02,73.09 133.2,73.26 133.49,73.26 133.7,73.06 133.7,72.76 133.53,72.59 133.53,72.29 133.86,71.96 v1(135.13,71.96)
RGMII0_RXDV: length 78.3
  TOP w0.203: v1(140.42,68.88) 140.41,68.88 139.8,68.27 139.8,67.89 139.43,67.52 139.43,67.44 ; v1(106.68,121.35) 108.35,123.02 J3.200
  ART03 w0.178: v1(106.68,121.35) 106.68,106.65 110.57,102.76 110.57,92.84 134.67,68.73 135.71,68.73 137.26,67.18 138.71,67.18 v1(140.42,68.88)
RGMII0_TXCK: length 77.1
  TOP w0.203: v1(109.45,128.52) 109.02,128.96 R402.2 ; v1(139.5,72.69) 139.98,72.21 140.51,72.21 140.67,72.37 U1201.21
  ART03 w0.178: v1(139.5,72.69) 139.28,72.48 137.85,72.48 114.97,95.35 114.97,122.16 116.12,123.31 116.12,127.84 115.69,128.27 110.12,128.27 109.87,128.52 v1(109.45,128.52)
RGMII0_TXD0: length 80.8
  TOP w0.152: U1201.19 140.76,73.17 140.76,73.17 139.78,73.17 v1(139.5,73.45)
  TOP w0.203: R404.2 106.3,131.29 108.1,131.29 108.36,131.55 v1(108.36,131.6)
  ART03 w0.178: v1(108.36,131.6) 108.36,131.21 110.92,128.65 115.97,128.65 117.32,127.31 117.32,123.03 115.99,121.7 115.99,120.29 116.17,120.11 116.17,94.7 137.41,73.45 v1(139.5,73.45)
RGMII0_TXD1: length 86
  TOP w0.152: U1201.18 140.62,73.57 140.52,73.48 140.13,73.48 139.5,74.11 v1(139.5,74.22)
  TOP w0.203: v1(105.19,130.56) 104.94,130.81 R405.2
  ART03 w0.178: v1(139.5,74.22) 139.5,74.48 140.13,75.11 140.49,75.11 141.31,74.29 141.31,72.26 139.43,70.38 137.79,70.38 112.09,96.08 112.09,105.31 110.59,106.81 110.59,120.52 105.66,125.45 105.66,130.09 v1(105.19,130.56)
RGMII0_TXD2: length 82.9
  TOP w0.203: v1(140.31,73.91) 140.37,73.97 U1201.17 ; v1(105.19,131.7) 104.84,131.34 103.73,131.34 103.34,130.95 R406.2
  ART03 w0.178: v1(105.19,131.7) 105.25,131.7 106.63,130.32 106.63,125.89 109.54,122.99 111.32,122.99 112.65,121.66 112.65,118.78 113.07,118.36 113.07,96.18 137.53,71.71 139.91,71.71 140.7,72.51 140.7,73.52 v1(140.31,73.91)
RGMII0_TXD3: length 84.9
  TOP w0.203: R407.2 102.95,131.83 v1(104.15,131.83) ; U1201.16 140.61,74.37 v1(140.31,74.67)
  ART03 w0.178: v1(104.15,131.83) 104.45,131.53 104.46,131.53 104.97,131.03 105.39,131.03 106.04,130.37 106.04,125.81 109.25,122.61 110.3,122.61 111.63,121.27 111.63,116.08 112.69,115.02 112.69,96.02 137.38,71.33 139.96,71.33 141.01,72.38 141.01,73.97 v1(140.31,74.67)
RGMII0_TXEN: length 80.2
  TOP w0.203: R403.2 108.48,130.37 v1(108.48,129.72) ; v1(140.26,72.69) 140.26,72.7 140.33,72.77 U1201.20
  ART03 w0.178: v1(108.48,129.72) 108.48,128.86 109.46,127.89 115.64,127.89 115.82,127.71 115.82,123.64 115.4,123.23 115.36,123.23 113.72,121.58 113.72,119.4 113.45,118.76 113.45,96.34 137.69,72.09 139.66,72.09 v1(140.26,72.69)
RGMII1_MDCK: length 36.9
  TOP w0.203: v1(99.57,123.95) 98.48,122.86 93.29,122.86 91.85,124.3 J3.134 ; R1329.1 R1319.1
  TOP w0.254: R1329.1 v1(116.33,130.56)
  ART03 w0.178: v1(99.57,123.95) 99.57,127.76 103.68,131.87 103.68,132.02 103.96,132.3 108.32,132.3 108.9,131.72 108.9,131.21 110.94,129.17 115.26,129.17 116.33,130.24 v1(116.33,130.56)
RGMII1_MDIO: length 36.2
  TOP w0.203: R1325.2 R1334.1 ; v1(98.55,123.95) 97.84,123.24 93.55,123.24 92.35,124.44 J3.136
  TOP w0.254: R1334.1 v1(116.33,129.54)
  ART03 w0.178: v1(116.33,129.54) 116.8,130.01 116.8,130.75 116.53,131.03 115.58,131.03 113.98,132.63 112.2,132.63 112.15,132.68 103.8,132.68 103.3,132.18 103.3,132.03 98.55,127.28 v1(98.55,123.95)
RGMII1_RST: length 129
  TOP w0.203: R345.2 155.75,45.71 v1(155.75,45.57) 155.93,45.57 155.97,45.61 157.58,45.61 157.72,45.75 R348.1 158.2,46.23 158.28,46.31 158.53,46.31 R119.1 ; J3.138 92.85,124.41 93.58,123.67 94.21,123.67 v1(94.74,124.21)
  ART03 w0.178: v1(155.75,45.57) 156.06,45.57 157.65,47.15 157.65,53.74 157.06,54.33 157.06,55.23 153.42,58.86 147.72,58.86 147.09,59.5 143.45,59.5 142.53,60.43 136.84,60.43 136.18,61.09 133.33,61.09 131.91,62.51 125.16,62.51 107.29,80.38 107.29,101.97 99.64,109.61 99.64,119.3 v1(94.74,124.21)
RGMII1_RXCK: length 5.4
  TOP w0.203: R1324.2 101.46,130.48 101.17,130.18 101.17,128.9 99.85,127.59 J3.166
RGMII1_RXCK_R: length 20.9
  TOP w0.203: v1(101.78,133.04) 101.78,132.09 101.51,131.83 R1324.1 ; U6.62 114.1,142.38 113.56,141.84 113,140.5 113,139.37 112.7,139.06 C97.2 112.5,138.45 v1(112.28,138.24) 112.36,138.16 R184.2
  ART03 w0.178: v1(112.28,138.24) 110.98,136.94 110.17,136.4 109.05,135.93 108.58,135.84 108.05,135.73 107.88,135.7 104.29,135.7 104.28,135.7 101.78,133.19 v1(101.78,133.04)
RGMII1_RXD0: length 4
  TOP w0.203: J3.162 98.85,127.86 99.32,128.33 99.32,128.53 99.78,128.99 R1322.2
RGMII1_RXD0_R: length 24
  TOP w0.203: R204.2 110.65,138.03 v1(110.44,138.24) 110.44,139.04 C190.2 110.67,139.06 110.97,139.37 110.97,141.12 111.63,141.78 112.25,141.78 113.65,143.18 U6.60 ; R1322.1 99.62,130.36 99.62,131.29 v1(99.57,131.34)
  ART03 w0.178: v1(99.57,131.34) 100.43,132.39 100.8,133.29 103.19,135.68 103.89,136.39 104.19,136.46 107.81,136.46 108.22,136.54 109.13,136.92 v1(110.44,138.24)
RGMII1_RXD1: length 3.9
  TOP w0.203: J3.160 98.35,128.27 98.92,128.85 R1321.2
RGMII1_RXD1_R: length 25.6
  TOP w0.203: v1(98.81,131.35) 98.81,130.32 R1321.1 ; R257.2 109.79,138.25 v1(109.68,138.36) 109.68,138.83 C191.2 109.65,139.06 109.96,139.37 109.96,141.1 110.97,142.11 112.01,142.11 113.47,143.58 U6.59
  ART03 w0.178: v1(109.68,138.36) 108.37,137.05 108.02,136.91 104.4,136.91 103.63,136.71 103.18,136.53 101.98,135.73 98.81,132.55 v1(98.81,131.35)
RGMII1_RXD2: length 3.7
  TOP w0.203: J3.158 97.85,128.48 98.07,128.7 R1320.2
RGMII1_RXD2_R: length 27.5
  TOP w0.203: v1(97.98,131.95) 98.02,131.91 98.02,130.25 R1320.1 ; U6.58 114.06,143.98 113.99,143.91 113.23,143.91 111.81,142.49 110.68,142.49 110.1,141.91 109.17,141.91 108.08,140.82 108.08,139.37 108.38,139.06 C192.2 108.59,138.53 108.28,138.22 v1(108.28,137.7) 108.38,137.6 R258.2
  ART03 w0.178: v1(97.98,131.95) 98.05,132.34 98.05,133.54 99.86,135.35 100.24,135.73 101.94,136.69 104.35,137.29 106.18,137.29 v1(108.28,137.7)
RGMII1_RXD3: length 3.7
  TOP w0.203: R1318.2 97.21,128.11 97.35,127.97 J3.156
RGMII1_RXD3_R: length 28.6
  TOP w0.203: R1318.1 97.21,130.75 97.3,130.83 v1(97.3,131.27) ; U6.57 113.95,144.38 113.81,144.24 112.83,144.24 111.41,142.82 110.44,142.82 109.93,142.32 108.94,142.32 107.67,141.05 107.67,139.37 107.37,139.06 C193.2 107.16,138.86 107.51,138.52 v1(107.87,138.52) 107.87,138.39 107.87,138.39 107.87,138.15 107.44,137.72 R273.2
  ART03 w0.178: v1(107.87,138.52) 107.2,138.16 105.08,137.74 105.06,137.73 104.18,137.73 102.08,137.2 100.01,136.04 97.3,133.32 v1(97.3,131.27)
RGMII1_RXDV: length 4.2
  TOP w0.203: R1323.2 100.63,129.08 100.18,128.62 100.18,128.52 99.35,127.7 J3.164
RGMII1_RXDV_R: length 22.9
  TOP w0.203: v1(100.33,131.34) 100.63,130.61 R1323.1 ; U6.61 113.93,142.78 111.99,140.83 111.99,139.37 111.68,139.06 C189.2 111.48,138.37 v1(111.35,138.24) 111.5,138.08 R185.2
  ART03 w0.178: v1(100.33,131.34) 100.4,131.52 100.6,131.81 101.12,133.08 103.57,135.52 104.09,136.04 104.24,136.08 107.84,136.08 107.98,136.11 108.47,136.2 109.92,136.8 v1(111.35,138.24)
RGMII1_TXCK: length 27.6
  TOP w0.203: v1(96.25,131.06) 96.38,130.94 R408.2 ; C1317.2 113.24,138.33 113.5,139.6 v1(113.5,139.68) 113.84,141.42 113.91,141.58 114.31,141.98 U6.63
  ART03 w0.178: v1(96.25,131.06) 96.58,130.73 100.39,130.73 102.16,132.5 102.16,132.65 103.32,133.82 106.19,133.82 108.9,134.94 110.4,135.69 113.28,138.57 113.5,139.34 v1(113.5,139.68)
RGMII1_TXD0: length 30.1
  TOP w0.203: v1(95.53,131.95) 94.94,131.37 93.9,131.37 93.8,131.27 R410.2 ; U6.65 116.53,139.33 116.29,139.09 115.62,139.09 115.28,138.95 114.51,137.8 v1(114.3,137.29)
  ART03 w0.178: v1(95.53,131.95) 95.02,131.45 95.02,130.88 96.01,129.9 100.63,129.9 102.92,132.19 102.92,132.34 103.64,133.06 106.61,133.06 109.26,134.15 109.27,134.16 113.08,136.06 v1(114.3,137.29)
RGMII1_TXD1: length 32
  TOP w0.203: v1(115.7,138.56) 116.33,138.56 116.98,139.21 U6.66 ; R411.2 92.41,131.14 v1(91.49,132.05)
  ART03 w0.178: v1(115.7,138.56) 115.54,138.94 113.95,140.54 113.14,140.54 112.81,140.2 112.3,139.99 110.14,139.56 110,139.55 107.92,139.55 107.92,139.54 106.24,139.21 104.72,138.58 103.36,138.58 101.46,138.1 97.69,136.09 96.44,134.84 92.5,131.61 91.94,131.61 v1(91.49,132.05)
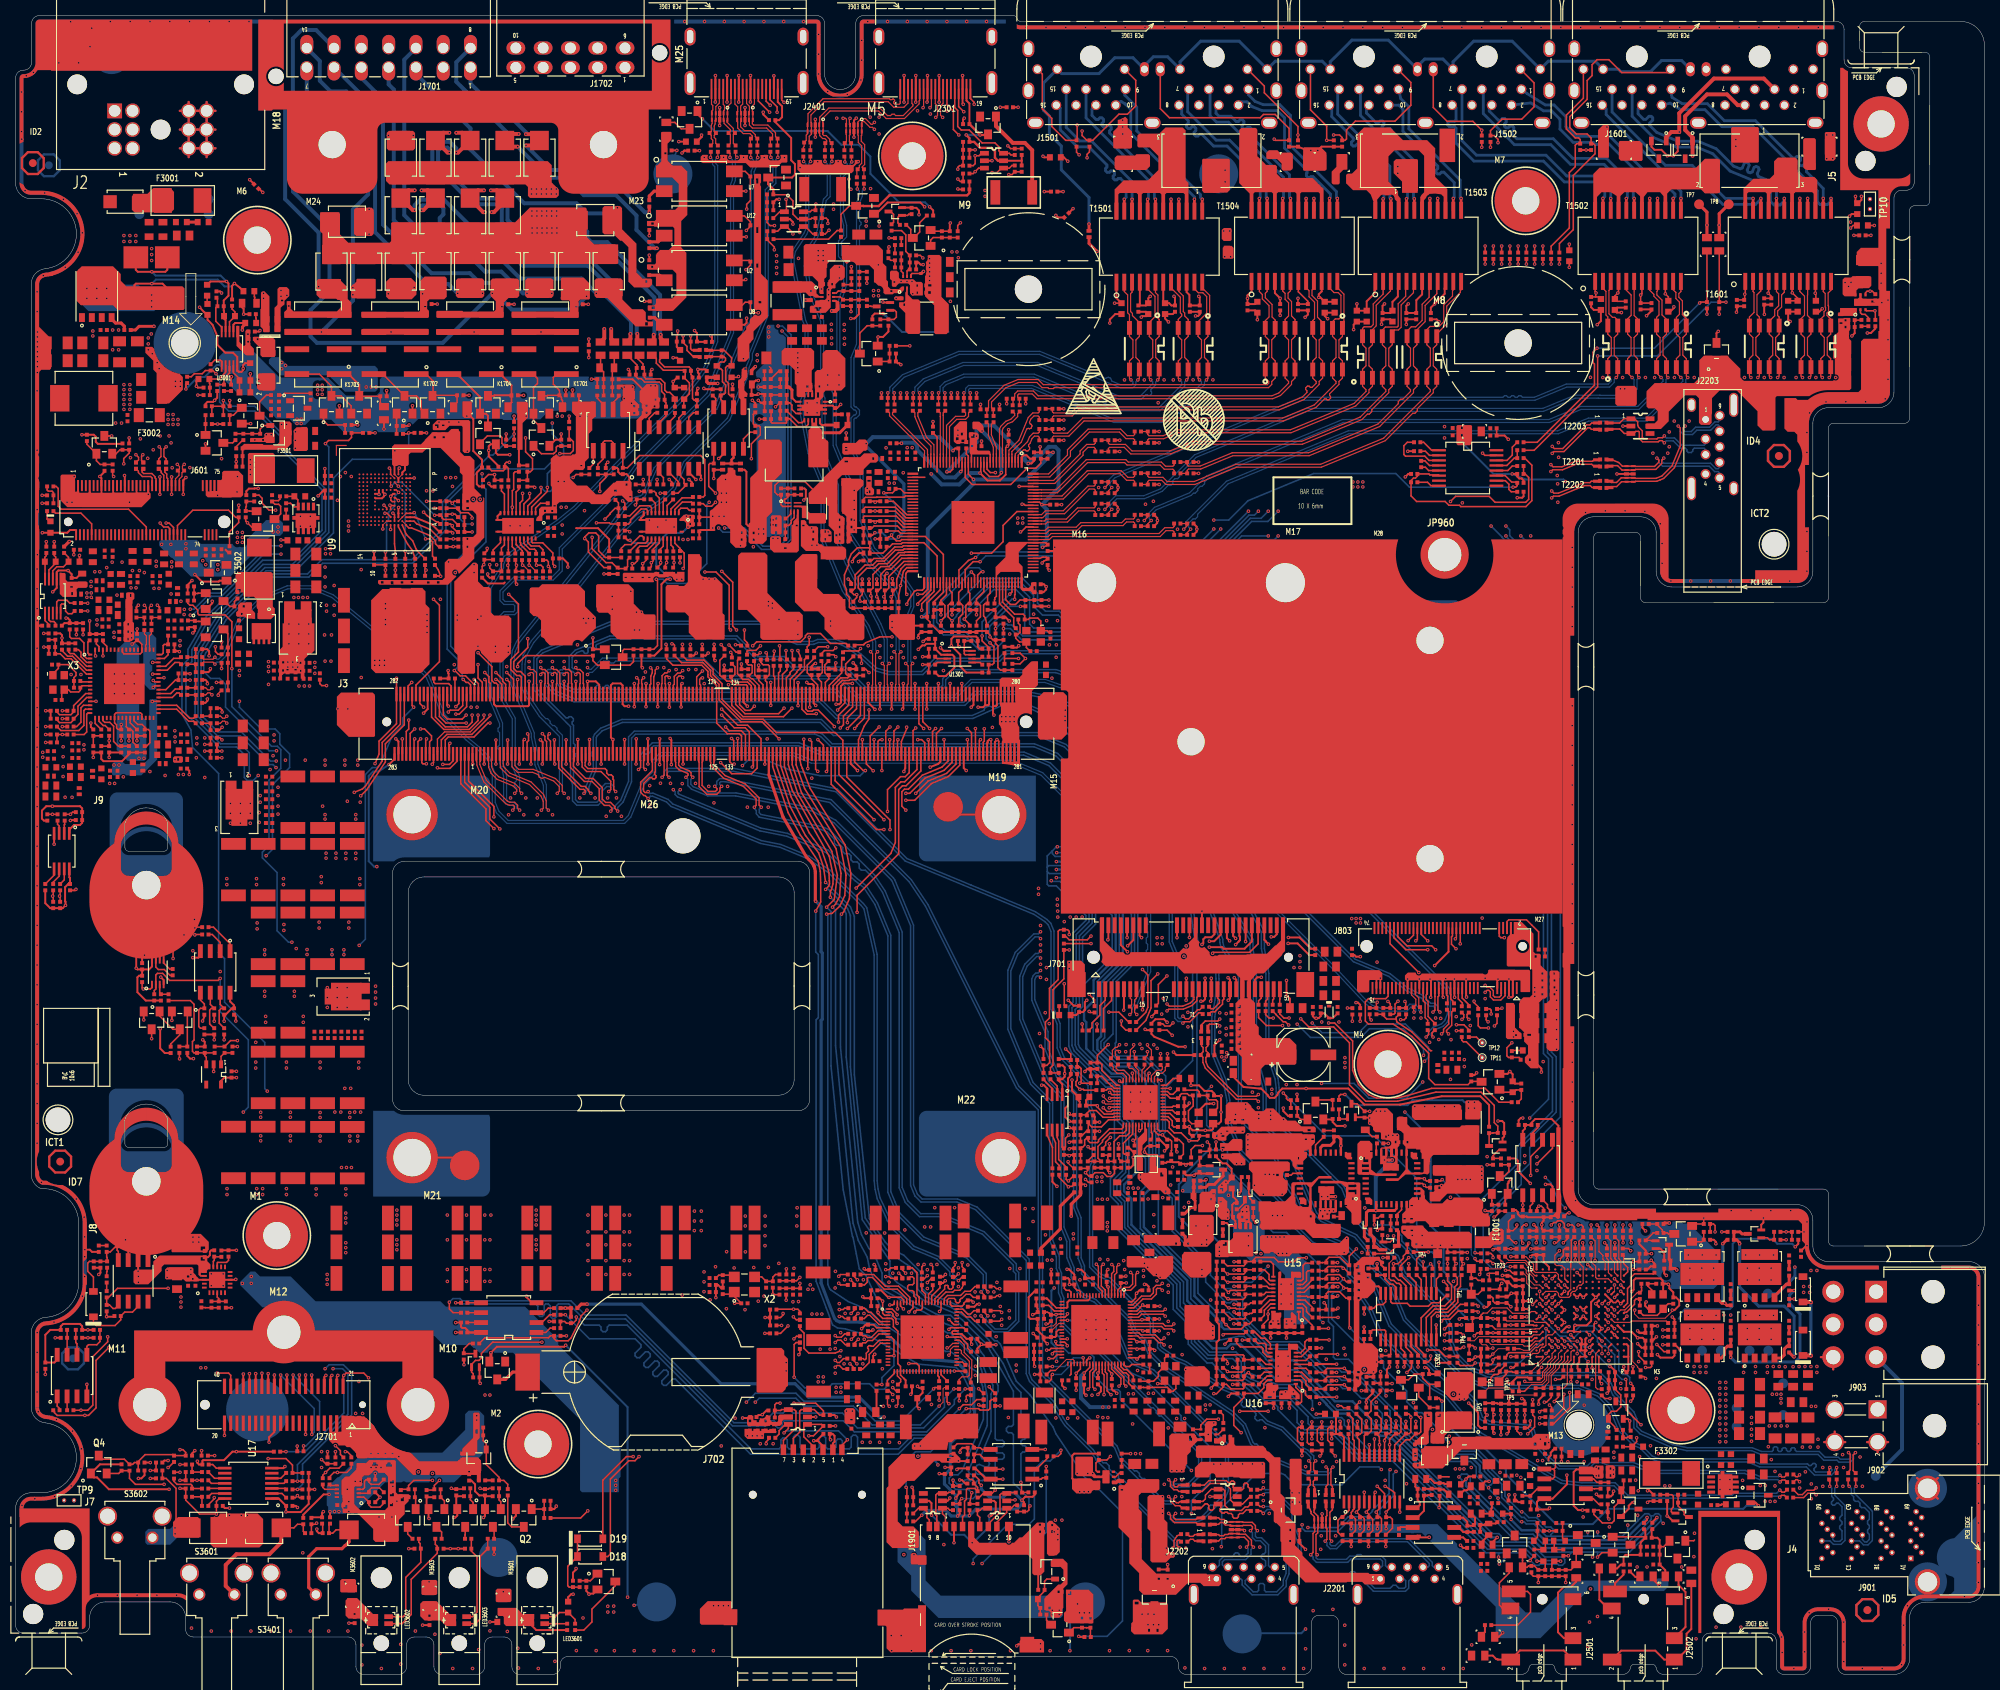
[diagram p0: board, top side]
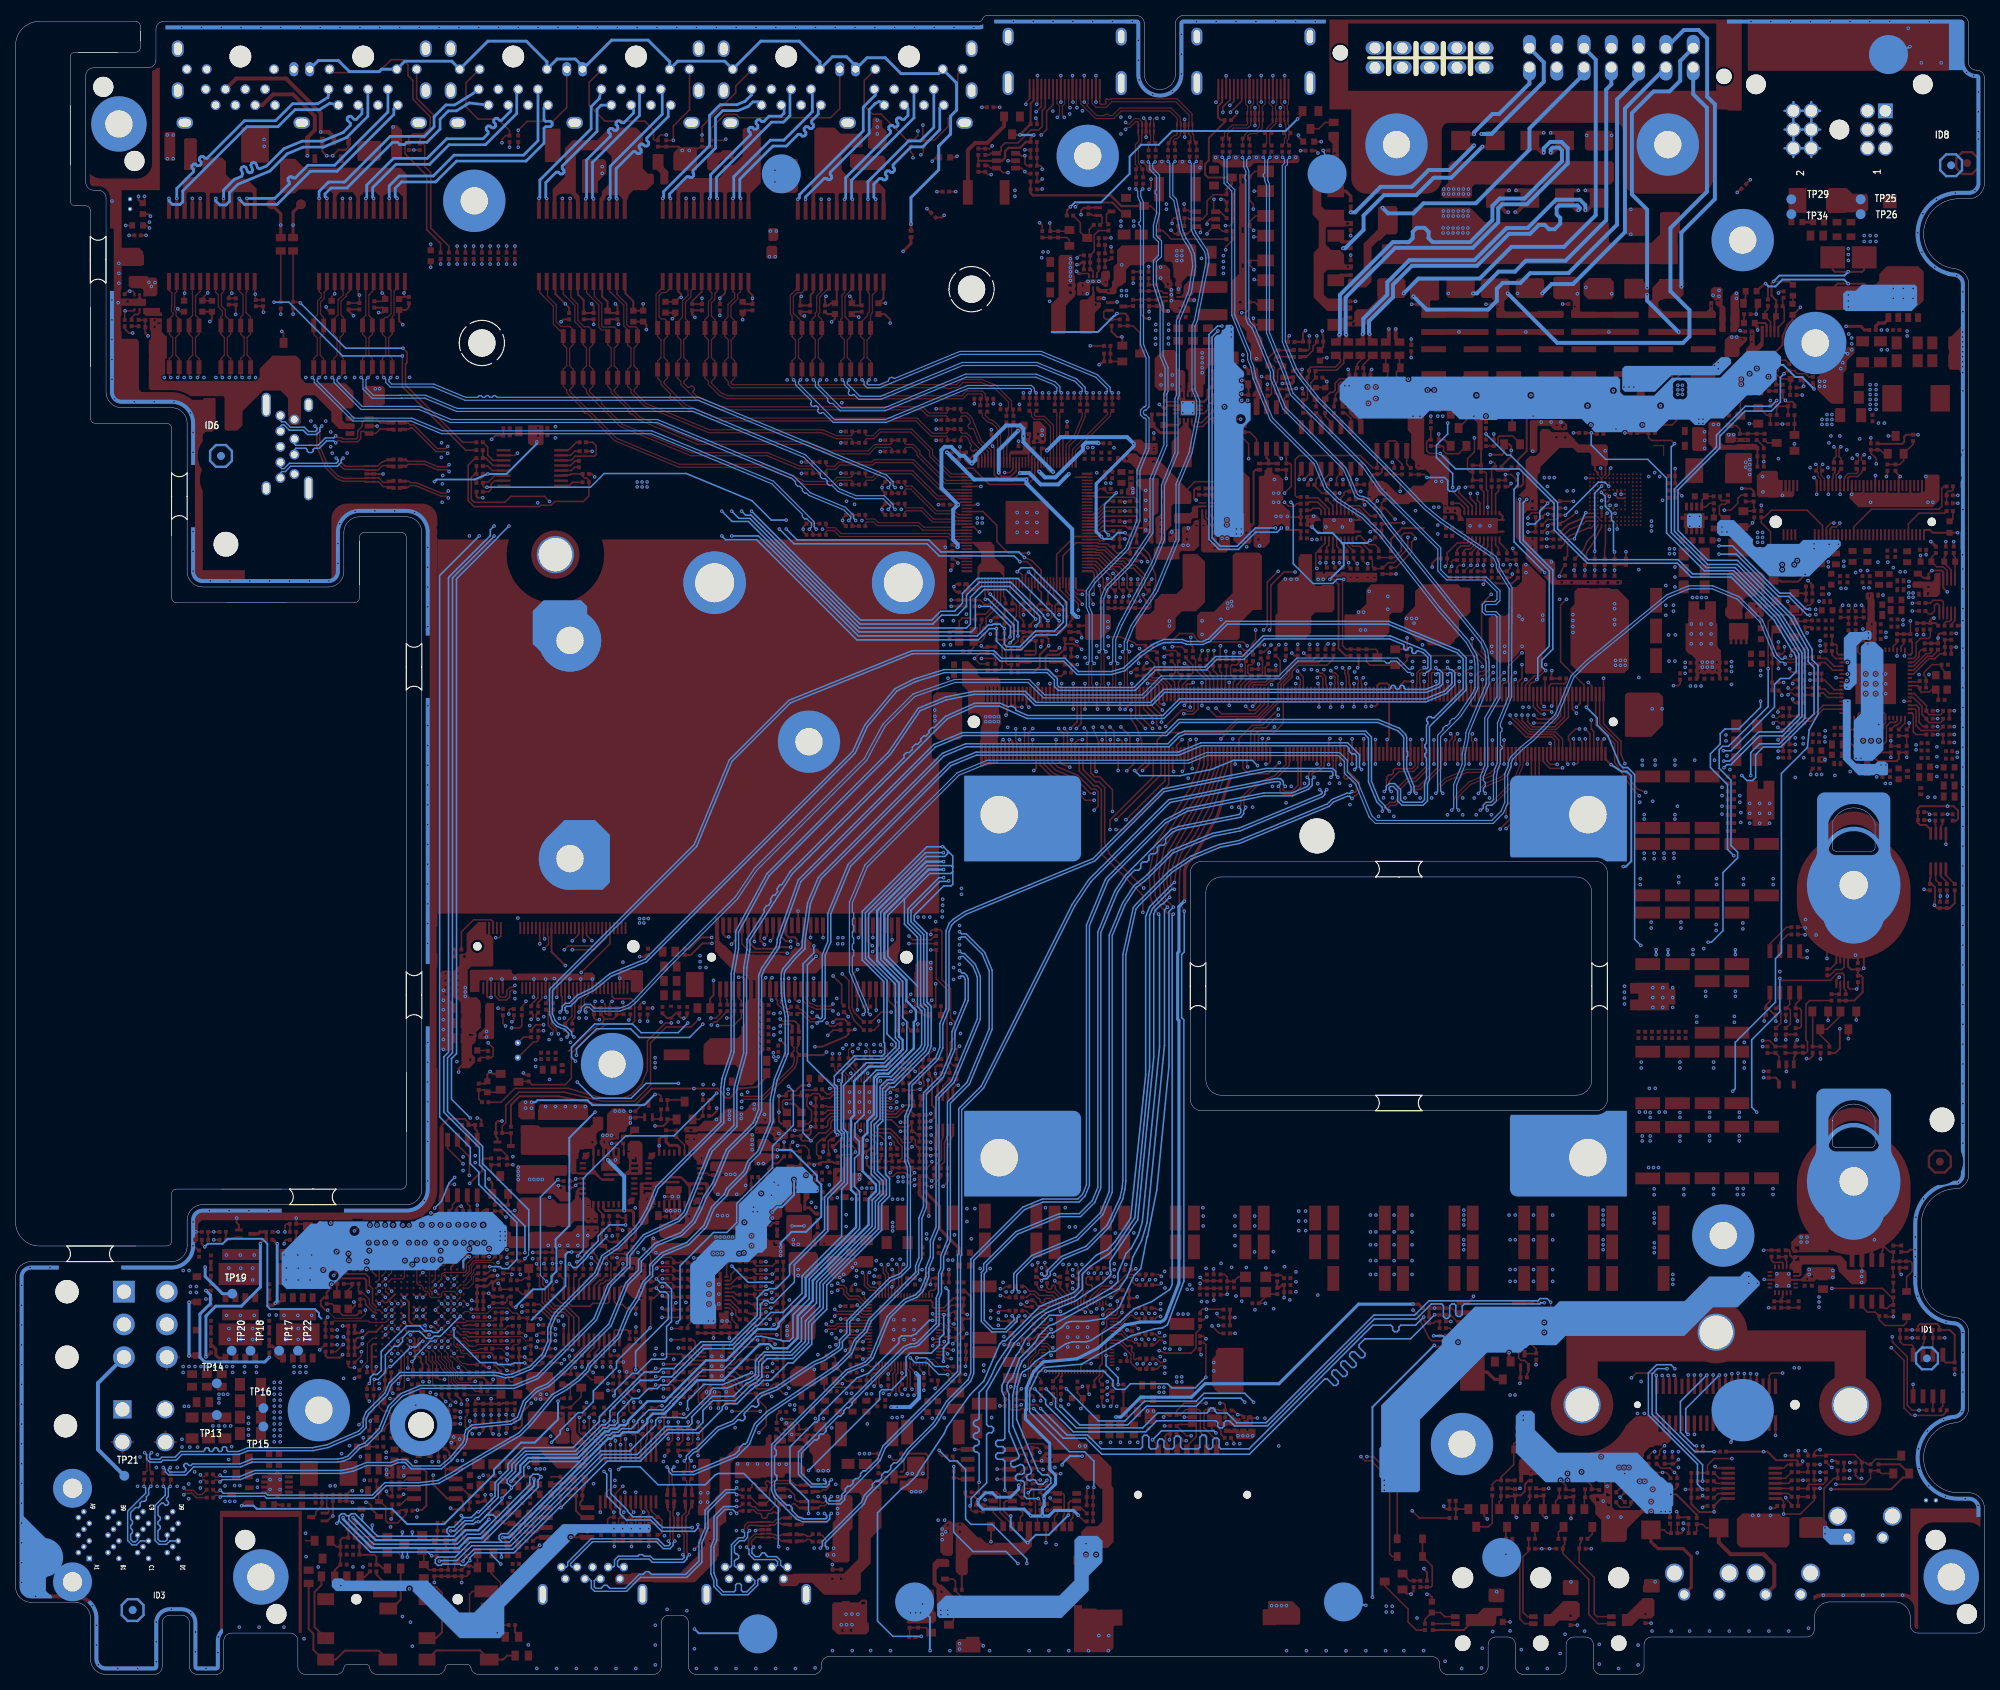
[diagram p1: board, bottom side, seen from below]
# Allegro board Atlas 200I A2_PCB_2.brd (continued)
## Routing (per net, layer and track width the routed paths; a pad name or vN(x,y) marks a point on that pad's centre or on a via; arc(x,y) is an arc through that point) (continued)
RGMII1_TXD2: length 32.3
  TOP w0.203: U6.67 117.38,139.09 115.7,137.41 v1(115.7,137.29) ; R412.2 91.86,130.89 91.72,131.04 v1(91.72,131.11)
  ART03 w0.178: v1(91.72,131.11) 92.49,131.11 92.77,131.23 93.47,131.7 94.2,132.43 95.79,133.28 98.01,134.76 99.03,135.6 100.17,136.73 102.08,137.81 103.51,138.17 104.73,138.17 106.27,138.81 108.08,139.17 110.11,139.17 112.44,139.63 113.01,139.87 113.3,140.15 113.69,140.15 115.09,138.75 v1(115.7,137.29)
RGMII1_TXD3: length 36.5
  TOP w0.203: R413.2 90.92,131.64 90.49,132.07 v1(90.49,132.1) ; U6.68 117.78,138.92 116.21,137.34 v1(116.21,136.52)
  ART03 w0.178: v1(116.21,136.52) 116.21,138.82 113.99,141.03 112.35,141.03 112.18,140.96 111.99,140.78 111.84,140.66 111.08,140.26 110.53,140.03 110.08,139.94 109.98,139.93 107.77,139.93 107.76,139.93 106.26,139.63 104.72,138.99 103.13,138.99 100.78,138.4 97.86,136.85 95.93,134.92 95.07,134.21 92.83,132.71 91.52,132.71 90.8,132.42 v1(90.49,132.1)
RGMII1_TXEN: length 26.9
  TOP w0.203: U6.64 114.43,141.53 114.25,141.35 114.17,141.16 114.17,138.68 v1(114.3,138.56) ; R409.2 95.24,130.81 v1(95.49,131.06)
  ART03 w0.178: v1(114.3,138.56) 113.23,136.95 112.77,136.49 112.73,136.43 112.69,136.41 112.62,136.35 109.07,134.57 109.07,134.57 106.34,133.44 103.48,133.44 102.54,132.49 102.54,132.35 100.52,130.33 96.23,130.33 v1(95.49,131.06)
RGMII_CLK_PHY0: length 7.5
  TOP w0.203: U1201.28 143.26,69.32 142.06,68.12 142.06,66.88 142.19,66.75 C184.1 142.62,65.84 R1242.1 R1240.2 141.5,66.11 141.5,66.58 R1227.1
RGMII_DV_PHY0: length 8.7
  TOP w0.203: R1228.1 C183.1 140.08,66.42 R1241.1 R1206.2 140.87,65.88 140.87,68.35 141.61,69.09 142.47,69.09 142.86,69.48 U1201.27
RGMII_PHY0_D0: length 10.2
  TOP w0.178: 139.4,68.32 138.81,67.73
  TOP w0.203: R1223.1 137.51,65.87 R1202.2 C188.1 R1203.1 138.81,66.23 138.81,67.73 ; U1201.26 142.46,69.81 142.11,69.47 140.35,69.47 139.4,68.51 139.4,68.32
RGMII_PHY0_D1: length 9.9
  TOP w0.203: R1239.1 C187.1 R1224.1 136.72,67.64 136.86,67.64 137.09,67.88 137.11,67.92 137.11,68.57 137.36,68.83 R1207.2 137.57,68.45 137.8,68.22 138.74,68.22 138.89,68.37 138.89,68.58 140.29,69.98 141.86,69.98 142.06,70.18 U1201.25
RGMII_PHY0_D2: length 7.6
  TOP w0.203: 137.57,70.69 138.02,70.23 139.24,70.23 140.16,71.14 140.97,71.14 141,71.17 U1201.24 ; 137.57,70.69 R1208.2 137.32,69.68 136.85,69.21 R1244.1 R1225.1 ; 137.57,70.69 C186.1
RGMII_PHY0_D3: length 7.4
  TOP w0.203: R1243.1 R1209.2 R1226.1 137.32,71.77 137.38,71.71 C185.1 137.39,71.98 137.74,72.34 138.59,72.34 139.46,71.48 140.83,71.48 140.86,71.5 140.93,71.57 U1201.23
RS232_RX: length 29.9
  TOP w0.406: LB1604.2 v1(218.49,185.93) 218.49,187.38 TP8.1
  TOP w0.508: v1(215.07,194.82) D17.1 215.07,197.17 214.12,198.12 214.12,199.9 216.92,202.69 219.48,202.69 220.86,201.31 J1601.6
  ART03 w0.406: v1(218.49,185.93) 218.49,187.91 215.07,191.33 v1(215.07,194.82)
RS232_TX: length 37.6
  TOP w0.406: LB1603.2 v1(216.92,185.93) 216.92,187.58 TP7.1
  TOP w0.508: D16.1 211.69,197.21 212.34,197.87 v1(213.36,197.87) 213.36,200.28 217.81,204.72 224.21,204.72 J1601.3
  ART03 w0.406: v1(213.36,197.87) 213.78,197.45 213.78,190.79 216.92,187.65 v1(216.92,185.93)
RS485_RXD_N: length 81.3
  TOP w0.508: v1(79.74,171.96) 79.74,171.21 LB1605.2 ; v1(51.18,187.84) 50.95,187.84 D1720.2 50.4,190.38 v1(51.18,190.38)
  ART04 w0.508: J1702.8 70.88,208.65 69.49,210.03 68.69,210.03 67.72,211 63.02,211 60.78,208.76 60.78,205.21 59.42,203.85 55.54,203.85 53.26,201.57 53.26,198.17 51.18,196.09 v1(51.18,190.38)
  BOTTOM w0.508: v1(79.74,171.96) 79.66,172.04 79.66,173.9 76.58,176.98 76.58,178.59 73.74,181.43 65.38,181.43 61.26,185.54 58.57,185.54 54.94,189.18 51.88,189.18 51.18,188.48 v1(51.18,187.84)
RS485_RXD_P: length 81.3
  TOP w0.508: v1(52.07,187.84) 52.3,187.84 D1721.2 52.86,190.38 v1(52.07,190.38) ; LB1606.2 78.85,171.33 v1(78.85,171.96)
  ART04 w0.508: J1702.9 67.91,208.9 67.91,209.73 67.4,210.24 63.33,210.24 61.54,208.45 61.54,204.89 59.74,203.08 55.85,203.08 54.03,201.26 54.03,197.85 51.94,195.77 51.94,195.22 52.45,194.71 54.05,194.71 54.56,194.2 54.56,193.19 54.05,192.68 52.45,192.68 51.94,192.17 51.94,190.5 v1(52.07,190.38)
  BOTTOM w0.508: v1(52.07,187.84) 51.92,187.99 51.92,188.17 52.19,188.44 54.53,188.44 54.86,188.11 54.86,187.3 54.4,186.83 54.4,186.11 55.12,185.4 55.84,185.4 56.4,185.96 57.12,185.96 58.27,184.81 60.96,184.81 65.08,180.7 73.43,180.7 75.85,178.28 75.85,176.68 78.93,173.6 78.93,172.04 v1(78.85,171.96)
RS485_TXD_N: length 73.2
  TOP w0.508: LB1608.2 81.84,171.18 v1(81.84,171.85) ; v1(56.51,195.23) 56.75,195.23 D1716.2 57.3,197.77 v1(56.51,197.77)
  ART04 w0.508: v1(56.51,197.77) 56.51,198.28 58.2,199.97 61.63,199.97 63.21,201.56 68.83,201.56 69.79,202.51 69.79,203.54 71.25,205 71.25,206.05 J1702.3
  BOTTOM w0.508: v1(81.84,171.85) 81.92,171.93 81.92,176.65 75.57,183.01 65.63,183.01 62.36,186.28 62.36,188.09 61.85,188.59 58.68,188.59 53.45,193.83 53.45,195.81 54.24,196.6 55.69,196.6 56.51,195.77 v1(56.51,195.23)
RS485_TXD_P: length 73.2
  TOP w0.508: v1(82.73,171.85) 82.73,171.37 LB1607.2 ; v1(55.63,195.23) 55.4,195.23 D1717.2 54.84,197.77 v1(55.63,197.77)
  ART04 w0.508: J1702.4 67.66,204.91 69.03,203.54 69.03,202.83 68.52,202.32 62.9,202.32 61.32,200.74 57.89,200.74 55.75,198.59 55.75,197.88 v1(55.63,197.77)
  BOTTOM w0.508: v1(82.73,171.85) 82.65,171.93 82.65,176.96 75.87,183.74 73.82,183.74 73.31,184.25 73.31,185.06 72.81,185.57 71.79,185.57 71.28,185.06 71.28,184.25 70.77,183.74 65.94,183.74 63.09,186.59 63.09,188.39 62.15,189.33 58.98,189.33 54.18,194.13 54.18,195.5 54.54,195.86 55.38,195.86 55.63,195.62 v1(55.63,195.23)
RST_5G_LTE: length 196.3
  TOP w0.203: R821.1 190.25,73.41 188.47,75.18 181.61,75.18 178.56,74.27 177.15,73.94 174.54,73.94 173.56,74.35 172.23,75.68 171.48,77.49 171.48,81.25 169.16,83.57 v1(168.4,83.57) ; v1(53.59,137.92) 54.36,137.16 54.36,129.92 51.35,126.91 J3.292
  ART03 w0.178: v1(168.4,83.57) 168.4,84.23 167.18,85.45 167.18,96.54 159.69,104.04 139.69,104.04 134.33,98.68 v1(133.6,98.68)
  ART04 w0.178: v1(53.59,137.92) 54.94,136.58 74.99,136.58 76.26,135.31 81.49,135.31 82.36,135.62 91.92,135.62 91.94,135.64 92.02,135.64 92.07,135.62 92.13,135.62 93.61,135.28 93.65,135.26 93.77,135.23 94.13,135.03 95.99,133.7 97.05,132.64 97.4,132.1 97.51,131.76 97.68,131.58 97.79,131.32 97.79,129.89 97.79,129.89 99.81,125.41 100.72,124.76 100.85,124.3 100.96,123.6 101.31,122.81 102.03,121.97 103.45,121.03 103.93,120.55 104.79,119.28 106.37,117.09 106.55,116.81 106.67,116.64 108.08,115.06 109.35,113.9 115.72,113.9 130.56,99.06 133.22,99.06 v1(133.6,98.68)
RSV_GPIO: length 308.2
  TOP w0.203: R390.2 154.97,39.32 v1(155.42,38.86) 155.5,38.79 157.28,38.79 157.53,39.04 R391.1 R288.1 ; R281.2 79.25,129.92 78.8,129.48 Q1.2 74.61,129.48 74.04,130.05 R280.2 65.42,130.7 64.39,129.67 v1(64.39,129.29) ; v1(46.1,116.84) 46.61,118.07 46.61,119.72 48.85,121.96 J3.282 v1(48.85,127.79)
  ART03 w0.178: v1(39.24,26.54) 40.13,27.43 42.43,27.43 44.57,29.57 59.45,29.57 72,17.02 114.31,17.02 115.03,16.3 115.42,16.3 116.25,17.13 119.35,17.13 120.18,16.3 128.66,16.3 132.68,20.31 133.66,20.31 v1(134.19,19.79)
  ART04 w0.178: v1(39.24,26.54) 36.93,24.23 36.93,22.96 36.37,22.4 35.55,22.4 33.02,24.93 33.02,32.94 27.89,38.07 27.89,44.88 24.13,48.64 24.13,52.45 25.27,53.59 25.27,58.29 24,59.56 24,72.52 27.31,75.82 27.31,84.71 28.32,85.72 28.32,98.42 29.97,100.08 29.97,105.02 32.26,107.3 32.26,111.38 33.15,112.27 34.48,112.27 38.74,116.52 38.74,117.29 39.3,117.86 45.09,117.86 v1(46.1,116.84) ; v1(48.85,127.79) 56.23,127.79 56.85,127.18 63.3,127.18 63.5,127.38 63.5,128.4 v1(64.39,129.29) ; v1(155.42,38.86) 155.02,38.45 155.02,35.15 152.69,32.82 151.69,32.82 139.9,21.03 135.43,21.03 v1(134.19,19.79)
RSV_GPIO_R: length 266.4
  TOP w0.203: v1(82.17,140.49) 82.17,140.46 82.32,140.31 82.32,131.98 81.85,131.51 R282.2 C170.1 R281.1 78.04,131.51 77.85,131.32 Q1.3 ; R2842.2 v1(200.03,55.37) ; R389.2 170.9,37.72 v1(170.41,38.21) 168.26,38.21 167.97,37.92 R388.2 167.96,37.69 R290.2
  ART03 w0.178: v1(88.95,150.37) 89.42,149.9 93.64,149.9 98.26,154.52 112.73,154.52 114.6,152.65 124.88,152.65 128,149.53 128,146.78 129.57,145.21 139.74,145.21 143.15,141.8 143.15,120.35 149.39,114.12 154.92,114.12 170.79,98.25 170.79,90.07 173.74,87.12 173.74,85.82 178.81,80.75 178.81,72.45 184.84,66.42 v1(188.72,66.42)
  ART04 w0.178: v1(170.41,38.21) 169.29,38.21 168.95,38.55 168.95,38.9 167.63,40.22 167.63,40.91 167.03,41.51 167.03,43.83 168.96,45.76 168.96,46.05 169.34,46.43 169.8,46.43 171.35,47.98 171.35,54.64 171.79,55.08 172.71,55.08 173.1,54.69 176.9,54.69 177.97,55.75 177.97,56.36 179.77,58.17 182.75,58.17 187.53,62.94 187.53,65.3 188.65,66.42 v1(188.72,66.42) 189.73,66.42 192.3,68.99 195.23,68.99 197.03,67.18 197.03,59.26 197.95,58.34 198.01,58.32 198.63,57.7 198.63,56.84 200.03,55.45 v1(200.03,55.37)
  BOTTOM w0.203: v1(88.95,150.37) 88.65,150.06 88.65,142.49 86.11,139.95 83.57,139.95 83.03,140.49 v1(82.17,140.49)
RSV_WAKE: length 102.3
  TOP w0.203: J3.141 93.6,120.52 93.07,121.06 91.54,121.06 v1(91.06,121.54)
  TOP w0.254: R247.2 166.12,93.09 164.67,94.54 v1(163.23,94.54)
  ART03 w0.178: v1(102.11,114.98) 100.62,116.46 100.62,118.95 94.93,124.65 93.67,124.65 91.06,122.04 v1(91.06,121.54) ; v1(163.23,94.54) 163.23,96.49 158.44,101.27 142.88,101.27 137.36,95.76 134.49,95.76 133.66,96.6 v1(133.66,97.15)
  ART04 w0.178: v1(102.11,114.98) 106.95,110.13 112.32,110.13 116.2,106.26 125.94,102.22 129.89,98.27 132.44,98.27 133.55,97.15 v1(133.66,97.15)
RTL8367_INT: length 14.6
  TOP w0.203: R1361.2 R1372.1 131.49,155.37 130.86,154.74 129.72,154.74 127.64,152.65 122.68,152.65 121.78,153.55 U6.19
SATA_LED: length 8.1
  TOP w0.203: R3611.1 R135.1 70.99,11.2 70.82,11.38 70.82,13.88 D18.1 72.06,17.4 D19.1
SATA_RX+: length 3.6
  TOP w0.188: R617.2 15.75,154.36 15.75,154.18 16.26,153.67 17.32,153.67 17.51,153.48 J601.41
SATA_RX-: length 3.6
  TOP w0.188: J601.43 18.01,153.37 17.89,153.49 17.89,153.64 17.48,154.05 16.42,154.05 16.23,154.24 16.23,154.5 R616.2
SATA_TX+: length 2.4
  TOP w0.188: C132.2 19.15,154.5 19.15,154.23 19.39,153.99 19.39,153.51 19.51,153.39 J601.49
SATA_TX-: length 2.4
  TOP w0.188: C133.2 18.67,154.36 18.67,154.17 19.01,153.83 J601.47
SD_CLK: length 9.3
  TOP w0.203: R64.1 122.1,25.27 122.35,25.02 122.66,25.02 122.89,24.79 R63.2 123.38,23.99 R77.2 123.02,23.85 122.08,23.85 121.94,23.71 121.94,22.46 121.7,22.23 121.7,20.45 121.45,20.2 J1901.5
SD_CMD: length 3.6
  TOP w0.203: U1901.6 123.97,21.32 123.71,21.06 R1904.2 123.35,20.45 123.65,20.15 J1901.3
SD_DATA0: length 4
  TOP w0.203: J1901.7 119.25,20.23 118.87,20.61 U1902.1 119.57,21.32 119.81,21.07 R1905.2
SD_DATA1: length 6.4
  TOP w0.203: R1906.2 119.66,23.36 119.52,23.22 U1902.3 118.22,23.22 118.02,23.01 118.02,20.45 118.15,20.32 J1901.8
SD_DATA2: length 4.4
  TOP w0.203: R1902.2 128.08,21.71 127.69,21.32 U1901.1 127.11,20.78 125.85,19.52 J1901.1
SD_DATA3: length 6.8
  TOP w0.203: R1903.2 127.39,23.32 127.28,23.22 U1901.3 126.44,23.22 126.25,23.02 126.25,20.81 124.75,19.31 J1901.2
SDIO_CLK: length 111.2
  TOP w0.203: v1(125.63,23.64) 125.21,23.22 U1901.4 124.11,23.22 123.57,22.68 R77.1 ; J3.169 100.6,117.28 100.72,116.69 100.9,116.24 100.91,116.24 101.05,115.86 101.9,113.66 106.39,106.41 107.13,102.69 106.93,99.51 106.2,97.81 v1(105.92,97.54)
  BOTTOM w0.203: v1(125.63,23.64) 125.63,27.36 125.87,27.6 126.56,27.6 126.8,27.84 126.8,28.17 126.56,28.41 125.87,28.41 125.63,28.65 125.63,28.98 125.87,29.22 126.56,29.22 126.8,29.46 126.8,29.8 126.56,30.04 125.87,30.04 125.63,30.27 125.63,35.46 126,36.35 126,37.06 124.18,40.91 123.82,41.35 122.96,43.03 119.91,46.08 118.47,46.08 117.97,46.28 114.14,48.29 112.06,49.54 111.96,49.58 111.13,50.42 111.13,51.48 110.08,54.01 109.43,54.65 108.49,56.41 108,58.03 105.79,80.47 105.79,97.41 v1(105.92,97.54)
SDIO_CMD: length 115.7
  TOP w0.203: R1904.1 R1911.2 v1(122.63,23.31) ; v1(104.02,97.54) 104.72,97.64 105.71,98.56 106.35,99.92 106.51,102.51 105.81,106.19 101.2,113.64 100.1,116.69 J3.167
  BOTTOM w0.203: v1(104.02,97.54) 104.17,97.38 104.17,50.05 104.41,49.46 104.57,49.31 106.77,47.83 109.09,46.87 110.83,45.24 114.59,42.85 115.19,42.67 116.96,42.67 117.85,42.4 119.25,41.43 119.86,41.43 121.77,40.12 122.45,39.33 123.38,38.78 123.53,38.49 124.03,36.9 124.12,35.92 124.12,32.73 121.39,26.14 120.85,25.6 120.14,25.6 119.74,25.2 119.74,24.54 120.55,23.72 122.21,23.72 v1(122.63,23.31)
SDIO_DATA0: length 113.4
  TOP w0.203: v1(104.78,98.42) 105.16,98.81 105.68,99.8 105.86,102.77 105.22,105.93 100.79,113.11 99.6,116.69 J3.165 ; v1(121.35,22.56) 121.08,22.29 R1910.2 R1905.1
  BOTTOM w0.203: v1(104.78,98.42) 105.16,98.04 105.16,80.69 107.4,57.91 108.08,55.65 109.23,53.52 109.52,52.05 109.98,50.94 110.94,49.49 119.36,44.92 119.53,44.89 120.04,44.68 121.26,43.46 121.74,42.55 123.72,40.56 124.69,38 125.17,37.52 125.35,37.08 125.35,36.55 125.1,35.94 125.1,31.18 123.78,28 123.91,27.69 124.77,27.33 124.9,27.02 124.77,26.71 124.46,26.58 123.6,26.94 123.29,26.81 123.13,26.43 123.13,25.91 123.36,25.68 124.02,25.68 124.26,25.44 124.26,25.1 124.02,24.86 123.36,24.86 123.13,24.63 123.13,22.87 122.81,22.56 v1(121.35,22.56)
SDIO_DATA1: length 110.1
  TOP w0.203: v1(104.01,98.42) 104.99,99.4 105.39,102.52 104.67,105.59 100.33,112.96 99.1,116.69 J3.163 ; R1909.2 R1906.1 v1(120.23,24.92)
  BOTTOM w0.203: v1(120.23,24.92) 120.73,24.41 121.39,24.41 121.58,24.61 121.7,24.89 122.01,25.02 122.43,24.84 122.74,24.97 122.87,25.28 122.74,25.59 122.32,25.77 122.19,26.08 124.61,31.92 124.61,35.74 124.38,36.91 124.37,37.02 123.86,39.11 123.4,40.21 120.16,43.46 120.16,43.53 119.89,43.8 119.51,43.8 118.36,44.5 117.8,45.05 117.39,45.22 117.07,45.29 115.32,45.29 112.77,45.67 110.97,47.07 109.06,51.18 108.2,52.03 107.82,53.97 107.4,56.07 107.32,56.21 106.14,62.15 104.58,78.06 104.58,97.86 v1(104.01,98.42)
SDIO_DATA2: length 111.9
  TOP w0.203: v1(130.1,21.61) 129.96,21.47 129.96,21.1 129.75,20.89 R1908.2 R1902.1 ; J3.161 98.6,116.48 99.61,113.4 104.35,104.94 104.85,102.52 104.83,101.42 104.63,100.67 104.5,100.46 v1(104.5,99.69)
  BOTTOM w0.203: v1(104.5,99.69) 105.33,98.86 105.59,98.75 106.34,98.01 106.53,97.54 106.53,79.21 108.58,58.34 112.14,53.01 112.14,51.77 112.04,51.66 112.04,51.28 112.14,51.18 112.14,51.18 113.05,50.28 116.54,47.94 120.3,46.38 121.45,45.44 124.47,42.42 124.58,42.22 124.97,41.53 125.47,40.7 127.97,36.34 127.97,32.05 127.73,31.81 127.31,31.81 127.08,31.58 127.08,31.24 127.31,31 127.73,31 127.97,30.76 127.97,24.56 129.96,22.57 129.96,21.76 v1(130.1,21.61)
SDIO_DATA3: length 110.3
  TOP w0.203: R1907.2 129.11,23.35 R1903.1 129.01,23.4 129.01,24.56 v1(128.93,24.64) ; v1(103.89,100.71) 104.28,101.12 104.39,101.42 104.37,101.8 104.36,101.81 104.32,102.81 104.06,103.78 103.37,105.8 102.34,107.17 101.8,107.95 99.46,112.56 98.1,116.61 J3.159
  BOTTOM w0.203: v1(103.89,100.71) 104.24,100.71 106.69,98.26 107.06,97.36 107.06,77.94 108.97,58.56 111.61,54.61 112.28,53.94 114.72,52.31 115.7,51.33 115.7,49.4 116.64,48.46 120,47.08 121.92,45.8 124.87,42.85 125.21,42 126.67,39.86 127.4,38.24 127.89,37.34 128.4,36.69 128.93,36.16 128.93,32.84 129.17,32.6 129.4,32.6 129.64,32.36 129.64,32.02 129.4,31.79 129.17,31.79 128.93,31.55 128.93,31.21 129.17,30.97 129.4,30.97 129.64,30.74 129.64,30.4 129.4,30.16 129.17,30.16 128.93,29.92 128.93,29.59 129.17,29.35 129.4,29.35 129.64,29.11 129.64,28.77 129.4,28.54 129.17,28.54 128.93,28.3 v1(128.93,24.64)
SDIO_DETECT: length 117.5
  TOP w0.203: R1918.2 R1912.1 C1901.1 R1901.1 114.31,23.9 v1(114.21,24.01) ; J3.155 97.1,116.45 99.08,110.54 100.65,107.66 100.89,107.35 102.92,104.32 103.2,103.02 103.25,101.53 103.25,99.09 v1(102.62,97.92)
  BOTTOM w0.203: v1(102.62,97.92) 102.62,92.68 102.95,92.34 102.95,84.26 102.67,83.97 102.67,50.44 103.96,47.04 104.78,44.83 105.41,44.45 106.43,44.32 109.47,43.43 115.77,39.8 120.64,39.37 121.34,38.66 122.45,36.38 122.45,33.68 117.34,28.56 115.41,28.56 114.21,27.37 v1(114.21,24.01)
SDIO_POWER_EN: length 135.2
  TOP w0.203: v1(103.89,101.6) 103.61,103.59 102.99,105.38 101.31,107.61 99.35,111.31 97.6,116.53 J3.157 ; R1915.1 136.6,4.8 136.57,4.82 136.41,4.82 v1(136.34,4.88)
  BOTTOM w0.203: v1(103.89,101.6) 103.94,101.6 107.06,98.48 107.57,97.24 107.57,76.93 109.5,58.49 111.52,55.48 112.47,54.48 113.93,53.76 116.17,51.52 116.17,49.62 116.81,48.98 121.14,47.21 125.55,42.8 125.87,42.8 126.29,42.37 128.35,37.62 130.1,35.86 133.07,31.72 133.41,30.89 136.65,26.03 136.92,25.5 138.11,24.34 138.9,23.79 141.96,20.73 141.96,6.86 139.99,4.88 v1(136.34,4.88)
SDIO_VOUT: length 144.7
  TOP w0.203: R1911.1 122.34,20.38 v1(122.33,20.37) ; v1(116.22,20.42) 115.42,19.63 R1918.1 ; v1(123.85,24.26) 123.55,24.56 123.55,24.99 123.04,25.5 122.95,25.5 R64.2
  TOP w0.254: v1(120.81,20.32) 121.08,20.59 R1910.1 ; R1909.1 v1(120.58,22.61) ; R1908.1 129.34,22.08 v1(129.06,22.35) 129.48,22.78 130.43,22.78 130.71,23.06 R1907.1
  TOP w0.305: J3.153 96.6,115.41
  TOP w0.406: v1(102.62,99.19) 102.57,99.24 102.57,102.8 102.57,102.99 102.48,103.44 102.45,103.51 102.41,103.69 102.34,103.76 102.31,103.85 102.07,104.21 101.76,104.52 101.43,104.85 98.4,110.04 96.6,115.41
  BOTTOM w0.381: v1(122.33,20.37) 123.16,21.21 128.45,21.21 129.06,21.82 v1(129.06,22.35) 128.12,23.29 127.23,23.29 126.67,22.73 124.89,22.73 123.85,23.77 v1(123.85,24.26)
  BOTTOM w0.406: v1(102.62,99.19) 103.3,98.5 103.3,92.71 103.46,92.55 103.46,84.05 103.3,83.89 103.3,50.2 105.02,45.69 105.29,45.39 105.69,45.21 108.22,45.21 110.24,44.83 113.71,41.85 116.4,40.48 120.68,40.1 121.91,38.87 122.89,36.7 122.89,33.96 122.99,33.86 122.99,32.77 119.86,29.64 119.86,26.29 119.13,25.55 119.13,24.43 120.58,22.97 v1(120.58,22.61) 120.58,21.6 120.81,21.38 v1(120.81,20.32) ; v1(120.81,20.32) 122.28,20.32 v1(122.33,20.37) ; v1(120.81,20.32) 119.99,20.32 119.28,21.03 116.82,21.03 v1(116.22,20.42)
SENSE_LTE_3V3: length 17
  TOP w0.102: v1(203.46,41.15) 203.46,41.95
  TOP w0.203: R2824.1 v1(193.55,33.27) R2825.2 ; 203.46,41.95 U3.L3
  ART04 w0.178: v1(203.46,41.15) 202.94,40.64 201.17,40.64 196.47,35.94 194.61,35.94 194.08,35.41 194.08,33.81 v1(193.55,33.27)
SENSE_LTE_3V8: length 18.9
  TOP w0.102: 199.46,43.55 v1(199.46,43.57)
  TOP w0.203: R2821.1 188.47,33.53 v1(188.72,33.27) 188.47,33.02 R2820.2 ; U3.G4 199.46,43.55
  ART04 w0.178: v1(199.46,43.57) 199.16,43.86 197.03,43.86 195.5,42.34 195.5,41.33 189.74,35.56 189.74,34.29 v1(188.72,33.27)
SENSE_TEC_OUT: length 15.3
  TOP w0.203: U3.K2 v1(201.87,41.17) ; R2823.2 v1(192.53,33.27) R2822.1
  ART04 w0.178: v1(201.87,41.17) 201.06,41.17 198.5,38.61 197.1,38.61 194.82,36.32 194.45,36.32 193.68,35.54 193.68,34.42 v1(192.53,33.27)
SENSE_VBAT_3V0: length 41.1
  TOP w0.203: v1(202.18,39.31) 202.18,40.68 U3.K1 ; R3216.2 R3217.2 198.27,27.3 v1(198.25,27.28) ; R3221.2 191.47,22.99 v1(191.52,23.04)
  ART03 w0.178: v1(198.25,27.28) 198.78,27.81 201.8,27.81 204.09,30.1 206.76,30.1 207.96,31.3 207.96,32.32 208.53,32.89 208.53,35.4 210.95,37.81 210.95,38.13 210.47,38.61 204.34,38.61 203.64,39.31 v1(202.18,39.31)
  ART04 w0.178: v1(191.52,23.04) 191.81,23.33 191.81,23.38 192.18,23.75 193.5,23.75 197.04,27.29 198.23,27.29 v1(198.25,27.28)
SENSE_VCC_3V3: length 15.5
  TOP w0.102: v1(200.27,41.15) 200.27,41.94
  TOP w0.203: 200.27,41.94 U3.G3 ; R2818.2 v1(191.52,33.27) R2819.1
  ART04 w0.178: v1(191.52,33.27) 192.66,34.42 192.66,35.54 193.82,36.7 194.44,36.7 196.85,39.12 198.23,39.12 v1(200.27,41.15)
SENSE_VCC_5V0: length 15.5
  TOP w0.203: R2816.1 v1(190.5,33.27) R2817.2 ; v1(199.47,41.95) 199.07,42.35 U3.F3
  ART04 w0.178: v1(199.47,41.95) 199.47,41.06 198.04,39.62 196.72,39.62 194.18,37.08 193.67,37.08 192.15,35.57 192.15,34.92 v1(190.5,33.27)
SENSE_VIN_12V0: length 16
  TOP w0.203: U3.E3 198.27,42.35 v1(198.67,41.95) ; R2814.2 189.48,33.15 189.61,33.27 v1(189.61,33.32) 189.48,33.45 R2815.1
  ART04 w0.254: v1(198.67,41.95) 198.67,41.19 197.61,40.13 195.2,40.13 190.91,35.84 190.91,34.62 v1(189.61,33.32)
SERDES0_RX_N: length 76.2
  TOP w0.188: v1(16.32,156.47) 16.15,156.3 16.15,155.7 R616.1 ; J3.38 67.85,127.06 67.91,127.12 67.91,128.34 67.72,128.52 67.54,128.52 67.35,128.34 v1(67.35,128.27)
  ART04 w0.152: v1(16.32,156.47) 16.07,156.72 16.07,156.82 16.22,156.97 16.61,156.97 17.76,155.83 22.07,155.83 23.47,154.43 23.47,153.77 23.32,153.61 23.11,153.61 22.96,153.46 22.96,153.16 23.11,153.01 23.32,153.01 23.47,152.86 23.47,152.55 23.32,152.4 23.22,152.4 23.06,152.25 23.06,151.94 23.22,151.79 23.32,151.79 23.47,151.64 23.47,146.7 24.94,143.14 24.94,141.65 25.41,140.52 29.66,136.27 38.63,136.27 40.25,134.64 41.61,134.64 44.04,132.21 44.93,131.84 48.07,131.22 53.95,130.05 63.57,130.05 64.43,130.4 66.06,130.4 66.42,130.04 66.42,129.15 66.8,128.77 67.06,128.77 67.35,128.48 v1(67.35,128.27)
SERDES0_RX_P: length 76.1
  TOP w0.188: R617.1 15.77,155.8 15.77,156.13 v1(15.43,156.47) ; v1(67.35,129.16) 67.35,129.09 67.54,128.91 67.88,128.91 68.29,128.49 68.29,127.12 68.35,127.06 J3.40
  ART04 w0.152: v1(15.43,156.47) 15.68,156.72 15.68,156.98 16.06,157.35 16.77,157.35 17.91,156.21 22.23,156.21 23.85,154.58 23.85,146.77 25.32,143.22 25.32,141.72 25.73,140.73 29.82,136.65 38.79,136.65 40.41,135.03 41.76,135.03 44.26,132.53 45.04,132.21 53.99,130.43 63.49,130.43 64.35,130.78 66.22,130.78 66.8,130.2 66.8,129.3 66.95,129.15 67.34,129.15 v1(67.35,129.16)
SERDES0_TX_N: length 84.8
  TOP w0.188: v1(67.57,120.67) 67.89,120.35 67.89,119.89 68.1,119.68 J3.39 ; v1(18.42,157.48) 18.64,157.25 18.64,156.23 18.36,155.95 C133.1
  ART04 w0.152: v1(67.57,120.67) 67.79,120.9 67.79,122.81 67.95,122.96 67.95,130.4 67,131.35 64.41,132.42 59.66,132.42 59.28,132.43 57.46,131.85 54.41,131.85 48.74,132.55 45.55,133.19 44.17,134.56 44.17,138.8 40.28,142.7 38.92,142.7 37.65,141.43 27.82,141.43 26.91,142.34 24.89,147.2 24.89,155.32 23.24,156.97 18.93,156.97 v1(18.42,157.48)
SERDES0_TX_P: length 84.9
  TOP w0.188: J3.41 68.6,119.72 68.27,120.05 68.27,120.48 v1(68.45,120.67) ; v1(19.3,157.48) 19.02,157.2 19.02,156.23 19.3,155.95 C132.1
  ART04 w0.152: v1(68.45,120.67) 68.17,120.95 68.17,122.65 68.33,122.8 68.33,130.56 67.22,131.67 64.48,132.8 59.67,132.8 59.22,132.81 57.4,132.23 54.43,132.23 48.8,132.93 45.73,133.54 44.55,134.72 44.55,138.96 40.44,143.08 38.76,143.08 37.49,141.81 27.98,141.81 27.23,142.56 25.27,147.28 25.27,154.39 25.41,154.53 25.5,154.53 25.63,154.66 25.63,154.85 25.5,154.98 25.41,154.98 25.27,155.11 25.27,155.48 23.4,157.35 19.43,157.35 v1(19.3,157.48)
SERDES1_RX_N: length 233.5
  TOP w0.188: v1(68.85,128.27) 68.85,128.34 69.04,128.52 69.22,128.52 69.41,128.34 69.41,127.12 69.35,127.06 J3.44 ; C95.2 232.59,26.36 v1(232.67,26.54)
  BOTTOM w0.188: v1(232.67,26.54) 232.92,26.29 232.92,26.15 232.73,25.96 230.86,25.96 230.65,26.17 230.65,26.4 230.92,26.66 230.92,26.89 230.75,27.06 230.52,27.06 230.25,26.8 230.02,26.8 229.82,27 223.73,27 222.22,27.62 211.19,27.62 210.5,27.76 209.88,28.02 208.54,29.36 207.67,29.72 205.92,31.47 204.7,34.42 204.7,34.42 203.1,36.02 200.55,37.08 188.61,37.08 185.7,38.28 178.33,45.65 176.52,50.02 174.08,52.46 174.08,53.84 171.99,56.39 167.64,58.45 166.84,59.25 163.49,67.32 160.38,70.44 160.38,75.06 160.29,75.55 159.13,79.74 159.13,89.67 159.11,90.7 158.7,93.01 158.7,94.3 156.46,97.82 156.53,98.12 156.23,98.6 155.92,98.67 155.62,99.14 155.68,99.45 155.38,99.93 155.07,99.99 154.77,100.47 154.84,100.78 154.54,101.25 154.23,101.32 153.19,102.95 138.56,117.58 138.56,117.95 138.26,118.25 137.89,118.25 137.49,118.65 137.49,118.92 137.09,119.32 136.82,119.32 136.42,119.72 136.42,120 136.02,120.39 135.74,120.39 135.35,120.79 135.35,121.07 134.95,121.47 134.67,121.47 133.24,122.9 129.5,124.59 126.21,124.59 125.16,124.12 124.84,124.24 124.32,124.01 124.2,123.69 122.69,123.01 105.36,123.01 103.23,125.15 71.7,125.15 69.24,126.17 68.31,127.09 68.31,128.4 68.43,128.52 68.66,128.52 68.85,128.34 v1(68.85,128.27)
SERDES1_RX_P: length 233.5
  TOP w0.188: v1(68.85,129.16) 68.85,129.09 69.04,128.91 69.38,128.91 69.79,128.49 69.79,127.12 69.85,127.06 J3.46 ; C96.2 233.55,26.54 v1(233.55,26.54)
  BOTTOM w0.188: v1(233.55,26.54) 233.3,26.29 233.3,25.99 232.89,25.58 230.7,25.58 229.66,26.62 223.65,26.62 222.14,27.24 211.15,27.24 210.39,27.4 209.67,27.7 208.33,29.04 207.45,29.4 205.6,31.25 204.37,34.21 202.88,35.7 200.47,36.7 188.53,36.7 185.48,37.96 178.01,45.44 176.2,49.81 173.7,52.3 173.7,53.7 171.75,56.08 167.42,58.13 166.51,59.03 163.17,67.11 159.99,70.28 159.99,75.03 159.92,75.46 158.75,79.69 158.75,89.66 158.73,90.67 158.32,92.98 158.32,94.19 152.89,102.71 133.02,122.58 129.41,124.21 126.29,124.21 122.77,122.63 105.2,122.63 103.07,124.76 71.62,124.76 69.02,125.84 67.93,126.94 67.93,128.56 68.28,128.91 68.6,128.91 v1(68.85,129.16)
SERDES1_TX_N: length 227.1
  TOP w0.188: J3.45 69.6,117.27 69.65,117.22 69.65,116.28 72.38,113.54 72.87,113.54 73.06,113.35 73.06,113.19 v1(72.9,113.03) ; v1(226.28,25.55) 226.5,25.32 226.86,25.32 C915.1
  BOTTOM w0.188: v1(226.28,25.55) 226.1,25.37 223.75,25.37 221.83,26.17 210.68,26.17 209.3,26.44 207.53,27.18 204.4,27.18 203.48,27.56 202.38,27.56 201.57,26.75 198.04,26.75 196.84,27.73 196.83,27.74 195.14,29.72 194.95,30.26 194.95,30.67 194.77,31.36 193.98,31.99 189.06,32.48 188.13,32.99 187.38,35.08 185.94,36.52 185.58,36.75 184.35,37.26 184.04,37.51 182.25,39.12 176.44,44.93 174.25,50.24 172.62,51.86 172.62,53.17 170.48,55.32 167.23,56.66 166.94,56.95 165.69,58.19 164.87,59.85 164.25,61.33 163.12,63.03 161.35,67.31 157.92,70.73 157.2,72.47 157.2,89.7 156.83,90.59 154.96,93.35 154.82,93.95 154.82,94.31 152.13,101.9 134.74,119.29 131.05,120.82 105.04,120.82 103.35,122.5 77.75,122.5 75.02,121.38 74.24,120.6 74.09,120.24 74.09,118.45 73.97,118.33 73.97,117.81 74.09,117.69 74.09,116.19 73.15,113.92 73.15,113.22 72.96,113.03 v1(72.9,113.03)
SERDES1_TX_P: length 226.5
  TOP w0.188: v1(73.79,113.03) 73.44,113.38 73.44,113.51 73.03,113.92 72.54,113.92 70.03,116.43 70.03,117.19 70.1,117.27 J3.47 ; v1(226.29,24.69) 226.55,24.94 226.91,24.94 C916.1
  BOTTOM w0.188: v1(226.29,24.69) 225.99,24.99 223.68,24.99 221.75,25.79 210.65,25.79 209.19,26.07 207.45,26.8 204.32,26.8 203.4,27.18 202.54,27.18 201.73,26.36 197.91,26.36 196.59,27.44 196.57,27.46 194.81,29.53 194.56,30.19 194.56,30.62 194.43,31.14 193.83,31.62 188.94,32.11 187.82,32.73 187.05,34.87 185.69,36.22 185.4,36.42 184.14,36.94 184.1,36.98 183.8,37.22 181.99,38.85 176.12,44.71 173.92,50.02 172.24,51.7 172.24,53.02 170.27,54.99 167.01,56.34 166.79,56.57 166.78,56.57 165.38,57.97 164.52,59.69 163.92,61.15 162.78,62.84 161.02,67.09 157.6,70.52 156.82,72.4 156.82,89.62 156.49,90.41 154.61,93.2 154.44,93.9 154.44,94.24 151.8,101.7 134.52,118.97 132.75,119.7 132.75,119.7 130.98,120.44 104.88,120.44 103.19,122.12 77.82,122.12 75.24,121.05 74.56,120.38 74.47,120.16 74.47,116.11 73.53,113.84 73.53,113.19 73.69,113.03 v1(73.79,113.03)
SERDES2_RX_N: length 237.7
  TOP w0.188: v1(235.07,28.45) 235.28,28.24 235.28,26.24 235.03,25.98 C83.2 ; v1(70.35,128.27) 70.35,128.34 70.54,128.52 70.79,128.52 70.91,128.41 70.91,127.12 70.85,127.06 J3.50
  BOTTOM w0.188: v1(70.35,128.27) 70.35,128.34 70.2,128.49 70.03,128.49 69.88,128.34 69.88,127.18 69.92,127.13 70.15,126.98 71.63,126.36 74.26,126.36 74.42,126.53 74.42,126.71 74.59,126.87 74.82,126.87 74.98,126.71 74.98,126.53 75.15,126.36 75.38,126.36 75.55,126.53 75.55,126.71 75.71,126.87 75.95,126.87 76.11,126.71 76.11,126.53 76.28,126.36 105.26,126.36 106.93,124.69 121.59,124.69 123.01,126.11 129.57,126.11 133.25,125.38 136.76,123.92 140.58,118.28 156.16,102.69 160.16,95.31 160.16,93.14 160.32,92.22 160.73,89.92 160.73,79.92 161.9,76.47 161.98,75.86 162.05,75.26 162.05,74.73 162.05,70.9 170.38,62.57 171.52,59.81 171.52,59.81 171.54,59.78 172.54,58.01 173.26,57.14 175.39,55.01 177.33,53.71 178.25,51.5 183.27,46.48 183.65,45.9 184.25,44.45 184.25,42.78 184.95,41.1 186.56,39.48 188.84,38.54 189.64,38.44 190.79,38.72 191.26,38.73 203.23,38.73 204.62,37.34 205.15,36.07 207.56,33.66 207.92,32.78 207.92,31.8 208.54,31.19 212.52,29.47 214.4,29.08 222.73,29.08 223.9,28.6 225.26,28.6 225.42,28.76 225.42,29.04 225.59,29.21 225.82,29.21 225.99,29.04 225.99,28.76 226.15,28.6 226.39,28.6 226.55,28.76 226.55,28.92 226.72,29.08 226.95,29.08 227.12,28.92 227.12,28.76 227.28,28.6 227.51,28.6 227.68,28.76 227.68,28.92 227.84,29.08 228.08,29.08 228.24,28.92 228.24,28.76 228.41,28.6 231.32,28.6 232.05,27.86 233.76,27.86 234.01,27.61 235.14,27.61 235.32,27.8 235.32,28.2 v1(235.07,28.45)
SERDES2_RX_P: length 237.1
  TOP w0.188: v1(235.96,28.45) 235.66,28.15 235.66,26.16 C94.2 ; v1(70.35,129.16) 70.35,129.09 70.54,128.91 70.95,128.91 71.29,128.57 71.29,127.12 71.35,127.06 J3.52
  BOTTOM w0.188: v1(235.96,28.45) 235.71,28.2 235.71,27.64 235.29,27.23 233.85,27.23 233.6,27.48 231.9,27.48 231.16,28.22 223.82,28.22 222.66,28.7 214.36,28.7 212.41,29.11 208.32,30.87 207.54,31.64 207.54,32.7 207.23,33.45 204.83,35.86 204.3,37.13 203.07,38.35 191.27,38.35 191.05,38.35 191.05,38.35 190.84,38.34 189.67,38.05 188.74,38.17 186.35,39.16 184.63,40.88 183.87,42.71 183.87,44.37 183.31,45.72 182.97,46.23 177.92,51.28 177.02,53.46 175.14,54.72 172.98,56.88 172.23,57.8 171.21,59.6 171.19,59.62 170.06,62.35 161.67,70.74 161.67,74.72 161.67,75.24 161.53,76.38 160.35,79.86 160.35,89.89 159.95,92.15 159.78,93.11 159.78,95.22 155.85,102.46 140.28,118.04 136.51,123.61 133.14,125.01 129.53,125.73 123.17,125.73 121.75,124.31 106.77,124.31 105.1,125.98 71.56,125.98 69.97,126.64 69.68,126.83 69.49,127.02 69.49,128.49 69.87,128.87 70.12,128.87 70.35,129.09 v1(70.35,129.16)
SERDES2_TX_N: length 227.6
  TOP w0.188: C901.1 226.86,23.38 226.53,23.38 v1(226.26,23.64) ; v1(76.33,110.74) 76.47,110.89 76.47,111.15 76.15,111.48 75.51,111.48 74.85,112.14 74.85,113.61 73.91,114.55 72.94,114.55 71.16,116.34 71.16,117.05 71.1,117.11 J3.51
  BOTTOM w0.188: v1(76.33,110.74) 76.84,111.25 76.84,111.37 77.6,112.14 78.61,114.59 78.61,120.27 79.35,121.01 102.57,121.01 103.47,120.63 104.72,119.38 130.68,119.38 133.65,118.15 149.56,102.24 150.93,98.97 151.63,94.06 151.63,93.25 152.64,92.24 154.06,90.58 154.14,90.44 154.3,89.93 154.33,89.24 154.33,89.22 154.29,87.39 154.21,86.44 153.8,84.38 153.8,79.72 155.2,76.34 155.73,73.68 155.73,70.96 157.32,67.11 158.59,65.84 159.15,64.5 161.31,62.34 161.61,61.6 163.23,59.98 163.87,58.44 164.07,57.99 164.24,57.58 164.5,57.33 164.5,57.33 166.04,55.79 166.06,55.77 166.4,55.43 169.66,54.08 171.17,52.57 171.17,51.25 172.09,50.33 172.53,49.27 172.53,49.27 172.92,48.31 174.02,46.66 175.34,43.48 179.09,39.73 179.34,39.13 180.4,38.07 181.96,36.88 183.64,35.92 183.69,35.88 186.07,33.01 186.74,32.21 187.99,30.96 195.34,26.67 196.21,26.08 198.34,24.88 198.35,24.88 200.86,24.59 205.16,24.59 206.75,22.99 220.16,22.99 220.41,23.24 225.86,23.24 v1(226.26,23.64)
SERDES2_TX_P: length 226.7
  TOP w0.188: C913.1 227.14,22.68 226.85,22.97 226.49,22.97 v1(226.25,22.73) ; v1(77.22,110.74) 76.85,111.11 76.85,111.31 76.3,111.86 75.67,111.86 75.24,112.3 75.24,113.77 74.07,114.93 73.1,114.93 71.54,116.5 71.54,117.05 71.6,117.11 J3.53
  BOTTOM w0.188: v1(226.25,22.73) 226.12,22.86 220.57,22.86 220.32,22.61 206.59,22.61 205,24.21 200.84,24.21 198.27,24.5 198.19,24.53 196.01,25.76 195.14,26.35 187.75,30.66 186.46,31.95 185.78,32.77 183.41,35.62 181.75,36.56 180.15,37.78 179.02,38.92 178.77,39.51 175.02,43.26 173.69,46.48 172.59,48.13 171.76,50.12 170.79,51.09 170.79,52.41 169.44,53.76 166.19,55.1 165.79,55.49 165.78,55.51 164.18,57.1 163.92,57.37 163.72,57.84 163.52,58.29 162.91,59.77 161.29,61.39 160.98,62.12 158.82,64.28 158.27,65.63 157,66.89 155.35,70.89 155.35,73.64 155.09,74.94 155.09,74.94 154.83,76.23 153.42,79.65 153.42,84.42 153.83,86.5 153.91,87.41 153.95,89.22 153.95,89.23 153.92,89.86 153.78,90.29 153.75,90.36 152.36,91.98 151.25,93.09 151.25,94.03 150.56,98.87 149.23,102.02 133.43,117.83 130.6,119 104.57,119 103.25,120.31 102.5,120.62 79.51,120.62 78.99,120.11 78.99,114.51 78.2,112.6 77.92,111.92 77.22,111.22 v1(77.22,110.74)
SERDES3_RX_N: length 144.2
  TOP w0.188: v1(182.67,84.96) 182.41,85.22 182.41,86.94 182.53,87.05 ; J3.56 72.35,127.06 72.41,127.12 72.41,128.34 72.22,128.52 72.04,128.52 71.85,128.34 v1(71.85,128.27)
  TOP w0.203: J803.41 182.53,87.05
  BOTTOM w0.188: v1(71.85,128.27) 71.47,128.65 71.34,128.65 70.99,129 70.99,130.61 71.77,131.39 76.2,133.22 92.51,133.22 95.15,130.58 98.6,130.58 99.95,129.23 106.45,129.23 109.07,126.61 118.61,126.61 118.9,126.9 118.9,127.74 120.05,128.9 133.43,128.9 137.29,127.68 139.72,126.46 143.61,121.76 145.14,118.43 145.55,117.99 171.8,91.74 176.3,89.88 178.57,88.04 180.46,87.12 181.49,86.1 181.99,86.1 182.4,85.69 182.4,85.23 v1(182.67,84.96)
SERDES3_RX_P: length 144.2
  TOP w0.188: 182.03,86.96 182.03,86.95 182.03,85.22 v1(181.78,84.96) ; v1(71.85,129.16) 71.85,129.09 72.04,128.91 72.38,128.91 72.79,128.49 72.79,127.12 72.85,127.06 J3.58
  TOP w0.203: J803.43 182.03,86.96
  BOTTOM w0.188: v1(71.85,129.16) 71.72,129.03 71.5,129.03 71.37,129.16 71.37,130.45 71.99,131.07 72.63,131.33 72.85,131.24 72.93,131.05 73.14,130.96 73.36,131.05 73.45,131.26 73.37,131.46 73.46,131.68 73.67,131.77 73.89,131.68 73.97,131.48 74.19,131.39 74.4,131.48 74.49,131.7 74.41,131.89 74.5,132.11 76.27,132.84 92.35,132.84 95,130.2 98.45,130.2 99.79,128.85 106.29,128.85 108.92,126.23 118.76,126.23 119.28,126.75 119.28,127.58 120.21,128.52 133.37,128.52 137.15,127.33 139.48,126.15 143.29,121.56 144.82,118.21 145.28,117.72 171.58,91.42 176.1,89.55 178.36,87.72 180.24,86.81 181.33,85.72 181.83,85.72 182.02,85.53 182.02,85.2 v1(181.78,84.96)
SERDES3_TX_N: length 185.5
  TOP w0.188: v1(181.79,81.76) 181.66,81.89 181.66,82.3 C810.1 ; v1(76.07,113.26) 76.33,113.51 76.33,114.57 75.08,115.82 73.24,115.82 72.66,116.41 72.66,117.02 72.6,117.08 J3.57
  BOTTOM w0.188: v1(181.79,81.76) 181.56,81.99 181.56,82.24 182.01,82.7 183.09,83.15 183.61,83.66 184.02,84.66 184.02,87.88 165.48,106.43 160.96,117.32 153.33,124.95 137.54,131.32 127.01,131.32 126.05,130.36 117.91,130.36 116.2,128.65 111.99,128.65 110.41,129.1 108.46,130.87 106.81,132.03 106.14,132.39 105.23,132.77 102.86,132.77 102.24,132.51 100.3,132.51 99.53,132.83 97.26,135.1 76.4,135.1 67.43,131.39 66.47,130.43 66.47,126.28 71.17,121.58 71.17,114.81 71.43,114.2 71.43,112.06 71.98,111.51 74.7,111.51 75.26,112.06 75.26,113.36 75.8,113.9 76.18,113.9 76.33,113.76 76.33,113.51 v1(76.07,113.26)
SERDES3_TX_P: length 185.7
  TOP w0.188: v1(76.96,113.26) 76.71,113.51 76.71,114.73 76.62,114.82 76.62,115.18 76.4,115.4 76.04,115.4 75.82,115.62 75.82,115.98 75.59,116.2 73.4,116.2 73.04,116.57 73.04,117.02 73.1,117.08 J3.59 ; v1(180.9,81.76) 181.23,82.09 181.23,82.52 C811.1
  BOTTOM w0.188: v1(180.9,81.76) 181.18,82.04 181.18,82.4 181.79,83.02 182.88,83.47 183.28,83.87 183.64,84.74 183.64,87.73 165.15,106.21 160.64,117.11 153.12,124.63 137.47,130.94 127.17,130.94 126.21,129.98 118.07,129.98 116.36,128.27 111.94,128.27 110.22,128.76 108.22,130.57 106.61,131.71 105.98,132.04 105.15,132.38 102.93,132.38 102.39,132.16 102.32,132.13 100.23,132.13 99.31,132.51 97.1,134.72 76.48,134.72 67.65,131.06 66.85,130.27 66.85,126.44 70.58,122.71 70.85,122.71 71,122.86 71.27,122.86 71.54,122.6 71.54,122.33 71.38,122.18 71.38,121.91 71.55,121.74 71.55,119.45 71.76,119.25 71.76,118.88 71.55,118.68 71.55,118.31 71.76,118.11 71.76,117.74 71.55,117.54 71.55,114.89 71.81,114.27 71.81,112.22 72.14,111.89 74.54,111.89 74.88,112.22 74.88,113.52 75.64,114.28 76.34,114.28 76.71,113.91 76.71,113.51 v1(76.96,113.26)
SERDES4_RX_N: length 100.3
  TOP w0.188: J3.86 79.85,127.04 79.91,127.1 79.91,127.6 v1(79.66,127.85) ; J701.23 150.95,87.03 151.12,86.86 151.12,86.59 150.66,86.13 149.68,85.72 147.95,85.72 v1(147.67,86)
  ART04 w0.152: v1(147.67,86) 147.42,85.75 146.55,85.75 144.96,87.35 142.74,88.26 142.15,88.26 141.9,88.52 141.49,88.52 141.24,88.26 140.83,88.26 140.58,88.52 140.17,88.52 139.92,88.26 139.51,88.26 139.26,88.52 138.85,88.52 138.6,88.26 138.19,88.26 137.94,88.52 137.53,88.52 137.28,88.26 137.13,88.26 136.8,87.93 136.31,87.93 136.09,88.16 135.65,88.16 135.43,87.93 133.47,87.93 133.24,88.16 132.81,88.16 132.58,87.93 132.15,87.93 131.92,88.16 131.49,88.16 131.26,87.93 131.03,87.93 130.25,88.09 130.11,88.3 129.64,88.4 129.42,88.25 128.95,88.35 128.81,88.56 128.34,88.65 128.13,88.51 127.13,88.71 125.2,89.29 124.89,89.42 124.75,89.76 124.38,89.91 124.04,89.77 123.67,89.93 123.53,90.27 123.16,90.42 122.82,90.28 122.45,90.43 122.31,90.77 121.94,90.93 121.6,90.78 121.23,90.94 121.17,91.09 120.54,91.36 120.38,91.29 119.01,91.86 107.24,99.72 104.93,102.23 103.34,103.68 101.5,105.05 97.45,106.4 97.42,106.41 90.46,110.07 86.07,111.89 83.01,113.03 82.12,114.32 82.12,116.92 80.59,119.63 80.27,124.47 78.89,126.79 78.89,127.9 79.4,128.41 79.8,128.41 79.95,128.26 79.95,128.15 v1(79.66,127.85)
SERDES4_RX_P: length 100.3
  TOP w0.188: v1(80.54,127.85) 80.29,127.6 80.29,127.1 80.35,127.04 J3.88 ; v1(147.67,85.12) 147.9,85.34 149.76,85.34 150.88,85.81 151.5,86.43 151.5,86.86 151.75,87.11 J701.25
  ART04 w0.152: v1(80.54,127.85) 80.33,128.06 80.33,128.42 79.96,128.79 79.24,128.79 78.51,128.06 78.51,126.68 79.89,124.36 80.22,119.52 81.74,116.82 81.74,114.2 82.77,112.72 85.93,111.54 90.3,109.72 97.26,106.07 97.29,106.06 97.32,106.05 101.32,104.71 103.09,103.38 104.66,101.96 106.99,99.43 118.83,91.52 125.07,88.94 127.04,88.34 130.99,87.55 136.96,87.55 137.29,87.88 142.66,87.88 144.74,87.02 146.39,85.37 147.42,85.37 v1(147.67,85.12)
SERDES4_TX_N: length 100.7
  TOP w0.188: C722.1 151.87,85.27 151.61,85.27 150.44,84.1 150.04,84.1 v1(149.71,84.44) ; J3.87 80.1,117.3 80.16,117.24 80.16,116.36 v1(79.88,116.08)
  BOTTOM w0.188: v1(149.71,84.44) 149.41,84.14 149.24,84.14 149.05,84.33 149.05,92.32 148.34,94.03 148.34,97.63 145.74,103.89 132.73,116.91 129.34,118.31 103.39,118.31 100.51,119.51 81.66,119.51 80.14,117.98 80.14,116.34 v1(79.88,116.08)
SERDES4_TX_P: length 100.1
  TOP w0.188: J3.89 80.6,117.25 80.54,117.19 80.54,116.31 v1(80.77,116.08) ; C723.1 152.17,84.71 151.99,84.89 151.77,84.89 150.6,83.72 149.88,83.72 v1(149.71,83.55)
  BOTTOM w0.188: v1(80.77,116.08) 80.52,116.34 80.52,117.82 80.78,118.09 81.13,118.09 81.48,118.44 81.48,118.79 81.82,119.13 100.43,119.13 103.32,117.93 129.26,117.93 132.51,116.59 145.42,103.68 147.96,97.56 147.96,93.96 148.67,92.24 148.67,84.17 149.08,83.76 149.5,83.76 v1(149.71,83.55)
SERDES_CLK0_N: length 46.9
  TOP w0.155: v1(27.08,122.03) 27.07,122.03 26.82,122.29 26.54,122.29 26.27,122.02 C2622.2 ; v1(65.85,128.27) 65.85,128.37 66,128.52 66.25,128.52 66.41,128.37 66.41,127.07 66.35,127.01 J3.32
  ART04 w0.127: v1(27.08,122.03) 27.32,122.28 28.58,122.28 34.96,124.92 38.02,124.92 40.41,125.91 63.88,125.91 64.06,126.08 64.22,126.08 64.26,126.04 64.42,126.04 64.53,126.15 64.53,126.31 64.49,126.35 64.49,126.51 64.6,126.62 64.75,126.62 64.8,126.58 64.96,126.58 65.07,126.69 65.07,126.85 65.02,126.89 65.02,127.05 65.23,127.25 65.23,128.32 65.43,128.52 65.6,128.52 v1(65.85,128.27)
SERDES_CLK0_P: length 46.9
  TOP w0.155: J3.34 66.85,127.01 66.79,127.07 66.79,128.53 66.41,128.91 66,128.91 65.85,129.06 v1(65.85,129.16) ; v1(27.08,122.92) 27.07,122.92 26.82,122.67 26.54,122.67 26.27,122.94 C2621.2
  ART04 w0.127: v1(27.08,122.92) 27.35,122.66 28.5,122.66 34.88,125.3 37.94,125.3 40.33,126.29 63.72,126.29 64.85,127.41 64.85,128.48 65.27,128.91 65.6,128.91 v1(65.85,129.16)
SLOT_SEL0: length 2
  TOP w0.203: J3.312 R142.1
SLOT_SEL1: length 3.9
  TOP w0.203: R187.1 53.63,127.28 53.81,127.1 55.54,127.1 55.85,126.8 J3.310
SPI0_CLK: length 90.8
  TOP w0.203: v1(111.37,109.65) 105.6,115.42 J3.189 ; v1(163.32,84.2) 162.66,84.2 162.13,84.73 R106.1
  ART03 w0.178: v1(163.32,84.2) 166.17,87.05 166.17,95.91 159.02,103.06 140.53,103.06 135.26,97.79 v1(135.26,97.15)
  ART04 w0.178: v1(135.26,97.15) 134.39,97.15 133.81,96.57 133.45,96.57 132.21,97.81 129.68,97.81 125.76,101.73 115.6,105.94 111.89,109.65 v1(111.37,109.65)
SPI0_CS0: length 92.5
  TOP w0.203: v1(162.48,83.24) 160.43,83.24 159.41,84.25 R101.1 ; J3.193 106.6,115.14 112.14,109.6 v1(112.14,108.38)
  ART03 w0.178: v1(134.49,96.57) 134.78,96.28 136.5,96.28 137.22,96.58 142.29,101.65 158.6,101.65 163.83,96.42 163.83,93.62 163.3,93.09 162.87,93.09 162.14,92.37 160.82,89.18 160.82,83.91 161.49,83.24 v1(162.48,83.24)
  ART04 w0.178: v1(134.49,96.57) 134.05,96.13 133.17,96.13 131.97,97.33 129.37,97.33 125.55,101.15 115,105.52 v1(112.14,108.38)
SPI0_MISO: length 95
  TOP w0.203: v1(163.27,83.31) 162.87,83.72 162.57,83.72 161.64,84.65 161.64,84.67 R105.1 ; v1(111.37,108.38) 110.41,108.38 104.6,114.2 J3.185
  ART03 w0.178: v1(163.27,83.31) 162.85,83.73 162.85,84.47 165.66,87.27 165.66,88.38 165.45,88.59 164.98,88.59 164.77,88.8 164.77,89.09 164.98,89.3 165.45,89.3 165.66,89.51 165.66,95.67 158.88,102.45 141.31,102.45 v1(136.02,97.15)
  ART04 w0.178: v1(111.37,108.38) 114.55,105.2 125.49,100.67 129.21,96.95 131.81,96.95 133.01,95.75 134.61,95.75 v1(136.02,97.15)
SPI0_MOSI: length 90.6
  TOP w0.203: J3.187 105.1,114.65 v1(110.1,109.65) ; R102.1 160.32,84.64 160.76,84.2 v1(161.29,84.2)
  ART03 w0.178: v1(136.78,97.15) 141.69,102.07 158.72,102.07 165.28,95.51 165.28,90.47 164.44,89.64 163.66,87.75 v1(161.29,84.2)
  ART04 w0.178: v1(110.1,109.65) 110.1,109.65 110.75,108.07 113.77,105.05 125.38,100.24 129.06,96.56 131.65,96.56 132.85,95.37 134.99,95.37 v1(136.78,97.15)
SPI2_CLK: length 36
  TOP w0.203: v1(102.87,115.85) 102.6,116.12 J3.177 ; v1(93.47,133.98) 93.47,132.71 93.85,132.34 R2758.1
  ART03 w0.178: v1(102.87,115.85) 102.87,116.27 103.34,116.74 103.34,120.1 99.99,123.44 98.44,123.44 97.92,123.96 97.92,124.46 96.27,126.11 91.65,126.11 90.99,126.78 90.99,127.14 91.32,127.48 91.32,129.65 89.12,131.85 89.12,132.34 89.9,133.12 92.61,133.12 v1(93.47,133.98)
SPI2_CLK_R: length 173.9
  TOP w0.203: R376.2 36.41,22.67 v1(36.14,22.94) 35.88,22.67 R173.1 ; v1(92.33,132.08) 92.93,132.08 R2758.2
  ART04 w0.178: v1(92.33,132.08) 91.82,131.57 89.41,131.57 89.1,131.88 89.1,132.33 88.8,132.64 85.35,132.64 85.05,132.34 85.05,131.58 84.58,131.12 78.64,131.12 76.48,128.96 76.48,120.64 76.16,120.32 76.16,117.03 73.61,114.48 61.04,114.48 60.07,115.44 40.18,115.44 33.57,108.83 33.57,105.58 32.77,104.77 32.77,100.84 29.57,97.64 29.57,76.68 24.93,72.05 24.93,59.94 26.16,58.71 26.16,53.21 27.15,52.22 27.15,49.43 28.42,48.16 28.42,38.22 33.53,33.12 33.53,25.55 v1(36.14,22.94)
SPI2_CS0: length 21.9
  TOP w0.203: J3.181 103.6,119.21 v1(102.9,119.91)
  TOP w0.254: v1(89.71,130.06) 89.59,130.19 R2763.1
  ART03 w0.178: v1(89.71,130.06) 90.01,129.76 90.01,129.46 90.68,128.78 90.68,126.65 91.68,125.65 96.27,125.65 97.38,124.54 97.38,124.06 99.55,121.9 100.92,121.9 102.9,119.93 v1(102.9,119.91)
SPI2_CS0_R: length 186.5
  TOP w0.203: R295.2 R170.1 35.51,26.85 34.67,27.69 v1(32.39,27.69)
  TOP w0.254: R2763.2 v1(89.59,132.14)
  ART04 w0.178: v1(32.39,27.69) 32.39,25.55 32.26,25.42 31.88,25.42 31.62,25.68 31.62,28.53 31.83,28.73 31.95,28.73 32.16,28.94 32.16,29.24 31.95,29.44 31.83,29.44 31.62,29.65 31.62,33.22 27.43,37.42 27.43,44.07 25.45,46.05 25.15,46.05 25.04,45.94 24.75,45.94 24.54,46.15 24.54,46.44 24.65,46.56 24.65,46.85 23.65,47.85 23.65,53.33 24.51,54.2 24.51,57.82 23.11,59.21 23.11,73.12 24.92,74.92 24.92,111.4 27.94,114.43 35.92,114.43 37.97,116.48 37.97,117.45 38.91,118.39 45.97,118.39 46.96,117.4 55.68,117.4 55.85,117.22 56.15,117.22 56.34,117.41 56.63,117.41 56.84,117.2 56.84,116.91 56.65,116.72 56.65,116.42 56.97,116.1 60.63,116.1 61.67,115.06 72.77,115.06 74.17,116.46 74.17,117.6 75.46,118.9 75.46,122.71 75.95,123.19 75.95,129.08 78.44,131.57 84.33,131.57 84.67,131.91 84.67,132.6 85.09,133.02 88.96,133.02 89.59,132.39 v1(89.59,132.14)
SPI2_MISO: length 26.7
  TOP w0.203: v1(101.6,116.2) 101.6,117.22 J3.173
  TOP w0.254: v1(88.82,131.03) 88.49,130.7 R2762.1
  ART03 w0.178: v1(101.6,116.2) 102.3,116.9 102.3,120.1 101.41,120.98 99.52,120.98 95.17,125.32 91.58,125.32 90.37,126.53 90.37,128.66 88.82,130.21 v1(88.82,131.03)
SPI2_MISO_R: length 181.2
  TOP w0.203: R378.2 v1(36.14,24.79) R72.1
  TOP w0.254: v1(88.06,132.14) R2762.2
  ART04 w0.178: v1(88.06,132.14) 87.44,132.14 85.36,130.06 79.21,130.06 77.69,128.54 77.69,123.35 78.54,122.5 78.54,113.26 77.04,111.76 75.36,111.76 72.7,109.09 63.86,109.09 62.47,109.67 57.96,114.17 40.83,114.17 35.43,108.77 35.43,100.08 32.64,97.28 32.64,76.96 27.85,72.17 27.85,54.19 30.73,51.31 30.73,42.04 32.72,40.06 35.72,40.06 35.93,40.26 35.93,40.41 36.13,40.61 36.43,40.61 36.64,40.41 36.64,40.26 36.85,40.06 37.14,40.06 37.35,40.26 37.35,40.41 37.56,40.61 37.85,40.61 38.06,40.41 38.06,40.26 38.27,40.06 38.56,40.06 38.77,40.26 38.77,40.41 38.98,40.61 39.27,40.61 39.48,40.41 39.48,40.26 39.69,40.06 39.87,40.06 v1(40.71,39.22)
  BOTTOM w0.203: v1(36.14,24.79) 36.14,26.9 42.62,33.38 42.62,38.53 41.94,39.22 v1(40.71,39.22)
SPI2_MOSI: length 23.2
  TOP w0.203: v1(101.85,119.91) 101.85,119.89 102.1,119.64 J3.175
  TOP w0.254: v1(87.3,131.03) 86.97,130.7 R2761.1
  ART03 w0.178: v1(101.85,119.91) 101.09,120.67 99.39,120.67 95.05,125.02 91.45,125.02 90.06,126.41 90.06,128.5 87.54,131.03 v1(87.3,131.03)
SPI2_MOSI_R: length 184.9
  TOP w0.203: R377.2 v1(36.14,23.73) R171.1
  TOP w0.254: R2761.2 v1(86.54,132.14)
  ART04 w0.178: v1(39.7,39.22) 39.29,39.62 32.39,39.62 30.23,41.78 30.23,48.77 29.59,49.4 29.59,51.82 27.43,53.97 27.43,59.6 26.07,60.96 26.07,63.73 26.28,63.93 26.51,63.93 26.72,64.14 26.72,64.44 26.51,64.65 26.28,64.65 26.07,64.85 26.07,65.15 26.28,65.36 26.51,65.36 26.72,65.57 26.72,65.86 26.51,66.07 26.28,66.07 26.07,66.28 26.07,66.57 26.28,66.78 26.51,66.78 26.72,66.99 26.72,67.28 26.51,67.49 26.28,67.49 26.07,67.7 26.07,67.99 26.28,68.2 26.51,68.2 26.72,68.41 26.72,68.7 26.51,68.91 26.28,68.91 26.07,69.12 26.07,69.42 26.28,69.62 26.51,69.62 26.72,69.83 26.72,70.13 26.51,70.34 26.28,70.34 26.07,70.54 26.07,71.16 31.37,76.45 31.37,93.6 31.72,93.95 31.72,97.13 34.93,100.33 34.93,108.86 40.62,114.55 58.28,114.55 62.96,109.88 63.93,109.47 72.31,109.47 75.18,112.34 75.18,113.56 77.66,116.03 77.66,122.79 77.38,123.06 77.38,128.73 79.03,130.38 85.02,130.38 86.54,131.9 v1(86.54,132.14)
  BOTTOM w0.203: v1(39.7,39.22) 40.21,39.73 42.04,39.73 43.1,38.66 43.1,33.28 36.8,26.98 36.8,24.39 v1(36.14,23.73)
SPI_CLK_HUB0: length 20.5
  TOP w0.203: U2002.34 133.6,42.22 133.4,42.42 v1(133.4,42.7) ; R2019.1 121.01,35.13 v1(121.03,35.1)
  ART04 w0.178: v1(133.4,42.7) 133.4,41.86 134.25,41.01 134.25,39.7 133.76,38.51 133.35,38.1 131.63,36.95 131.09,36.73 128.73,36.73 124.68,35.05 122.81,35.05 122.39,34.63 121.5,34.63 v1(121.03,35.1)
SPI_CS_HUB: length 79.4
  TOP w0.203: v1(121.04,34.1) 121.53,34.59 122.61,34.59 123.27,35.25 R2016.2 ; R2003.2 R2037.1 70.42,45.28 70.64,45.06 R2036.1 71.5,45.06 71.91,45.47 v1(71.91,45.85)
  BOTTOM w0.203: v1(121.04,34.1) 117.65,30.71 115.04,30.71 113.26,28.93 108.22,28.93 107.98,29.17 107.98,30.44 107.74,30.68 107.4,30.68 107.16,30.44 107.16,29.17 106.93,28.93 106.27,28.93 106.03,29.17 106.03,29.96 105.8,30.2 105.46,30.2 105.22,29.96 105.22,29.17 104.98,28.93 104.13,28.93 103.89,29.17 103.89,30.34 103.66,30.58 103.32,30.58 103.08,30.34 103.08,29.17 102.84,28.93 100.83,28.93 100.62,29.14 100.62,30.42 100.33,30.71 99.99,30.71 99.78,30.5 99.78,29.17 99.54,28.93 99.2,28.93 98.97,29.17 98.97,30.09 98.73,30.33 98.39,30.33 98.15,30.09 98.15,29.17 97.91,28.93 94.3,28.93 78.43,44.81 76.13,44.81 75.89,44.57 75.89,44.2 75.66,43.97 75.32,43.97 75.08,44.2 75.08,44.57 74.84,44.81 72.95,44.81 v1(71.91,45.85)
SPI_CS_HUB0: length 20.7
  TOP w0.203: U2002.32 134.84,43.02 v1(134.87,43.05) ; v1(123.52,34.59) 123.67,34.44 R2020.1
  ART04 w0.178: v1(134.87,43.05) 134.87,43.94 134.75,44.07 134.24,44.07 134.11,43.94 134.11,42.04 134.56,41.59 134.56,39.4 133.97,37.98 131.69,36.46 131.12,36.22 128.67,36.22 126.64,35.38 124.58,34.59 v1(123.52,34.59)
SPI_CS_HUB1: length 8.5
  TOP w0.152: U2101.45 120.28,42.07 119.89,41.68 119.89,41.15 v1(119.7,40.96)
  TOP w0.203: v1(123.51,36.64) 124.08,36.07 R2016.1
  ART04 w0.178: v1(123.51,36.64) 119.7,40.45 v1(119.7,40.96)
SPI_MCU_CLK: length 18.2
  TOP w0.203: R2810.1 192.02,58.67 191.46,58.11 R2878.1 192.05,56.92 192.53,57.4 v1(192.53,57.66) ; v1(194.31,64.02) 194.31,66.42 195.83,67.94 U2801.6
  ART04 w0.178: v1(192.53,57.66) 192.53,57.71 193.41,58.59 193.7,58.59 194.03,58.26 194.33,58.26 194.54,58.47 194.54,58.76 194.21,59.09 194.21,59.38 194.49,59.66 194.49,60.91 194.7,61.12 194.81,61.12 195.02,61.33 195.02,61.62 194.81,61.83 194.7,61.83 194.49,62.04 194.49,62.36 194.83,62.7 194.83,63.5 v1(194.31,64.02)
SPI_MCU_CS: length 16.5
  TOP w0.203: U2801.1 v1(193.29,60.2) 193.29,59.56 ; R2876.2 v1(191.77,53.59)
  ART04 w0.178: v1(193.29,60.2) 192.94,59.84 192.65,59.84 192.2,60.29 191.91,60.29 191.7,60.08 191.7,59.78 192.3,59.18 192.3,58.95 192.04,58.69 191.79,58.69 191.19,59.28 190.96,59.28 190.73,59.05 190.73,58.85 191.35,58.23 191.35,58.03 191.26,57.94 190.55,57.94 190.37,57.76 190.37,57.46 190.58,57.25 190.93,57.25 191.1,57.09 191.1,55.41 190.98,55.3 190.68,55.3 190.47,55.09 190.47,54.79 190.68,54.59 191.01,54.59 191.19,54.41 191.19,53.8 191.39,53.59 v1(191.77,53.59)
SPI_MCU_MISO: length 21.4
  TOP w0.152: v1(197.99,54.36) 197.42,53.78 197.42,52.64 197.61,52.45 198.3,52.45 198.68,52.07 198.68,50.74 198.76,50.66
  TOP w0.203: R2806.2 195.1,59.82 v1(195.35,60.07) 195.68,60.07 195.96,59.79 R2803.1 ; 198.76,50.66 U3.F13
  ART04 w0.178: v1(195.35,60.07) 195.35,59.26 196.2,58.41 196.2,57.31 195.5,56.62 193.6,56.62 193.4,56.41 193.4,56.06 193.55,55.9 196.11,55.9 196.31,56.11 196.31,56.74 196.52,56.95 196.82,56.95 197.03,56.74 197.03,56.11 197.23,55.9 197.79,55.9 197.99,55.7 v1(197.99,54.36)
SPI_MCU_MOSI: length 18.2
  TOP w0.203: R2809.1 v1(191.77,54.61) R2875.1 ; v1(195.11,65.5) 197.1,67.49 U2801.5
  ART04 w0.178: v1(191.77,54.61) 191.48,54.9 191.48,56.61 192.08,58.07 193.76,59.75 193.76,60.39 193.52,60.63 193.52,64.24 194.79,65.5 v1(195.11,65.5)
SPI_MISO_HUB: length 77.4
  TOP w0.203: R2013.2 125.17,35.25 124.97,35.05 124.97,34.11 124.77,33.91 123.7,33.91 123.51,34.09 v1(121.92,34.09)
  TOP w0.254: R2002.1 v1(70.51,46.13)
  BOTTOM w0.203: v1(70.51,46.13) 73.59,43.05 79.45,43.05 80.2,42.3 80.2,41.96 79.45,41.21 79.45,40.87 79.69,40.63 80.02,40.63 80.78,41.39 81.12,41.39 81.4,41.11 81.4,40.77 80.58,39.95 80.58,39.62 80.82,39.38 81.15,39.38 81.97,40.2 82.31,40.2 82.55,39.96 82.55,39.62 81.73,38.8 81.73,38.47 81.97,38.23 82.3,38.23 83.12,39.05 83.46,39.05 83.7,38.81 83.7,38.47 82.88,37.65 82.88,37.32 83.11,37.08 83.45,37.08 84.27,37.9 84.61,37.9 94.26,28.24 113.18,28.24 115.24,30.3 118.13,30.3 v1(121.92,34.09)
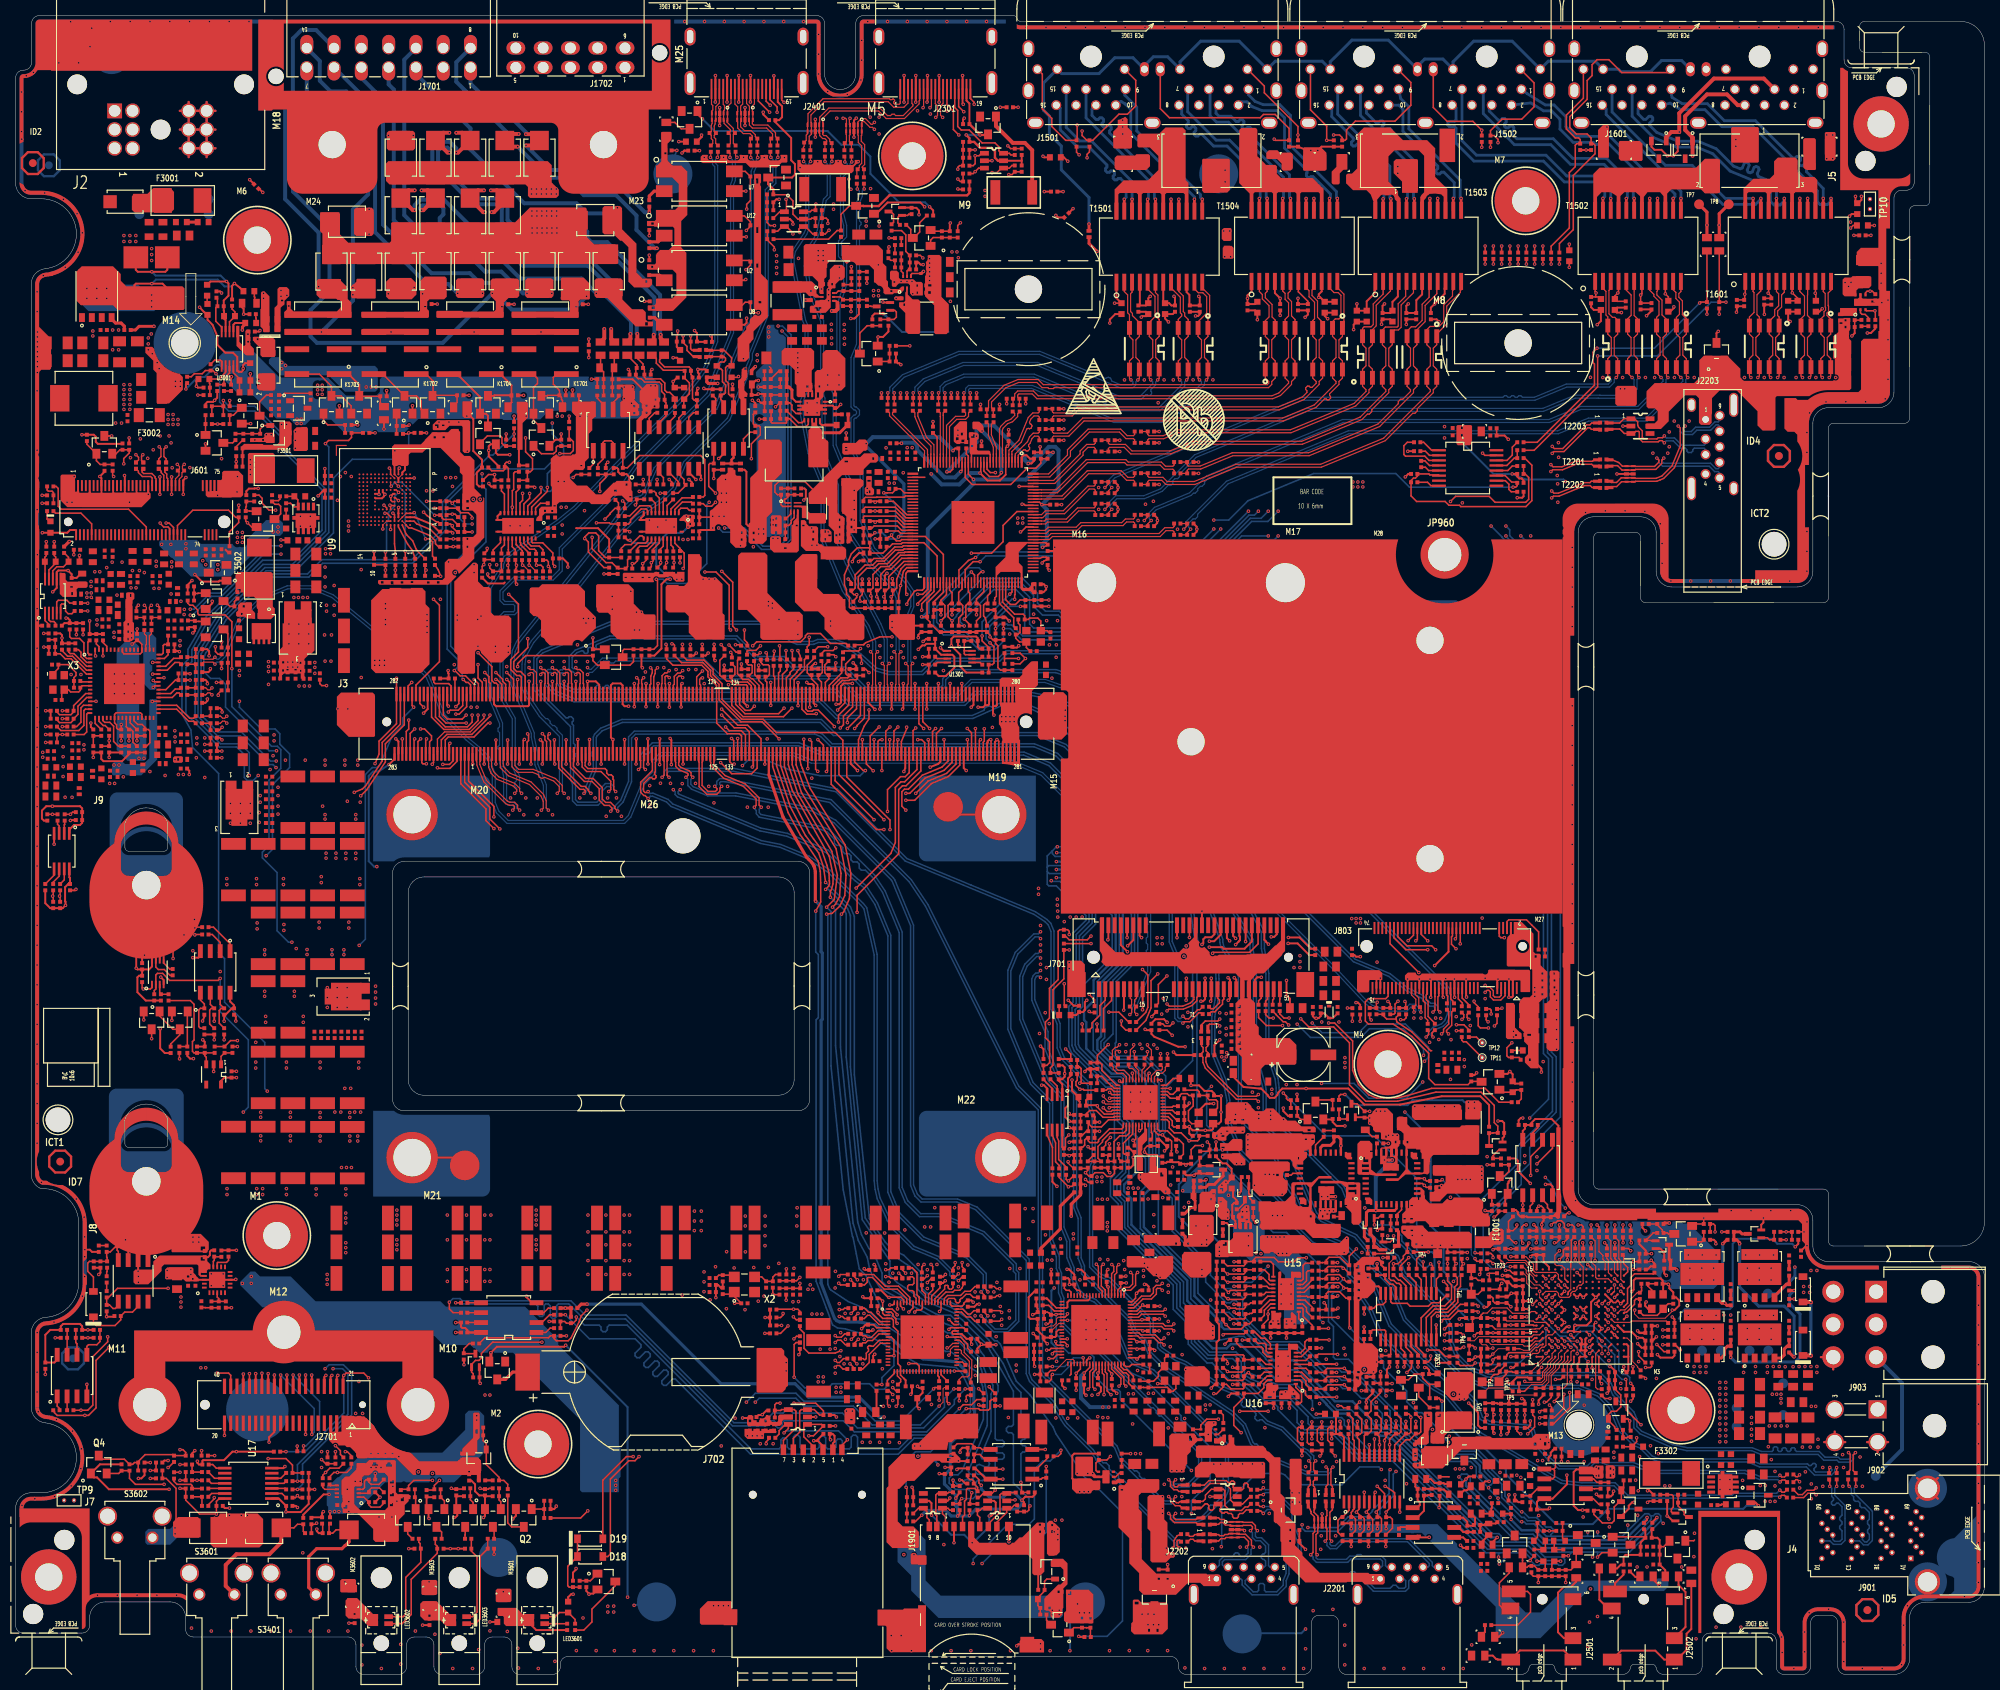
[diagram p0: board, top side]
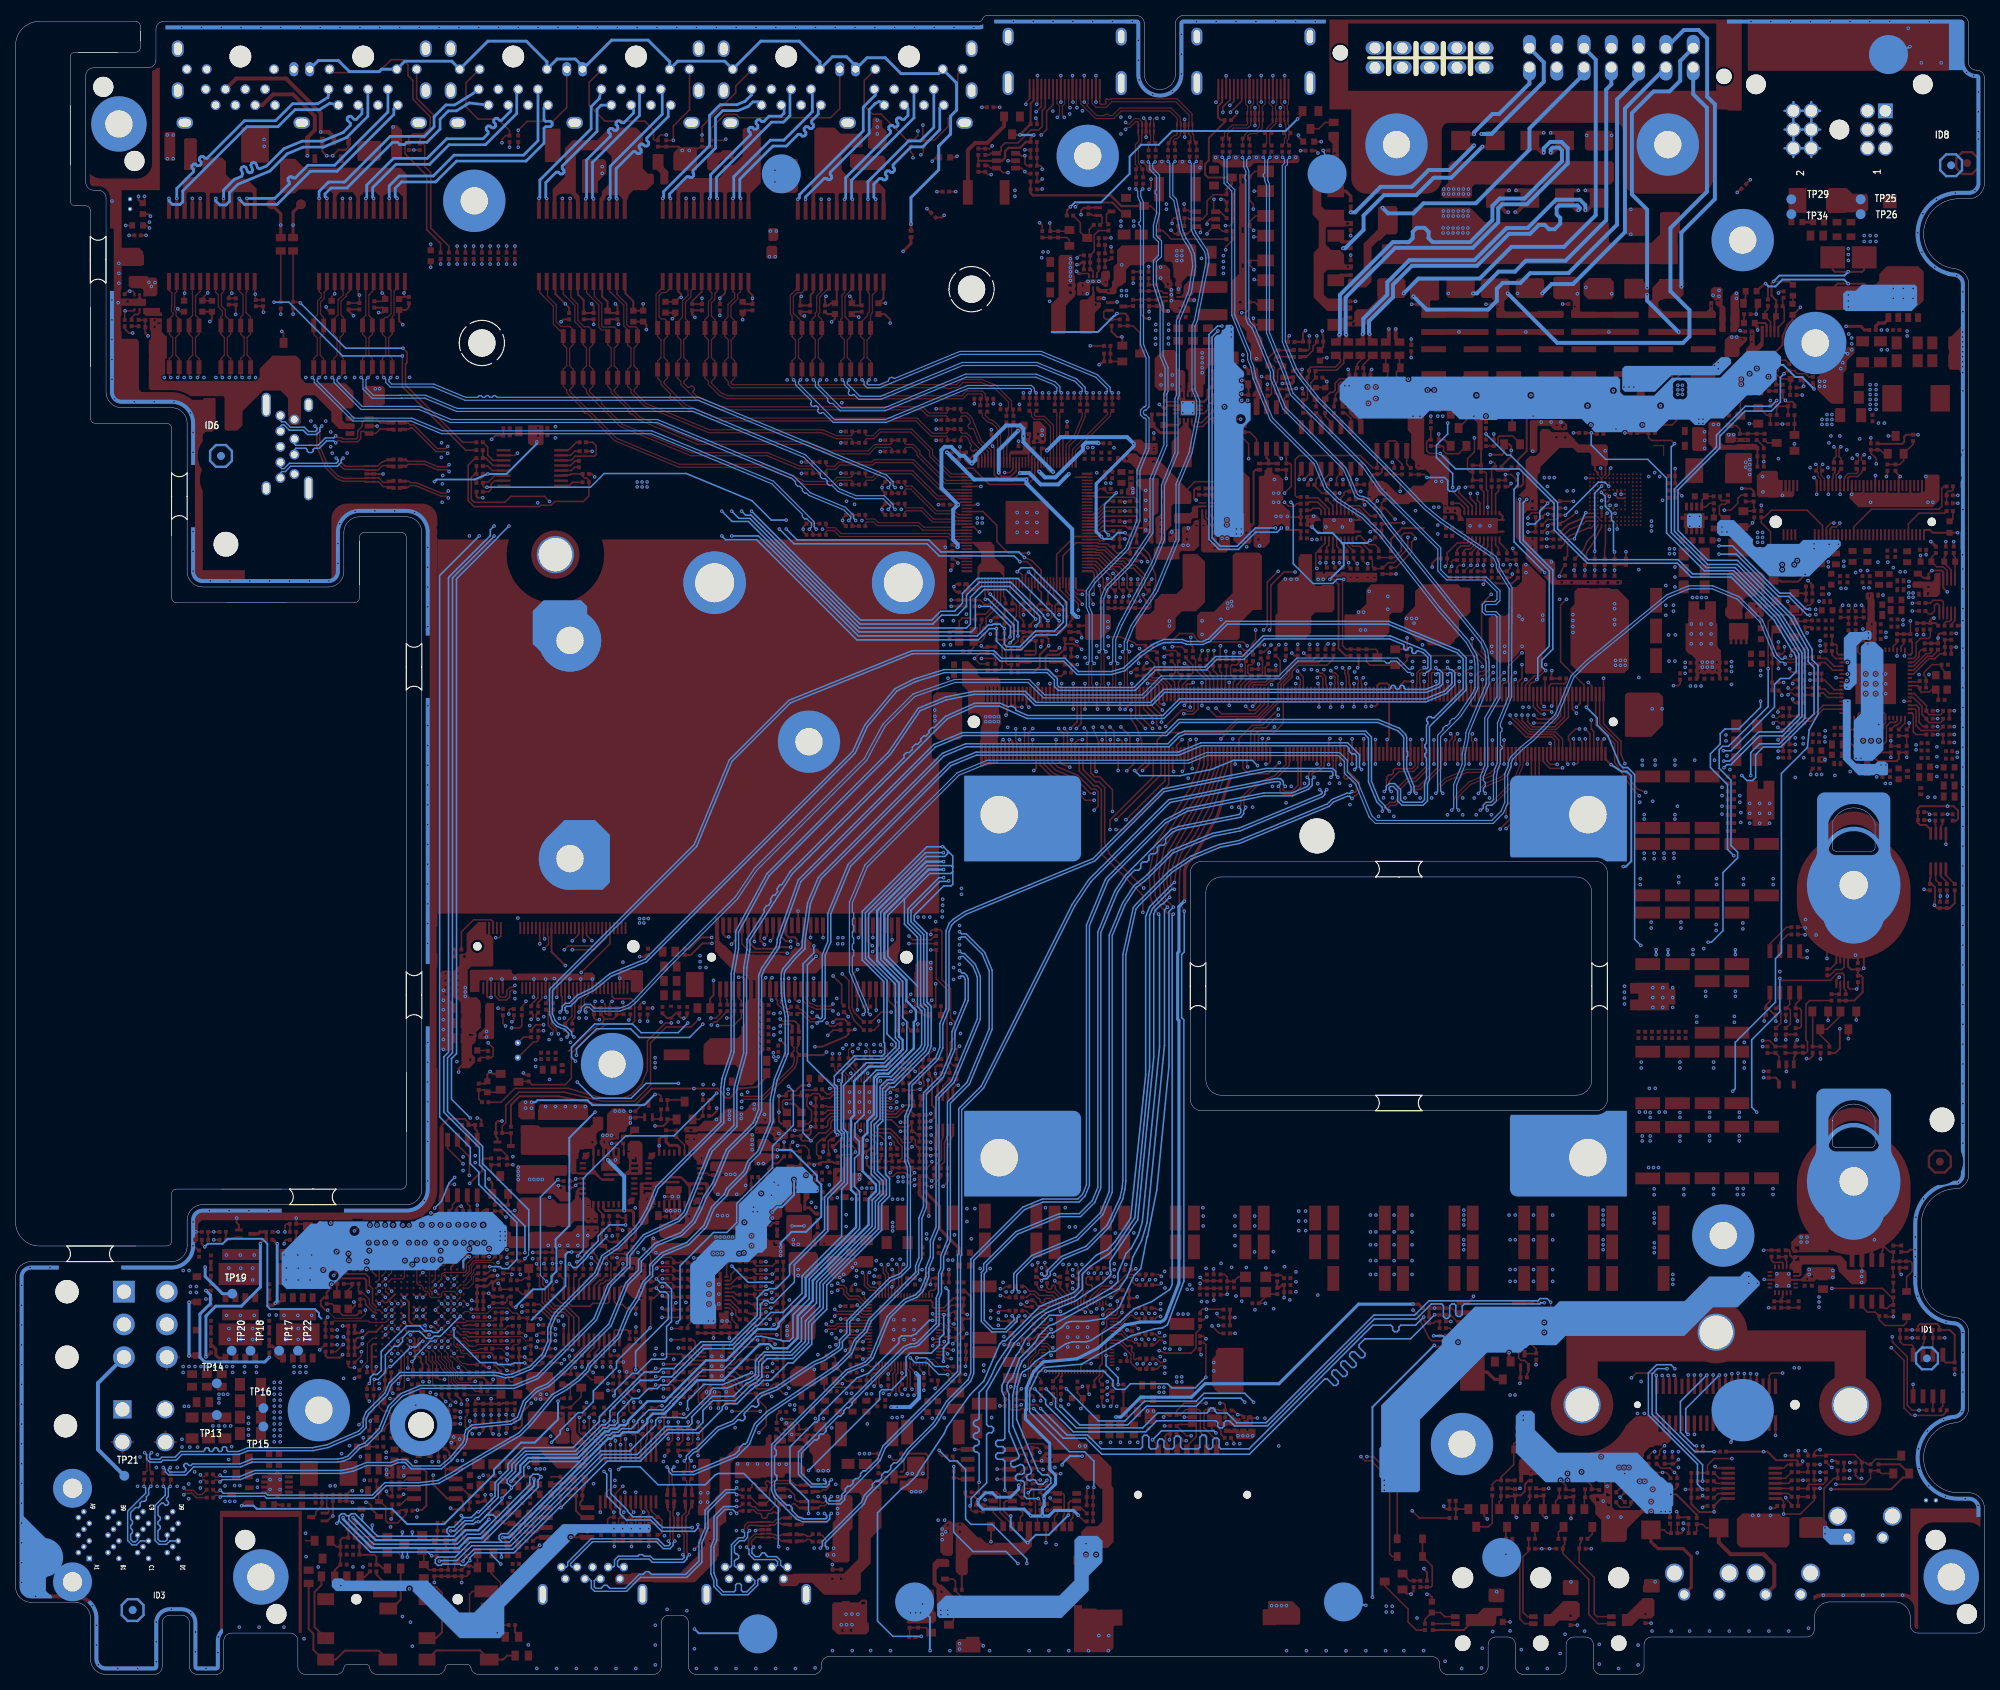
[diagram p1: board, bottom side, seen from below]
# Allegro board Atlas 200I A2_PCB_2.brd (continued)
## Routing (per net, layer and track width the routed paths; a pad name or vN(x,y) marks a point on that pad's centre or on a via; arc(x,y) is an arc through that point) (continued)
SPI_MISO_HUB0: length 21
  TOP w0.203: v1(134.87,42.16) 134.87,42.29 134.54,42.62 U2002.33 ; v1(126.26,34.45) 125.76,34.45 125.76,34.44 R2017.1
  ART04 w0.178: v1(126.26,34.45) 128.78,35.12 129.36,35.12 129.57,35.33 129.57,35.61 129.78,35.81 130.07,35.81 130.28,35.61 130.28,35.33 130.49,35.12 130.79,35.12 130.99,35.33 130.99,35.61 131.2,35.81 131.5,35.81 131.7,35.61 131.7,35.33 131.91,35.12 132.27,35.12 132.52,35.33 132.63,35.7 132.41,36.34 132.45,36.44 132.86,36.7 133.15,36.63 133.89,35.44 134.18,35.38 134.43,35.53 134.49,35.82 133.75,37.01 133.81,37.3 133.88,37.34 134.28,37.6 134.89,39.08 134.89,42.13 134.87,42.14 v1(134.87,42.16)
SPI_MISO_HUB1: length 10.4
  TOP w0.152: U2101.46 120.2,42.47 119.62,41.89 v1(119.47,41.89)
  TOP w0.203: R2013.1 124.87,36.83 v1(124.87,36.91)
  ART04 w0.178: v1(119.47,41.89) 119.47,41.86 121.95,39.39 121.95,38.79 123.44,37.29 124.49,37.29 v1(124.87,36.91)
SPI_MOSI_HUB: length 83.8
  TOP w0.203: R2004.1 v1(56.44,47.68) ; R2018.2 v1(121.79,36.63)
  BOTTOM w0.203: v1(56.44,47.68) 56.87,47.68 57.02,47.52 66.69,47.52 66.98,47.23 66.98,46.16 67.22,45.92 67.55,45.92 67.79,46.16 67.79,47.34 67.98,47.52 68.32,47.52 68.58,47.26 68.58,45.93 68.84,45.67 69.13,45.67 69.39,45.93 69.39,47.31 69.6,47.52 70.94,47.52 72.87,45.59 78.23,45.59 91.95,31.88 96.16,31.88 96.83,32.54 97.28,32.54 97.51,32.3 97.51,31.86 97.75,31.62 98.09,31.62 98.33,31.86 98.33,32.3 98.57,32.54 106.15,32.54 107.57,31.11 116.84,31.11 120.4,34.67 120.4,35.23 v1(121.79,36.63)
SPI_MOSI_HUB0: length 20
  TOP w0.203: v1(132.23,41.6) 132.59,41.6 132.8,41.82 U2002.35 ; v1(121.92,35.1) 121.92,35.69 122.05,35.81 R2018.1
  ART04 w0.178: v1(121.92,35.1) 122.25,35.43 124.56,35.43 128.6,37.11 130.8,37.11 132.68,38.99 133.35,38.99 133.7,39.33 133.95,39.94 133.95,40.77 133.12,41.6 v1(132.23,41.6)
SPI_MOSI_HUB1: length 6.5
  TOP w0.152: R2014.1 122.5,37.92 122.63,38.05 122.63,40.33 121.67,41.3 121.67,42.26 121.25,42.68 121.25,42.68 121.1,42.83 121.1,42.83 121.06,42.87 U2101.47
SPI_SCK_HUB: length 79.5
  TOP w0.203: v1(55.63,47.75) 55.63,46.89 56.11,46.41 R2001.2 ; R2019.2 v1(120.33,36.63)
  BOTTOM w0.203: v1(55.63,47.75) 56.08,48.21 57,48.21 57.28,47.93 71.22,47.93 73.05,46.1 78.3,46.1 92.12,32.28 95.89,32.28 97.13,33.53 98.43,33.53 98.67,33.77 98.67,33.92 98.91,34.16 99.24,34.16 99.48,33.92 99.48,33.77 99.72,33.53 106.05,33.53 107.95,31.62 116.46,31.62 119.13,34.29 119.13,35.42 v1(120.33,36.63)
SPI_SCK_HUB1: length 6.1
  TOP w0.152: U2101.44 121.14,41.67 121.29,41.53 121.29,41.2 122.31,40.17 122.31,38.39 122.1,38.18 121.36,38.18 121.01,37.82
  TOP w0.203: R2015.1 121.01,37.82
SPWR_DET_REAR_HUB1: length 5.9
  TOP w0.203: U2002.44 136.96,40.56 v1(136.91,40.61) ; R2008.1 v1(132.97,39.5)
  BOTTOM w0.178: v1(132.97,39.5) 134.54,39.5 135.66,40.61 v1(136.91,40.61)
SPWR_DET_USB2: length 18.4
  TOP w0.203: U2101.76 112.69,47.6 112.48,47.39 v1(112.12,47.39) ; R2103.2 98.11,45.78 98.43,46.1 v1(98.43,46.3)
  ART04 w0.178: v1(98.43,46.3) 99.44,47.32 103.61,47.32 104.65,48.36 106.96,48.36 107.95,47.37 108.97,47.37 110.36,45.97 111.38,45.97 112.12,46.71 v1(112.12,47.39)
SYS_RST_OUT: length 242.9
  TOP w0.203: R115.1 158.8,48.76 R343.1 157.72,48.37 157.46,48.11 155.6,48.11 v1(155.5,48.2) 155.37,48.2 R342.2 ; J3.293 51.1,119.93 v1(51.18,120.01)
  ART03 w0.178: v1(51.18,120.01) 49.78,118.62 48.9,118.62 44.2,113.92 43.43,113.92 42.55,113.03 v1(42.55,112.01)
  ART04 w0.178: v1(155.5,48.2) 156.26,48.2 156.78,47.68 156.78,44.78 155.93,43.93 155.93,42.44 155.45,41.96 155.45,41.03 156.6,39.88 156.6,35.93 152.65,31.98 151.49,31.98 140.01,20.5 138.35,20.5 134.61,16.75 131.99,16.75 127.74,21.01 77.92,21.01 73.13,25.8 73.13,29.8 68.64,34.29 57.56,34.29 52.26,39.58 48.35,39.58 36.4,51.53 36.4,78.21 34.65,79.96 34.65,94.74 34.98,95.07 34.98,96.85 37.26,99.14 37.26,106.22 41.22,110.18 41.22,110.69 v1(42.55,112.01)
SYS_RST_OUT_R: length 275.2
  TOP w0.203: v1(171.12,44.45) 171.04,44.53 R335.2 170.63,48.26 169.79,49.1 168.67,49.1 168.35,49.1 168.1,48.84 R334.2 167.61,48.42 167.61,48.41 R124.2 ; v1(19.56,26.54) 19.61,26.54 R2780.2 ; v1(202.82,57.66) 203.07,57.4 R2847.2
  ART03 w0.178: v1(153.49,16.13) 153.85,15.77 160.78,15.77 165.2,20.19 166.09,20.19 167.79,21.89 169.88,21.89 174.79,26.81 175.37,26.81 175.38,26.81 177,26.81 178.38,25.42 v1(178.38,24.46)
  ART04 w0.178: v1(171.12,44.45) 172.29,45.62 173.25,45.62 177.42,49.78 177.42,53.85 179.64,56.07 179.64,56.53 180.24,57.12 183.64,57.12 183.72,57.2 183.79,57.2 190.28,63.69 190.28,65.61 192.75,68.07 194.85,68.07 196.11,66.8 196.11,64.67 195.58,64.13 195.58,60.67 195.94,60.31 195.94,59.54 197.47,58 197.47,57.24 200.36,54.36 203.43,54.36 204.32,55.24 204.32,55.59 202.82,57.09 v1(202.82,57.66) ; v1(178.38,24.46) 178.46,24.46 v1(183.77,29.77) ; v1(19.56,26.54) 19.56,24.63 26.59,17.6 69.93,17.6 73.74,13.79 120.83,13.79 122.39,15.35 124.83,15.35 127.2,12.98 138.57,12.98 143.26,17.68 151.94,17.68 v1(153.49,16.13)
  BOTTOM w0.203: v1(183.77,29.77) 182.65,30.89 182.65,31.28 180.36,33.58 179.81,33.58 178.41,34.98 178.41,36.35 175.44,39.32 175.44,40.13 v1(171.12,44.45)
TAISHAN_POROFF_IN: length 232.3
  TOP w0.203: R2952.2 63.2,154.71 62.99,154.91 R150.2 ; R150.2 62.74,154.61 62.54,154.41 61.06,154.41 R2990.2 ; R150.2 62.74,155.3 62.94,155.5 v1(63.32,155.5) ; R2846.2 v1(205.11,55.37)
  ART03 w0.178: v1(63.32,155.5) 63.42,155.6 70.53,155.6 72.53,157.61 100.3,157.61 104.33,161.65 106.39,161.65 107.02,162.28 122.66,162.28 123.24,161.7 133.89,161.7 134.08,161.51 143.72,161.51 145.23,160 155.63,160 171.26,144.37 171.26,122.21 187.33,106.14 187.33,96.47 193.34,90.46 193.34,73.81 192.44,72.91 192.44,62.61 194.79,60.27 194.79,59.65 196.24,58.19 196.24,57.7 197.43,56.51 203.96,56.51 v1(205.11,55.37)
TAISHAN_POROFF_OUT: length 362.5
  TOP w0.203: R152.2 76.89,149.6 76.25,148.96 76.25,148.88 v1(75.59,148.21) ; R152.2 R2955.2 ; R152.2 77.32,150.28 R2993.2 ; v1(190.63,52.83) 190.63,52.96 190.22,53.36 R2845.2
  ART03 w0.178: v1(190.63,52.83) 190.63,52.58 190.16,52.11 190.16,49.98 190.74,49.4 191.94,49.4 193.15,48.19 193.15,45.89 195.23,43.81 198.24,43.81 199.91,42.14 199.91,41.54 199.14,40.77 199.14,38.87 197.29,37.02 189.67,37.02 188.32,38.38 180.11,38.38 179.62,37.88 178.08,37.88 177.38,38.59 175.99,38.59 175.02,39.56 172.78,39.56 170.96,37.74 170.15,37.74 169.51,37.1 169.22,37.1 168.84,36.72 163.69,36.72 163.41,36.44 163.41,36.13 162.3,35.01 159.92,35.01 154.42,29.51 152.42,29.51 151.58,28.68 147.41,28.68 145.39,26.66 134.45,26.66 127.64,19.85 100.61,19.85 94.5,25.97 66.39,25.97 60.69,31.67 59.11,31.67 58.14,32.64 58.14,34.19 55.04,37.29 55.04,40.56 41.28,54.33 41.28,58.67 39.99,59.96 39.99,81.77 38.86,82.9 38.86,93.06 36.98,94.94 36.98,97.92 33.66,101.25 33.66,102.18 26.49,109.35 26.49,115.37 26.94,115.81 26.94,120.08 32.91,126.05 32.91,130.29 32.55,130.64 32.55,146.75 38.83,153.03 42.42,153.03 v1(43.05,153.67)
  ART04 w0.178: v1(75.59,148.21) 72.81,148.21 72.62,148.4 60.76,148.4 57.54,149.75 55.64,149.75 54.53,150.86 54.53,152.15 52.45,154.23 44.35,154.23 43.79,153.67 v1(43.05,153.67)
TAISHAN_POWEROFF_IN: length 31.4
  TOP w0.203: v1(60.81,142.35) 60.81,141.93 R154.1 R2973.2 R2948.1 ; v1(52.71,120.01) 52.6,119.91 J3.299
  ART03 w0.178: v1(52.71,120.01) 53.22,120.53 53.22,125.31 54.52,126.61 54.52,135.99 58.87,140.33 59.12,140.33 60.07,141.29 60.07,141.62 v1(60.81,142.35)
TAISHAN_POWEROFF_OUT: length 56
  TOP w0.203: R2949.1 78.49,143 78.49,142.11 78.23,141.86 77.34,141.86 R156.1 77.11,141.99 76.48,142.62 75.73,142.62 73.94,144.41 v1(73.94,145.87) ; v1(49.6,120.01) J3.287
  ART03 w0.178: v1(49.6,120.01) 49.43,120.19 49.43,137.31 55.5,143.38 56.77,143.38 59.22,145.83 71.76,145.83 72.11,146.18 73.63,146.18 v1(73.94,145.87)
TAISHAN_SLEEP_IN: length 32.3
  TOP w0.203: R2922.1 R155.1 60.11,142.43 v1(60.05,142.37) 59.84,142.16 R2974.2 ; v1(51.18,121.28) 50.6,120.7 J3.291
  ART03 w0.178: v1(60.05,142.37) 59.56,141.88 59.56,141.32 59.06,140.82 58.81,140.82 54.13,136.13 54.13,126.88 52.84,125.59 52.84,121.52 52.14,120.81 51.65,120.81 v1(51.18,121.28)
TAISHAN_SLEEP_IN_R: length 229.1
  TOP w0.203: R2843.2 198.7,54.63 198.5,54.43 198.5,53.72 v1(197.99,53.21) ; R2921.2 R151.2 v1(61.43,153.92) 60.66,153.92 R2991.2
  ART03 w0.178: v1(61.43,153.92) 63.22,153.92 64.51,155.22 70.68,155.22 72.69,157.23 100.55,157.23 104.59,161.26 106.55,161.26 107.18,161.9 122.5,161.9 123.09,161.32 133.36,161.32 134.24,160.44 144.25,160.44 145.72,158.97 156.12,158.97 170.88,144.21 170.88,122.05 186.94,105.98 186.94,96.32 192.96,90.3 192.96,74.03 191.33,72.4 191.33,62.83 193.76,60.39 193.76,59.85 195.2,58.42 195.2,57.28 196.6,55.88 196.6,54.61 v1(197.99,53.21)
TAISHAN_SLEEP_OUT: length 59.1
  TOP w0.203: J3.289 50.1,120.97 50.42,121.28 v1(50.42,122.43) ; R153.1 75.46,141.99 73.46,143.99 73.46,145.26 72.99,145.73 ; 72.99,145.73 72.99,145.91 73.51,146.43 74.41,146.43 74.78,146.06 74.78,144.14 75.64,143.28 R2976.2 R2923.1 ; 72.99,145.73 v1(72.99,145.71)
  ART03 w0.178: v1(72.99,145.71) 72.72,145.44 59.97,145.44 56.65,142.12 54.78,142.12 49.86,137.2 49.86,122.98 v1(50.42,122.43)
TAISHAN_SLEEP_OUT_R: length 346.5
  TOP w0.203: v1(74.5,147.73) 76.17,147.73 76.31,147.58 R2956.2 R149.2 R2992.2 ; R2844.2 203.82,35.39 v1(204.48,35.39)
  ART03 w0.178: v1(204.48,35.39) 203.41,35.39 202.4,36.41 200.45,36.41 199.77,37.08 198.5,37.08 197.67,36.25 189.36,36.25 188,37.62 180.47,37.62 179.97,37.12 177.77,37.12 177.11,37.78 172.76,37.78 171.02,36.04 165.1,36.04 164.66,35.61 163.52,35.61 162.54,34.63 162.16,34.63 161.89,34.36 161.89,33.92 161.16,33.2 158.64,33.2 154.58,29.13 152.58,29.13 151.74,28.3 147.57,28.3 145.55,26.28 135.47,26.28 128.67,19.47 100.46,19.47 94.48,25.45 66.14,25.45 60.31,31.28 58.94,31.28 57.68,32.54 57.68,33.96 54.66,36.98 54.66,40.21 40.64,54.23 40.64,58.65 37.36,61.92 37.36,87.37 36.6,88.13 36.6,97.76 33.15,101.21 33.15,102.15 25.95,109.35 25.95,119.99 arc(25.97,120.08) 26.02,120.15 31.81,125.94 arc(31.86,126.02) 31.88,126.1 31.88,146.62 38.93,153.67 v1(41.66,153.67)
  ART04 w0.178: v1(41.66,153.67) 42.13,153.2 43.95,153.2 44.6,153.85 49.48,153.85 50.8,152.53 53.47,152.53 54.18,151.82 54.18,150.67 55.49,149.36 57.31,149.36 60.76,147.93 72.2,147.93 72.41,147.73 v1(74.5,147.73)
TEC+:
  vias: v1(221.89,46.06) v1(222.1,44.37) v1(222.1,42.98) v1(223.62,44.37) v1(223.62,42.98) v1(223.67,46.06) v1(225.15,44.37) v1(225.15,42.98) v1(225.45,46.06)
TEC-:
  vias: v1(214.53,46.06) v1(214.73,44.37) v1(214.73,42.98) v1(216.31,46.06) v1(216.26,44.37) v1(216.26,42.98) v1(217.78,44.37) v1(217.78,42.98) v1(218.08,46.06) v1(219.08,46.1) v1(219.96,46.1) v1(229.32,49.77) v1(229.32,49) v1(230.08,49.77) v1(230.08,49)
TEC_GND: length 17
  TOP w0.203: J2001.1 v1(176.55,65.99)
  TOP w0.254: 174.5,59.57 v1(174.45,59.51)
  TOP w0.305: 176.86,59.51 177.1,59.76 U11.15 ; U11.11 174.5,59.57
  TOP w0.381: 176.86,59.51 v1(174.45,59.51) 173.51,59.51 173.24,59.25 Q1001.2 173.24,57.62 172.97,57.35 172.97,56.12 R1010.1
  BOTTOM w0.508: v1(174.45,59.51) 174.45,63.89 v1(176.55,65.99)
TEC_TRIM1: length 5.5
  TOP w0.203: R1011.2 174.57,53.98 174.57,53.98 176.14,53.98 Q1002.3
  TOP w0.381: Q1002.3 177.36,55.19 177.36,56.8 R1002.2
TEC_TRIM2: length 3.5
  TOP w0.381: Q1002.2 174.89,54.47 174.52,54.84 R1008.1 R1010.2 174.22,55.98 173.74,56.46 Q1001.3
TPM_CLK: length 2.4
  TOP w0.203: R182.2 R181.2 R2776.2
TPM_CS_N: length 2.2
  TOP w0.203: R175.2 R287.2 R2777.2
TPM_INT: length 28.4
  TOP w0.203: J3.191 106.1,119.83 105.11,120.83 97.57,120.83 95.87,122.53 93.16,122.53 90.6,125.08 90.6,127.1 89.45,128.24 89.45,128.94 88.27,130.12 86.09,130.12 R2759.1
TPM_INT_R: length 298.6
  TOP w0.203: v1(85.52,132.14) R2759.2 ; v1(155.42,39.88) 155.42,40.21 155.24,40.39 R291.2 154.84,40.84 154.99,41 157.4,41 157.53,40.87 R292.1 157.54,40.38 R103.1
  ART03 w0.178: v1(119.05,16.66) 120.17,15.53 129.1,15.53 v1(133.35,19.79)
  ART04 w0.178: v1(85.52,132.14) 85.52,131.55 84.74,130.76 78.98,130.76 77.05,128.83 77.05,116.04 74.88,113.87 60.02,113.87 58.95,114.93 40.46,114.93 34.42,108.89 34.42,105.16 33.78,104.52 33.78,100.2 30.33,96.75 30.33,76.17 25.69,71.54 25.69,60.54 26.92,59.31 26.92,53.72 27.71,52.93 27.71,50.39 29.78,48.32 29.78,41.69 32.23,39.24 38.47,39.24 39.25,38.46 39.25,36.63 54.8,21.08 70.2,21.08 74.99,16.3 118.69,16.3 v1(119.05,16.66) ; v1(155.42,39.88) 154.58,39.04 154.58,35.25 152.73,33.4 151.66,33.4 139.78,21.51 135.08,21.51 v1(133.35,19.79)
TPM_MISO: length 18.2
  TOP w0.203: R2778.2 v1(36.12,29.29) ; R285.2 v1(23.27,24.9) R219.2
  ART03 w0.178: v1(23.27,24.9) 23.81,24.9 28.19,29.29 34.03,29.29 34.23,29.49 34.23,30.12 34.44,30.33 34.74,30.33 34.95,30.12 34.95,29.49 35.15,29.29 v1(36.12,29.29)
TPM_MOSI: length 4.5
  TOP w0.203: R180.2 R183.2 22.63,24.23 22.48,24.38 20.7,24.38 20.32,24.76 R2779.2
TPM_ON_LINE1: length 12.4
  TOP w0.254: J2701.31 v1(33.99,38.4) ; J2701.6 v1(37.99,30.78)
  BOTTOM w0.203: v1(37.99,30.78) 38.3,31.09 38.3,34.1 v1(33.99,38.4)
TPM_ONLINE: length 26
  TOP w0.203: v1(112.4,133.1) 110.82,133.1 109.01,132.35 108.8,132.13 108.79,132.13 108.74,132.08 107.7,132.08 R202.1 ; v1(115.44,121.41) 115.1,121.07 J3.227
  ART03 w0.178: v1(119,128.78) 119,129.09 115,133.1 v1(112.4,133.1)
  ART04 w0.178: v1(119,128.78) 117.93,127.71 117.83,127.47 117.83,124.05 115.44,121.67 v1(115.44,121.41)
TPM_TYPE: length 180
  TOP w0.203: v1(187.76,51.31) 187.88,51.43 R203.2 ; R2783.2 R2784.1 39.78,27.03 v1(39.24,27.56)
  ART03 w0.178: v1(39.24,27.56) 39.65,27.96 42.43,27.96 44.49,30.02 59.53,30.02 72,17.55 129.18,17.55 135.93,24.29 145.2,24.29 147.98,27.08 152.57,27.08 153.34,27.85 157.09,27.85 162.9,33.66 162.9,34.36 163.18,34.63 164.23,34.63 165.25,35.66 167.94,35.66 169.3,35.1 171.85,35.1 172.17,35.42 174.67,35.42 174.82,35.27 176.39,35.27 176.53,35.41 181.1,35.41 181.64,35.94 v1(184.4,35.94)
  ART04 w0.178: v1(184.4,35.94) 184.4,36.83 185,37.43 185,41.4 184.19,42.21 184.19,47.74 v1(187.76,51.31)
TYPE_ID0: length 16.5
  TOP w0.203: U2703.19 v1(173.62,29.46) ; R2725.1 174.98,37.36 R125.1 175.06,37.34 R2741.2
  TOP w0.254: R2741.2 175.06,38.86 v1(175.06,38.86)
  ART04 w0.178: v1(173.62,29.46) 172.76,30.32 172.76,33.89 171.89,34.76 171.89,35.14 172.12,35.37 172.12,37.5 173.9,39.28 174.64,39.28 v1(175.06,38.86)
TYPE_ID1: length 10
  TOP w0.203: U2703.20 172.97,30.63 R2726.1 173.51,30.89 173.86,31.24 173.86,32.79 R2742.2 173.46,33.43 173.84,33.81 173.84,34.98 174.37,35.51 174.42,35.51 175.03,36.12 R126.1
UART0_RX: length 23.4
  TOP w0.203: v1(59.31,131.06) 61.09,129.29 61.09,127.5 61.41,127.18 61.62,127.18 61.85,126.95 J3.14 ; R41.2 68.53,141.93 v1(68.33,142.14) 68.33,142.75 68.12,142.95 R2928.1
  ART03 w0.178: v1(68.33,142.14) 68.33,141.05 59.92,132.65 59.92,132.54 59.82,132.44 59.82,131.57 v1(59.31,131.06)
UART0_RX_R: length 154.2
  TOP w0.203: R1614.1 R1644.1 193.6,154 194.06,153.54 194.06,150.75 193.68,150.37 189.74,150.37 188.98,151.13 184.68,151.13 v1(184.02,150.47) ; v1(68.2,152.27) 68.2,151.76 66.19,149.76 U2904.3
  ART03 w0.178: v1(184.02,150.47) 182.73,149.17 170.32,149.17 156.83,162.67 146.34,162.67 143.57,165.43 142.04,165.43 141.52,165.95 110.83,165.95 109.83,164.95 97.71,164.95 93.29,160.53 v1(68.83,160.53)
  BOTTOM w0.203: v1(68.83,160.53) 68.83,159.13 70.28,157.68 70.28,156.13 68.2,154.05 v1(68.2,152.27)
UART0_TX: length 35.4
  TOP w0.203: J3.16 62.35,127.01 61.72,127.63 v1(61.6,127.63) ; R2937.1 84.35,143.23 84.45,143.14 v1(84.45,142.62) 84.45,142.1 R47.2
  ART03 w0.178: v1(84.45,142.62) 83.57,143.5 75.51,143.5 74.79,142.77 73.31,142.77 62.71,132.17 62.71,130.4 62.1,129.79 62.1,128.14 v1(61.6,127.63)
UART0_TX_R: length 116.8
  TOP w0.203: v1(89.76,150.37) 89.26,149.86 88.52,149.86 88.19,150.19 R2941.2 ; v1(192.05,152.3) 192.38,152.3 192.58,152.5 R1642.1 192.48,152.96 191.87,152.96 191.04,153.79 U1601.11
  ART03 w0.178: v1(89.76,150.37) 90.27,150.88 93.87,150.88 98.27,155.28 126.58,155.28 128.7,153.16 141.61,153.16 143.19,151.57 143.19,150.56 144.4,149.35 152.4,149.35 v1(153.67,148.08)
  BOTTOM w0.203: v1(192.05,152.3) 178.77,152.3 177.01,154.05 166.47,154.05 158.06,150.57 155.58,148.08 v1(153.67,148.08)
UART1_RX: length 26.9
  TOP w0.203: R2946.1 63.2,142.37 v1(63.12,142.29) 63.2,142.21 R2997.2 ; J3.18 62.85,127.01 62.46,127.41 62.46,127.66 v1(61.6,128.52)
  ART03 w0.178: v1(63.12,142.29) 59.36,138.53 58.57,138.53 55.96,135.93 55.96,129.84 v1(56.26,129.54)
  ART04 w0.178: v1(61.6,128.52) 61.15,128.97 56.83,128.97 v1(56.26,129.54)
UART1_RX_R: length 225.3
  TOP w0.203: U2904.8 63.69,149.72 v1(63.7,149.73) 63.7,151.84 63.88,152.02 63.88,154.09 64.07,154.28 R33.2 ; R2879.1 195.33,39.01 v1(195.71,39.39)
  ART03 w0.178: v1(63.7,149.73) 64.62,148.82 73.94,148.82 74.22,149.1 80.3,149.1 80.64,149.44 93.98,149.44 98.68,154.14 112.57,154.14 114.56,152.15 124.85,152.15 127.62,149.38 127.62,146.62 130.12,144.12 140.3,144.12 142.74,141.68 142.74,120.23 149.28,113.69 154.81,113.69 170.41,98.1 170.41,89.91 173.36,86.96 173.36,85.66 174.33,84.68 174.33,83.57 172.84,82.08 172.84,75.88 181.53,67.18 181.53,60.53 183.21,58.86 183.21,54.85 183.17,54.81 183.17,52.5 183.73,51.94 185.89,51.94 190.75,47.08 190.75,46.19 191.67,45.27 191.95,45.27 192.48,44.74 192.48,42.62 v1(195.71,39.39)
UART1_TX: length 28.2
  TOP w0.203: J3.20 63.35,127.28 v1(62.99,127.63) ; 79.09,141.86 v1(79.09,142.49) 79.38,142.49 79.76,142.87 R2947.1
  ART03 w0.178: v1(62.99,127.63) 62.46,128.17 62.46,129.46 65.18,132.18 65.66,132.18 66.15,132.67 66.15,133.09 75.07,142.01 75.1,142.01 75.58,142.49 v1(79.09,142.49)
UART1_TX_R: length 341.8
  TOP w0.127: v1(193.55,37.59) 193.68,37.46 195.71,37.46 196.1,37.86 196.1,38.67 196.85,39.42 196.85,40 197.46,40.61 U3.D1
  TOP w0.203: v1(79.49,150.02) 79.65,150.19 R34.2 R2954.2
  ART03 w0.178: v1(42.29,154.18) 38.87,154.18 31.45,146.75 31.45,127.58 v1(28.7,124.84) ; v1(79.49,150.02) 79.05,149.59 73.26,149.59 v1(72.96,149.29) ; v1(193.55,37.59) 193.36,37.4 189.83,37.4 188.47,38.76 179.86,38.76 179.36,38.26 178.24,38.26 177.53,38.97 177.02,38.97 176.73,39.26 176.73,39.58 175.76,40.55 173.23,40.55 171.36,38.68 170.21,38.68 169.78,38.25 169.56,38.15 169.22,38.15 168.17,37.1 163.05,37.1 161.51,35.56 159.92,35.56 154.26,29.9 152.26,29.9 151.42,29.06 147.25,29.06 145.23,27.04 134.29,27.04 130.16,22.91 127.46,22.91 125.98,21.44 100.43,21.44 95.2,26.67 74.51,26.67 68.05,33.13 60.19,33.13 55.63,37.69 55.63,43.47 43.5,55.6 43.5,58.74 40.37,61.86 40.37,82.05 39.24,83.18 39.24,93.22 37.36,95.1 37.36,98.09 34.96,100.49 34.96,102.2 v1(32.13,105.03)
  ART04 w0.178: v1(42.29,154.18) 43.43,155.32 49.67,155.32 50.1,154.89 52.32,154.89 56.6,150.62 60.82,148.82 72.49,148.82 v1(72.96,149.29)
  BOTTOM w0.203: v1(32.13,105.03) 32.94,105.84 32.94,114.14 35.14,116.34 35.14,118.09 33.88,119.34 33.88,120.67 33.27,121.28 31.5,121.28 28.7,124.08 v1(28.7,124.84)
UART2_RX: length 75.7
  TOP w0.203: J3.147 95.1,116.26 94.39,115.54 91.85,115.54 v1(90.42,116.97) ; R40.2 67.64,142.04 67.39,142.29 v1(66.8,142.29) 66.75,142.34 R2929.1
  ART03 w0.178: v1(66.8,142.29) 66.8,141.15 57.52,131.86 57.52,128.46 56.52,127.46 56.52,126.06 54.99,124.54 54.99,121.89 57.81,119.07 57.81,116.52 58.09,115.85 58.72,115.22 81.05,115.22 82.04,116.2 90.17,116.2 90.42,116.46 v1(90.42,116.97)
UART2_RX_R: length 12
  TOP w0.203: v1(67.39,152.27) 67.39,151.59 65.69,149.89 U2904.4 ; R1603.1 73.58,153.94 R1611.1 71.89,153.94 v1(71.5,153.55)
  BOTTOM w0.203: v1(67.39,152.27) 67.89,151.76 68.58,151.76 68.83,152.02 68.83,153.16 69.22,153.55 v1(71.5,153.55)
UART2_TX: length 42
  TOP w0.203: R2936.1 83.5,142.65 83.49,142.65 v1(83.49,142.62) 83.46,142.6 83.46,142.57 83.43,142.54 83.31,142.25 R46.2 ; v1(90.57,141.51) 91.97,140.1 91.97,134.47 v1(92.46,133.98) ; v1(90.55,123.82) 92.61,121.77 93.88,121.77 95.6,120.05 J3.149
  ART03 w0.178: v1(92.46,133.98) 91.99,133.51 88.77,133.51 86.86,131.6 86.86,130.84 88,129.7 88.38,129.7 89.69,128.39 89.69,124.69 v1(90.55,123.82)
  ART04 w0.178: v1(83.49,142.62) 84.15,141.96 85.63,141.35 86.64,141.35 88.04,141.99 88.68,141.99 v1(90.57,141.51)
UART2_TX_R: length 19
  TOP w0.203: R2940.2 88.19,151.04 88.39,151.25 88.39,155.83 87.86,156.36 80.04,156.36 78.46,154.79 R1601.1 77.88,156.95 U1603.4
UART3_RX: length 21.2
  TOP w0.152: v1(65.86,142.29) 65.96,142.29 R39.2
  TOP w0.203: v1(63.25,138.56) 64.49,137.31 64.49,131.16 63.5,130.17 63.5,128.9 64.26,128.14 64.64,128.14 64.85,127.94 J3.26 ; R2930.1 v1(65.86,142.29)
  ART03 w0.178: v1(65.86,142.29) 63.25,139.67 v1(63.25,138.56)
UART3_RX_R: length 19.7
  TOP w0.203: U2904.5 65.19,150.15 65.93,150.89 v1(65.93,151.5) ; v1(80.49,153.29) R1625.1 R1652.2
  ART03 w0.178: v1(65.93,151.5) 73.14,151.5 74.42,152.78 79.98,152.78 v1(80.49,153.29)
UART3_TX: length 31.9
  TOP w0.203: v1(65.68,132.87) 65.68,131.72 63.88,129.92 63.88,129.03 64.26,128.65 64.77,128.65 65.35,128.07 J3.28 ; R45.2 82.73,142.42 v1(82.73,142.62) 82.73,143.17 R2935.1
  ART03 w0.178: v1(65.68,132.87) 65.68,133.16 74.91,142.39 74.94,142.39 75.67,143.12 82.23,143.12 v1(82.73,142.62)
UART3_TX_R: length 4.5
  TOP w0.203: U1602.5 85.06,153.95 85.73,153.29 85.73,152.81 R1651.2 85.93,152.5 84.96,151.54 R2939.2
UART6_RX: length 146.4
  TOP w0.203: v1(64.39,127.63) 64.35,127.6 J3.24 ; v1(136.78,83.44) 136.83,83.39 R82.2
  ART03 w0.127: 108.2,147.27 104.09,147.27
  ART03 w0.178: v1(64.39,127.63) 65.02,128.27 65.02,129.73 75.61,140.32 76.48,140.32 77.18,141.02 85.96,141.02 87.03,142.09 94.13,142.09 95.98,143.94 102.56,143.94 103.58,144.96 103.58,146.76 104.09,147.27 ; v1(136.78,83.44) 135.76,83.44 132.75,86.45 132.75,91.92 132.08,92.59 132.08,100.08 132.95,100.95 133.58,100.95 135.9,103.26 135.9,130.62 133.18,133.34 132.58,133.34 131.19,134.72 131.19,137.26 123.5,144.96 123.5,146.89 123.14,147.24 121.13,147.24 120,148.37 109.31,148.37 108.2,147.27
UART6_TX: length 151
  TOP w0.203: J3.22 63.85,127.67 v1(62.99,128.52) ; R60.2 138.71,83.41 v1(138.68,83.44)
  ART03 w0.127: 103.66,147.62 108.02,147.62
  ART03 w0.178: v1(138.68,83.44) 137.54,83.44 137.03,83.95 136.02,83.95 133.13,86.83 133.13,92.07 132.46,92.75 132.46,99.86 133.16,100.56 133.74,100.56 136.87,103.69 136.87,130.42 133.29,134 132.58,134 131.7,134.87 131.7,137.36 124.77,144.3 124.77,148.31 124.56,148.51 121.01,148.51 120.74,148.78 109.18,148.78 108.02,147.62 ; v1(62.99,128.52) 62.99,128.66 65.75,131.42 66.17,131.42 75.46,140.7 76.32,140.7 77.02,141.4 85.8,141.4 87.02,142.62 93.82,142.62 95.52,144.32 100.79,144.32 103.2,146.74 103.2,147.17 103.66,147.62
UART_DEBUG_MCU: length 6
  TOP w0.127: U3.E1 198.26,40.4 197.5,39.64 197.5,39.26 196.64,38.39 196.64,37.51 196.22,37.08 196.22,36.98 R227.2
  TOP w0.203: R227.2 R76.2
UART_MCU_DEBUG: length 9.8
  TOP w0.127: 193.93,36.73 194.41,37.21 195.83,37.21 196.37,37.74 196.37,38.51 197.23,39.37 197.23,39.88 197.87,40.51 197.87,41.16 U3.E2
  TOP w0.203: 193.93,36.73 193.52,36.32 R29.2 R228.2
UART_RS485_N: length 61.2
  TOP w0.508: LB1601.2 75.5,171.4 v1(75.5,172.6) ; v1(60.96,190.38) 61.73,190.38 62.72,189.39 D1715.2 62.74,188.98 61.35,187.59 v1(61.06,187.59)
  ART04 w0.508: v1(75.5,172.6) 75.56,172.66 75.56,178.51 72.48,181.58 71.01,181.58 70.71,181.29 70.71,180.89 70.41,180.59 69.99,180.59 69.7,180.89 69.7,181.29 69.4,181.58 68.98,181.58 68.68,181.29 68.68,180.89 68.38,180.59 67.96,180.59 67.66,180.89 67.66,181.29 67.37,181.58 66.13,181.58 63.93,183.78 63.93,186.45 62.29,188.09 61.57,188.09 v1(61.06,187.59) ; v1(60.96,190.38) 60.83,190.5 60.83,191.22 61.99,192.38 66.66,192.38 76.76,202.48 76.76,204.75 J1702.1
UART_RS485_P: length 61.2
  TOP w0.508: LB1602.2 76.38,171.32 v1(76.38,172.6) ; v1(60.07,190.38) 59.29,190.38 D1718.2 58.29,189.26 59.97,187.59 v1(60.17,187.59)
  ART04 w0.508: v1(60.17,187.59) 60.28,187.69 60.28,187.92 61.24,188.87 62.59,188.87 64.69,186.77 64.69,184.1 66.45,182.35 72.8,182.35 76.32,178.82 76.32,172.66 v1(76.38,172.6) ; v1(60.07,190.38) 60.07,191.54 61.67,193.14 66.34,193.14 76,202.8 76,204.85 74.71,206.15 J1702.2
UART_RTX_EN: length 69.7
  TOP w0.203: J3.321 58.1,114.59 61.34,111.35 v1(61.34,110.01) ; R2945.1 80.91,142.98 v1(80.43,142.49) 80.43,141.86
  ART03 w0.178: v1(61.7,142.34) 61.7,141.6 59.57,139.47 58.54,139.47 54.94,135.87 54.94,126.31 53.72,125.09 53.72,120.22 56.73,117.2 57.6,115.12 61.34,111.38 v1(61.34,110.01)
  ART04 w0.178: v1(61.7,142.34) 62.56,141.48 70.99,141.48 71.5,141.99 79.92,141.99 v1(80.43,142.49)
UART_RTX_EN_R: length 10.2
  TOP w0.203: v1(74.93,151.76) 74.93,152.78 75.69,153.54 R1609.2 ; R1602.1 R1609.2 ; R1609.2 R1610.1 ; R2953.2 v1(79.98,151.76)
  ART03 w0.178: v1(74.93,151.76) v1(79.98,151.76)
UART_RXD_5G: length 2
  TOP w0.203: R806.1 187.35,81.76 TP12.1
UART_RXD_MODULE: length 31.4
  TOP w0.203: v1(182.12,92.96) 181.61,93.47 178.44,93.47 177.28,94.63 J803.62 ; v1(184.79,83.34) 185.75,83.34 186.38,82.71 R806.2
  ART03 w0.178: v1(182.12,92.96) 180.09,90.93 179.45,90.93 177.7,89.18 177.7,88.05 179.23,86.52 179.23,85.81 178.77,85.34 178.77,82.6 180.75,80.62 184.05,80.62 184.66,81.23 184.66,81.91 184.34,82.23 184.32,82.29 184.32,82.87 v1(184.79,83.34)
UART_TXD_5G: length 3.9
  TOP w0.203: TP11.1 186.06,81.15 185.68,81.15 185.47,81.36 R807.1
UART_TXD_MODULE: length 29.7
  TOP w0.203: J803.64 176.78,94.49 178.3,92.96 v1(181.1,92.96) ; R807.2 v1(184.79,82.57)
  ART03 w0.178: v1(181.1,92.96) 180.79,92.96 177.29,89.46 177.29,87.91 178.77,86.44 178.77,86.05 178.35,85.63 178.35,82.44 180.65,80.14 184.23,80.14 185.04,80.95 185.04,82.32 v1(184.79,82.57)
UHT_ALARM: length 316.3
  TOP w0.203: J3.303 53.6,116.97 53.47,116.84 53.47,116.79 v1(53.44,116.76) ; R414.2 199.03,59.21 v1(199.24,59.21) ; R2841.2 v1(202.06,55.37) ; v1(160.63,33.76) v1(157,33.76)
  ART03 w0.178: v1(53.44,116.76) 53.34,116.66 53.29,116.66 52.38,115.75 48.82,115.75 44.45,111.38 v1(39.37,111.38)
  ART04 w0.178: v1(202.06,55.37) 202.06,56.26 201.47,56.84 201.47,58.06 201.03,58.51 199.34,59.21 v1(199.24,59.21) 199,59.21 198.49,59.42 198.23,59.67 198.23,68.75 195.14,71.84 192.4,71.84 184.4,63.85 184.4,63.03 181.49,60.12 176.28,60.12 175.13,58.98 171.76,58.98 165.13,52.35 163.93,52.35 161.43,49.85 161.43,47.14 162.38,46.19 162.38,41.02 162.4,41.01 162.4,40.62 162.38,40.61 162.38,39.75 162.4,39.74 162.4,39.35 162.38,39.34 162.38,38.48 162.4,38.47 162.4,38.08 162.38,38.07 162.38,35.87 160.63,34.12 v1(160.63,33.76) ; v1(39.37,111.38) 39.17,111.38 36.35,108.56 36.35,99.65 33.55,96.85 33.55,68.63 29.9,64.97 29.9,55.02 46.38,38.53 46.38,35.67 56.27,25.78 70.99,25.78 77.63,19.14 128.23,19.14 131.53,15.84 136.48,15.84 150.64,30 153.24,30 v1(157,33.76)
UPDATE_MODE: length 19.7
  TOP w0.203: J3.139 93.1,120.39 92.81,120.67 91.28,120.67 89.92,122.03 89.92,124.84 89.89,124.86 89.89,126.87 88.79,127.97 88.79,128.24 88.79,128.24 88.79,128.67 88,129.46 84.3,129.46 83.49,130.28 R83.2
USB2_CONN_DN2: length 10
  TOP w0.188: R2221.2 151.17,24.28 T2204.2 152.45,24.28 153.04,24.87 155.27,24.87 155.52,24.61 155.76,24.61 155.94,24.8 156.17,24.8 156.34,24.64 156.34,24.4 156.15,24.22 156.15,23.98 156.38,23.76 U2205.6 156.74,23.69 157.31,23.69 157.5,23.88 157.5,24.37 157.66,24.54 157.9,24.54 158.06,24.37 158.06,24.06 R251.1
USB2_CONN_DN3: length 10.8
  TOP w0.188: R2231.2 151.17,22.16 T2209.2 151.61,22.19 152.27,22.19 152.59,22.52 152.59,22.99 153.36,23.76 U2205.1 154.88,23.76 155.09,23.55 155.09,21.67 155.73,21.03 157.23,21.03 157.68,21.48 158.03,21.48 R253.1
USB2_CONN_DP2: length 10.1
  TOP w0.188: R2220.2 151.17,23.47 T2204.3 152.18,23.47 153.2,24.49 155.11,24.49 155.8,23.79 155.8,23.16 155.8,23.16 155.8,22.38 156.32,21.86 U2205.4 157.37,21.86 158.29,22.78 R252.1
USB2_CONN_DP3: length 10.8
  TOP w0.188: R2230.2 151.17,21.35 T2209.3 151.58,21.34 152.03,21.34 152.57,21.88 152.81,21.88 153.03,21.67 153.03,21.25 153.21,21.07 153.48,21.07 153.67,21.25 153.67,21.67 153.86,21.86 U2205.3 154.32,21.86 154.57,21.6 154.57,21.34 154.47,21.24 154.47,20.97 154.73,20.7 155,20.7 155.1,20.81 155.37,20.81 155.52,20.65 155.89,20.65 156.08,20.46 156.08,20.23 156.26,20.04 156.64,20.04 156.83,20.23 156.83,20.46 157.02,20.65 157.38,20.65 157.83,21.1 158.18,21.1 158.31,20.97 R254.1
USB2_DM1_HUB0: length 38.2
  TOP w0.188: R2111.1 126.24,46.66 v1(126.46,46.44) ; v1(142.4,36.98) 142.14,37.24 142.14,38.16 140.96,39.34 U2002.54
  ART04 w0.152: v1(142.4,36.98) 142.27,36.86 142.27,35.88 141.19,34.8 136.27,34.8 135.2,35.86 135.2,38.97 135.36,39.12 135.36,46.45 135.07,46.74 130.37,46.74 127.61,43.98 126.13,43.98 125.65,44.45 125.65,45.28 125.98,45.61 125.98,45.96 v1(126.46,46.44)
USB2_DM1_HUB1: length 3.2
  TOP w0.188: U2101.57 120.7,46.86 121.47,46.86 122.1,46.23 122.48,46.23 122.91,46.66 R2112.1
USB2_DN1: length 102.7
  TOP w0.188: R2112.2 124.23,46.46 v1(124.7,46) ; v1(94.74,111.25) 94.97,111.48 94.97,112.29 93.35,113.91 90.79,114.97 89.16,116.6 89.16,117.02 89.1,117.08 J3.123
  BOTTOM w0.188: v1(124.7,46) 124.45,45.74 124.45,45.48 125.6,44.32 127.15,44.32 128.27,45.45 128.27,51.4 127.97,51.71 127.97,52.5 124,56.47 118.55,58.72 115.92,58.72 114.09,60.55 113.32,62.41 113.32,95.15 111.18,100.32 109.87,102.29 108.99,103.16 108.47,103.16 108.2,103.43 108.2,103.96 107.93,104.23 107.41,104.23 107.14,104.5 107.14,105.02 106.87,105.29 106.34,105.29 106.07,105.56 106.07,106.08 105.8,106.35 105.28,106.35 105.01,106.62 105.01,107.15 104.09,108.06 103.3,108.39 95.37,109.97 95,110.42 95,110.82 94.74,111.07 v1(94.74,111.25)
USB2_DN2: length 148.6
  TOP w0.188: v1(88.09,128.72) 87.35,127.98 J3.116 ; R2221.1 149.9,24.33 T2204.1 149.19,24.28 148.97,24.06 148.7,24.06 148.49,24.28 148.49,24.69 v1(148.77,24.97)
  ART04 w0.152: v1(88.09,128.72) 88.47,128.34 88.95,128.34 90.35,126.94 91.43,124.34 110.03,105.74 116.12,101.67 122.56,98.23 130.26,95.04 131.21,95.04 v1(131.45,95.27)
  BOTTOM w0.188: v1(148.77,24.97) 148.54,24.74 148.54,24.56 148.66,24.43 150.34,24.43 151.72,25.82 151.72,28.38 150.03,30.07 149.73,30.07 149.48,30.32 149.48,30.62 149.26,30.84 148.91,30.84 148.55,31.19 148.55,31.55 146.96,33.15 146.68,33.15 146.29,33.54 146.29,33.82 145.89,34.21 145.62,34.21 145.22,34.6 145.22,34.88 138.39,41.71 137.61,42.04 137.16,42.04 136.67,42.24 134.06,44.85 134.06,48.2 133.76,48.94 133.76,51.4 133.48,52.07 133.48,53.58 132.62,55.66 132.62,73.27 130.17,75.71 127.25,82.76 127.25,90.32 128.21,92.62 130.58,95 131.17,95 v1(131.45,95.27)
USB2_DN3: length 133.5
  TOP w0.188: J3.117 87.6,117.11 87.66,117.05 87.66,113.89 88.65,112.9 89.92,112.9 90.33,113.31 90.33,113.71 v1(90.55,113.93) ; R2231.1 149.9,22.21 T2209.1 149.29,22.16 149.15,22.02 148.88,22.02 148.5,22.4 148.5,22.54 v1(148.77,22.81)
  BOTTOM w0.188: v1(90.55,113.93) 90.3,114.18 90.3,114.4 90.43,114.53 90.99,114.53 104.43,111.85 114.59,101.69 116.68,98.56 128.35,75.22 131.16,72.42 131.16,53.8 131.32,53.64 131.32,38.7 140.95,29.08 141.63,27.44 146.17,22.89 146.17,22.43 146.73,21.87 148.24,21.87 148.57,22.2 148.57,22.61 v1(148.77,22.81)
USB2_DP1: length 102.8
  TOP w0.188: v1(123.81,46) 124.23,45.58 R2109.2 ; v1(95.63,111.25) 95.35,111.53 95.35,112.45 93.57,114.23 91,115.3 89.54,116.76 89.54,117.02 89.6,117.08 J3.125
  BOTTOM w0.188: v1(95.63,111.25) 95.38,110.99 95.38,110.56 95.57,110.32 103.41,108.76 104.31,108.39 110.16,102.53 111.52,100.5 113.7,95.23 113.7,62.49 114.42,60.77 116.08,59.11 118.63,59.11 124.21,56.79 128.35,52.66 128.35,51.87 128.65,51.56 128.65,45.29 127.31,43.94 125.44,43.94 124.07,45.32 124.07,45.74 v1(123.81,46)
USB2_DP1_HUB0: length 38.2
  TOP w0.188: R2109.1 126.24,45.32 v1(126.46,45.55) ; U2002.53 140.56,39.2 141.76,38 141.76,37.23 v1(141.51,36.98)
  ART04 w0.152: v1(141.51,36.98) 141.89,36.6 141.89,36.04 141.03,35.18 136.43,35.18 135.59,36.02 135.59,37.36 135.74,37.52 135.97,37.52 136.12,37.67 136.12,37.9 135.97,38.05 135.74,38.05 135.59,38.2 135.59,38.81 135.74,38.96 135.74,40.95 135.99,41.21 135.99,41.41 135.74,41.66 135.74,41.87 135.99,42.12 135.99,42.32 135.74,42.58 135.74,42.78 135.99,43.03 135.99,43.24 135.74,43.49 135.74,43.69 135.99,43.95 135.99,44.15 135.74,44.4 135.74,44.61 135.99,44.86 135.99,45.06 135.74,45.32 135.74,45.52 135.99,45.77 135.99,45.98 135.74,46.23 135.74,46.61 135.23,47.12 132,47.12 131.75,47.37 131.3,47.37 131.05,47.12 130.21,47.12 127.45,44.36 126.29,44.36 126.03,44.61 126.03,45.12 v1(126.46,45.55)
USB2_DP1_HUB1: length 3.2
  TOP w0.188: U2101.56 120.7,46.48 121.31,46.48 121.94,45.85 122.49,45.85 123.01,45.32 R2110.1
USB2_DP2: length 148.6
  TOP w0.188: v1(88.09,127.84) 87.92,127.84 87.73,127.65 87.73,127.03 87.85,126.91 J3.118 ; v1(147.88,24.97) 148.11,24.75 148.11,24.12 148.55,23.68 148.97,23.68 149.19,23.47 T2204.4 149.9,23.42 R2220.1
  ART04 w0.152: v1(88.09,127.84) 88.22,127.96 88.8,127.96 90.03,126.73 90.54,125.5 91.11,124.13 97.41,117.82 97.41,117.71 97.41,117.6 97.73,117.28 97.84,117.28 97.84,117.28 97.95,117.28 98.28,116.96 98.28,116.85 98.28,116.84 98.28,116.73 98.6,116.41 98.71,116.41 98.71,116.41 98.82,116.41 99.15,116.09 99.15,115.98 99.15,115.98 99.15,115.87 99.47,115.54 99.58,115.54 99.58,115.54 99.69,115.54 109.79,105.45 115.92,101.34 122.4,97.88 130.18,94.66 131.17,94.66 v1(131.45,94.39)
  BOTTOM w0.188: v1(131.45,94.39) 131.22,94.61 130.74,94.61 128.53,92.41 127.64,90.24 127.64,82.84 130.5,75.93 133,73.43 133,55.74 133.86,53.66 133.86,52.15 134.14,51.47 134.14,49.01 134.44,48.28 134.44,45.01 136.89,42.56 137.24,42.42 137.69,42.42 138.61,42.04 152.1,28.54 152.1,25.66 150.5,24.05 148.51,24.05 148.16,24.4 148.16,24.7 v1(147.88,24.97)
USB2_DP3: length 133.5
  TOP w0.188: R2230.1 149.9,21.3 T2209.4 149.59,21.35 149.31,21.64 148.72,21.64 148.12,22.24 148.12,22.57 v1(147.88,22.81) ; J3.119 88.1,117.1 88.04,117.05 88.04,114.05 88.8,113.28 89.76,113.28 89.95,113.47 89.95,113.64 v1(89.66,113.93)
  BOTTOM w0.188: v1(147.88,22.81) 148.19,22.5 148.19,22.36 148.08,22.25 146.89,22.25 146.55,22.59 146.55,23.05 146.1,23.5 146.1,23.8 145.76,24.14 145.46,24.14 145.12,24.48 145.12,24.78 144.78,25.12 144.48,25.12 144.13,25.47 144.13,25.77 143.79,26.11 143.49,26.11 141.95,27.65 141.27,29.29 131.7,38.86 131.7,53.8 131.54,53.96 131.54,72.57 128.67,75.45 117.01,98.75 114.88,101.94 104.61,112.21 91.03,114.91 90.27,114.91 89.92,114.55 89.92,114.18 v1(89.66,113.93)
USB3_0_CONN_RX_N: length 13.6
  TOP w0.188: R2227.2 153.21,20.07 T2207.2 153.64,20.09 154.28,20.09 154.5,19.87 154.98,19.87 155.31,19.54 155.9,19.54 D2202.1 D2202.10 157.37,19.57 157.43,19.51 158.59,19.51 159.01,19.1 159.01,18.69 v1(159.26,18.44)
  BOTTOM w0.188: J2202.5 160.88,13.76 160.69,13.95 160.69,16.64 159.8,17.53 159.19,17.53 159,17.72 159,18.19 v1(159.26,18.44)
USB3_0_CONN_RX_P: length 13.6
  TOP w0.188: v1(158.37,18.44) 158.62,18.69 158.62,18.94 158.44,19.13 157.43,19.13 157.37,19.07 D2202.9 D2202.2 155.83,19.16 155.15,19.16 154.82,19.49 154.53,19.49 154.28,19.25 T2207.3 153.21,19.25 R2226.2
  BOTTOM w0.188: J2202.6 160.12,13.76 160.31,13.95 160.31,14.55 160.11,14.75 159.97,14.75 159.77,14.95 159.77,15.24 159.97,15.45 160.11,15.45 160.31,15.65 160.31,16.48 159.64,17.15 159.04,17.15 158.62,17.56 158.62,18.19 v1(158.37,18.44)
USB3_0_CONN_TX_N: length 13.2
  TOP w0.188: R2229.2 153.57,17.98 T2208.2 154.28,17.93 154.42,17.79 154.93,17.79 155.08,17.95 155.48,17.95 155.6,18.07 D2202.4 D2202.7 156.84,17.98 157.73,17.98 158.5,17.22 158.5,16.58 v1(158.75,16.33)
  BOTTOM w0.188: v1(158.75,16.33) 158.45,16.03 158.45,15.41 157.76,14.73 155.06,14.73 154.77,14.44 154.77,14.05 155.06,13.76 J2202.8
USB3_0_CONN_TX_P: length 13.2
  TOP w0.188: v1(157.86,16.33) 158.12,16.58 158.12,17.06 157.58,17.6 156.79,17.6 D2202.6 D2202.5 155.24,17.57 155.09,17.41 154.58,17.41 154.28,17.12 T2208.3 153.57,17.07 R2228.2
  BOTTOM w0.188: J2202.9 154.12,13.76 154.39,14.03 154.39,14.6 154.9,15.11 156.04,15.11 156.25,15.32 156.25,15.39 156.45,15.6 156.74,15.6 156.94,15.39 156.94,15.32 157.15,15.11 157.6,15.11 158.06,15.57 158.06,16.13 v1(157.86,16.33)
USB3_0_RX_N: length 158.9
  TOP w0.188: J3.104 84.35,126.36 84.35,126.89 84.47,127.01 84.47,128.02 84.91,128.46 85.25,128.46 v1(85.55,128.77) ; v1(148.77,20.65) 148.51,20.4 148.51,20.13 148.8,19.85 151.35,19.85 151.56,20.07 T2207.1 152.3,20.07 R2227.1
  ART04 w0.152: v1(85.55,128.77) 85.84,128.48 86.23,128.48 86.96,127.75 88.05,125.1 91.36,119.71 95.24,117.22 95.71,116.44 102.23,109.91 105.67,107.09 111.99,102.41 120.6,96.65 130.67,92.48 131.14,92.48 v1(131.45,92.79)
  BOTTOM w0.188: v1(131.45,92.79) 131.14,92.48 130.8,92.48 129.41,91.09 128.78,89.56 128.78,84.05 132.16,75.89 134.08,73.97 134.08,57.32 134.81,55.54 134.81,53.46 135.38,52.09 135.38,50.96 135.68,50.23 136.14,49.12 136.9,48.36 138.33,47.77 140.39,45.71 142.52,40.56 143.34,39.74 145.76,38.74 155.16,29.33 155.16,28.94 154.94,28.72 154.94,28.19 155.16,27.96 155.16,25.76 154.88,25.47 154.88,25 155.16,24.72 155.16,23.68 154.87,22.97 153.62,21.72 153.26,21.72 152.91,21.37 152.91,21.01 152.13,20.23 151.49,19.96 148.59,19.96 148.46,20.09 148.46,20.35 v1(148.77,20.65)
USB3_0_RX_P: length 158.9
  TOP w0.188: v1(85.55,127.88) 85.36,128.08 85.07,128.08 84.85,127.86 J3.106 ; R2226.1 152.3,19.25 T2207.4 151.61,19.25 151.4,19.47 148.64,19.47 148.13,19.97 148.13,20.4 v1(147.88,20.65)
  ART04 w0.152: v1(85.55,127.88) 85.77,128.1 86.07,128.1 86.64,127.53 87.71,124.93 87.66,124.7 87.9,124.31 88.13,124.25 88.37,123.86 88.31,123.63 88.55,123.24 88.78,123.19 91.08,119.44 94.96,116.95 95.41,116.2 101.98,109.63 105.44,106.79 111.77,102.09 120.42,96.31 130.59,92.1 131.24,92.1 v1(131.45,91.9)
  BOTTOM w0.188: v1(131.45,91.9) 131.24,92.1 130.96,92.1 129.74,90.87 129.16,89.48 129.16,84.12 132.48,76.1 134.46,74.13 134.46,57.39 135.19,55.61 135.19,53.54 135.76,52.17 135.76,51.03 136.03,50.38 136.47,49.33 137.11,48.69 138.54,48.1 140.71,45.93 142.85,40.78 143.56,40.06 145.98,39.06 155.55,29.49 155.55,23.6 155.2,22.76 152.35,19.91 151.56,19.58 148.43,19.58 148.08,19.93 148.08,20.45 v1(147.88,20.65)
USB3_0_TX_N: length 140.7
  TOP w0.188: v1(148.39,16.2) 148.56,16.38 148.56,17.18 148.97,17.79 C123.1 ; v1(85.96,115.09) 86.25,115.37 86.25,115.51 86.15,115.61 85.09,116.04 84.66,116.48 84.66,117.02 84.6,117.08 J3.105
  BOTTOM w0.188: v1(85.96,115.09) 86.22,114.83 86.22,114.03 86.69,113.56 88.76,112.7 92.35,112.7 102.19,110.74 104.96,109.26 112.29,101.93 112.43,101.73 114.78,96.04 114.78,62.72 115.35,61.36 116.1,60.6 120.73,60.6 123.11,59.62 129.62,53.11 129.62,38.58 130.03,37.58 132.79,34.82 134.01,32.79 134.05,32.68 134.55,31.93 137.89,28.59 138.52,27.65 138.59,27.5 143.31,22.77 143.69,21.86 148.67,16.88 148.67,16.49 v1(148.39,16.2)
USB3_0_TX_P: length 140.7
  TOP w0.188: J3.107 85.1,117.08 85.04,117.02 85.04,116.64 85.31,116.37 86.36,115.93 86.63,115.67 86.63,115.31 v1(86.85,115.09) ; v1(149.28,16.2) 148.95,16.54 148.95,17.07 149.05,17.22 149.28,17.22 C124.1
  BOTTOM w0.188: v1(149.28,16.2) 149.05,16.43 149.05,17.04 144.01,22.08 143.64,22.99 142.62,24.01 142.62,24.39 142.22,24.79 141.84,24.79 141.44,25.19 141.44,25.57 141.04,25.97 140.66,25.97 140.26,26.36 140.26,26.75 139.86,27.14 139.48,27.14 138.91,27.71 138.86,27.83 138.19,28.84 134.85,32.18 134.39,32.86 134.35,32.96 133.1,35.05 130.36,37.79 130,38.66 130,53.27 123.33,59.94 120.8,60.98 116.26,60.98 115.67,61.58 115.16,62.8 115.16,96.11 112.76,101.91 112.58,102.18 105.19,109.57 102.32,111.1 92.39,113.08 88.84,113.08 86.91,113.88 86.6,114.19 86.6,114.83 v1(86.85,115.09)
USB3_1_CONN_RX_N: length 22
  TOP w0.188: v1(168.78,17.09) 168.56,17.32 D2203.10 D2203.1 168.56,20.8 168.88,21.12 T2206.2 168.93,21.79 R2224.2
  BOTTOM w0.188: v1(168.78,17.09) 168.56,16.87 168.56,16.7 168.75,16.51 169.26,16.51 170.15,17.4 178.67,17.4 181.69,14.38 181.69,13.95 181.88,13.76 J2201.5
USB3_1_CONN_RX_P: length 22
  TOP w0.188: R2225.2 168.02,21.79 T2206.3 168.07,21.16 168.18,21.05 168.18,20.36 168.06,20.24 D2203.2 D2203.9 168.06,18.81 168.18,18.69 168.18,17.32 v1(167.96,17.09)
  BOTTOM w0.188: v1(167.96,17.09) 168.18,16.87 168.18,16.54 168.59,16.13 169.42,16.13 170.31,17.02 178.51,17.02 181.31,14.22 181.31,13.95 181.12,13.76 J2201.6
USB3_1_CONN_TX_N: length 18.9
  TOP w0.188: R2223.2 166.65,21.76 T2205.2 166.59,21.15 166.52,21.08 166.52,20.8 167.01,20.31 167.01,20.13 167.06,20.08 D2203.4 D2203.7 167.06,18.8 167.01,18.75 167.01,18.16 166.78,17.93 166.78,15.5 v1(166.93,15.35)
  BOTTOM w0.188: J2201.8 175.88,13.76 175.69,13.95 175.69,14.68 175.2,15.17 172.71,15.17 172.52,15.37 172.09,15.37 171.89,15.17 171.1,15.17 170.69,14.76 166.98,14.76 166.79,14.95 166.79,15.22 v1(166.93,15.35)
USB3_1_CONN_TX_P: length 18.8
  TOP w0.188: R2222.2 165.73,21.76 T2205.3 165.8,21.69 166.14,20.88 166.14,20.88 166.14,20.64 166.56,20.23 D2203.5 D2203.6 166.56,18.77 166.62,18.7 166.62,18.32 166.4,18.09 166.4,15.65 v1(166.1,15.35)
  BOTTOM w0.188: J2201.9 175.12,13.76 175.31,13.95 175.31,14.52 175.04,14.79 171.26,14.79 170.85,14.38 166.82,14.38 166.41,14.79 166.41,15.04 v1(166.1,15.35)
USB3_1_RX_N: length 155.9
  TOP w0.188: R2224.1 168.93,23.41 T2206.1 168.88,24.13 168.69,24.32 168.69,26.34 v1(168.95,26.6) ; v1(83.83,128.77) 83.53,128.47 83.26,128.47 82.91,128.12 82.91,127.1 82.85,127.04 J3.98
  ART04 w0.152: v1(131.45,90.3) 131.07,89.92 129.99,89.92 120.75,93.74 107.6,103.67 99.63,109.95 97.27,112.31 93.46,114.85 91.58,116.73 91.24,117.54 90.07,118.71 87.35,122.5 86.4,124.08 85.92,124.81 84.84,127.41 84.84,128.14 84.46,128.52 84.07,128.52 v1(83.83,128.77)
  BOTTOM w0.188: v1(168.95,26.6) 168.73,26.38 168.73,26.03 168.52,25.82 168.32,25.62 165.56,25.62 160.08,27.89 160.04,27.89 158.38,29.54 157.41,31.9 155.9,33.41 147.16,39.25 145.23,41.17 144.6,42.69 143.35,43.95 142.77,45.34 136.7,51.41 136.7,52.33 136.27,53.37 136.27,58.49 135.69,59.91 135.69,74.44 133.51,76.62 132.03,80.19 132.03,82.37 130.33,86.48 130.33,89.21 130.5,89.64 130.84,89.97 131.12,89.97 v1(131.45,90.3)
USB3_1_RX_P: length 155.9
  TOP w0.188: R2225.1 168.02,23.34 168.07,23.39 T2206.4 168.07,24.13 168.31,24.37 168.31,26.36 v1(168.06,26.6) ; v1(83.83,127.88) 83.61,128.09 83.42,128.09 83.29,127.96 83.29,127.1 83.35,127.04 J3.100
  ART04 w0.152: v1(83.83,127.88) 84.08,128.14 84.3,128.14 84.46,127.98 84.46,127.34 84.78,126.56 84.7,126.39 84.46,126.29 84.38,126.11 84.46,125.94 84.63,125.86 84.88,125.97 85.05,125.89 85.13,125.72 85.05,125.54 84.81,125.44 84.73,125.27 84.81,125.09 84.98,125.02 85.23,125.12 85.4,125.05 85.58,124.63 86.08,123.87 87.03,122.29 89.78,118.47 90.92,117.33 91.26,116.51 93.22,114.55 93.65,114.27 93.7,114.03 94.08,113.77 94.32,113.82 94.7,113.57 94.74,113.33 95.12,113.07 95.36,113.12 95.74,112.87 95.79,112.63 96.17,112.37 96.41,112.42 97.02,112.01 99.38,109.66 107.37,103.37 120.57,93.41 120.66,93.18 121.08,93.01 121.31,93.1 121.73,92.92 121.82,92.7 122.24,92.53 122.47,92.62 122.89,92.44 122.98,92.22 123.41,92.04 123.63,92.14 124.05,91.96 124.14,91.74 124.57,91.56 124.79,91.66 129.91,89.54 131.32,89.54 v1(131.45,89.41)
  BOTTOM w0.188: v1(131.45,89.41) 131.26,89.59 131,89.59 130.83,89.42 130.71,89.14 130.71,86.56 132.41,82.45 132.41,80.27 133.83,76.83 136.07,74.6 136.07,59.98 136.65,58.57 136.65,53.44 137.08,52.41 137.08,51.56 143.09,45.55 143.67,44.16 144.93,42.91 145.55,41.39 147.4,39.54 156.14,33.7 157.73,32.11 158.71,29.76 158.91,29.56 159.16,29.56 159.69,29.04 159.69,28.78 160.23,28.24 165.64,26 168.16,26 168.35,26.19 168.35,26.32 v1(168.06,26.6)
USB3_1_TX_N: length 146.6
  TOP w0.188: v1(166.74,27.39) 166.47,27.13 166.47,26.23 C127.1 ; J3.99 83.1,117.23 83.17,117.16 83.17,115.34 v1(82.92,115.09)
  BOTTOM w0.188: v1(166.74,27.39) 166.48,27.65 166.48,28.03 165.71,28.8 165.23,29 162.54,31.69 160.56,32.51 157.05,36.02 155.45,36.68 154.99,36.87 150.15,40.11 148.94,40.61 147.06,41.87 146.84,42.09 146.84,42.88 145.9,43.82 145.9,45.36 140.41,50.85 139.16,51.37 138.13,52.4 138.13,65.02 138.46,65.81 138.46,71.58 137.92,72.87 137.92,75.7 134.51,79.11 133.96,80.44 133.96,83.49 133.17,85.39 133.17,95.37 132.76,96.36 132.27,96.85 130.8,97.84 122.55,101.25 114.31,104.66 105.38,113.6 92.13,116.23 83.6,116.23 83.19,115.82 83.19,115.36 v1(82.92,115.09)
USB3_1_TX_P: length 146.6
  TOP w0.188: C128.1 166.09,26.21 166.09,27.15 v1(165.85,27.39) ; v1(83.8,115.09) 83.55,115.34 83.55,117.15 83.6,117.2 J3.101
  BOTTOM w0.188: v1(165.85,27.39) 166.1,27.65 166.1,27.87 165.49,28.48 165.02,28.68 162.32,31.37 160.34,32.19 159.86,32.67 159.59,32.67 159.48,32.56 159.21,32.56 158.95,32.82 158.95,33.09 159.06,33.2 159.06,33.47 158.11,34.42 157.85,34.42 157.73,34.3 157.47,34.3 157.2,34.57 157.2,34.84 157.32,34.95 157.32,35.22 156.84,35.7 155.3,36.33 154.81,36.54 149.97,39.77 148.76,40.27 146.82,41.57 146.46,41.93 146.46,42.72 145.52,43.66 145.52,45.21 140.2,50.52 138.94,51.05 137.74,52.24 137.74,65.09 138.07,65.89 138.07,71.51 137.54,72.79 137.54,75.54 134.19,78.89 133.58,80.36 133.58,83.41 132.79,85.32 132.79,95.29 132.44,96.14 132.03,96.55 130.62,97.5 114.09,104.34 105.19,113.24 92.1,115.85 83.75,115.85 83.57,115.66 83.57,115.32 v1(83.8,115.09)
USB3_2_RX_N: length 108.2
  TOP w0.188: v1(123.81,49.07) 124.23,48.65 C99.1 ; J3.92 81.35,126.94 81.47,127.06 81.47,128.06 81.65,128.49 81.65,128.92 v1(81.43,129.13)
  ART04 w0.152: v1(84.35,113.49) 84.63,113.77 84.63,118.62 84.46,118.79 84.46,119.25 84.63,119.42 84.63,119.82 82.3,125.44 82.04,125.7 81.53,126.93 81.53,129.03 v1(81.43,129.13)
  BOTTOM w0.188: v1(84.35,113.49) 84.58,113.26 84.58,112.88 84.87,112.59 95.44,108.21 98.89,107.53 104.02,105.4 107.19,102.23 107.71,101.78 108.78,100.93 110.19,98.78 111.87,94.75 111.87,61.86 113.04,59.01 116.29,55.77 121.97,53.42 124.1,51.28 124.1,49.36 v1(123.81,49.07)
USB3_2_RX_N_HUB0: length 27.8
  TOP w0.188: C99.2 125.61,48.37 125.84,48.6 v1(126.21,48.6) ; U2002.47 138.16,39.22 137.77,38.84 137.77,36.8 v1(137.54,36.58)
  ART04 w0.152: v1(137.54,36.58) 137.8,36.83 137.8,39.12 137.82,39.19 138.3,40.34 138.3,41.23 137.74,42.58 137.74,46.25 136.74,47.25 134.98,47.98 133.24,47.98 131.14,48.85 129.67,48.85 129.41,48.59 129.13,48.59 128.87,48.85 128.6,48.85 128.34,48.59 128.07,48.59 127.81,48.85 127.53,48.85 127.27,48.59 127,48.59 126.74,48.85 126.46,48.85 v1(126.21,48.6)
USB3_2_RX_N_HUB1: length 5.5
  TOP w0.188: C2132.2 122.83,48.37 122.43,48.77 121.89,48.77 121.36,48.23 121.27,48.23 121.11,48.07 121.11,47.84 120.94,47.68 120.71,47.68 120.54,47.84 120.54,48.07 120.38,48.23 119.68,48.23 119.49,48.05 U2101.59
USB3_2_RX_P: length 108.1
  TOP w0.188: v1(124.7,49.07) 124.7,49.16 124.23,49.63 C2133.1 ; v1(82.32,129.13) 82.03,128.84 82.03,128.42 81.85,127.99 J3.94
  ART04 w0.152: v1(85.24,113.49) 85.01,113.72 85.01,119.89 82.62,125.66 82.37,125.91 81.92,127 81.92,128.73 v1(82.32,129.13)
  BOTTOM w0.188: v1(85.24,113.49) 84.96,113.22 84.96,113.04 85.09,112.91 95.55,108.58 99.01,107.89 104.24,105.73 107.45,102.51 107.95,102.07 109.07,101.19 110.53,98.96 112.25,94.82 112.25,61.93 112.81,60.58 113.37,59.23 116.5,56.09 122.18,53.74 124.49,51.43 124.49,49.28 v1(124.7,49.07)
USB3_2_RX_P_HUB0: length 27.8
  TOP w0.188: v1(126.21,49.48) 125.79,49.48 125.51,49.76 C98.2 ; U2002.48 138.56,39.14 138.54,39.12 138.54,39.07 138.15,38.68 138.15,36.85 v1(138.43,36.58)
  ART04 w0.152: v1(126.21,49.48) 126.46,49.23 131.21,49.23 133.31,48.36 135.06,48.36 136.96,47.57 138.13,46.41 138.13,42.65 138.68,41.31 138.68,40.27 138.18,39.04 138.18,36.83 v1(138.43,36.58)
USB3_2_RX_P_HUB1: length 5.5
  TOP w0.188: U2101.60 119.11,47.69 119.11,48.2 119.52,48.62 121.2,48.62 121.74,49.15 122.43,49.15 123.04,49.76 C2133.2
USB3_2_TX_N: length 92.6
  TOP w0.188: C101.1 121.4,50.99 v1(120.92,50.51) ; J3.93 81.6,117.08 81.66,117.02 81.66,115.95 80.16,114.45 80.16,113.16 80.57,112.75 80.74,112.75 v1(81.12,112.36)
  BOTTOM w0.188: v1(81.12,112.36) 81.38,112.63 81.41,112.63 81.69,112.66 83.48,111.92 84.05,111.35 95.52,106.6 98.04,106.1 101.57,104.64 104.2,102.89 108.44,98.64 108.8,98.19 110.11,92.31 110.11,63.31 110.23,62.23 110.51,61.01 111.57,58.75 111.81,58.18 111.87,58.12 112.21,57.4 115.03,54.58 118.15,53.29 119.81,51.63 119.81,51.19 120.26,50.74 120.69,50.74 v1(120.92,50.51)
USB3_2_TX_N_HUB0: length 40.2
  TOP w0.188: U2002.50 139.36,39.14 139.37,39.13 139.37,38.66 139.6,38.43 v1(139.6,35.89) ; C101.2 121.62,52.07 121.39,52.3 v1(121.39,52.83)
  ART04 w0.152: v1(121.39,52.83) 121.14,53.08 121.14,53.19 121.29,53.34 122.55,53.34 124.71,51.18 126.78,51.18 126.91,51.05 126.91,51.03 127.05,50.9 127.24,50.9 127.37,51.03 127.37,51.05 127.5,51.18 127.69,51.18 127.83,51.05 127.83,51.03 127.96,50.9 128.15,50.9 128.28,51.03 128.28,51.05 128.42,51.18 128.6,51.18 128.74,51.05 128.74,51.03 128.87,50.9 129.06,50.9 129.19,51.03 129.19,51.05 129.33,51.18 132.26,51.18 134.29,49.15 135.46,49.15 137.88,48.15 140.84,45.18 140.84,44.68 140.61,44.45 140.61,44.15 140.84,43.92 140.84,43.62 140.61,43.39 140.61,43.08 140.84,42.86 140.84,42.55 140.61,42.32 140.61,42.02 140.84,41.79 140.84,41.49 140.61,41.26 140.61,40.95 140.84,40.72 140.84,40.16 139.5,38.82 139.5,36.95 139.85,36.6 139.85,36.14 v1(139.6,35.89)
USB3_2_TX_N_HUB1: length 4.7
  TOP w0.188: U2101.62 118.29,48.03 119.3,49.05 120.2,49.05 120.43,49.28 121.09,49.28 121.37,49.56 121.61,50.15 C2130.2
USB3_2_TX_P: length 92.7
  TOP w0.188: C2131.1 120.51,50.99 v1(120.92,51.39) ; v1(81.12,113.25) 80.99,113.13 80.73,113.13 80.54,113.32 80.54,114.29 81.31,115.07 81.55,115.07 81.73,114.88 81.96,114.88 82.13,115.05 82.13,115.28 81.95,115.46 81.95,115.7 82.04,115.79 82.04,117.02 82.1,117.08 J3.95
  BOTTOM w0.188: v1(120.92,51.39) 120.64,51.12 120.42,51.12 120.19,51.35 120.19,51.79 118.37,53.61 115.25,54.91 112.53,57.62 112.19,58.34 112.13,58.4 111.92,58.91 110.87,61.13 110.61,62.3 110.49,63.33 110.49,92.35 109.16,98.36 108.73,98.89 104.44,103.18 101.75,104.98 98.15,106.46 95.63,106.97 84.26,111.67 83.69,112.24 81.74,113.05 81.36,113.01 81.36,113.01 v1(81.12,113.25)
USB3_2_TX_P_HUB0: length 40.2
  TOP w0.188: v1(120.5,52.83) 120.5,52.46 120.22,52.17 C100.2 ; U2002.51 139.76,39.14 139.75,39.13 139.75,38.81 139.98,38.59 139.98,36.37 140.46,35.89 v1(140.48,35.89)
  ART04 w0.152: v1(120.5,52.83) 120.76,53.08 120.76,53.35 121.13,53.72 122.71,53.72 124.87,51.56 132.42,51.56 134.45,49.53 135.53,49.53 138.09,48.47 141.22,45.34 141.22,40 139.88,38.66 139.88,37.11 140.23,36.76 140.23,36.14 v1(140.48,35.89)
USB3_2_TX_P_HUB1: length 4.7
  TOP w0.188: U2101.63 117.91,47.69 117.91,48.19 119.15,49.43 119.15,49.81 119.25,49.91 119.51,49.91 119.61,49.81 119.61,49.58 119.76,49.43 120.04,49.43 120.22,49.61 C2131.2
USB20_4G_DN: length 17.9
  TOP w0.188: T1.1 152.96,82.85 R709.1
  TOP w0.203: T1.1 152.91,83.21 153.12,83.42 154.2,83.42 v1(154.43,83.18)
  TOP w0.254: J701.36 156.15,94.74 v1(156.47,94.42)
  ART03 w0.178: v1(154.43,83.18) 154.69,83.44 155.6,83.44 156.38,84.22 157.38,86.63 157.38,91.15 157.56,91.33 157.63,91.33 157.81,91.5 157.81,91.86 157.63,92.04 157.56,92.04 157.38,92.22 157.38,93.45 156.47,94.36 v1(156.47,94.42)
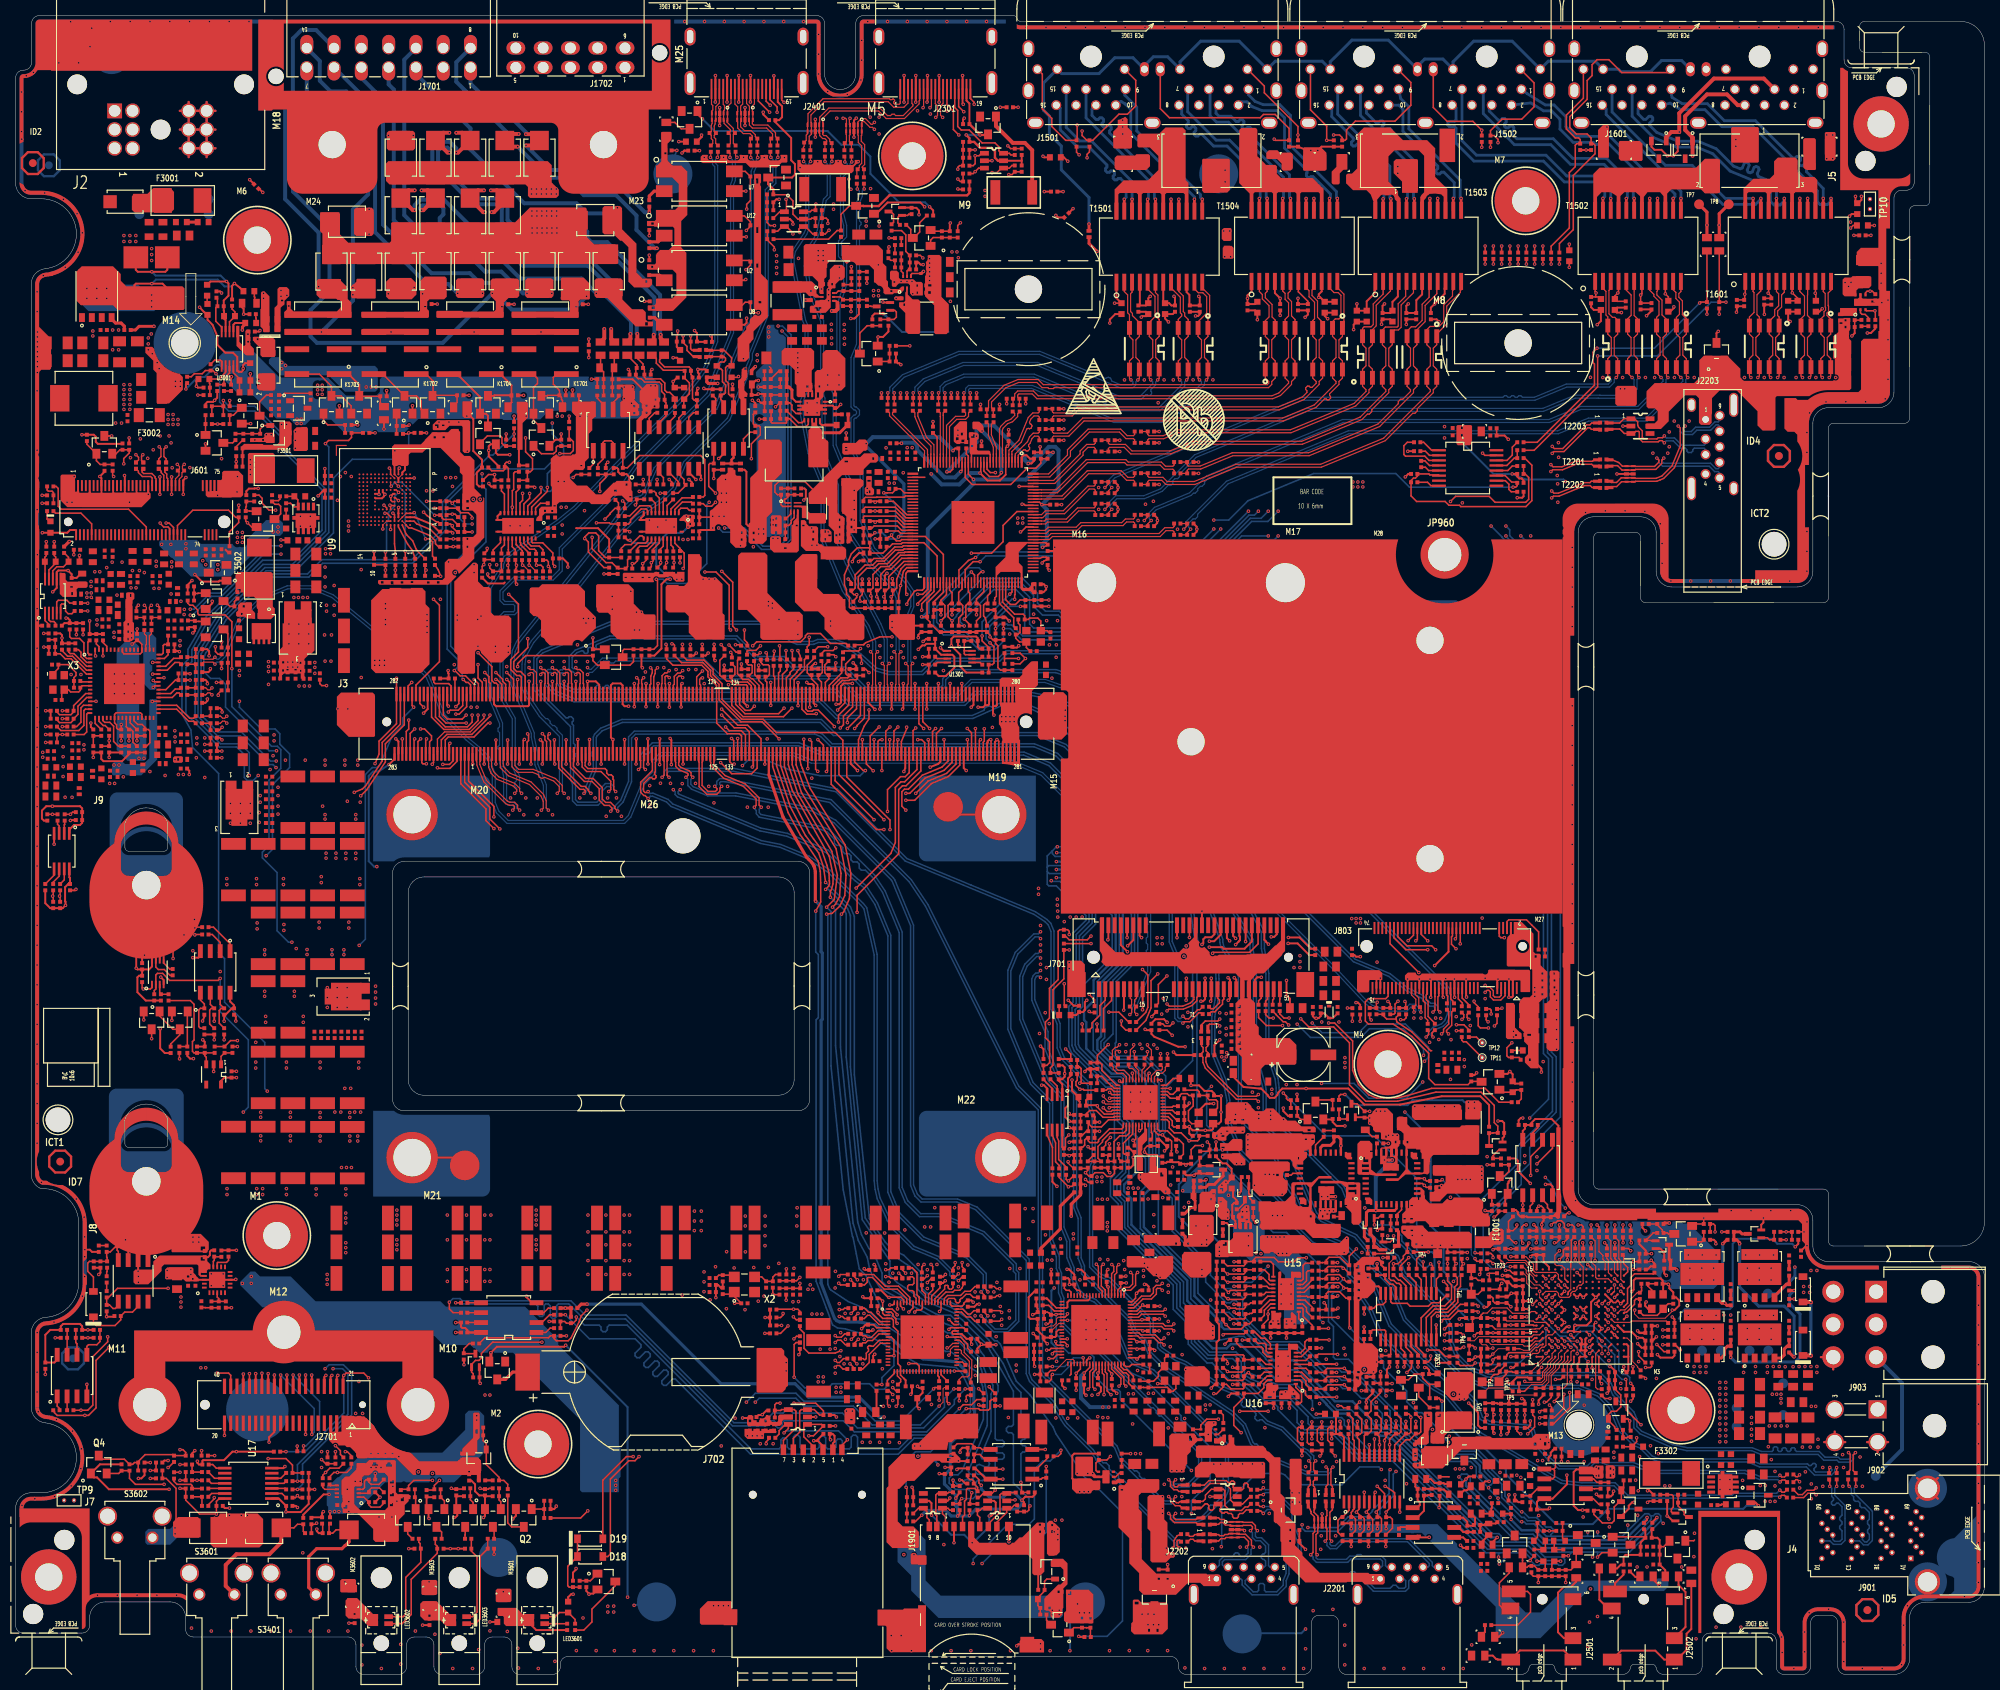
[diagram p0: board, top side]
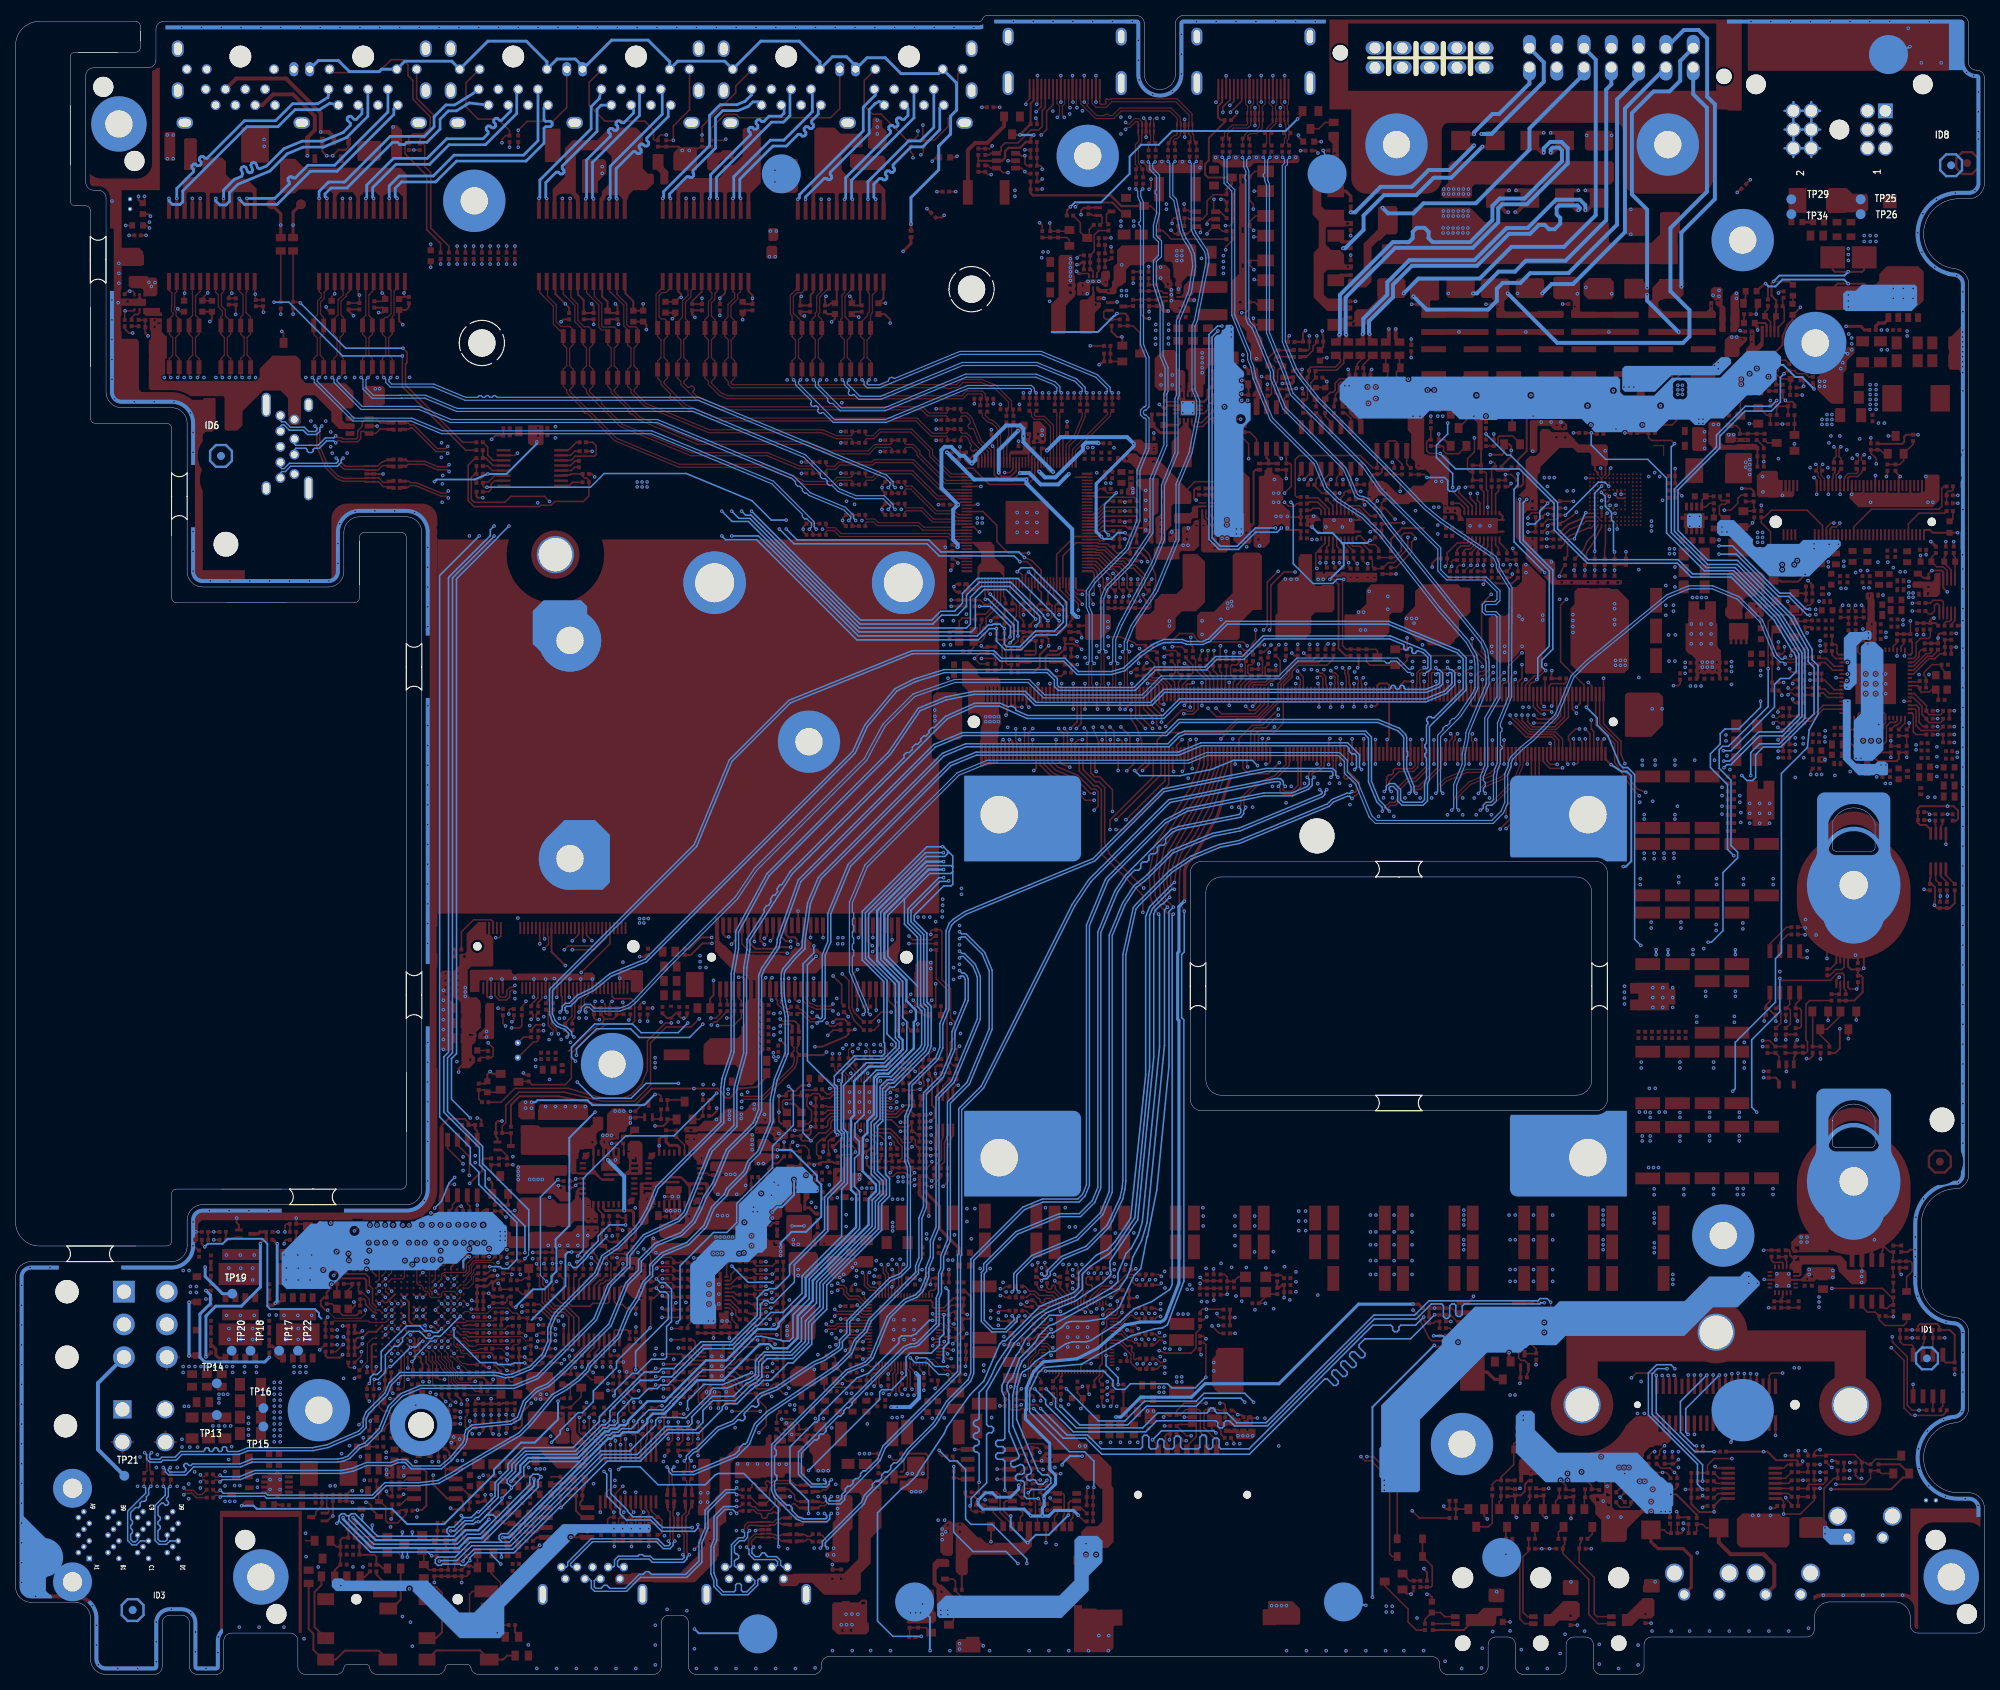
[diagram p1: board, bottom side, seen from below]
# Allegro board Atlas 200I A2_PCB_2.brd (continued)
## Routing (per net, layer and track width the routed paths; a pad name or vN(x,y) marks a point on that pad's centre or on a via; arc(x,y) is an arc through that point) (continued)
USB20_4G_DP: length 17.9
  TOP w0.188: T1.4 152.04,82.85 R708.1
  TOP w0.203: v1(154.43,84.07) 154.18,83.82 152.58,83.82 152.1,83.34 T1.4
  TOP w0.254: J701.38 156.95,94.73 157.03,94.65 157.03,94.19 156.87,94.03 156.87,94.02 v1(156.47,93.62)
  ART03 w0.178: v1(156.47,93.62) 156.63,93.62 156.97,93.28 156.97,86.71 156.03,84.45 155.43,83.84 154.66,83.84 v1(154.43,84.07)
USB20_4G_HUB0_DN: length 46.1
  TOP w0.188: v1(112.94,34.39) 113.16,34.62 R2130.1 ; v1(147.3,43.16) 147.07,42.93 146.79,42.93 146.16,43.56 144.33,43.56 144.09,43.8 142.96,43.8 U2002.66
  ART03 w0.152: v1(147.3,43.16) 147.04,42.9 145.93,42.9 144.44,43.52 143.09,43.52 140.73,41.16 137.87,39.98 136.11,39.98 134.76,38.63 134.76,38.02 133.33,36.59 132.04,36.59 131.87,36.75 131.5,36.75 131.34,36.59 130.97,36.59 130.8,36.75 130.44,36.75 130.27,36.59 129.9,36.59 129.74,36.75 129.37,36.75 129.21,36.59 128.84,36.59 128.67,36.75 128.3,36.75 128.14,36.59 127.77,36.59 127.61,36.75 127.24,36.75 127.07,36.59 126.07,36.59 125.62,36.14 116.35,36.14 114.07,33.86 112.92,33.86 112.77,34.01 112.77,34.22 v1(112.94,34.39)
USB20_4G_HUB0_DP: length 46.2
  TOP w0.188: v1(147.3,42.27) 147.02,42.54 146.63,42.54 146,43.18 144.17,43.18 143.93,43.42 U2002.65 ; v1(112.05,34.39) 111.82,34.62 R2128.1
  ART03 w0.152: v1(112.05,34.39) 112.38,34.06 112.38,33.85 112.76,33.48 114.22,33.48 116.51,35.76 125.78,35.76 126.23,36.21 133.49,36.21 135.14,37.86 135.14,38.47 136.27,39.6 137.95,39.6 140.94,40.84 143.25,43.14 144.36,43.14 145.85,42.52 147.04,42.52 v1(147.3,42.27)
USB20_4G_HUB1_DN: length 2
  TOP w0.188: R2129.1 113.51,37.54 113.51,37.87 113.09,38.3 U2101.21
USB20_4G_HUB1_DP: length 2
  TOP w0.188: R2127.1 111.82,37.73 112.69,38.59 U2101.20
USB20_4G_HUB_DN: length 92.5
  TOP w0.188: v1(112.49,36.79) 112.91,36.37 R2130.2 ; R709.2 152.96,81.23 T1.2 152.91,80.64 152.68,80.42 152.68,79.98 152.93,79.73 C715.1 152.65,79.15 152.65,78.59 152.91,77.99 156.72,74.17 159.16,74.17 v1(159.39,74.4)
  ART04 w0.152: v1(112.49,36.79) 112.76,36.52 113.21,36.52 114.08,35.66 116.21,35.05 117.02,34.23 118.17,33.76 119.96,33.4 126,33.4 127.72,34.11 129.44,34.11 129.61,34.29 130.07,34.29 130.25,34.11 130.71,34.11 130.88,34.29 131.34,34.29 131.52,34.11 131.97,34.11 132.1,34.24 132.66,34.24 132.79,34.11 133.24,34.11 133.4,34.26 133.9,34.26 134.06,34.11 134.75,34.11 135.05,33.81 136.73,33.81 137.47,33.08 137.47,32.54 137.62,32.38 140.46,32.38 144.14,36.07 144.14,36.53 145.26,39.25 145.26,42.16 145.77,43.39 145.77,45.9 145.95,46.33 145.95,48.65 145.42,49.94 145.42,51.53 145.44,51.6 149.14,60.53 149.65,61.03 151.08,63.18 152.05,64.14 155.08,65.96 155.72,66.59 156.83,69.28 157.76,71.53 158.01,71.78 158.32,72.52 158.32,72.92 158.65,73.71 159.33,74.4 v1(159.39,74.4)
USB20_4G_HUB_DP: length 92.5
  TOP w0.188: R2127.2 112.02,36.37 v1(112.49,35.9) ; v1(159.39,73.51) 159.11,73.79 156.57,73.79 152.58,77.77 152.27,78.52 152.27,79.17 C716.1 151.99,79.58 152.3,79.88 152.3,80.42 152.1,80.62 T1.3 152.04,81.23 R708.2
  ART04 w0.152: v1(159.39,73.51) 159.29,73.6 159.08,73.6 158.97,73.5 158.7,72.85 158.7,72.45 158.33,71.56 158.08,71.31 157.18,69.14 156.04,66.38 155.32,65.66 152.28,63.84 151.38,62.93 149.95,60.79 149.47,60.31 145.8,51.45 145.8,50.02 146.33,48.73 146.33,46.25 146.15,45.82 146.15,43.31 145.64,42.09 145.64,39.17 144.52,36.46 144.52,35.96 144.48,35.87 140.61,32 137.46,32 137.08,32.38 137.08,32.93 136.58,33.43 134.89,33.43 134.6,33.73 127.8,33.73 126.08,33.02 119.92,33.02 118.06,33.39 116.81,33.91 116.01,34.71 113.88,35.32 113.05,36.14 112.73,36.14 v1(112.49,35.9)
USB20_5G_HUB0_DN: length 55.3
  TOP w0.188: v1(105.64,45.92) 106.05,45.92 106.32,45.64 106.81,45.64 ; v1(147.07,50.16) 146.81,49.91 146.28,49.91 145.92,49.55 145.92,48.95 145.51,48.54 144.41,48.54 143.29,47.42 U2002.75
  ART03 w0.152: v1(105.64,45.92) 105.36,46.2 105.02,46.2 104.65,46.58 104.65,47.88 105.35,48.58 106.8,49.18 106.82,49.18 108.28,49.78 115.35,49.78 116.11,49.02 120.96,49.02 122.07,47.91 122.07,47.5 122.61,46.96 124.84,46.96 126.04,48.16 129.22,48.16 129.7,47.68 142.33,47.68 144.38,48.53 145.27,49.42 146.46,49.91 146.81,49.91 v1(147.07,50.16)
USB20_5G_HUB0_DP: length 55.2
  TOP w0.188: 106.81,46.98 106.32,46.98 106.14,46.8 v1(105.64,46.8) ; U2002.74 143.43,47.02 144.57,48.16 145.67,48.16 146.3,48.79 146.3,49.4 146.44,49.53 146.81,49.53 v1(147.07,49.28)
  ART03 w0.152: v1(147.07,49.28) 146.81,49.53 146.54,49.53 145.49,49.09 144.6,48.2 142.4,47.29 129.54,47.29 129.06,47.78 126.19,47.78 125,46.58 122.45,46.58 121.69,47.34 121.69,47.75 120.8,48.64 120.55,48.64 120.4,48.49 119.94,48.49 119.79,48.64 119.34,48.64 119.18,48.49 118.73,48.49 118.58,48.64 118.14,48.64 117.99,48.49 117.61,48.49 117.46,48.64 117.08,48.64 116.92,48.49 116.54,48.49 116.39,48.64 115.95,48.64 115.19,49.4 114.14,49.4 113.99,49.25 113.61,49.25 113.46,49.4 113.08,49.4 112.92,49.25 112.54,49.25 112.39,49.4 112.01,49.4 111.86,49.25 111.48,49.25 111.33,49.4 110.95,49.4 110.79,49.25 110.41,49.25 110.26,49.4 109.88,49.4 109.73,49.25 109.35,49.25 109.19,49.4 108.36,49.4 107.11,48.89 107.02,48.66 106.77,48.56 106.52,48.66 105.57,48.26 105.03,47.72 105.03,46.73 105.18,46.58 105.42,46.58 v1(105.64,46.8)
USB20_5G_HUB1_DN: length 4.1
  TOP w0.188: R2125.1 108.84,45.64 109.27,46.08 109.55,46.08 110.75,44.88 111.17,44.88 111.18,44.87 U2101.6
USB20_5G_HUB1_DP: length 4.2
  TOP w0.188: R2123.1 108.86,46.98 109.39,46.46 109.71,46.46 110.9,45.26 111.17,45.26 111.18,45.27 U2101.5
USB20_5G_HUB_DN: length 151
  TOP w0.188: R2126.2 107.62,45.89 v1(108.04,46.31) ; v1(188.47,88.39) 188.72,88.14 189.1,88.14 189.51,87.73 189.51,87.08 189.7,86.89 190.32,86.89 190.53,87.1 J803.9
  ART04 w0.152: v1(188.47,88.39) 188.16,88.08 187.93,88.08 187.58,87.73 187.58,82.07 184.49,78.99 184.22,78.99 183.89,78.66 183.89,78.39 183.56,78.05 183.29,78.06 182.96,77.73 182.96,77.45 182.63,77.12 182.35,77.12 182.02,76.79 182.03,76.52 180.86,75.35 176.04,73.35 173.77,73.35 169.63,71.64 169.56,71.61 161.49,63.54 160,62.92 159.09,62.01 156.14,60.79 154.9,60.05 154.28,59.3 153.34,56.67 153.34,52.06 153.04,51.33 151.94,48.69 151.94,48.54 151.94,37.99 145.42,31.47 142.23,28.85 138.98,28.85 138.09,27.96 130.51,27.96 129.95,28.52 122.4,28.52 121.59,29.34 121.43,29.37 121.35,29.39 117.85,29.39 115.96,27.49 107.76,27.49 105.26,28.53 101.85,31.94 101.85,38.1 102.38,41.24 102.63,41.89 103.2,42.46 103.47,42.46 103.72,42.21 103.93,42.21 104.19,42.46 104.19,42.68 103.94,42.93 103.94,43.2 105.57,44.83 106.93,44.83 107.77,45.67 107.77,46.04 v1(108.04,46.31)
USB20_5G_HUB_DP: length 151
  TOP w0.188: J803.7 191.03,87.06 190.47,86.51 189.54,86.51 189.13,86.92 189.13,87.57 188.94,87.76 188.72,87.76 v1(188.47,87.5) ; v1(107.15,46.31) 107.62,46.78 R2123.2
  ART04 w0.152: v1(188.47,87.5) 188.27,87.7 188.09,87.7 187.96,87.58 187.96,81.91 181.07,75.03 176.11,72.97 173.85,72.97 169.77,71.29 161.71,63.22 160.21,62.6 159.3,61.69 156.31,60.45 155.15,59.76 154.62,59.11 153.72,56.6 153.72,51.99 153.29,50.94 153.08,50.45 153.24,50.08 153.09,49.73 152.72,49.58 152.32,48.61 152.32,48.61 152.32,37.83 145.68,31.19 142.37,28.47 139.14,28.47 138.25,27.58 130.35,27.58 129.79,28.14 122.24,28.14 121.4,28.99 121.31,29.01 118.01,29.01 116.11,27.11 107.69,27.11 105.04,28.21 101.47,31.78 101.47,38.13 102.01,41.34 102.3,42.1 105.41,45.21 106.77,45.21 107.39,45.83 107.39,45.95 107.36,46.02 107.3,46.16 v1(107.15,46.31)
USB20_D_HUB0_DN: length 45.8
  TOP w0.188: U2002.8 139.36,49.16 138.86,49.66 138.86,52.37 v1(138.61,52.62) ; R2138.1 105.79,49.96 v1(105.57,50.18)
  ART03 w0.152: v1(105.57,50.18) 105.2,50.55 104.74,50.55 104.24,51.05 104.24,52.18 105.68,53.61 105.75,53.64 112.25,56.34 123.51,56.34 128.1,54.44 129.28,54.2 135.39,54.2 136.72,53.65 138.3,52.07 138.64,52.07 138.79,52.22 138.79,52.44 v1(138.61,52.62)
USB20_D_HUB0_DP: length 45.8
  TOP w0.188: v1(139.5,52.62) 139.24,52.37 139.24,49.81 139.74,49.32 139.74,49.32 139.76,49.3 U2002.7 ; R2136.1 105.79,51.3 v1(105.57,51.07)
  ART03 w0.152: v1(105.57,51.07) 105.42,50.93 104.9,50.93 104.62,51.21 104.62,52.02 105.89,53.29 112.33,55.96 123.44,55.96 127.99,54.07 129.24,53.82 134.12,53.82 134.26,53.69 134.26,53.5 134.39,53.36 134.58,53.36 134.71,53.5 134.71,53.69 134.85,53.82 135.31,53.82 136.5,53.33 138.15,51.69 138.8,51.69 139.17,52.06 139.17,52.29 v1(139.5,52.62)
USB20_D_HUB1_DN: length 8.3
  TOP w0.188: R2137.1 108.87,49.96 109.22,50.31 109.22,50.79 109.35,50.92 109.89,50.92 111.38,49.43 113.08,49.43 114.29,48.22 U2101.72
USB20_D_HUB1_DP: length 8.2
  TOP w0.188: U2101.71 114.69,48.35 113.23,49.81 111.54,49.81 110.05,51.3 R2135.1
USB20_D_HUB_CONN_DN: length 16.2
  TOP w0.188: R2219.2 204.43,160.59 T2203.2 205.72,160.54 206.28,161.09 U2206.1 207.62,161.09 208.03,160.68 208.03,160.27 208.14,160.01 208.62,159.53 208.62,158.7 208.82,158.5 210.51,158.5 210.66,158.65 211.22,158.65 v1(211.45,158.88)
  BOTTOM w0.188: v1(211.45,158.88) 211.71,158.62 212.76,158.62 213.7,157.68 216.55,157.68 216.74,157.87 J2203.2
USB20_D_HUB_CONN_DP: length 16.2
  TOP w0.188: v1(211.45,157.99) 211.18,158.27 210.82,158.27 210.67,158.11 208.66,158.11 208.24,158.54 208.24,159.37 208.15,159.46 207.78,159.46 207.51,159.19 U2206.3 206.32,159.19 205.74,159.77 204.53,159.77 T2203.3 204.43,159.67 R2218.2
  BOTTOM w0.188: J2203.3 216.74,157.11 216.55,157.3 215.28,157.3 215.09,157.11 215.09,156.93 214.91,156.74 214.53,156.74 214.34,156.93 214.34,157.11 214.15,157.3 213.54,157.3 212.6,158.24 211.7,158.24 v1(211.45,157.99)
USB20_D_HUB_DN: length 165.8
  TOP w0.188: R2137.2 107.54,50.16 v1(107.08,50.63) ; R2219.1 202.81,160.59 T2203.1 202.14,160.54 201.9,160.3 201.47,160.3 198.42,157.25 197.35,157.25 v1(197.07,157.53)
  ART04 w0.152: v1(107.08,50.63) 107.36,50.91 107.36,51.77 116.99,61.39 134.27,61.39 135.37,61.85 144.24,61.85 144.77,62.38 145.92,65.14 146.2,66.9 146.2,69.57 148.07,71.44 151.76,72.97 154.99,76.2 155.75,77.22 157.23,78.62 158.88,82.59 158.88,84.12 159.05,84.53 162.31,87.79 162.84,88.01 165.41,90.58 165.41,94 169.33,103.47 180.93,115.07 182.78,119.54 188.37,147.64 190.07,151.75 191.62,153.29 192.4,153.62 196.06,157.28 196.82,157.28 v1(197.07,157.53)
USB20_D_HUB_DP: length 165.9
  TOP w0.188: R2135.2 107.54,51.04 v1(107.96,50.63) ; v1(197.07,156.64) 197.3,156.87 198.58,156.87 201.63,159.92 201.9,159.92 202.09,159.72 T2203.4 202.81,159.67 R2218.1
  ART04 w0.152: v1(197.07,156.64) 196.82,156.9 196.22,156.9 192.61,153.29 191.83,152.97 190.4,151.53 188.74,147.53 183.15,119.43 181.25,114.86 169.65,103.26 165.79,93.93 165.79,90.42 163.05,87.68 162.52,87.47 159.37,84.31 159.26,84.04 159.26,82.52 157.55,78.4 156.04,76.96 155.28,75.95 151.97,72.64 148.29,71.12 146.58,69.41 146.58,66.87 146.28,65.04 145.09,62.16 144.4,61.47 135.45,61.47 134.35,61.01 117.15,61.01 112.85,56.71 112.85,56.41 112.53,56.09 112.23,56.09 111.92,55.78 111.92,55.48 111.6,55.16 111.3,55.16 110.98,54.85 110.98,54.54 110.67,54.23 110.36,54.23 110.05,53.91 110.05,53.61 109.73,53.29 109.43,53.29 107.74,51.61 107.74,50.84 v1(107.96,50.63)
USB30_5G_HUB0_RX_N: length 57.1
  TOP w0.188: R2122.1 106.11,39.18 105.66,39.62 105.34,39.62 v1(105.12,39.4) ; U2002.72 142.96,46.2 143.87,46.2 144.26,46.59 147.19,46.59 v1(147.45,46.85)
  ART03 w0.152: v1(147.45,46.85) 147.19,46.59 146.49,46.59 144.78,44.88 142.42,44.88 140.06,42.52 138.67,42.52 135.35,41.15 133.4,39.2 133.4,38.3 133.15,38.05 129.82,38.05 129.59,38.28 129.21,38.28 128.98,38.05 128.24,38.05 128.07,38.23 127.71,38.23 127.53,38.05 127.18,38.05 127,38.23 126.64,38.23 126.47,38.05 126.11,38.05 125.93,38.23 125.58,38.23 125.4,38.05 124.51,38.05 123.92,37.46 116.77,37.46 116.5,37.58 116.41,37.78 116.41,37.78 116.06,37.92 115.87,37.84 115.86,37.84 115.51,37.99 115.43,38.18 115.43,38.19 115.08,38.33 114.88,38.25 114.88,38.25 114.32,38.48 110.08,38.48 109.18,38.11 108.46,38.11 108.29,38.28 107.93,38.28 107.76,38.11 107.39,38.11 107.22,38.28 106.86,38.28 106.69,38.11 106.33,38.11 106.16,38.28 105.8,38.28 105.63,38.11 104.89,38.11 104.52,38.48 104.52,39.48 104.67,39.63 104.89,39.63 v1(105.12,39.4)
USB30_5G_HUB0_RX_P: length 57.2
  TOP w0.188: v1(105.12,40.29) 105.4,40.01 105.67,40.01 106.17,40.51 R2108.1 ; v1(147.45,45.96) 147.19,46.21 144.41,46.21 144.02,45.82 U2002.71
  ART03 w0.152: v1(147.45,45.96) 147.19,46.21 146.64,46.21 144.93,44.5 142.58,44.5 140.21,42.14 138.74,42.14 135.57,40.82 133.78,39.04 133.78,38.14 133.31,37.67 124.66,37.67 124.08,37.08 116.69,37.08 114.24,38.1 110.16,38.1 109.26,37.73 104.74,37.73 104.14,38.32 104.14,39.64 104.52,40.01 104.84,40.01 v1(105.12,40.29)
USB30_5G_HUB0_TX_N: length 59.2
  TOP w0.188: v1(105.12,42.57) 105.43,42.88 105.84,42.88 106.43,42.29 C2106.1 ; v1(148.54,44.96) 148.29,44.7 147.45,44.7 147.14,45.01 143.65,45.01 143.64,45.02 U2002.69
  ART03 w0.152: v1(105.12,42.57) 105.31,42.76 105.47,42.76 106.54,41.69 106.93,41.53 113.33,41.53 116.7,40.13 122.79,40.13 128.86,41.2 131.86,43.3 133.35,43.56 134.25,43.56 134.25,43.57 135.27,43.75 136.08,44.31 136.77,45.64 137.1,45.97 140.41,45.97 140.56,45.82 140.56,45.62 140.71,45.47 141.01,45.47 141.17,45.62 141.17,45.82 141.32,45.97 141.62,45.97 141.77,45.82 141.77,45.62 141.93,45.47 142.23,45.47 142.38,45.62 142.38,45.82 142.53,45.97 144.29,45.97 145.73,47.41 146.56,47.75 147.54,47.75 148.99,46.3 149.21,45.78 149.21,44.98 149.06,44.83 148.67,44.83 v1(148.54,44.96)
USB30_5G_HUB0_TX_P: length 59.2
  TOP w0.188: C2103.1 106.32,43.69 105.9,43.26 105.32,43.26 v1(105.12,43.46) ; v1(148.54,44.07) 148.29,44.32 147.29,44.32 146.98,44.63 143.65,44.63 143.64,44.62 U2002.68
  ART03 w0.152: v1(148.54,44.07) 148.92,44.45 149.22,44.45 149.59,44.82 149.59,45.85 149.32,46.52 147.7,48.13 146.48,48.13 145.51,47.73 144.13,46.35 136.95,46.35 136.46,45.86 135.79,44.57 135.12,44.11 134.19,43.94 133.32,43.94 131.71,43.66 128.71,41.56 122.76,40.51 116.78,40.51 113.4,41.91 107,41.91 106.75,42.01 105.62,43.14 105.44,43.14 v1(105.12,43.46)
USB30_5G_HUB1_RX_N: length 5.6
  TOP w0.188: R2121.1 108.65,39.18 109.47,40 109.47,41.04 110.91,42.48 111.17,42.48 111.18,42.47 U2101.12
USB30_5G_HUB1_RX_P: length 5.6
  TOP w0.188: U2101.11 111.18,42.87 111.17,42.86 110.76,42.86 109.99,42.1 109.73,42.1 109.65,42.18 109.46,42.18 109.27,41.99 109.27,41.86 109.39,41.74 109.39,41.49 109.09,41.2 109.09,40.51 108.97,40.39 108.84,40.39 108.71,40.51 R2107.1
USB30_5G_HUB1_TX_N: length 4.1
  TOP w0.188: C2105.1 108.66,42.54 109.02,42.54 109.32,42.83 109.89,42.83 110.74,43.68 111.17,43.68 111.18,43.67 U2101.9
USB30_5G_HUB1_TX_P: length 4
  TOP w0.188: U2101.8 111.18,44.07 111.17,44.06 110.58,44.06 109.73,43.21 109.25,43.21 109.02,43.44 108.66,43.44 C2104.1
USB30_5G_HUB_RX_N: length 119.7
  TOP w0.188: v1(107.01,39.84) 107.48,39.37 R2122.2 ; R231.1 186.15,84.68 186.15,84.26 v1(186.38,84.03)
  ART04 w0.152: v1(186.38,84.03) 186.13,83.78 185.99,83.45 185.99,81.98 184.19,80.18 183.07,79.71 179.31,75.96 175.79,74.5 173.75,74.5 166.91,71.67 158.61,63.37 155.27,61.98 154.74,61.67 153.12,59.96 152.59,58.98 152.17,56.82 151.69,55.67 150.9,51.72 150.9,41.6 149.34,38.91 148.35,35.59 146.66,33.87 141.81,29.9 127.51,29.9 116.43,30.99 109.45,32.37 107.44,34.39 107.44,39.41 v1(107.01,39.84)
USB30_5G_HUB_RX_P: length 119.9
  TOP w0.188: R2107.2 107.48,40.26 v1(107.9,39.84) ; v1(185.5,84.03) 185.73,84.27 185.73,84.64 R230.1
  ART04 w0.152: v1(185.5,84.03) 185.68,83.85 185.7,83.74 185.61,83.53 185.61,82.14 183.98,80.5 182.85,80.04 179.1,76.28 175.71,74.88 173.67,74.88 166.69,71.99 158.4,63.69 155.09,62.32 154.5,61.97 152.81,60.19 152.23,59.11 151.8,56.93 151.32,55.78 150.52,51.75 150.52,41.71 149.76,40.38 148.99,39.06 148.01,35.79 146.4,34.16 141.67,30.28 127.53,30.28 116.49,31.36 109.64,32.72 108.65,33.72 108.65,33.95 108.44,34.16 108.21,34.16 107.82,34.54 107.82,34.77 107.98,34.92 108.03,34.92 108.18,35.07 108.18,35.38 108.03,35.53 107.98,35.53 107.82,35.68 107.82,35.99 107.98,36.14 108.03,36.14 108.18,36.29 108.18,36.59 108.03,36.75 107.98,36.75 107.82,36.9 107.82,37.2 107.98,37.35 108.03,37.35 108.18,37.5 108.18,37.81 108.03,37.96 107.98,37.96 107.82,38.11 107.82,38.42 107.98,38.57 108.03,38.57 108.18,38.72 108.18,39.02 108.03,39.18 107.98,39.18 107.82,39.33 107.82,39.77 v1(107.9,39.84)
USB30_5G_HUB_TX_N: length 120.3
  TOP w0.188: R233.1 184.18,84.98 184.18,83.28 183.52,82.61 183.52,82.42 v1(183.77,82.17) ; v1(108.07,42.99) 107.59,42.51 C2105.2
  ART04 w0.152: v1(108.07,42.99) 107.82,42.74 107.82,42.52 108.81,41.53 109.43,40.18 110.36,35.4 110.67,34.25 111.35,33.83 111.72,33.83 116.7,32.64 118.68,32.41 120.41,32.08 128.3,31.36 141.01,31.36 144.72,35.07 146.1,35.64 146.95,36.49 149.2,43.99 149.2,54.89 149.57,57.45 151.43,60.92 153.94,63.56 155.49,64.49 157.78,65.12 165.11,72.45 166.96,76.92 170.97,80.93 173.61,82.02 179.02,83.06 183.21,83.06 183.52,82.75 183.52,82.42 v1(183.77,82.17)
USB30_5G_HUB_TX_P: length 120.4
  TOP w0.188: R232.1 183.8,85.04 183.8,83.43 183.13,82.77 183.13,82.42 v1(182.88,82.17) ; v1(107.19,42.99) 107.59,43.4 C2104.2
  ART04 w0.152: v1(182.88,82.17) 183.14,82.42 183.14,82.59 183.05,82.68 179.05,82.68 173.72,81.65 171.19,80.61 167.29,76.7 165.44,72.24 157.98,64.78 155.65,64.13 154.18,63.26 151.74,60.7 149.94,57.32 149.58,54.86 149.58,43.93 147.29,36.28 146.32,35.32 144.93,34.74 141.17,30.98 128.28,30.98 120.36,31.71 118.62,32.03 116.63,32.26 111.67,33.45 111.24,33.45 110.34,34 109.99,35.31 109.98,35.32 109.9,35.76 109.68,35.9 109.63,36.17 109.78,36.39 109.06,40.06 108.5,41.31 107.55,42.25 107.44,42.36 107.44,42.74 v1(107.19,42.99)
USB30_D_HUB0_RX_N: length 41.3
  TOP w0.188: v1(140.59,52.58) 140.84,52.32 140.84,51.69 140.57,51.41 140.57,49.31 140.56,49.3 U2002.5 ; v1(111.6,51.03) 112.02,51.03 112.24,50.81 R2134.1
  ART03 w0.152: v1(111.6,51.03) 111.31,51.32 111.09,51.32 110.67,51.74 110.67,53.18 112,54.51 112.54,54.91 122.97,54.91 127.38,53.09 128.72,53.09 131.91,51.76 132.23,51.45 137.08,51.45 138.34,50.93 140.05,50.93 140.84,51.72 140.84,52.32 v1(140.59,52.58)
USB30_D_HUB0_RX_P: length 41.3
  TOP w0.188: R2132.1 112.25,52.15 112.02,51.92 v1(111.6,51.92) ; U2002.4 140.96,49.3 140.95,49.31 140.95,51.25 141.22,51.53 141.22,52.32 v1(141.48,52.58)
  ART03 w0.152: v1(141.48,52.58) 141.22,52.32 141.22,51.56 140.21,50.55 138.26,50.55 137,51.07 133.56,51.07 133.41,50.91 133.41,50.88 133.25,50.72 132.95,50.72 132.8,50.88 132.8,50.91 132.65,51.07 132.07,51.07 131.69,51.44 128.64,52.7 127.31,52.7 122.9,54.53 115.07,54.53 114.92,54.38 114.92,54.36 114.77,54.2 114.47,54.2 114.31,54.36 114.31,54.38 114.16,54.53 113.86,54.53 113.71,54.38 113.71,54.36 113.56,54.2 113.25,54.2 113.1,54.36 113.1,54.38 112.95,54.53 112.67,54.53 112.25,54.22 111.05,53.02 111.05,52.06 111.19,51.92 v1(111.6,51.92)
USB30_D_HUB0_TX_N: length 35.6
  TOP w0.188: v1(116.51,52.59) 116.23,52.31 C2110.1 ; v1(143.01,51.56) 143.26,51.31 143.26,50.07 142.84,49.66 142.19,49.66 141.76,49.23 U2002.2
  ART03 w0.152: v1(143.01,51.56) 143.26,51.31 143.26,50.22 142.51,49.46 140.85,48.99 134.82,48.99 134.66,49.15 134.21,49.15 134.06,48.99 133.32,48.99 131.6,49.51 127.05,51.56 121.83,53.72 117.39,53.72 116.78,53.11 116.78,52.74 116.63,52.59 v1(116.51,52.59)
USB30_D_HUB0_TX_P: length 35.6
  TOP w0.188: C2108.1 117.63,52.33 117.4,52.56 v1(117.4,52.59) ; v1(143.89,51.56) 143.64,51.31 143.64,49.91 143,49.28 142.35,49.28 142.16,49.09 U2002.1
  ART03 w0.152: v1(143.89,51.56) 143.64,51.31 143.64,50.06 142.71,49.12 140.9,48.61 133.27,48.61 131.47,49.15 126.9,51.21 124.99,52 124.64,51.85 124.33,51.98 124.18,52.33 123.03,52.81 121.76,53.34 117.55,53.34 117.16,52.96 117.16,52.74 117.31,52.59 v1(117.4,52.59)
USB30_D_HUB1_RX_N: length 5.3
  TOP w0.188: R2133.1 114.74,51.01 115.03,51.01 115.21,50.82 115.21,50.17 115.03,49.98 114.59,49.98 114.4,49.8 114.4,49.42 114.59,49.23 115.03,49.23 115.21,49.05 115.21,48.54 115.49,48.27 U2101.69
USB30_D_HUB1_RX_P: length 5.3
  TOP w0.188: U2101.68 115.89,48.38 115.87,48.4 115.87,48.42 115.6,48.7 115.6,51.57 115.01,52.15 R2131.1
USB30_D_HUB1_TX_N: length 2.5
  TOP w0.188: C2109.1 116.23,49.23 116.7,48.77 116.7,48.39 116.69,48.38 U2101.66
USB30_D_HUB1_TX_P: length 2.5
  TOP w0.188: U2101.65 117.09,48.38 117.08,48.39 117.08,48.77 117.63,49.32 C2107.1
USB30_D_HUB_CONN_RX_N: length 17.5
  TOP w0.188: v1(210.49,156.03) 210.74,155.78 210.74,155.51 210.2,154.96 207.74,154.96 207.71,155 D2201.5 D2201.6 206.06,155 205.59,155.47 204.76,155.81 T2201.2 204.43,155.86 R2210.2
  BOTTOM w0.188: J2203.5 218.54,154.11 218.35,154.3 217.91,154.3 217.22,154.99 211.23,154.99 210.74,155.48 210.74,155.78 v1(210.49,156.03)
USB30_D_HUB_CONN_RX_P: length 17.5
  TOP w0.188: R2209.2 204.43,154.95 T2201.3 204.66,155 204.72,155.07 205.46,155.07 206.02,154.5 D2201.7 D2201.4 207.67,154.5 207.75,154.58 210.35,154.58 211.13,155.36 211.13,155.78 v1(211.38,156.03)
  BOTTOM w0.188: J2203.6 218.54,154.87 218.35,154.68 218.06,154.68 217.37,155.37 211.39,155.37 211.13,155.64 211.13,155.78 v1(211.38,156.03)
USB30_D_HUB_CONN_TX_N: length 22
  TOP w0.188: R2211.2 204.08,153.07 T2202.2 204.65,152.91 205.33,152.91 205.92,153.5 D2201.9 D2201.2 207.67,153.5 207.73,153.44 210.41,153.44 211.15,153.75 212.42,155.02 213.49,157.59 213.49,159.89 v1(213.23,160.15)
  BOTTOM w0.188: J2203.8 218.54,160.11 218.35,160.3 218.09,160.3 217.4,159.61 215.62,159.61 215.07,159.06 213.9,159.06 213.49,159.47 213.49,159.89 v1(213.23,160.15)
USB30_D_HUB_CONN_TX_P: length 22
  TOP w0.188: v1(214.12,160.15) 213.87,159.89 213.87,157.51 212.75,154.8 211.37,153.43 210.93,153.24 210.49,153.06 207.77,153.06 207.71,153 D2201.1 D2201.10 205.96,153 205.33,152.37 204.6,152.37 T2202.3 204.08,152.26 R2212.2
  BOTTOM w0.188: J2203.9 218.54,160.87 218.35,160.68 217.93,160.68 217.24,159.99 215.46,159.99 214.91,159.44 214.06,159.44 213.87,159.63 213.87,159.89 v1(214.12,160.15)
USB30_D_HUB_RX_N: length 154.6
  TOP w0.188: v1(113.26,51.47) 113.73,51.01 R2134.2 ; R2210.1 203.16,155.81 T2201.1 202.42,155.81 202.24,155.63 200.03,155.63 198.31,154.91 197.18,154.91 v1(196.9,155.19)
  ART04 w0.152: v1(196.9,155.19) 196.65,154.94 196.06,154.94 194.5,153.37 193.57,151.13 190.38,147.94 189.8,146.56 184.53,120.04 181.9,113.69 170.57,102.36 167.72,95.47 167.72,90.6 166.44,88.75 163.03,85.33 160.84,82.84 159.82,80.02 158.53,77.88 156.78,76.21 155,73.85 151.55,70.4 150.9,69.91 148.98,68.85 148.33,68.19 147.58,66.39 146.99,63.05 145.85,60.84 145.57,60.56 144.38,60.07 137.1,60.07 132.63,59.18 130.92,59.18 120.65,57.19 118.42,56.15 113.96,52.73 113.54,52.23 113.54,51.75 v1(113.26,51.47)
USB30_D_HUB_RX_P: length 154.5
  TOP w0.188: R2131.2 113.73,51.89 v1(114.14,51.47) ; v1(196.9,154.31) 197.13,154.53 198.39,154.53 200.11,155.24 202.13,155.24 202.38,155 T2201.4 203.16,155 R2209.1
  ART04 w0.152: v1(196.9,154.31) 196.65,154.56 196.22,154.56 194.82,153.16 193.89,150.91 190.7,147.72 190.17,146.44 184.9,119.93 182.22,113.48 170.89,102.15 168.1,95.4 168.1,90.48 166.74,88.5 163.31,85.07 161.18,82.65 160.17,79.85 158.83,77.64 157.06,75.95 155.29,73.6 151.8,70.11 151.11,69.59 149.22,68.54 148.65,67.98 147.95,66.28 147.36,62.93 146.16,60.61 145.79,60.24 144.46,59.69 137.14,59.69 132.67,58.8 130.96,58.8 128.26,58.28 128.14,58.09 127.49,57.96 127.3,58.09 126.65,57.96 126.53,57.78 125.88,57.65 125.69,57.78 120.76,56.82 118.62,55.82 117.75,55.16 117.72,54.87 117.29,54.55 117.01,54.59 116.58,54.26 116.55,53.98 116.12,53.65 115.84,53.69 114.22,52.45 113.92,52.09 113.92,51.7 v1(114.14,51.47)
USB30_D_HUB_TX_N: length 150.8
  TOP w0.188: R2211.1 203.16,153.07 T2202.1 202.09,153.07 201.9,152.88 201.12,152.88 197.87,151.54 197.28,151.54 v1(197,151.82) ; v1(116.93,51.16) 116.52,50.75 C2109.2
  ART04 w0.152: v1(116.93,51.16) 117.18,50.9 117.45,50.9 118.59,52.04 118.59,53.09 120.45,54.95 121.32,55.31 137.87,55.31 140.86,56.02 145.54,58.37 146.28,58.37 146.92,59.01 148.1,61.83 148.42,62.15 148.74,62.91 148.9,63.72 148.9,65.16 148.96,65.77 149.03,66.17 149.09,66.3 151.03,68.24 152.42,69.17 152.96,69.39 153.54,69.97 153.72,70.4 155.98,72.66 157.98,75.34 159.61,76.68 162.04,79.08 169.39,89.76 169.39,95.68 171.78,101.46 183.1,112.77 187.17,122.59 191.81,145.94 192.67,148.02 196.21,151.56 196.75,151.56 v1(197,151.82)
USB30_D_HUB_TX_P: length 150.8
  TOP w0.188: C2107.2 117.41,50.75 v1(116.93,50.27) ; v1(197,150.93) 197.23,151.15 197.95,151.15 201.2,152.5 201.96,152.5 202.2,152.26 T2202.4 203.16,152.26 R2212.1
  ART04 w0.152: v1(116.93,50.27) 117.18,50.52 117.61,50.52 118.97,51.89 118.97,52.93 120.66,54.62 121.4,54.93 137.91,54.93 140.99,55.66 145.63,57.99 146.43,57.99 147.24,58.8 148.42,61.61 148.74,61.93 149.1,62.8 149.28,63.68 149.28,65.14 149.33,65.72 149.4,66.06 149.41,66.09 151.27,67.94 152.6,68.83 153.18,69.07 153.86,69.76 154.04,70.19 156.27,72.41 158.26,75.07 159.87,76.39 162.33,78.83 169.77,89.64 169.77,95.61 170.94,98.42 172.11,101.24 183.42,112.55 187.53,122.48 192.18,145.83 192.99,147.81 196.37,151.18 196.75,151.18 v1(197,150.93)
USB30_PWR0_EN1: length 411.7
  TOP w0.203: R88.2 60.19,43.19 68.33,43.19 68.58,43.43 R238.2 69.06,43.08 69.34,42.8 70.87,42.8 71.25,43.18 72.26,45.21 72.54,45.99 v1(73.28,46.74) ; R2217.2 238.13,177.44 v1(237.85,177.44) 237.45,177.44 237.25,177.24 U2203.4 ; U2002.26 v1(134.9,45.42)
  ART03 w0.178: v1(204.41,18.92) 203.84,19.49 203.84,20.45 204.85,21.46 213.11,21.46 220.13,28.49 220.13,39.36 221.54,40.77 225.86,40.77 228.56,43.47 228.56,51.19 227.61,52.15 227.61,56.9 226.79,57.72 217.71,57.72 217.43,57.44 211.16,57.44 209.11,59.5 201.38,59.5 199.5,60.28 198.88,60.89 198.88,125 198.16,125.72 198.16,149 200.55,151.38 207.32,151.38 207.98,152.04 207.98,157.87 215.18,165.07 232.79,165.07 237.96,170.24 237.96,173.24 237.85,173.35 v1(237.85,177.44) ; v1(134.9,45.42) 134.73,45.59 128.8,45.59 126.01,42.8 121.29,42.8 119.93,41.44 119.26,41.44 118.26,42.45 115.57,42.45 109.33,43.69 108.64,43.69 107.2,44.28 100.29,44.28 99.82,43.81 97.92,43.81 96.52,45.21 74.8,45.21 v1(73.28,46.74)
  ART04 w0.178: v1(204.41,18.92) 204.41,18.03 203.24,16.87 189.61,16.87 188.85,16.1 176.7,16.1 174.79,18.01 170.63,18.01 168.58,20.06 167.36,20.06 166.97,20.45 163.83,20.45 163.45,20.07 151.38,20.07 v1(150.8,20.65)
  BOTTOM w0.203: v1(134.9,45.42) 135.3,45.42 137.03,43.69 137.65,43.43 138.89,43.43 139.22,43.1 139.22,42.54 143.13,38.64 144.64,38.01 149.47,33.18 149.47,32.64 149.73,32.37 150,32.37 153.19,29.18 153.19,24.66 150.8,22.28 v1(150.8,20.65)
USB30_PWR1_EN1: length 76
  TOP w0.203: v1(99.85,38.12) 99.85,42.32 100.1,42.57 R2142.1 ; v1(120.4,38.91) 121.78,38.91 R189.1 ; v1(67.5,42.62) 61.18,42.62 59.74,41.17 59.74,40.59 59.44,40.28 58.98,40.28 58.48,39.78 Q2101.1 58.48,38.79 58.68,38.58 C80.2
  ART03 w0.178: v1(67.5,42.62) 71.99,38.12 v1(99.85,38.12)
  BOTTOM w0.203: v1(99.85,38.12) 101.22,36.75 104.22,36.75 104.75,37.29 109.53,37.29 110.24,36.58 111.38,36.58 111.76,36.96 111.76,37.72 112.95,38.91 v1(120.4,38.91)
USB_12M_X0_HUB1: length 19.1
  TOP w0.203: v1(100.58,50.16) 100.58,49.56 R110.2 C78.2 R109.2 R222.1 ; v1(113.1,46.89) 113.09,46.91 U2101.75
  ART04 w0.178: v1(113.1,46.89) 113.1,47.42 112.62,47.9 111.89,47.9 111.38,47.39 110.59,47.39 108.85,49.13 104.05,49.13 102.51,50.67 101.09,50.67 v1(100.58,50.16)
USB_12M_XI_HUB1: length 22.7
  TOP w0.203: R223.1 R112.2 R111.2 100.15,50.49 v1(100.58,50.93) ; v1(113.87,46.89) 113.49,47.27 U2101.74
  ART03 w0.178: v1(113.87,46.89) 113.35,47.41 112.94,47.41 111.4,45.86 107.97,45.86 107.94,45.84 107.93,45.84 107.49,45.4 103.76,45.4 103.57,45.59 102.01,45.59 101.05,46.55 101.05,50.46 v1(100.58,50.93)
USB_25M_XI_HUB1: length 4.1
  TOP w0.203: U2002.55 141.36,39.39 142.07,38.69 142.42,38.69 142.75,38.35 142.75,37.34 143.26,36.83 R2011.1
USB_25M_XO_HUB1: length 3
  TOP w0.203: U2002.56 141.76,39.48 142.14,39.09 142.52,39.09 143.36,38.25 R2012.1
USB_PWR_EN: length 58.2
  TOP w0.203: R2203.2 U2201.4 152.01,31.99 152.76,32.74 v1(154.26,32.74) ; v1(140.41,27.96) 139.95,27.51 R2207.2 138.56,27.13 138.56,26.16 138.72,26 U2202.4 ; R58.2 v1(175.36,53.47)
  ART03 w0.178: v1(168.1,40.44) 167.49,40.44 165.94,38.89 160.78,38.89 154.64,32.74 v1(154.26,32.74) 153.25,32.74 150.7,30.2 146.7,30.2 145.43,28.93 141.38,28.93 v1(140.41,27.96)
  ART04 w0.178: v1(175.36,53.47) 175.36,50.37 168.83,43.84 167.91,43.84 167.59,43.52 167.59,42.52 168.1,42.01 v1(168.1,40.44)
USIM0_CLK: length 190.4
  TOP w0.203: v1(99.82,34.8) 102.62,34.8 103.61,33.81 C104.2 103.12,33.27 102.43,33.97 U701.3 100.76,33.97 100.56,33.77 100.56,31.09 99.74,30.27 J702.3 ; v1(140.21,84.96) 141.48,84.96 142.75,83.69 R705.2 ; R801.2 187.58,83.21 187.86,82.93 v1(188.89,82.93)
  ART03 w0.178: v1(164.36,83.41) 164.36,82.98 162.51,81.13 159.16,81.13 156.27,78.24 154.78,78.24 153.98,79.05 153.98,80.96 151.44,83.5 151.44,85.26 150.76,85.94 149.39,85.94 148.09,87.24 146.69,87.24 145.82,86.37 141.62,86.37 v1(140.21,84.96) ; v1(180.57,79.43) 180.09,78.94 180.09,78.23 180.37,77.95 183.91,77.95 v1(188.89,82.93)
  ART04 w0.178: v1(140.21,84.96) 140.18,84.99 138.56,84.99 137.72,84.15 117.83,84.15 87.43,53.75 87.43,34.47 94.03,27.86 97.92,27.86 99.82,29.77 v1(99.82,34.8)
  BOTTOM w0.203: v1(164.36,83.41) 166.07,81.71 172.52,81.71 173.63,82.83 177.98,82.83 180.57,80.24 v1(180.57,79.43)
USIM0_DATA: length 185.3
  TOP w0.203: R706.2 137.82,84.91 v1(137.68,85.05) ; v1(98.04,34.8) 97.57,34.8 97.37,34.59 C105.1 ; v1(188.85,83.72) 188.6,83.97 R803.2 ; C105.1 98.12,33.86 98.23,33.97 U701.4 99.87,33.97 100.08,33.77 100.08,31.62 98.47,30.02 J702.7 ; C105.1 R722.1
  ART03 w0.178: v1(137.68,85.05) 139.38,85.05 139.99,84.44 140.45,84.44 141.73,85.72 144.65,85.72 146.45,84.69 146.63,84.37 146.86,84.23 147.79,84.23 148.74,84.63 149.52,85.41 150.54,85.41 150.9,85.04 150.9,83.28 153.44,80.74 153.44,78.83 154.56,77.71 156.49,77.71 159.38,80.59 163.32,80.59 v1(166.29,83.57) ; v1(180.7,78.66) 183.79,78.66 v1(188.85,83.72)
  ART04 w0.178: v1(98.04,34.8) 98.04,29.08 97.54,28.57 94.87,28.57 88.39,35.05 88.39,48.18 89.23,49.02 89.23,50.9 95.25,56.92 95.25,58.83 119.33,82.91 137.39,82.91 138.84,84.35 140.56,84.35 140.84,84.63 140.84,85.29 140.61,85.52 138.15,85.52 v1(137.68,85.05)
  BOTTOM w0.203: v1(166.29,83.57) 167.54,82.32 172.26,82.32 173.38,83.44 178.23,83.44 181.2,80.47 181.2,79.17 v1(180.7,78.66)
USIM0_DECT: length 127.8
  TOP w0.203: R104.1 96.62,30.2 96.27,29.84 v1(96.27,29.59) ; v1(148.33,81.99) 147.67,82.65 R48.2 ; R50.2 v1(171.44,83.79)
  ART03 w0.178: v1(148.33,81.99) 148.38,81.94 150.35,81.36 150.69,81.22 151.71,80.2 151.71,78.3 153.9,76.11 157.16,76.11 158.45,77.41 162.6,77.41 v1(164.34,75.67)
  ART04 w0.178: v1(148.33,81.99) 148.3,82.02 147.09,82.02 146.34,81.71 139.42,81.71 136.7,78.99 118.54,78.99 97.66,58.11 97.66,54.43 92.89,49.66 92.89,34.47 96.27,31.09 v1(96.27,29.59) ; v1(164.34,75.67) 164.34,76.69 v1(171.44,83.79)
USIM0_DECT_R: length 14.2
  TOP w0.203: v1(98.55,30.99) 99.1,31.54 U701.6 98.72,32.07 97.92,31.27 97.92,30.84 R104.2 ; v1(106.68,30.1) 105.97,29.39 J702.4
  BOTTOM w0.203: v1(106.68,30.1) 105.54,31.24 98.81,31.24 v1(98.55,30.99)
USIM0_PWR: length 144
  TOP w0.254: R49.2 v1(172.44,83.79) ; J702.1 104.82,29.64 105.03,29.84 105.03,30.61 104.78,30.86 C725.1 104.42,30.2 v1(104.52,30.1) ; v1(93.24,32.89) 94.11,32.89 ; v1(149.99,80.52) 149.12,80.52 146.05,81.79 145.67,82.17 R32.2 144.96,82.65 v1(144.86,82.75)
  ART03 w0.254: v1(149.99,80.52) 149.99,78.89 152.78,76.1 152.78,75.2 153.18,74.8 157.35,74.8 159,76.45 162.18,76.45 v1(162.97,75.67) ; v1(104.52,30.1) 103.07,30.1 99.26,33.91 93.98,33.91 93.24,33.17 v1(93.24,32.89)
  ART04 w0.254: v1(172.44,83.79) 172.19,83.79 165.5,77.1 164.72,75.24 164.47,74.98 163.65,74.98 v1(162.97,75.67) ; v1(144.86,82.75) 144.65,82.55 138.58,82.55 137.52,81.48 119.96,81.48 96.9,58.42 96.9,56.26 96.29,55.65 95.68,55.65 94.87,54.84 94.87,53.72 90.58,49.43 90.58,35.56 v1(93.24,32.89)
USIM0_RST: length 182
  TOP w0.203: R704.2 142.39,82.65 141.81,83.24 v1(141.81,83.82) ; v1(189.66,83.18) 189.99,83.51 R802.2 ; v1(101.73,30.61) 102.32,30.61 C103.2 103.57,31.9 103.53,31.9 103.36,32.07 U701.1 101.3,32.07 101.09,31.87 101.09,30.48 102.28,29.29 J702.2
  ART03 w0.178: v1(141.81,83.82) 145.3,83.82 147.15,83.06 148.49,83.06 150.34,82.53 151.18,82.25 152.91,80.52 152.91,78.61 154.34,77.18 156.71,77.18 158.01,78.47 164.83,78.47 v1(167.49,75.82) ; v1(189.66,83.18) 189.66,79.32 188.39,78.05 186.92,78.05 186,77.14 181.61,77.14 v1(180.47,76)
  ART04 w0.178: v1(141.81,83.82) 141.38,84.25 141.38,85.51 140.78,86.11 137.82,86.11 137.21,85.5 117.91,85.5 86.28,53.87 86.28,34.44 93.78,26.95 98.07,26.95 v1(101.73,30.61)
  BOTTOM w0.203: v1(167.49,75.82) 171.65,75.82 173.56,73.91 178.38,73.91 v1(180.47,76)
USIM1_DECT: length 18.9
  TOP w0.203: J803.66 176.28,93.73 v1(179.96,90.04) ; R50.1 170.82,85.47 v1(170.81,85.49)
  ART04 w0.178: v1(179.96,90.04) 176.78,90.04 172.23,85.49 v1(170.81,85.49)
USIM1_PWR: length 19.4
  TOP w0.254: v1(171.91,86.18) 172.16,86.18 172.44,85.9 R49.1 ; J803.36 183.78,92.72 v1(181.99,90.93)
  ART04 w0.254: v1(181.99,90.93) 175.46,90.93 171.91,87.38 v1(171.91,86.18)
V_3V3_HUB: length 119.6
  TOP w0.203: v1(137.21,62.74) 137.06,62.89 R2031.2 ; v1(135.08,69.2) 134.65,68.77 134.65,67.67 C2024.1
  TOP w0.254: C2024.1 134.24,67.67 U2003.8 ; v1(56.44,45.14) R2035.1 57.12,44.6 57.28,44.45 57.66,44.45 57.94,44.17 C2001.1
  TOP w0.305: C2001.1 U2001.8
  TOP w0.406: R2034.1 v1(70.51,46.99) R162.2 R2036.2 ; R2030.2 136.58,63.88 R2031.2 R163.2 136.58,61.52 135.38,60.32 v1(135.38,58.8)
  ART03 w0.406: v1(135.38,58.8) 130.03,58.8 121.63,60.31 118.44,63.5 75.57,63.5 70.51,58.44 v1(70.51,46.99)
  ART04 w0.254: v1(137.21,62.74) 136.37,63.58 136.37,67.91 v1(135.08,69.2)
  ART04 w0.406: v1(56.44,45.14) 56.82,45.14 58.67,46.99 v1(70.51,46.99)
V_3V3_USBHUB0: length 135.7
  TOP w0.203: 112.01,48.39 113.56,48.39 113.89,48.06 U2101.73 ; v1(119.48,43.34) 119.55,43.27 U2101.48 121.19,43.27 122.1,42.37 122.1,41.84 C2114.1 ; v1(110.62,46.43) 110.62,46.25 111.2,45.67 U2101.4 112.34,45.67 112.57,45.44 112.57,44.6 113.16,44.02 113.16,39.85 113.49,39.52 U2101.22 113.49,38.4 113.92,37.97 ; v1(100.46,41.02) 100.58,41.15 R2142.2
  TOP w0.254: R109.1 v1(98.83,48) ; R2103.1 v1(96.13,45.78) ; R2103.1 R2102.1 ; R2103.1 R2143.1 ; R207.1 R206.1 90.46,49.6 90.09,49.96 C76.1 C77.1 v1(89.81,48.34) ; 113.92,37.97 114.15,37.74 C2117.2 ; LB2101.2 110.41,33.74 R337.1 ; R112.1 v1(98.86,52.03) ; v1(110.62,46.43) 110.54,46.51 C2116.1 ; C2111.1 111,49.28 111.89,48.39 112.01,48.39 v1(112.01,48.36)
  TOP w0.406: v1(73.28,47.5) 72.54,47.5 R162.1
  ART03 w0.254: 112.01,48.39 114.41,48.39 119.13,43.67 119.16,43.67 v1(119.48,43.34) 125.29,43.34 125.3,43.33 v1(125.76,43.33) ; 112.01,48.39 111.03,48.39 110.62,47.98 v1(110.62,46.43) ; 112.01,48.39 v1(112.01,48.36) ; v1(89.81,48.34) 90.14,48.66 90.14,50.06 91.11,51.03 98.32,51.03 98.86,51.57 v1(98.86,52.03)
  ART04 w0.254: v1(98.86,52.03) 98.83,52 v1(98.83,48) ; v1(110.62,46.43) 109.3,47.75 108.66,47.75 107.67,48.74 99.8,48.74 99.05,48 v1(98.83,48) ; v1(98.83,48) 97.91,48 96.13,46.22 v1(96.13,45.78) 96.13,45.49 96.23,45.25 v1(100.46,41.02)
  BOTTOM w0.406: v1(111.38,33.02) 110.74,33.02 108.2,35.56 101.69,35.56 99.97,37.29 90.48,37.29 80.26,47.5 v1(73.28,47.5)
V_5V0_HUB: length 9.8
  BOTTOM w0.254: v1(133.5,40.16) 133.5,41.88 132.84,42.54 132.84,49.22 v1(133.2,49.58)
V_12V0_CON_IN: length 126.5
  TOP w0.203: R3003.2 v1(23.37,164.12)
  TOP w0.254: R3019.1 15.42,180.19 15.67,179.93 v1(17.47,179.93) 19.2,179.93 19.46,180.19 R3018.1 ; U3001.9 26.93,173.73 26.73,173.93 C38.1 26.73,174.9 26.7,174.94 R3006.2 26.7,176.26 27.31,176.87 27.31,178.43 v1(27.05,178.69) 25.01,178.69 24.59,178.27 C3010.1 ; R3012.1 v1(3.94,145.31)
  TOP w0.406: v1(6.88,145.33) R3013.2
  ART03 w0.254: v1(3.94,145.31) 4.34,145.72 4.34,148.25 5.32,149.22 5.32,176.97 7.75,179.4 16.94,179.4 v1(17.47,179.93)
  ART03 w0.406: v1(17.45,181.38) 18.67,180.16 18.67,175.39 16,172.72 16,166.87 ; v1(6.88,145.33) 9.53,147.98 9.53,162.94 13.45,166.87 16,166.87 ; 16,166.87 18.86,164.01 22.33,164.01 22.44,164.12 v1(23.37,164.12)
  BOTTOM w0.254: v1(27.05,178.69) 26.29,179.45 17.96,179.45 v1(17.47,179.93)
  vias: v1(13.89,184.58) v1(13.89,183.82) v1(14.66,184.58) v1(14.66,183.82) v1(15.42,184.58) v1(15.42,183.82) v1(17.45,182.9) v1(17.45,182.14)
V_12V0_IN:
  vias: v1(9.91,172.34) v1(9.91,171.7) v1(31.76,171.56) v1(32.4,171.56)
V_12V0_SENSE: length 66.5
  TOP w0.254: 19.46,177.8 18.85,178.41 v1(17.47,178.41) 15.42,178.41 15.24,178.23 15.24,176.68 ; R86.2 27.76,178.13 v1(28.07,178.43) 28.8,177.87 C3001.1 ; v1(4.95,145.31) R3011.2
  ART03 w0.254: v1(4.95,145.31) 4.95,148.32 5.7,149.07 5.7,176.82 7.91,179.02 16.86,179.02 v1(17.47,178.41)
  BOTTOM w0.254: v1(28.07,178.43) 27.69,178.05 26.8,178.05 25.92,178.93 18,178.93 v1(17.47,178.41)
  vias: v1(9.14,177.8) v1(9.14,176.53) v1(10.41,177.8) v1(10.41,176.53) v1(11.68,177.8) v1(11.68,176.53) v1(17.45,176.96) v1(17.45,176.2) v1(17.45,175.44)
V_ADJ_TEC:
  vias: v1(189.72,56.8) v1(189.72,56.24) v1(189.72,55.68) v1(190.36,56.8) v1(190.36,56.24) v1(190.36,55.68) v1(214.53,53.8) v1(214.73,52.12) v1(214.73,50.6) v1(216.31,53.8) v1(216.26,52.12) v1(216.26,50.6) v1(217.78,52.12) v1(217.78,50.6) v1(218.08,53.8) v1(221.89,53.8) v1(222.1,52.12) v1(222.1,50.6) v1(223.62,52.12) v1(223.62,50.6) v1(223.67,53.8) v1(225.15,52.12) v1(225.15,50.6) v1(225.45,53.8)
V_AVDD_1V0_PHY0: length 8.7
  TOP w0.203: U1201.47 v1(148.07,75.17) ; U1201.4 145.26,77.01 v1(145.38,77.13) ; U1201.9 143.26,77.1 v1(143.23,77.13)
  ART03 w0.254: v1(143.23,77.13) 145.37,77.13 v1(145.38,77.13) 145.8,76.71 147.11,76.71 147.57,76.24 147.57,75.67 v1(148.07,75.17)
  vias: v1(148.13,62.79) v1(148.39,65.1)
V_AVDD_3V3_PHY0: length 29.6
  TOP w0.203: v1(141.58,76.14) 141.77,75.95 141.99,75.95 142.06,76.02 U1201.12
  TOP w0.254: U1201.1 146.49,76.29 146.85,76.29 v1(146.94,76.2)
  ART03 w0.254: v1(141.58,76.14) 141.64,76.2 v1(146.94,76.2) 146.94,72.39 147.6,71.73 147.6,67.66 148.73,66.53 148.74,66.52 148.74,66.52 149.81,66.52 150.39,65.94 150.39,65.94 150.62,65.71 150.62,64.19 150.01,63.58 148.13,63.58 147.57,63.02 144.6,63.02 v1(143.97,62.38) v1(143.33,62.38) v1(142.7,62.38)
V_BAT_3V0: length 188.9
  TOP w0.254: J3.283 48.6,117.43 v1(47.88,116.71) ; v1(192.28,23.04) R3221.1 192.53,22.3 192.74,22.1 R3220.1 ; v1(60.96,41.27) 61.72,42.04 70.36,42.04 v1(70.55,42.23)
  TOP w0.406: v1(60.96,41.27) 60.96,40.33 D15.2
  ART03 w0.254: v1(192.28,23.04) 191.77,23.55 190.04,23.55 189.84,23.34 188.47,23.34 185.22,20.09 169.08,20.09 166.97,17.98 166.97,17.59 166.57,17.2 165.86,17.2 163.96,15.29 163.96,13.46 162.18,11.68 162.18,10.74 159.17,7.74 149.59,7.74 147.75,9.58 80.42,9.58 80.09,9.91 v1(78.49,9.91)
  BOTTOM w0.254: v1(47.88,116.71) 46.62,115.87 46.5,115.82 45.85,115.82 45.29,115.26 45.29,104.32 45.97,103.63 v1(46.33,103.63) ; v1(78.49,9.91) 78.49,34.29 v1(70.55,42.23)
V_DV11_HUB: length 56.5
  TOP w0.203: U2002.67 144.42,44.22 v1(144.58,44.07) ; U2002.61 143.73,41.82 v1(143.83,41.72) ; U2002.3 141.36,49.31 141.73,49.68 C2002.1 ; U2002.76 143.2,47.82 143.64,48.26 143.64,48.77 v1(143.76,48.89) ; U2002.40 135.36,38.51 135.2,38.35 ; U2002.46 137.76,39.38 v1(137.03,38.66) ; U2002.12 137.76,48.18 137.55,47.98 ; U2002.49 138.96,38.81 v1(138.81,38.66) ; 134.8,47.02 U2002.22 133.47,47.02 133.06,47.43 ; v1(144.46,45.5) 144.38,45.42 U2002.70
  TOP w0.254: C2015.1 v1(144.58,44.07) ; 134.8,47.02 134.9,47.12 134.9,47.75 135.13,47.98 137.55,47.98 ; v1(143.83,41.72) 143.89,41.78 144.6,41.78 C2013.1 ; C2010.1 v1(138.81,38.66) ; v1(143.76,48.89) 144.15,49.28 C2016.1 ; C2019.1 132.23,48.23 132.26,48.21 132.28,48.21 133.06,47.43 ; C2002.1 v1(142.44,50.22) ; v1(144.46,45.5) 145.15,45.5 C2018.1 ; C2009.1 v1(137.03,38.66)
  ART03 w0.254: v1(143.83,41.72) 143.38,41.27 143.13,41.27 141.22,39.37 139.52,39.37 v1(138.81,38.66) 137.49,38.66 137.49,38.66 v1(137.03,38.66)
  ART04 w0.254: v1(143.83,41.72) 144.26,42.15 144.58,42.92 v1(144.58,44.07) 144.55,44.09 144.55,45.41 v1(144.46,45.5) 144.55,45.59 144.55,45.74 145.09,46.28 145.09,47.57 v1(143.76,48.89) v1(142.44,50.22) 142.05,50.61 v1(136.5,50.61)
  BOTTOM w0.508: v1(137.03,38.66) 136.63,38.26 136.63,35.45 137.8,34.29 v1(139.45,34.29) v1(140.21,34.29)
V_DV12_HUB: length 81.7
  TOP w0.203: U2101.58 119.89,47.45 120.09,47.24 121.39,47.24 121.62,47.47 121.62,47.62 121.97,47.98 C2126.1 ; U2101.3 111.46,46.07 111.2,46.33 v1(111.2,47.88) ; U2101.64 117.49,48.53 118.56,49.59 C2120.1 ; U2101.70 115.09,47.01 v1(114.55,46.48) ; C2123.1 110.05,44.86 110.44,44.47 U2101.7 ; U2101.50 120.25,44.07 120.12,43.94 120.12,43.79 120.24,43.67 U2101.49 121.24,43.67 121.25,43.66
  TOP w0.254: v1(122.62,42.35) 122.53,42.44 C2128.1 121.95,43.05 121.34,43.66 121.25,43.66 ; C2127.1 110.82,48.26 v1(111.2,47.88) ; v1(110.11,52.58) 110.29,52.4 C42.1 ; C2120.1 118.94,50.2 v1(119.23,50.49) ; C2126.1 122.58,47.98 v1(122.81,47.75) ; v1(108.51,44.35) 109.01,44.86 C2123.1
  ART03 w0.254: v1(111.16,39.2) 111.35,39.39 122.05,39.39 v1(123.09,38.35) ; v1(111.2,47.88) 113.92,47.88 114.55,47.24 v1(114.55,46.48) 114.55,45.47 113.41,44.32 112.52,44.32 112.14,44.7 108.86,44.7 v1(108.51,44.35)
  ART04 w0.254: 119.23,50.32 v1(119.23,50.49) ; 119.23,50.32 121.79,47.75 v1(122.81,47.75) ; 119.23,50.32 119.23,50.29 116.69,47.75 115.82,47.75 v1(114.55,46.48) ; v1(122.62,42.35) 123.7,41.28 123.7,38.96 v1(123.09,38.35) ; v1(108.51,44.35) 111.16,41.69 v1(111.16,39.2) 111.51,38.86 114.55,38.86 117.46,35.96 v1(117.46,34.63) ; v1(111.2,47.88) 111.25,47.93 111.25,49.49 110.11,50.63 v1(110.11,52.58)
V_DV33_HUB: length 76.5
  TOP w0.203: U2002.58 143.66,40.62 v1(143.83,40.45) ; v1(140.59,38.53) 140.59,38.61 140.16,39.04 U2002.52 ; v1(136.02,38.63) 136.56,39.17 U2002.43 ; v1(143.82,42.67) 143.47,43.02 U2002.64 ; C2006.2 135.79,49.63 136.14,49.28 136.4,49.28 136.56,49.12 U2002.15 ; U2002.73 143.8,46.62 144.25,47.06 144.25,47.09 v1(144.55,47.4) ; v1(140.11,49.71) 140.16,49.66 U2002.6 ; U2002.29 133.76,44.22 133.48,43.94
  TOP w0.254: C2014.1 v1(143.82,42.67) ; v1(143.83,40.45) 144.21,40.83 144.57,40.83 C2012.1 ; 133.48,43.94 133.48,43.43 133.32,43.28 R336.2 132.7,43.2 C2020.2 ; C2017.1 144.7,47.24 v1(144.55,47.4) ; R201.2 134.98,50.82 135.15,50.65 v1(135.15,50.03) 135.17,50.01 C2006.2 ; v1(140.11,49.71) 139.93,49.89 C2003.2 ; R2008.2 R298.2 ; R298.2 v1(130.68,38.48) ; R298.2 R2009.2 ; C2020.2 131.85,43.36 131.04,44.17 R2032.2 131.04,44.81 131.08,44.85 R2038.1 130.15,45.61 129.92,45.85 129.92,48.39 130.68,49.15 130.89,49.15 LB2002.2 ; C2020.2 131.85,42.87 v1(132.31,42.42) ; C2011.2 v1(140.59,38.53) ; C2008.1 v1(136.02,38.63)
  TOP w0.406: R163.1 133.99,60.07 133.99,57.15 131.51,54.67 C2037.2
  ART03 w0.254: v1(143.83,40.45) 143.19,40.45 141.28,38.53 v1(140.59,38.53) 139.88,38.53 139.5,38.15 136.58,38.15 136.09,38.63 v1(136.02,38.63) ; v1(135.15,50.03) 136.33,50.03 137.11,49.71 v1(140.11,49.71)
  ART04 w0.254: v1(135.15,50.03) 135.15,50.9 v1(132.91,53.15) v1(132.32,53.15) ; v1(140.11,49.71) 141.09,49.71 v1(144.55,47.4) 144.55,46.54 143.82,45.8 v1(143.82,42.67) 143.35,42.2 143.35,40.93 v1(143.83,40.45) ; v1(132.31,42.42) 132.21,42.42 131.45,41.66 131.45,39.24 v1(130.68,38.48)
V_DVDD_1V0_PHY0: length 6
  TOP w0.203: v1(138.73,72.95) 138.73,72.77 139.62,71.88 140.72,71.88 140.81,71.97 U1201.22
  TOP w0.254: v1(138.73,72.95) 138.66,73.02 137.35,73.02 137.29,72.97 137.29,73.66 C1214.2
  vias: v1(144.27,64.08) v1(144.27,63.52)
V_HOT_12V0_D1: length 1.9
  BOTTOM w0.254: v1(40.58,92.96) v1(40.58,92.33) ; v1(31.94,92.96) v1(31.94,92.33) ; v1(42.1,92.96) v1(42.1,92.33)
  vias: v1(34.91,129.86) v1(34.91,129.22) v1(35.05,134.75) v1(35.05,133.48) v1(35.05,132.21) v1(35.55,129.86) v1(35.55,129.22) v1(36.18,129.86) v1(36.18,129.22) v1(36.32,134.75) v1(36.32,133.48) v1(36.32,132.21) v1(37.38,92.99) v1(37.38,92.35) v1(37.59,134.75) v1(37.59,133.48) v1(37.59,132.21) v1(39.69,110.3) v1(39.69,109.73) v1(39.82,105.35) v1(39.82,104.71) v1(41.09,105.35) v1(41.09,104.71) v1(42.36,105.35) v1(42.36,104.65) v1(43.63,110.3) v1(43.63,109.73) v1(43.63,105.35) v1(43.63,104.65) v1(46.06,130.09) v1(46.06,129.45) v1(46.67,130.09) v1(46.67,129.45) v1(47.31,130.09) v1(47.31,129.45) v1(47.43,137.35) v1(47.43,136.72) v1(47.43,135.32) v1(47.43,134.68) v1(52.77,135.95) v1(52.77,135.19) v1(52.77,134.43) v1(52.77,133.67) v1(72.83,135.46) v1(73.15,134.87) v1(73.46,135.46) v1(74.1,135.46) v1(88.17,140.5) v1(88.94,140.5) v1(89.66,140.51) v1(104.52,135.13) v1(104.52,134.49)
V_HOT_12V0_D2: length 44.6
  ART03 w0.508: v1(153.54,43.51) 153.04,43 153.04,39.52 151.36,37.85 150.83,37.85 147.65,34.67 145.59,34.67 143.87,32.94 v1(140.08,32.94)
  ART03 w0.635: 138.48,32.94 137.41,31.88 129.57,31.88 126.99,29.3 v1(116.04,29.3) v1(115.32,29.3)
  vias: v1(27.56,111.73) v1(27.56,110.46) v1(27.56,109.19) v1(28.83,111.73) v1(28.83,110.46) v1(28.83,109.19) v1(30.1,111.73) v1(30.1,110.46) v1(30.1,109.19) v1(31.24,110.57) v1(31.24,109.3) v1(31.37,112.74) v1(31.37,111.89) v1(101.63,49.4) v1(101.92,49.97) v1(102.24,49.4) v1(102.95,38.18) v1(102.93,37.53) v1(103.59,38.16) v1(103.58,37.52) v1(116.59,57.4) v1(117.35,57.4) v1(127.43,46.66) v1(127.46,45.72) v1(138.79,33.07) v1(139.45,32.94) v1(140.03,57.96) v1(140.02,57.43) v1(140.02,56.89) v1(153.54,44.65) v1(153.54,44.09)
V_HOT_12V0_D3: length 1.3
  ART03 w0.254: v1(35.75,87.63) v1(35.75,87) ; v1(31.94,87) v1(31.94,87.63)
  vias: v1(31.43,72.11) v1(31.43,71.48) v1(31.43,69.09) v1(31.43,68.45) v1(35.24,72.11) v1(35.24,71.48) v1(35.24,69.09) v1(35.24,68.45) v1(39.05,72.09) v1(39.05,71.45) v1(39.05,69.06) v1(39.05,68.43) v1(39.98,88.1) v1(39.98,86.83) v1(39.98,85.56) v1(40.95,72.14) v1(41.25,88.1) v1(41.25,86.83) v1(41.25,85.56) v1(41.71,72.14) v1(42.22,75.18) v1(42.52,88.1) v1(42.52,86.83) v1(42.52,85.56) v1(42.86,72.09) v1(42.86,71.45) v1(42.86,69.06) v1(42.86,68.43) v1(42.98,75.18) v1(43.49,72.14) v1(43.88,69.06) v1(43.88,68.43) v1(44.25,72.14) v1(48.9,59.56) v1(48.9,58.93) v1(48.9,58.29) v1(48.9,57.66) v1(48.9,55.75) v1(48.9,55.12) v1(48.9,54.48) v1(66.77,59.56) v1(66.77,58.93) v1(66.77,58.29) v1(66.77,57.66) v1(66.77,55.75) v1(66.77,55.12) v1(66.77,54.48) v1(87.05,56.93) v1(87.06,59.44) v1(87.06,58.17) v1(87.95,59.44) v1(87.95,58.17) v1(87.94,56.93) v1(100.23,59.87) v1(100.19,58.8) v1(100.19,57.53) v1(117.88,59.87) v1(120.42,59.87)
V_HOT_12V_1:
  vias: v1(35.69,138.15) v1(36.27,138.15) v1(36.53,148.56) v1(36.53,147.29) v1(36.86,138.15) v1(37.44,138.15) v1(37.8,148.56) v1(37.8,147.29) v1(46.16,88.29) v1(46.16,87.53) v1(46.16,86.77) v1(46.16,86)
V_LTE_3V3: length 154.7
  TOP w0.254: R2825.1 193.93,31.62 194.26,31.95 v1(194.26,32.51) ; v1(112.01,183.13) 111.94,183.06 R3126.2 ; R701.2 188.98,73.05 187.86,74.17 182.91,74.17 177.54,73.1 172.98,73.1 170.92,75.16 v1(165.51,75.16) 162.45,75.16 161.95,74.66 161.81,74.32 161.46,73.96 160.86,73.96 160.65,74.17 160.6,74.3 159.73,75.16 159.48,75.16 157.48,75.36 156.17,76.67 LB702.1 ; v1(137.38,86.49) 137.13,86.24 137.13,85.22 136.88,84.96 C731.1 136.02,84.58 D1.1
  ART03 w0.254: v1(117.22,181.61) 117.22,182.07 116.56,182.73 112.42,182.73 v1(112.01,183.13) ; v1(165.51,75.16) 166.95,75.16 169.06,73.05 169.06,70.52 170.4,69.19 170.53,69.19 171.93,67.79 171.93,63.14 175.97,59.11 v1(175.97,56.26) ; 144.81,89.89 141.58,89.89 138.18,86.49 v1(137.38,86.49)
  ART04 w0.203: v1(194.26,32.51) 194.09,32.35 187.74,32.35 187.23,31.83
  ART04 w0.254: 187.23,31.83 178.24,22.85 174.17,22.85 173.48,23.54 173.48,23.58 171.59,25.46 171.59,27.02 168.89,29.72 168.57,29.72 168.28,30.01 168.28,30.18 167.57,30.89 167.02,30.89 165.74,32.17 165.74,32.6 165.99,32.85 165.99,33.62 165.81,33.8 165.81,34.22 165.9,34.31 165.9,38.23 165,39.13 165,39.82 164.4,40.42 164.4,40.68 164.39,40.69 164.39,50.36 170.8,56.77 173.15,56.77 173.66,56.26 v1(175.97,56.26)
  vias: v1(117.22,181.05) v1(117.22,180.49) v1(117.22,179.93) v1(117.22,179.37) v1(117.22,178.82) v1(146.4,94.51) v1(146.42,93.72) v1(147.03,94.51) v1(147.06,93.72) v1(154.69,79.22) v1(155,78.76) v1(155.32,79.76) v1(155.27,79.22)
V_LTE_3V8: length 64.5
  TOP w0.254: R2820.1 187.88,31.62 187.57,31.94 187.57,33.59 v1(186.36,34.8) ; v1(195.68,77.27) 195.68,77.72 195.24,78.17 194.89,78.17 ; R3116.2 v1(107.19,180.59)
  ART03 w0.254: v1(106.27,173.18) 106.27,174.47 106.45,174.65 106.45,175.39 107.19,176.12 v1(107.19,180.59)
  ART03 w0.381: v1(195.68,77.27) 195.68,67.79 v1(193.55,65.66)
  ART04 w0.254: v1(186.36,34.8) 184.53,34.8 183.77,35.56 183.77,37.08 184.54,37.86 184.54,41.26 183.77,42.04 183.77,48.79 188.34,53.36 188.34,56.39 190.2,58.24 190.2,59.44 192.68,61.92 192.68,64.79 v1(193.55,65.66)
  vias: v1(104.62,173.2) v1(104.62,172.44) v1(106.27,172.41) v1(128.52,148.34) v1(128.52,147.7) v1(129.16,148.34) v1(129.16,147.7) v1(171.36,96.96) v1(171.92,96.96) v1(171.92,96.4) v1(172.48,96.96) v1(172.48,96.4) v1(194.83,88.1) v1(194.83,87.54) v1(194.83,86.98)
V_SDCARD_V33: length 19.5
  TOP w0.254: U1902.5 117.17,22.27 117.46,21.97 117.46,20.45 v1(117.49,20.42) ; Q1901.3 131.15,13.1 C1904.1 ; v1(124.88,20.32) 125.12,20.32 125.7,20.9 125.7,22.05 125.49,22.27 U1901.5
  BOTTOM w0.254: v1(117.49,20.42) 120,17.91 121.66,17.91 v1(122.68,16.89) 122.81,16.89 124.88,18.96 v1(124.88,20.32)
V_STBY_1V8: length 299.8
  TOP w0.178: v1(134.99,65.77) 134.99,65.6 135.66,64.92 R1237.1
  TOP w0.254: v1(188.34,47.12) 188.7,47.12 188.98,47.4 R2826.2 ; U3401.5 26.35,76.13 26.77,76.56 C3406.1 v1(28.32,76.56) ; R1325.1 118.39,128.07 119.3,128.07 120.4,129.16 120.4,130.55 120.14,130.81 U1301.2 118.7,130.81 R1319.2 117.93,132.21 ; R2986.1 22.27,134.34 R2985.1 22.99,133.86 v1(22.73,133.6) ; 62.74,140.08 62.61,139.95 60.57,139.95 R2974.1 ; U2704.1 6.89,108.36 7.49,108.97 8.26,108.97 8.53,109.24 C2714.2 R92.1 8.53,111.1 8.26,111.38 v1(4.72,111.38) 3.94,111.38 3.38,110.82 3.38,109.78 3.63,109.53 R93.1 ; 117.93,132.21 C1320.2 ; 117.93,132.21 116.8,132.21 116.59,132 116.28,132 v1(115.77,131.5) ; R364.1 R360.1 R362.1 R352.1 R342.1 R346.1 R345.1 R344.1 154.04,45.23 154.31,44.97 154.31,44.92 154.36,44.87 154.36,42.93 154.03,42.6 R291.1 R390.1 R294.1 R293.1 153.81,37.22 153.34,36.75 v1(153.34,36.73) ; v1(23.32,27.36) 23.32,27.13 23.52,26.92 R167.2 23.95,27.38 24.06,27.48 26.72,27.48 27.81,28.57 v1(28.32,28.57) R200.2 ; v1(74.04,132.97) R280.1 Q1.1 ; U2003.1 134.24,75.72 133.78,76.17 R2754.1 134.22,76.35 134.54,76.67 v1(134.54,77.06) 134.54,77.88 134.29,78.13 C2025.2 ; U17.1 33.75,22.56 C166.1 34.7,20.88 v1(34.67,20.85) 34.7,20.83 36.55,20.83 37.59,21.87 R376.1 R377.1 ; R168.1 10.82,26.95 Q4.1 9.65,25.68 10.06,25.27 10.44,25.27 11.96,23.75 v1(19.69,23.75) ; R2755.1 131.83,80.21 v1(131.45,80.59) ; R295.1 R378.1 R377.1 ; LB1407.1 108.16,143.85 107.5,143.18 v1(107.32,142.75) ; R377.1 v1(38.35,23.73) ; 71.91,147.04 71.91,147.05 74.7,147.05 76.12,145.62 R2976.1
  ART03 w0.254: v1(74.04,132.97) 75.06,133.98 75.06,137.55 77.44,139.93 84.25,139.93 v1(84.81,140.49) ; v1(28.32,28.57) 29.72,28.57 31.12,27.18 ; v1(19.69,23.75) 20.19,23.24 21.34,23.24 21.97,23.88 21.97,26.01 v1(23.32,27.36)
  ART04 w0.254: v1(115.77,131.5) 113.59,133.68 111.58,133.68 107.32,137.95 v1(107.32,142.75) 95.64,142.75 92.35,143.76 89.36,144.8 v1(86.23,145.59) ; v1(20.88,115.44) 19.99,114.55 13.59,114.55 13.08,115.06 7.62,115.06 4.72,112.17 v1(4.72,111.38) ; v1(24.26,115.06) 24.64,115.44 29.21,115.44 32.89,119.13 34.04,119.13 35.87,120.95 49.84,120.95 50.67,121.79 54.1,121.79 54.61,121.28 61.21,121.28 62.48,120.01 62.48,119.51 63.93,118.06 70.05,118.06 71.12,119.13 71.12,122.94 73.91,125.73 73.91,130.61 74.04,130.73 v1(74.04,132.97) ; v1(134.54,77.06) 134.09,76.61 134.09,66.67 v1(134.99,65.77)
  BOTTOM w0.254: v1(188.34,47.12) 188.34,47.19 186.13,49.4 184.7,49.4 183.77,50.33 183.77,51.08 183.13,51.71 183.13,52.72 183.13,54.72 183.24,54.83 183.24,55.79 181.48,57.56 181.48,68.83 v1(178.18,72.14) ; v1(118.29,26.87) 118.29,27 117.29,28 v1(115.72,28)
  vias: v1(9.68,140.21) v1(9.68,139.57) v1(21.21,48.41) v1(21.21,47.78) v1(21.21,47.12) v1(21.51,115.44) v1(23.76,39.33) v1(24.38,39.34) v1(32.15,159.04) v1(32.79,159.04) v1(60.2,35.84) v1(60.83,35.84) v1(69.47,161.42) v1(69.98,149.73) v1(70.1,161.42) v1(70.61,149.73) v1(85.45,140.49) v1(85.6,145.59) v1(93.35,168.78) v1(159.11,54.08) v1(159.72,53.97) v1(161.26,45.34) v1(161.37,36.25) v1(161.9,45.34) v1(184.02,76.33)
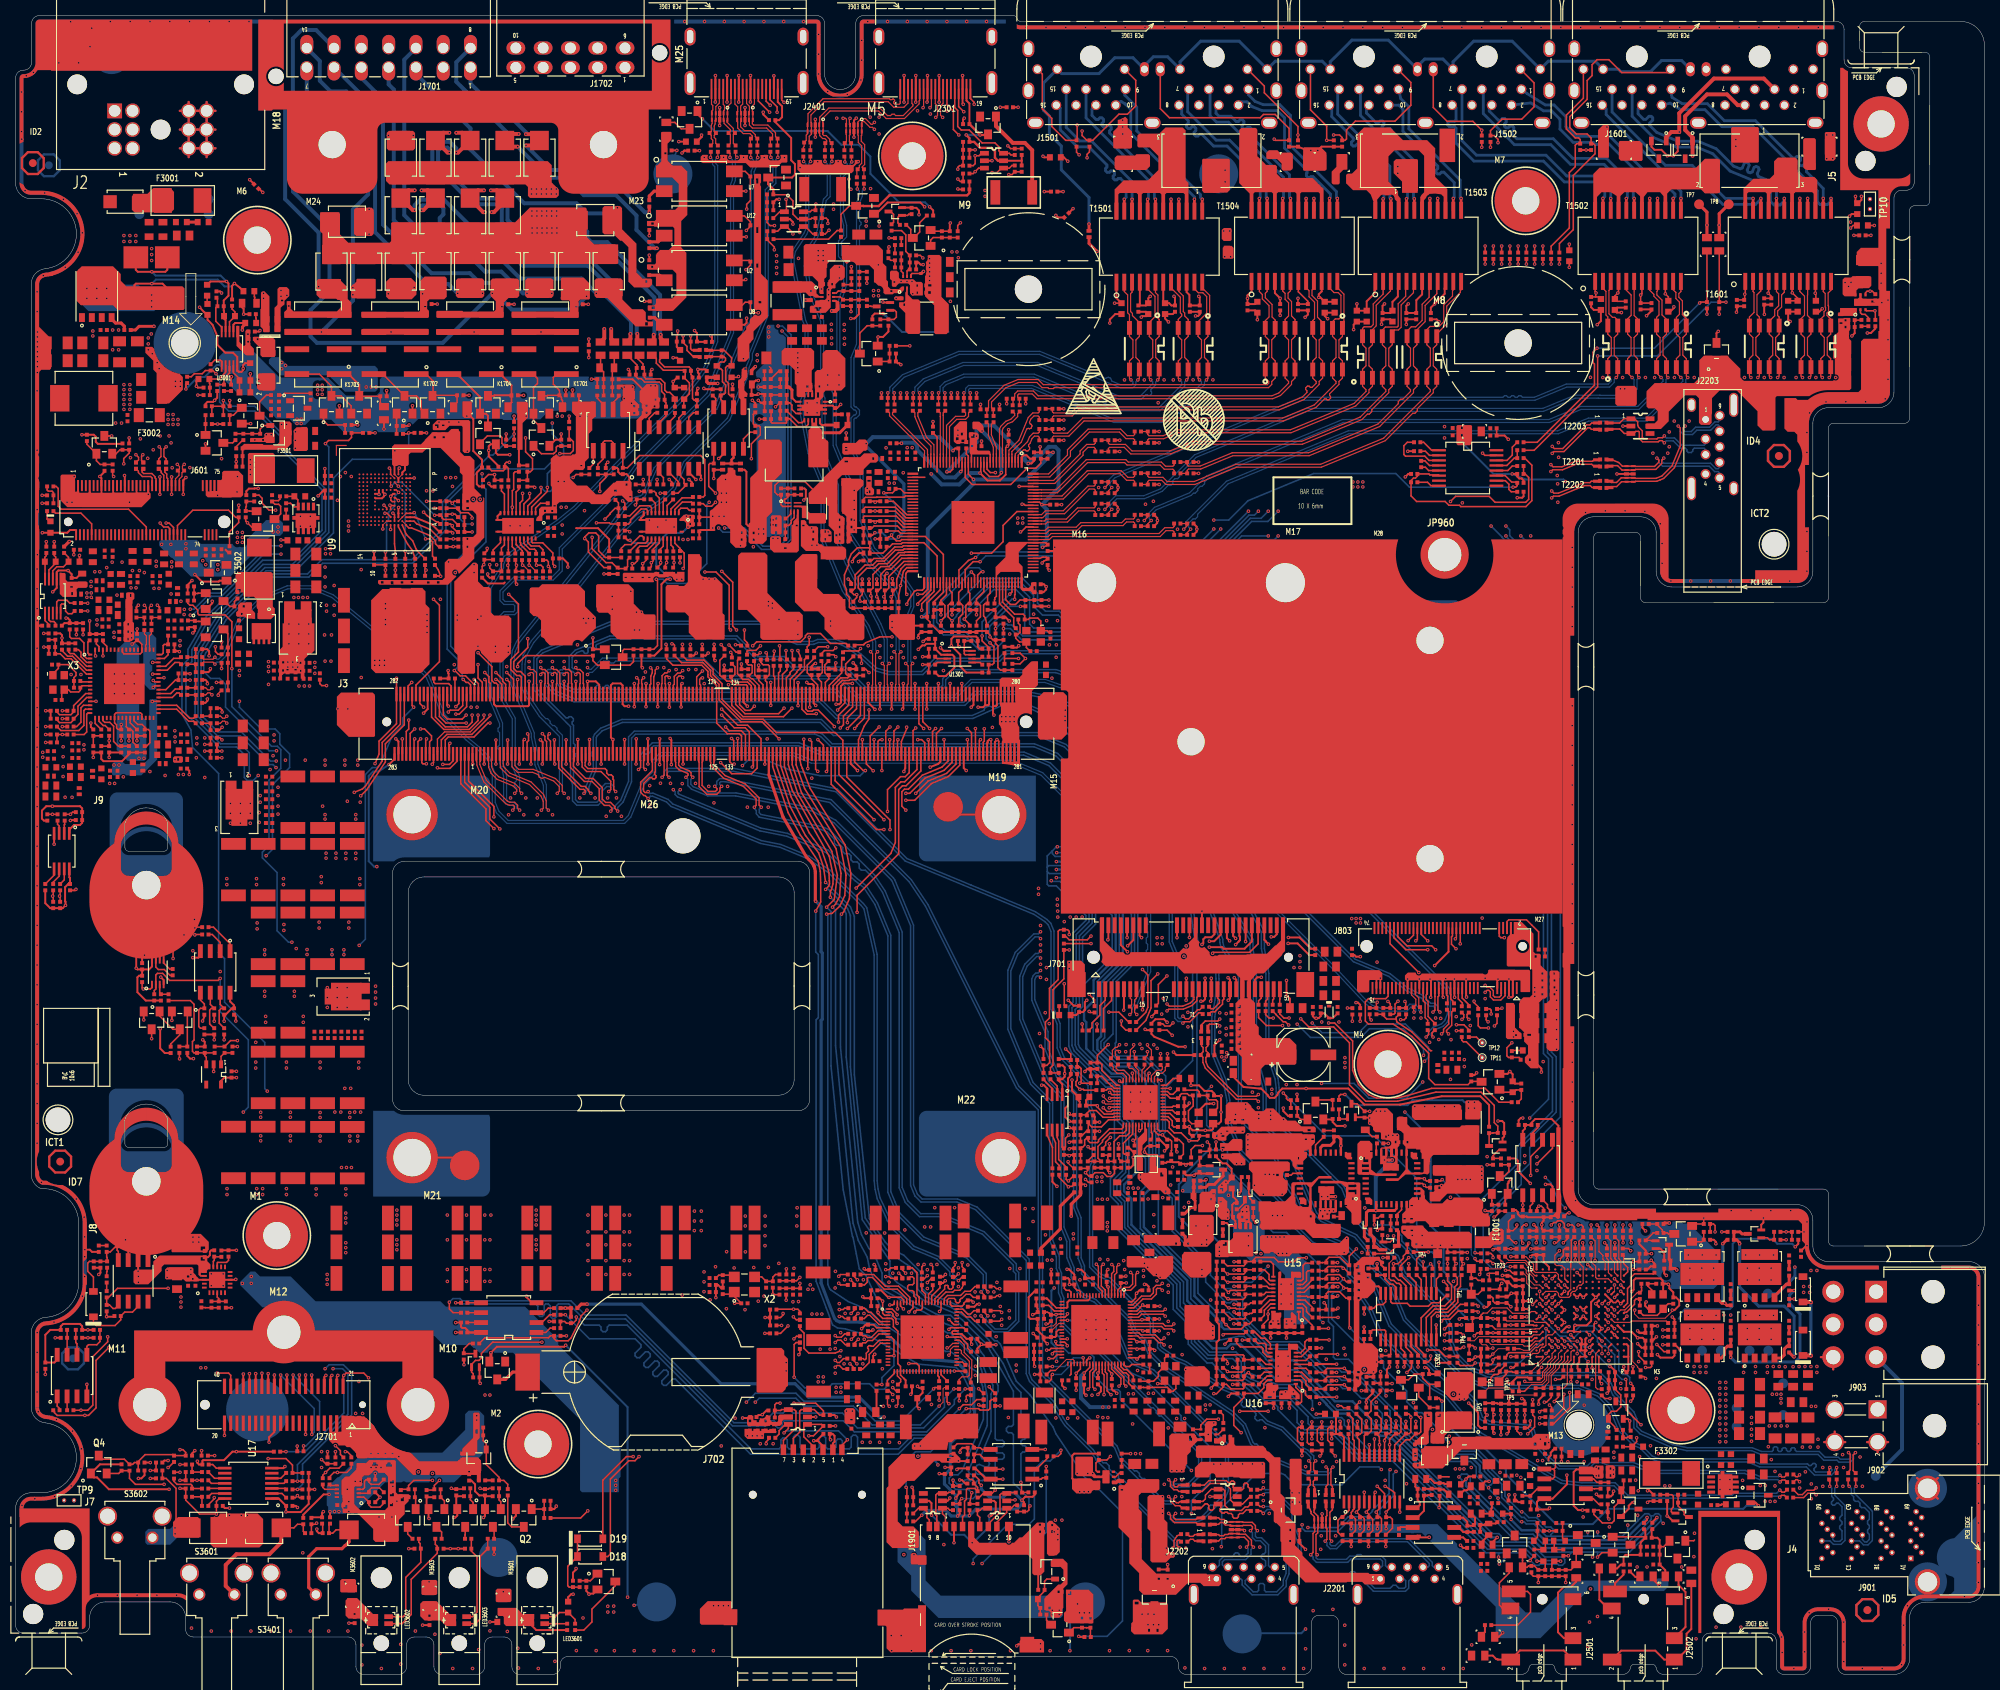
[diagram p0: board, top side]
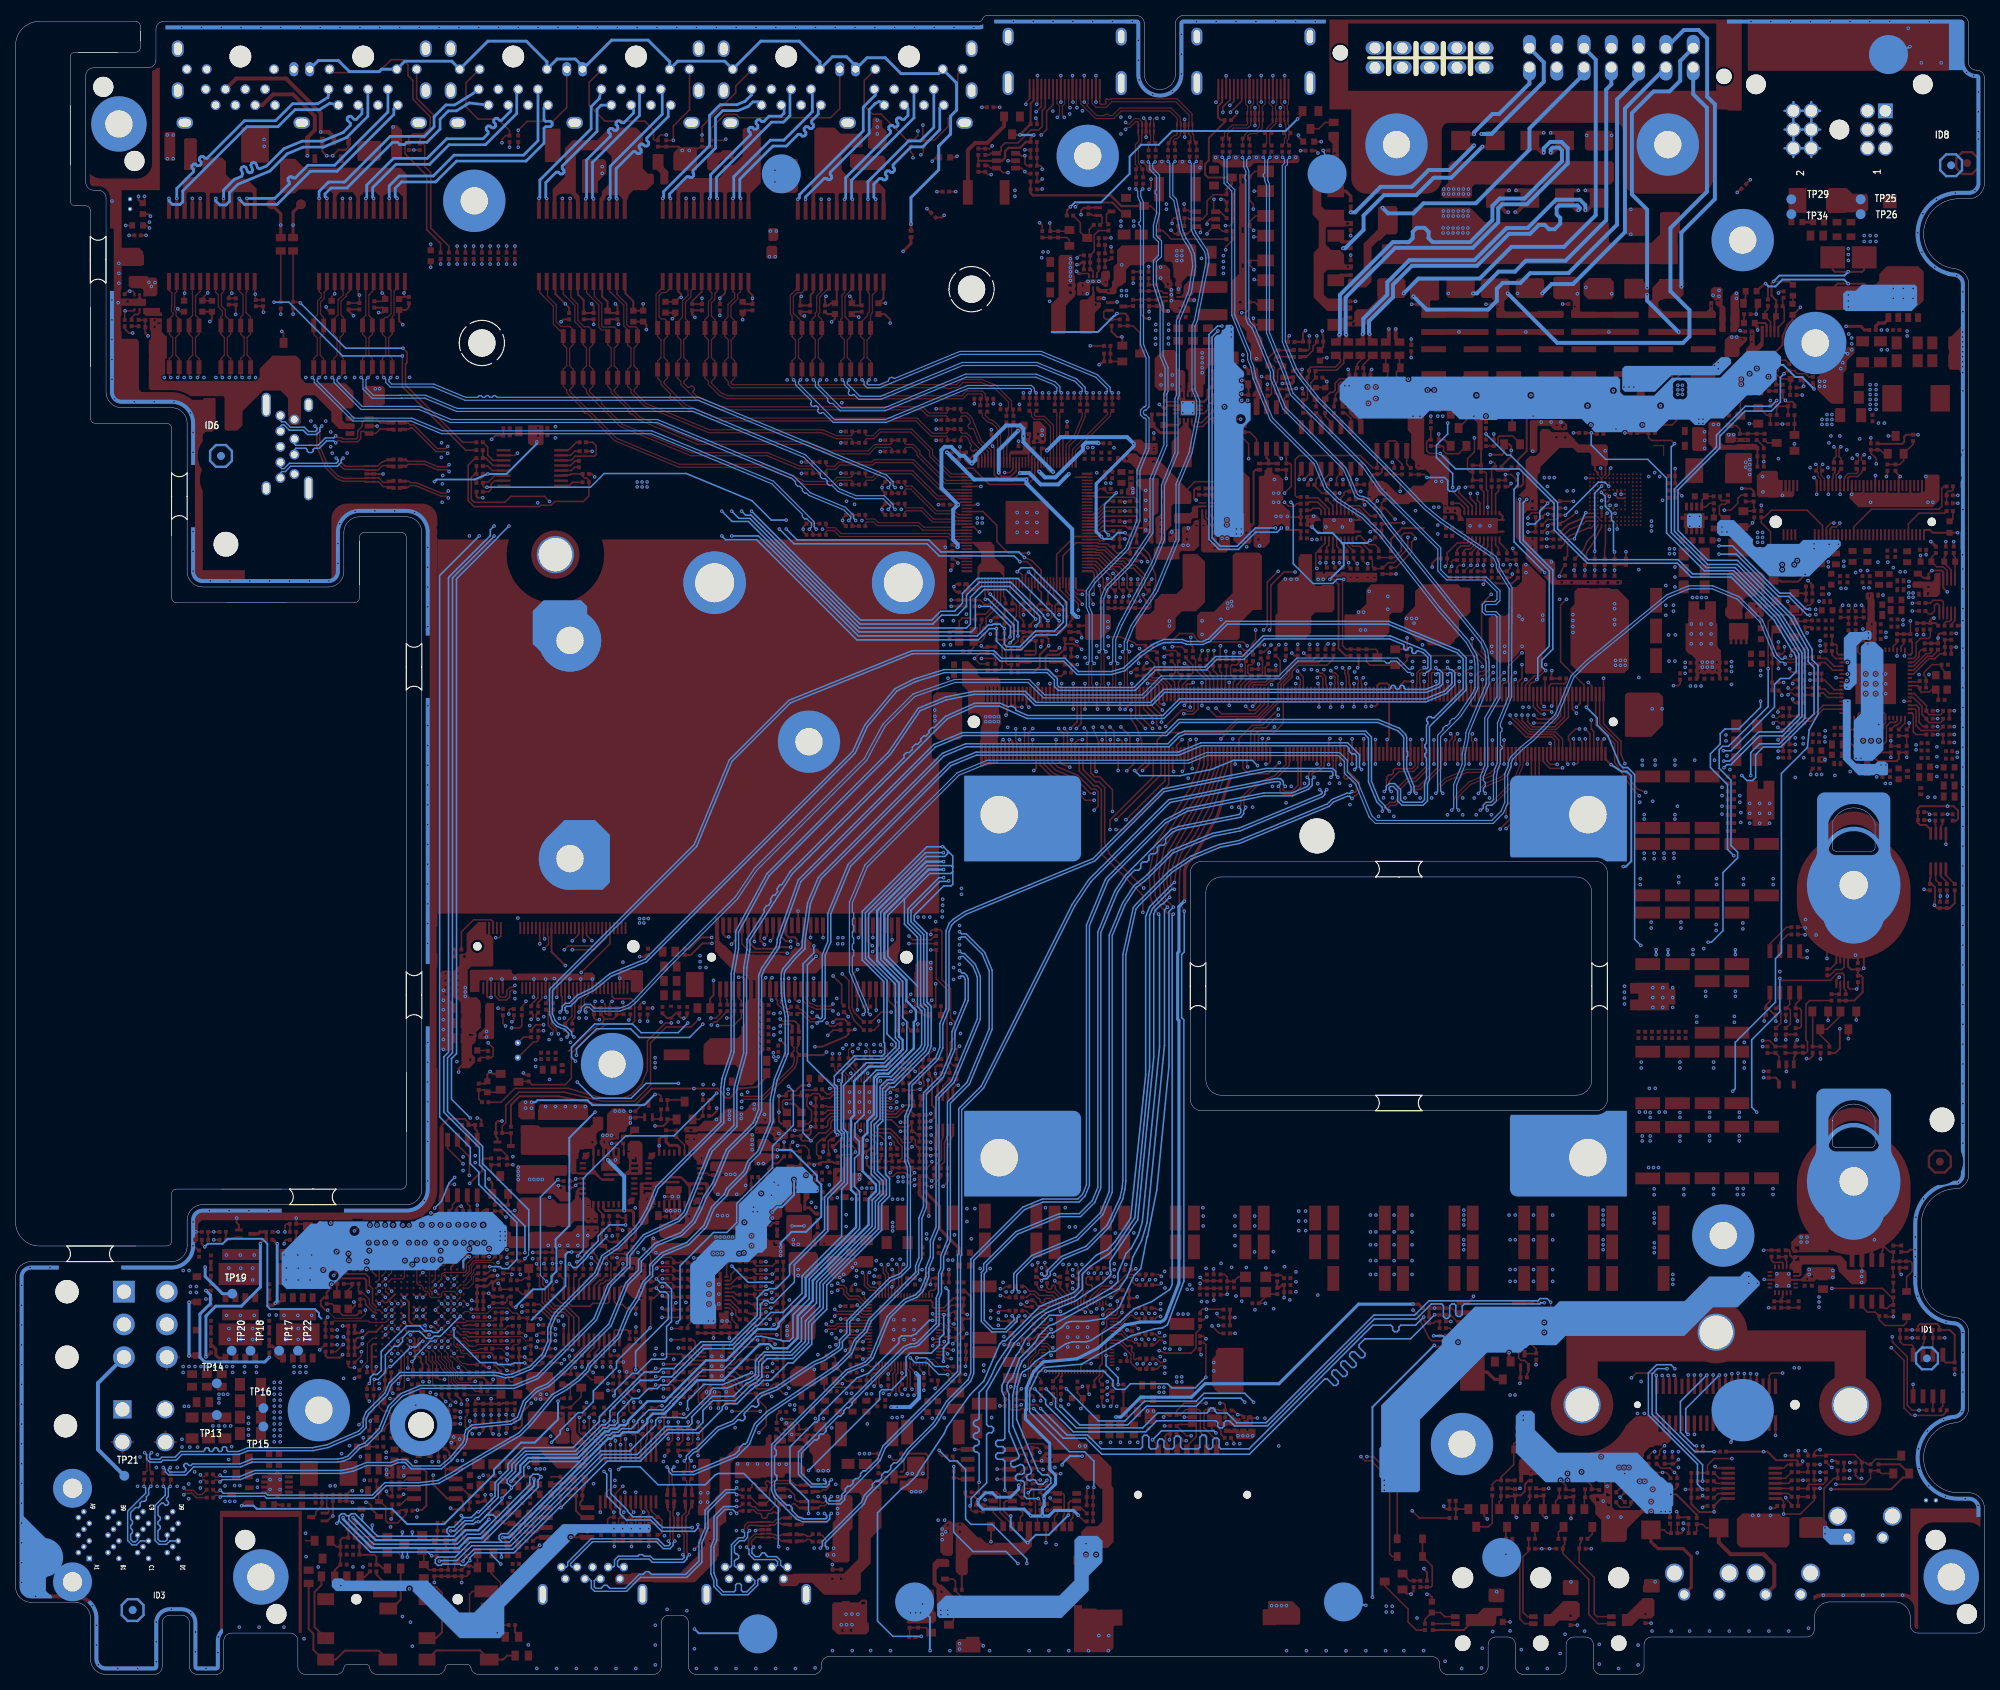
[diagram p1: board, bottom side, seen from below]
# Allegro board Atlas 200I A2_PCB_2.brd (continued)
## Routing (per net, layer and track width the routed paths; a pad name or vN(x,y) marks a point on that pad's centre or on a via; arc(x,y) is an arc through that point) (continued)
V_STBY_3V3: length 489.7
  TOP w0.203: R243.1 v1(5.99,121.59) ; R1627.1 84.18,152.93 v1(83.82,153.29) ; R241.1 v1(9.49,135.15)
  TOP w0.254: R9.2 212.75,40.89 212.5,40.64 210.95,40.64 v1(210.57,41.02) ; R2991.1 59.44,152.4 59.15,152.69 59.15,154.17 R2990.1 59.82,155.83 58.7,156.95 58.7,161.05 58.33,161.42 v1(57.87,161.42) ; R2716.2 v1(173.53,18.69) ; R2703.1 46.13,23.34 v1(46.74,22.73) 46.13,22.12 R2705.1 ; R3136.2 117.68,187.81 v1(117.22,188.26) ; v1(212.47,45.85) 212.75,45.57 R6.2 R8.2 R7.2 ; U2804.8 5.33,40.37 4.98,40.01 C2812.1 3.81,43.56 4.45,44.2 R2891.2 5.79,44.65 6.1,44.96 8.26,44.96 8.53,44.68 R2893.2 v1(9.27,44.2) R2892.2 ; D2408.1 110.39,187.38 111.83,188.82 116.03,188.82 v1(116.59,188.26) ; C13.1 193.9,47.88 v1(194.01,47.98) ; C13.1 C23.1 v1(194.06,46.86) ; C13.1 C14.1 193.29,48.92 C17.1 C16.1 192,49.81 191.49,50.32 C15.1 ; C22.1 208.53,41.91 v1(208.03,42.42) ; C22.1 C18.1 ; C22.1 C21.1 208.66,43.18 v1(208.03,43.18) 207.25,43.95 U3.R5 205.46,44.75 U3.P6 ; R2723.2 v1(174.5,32.51) ; R16.1 R5.2 195.73,57.15 v1(195.73,57.68) 195.73,57.94 195.96,58.17 R2803.2 ; R2749.1 3.8,98.94 4.44,98.3 R91.2 R90.2 6.04,98.3 v1(6.4,98.66) 6.4,99.12 6.34,99.18 6.34,100.99 6.75,101.4 C2713.1 6.98,102.17 6.89,102.26 U2704.8 ; R2715.2 v1(166.24,30.23) ; C3404.1 15.62,90.44 v1(15.47,90.59) 15.47,92.27 16.23,93.03 R3404.1 16.74,93.49 16.99,93.74 18.39,93.74 18.64,93.49 R3403.1 ; C3404.1 17.12,90.44 17.49,90.81 U10.8 ; C3404.1 R3423.2 15.82,89.63 15.62,89.42 15.62,87.52 16.7,86.44 R3424.2 R3405.1 ; C15.1 191.14,50.32 190.78,50.67 190.02,50.67 R3.2 ; C15.1 191.31,50.29 191.31,49.55 R26.1 ; R27.1 v1(189.48,43.81) R96.2 ; R282.1 81.93,130.7 82.83,131.6 82.83,139.85 83.46,140.49 v1(83.95,140.49) ; R3408.2 11.68,45.92 11.67,45.91 v1(11.67,45.89) 12.59,45.89 R3410.2 ; R1647.1 94.87,163.07 v1(94.49,163.45) ; v1(191.26,37.85) 191.26,37.59 191.52,37.34 R228.1 192,37.57 192.53,38.1 193.93,38.1 194.08,37.95 R4.2 ; R2719.2 v1(179.58,32.46) ; v1(237.49,172.08) 237.95,172.08 238.51,172.64 R2215.2 ; v1(15.71,51.73) U3402.2 15.71,54.9 C3402.2 R3406.2 ; 174.2,49.78 174.81,49.78 175.06,49.53 U1002.24 ; 206.83,40.77 206.83,38.99 C19.1 206.25,39.12 v1(206.25,39.47) ; 206.83,40.77 206.82,40.75 U3.R1 ; 206.83,40.77 206.83,42.14 206.62,42.35 U3.R3 ; R2803.2 R2830.2 ; R2803.2 193.9,58.65 193.8,58.75 R2805.1 192.96,58.75 192.66,59.05 192.66,59.31 192.41,59.56 192.02,59.56 ; R2809.2 189.61,54.61 v1(189.48,54.48) ; C1603.1 72.24,162.95 ; R2889.2 v1(25.48,83.79) ; U2805.8 27.51,86.33 28.02,85.83 C2811.1 27.74,85.45 26.92,84.63 R2887.2 v1(26.75,83.79) ; R3607.1 36.89,20.49 39.5,23.09 v1(40.21,23.09) ; R241.1 R239.1 R245.1 ; R1106.1 228.63,55.23 v1(228.24,54.85) ; v1(26.42,129.03) R2984.2 ; U3.A15 195.06,53.81 C20.1 ; C20.1 194.54,53.82 v1(194.31,53.59) ; C20.1 C24.1 195.96,52.96 196.66,52.26 U3.C15 ; 201.17,26.29 200.15,26.29 199.82,25.96 199.82,21.64 200.38,21.08 v1(200.97,21.08) 201.52,21.08 R1019.2 ; R3613.1 v1(17.27,25.15) ; R2829.2 189.38,45.72 v1(189.48,45.61) R35.1 190.22,45.51 R28.1 ; v1(126.61,25.05) U2803.8 124.49,25.05 123.11,26.43 C2813.1 ; U2801.8 193.29,69.72 193.57,70 C2801.1 R2804.2 194.41,70.76 194.89,71.25 197,71.25 197.87,70.38 197.87,69.93 ; R2718.2 v1(172.42,18.69) ; v1(87.5,164.97) 87.5,164.85 87.38,164.72 R1622.2 ; v1(195.33,34.67) 195.33,35.18 195.96,35.81 R227.1 ; 172.97,42.29 172.94,42.32 R1031.2 ; R1651.1 86.74,152.91 v1(86.36,153.29) ; 9.83,138.05 v1(9.7,138.18) ; R2722.2 v1(175.77,32.51) ; R3213.2 25.1,54.41 24.92,54.23 24.92,53.77 24.66,53.52 C3220.1 ; R36.1 182.6,39.98 v1(182.5,39.88) ; R3102.1 153.95,66.4 154.79,65.56 155.27,65.56 155.96,64.87 C3214.1 155.96,63.63 155.47,63.14 v1(155.22,63.14) ; v1(89.54,153.42) R1648.1 90.67,154.53 LB9.1 ; R2717.2 v1(164.97,30.23) ; C2711.1 169.33,32.77 169.34,32.75 169.34,30.91 169.42,30.84 ; 169.42,30.84 168.83,30.84 R2711.2 v1(168.78,30.23) ; 169.42,30.84 C2712.1 170.37,30.39 U2703.24 ; v1(133.55,62.61) 132.97,63.19 R2025.1 ; U3.E8 v1(198.66,46.75) U3.E9 ; R2704.1 v1(46.13,25.78) ; R1030.2 175.13,52.53 175.13,52.7 ; R21.2 120.94,27.36 ; R2818.1 191.52,31.11 v1(191.26,30.86) ; LB2506.1 210.02,12.16 v1(210.79,11.39) ; v1(88.09,199.54) 87.71,199.92 87.71,200.3 D1702.1 ; R1652.1 78.71,153.62 78.36,153.97 R1601.2 77.57,153.97 77.29,154.25 77.29,154.61 77.14,154.76 R1610.2 ; R2784.2 v1(40.01,28.57) ; R2888.2 24.21,84.37 v1(23.98,83.82) ; R2744.2 R2745.2 v1(171.3,18.69) ; R2713.2 v1(167.51,30.23) ; LB1704.1 v1(47.24,159.77) ; R1642.2 193.4,153.16 193.14,153.42 192.84,153.42 192.58,153.67 R1644.2 v1(191.93,154) ; R2712.2 v1(175.77,18.69) ; R97.2 186.44,40.36 186.84,40.36 v1(187.2,40.72) 187.25,40.77 R99.2 R38.2 R25.1 ; R1607.1 79.13,166.14 80.45,164.82 C1616.1 ; R2726.2 v1(173.23,32.51) ; R2721.2 v1(177.04,32.51) ; U3.D9 v1(197.86,47.55) U3.E10 ; LB2501.2 190.22,4.83 v1(190.73,5.33) ; R277.1 R33.1 64.55,157.19 ; v1(111.25,174.57) 110.19,174.57 109.88,174.27 R3125.2 ; R2743.2 v1(172.09,32.46) ; v1(21.84,164.9) 21.84,165.51 R3023.2 ; 174.14,38.81 R2725.2 R2724.2 ; U3.L9 v1(202.66,47.56) 203.06,47.95 U3.L10 ; R2720.2 v1(178.31,32.46) ; R3422.1 v1(40.32,20.89) ; R1032.2 174.55,40.08 v1(174.55,40.08) ; R3412.1 19.13,79.71 18.54,80.31 v1(18.54,82.82) ; R54.2 v1(181.18,54.18) ; R2714.2 v1(174.65,18.69) ; R2992.1 78.51,145.49 v1(78.79,145.49) ; R98.2 v1(189.48,42.8)
  TOP w0.305: R37.2 R99.2
  TOP w0.406: v1(94.87,167.77) 94.38,167.28 LB10.1
  ART03 w0.203: v1(191.26,37.85) 189.94,37.85 188.6,39.19 188.6,39.75 188.09,40.26 187.83,40.26
  ART03 w0.254: 142.16,62.38 142.01,62.23 136.82,62.23 135.17,63.88 134.75,63.88 133.55,62.68 v1(133.55,62.61) ; v1(94.87,167.77) 94.62,167.51 94.62,163.58 v1(94.49,163.45) ; v1(198.78,153.02) 200.23,154.47 200.23,164.64 v1(201.98,166.39) 203.27,167.68 233.09,167.68 v1(237.49,172.08) ; v1(26.42,129.03) 27.69,130.3 27.69,140.21 26.9,140.99 ; v1(25.48,83.79) 24,83.79 v1(23.98,83.82) ; 15.34,86.02 v1(18.54,82.82)
  ART04 w0.254: 192.79,53.11 193.83,53.11 v1(194.31,53.59) ; 192.79,53.11 192.76,53.14 192.76,54.33 191.9,55.2 191.9,55.58 193.36,57.05 195.1,57.05 v1(195.73,57.68) ; 192.79,53.11 191.26,53.11 189.89,54.48 v1(189.48,54.48) ; v1(18.54,82.82) 22.98,82.82 v1(23.98,83.82) ; 195.07,30.99 196.44,32.36 196.44,33.55 v1(195.33,34.67) ; v1(26.75,83.79) v1(25.48,83.79)
  ART04 w0.508: 91.82,168.78 92.84,167.77 v1(94.87,167.77)
  BOTTOM w0.254: v1(117.22,188.26) 116.64,188.84 113.29,188.84 109.63,192.51 109.63,194.72 108.12,196.23 105.91,196.23 104.14,197.99 89.64,197.99 v1(88.09,199.54) ; 119.63,172.21 113.69,172.21 111.65,174.25 111.58,174.25 v1(111.25,174.57) ; 195.07,52.2 195.07,53.09 194.56,53.59 v1(194.31,53.59) ; 82.33,145.14 82.17,144.98 82.17,142.26 v1(83.95,140.49) ; 82.33,145.14 79.14,145.14 v1(78.79,145.49) ; 82.33,145.14 83.62,146.43 85.47,146.43 v1(86.23,147.19) ; v1(185.65,158.11) 185.65,157.89 189.54,154 v1(191.93,154) 193.65,153.29 198.51,153.29 v1(198.78,153.02) ; v1(181.18,54.18) 181.66,54.18 181.98,53.86 181.98,49.82 186.33,45.47 ; v1(228.24,54.85) 227.85,55.24 225.93,55.24 225.3,55.88 220.85,55.88 220.22,55.24 220.22,47.24 219.84,46.86 214.1,46.86 213.59,46.35 213.59,45.95 213.28,45.64 ; v1(21.84,164.9) 23.38,166.43 24.24,166.43 25.79,167.98 27.1,167.98 27.15,167.92
  vias: v1(6.35,112.52) v1(7.24,112.52) v1(9.14,138.73) v1(9.14,138.18) v1(9.7,138.73) v1(15.75,51.05) v1(15.75,50.29) v1(17.22,115.82) v1(19.94,138.61) v1(20.45,117.35) v1(21.21,137.67) v1(36.09,161.04) v1(36.09,160.48) v1(36.63,161.04) v1(36.63,160.48) v1(40.91,20.89) v1(41.47,20.89) v1(42.23,11.87) v1(53.02,11.87) v1(59.14,33.19) v1(59.14,32.63) v1(62.55,10.6) v1(65.48,161.42) v1(69.6,153.03) v1(70.36,153.03) v1(72.39,161.39) v1(73.28,161.39) v1(81.47,165.3) v1(82.03,165.3) v1(86.02,148.59) v1(115.23,16.77) v1(120.9,27.4) v1(132.95,8.23) v1(132.95,7.67) v1(133.84,8.23) v1(133.84,7.67) v1(149.68,62.05) v1(154.71,62.76) v1(155.55,61.47) v1(157.35,59.36) v1(157.86,59.94) v1(157.91,59.36) v1(158.04,69.21) v1(158.04,68.58) v1(158.04,67.94) v1(158.04,67.31) v1(162.87,36.25) v1(162.99,45.34) v1(163.65,45.34) v1(163.88,36.25) v1(174.14,38.81) v1(182.12,40.39) v1(202.72,26.58) v1(202.72,25.48) v1(204.98,28.51) v1(204.98,27.81)
V_STBY_5V0: length 25.5
  TOP w0.254: R3104.1 152.54,63.33 v1(152.68,63.47) ; 94.23,147.32 93.98,147.32 93.73,147.57 93.73,154.29 93.47,154.54 LB8.1 ; R2817.1 v1(190.5,30.74) ; R238.1 v1(70.64,43.43) ; R3106.2 v1(95.25,165.15) ; R2207.1 135.76,28.32 135.52,28.08 135.52,25.13 135.64,25.02
  BOTTOM w0.254: v1(155.45,59.31) 154.81,59.94 154.23,59.94 152.65,61.52 152.65,63.45 v1(152.68,63.47) ; 69.09,43.05 69.47,43.43 v1(70.64,43.43)
  vias: v1(29.08,50.16) v1(30.23,51.05) v1(30.23,50.16) v1(34.14,168.3) v1(34.14,167.49) v1(34.62,167.92) v1(44.96,165.15) v1(45.59,165.15) v1(46.23,165.15) v1(76.96,24.89) v1(76.96,24.26) v1(76.96,23.62) v1(95.3,146.94) v1(95.3,146.3) v1(95.94,146.94) v1(95.94,146.3) v1(96.6,172.85) v1(96.6,172.21) v1(96.6,171.58) v1(104.9,188.62) v1(104.9,187.96) v1(124.33,190.37) v1(124.33,189.61) v1(136.47,23.44) v1(137.03,23.44) v1(137.59,23.44) v1(148.29,26.14) v1(148.92,26.14) v1(149.56,26.14) v1(155.45,58.55) v1(185.17,35.94) v1(185.17,35.31) v1(185.8,35.33) v1(192.53,25.55) v1(193.04,25.27) v1(234.63,178.55) v1(235.08,178.05) v1(235.4,178.57)
V_STBY_12V0: length 124.5
  TOP w0.203: R1012.1 169.72,74.19 169.93,74.4 v1(170.49,74.4) ; v1(95.38,161.04) R3110.2
  TOP w0.254: v1(107.11,173.94) 107.57,173.94 107.62,173.99 107.65,173.99 108.15,174.5 R3119.2 ; v1(211.71,51.18) 211.68,51.18 211.43,51.43 R1120.2 ; v1(10.67,51.31) 10.88,51.52 R3416.2 R3411.2 ; v1(189.61,30.94) 189.48,31.06 R2814.1 ; v1(209.04,56.9) 208.64,57.3 R1118.2 ; v1(194.26,62.99) 192.66,64.59 192.66,65.91 192.38,66.19 R712.1 ; R1112.2 v1(218.82,56.77)
  ART03 w0.254: 210.69,55.24 v1(209.04,56.9) 207.67,58.27 198.78,58.27 194.26,62.79 v1(194.26,62.99) ; 210.69,55.24 211.61,56.16 218.21,56.16 v1(218.82,56.77) ; 210.69,55.24 210.69,52.2 v1(211.71,51.18) 213.64,49.25 213.64,42.83 215.32,41.15 216,41.15 217.75,39.39 217.75,28.04 213.46,23.75 212.34,23.75 ; 200.84,20.19 v1(201.04,20.19)
  ART04 w0.254: v1(189.61,30.94) 189.61,25.53 190.5,24.64 190.5,23.11 192.08,21.54 195.66,21.54 197,20.19 v1(201.04,20.19) ; v1(103.35,177.72) 103.86,178.23 104.52,178.23 106.48,176.27 106.48,174.57 v1(107.11,173.94)
  BOTTOM w0.254: v1(186.33,73.41) 185.83,73.41 185.57,73.66 179.15,73.66 178.51,73.02 171.88,73.02 170.51,74.4 v1(170.49,74.4)
  vias: v1(19.56,161.62) v1(19.56,160.98) v1(19.56,160.35) v1(20.19,161.62) v1(20.19,160.98) v1(20.19,160.35) v1(20.83,160.98) v1(20.83,160.35) v1(28.45,146.49) v1(28.45,145.86) v1(28.45,145.22) v1(29.08,146.49) v1(29.08,145.86) v1(29.08,145.22) v1(30.1,155.83) v1(30.1,155.19) v1(30.1,154.56) v1(30.1,153.92) v1(30.61,155.5) v1(30.61,154.86) v1(38.74,165.38) v1(38.74,164.79) v1(38.74,164.21) v1(39.32,165.38) v1(39.32,164.79) v1(39.32,164.21) v1(75.95,8.74) v1(75.95,8) v1(76.71,8.76) v1(76.71,8) v1(100.32,169.53) v1(100.32,168.9) v1(100.32,168.26) v1(100.32,167.63) v1(100.32,166.99) v1(102.93,182.64) v1(102.93,182) v1(102.93,181.37) v1(103.57,182.64) v1(103.57,182) v1(103.57,181.37) v1(110.03,177.52) v1(110.03,176.86) v1(110.67,177.52) v1(110.67,176.86) v1(161.2,58.86) v1(161.84,58.86) v1(162.47,58.86) v1(171.51,152.97) v1(171.51,152.34) v1(172.15,152.97) v1(172.15,152.34) v1(172.78,152.97) v1(172.78,152.34) v1(186.33,72.64) v1(187.1,73.41) v1(187.1,72.64) v1(211.52,24.19) v1(212.15,24.19)
V_TEC_OUT: length 55.4
  TOP w0.203: v1(193.04,30.86) 192.91,30.86 192.53,31.24 R2823.1
  TOP w0.508: v1(230.25,40.87) 230.2,40.92 D1102.1 ; D1101.1 230.2,47.78 v1(230.25,47.73)
  ART03 w0.254: v1(193.04,30.86) 195.58,28.32 201.68,28.32 204.09,30.73 206.63,30.73 207.52,31.62 207.52,32.51 208.03,33.02 208.03,35.56 v1(210.44,37.97)
  ART04 w0.254: v1(210.44,37.97) 212.09,39.62 213.49,39.62 214,40.13 229.51,40.13 v1(230.25,40.87)
  BOTTOM w0.406: v1(230.25,40.87) v1(230.25,47.73)
V_TPM_3V3: length 46.5
  TOP w0.203: R183.1 R182.1 21.82,22.35 23.6,20.57 v1(25.76,20.57) C167.2 25.76,22.2 26.12,22.56 U17.14 ; R285.1 R287.1 ; C162.2 59.41,24.89 59.41,25.97
  TOP w0.254: R169.1 v1(17.27,27.18) ; v1(21.08,23.88) 21.12,23.84 R183.1 ; R285.1 v1(21.08,24.9)
  TOP w0.508: C162.2 59.41,25.81
  ART03 w0.254: v1(49.15,27.94) 45.59,27.94 41.4,23.75 39.62,23.75 37.97,22.1 27.28,22.1 v1(25.76,20.57) ; v1(17.27,27.18) 17.91,27.18 19.56,25.53 20.46,25.53 v1(21.08,24.9) v1(21.08,23.88)
V_VCC_1V8_EMMC: length 18.9
  TOP w0.127: U9.P5 U9.N4 U9.P3
  TOP w0.203: v1(47.37,148.96) 47.64,148.96 48.1,148.5 U9.C6
  TOP w0.254: U9.N4 U9.M4 ; U9.P3 49.6,154.19 49.94,154.53 49.94,155.57 49.96,155.6 ; C1805.2 C1806.2 C1814.2 ; 48.64,155.35 48.6,155.3 U9.P5
  ART04 w0.254: v1(55.54,142.71) 52.25,144.07 v1(47.37,148.96)
  vias: v1(34.11,160.35) v1(34.75,160.35) v1(48.64,156.97)
V_VCC_3V3: length 85.1
  TOP w0.254: 7.62,146.81 6.99,146.81 6.63,146.46 D701.1 v1(3.43,146.46) ; v1(22.99,141.1) 23.89,140.19 26.04,140.19 26.16,140.31 D2.1 ; v1(115.77,132.99) 115.77,133.35 116.15,133.72 C1430.1 116.19,133.73 LB1406.1 ; R1331.2 123.65,131.57 123.39,131.83 R1328.2 123.39,132.94 123.19,133.15 120.32,133.15 120.02,132.84 v1(120.02,131.95) 121.16,130.81 121.16,129.29 121.92,128.52 R1332.2 ; 26.92,144.27 27.28,143.92 R89.1 ; v1(8.51,159.03) R606.1 10.03,159.03 10.29,158.77 10.29,158.11 10.54,157.86 13.66,157.86 R604.1 ; R602.2 v1(3.4,150.24)
  ART03 w0.254: v1(115.77,132.99) 115.85,133.07 118.26,133.07 119.38,131.95 v1(120.02,131.95)
  ART04 w0.254: v1(115.77,132.99) 113.55,135.22 111.09,136.24 108.08,139.25 108.08,140.72 108.74,141.38 108.74,143.4 ; v1(158.12,56.26) v1(158.12,54.99) ; v1(8.51,159.03) 4.95,155.47 4.95,151.79 v1(3.4,150.24) 3.4,146.48 v1(3.43,146.46)
  BOTTOM w0.254: v1(154.38,54.81) 154.38,55.37 152.98,56.77 151.13,56.77 149.17,58.72 149.17,62.83 149.18,62.84 149.18,62.85 149.73,63.4 149.73,64.01 153.01,67.28 v1(154.79,67.28)
  vias: v1(18.73,144.97) v1(19.91,144.97) v1(21.84,145.03) v1(21.84,144.4) v1(33.02,146.56) v1(33.66,147.19) v1(33.66,146.56) v1(42.7,147.95) v1(42.7,147.32) v1(42.7,146.68) v1(55.17,153.53) v1(55.8,153.53) v1(56.44,153.53) v1(97.13,145.74) v1(97.76,145.74) v1(109.22,152.15) v1(109.22,151.61) v1(154.38,54.28) v1(154.38,53.75)
V_VCC_3V3_EMMC: length 9.8
  TOP w0.203: U9.F5 48.05,149.95 ; 48.05,149.95 48.1,149.9 U9.E6 ; 48.05,149.95 v1(48.01,149.99)
  TOP w0.254: U9.J10 46.54,151.45 46.6,151.4 ; 46.6,151.4 v1(46.61,151.38) ; 46.6,151.4 U9.K9
  ART04 w0.254: v1(48.01,149.99) v1(46.61,151.38) 42.04,151.38 v1(41.28,150.62)
V_VCC_AUDIO_5V0: length 8.7
  TOP w0.254: v1(185.31,16.57) 185.65,16.23 R2511.1
  ART03 w0.254: v1(185.31,16.57) 185.31,18.91 v1(189.1,22.71)
V_VCC_DISK_5V0:
  vias: v1(195.55,30.17) v1(196.32,30.45) v1(196.62,29.74) v1(205.87,37.34) v1(205.87,36.65) v1(225.3,35.94) v1(225.86,35.94) v1(226.42,35.94) v1(226.42,35.38) v1(226.42,34.82)
V_VCC_DISK_12V0: length 51.9
  TOP w0.254: v1(182.93,35.05) 182.55,35.43 R3306.2
  TOP w0.305: D3302.2 223.12,22.04 v1(223.52,21.64)
  BOTTOM w0.254: v1(223.52,21.64) 221.97,21.64 221.58,21.25 204.23,21.25 202.26,19.28 197.54,19.28 191.14,25.68 191.14,26.3 187.69,29.74 185.9,29.74 182.93,32.71 v1(182.93,35.05)
  vias: v1(218.59,24.99) v1(218.59,23.72) v1(219.86,24.99) v1(219.86,23.72) v1(221.49,24.89) v1(221.49,24) v1(222.63,32.97) v1(222.63,32.21) v1(222.63,31.44) v1(222.63,30.68) v1(222.63,29.92) v1(224.92,31.88) v1(225.68,31.88) v1(226.44,31.88) v1(227.2,31.88)
V_VCC_LED_3V3: length 5.1
  TOP w0.254: LED3601.1 66.77,5.69 R3608.1
V_VDD_3V3_PHY0: length 174
  TOP w0.203: U1201.30 144.06,69.82 v1(144.14,69.75) 144.21,69.75 144.46,70 U1201.31
  TOP w0.254: R178.1 150.27,65.51 v1(150.09,65.33) 149.91,65.51 R1210.1 149.15,65.71 148.39,65.71 R1212.1 148.08,65.76 147.7,65.76 147.57,65.63 R1221.1
  TOP w0.381: LB2.1 137.67,183.57 v1(138.68,182.55)
  ART03 w0.254: v1(146.53,163.14) 157.29,163.14 170.83,149.59 181.29,149.59 182.68,150.98 184.86,150.98 v1(185.55,150.29)
  ART04 w0.254: v1(144.14,69.75) 144.14,70.07 147.74,73.67 150.89,74.98 151.76,75.56 154.19,77.98 155,77.98 156.56,79.55 157.32,81.37 157.32,82.92 158.9,86.73 160.22,88.05 160.73,89.29 161.57,90.55 161.57,91.7 161.86,92.14 162.8,93.08 163.31,93.08 163.8,93.56 170.35,109.39 182.12,121.16 186.25,141.91 186.56,143.5 186.56,149.28 v1(185.55,150.29) ; v1(138.68,182.55) 138.68,176.71 142.93,172.47 142.93,171.45 147.85,166.52 147.85,164.46 v1(146.53,163.14)
  vias: v1(138.68,63.8) v1(138.68,63.22) v1(139.32,63.8) v1(139.32,63.22) v1(154.61,69.39)
V_VDD_3V3_PHY0_LED: length 123.3
  TOP w0.381: LB2.2 v1(137.67,186.05)
  BOTTOM w0.381: v1(137.67,186.05) 137.67,189.46 134.11,193.01 134.11,196.06 132.59,197.59 132.59,199.9 131.83,200.66 131.83,204.15 J1501.23 134.15,205.36 138.94,205.36 140.97,207.39 143.3,207.39 J1501.21 144.77,206.37 145.92,207.52 147.75,207.52 J1501.19 149.34,206.87 151.99,209.52 156.93,209.52 J1501.17 161.55,206.95 167.58,206.95 J1502.23 168.61,206.87 171.38,209.65 176.05,209.65 J1502.21 179.79,206.3 180.71,207.23 183.05,207.23 J1502.19 184.36,206.87 187,209.52 191.94,209.52 J1502.17 196.56,206.95 202.58,206.95 J1601.23 205.56,205.92 205.87,205.61 209.68,205.61 211.1,207.03 213.67,207.03 J1601.21
V_VDDI_EMMC: length 4.9
  TOP w0.254: C1813.1 54.32,146.6 53.39,147.53 51.16,148.45 U9.C1 U9.C2
VRT: length 67.9
  TOP w0.254: R1018.1 R1020.1 204.19,20.09 v1(204.34,19.94)
  ART03 w0.254: v1(204.34,19.94) 205.4,20.99 213.4,20.99 220.6,28.19 220.6,36.96 221.74,38.1 236.01,38.1 J903.3
  BOTTOM w0.508: TP21.1 241.94,28.85 241.94,37.37 J903.3
VRT_DET: length 27.7
  TOP w0.203: R1017.2 204.29,23.62 204.19,23.52 C1015.2
  TOP w0.254: v1(203.46,42.75) 203.06,43.15 U3.L4 ; C1015.2 204.6,22.83 204.85,23.09 204.85,23.42 v1(204.94,23.5)
  ART03 w0.178: v1(203.46,42.75) 205.7,40.51 207.77,40.51 v1(208.15,40.13)
  ART04 w0.178: v1(204.94,23.5) 204.94,23.61 205.89,24.56 205.89,27.55 208.41,30.07 208.41,30.56 207.52,31.44 207.52,32.72 208.53,33.74 208.53,37.42 208.29,37.66 208.29,38.28 208.43,38.42 208.43,39.85 v1(208.15,40.13)
XGND: length 1.3
  ART04 w0.254: v1(8.38,128.27) v1(7.11,128.27)
XTAL_IN_PHY0: length 9.4
  TOP w0.203: X1201.1 150.84,70.65 150.42,71.07 150.42,72.31 151.03,72.92 151.03,73.74 150.98,73.79 R1219.1 150.5,74.27 150.27,74.5 149.53,74.5 149.33,74.29 149.33,74.17 C1202.1 148.08,73.91 147.62,74.37 U1201.45
XTAL_OUT_PHY0: length 2.3
  TOP w0.203: U1201.46 147.73,74.77 148.08,74.42 148.44,74.42 R1220.1
$4N67725: length 5.3
  TOP w0.203: R402.1 107.94,128.14 ; 107.94,128.14 107.95,128.13 107.95,127.74 107.82,127.61 106.98,127.61 106.88,127.51 106.02,127.51 105.35,126.84 J3.188 ; 107.94,128.14 C176.1
$4N67726: length 7
  TOP w0.203: J3.186 104.85,126.85 105.84,127.84 106.71,127.84 106.96,128.08 C175.1 106.68,128.17 106.45,128.4 106.45,129.6 R403.1
$4N67727: length 5.3
  TOP w0.203: R404.1 105.94,130.13 C174.1 105.94,128.47 104.35,126.88 J3.184
$4N67728: length 4.9
  TOP w0.203: J3.182 103.85,127.27 104.29,127.71 C173.1 104.09,128.19 103.78,128.5 103.78,129.49 104.25,129.95 R405.1
$4N67729: length 4.8
  TOP w0.203: J3.180 103.35,127.31 102.95,127.71 C172.1 103.12,128.19 103.45,128.52 103.45,129.89 R406.1
$4N67779: length 5.7
  TOP w0.203: R408.1 95.57,129.84 95.76,129.65 95.76,129.64 95.89,129.51 96.52,129.51 96.67,129.36 96.67,128.24 96.42,127.99 C182.1 96.16,127.48 96.35,127.3 J3.152
$4N67780: length 4.9
  TOP w0.203: J3.150 95.85,126.96 95.3,127.51 C181.1 95.05,127.99 94.79,128.24 94.79,129.84 94.71,129.92 R409.1
$4N67781: length 5.7
  TOP w0.178: J3.148 95.35,126.87 94.49,127.74 94.36,127.74 C180.1
  TOP w0.203: C180.1 94.11,128.14 94.46,128.5 94.46,129.41 94.39,129.49 93.97,129.49 93.8,129.66 R410.1
$4N67782: length 6.2
  TOP w0.203: R411.1 92.58,130.1 92.58,128.37 92.81,128.14 C179.1 93.09,127.81 93.27,127.63 94.01,127.63 94.23,127.42 94.23,127.42 94.85,126.8 J3.146
$4N67783: length 6.4
  TOP w0.203: R412.1 92.25,129.25 92.25,128.29 91.95,127.99 C178.1 91.75,127.76 92.2,127.3 93.88,127.3 94.09,127.09 94.35,126.83 J3.144
$4N67784: length 8
  TOP w0.203: R413.1 90.32,130.1 90.32,128.19 90.53,127.99 C177.1 90.88,127.76 91.22,127.42 91.62,127.42 92.08,126.95 93.7,126.95 93.85,126.8 J3.142
$4N68414: length 151.2
  TOP w0.203: v1(79.96,27.94) 79.43,27.41 78.64,27.41 76.28,25.04 76.28,15.44 75.96,15.12 D18.2 ; v1(62.1,108.46) 60.83,109.74 60.83,111.23 57.6,114.46 J3.319
  ART04 w0.178: v1(62.1,108.46) 59.74,106.1 47.27,106.1 43.51,102.33 43.51,98.5 39.06,94.05 39.06,91.69 38.02,90.65 38.02,54.84 51.51,41.35 52.81,41.35 55.7,38.46 66.73,38.46 76.71,28.47 79.76,28.47 79.96,28.27 v1(79.96,27.94)
$4N68429: length 147.8
  TOP w0.203: v1(61.34,108.51) 60.33,109.52 60.33,111.02 57.1,114.25 J3.317 ; D19.2 75.31,24.92 78.33,27.94 v1(79.2,27.94)
  ART04 w0.178: v1(61.34,108.51) 59.49,106.65 47.04,106.65 42.95,102.56 42.95,98.73 38.51,94.28 38.51,91.92 37.47,90.88 37.47,54.61 51.28,40.79 52.58,40.79 55.47,37.9 66.5,37.9 76.45,27.94 v1(79.2,27.94)
$4N70341: length 5.8
  TOP w0.203: J3.178 102.85,126.94 102.08,127.71 C171.1 101.83,128.19 101.52,128.5 101.52,129.46 102.41,130.35 R407.1
$7N42484: length 2.5
  TOP w0.203: R1204.2 148.46,76.45 147.58,75.57 U1201.48
$7N42485: length 2.2
  TOP w0.203: R1235.2 139.9,74.95 140.08,75.13 140.5,75.13 140.85,74.77 U1201.15
$7N42486: length 2.8
  TOP w0.203: R1216.1 148.54,70.23 148.34,70.43 148.34,71.02 147.8,71.55 147.16,71.55 U1201.38
$7N42487: length 2.3
  TOP w0.203: U1201.39 148.04,71.97 148.9,71.12 R1201.1
$7N42488: length 2.1
  TOP w0.203: U1201.40 148.35,72.37 148.72,72.01 R1218.1
$7N42489: length 2
  TOP w0.203: U1201.41 148.34,72.77 148.46,72.9 R1217.1
$7N42494: length 4.2
  TOP w0.203: R1236.2 C1201.2 139.29,76.73 140.57,75.46 140.64,75.46 140.92,75.17 U1201.14
$7N42503: length 2
  TOP w0.203: U1201.34 145.66,69.5 145.77,69.39 145.77,68.81 R1215.2
$7N42505: length 27.8
  TOP w0.203: R1240.1 R1206.1 140.94,64.28 140.6,63.94 140.6,63.94 140.53,63.88 139.98,63.88 139.5,64.36 138.43,64.36 R1238.2 137.64,63.93 v1(137.21,64.36) 137.51,64.66 R1202.1 137.43,64.92 R1237.2 ; R1207.1 R1208.1 ; R1247.1 R1246.1
  TOP w0.254: R1247.1 135.33,76.82 134.98,76.46 134.98,73 134.62,72.64 134.62,71.5 v1(135.13,71) 135.21,70.92 R1209.1 ; R1208.1 v1(139.01,69.68)
  ART04 w0.254: v1(135.13,71) 135.98,70.14 138.55,70.14 v1(139.01,69.68) 139.01,66.17 v1(137.21,64.36)
$7N42508: length 7
  TOP w0.203: R1220.2 149.99,74.95 151.59,74.95 151.79,74.75 R1219.2 C1203.2 152.88,73.91 153.09,73.71 153.94,73.71 154.14,73.51 154.14,72.66 X1201.3
$7N63630: length 2.9
  TOP w0.155: R196.1 147.07,77.95 147.07,77.65 146.91,77.49 146.36,77.49 145.66,76.79 U1201.3
$7N63631: length 2.1
  TOP w0.155: R1317.1 144.78,77.85 144.46,77.53 U1201.6
$7N63632: length 2.3
  TOP w0.155: R190.1 145.69,78.21 145.17,77.69 145.16,77.69 144.84,77.37 144.84,76.27 U1201.5
$7N63633: length 2.6
  TOP w0.155: U1201.8 143.66,77.32 143.26,77.72 142.87,77.72 142.75,77.85 R191.1
$7N63634: length 2.1
  TOP w0.155: R192.1 143.66,77.87 144.04,77.48 144.04,76.27 U1201.7
$7N63635: length 3.2
  TOP w0.155: U1201.11 142.46,76.69 142.03,77.11 141.27,77.11 140.76,77.62 140.76,77.94 R193.1
$7N63636: length 3.2
  TOP w0.155: R194.1 141.14,78 141.14,77.78 141.43,77.5 142.19,77.5 142.86,76.83 U1201.10
$7N63637: length 3
  TOP w0.155: U1201.2 146.06,76.65 146.52,77.11 147.07,77.11 147.45,77.49 147.45,77.88 R195.1
$8N44565: length 12
  TOP w0.203: U6.20 121.38,154.48 121.22,154.32 v1(121.22,154.3) ; R1373.2 v1(113.61,157.94)
  BOTTOM w0.508: v1(121.22,154.3) 120.47,153.56 119.15,153.56 115.62,157.08 115.62,157.64 115.25,158.01 113.69,158.01 v1(113.61,157.94)
$8N44574: length 3.9
  TOP w0.203: R1377.2 112.83,149.22 114.07,147.98 U6.48
$8N44575: length 4.1
  TOP w0.203: R1376.2 112.57,150.49 114.29,148.78 U6.46
$8N44576: length 7.3
  TOP w0.203: R1375.2 108.74,149.5 108.97,149.73 112.83,149.73 114.18,148.38 U6.47
$8N44577: length 3.5
  TOP w0.203: R1381.2 113.21,146.68 113.52,146.38 U6.52
$8N44578: length 5.8
  TOP w0.203: R1380.2 109.83,147.07 110.08,147.32 113.08,147.32 113.62,146.78 U6.51
$8N44579: length 3.7
  TOP w0.203: R1379.2 113.08,147.95 113.86,147.18 U6.50
$8N44580: length 7.3
  TOP w0.203: U6.49 113.97,147.58 112.95,148.59 108.84,148.59 108.74,148.49 R1378.2
$8N44589: length 5.9
  TOP w0.203: C1319.1 130.1,131.27 129.63,131.73 X1301.3 128.74,132.44 128.27,132.92 R1326.2 128.54,133.4 128.82,133.68 128.82,134.63 128.6,134.85 R1310.1
$8N44608: length 6.3
  TOP w0.203: R1374.2 109.8,142.89 110.07,143.15 111.28,143.15 112.76,144.63 113.7,144.63 113.84,144.78 U6.56
$8N44609: length 10.3
  TOP w0.203: U6.13 124.18,154.38 124.89,153.67 126.04,153.67 126.42,154.05 v1(126.42,154.18)
  BOTTOM w0.508: v1(126.42,154.18) 126.42,157.05 v1(123.95,159.51)
$8N114121: length 1.7
  TOP w0.203: U1301.3 118.18,130.31 R1329.2
$8N114122: length 1.7
  TOP w0.203: R1334.2 118.2,129.81 U1301.4
$8N114763: length 1.4
  TOP w0.203: U1301.6 123.73,130.31 R1330.1
$8N114764: length 1.4
  TOP w0.203: R1333.1 123.71,129.81 U1301.5
$8N118897: length 4.6
  TOP w0.203: R1328.1 C1321.2 121.67,131.32 ; U1301.7 121.8,130.81 121.67,130.94 121.67,131.32 ; 121.67,131.32 121.68,131.31 U1301.8
$9N34271: length 5.3
  TOP w0.203: R1823.1 R1801.1 C1801.1 R1802.1 31.37,159.77 31.82,160.21 Q1801.1
$9N34273: length 4.1
  TOP w0.203: C1816.1 34.47,164.34 34.24,164.11 R1803.2
$9N34274: length 3.1
  TOP w0.203: C1803.1 R1805.2 27.94,161.54 28.88,162.48 Q1804.1
$9N34275: length 3.6
  TOP w0.203: Q1804.3 31.29,163.25 32.16,164.11 R1824.2
$9N34280: length 6.9
  TOP w0.203: v1(49.1,150.59) 49.07,150.59 48.71,150.95 U9.H5 ; R1807.2 54.2,147.84 53.99,147.84 52.78,148.65 v1(52.32,149.1)
  ART04 w0.178: v1(49.1,150.59) 52.06,149.36 v1(52.32,149.1)
$9N34284: length 9.9
  TOP w0.203: v1(49.12,151.64) 48.81,151.95 U9.K5 ; R1809.2 v1(47.44,143.99)
  BOTTOM w0.203: v1(49.12,151.64) 48.62,151.13 48.62,149.86 47.83,149.07 47.83,148.1 47.57,147.85 47.57,144.13 v1(47.44,143.99)
$9N34299: length 11.7
  TOP w0.152: v1(48.18,152.43) 48.1,152.51 U9.M6
  TOP w0.203: v1(53.74,148.7) 53.76,148.72 R1808.2 54.71,148.46 54.71,148.34 54.89,148.16 56.03,148.16 C1811.2
  BOTTOM w0.203: v1(48.18,152.43) 48.68,152.93 49.5,152.93 v1(53.74,148.7)
$9N34313: length 1.5
  TOP w0.203: C1814.1 28.3,157.5 29.13,158.34 R1801.2
$9N34316: length 2.5
  TOP w0.203: Q1803.1 C1815.1 R1821.2
$9N34317: length 1.7
  TOP w0.203: R1823.2 27.84,157.99 Q1803.3
$9N48264: length 10.4
  TOP w0.152: U9.M5 48.6,152.93 v1(49.09,152.43)
  TOP w0.203: R114.2 v1(49.98,144.08)
  BOTTOM w0.203: v1(49.98,144.08) 49.98,151.55 v1(49.09,152.43)
$11N32664: length 6.2
  TOP w0.203: Q1901.1 132.25,12.23 131.96,11.94 C1904.2 131.96,10.7 131.11,9.84 C1905.2 131.11,8.82 R1914.2 R1913.1
$11N32665: length 1.5
  TOP w0.203: Q1902.3 132.22,6.96 R1913.2
$11N32666: length 4.2
  TOP w0.203: R1915.2 137.85,4.84 R1916.1 137.36,5.99 137.36,6 C1908.1 135.72,6 Q1902.1
$12N62032: length 2.7
  TOP w0.203: U2001.2 67.49,45.14 68.49,46.13 R2002.2
$12N62036: length 2.5
  TOP w0.203: U2001.3 67.74,46.41 68.33,46.99 R2034.2
$12N62037: length 1.8
  TOP w0.203: U2001.6 R2001.1
$12N65908: length 2.5
  TOP w0.203: R2003.1 68.55,44.42 68,43.87 U2001.1
$12N67333: length 1.8
  TOP w0.203: U2001.5 R2004.2
$12N67903: length 1.8
  TOP w0.203: U2001.7 R2035.2
$12N120728: length 2.8
  TOP w0.203: R2005.1 143.13,39.75 142.88,39.5 142.37,39.5 142.16,39.71 U2002.57
$12N120770: length 2.8
  TOP w0.203: R2006.2 132.49,47.35 133.21,46.62 U2002.23
$12N120777: length 1
  TOP w0.203: R2005.2 R2007.1
$12N135137: length 5.8
  TOP w0.203: R2012.2 144.27,37.62 R2010.1 145.95,37.62 146.56,38.23 146.56,38.74 X2001.1 147.36,40.57 C2022.1
$12N135139: length 6.2
  TOP w0.203: X2001.3 148.81,36.67 148.46,36.32 C2023.1 147.98,36.55 147.7,36.83 145.8,36.83 145.77,36.8 R2010.2 144.68,36.8 144.65,36.83 R2011.2
$12N159486: length 5
  TOP w0.203: R2025.2 132.97,67.6 132.29,69.24 U2003.5
$12N159487: length 5.2
  TOP w0.203: U2003.6 132.94,69.23 133.38,68.17 133.38,65.76 133.84,65.3 R2028.1
$12N159488: length 5.4
  TOP w0.203: R2029.1 134.73,65.09 133.78,66.04 133.78,68.41 133.59,68.88 U2003.7
$12N159489: length 2.3
  TOP w0.203: U2003.2 133.59,75.47 R2026.2
$12N159490: length 2.4
  TOP w0.203: R2027.2 131.83,76.3 132.94,75.19 U2003.3
$12N201123: length 2
  TOP w0.203: R201.1 134.49,49.53 134.75,49.28 135.13,49.28 135.36,49.05 U2002.18
$12N201711: length 4.8
  TOP w0.127: U2002.41 135.76,40.26 135.61,40.41 134.77,40.41 133.35,38.99
  TOP w0.203: 133.35,38.99 132.74,38.99 R298.1
$12N202119: length 1.8
  TOP w0.127: U2002.27 133.79,45.02 132.87,44.09 R336.1
$13N103140: length 1.6
  TOP w0.203: R2201.1 154.89,33.27 R2202.2
$13N103141: length 1.3
  TOP w0.203: R2202.1 154.23,30.78 U2201.2
$13N103147: length 0.9
  TOP w0.203: R2205.1 R2206.2
$13N103148: length 1.2
  TOP w0.203: R2206.1 141.57,25.83 141.08,25.35 U2202.2
$13N120945: length 0.9
  TOP w0.203: R2213.1 R2214.2
$13N120946: length 2
  TOP w0.203: U2203.2 236.6,174.68 236.8,174.47 237.2,174.47 237.62,174.05 R2214.1
$13N183700: length 2.3
  TOP w0.188: R2229.1 151.94,17.98 T2208.1 151.23,17.93 151.01,17.72 150.56,17.72 C123.2
$13N183701: length 2.3
  TOP w0.188: R2228.1 151.94,17.07 T2208.4 151.23,17.12 151.01,17.33 150.67,17.33 150.36,17.03 C124.2
$13N184734: length 2.4
  TOP w0.188: R2223.1 166.59,23.03 T2205.1 166.59,24.03 166.43,24.2 166.43,24.77 C127.2
$13N184735: length 2.4
  TOP w0.188: R2222.1 165.78,23.03 T2205.4 165.78,24.05 166.05,24.32 166.05,24.88 C128.2
$13N189150: length 21.6
  TOP w0.188: v1(160.02,21.54) 159.59,21.54 R253.2
  BOTTOM w0.188: v1(160.02,21.54) 160.02,21.54 161.67,21.54 162.94,20.27 162.94,17.33 163.32,16.41 163.32,12.9 162.96,12.02 162.96,11.28 161.89,10.21 158.57,10.21 157.31,11.47 157.31,12.08 157.12,12.26 J2202.2
$13N189151: length 21.6
  TOP w0.188: v1(160.02,20.65) 159.7,20.97 R254.2
  BOTTOM w0.188: v1(160.02,20.65) 160.53,21.16 161.51,21.16 162.56,20.11 162.56,17.26 162.94,16.33 162.94,12.97 162.58,12.1 162.58,11.44 161.73,10.59 160.36,10.59 160.17,10.78 160.17,11.47 159.98,11.66 159.6,11.66 159.42,11.47 159.42,10.78 159.23,10.59 158.73,10.59 157.69,11.63 157.69,12.02 157.93,12.26 J2202.3
$13N189902: length 30
  TOP w0.188: R251.2 159.76,23.69 v1(160.02,23.95)
  BOTTOM w0.188: J2201.2 178.03,12.26 178.28,12.02 178.28,11.23 178.1,11.05 177.41,11.05 177.22,11.24 177.22,11.24 177.04,11.43 176.66,11.43 176.47,11.24 176.47,11.24 176.28,11.05 174.29,11.05 172.52,12.83 172.05,12.83 171.7,13.18 171.3,13.18 170.94,12.83 166.58,12.83 164.87,14.54 164.87,16.91 164.08,18.81 164.08,21.06 161.44,23.7 160.27,23.7 v1(160.02,23.95)
$13N189903: length 30.1
  TOP w0.188: v1(160.02,23.06) 160,23.05 159.51,23.05 R252.2
  BOTTOM w0.188: J2201.3 178.96,12.26 178.66,11.97 178.66,11.08 178.26,10.67 174.13,10.67 172.36,12.45 166.42,12.45 164.48,14.38 164.48,16.83 163.7,18.74 163.7,20.9 161.28,23.32 160.27,23.32 v1(160.02,23.06)
$14N18861: length 12.6
  TOP w0.508: RT1.1 130.38,195.53 129.44,196.47 127.89,196.47 125.73,198.63 D2307.1
$16N25599: length 10.3
  TOP w0.203: J2501.5 193.9,10.65 194.28,10.26 194.28,7.98 192.63,6.32 R2505.1
$16N25600: length 2.4
  TOP w0.203: R2501.2 196.19,16.26 R2502.2 195.91,16.03 C2505.2
$16N25603: length 2.4
  TOP w0.203: C2508.2 198.48,16 R2507.2 197.33,17.07 R2506.2
$16N25607: length 1.7
  TOP w0.254: LB2501.1 188,4.99 188.44,5.44 R2505.2
$16N25609: length 7
  TOP w0.203: J2501.4 190.75,8.45 190.3,8.91 190.3,11.76 191.56,13.02 LB2503.1
$16N25610: length 10.7
  TOP w0.254: LB2502.1 200.14,11.9 199.47,11.23 198.55,11.23 197.82,10.49 197.82,5.41 198.58,4.65 J2501.3
$16N25611: length 12.5
  TOP w0.254: LB2504.1 189.45,2.41 189.9,1.96 190.04,1.96 190.1,1.9 J2501.2 192.93,3.07 198.56,3.07 J2501.1
$16N31377: length 1.8
  TOP w0.254: C2517.2 186.12,23.62 185.78,23.62 R2513.1
$16N31378: length 4.8
  TOP w0.254: U4.2 179.76,20.12 180.62,20.98 C2516.1 181.03,22.94 181.1,23.01 R2512.2
$16N31379: length 3.5
  TOP w0.254: R2514.1 181.58,23.8 R2512.1 182.52,23.82 C2519.1 183.19,23.72 R2513.2
$16N31380: length 4.6
  TOP w0.254: C2518.1 179.51,24.09 R2514.2 C2516.2 179.81,22.38 180.09,22.1 180.09,21.72 179.76,21.39 U4.1
$16N31381: length 3.2
  TOP w0.254: C2518.2 181.48,25.07 181.99,24.56 182.6,24.56 R2515.1 183.16,24.54 183.26,24.43 183.82,24.43 R2516.1
$16N31382: length 1.9
  TOP w0.254: U4.3 179.12,18.9 177.62,18.9 R2517.2
$16N31384: length 1.8
  TOP w0.254: U4.5 185.65,17.58 185.95,17.27 186,17.27 R2518.2
$16N31385: length 2.6
  TOP w0.254: R2520.1 189.33,21.36 189.26,21.28 R2519.1 C2522.2
$16N31386: length 1.6
  TOP w0.254: R2522.1 188.02,16.98 C2524.2
$16N31387: length 3.2
  TOP w0.254: R2523.1 R2521.1 188.35,19.18 188.53,19.35 R2522.2 189.81,19.35 189.92,19.46 189.97,19.46 C2523.1
$16N31388: length 5
  TOP w0.254: C2522.1 187.17,20.08 187.17,19.33 R2521.2 186.92,19.07 C2525.2 186.18,19.58 185.65,20.12 U4.7
$16N31389: length 2.8
  TOP w0.254: R2523.2 187,18.26 C2525.1 185.66,18.26 185.08,18.85 U4.6
$16N33792: length 3
  TOP w0.254: R2526.2 206.22,12.8 205.13,11.7 J2502.5
$16N33793: length 8.8
  TOP w0.203: C2532.1 C2527.1 ; C2530.1 211.35,16.38 D2504.2
  TOP w0.254: LB2507.1 211.57,13.37 C2532.1 ; R2525.2 209.83,18.57 C2526.1 210.57,17.53 210.85,17.25 C2530.1 C2527.1
$16N33794: length 1.6
  TOP w0.254: LB2506.2 208.24,12.5 207.75,12.5 R2526.1
$16N33796: length 19.8
  TOP w0.254: LB2509.1 214.91,5.82 214.3,5.22 214.3,3.16 213.05,1.9 J2502.1 211.43,1.9 210.29,3.05 205.9,3.05 J2502.2
$16N33797: length 12.7
  TOP w0.203: D2503.1 208.89,17.65 C2526.2
  TOP w0.254: LB2508.1 205.38,13.59 205.87,14.07 C2529.1 206.22,15.08 206.48,15.33 208.37,15.33 C2531.1 C2528.1 208.41,16.92 C2526.2 209.02,18.44 R2524.2
$16N33798: length 8.9
  TOP w0.254: J2502.3 214.16,6.08 214.16,10.57 213.27,11.47 LB2507.2
$16N33799: length 6.1
  TOP w0.254: J2502.4 204.25,8.45 203.11,9.59 LB2508.2
$17N28562: length 8.2
  TOP w0.203: U301.6 9.09,128.33 7.12,130.29 6.36,130.29 5.73,130.93 C301.2 R263.1 5.07,132.71 R262.2 R267.2
$17N28564: length 6.6
  TOP w0.203: R329.2 5.31,122.43 5.64,122.1 7.09,122.1 7.44,122.45 R266.2 8,123.16 8,124.21 9.12,125.33 U301.12
$17N28570: length 4.3
  TOP w0.203: U301.25 14.19,121.56 R265.2 14.81,121.22 15.05,120.98 15.05,119.59 R328.2
$17N31574: length 5.3
  TOP w0.203: U301.62 11.19,130.67 v1(11.21,130.66) ; R246.2 v1(8.66,133.37)
  ART04 w0.178: v1(8.66,133.37) 11.21,130.82 v1(11.21,130.66)
$17N31614: length 1.4
  TOP w0.203: U301.61 11.69,131.89 11.2,132.38 R245.2
$17N31654: length 6.7
  TOP w0.203: U301.15 8.94,123.83 8.76,123.65 8.76,121.74 8.1,121.08 5.82,121.08 R244.2
$17N31694: length 4.3
  TOP w0.203: R243.2 7.82,121.59 8.38,122.15 8.38,124 8.71,124.33 U301.14
$17N31774: length 5.7
  TOP w0.203: R242.2 6.95,133.11 7.16,132.89 8.2,132.89 8.76,132.33 8.76,130.68 9.12,130.33 U301.2
$17N31814: length 2.1
  TOP w0.203: U301.1 9.47,130.83 9.27,131.03 9.27,132.43 R241.2
$17N31854: length 5.2
  TOP w0.203: U301.64 10.19,130.72 v1(10.26,130.66) ; R240.2 v1(7.8,133.37)
  ART04 w0.178: v1(10.26,130.66) 9.96,130.95 9.96,131.22 v1(7.8,133.37)
$17N31894: length 1.3
  TOP w0.203: R239.2 10.35,132.2 10.69,131.85 U301.63
$20N51827: length 4.3
  TOP w0.381: R3105.2 152.62,62.48 153.01,62.86 153.77,62.86 154.86,63.96 Q3101.3
$20N51829: length 5.5
  TOP w0.356: 151.27,60.79 Q3102.4 150.7,59.87
  TOP w0.381: 150.7,59.87 149.94,59.11 R3307.1 ; R3104.2 R3105.1 151.1,61.89 151.07,61.85 C3101.2 151.07,61 151.27,60.79
$20N51832: length 2.4
  TOP w0.203: R3103.2 151.84,66.22 C3102.2 151.87,65.24 Q3101.1
$20N62168: length 5
  TOP w0.254: U3101.7 100.08,163.26 99.57,163.77
  TOP w0.381: R3115.2 R3107.1 C3109.1 99.19,165.15 99.57,164.77 99.57,163.77
$20N62169: length 7.8
  TOP w0.203: R3109.2 R3110.1 96.89,160.67 97.03,160.52 98.8,160.52 98.88,160.6 C3113.1 99.26,161.09 100.28,160.07 101.36,160.07 101.66,160.37 U3101.10
$20N62170: length 6
  TOP w0.381: R3113.2 106.78,160.36 C3110.2 105.7,159.28 102.49,159.28
$20N62171: length 3
  TOP w0.203: U3101.9 100.86,160.58 100.41,160.58 C3112.1
$20N62172: length 2.6
  TOP w0.254: U3101.13 103.16,160.49 103.38,160.27 103.84,160.27
  TOP w0.381: C3110.1 103.84,160.27
$20N62173: length 1.4
  TOP w0.203: R3114.2 104.99,163.26 U3101.1
$20N62174: length 3.6
  TOP w0.203: U3101.8 100.09,161.76 99.57,162.28 99.57,162.84 99.29,163.12 C3104.1 R3108.1
$20N62175: length 0.9
  TOP w0.381: C3107.1 R3113.1
$20N62176: length 2.2
  TOP w0.203: R3108.2 C3114.1 C3103.1
$20N62177: length 2.2
  TOP w0.203: R3107.2 C3109.2 R3106.1
$20N62178: length 1.6
  TOP w0.203: R3115.1 97.87,167.18 R3112.1
$20N62179: length 1
  TOP w0.203: R3112.2 R3111.1
$20N137111: length 6.8
  TOP w0.254: U3102.4 105.17,176.21 105.41,175.97
  TOP w0.508: v1(104.67,174.9) 105.16,174.9 105.41,175.16 105.41,175.97 ; C3121.1 v1(101.35,176.3)
  ART04 w0.508: v1(101.35,176.3) 102.74,174.9 v1(104.67,174.9)
$20N137112: length 1
  TOP w0.203: R3121.2 R3120.2
$20N137115: length 0.8
  TOP w0.203: R3121.1 R3122.1
$20N137116: length 3.4
  TOP w0.203: U3102.6 105.25,177.21 105.51,177.47 C3120.1 R3117.1 R3122.2
$20N137117: length 1.9
  TOP w0.203: R3116.1 R3117.2 C3120.2
$20N137120: length 1.3
  TOP w0.203: Q3103.3 109.73,175.49 109.68,175.54 R134.1
$20N155997: length 3.5
  TOP w0.203: Q3105.1 C3132.1 R3137.1 R3123.2
$20N155998: length 5.6
  TOP w0.203: R3124.1 R3125.1 109.21,173.02 108.28,172.08 Q3105.3
$20N155999: length 3.7
  TOP w0.203: Q3103.1 112.75,174.99 112.95,174.78 112.95,174.12 112.67,173.83 C3133.1 R3124.2
$20N181723: length 8.3
  TOP w0.203: 116.01,179.71 114.97,179.71 114.83,179.57 U3103.4
  TOP w0.381: 116.01,179.71 116.16,179.71 v1(116.43,179.98)
  TOP w0.508: C3135.1 v1(112.93,176.53)
  ART03 w0.508: v1(112.93,176.53) 114.25,177.85 115.52,177.85 116.03,178.36 116.03,179.58 v1(116.43,179.98)
$20N181724: length 0.9
  TOP w0.203: R3132.1 R3131.2
$20N181725: length 1.1
  TOP w0.203: R3131.1 R3130.1
$20N181726: length 3.1
  TOP w0.203: U3103.6 113.83,179.77 113.59,180.01 C3134.1 R3127.1 R3130.2
$20N181727: length 1.9
  TOP w0.203: C3134.2 R3127.2 112.22,181.41 R3126.1
$20N181729: length 7.8
  TOP w0.203: R133.2 113.61,185.22 114.17,184.66 114.17,182.55 R3129.1 R3128.2 C3144.1 114.53,180.24 114.33,180.03 U3103.5
$20N181730: length 7.1
  TOP w0.203: R3129.2 116.03,182.04 v1(116.36,181.71)
  ART03 w0.178: v1(116.36,181.71) 111.53,181.71 v1(110.64,180.82)
$20N182986: length 4.4
  TOP w0.203: R3134.2 R3138.1 C3146.1 117.68,184.33 117.35,184 Q3106.1
$20N182987: length 5.7
  TOP w0.203: R3135.1 114.81,185.37 114.81,184.53 Q3106.3 115.19,184.28 115.95,185.04 115.95,186.23 R3136.1
$20N182988: length 3
  TOP w0.203: R3135.2 113.16,186.21 113.16,186.92 113.41,187.17 Q3104.1 114.4,187.17 114.55,187.32 114.91,187.32
$20N206297: length 2.2
  TOP w0.203: Q3104.3 112.23,187.67 112.6,187.3 112.6,186.28 R133.1
$20N206729: length 4.4
  TOP w0.203: U3102.5 105.77,176.71 C3130.1 R3118.2 R3119.1 R134.2
$20N212013: length 3
  TOP w0.381: R186.1 150.01,56.17 C3314.2
  BOTTOM w0.203: v1(152.91,57.53) v1(151.38,57.53)
  vias: v1(106.55,33.78) v1(107.32,33.78) v1(152.12,55.17) v1(152.76,55.75) v1(152.76,55.17)
$20N224028: length 0.9
  TOP w0.381: R3307.2 149.66,57.37 C3314.1
$46N78710: length 11.6
  TOP w0.203: v1(18.54,147.7) 18.54,147.65 19,147.19 19.55,147.19 19.76,146.99 J601.50 ; v1(12.57,153.67) 12.45,153.8 R56.1
  ART04 w0.178: v1(12.57,153.67) 12.57,153.67 18.54,147.7 v1(18.54,147.7)
$46N78948: length 16.4
  TOP w0.203: R57.1 5.21,152.4 5.46,152.15 5.46,149.86 5.84,149.48 14.48,149.48 16.76,147.2 J601.38
$47N12417: length 3.3
  TOP w0.203: R702.1 R712.2 191.52,64.52 190.93,63.93 Q702.3
$47N12418: length 2.9
  TOP w0.203: R702.2 C713.1 189.48,66.55 190.23,67.29 Q701.1
$47N12419: length 2.3
  TOP w0.203: Q702.1 189.33,60.78 189.33,60.78 C714.1 R714.2
$47N12435: length 15.4
  TOP w0.203: R704.1 144.95,83.89 145.62,85.5 145.62,89 v1(146.48,89.86)
  TOP w0.254: J701.14 144.15,94.77 v1(144.4,94.52)
  ART04 w0.178: v1(144.4,94.52) 146.48,92.44 v1(146.48,89.86)
$47N12436: length 14.3
  TOP w0.203: v1(144.53,90.42) 145.21,89.74 145.21,85.58 144.94,84.92 R705.1
  TOP w0.254: J701.12 143.35,94.2 v1(142.62,93.47)
  ART03 w0.178: v1(142.62,93.47) 143.64,92.46 143.64,91.31 v1(144.53,90.42)
$47N12437: length 12.7
  TOP w0.203: 138.38,85.72 138.38,86.54 137.69,87.22 v1(137.69,87.25)
  TOP w0.254: J701.10 v1(142.55,94.52)
  ART03 w0.178: v1(137.69,87.25) 141.61,91.16 141.61,93.57 v1(142.55,94.52)
$47N22092: length 1.1
  TOP w0.203: D1.2 R30.2
$47N42209: length 3.6
  TOP w0.203: C722.2 153.32,85.39 153.63,85.39 154.39,86.15 154.39,86.53 154.15,86.77 J701.31
$47N42210: length 4.2
  TOP w0.203: C723.2 153.35,85 153.8,85 154.79,85.99 154.79,86.46 154.95,86.62 J701.33
$47N53979: length 29
  TOP w0.203: v1(137.92,94.72) 137.44,94.23 135.13,94.23 134.65,94.72 R52.1
  TOP w0.254: J701.32 154.55,94.88 153.72,94.06 v1(153.1,94.06)
  ART04 w0.178: v1(153.1,94.06) 152.99,94.16 152.01,94.16 151.49,93.64 151.49,93.11 148.13,89.75 148.13,89.41 147.85,89.13 147.02,89.13 146.22,89.47 146.01,89.67 146.01,92.24 143.93,94.32 143.93,94.34 142.9,95.37 138.57,95.37 v1(137.92,94.72)
$47N53980: length 28.3
  TOP w0.203: R53.1 v1(137.92,93.75)
  TOP w0.254: J701.30 153.75,94.95 153.37,94.56 152.58,94.56 152.32,94.31 152.32,93.81 v1(152.16,93.64)
  ART04 w0.178: v1(137.92,93.75) 139.16,94.99 142.74,94.99 143.55,94.18 143.55,94.16 145.63,92.09 145.63,89.51 146,89.14 146.95,88.75 148.01,88.75 148.51,89.25 148.51,89.6 152.16,93.24 v1(152.16,93.64)
$47N73755: length 2.1
  TOP w0.203: J701.45 159.75,86.75 159.41,86.41 R101.2
$47N73822: length 2.1
  TOP w0.203: R102.2 160.32,86.38 160.55,86.61 J701.47
$47N73889: length 2.1
  TOP w0.203: J701.49 161.35,86.66 161.22,86.53 R105.2
$47N73956: length 2
  TOP w0.203: R106.2 162.13,86.63 162.15,86.66 J701.51
$47N81118: length 5.7
  TOP w0.203: R60.1 139.52,85.42 140.55,86.45 J701.5
$47N81388: length 6.2
  TOP w0.203: J701.3 139.75,86.49 139.07,85.8 139.07,84.58 138.05,83.57 138.05,83.01 R82.1
$47N82024: length 9.3
  TOP w0.254: J701.46 160.15,94.24 160.36,94.03 160.36,94 v1(160.68,93.68) ; v1(163.2,93.78) 164.41,93.78 165.91,92.28 R247.1
  ART03 w0.178: v1(160.68,93.68) 162.51,93.68 162.61,93.78 v1(163.2,93.78)
$47N85605: length 18.6
  TOP w0.254: v1(147.68,83.66) 147.29,84.05 146.18,84.05 145.67,83.54 R32.1 ; J701.8 141.75,93.56 v1(142.6,92.71)
  ART04 w0.254: v1(147.68,83.66) 147.68,84.09 148.51,84.92 148.51,86.86 147.86,87.5 145.55,88.46 142.6,91.42 v1(142.6,92.71)
$47N85919: length 22.3
  TOP w0.203: J701.44 159.35,93.71 158.27,92.63 153.64,92.63 v1(153.52,92.51) ; R48.1 147.12,83.46 147.41,83.18 148.04,83.18 v1(148.44,83.58)
  ART04 w0.178: v1(148.44,83.58) 148.44,84.16 149.28,84.99 149.28,89.1 149.68,89.5 149.68,89.5 152.51,92.33 153.16,92.33 153.34,92.51 v1(153.52,92.51)
$48N878: length 2.3
  TOP w0.203: U2701.6 39.65,23.74 39.4,24 R2702.1
$48N879: length 1
  TOP w0.203: R2701.1 40.38,24.24 41.2,24.24 U2701.5
$48N883: length 4.3
  TOP w0.203: U2701.1 44.67,22.74 R2705.2 45.31,21.74 45.59,21.46 46.74,21.46 47.22,21.95 R2707.1
$48N884: length 3.9
  TOP w0.203: R2706.1 46.66,23.93 45.64,23.93 45.31,23.6 R2703.2 45.19,23.24 U2701.2
$48N885: length 4.9
  TOP w0.203: R2708.1 46.61,24.38 45.59,24.38 45.31,24.66 R2704.2 44.96,24.99 44.76,24.79 44.76,23.95 44.55,23.74 U2701.3
$48N77079: length 2.8
  TOP w0.203: R2709.1 170.94,30.35 171.02,30.28 U2703.23
$48N77769: length 5.6
  TOP w0.203: U2703.22 171.67,30.01 171.5,30.17 171.5,32.82 R2710.1
$48N193018: length 28.5
  TOP w0.203: R2777.1 v1(21.08,26.92)
  TOP w0.254: J2701.32 v1(33.19,38.4)
  ART03 w0.178: v1(33.19,38.4) 33.19,38.72 32.78,39.13 28.89,39.13 28.35,38.59 28.35,37.6 28.55,37.39 29.38,37.39 29.59,37.18 29.59,36.89 29.38,36.68 28.55,36.68 28.35,36.47 28.35,35 28.02,34.67 27.72,34.67 27.48,34.91 27.19,34.91 26.98,34.7 26.98,34.41 27.22,34.17 27.22,33.87 27.01,33.66 26.72,33.66 26.48,33.9 26.18,33.9 25.97,33.69 25.97,33.4 26.21,33.16 26.21,32.87 26,32.66 25.71,32.66 25.47,32.9 25.18,32.9 24.97,32.69 24.97,32.39 25.21,32.15 25.21,31.86 25,31.65 24.7,31.65 24.46,31.89 24.17,31.89 23.96,31.68 23.96,31.39 24.2,31.15 24.2,30.85 22.23,28.88 22.23,28.07 v1(21.08,26.92)
$48N195194: length 31.1
  TOP w0.203: v1(25.48,22.68) 25.48,22.53 24.71,21.77 R2776.1
  TOP w0.254: J2701.34 v1(31.59,38.63)
  ART03 w0.178: v1(25.48,22.68) 24.08,22.68 22.73,24.03 22.73,25.76 24.38,27.41 24.38,29.81 27.19,32.62 27.49,32.62 27.94,32.17 28.23,32.17 28.44,32.38 28.44,32.67 27.99,33.12 27.99,33.42 28.2,33.63 28.49,33.63 28.94,33.17 29.24,33.17 29.45,33.38 29.45,33.68 28.99,34.13 28.99,34.42 29.2,34.63 29.5,34.63 29.95,34.18 30.24,34.18 30.45,34.39 30.45,34.68 30,35.14 30,35.43 30.21,35.64 30.5,35.64 30.96,35.19 31.25,35.19 31.46,35.39 31.46,35.69 31.01,36.14 31.01,36.44 31.59,37.02 v1(31.59,38.63)
$48N196898: length 14.7
  TOP w0.203: J2701.36 v1(29.99,38.58) ; R2782.1 v1(23.85,28.7)
  ART03 w0.178: v1(29.99,38.58) 29.99,35.96 23.85,29.82 v1(23.85,28.7)
$48N218401: length 2.4
  TOP w0.203: R2749.2 4.94,102.53 U2704.5
$48N218402: length 2.3
  TOP w0.203: U2704.6 5.59,102.4 4.82,101.64 R2752.1
$48N218403: length 2.2
  TOP w0.203: R2753.1 6.24,101.93 U2704.7
$48N218404: length 1.7
  TOP w0.203: R2750.2 6.3,109.04 6.24,108.98 U2704.2
$48N218405: length 1.7
  TOP w0.203: U2704.3 5.59,108.84 5.38,109.05 R2751.2
$48N306521: length 13.7
  TOP w0.203: R2778.1 v1(36.93,29.31)
  TOP w0.254: J2701.29 v1(35.59,38.4)
  BOTTOM w0.203: v1(36.93,29.31) 37.24,29.31 38.99,31.06 38.99,35.01 v1(35.59,38.4)
$48N306854: length 28.3
  TOP w0.203: R2779.1 v1(21.08,25.93)
  TOP w0.254: J2701.27 v1(37.19,38.4)
  ART03 w0.178: v1(37.19,38.4) 36.09,39.51 28.73,39.51 27.91,38.69 27.91,36.58 21.81,30.47 21.81,28.46 20.6,27.25 20.6,26.42 v1(21.08,25.93)
$48N317514: length 12.5
  TOP w0.203: R2783.1 v1(41.02,28.57)
  TOP w0.254: J2701.24 39.59,38.15 v1(39.8,38.36)
  ART03 w0.178: v1(41.02,28.57) 39.8,29.8 v1(39.8,38.36)
$48N323981: length 12.8
  TOP w0.203: v1(42.29,28.57) 42.55,28.57 43.05,28.07 R94.1
  TOP w0.254: J2701.22 41.19,38.22 v1(41.33,38.35)
  ART03 w0.178: v1(42.29,28.57) 42.29,29.34 41.33,30.3 v1(41.33,38.35)
$48N324314: length 12.6
  TOP w0.203: v1(41.02,29.34) 41.66,28.7 41.66,28.22 R95.1
  TOP w0.254: J2701.23 40.39,38.18 v1(40.56,38.35)
  ART03 w0.178: v1(41.02,29.34) 40.56,29.79 v1(40.56,38.35)
$48N350896: length 1
  TOP w0.305: C162.1 R248.2
$48N350897: length 3.8
  TOP w0.203: C137.1 R250.2 ; C137.1 R255.2 ; C137.1 Q2.1
$48N350898: length 5.8
  TOP w0.203: Q2.3 63.63,18.92 63.12,19.43 R256.2
$48N350899: length 9.6
  TOP w0.203: R256.1 63.12,24.38 62.61,24.89 R248.1 62,25.29 60.36,26.92 Q3.1 60.36,29.59 59.97,29.99 R249.1 C136.1
$48N361351: length 2.3
  TOP w0.203: U17.8 25.74,26.46 25.27,26.92 R167.1
$48N361353: length 2.1
  TOP w0.203: U17.2 34.16,23.21 R173.2
$48N361355: length 1.9
  TOP w0.203: R171.2 34.57,23.86 U17.3
$48N361356: length 2.1
  TOP w0.203: U17.12 24.73,23.86 R180.1
$48N361357: length 2.3
  TOP w0.203: R181.1 25.14,23.21 U17.13
$48N361360: length 2.1
  TOP w0.203: R170.2 34.01,25.16 U17.5
$48N361361: length 2
  TOP w0.203: R72.2 34.42,24.51 U17.4
$48N361364: length 2.4
  TOP w0.203: R175.1 25.51,25.16 U17.10
$48N361367: length 2.3
  TOP w0.203: R219.1 25.1,24.51 U17.11
$49N882: length 2.1
  TOP w0.203: R1604.1 77.34,163.88 76.63,163.17 U1603.6
$49N883: length 2.1
  TOP w0.203: U1603.7 75.36,162.95 74.6,163.71 R1608.1
$49N884: length 2.4
  TOP w0.203: U1603.1 74.09,155.26 R1603.2
$49N885: length 5.4
  TOP w0.203: LB1601.1 75.03,167.82 74.89,167.68 R1605.2 75.41,167.09 R1606.1 C1602.1 R1608.2
$49N886: length 5.3
  TOP w0.203: LB1602.1 76.78,167.82 76.75,167.78 R1605.1 76.53,167.4 R1607.2 C1601.2 R1604.2
$49N888: length 6.1
  TOP w0.203: R1602.2 74.68,155.24 75.36,155.93 U1603.2 75.34,157 75.34,158.04 75.54,158.24 76.38,158.24 76.63,157.99 U1603.3
$49N2996: length 2.6
  TOP w0.203: C1612.1 180.8,156.92 181.33,156.39 U1601.2
$49N2997: length 28.5
  TOP w0.203: R1646.2 193.55,156.03 194.46,155.12 194.46,150.58 193.69,149.81 185.35,149.81 185.17,149.99 183.82,149.99 183.34,150.47 179.68,150.47 178.97,151.18 R1645.2 178.97,153.16 179.27,153.47 179.53,153.47 179.78,153.72 C1613.1 181.26,154 181.38,153.87 182.46,153.87 U1601.6
$49N2998: length 7.4
  TOP w0.203: U1601.3 181.27,155.74 180.72,156.29 178.25,156.29 178.05,156.49 178.05,157.62 178.49,158.06 C1605.1
$49N2999: length 2.5
  TOP w0.203: C1614.1 180.8,154.86 181.22,154.44 U1601.5
$49N3000: length 4.2
  TOP w0.203: U1601.14 191.27,155.74 191.95,156.41 191.95,157.43 R1615.1
$49N3001: length 4.1
  TOP w0.203: U1601.13 191.26,155.09 192.2,156.03 R1646.1 R113.1
$49N3003: length 40.3
  TOP w0.203: v1(215.98,175.93) 216.09,176.05 C1606.2 LB1603.1 ; v1(202.82,170.13) 202.31,169.62 202.31,168.27 202.49,168.1 202.49,165.4 195.15,158.06 R1615.2
  BOTTOM w0.203: v1(202.82,170.13) 210.17,170.13 v1(215.98,175.93)
$49N3004: length 43.6
  TOP w0.203: v1(219.35,176.03) 219.34,176.05 C1607.2 LB1604.1 ; R113.2 193.41,157.03 194.75,157.03 202.9,165.18 v1(202.9,169.14)
  BOTTOM w0.203: v1(202.9,169.14) 210.55,169.14 217.45,176.03 v1(219.35,176.03)
$49N3011: length 2.1
  TOP w0.203: R1623.1 85.06,161.19 U1602.10
$49N3012: length 2.6
  TOP w0.203: R1624.1 86.92,161.85 86.33,161.26 U1602.9
$49N3013: length 2.2
  TOP w0.203: U1602.12 82.52,160.57 83.41,161.45 R1618.1
$49N3014: length 2.1
  TOP w0.203: R1617.1 84.56,161.39 83.79,160.63 U1602.11
$49N3015: length 2
  TOP w0.203: R1625.2 81.31,153.14 81.25,153.19 U1602.2
$49N3016: length 2.2
  TOP w0.203: U1602.3 82.52,154.09 83.08,153.53 R1626.2
$49N3017: length 2.5
  TOP w0.203: U1602.4 83.79,154.2 84.99,153.01 R1627.2
$49N3019: length 10.7
  TOP w0.203: LB1608.1 81.76,169.23 82.17,168.82 82.17,168.21 83.07,167.31 85.71,167.31 R1613.2 85.88,167.15 85.88,166.52 C1609.1 86.41,165.68 86.41,164.28 R1621.2 85.7,163.56 R1623.2
$49N3020: length 10.8
  TOP w0.203: LB1607.1 82.59,168.65 82.59,168.36 83.22,167.73 86.37,167.73 86.59,167.51 86.59,167.25 R1613.1 86.61,166.75 86.82,166.54 C1608.1 86.82,165.88 86.82,165.88 86.82,163.68 87.02,163.47 R1622.1 R1624.2
$49N3021: length 10.1
  TOP w0.203: LB1606.1 79.7,167.97 79.7,167.65 R1612.2 79.55,167.5 C1611.1 79.55,166.51 79.84,166.22 80.25,166.22 80.68,165.79 82.55,165.79 82.86,165.48 82.86,164.58 83.24,164.2 R1619.1 83.24,163.3 83.41,163.12 R1618.2
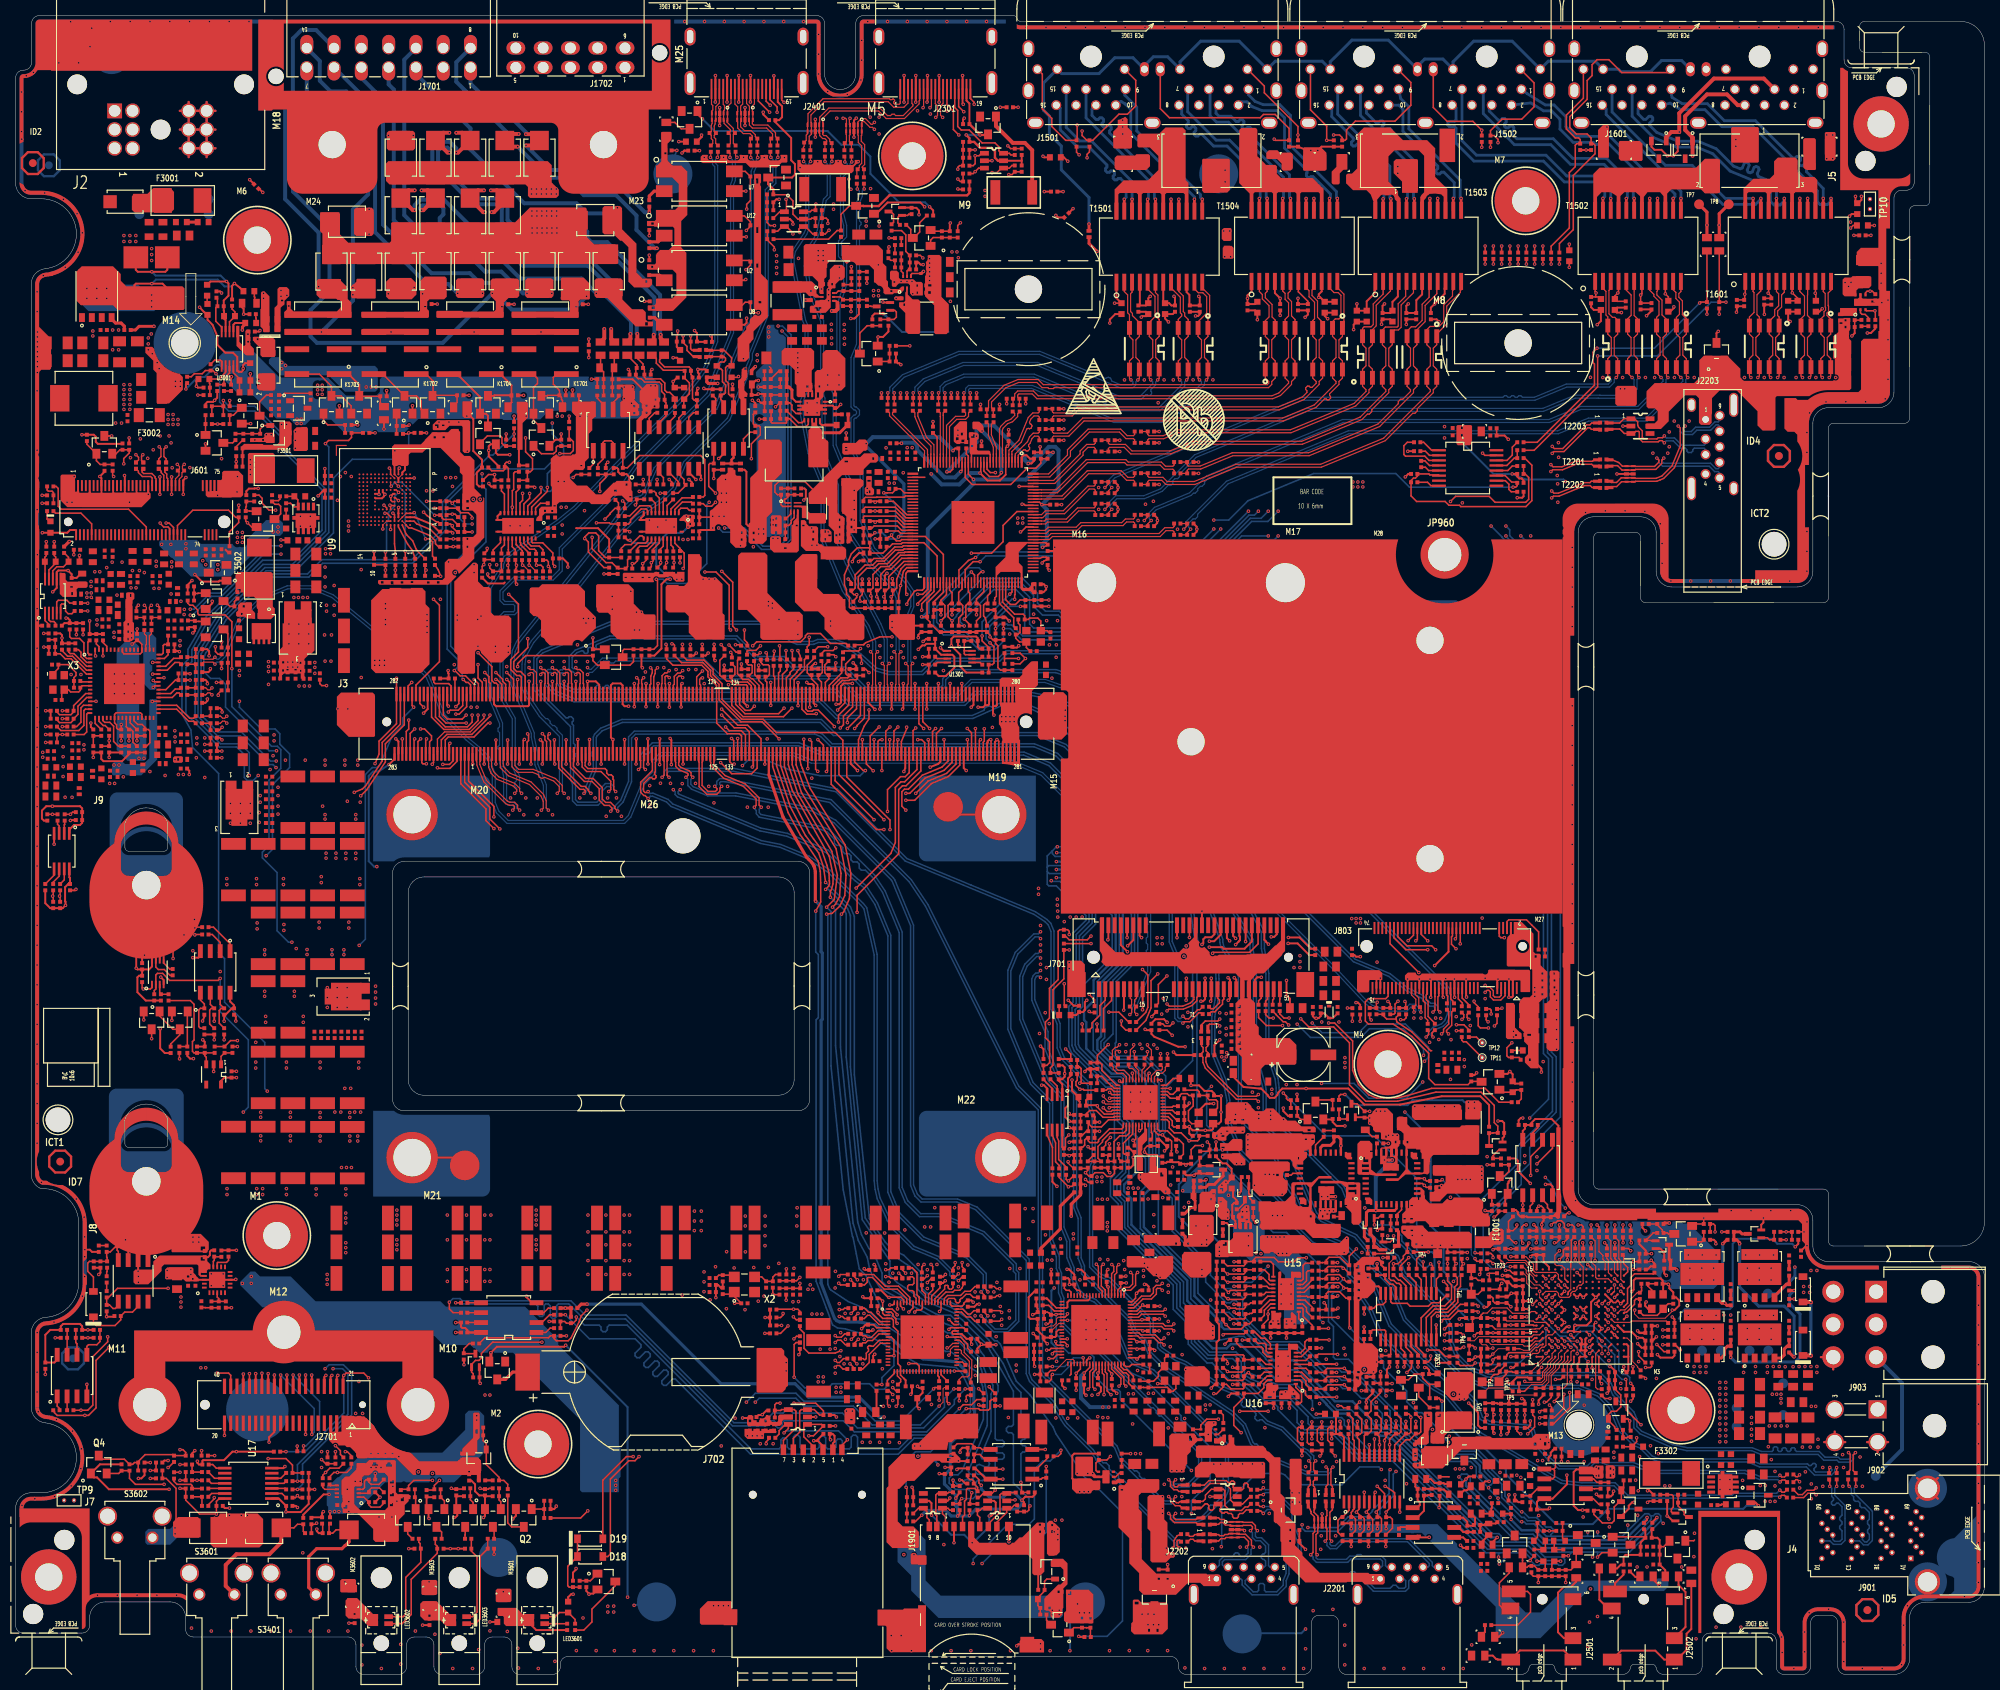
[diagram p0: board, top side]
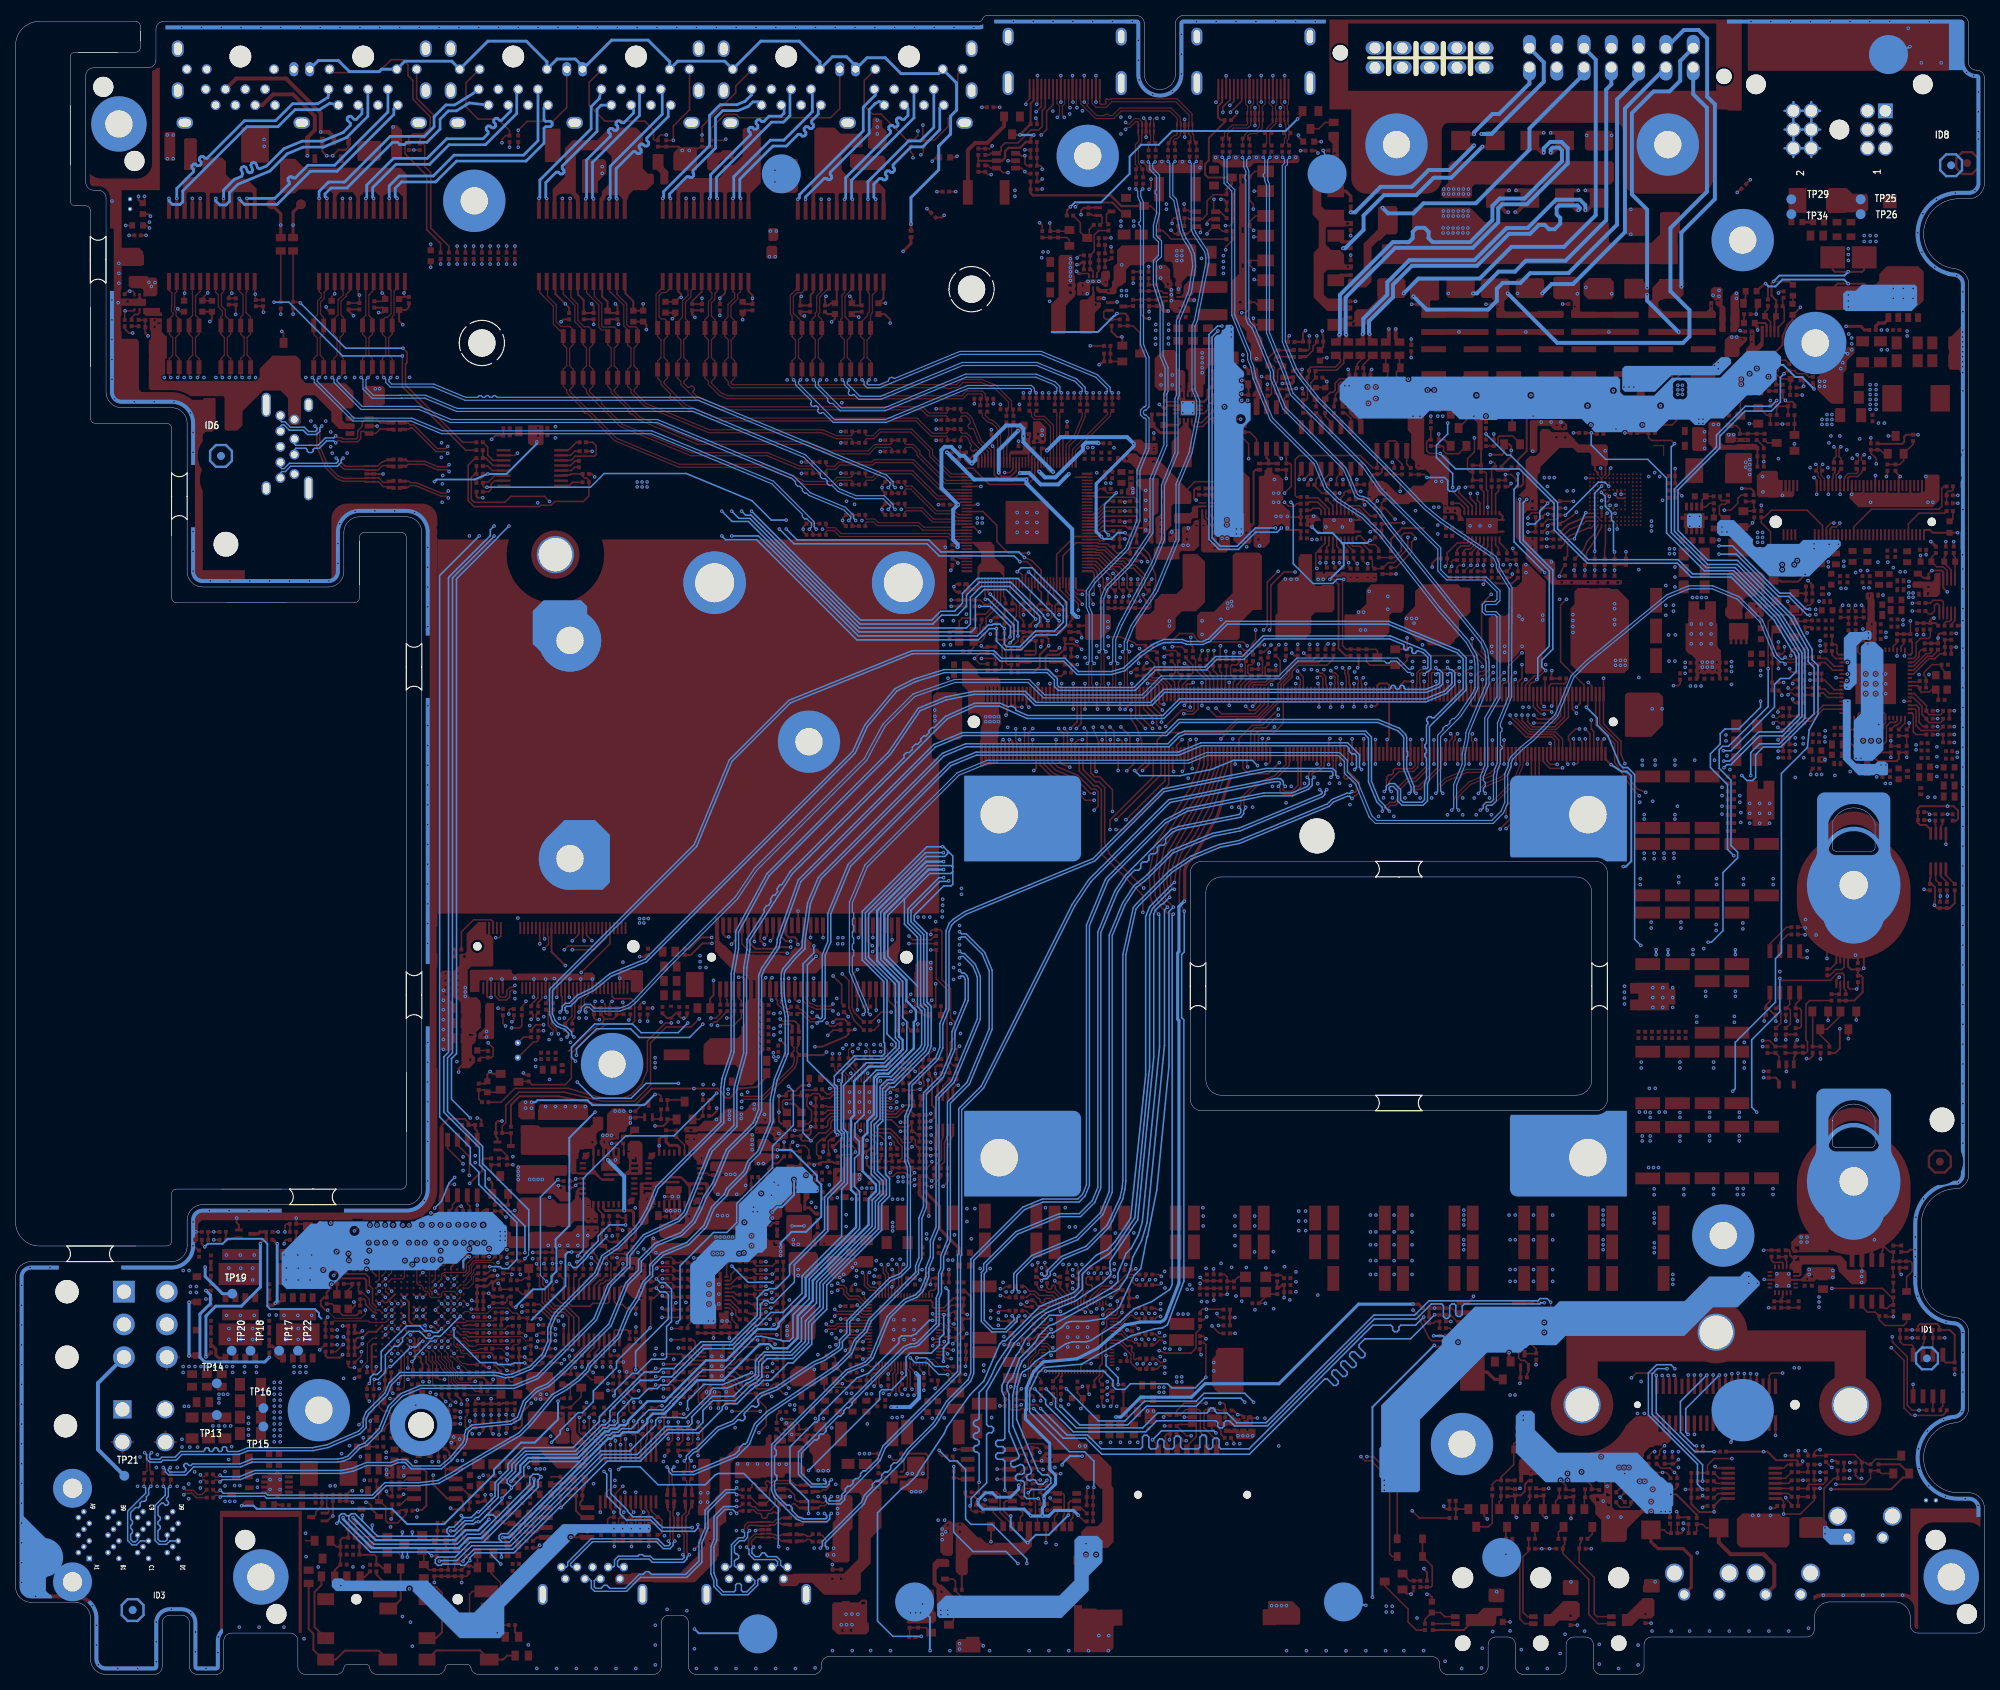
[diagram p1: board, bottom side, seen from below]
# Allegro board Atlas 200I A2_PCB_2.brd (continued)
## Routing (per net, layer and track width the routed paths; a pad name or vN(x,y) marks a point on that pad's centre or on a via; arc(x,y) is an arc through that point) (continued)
$49N3022: length 10
  TOP w0.203: LB1605.1 79.83,169.04 79.83,168.75 80.47,168.11 R1612.1 80.64,167.42 C1610.1 80.64,166.39 80.85,166.19 82.72,166.19 83.26,165.65 83.26,164.75 83.54,164.47 83.9,164.47 84.56,163.8 84.56,163.63 R1620.2 84.56,163.58 R1617.2
$49N3024: length 2.5
  TOP w0.203: R1628.1 81.97,161.85 81.25,161.14 U1602.13
$49N3026: length 2.9
  TOP w0.203: U1601.12 191.37,154.44 191.95,155.02 R1614.2
$49N3027: length 2.5
  TOP w0.203: C1614.2 180.75,155.68 181.34,155.09 U1601.4
$49N3028: length 2.8
  TOP w0.203: C1605.2 180.58,158.06 181.61,157.04 U1601.1
$49N16304: length 22.3
  TOP w0.203: T1601.7 227.83,177.3 227.86,177.27 v1(227.86,177.23) 228.55,176.54 C1624.2 C1625.2 ; C1623.2 C1620.2 225.17,176.78 v1(224.76,177.19) 224.83,177.26 T1601.4 ; T1601.10 230.83,177.21 v1(230.81,177.19) 230.89,177.11 C1626.2 ; T1601.1 221.83,177.13 v1(221.76,177.06) 221.76,176.4 C1622.2 C1621.2
  ART03 w0.178: v1(221.76,177.06) 221.89,177.19 v1(224.76,177.19) 224.8,177.23 v1(227.86,177.23) 227.9,177.19 v1(230.81,177.19)
$49N114414: length 1.8
  TOP w0.203: U1604.8 89.78,162.8 89.78,163.44 89.79,163.45 89.79,163.68 R1641.2
$49N114415: length 3.2
  TOP w0.203: U1604.4 93.35,158.5 94.21,159.36 R1640.1
$49N129020: length 7.3
  TOP w0.203: v1(92.71,166.5) 92.61,166.39 R1650.2
  TOP w0.406: R1649.2 C1644.2 88.65,165.81 88.85,165.61 v1(90.04,165.61)
  ART04 w0.305: v1(90.04,165.61) 90.93,166.5 v1(92.71,166.5)
$49N138534: length 3.6
  TOP w0.203: R1643.2 191.82,151.71 191.52,152.02 191.52,152.68 191.06,153.14 U1601.10
$49N141022: length 3
  TOP w0.203: U1601.8 181.52,152.49 181.08,152.93 R1645.1
$49N175637: length 27.2
  TOP w0.203: R1630.1 196.93,183.22 199.26,185.55 199.26,192.66 200.03,193.42 200.03,196.16 200.23,196.37 C1629.1 200.66,196.9 200.46,197.1 200.03,197.1 198.88,198.25 198.88,200.02 201.07,202.21 J1601.24
$49N175638: length 40.7
  TOP w0.203: R1629.1 197.99,183.56 199.77,185.34 199.77,192.28 202.57,195.07 202.57,196.16 202.36,196.37 C1628.1 202.06,197.1 201.55,197.61 200.15,197.61 199.33,198.43 199.33,199.84 201.55,202.06 201.55,204.47 202.18,205.1 202.18,206.5 202.82,207.14 204.34,207.14 205.99,205.49 211.81,205.49 J1601.22
$50N3043: length 5.7
  TOP w0.203: Q1701.1 67.44,156.59 68.99,156.59 69.06,156.67 69.09,156.67 69.34,156.92 69.34,157.43 69.49,157.58 C1701.1 R1701.2
$50N3048: length 8.9
  TOP w0.203: Q1701.3 66.42,160.91 D1701.1 66.42,165.1 66.93,165.61 66.93,166.24 66.37,166.8 K1701.8
$50N3052: length 8.5
  TOP w0.203: C1702.1 69.75,164.72 68.96,165.51 68.96,166.37 69.39,166.8 K1701.1 ; C1702.1 70,163.83 70,163.56 70.14,163.42 LB1701.2 ; C1702.1 68.24,164.08 68.17,164.02 D1701.3
$50N3713: length 2.2
  TOP w0.406: U12.2 82.4,183.78 R1704.2
$50N3720: length 2.7
  TOP w0.406: R1705.2 81.27,189.65 81.9,190.28 U7.2
$50N3727: length 3.3
  TOP w0.203: D1702.3 85.37,198.27 84.54,199.1 LB1702.1
$50N4340: length 2.2
  TOP w0.406: R1706.2 81.96,174.05 82.87,173.13 U8.2
$50N4347: length 2.2
  TOP w0.406: R1707.2 82.54,179.5 U2.2
$50N21517: length 2.6
  TOP w0.203: Q1702.1 C1707.1 R1708.2
$50N21522: length 9.3
  TOP w0.203: K1702.8 47.1,166.8 Q1702.3 51.4,164.02 52.02,163.4 52.02,162.23 52.45,161.8 D1723.1
$50N21526: length 9.3
  TOP w0.203: K1702.1 52.65,166.8 53.54,165.91 53.54,164.16 53.47,164.08 D1723.3 53.53,164.08 C1708.1 56.62,163.17 56.17,162.72 LB1703.2
$50N22342: length 4.9
  TOP w0.203: Q1703.1 39.5,160.83 40.05,160.28 C1709.1 R1711.2
$50N22347: length 10.4
  TOP w0.203: 43.05,161.73 43.05,161.8 43.03,161.82 43.03,162.74 41.75,164.02 Q1703.3 40.51,165.25 38.96,166.8 K1703.8
$50N22351: length 8.8
  TOP w0.203: D1724.3 44.13,163.96 C1710.1 46.77,163.12 LB1704.2
  TOP w0.254: D1724.3 44.07,165.44 42.71,166.8 K1703.1
$50N23194: length 5.9
  TOP w0.203: Q1704.1 59.56,157.94 60.5,158.88 62.17,158.88 62.37,158.67 62.37,157.92 62.71,157.58 C1711.1 R1714.2
$50N23199: length 9.9
  TOP w0.254: Q1704.3 60.58,161.48 60.33,161.73 D1725.1 59.56,163.88 56.64,166.8 K1704.8
$50N23203: length 9.2
  TOP w0.254: K1704.1 62.18,166.8 63.6,165.38 C1712.1 ; D1725.3 61.34,164.02 61.41,164.08 C1712.1 ; C1712.1 63.6,163.17 63.16,162.72 LB1705.2
$51N3749: length 2.2
  TOP w0.203: R2806.1 194.24,59.48 194.24,60.08 194.56,60.4 U2801.2
$51N3750: length 2.2
  TOP w0.203: R2804.1 195.22,70.13 194.56,69.47 U2801.7
$51N3751: length 2.4
  TOP w0.203: U2801.3 195.83,60.9 196.46,60.27 196.46,59.88 R2830.1
$51N3757: length 3
  TOP w0.203: R2801.1 187.55,48.77 TP1.1 R225.2
$51N24526: length 4.3
  TOP w0.203: R2802.1 191.03,39.65 190.35,38.96 R226.2 190.35,38.73 190.09,38.48 189.61,38.48 189.23,38.1 189.23,37.74 189.03,37.54 TP2.1
$51N56983: length 2.1
  TOP w0.203: C2804.1 206.73,30.45 206.63,30.35 LB2801.2 206.14,31.36 R2811.2
$51N107406: length 10.6
  TOP w0.203: v1(207.21,55.37) 207.14,55.45 R2812.2 ; U3.P11 v1(205.07,48.37)
  ART04 w0.203: v1(205.07,48.37) 206.15,48.37 206.78,49 206.78,49.3 207.01,49.53 207.01,52.13 207.33,52.45 207.61,52.45 207.92,52.77 207.92,54.66 v1(207.21,55.37)
$51N107414: length 11.9
  TOP w0.102: 205.05,49.15 205.06,49.15 v1(205.06,49.95)
  TOP w0.203: R2813.2 199.01,55.88 v1(198.5,55.37) ; 205.05,49.15 204.93,49.02 204.93,49.02 U3.N11
  ART04 w0.203: v1(198.5,55.37) 199.57,54.3 199.57,52.97 199.96,52.58 200.76,52.58 203.38,49.95 v1(205.06,49.95)
$51N178691: length 3.1
  TOP w0.203: U3.R14 206.76,51.65 206.76,52.2 206.25,52.7 206.25,53.7 R2832.1
$51N179012: length 8.8
  TOP w0.152: v1(202.57,53.09) 202.57,55.63 202.08,56.11 R2834.1
  TOP w0.203: U3.R12 206.26,49.55 v1(205.86,49.95)
  ART04 w0.203: v1(205.86,49.95) 205.86,50.6 205.03,51.43 204.22,51.43 v1(202.57,53.09)
$51N179013: length 6.3
  TOP w0.152: U3.R13 206.19,50.35 205.87,50.67 205.87,53.09 205.61,53.34 205.61,55.6 R2835.1
$51N179014: length 7.8
  TOP w0.203: U3.R11 v1(205.86,49.16) ; R2836.1 206.15,55.38 v1(206.16,55.37)
  ART04 w0.203: v1(205.86,49.16) 205.86,49.31 206.32,49.77 206.32,55.21 v1(206.16,55.37)
$51N189941: length 24.9
  TOP w0.203: R2853.2 197.26,32.16 199.31,34.21 v1(199.31,36.17) ; U3.C4 v1(197.06,42.75)
  ART04 w0.127: v1(197.06,42.75) 197.51,43.2 198.83,43.2 199.15,42.87 199.72,42.87 200.84,43.99 202.13,43.99 202.95,43.18 203.71,43.18 203.96,42.93 203.96,42.8
  ART04 w0.178: v1(199.31,36.17) 201.66,36.17 204.1,38.61 204.34,38.61 204.98,39.24 204.98,41.78 203.96,42.8
$51N189942: length 27.8
  TOP w0.203: v1(198.58,35.94) 198.55,35.92 198.55,34.18 197.38,33.01 R2854.2 ; U3.C3 v1(197.06,41.95)
  ART04 w0.127: 200.81,44.32 199.62,43.13 199.26,43.13 198.91,43.48 197.16,43.48 196.62,42.94 196.62,42.4 v1(197.06,41.95)
  ART04 w0.178: v1(198.58,35.94) 199.07,35.45 202.23,35.45 204.17,37.39 204.17,37.92 205.36,39.12 205.36,42.04 203.84,43.56 202.97,43.56 202.21,44.32 200.81,44.32
$51N189943: length 16.1
  TOP w0.203: R2855.2 207.44,37.01 207.14,37.31 v1(207.14,37.34) ; U3.D6 v1(197.86,44.36)
  BOTTOM w0.203: v1(207.14,37.34) 207.01,37.46 207.01,38.1 206.63,38.48 206.12,38.48 205.61,38.99 205.61,41.43 202.34,44.7 200.66,44.7 200.03,44.07 199.21,44.07 199.01,43.87 198.35,43.87 v1(197.86,44.35)
$51N189944: length 6.3
  TOP w0.152: U3.D5 197.07,43.56 196.53,43.56 196.27,43.3 196.27,42.22 196.02,41.97 195.74,41.97 195.45,41.69 195.45,41.41 195.22,41.17 194.57,41.17 194.16,40.77 R2856.2
$51N189945: length 18
  TOP w0.203: v1(208.15,41.4) 208.15,40.87 R2857.2 ; U3.K15 201.94,52.27 201.93,52.27 v1(201.63,52.58)
  ART03 w0.178: v1(201.63,52.58) 201.93,52.27 201.93,45.08 203.33,43.69 203.84,43.69 206.12,41.4 v1(208.15,41.4)
$51N189946: length 13.7
  TOP w0.203: U3.B7 v1(196.26,45.95) ; R2858.2 v1(201.04,53.16)
  ART03 w0.178: v1(201.04,53.16) 201.04,52.96 199.7,51.62 199.7,49.56 198.84,48.71 197.77,48.71 197.31,49.17 196.11,49.17 195.02,48.08 195.02,47.2 v1(196.26,45.95)
$51N189947: length 18.6
  TOP w0.203: v1(206.5,37.85) 206.58,37.77 R2859.2 ; U3.A7 v1(195.46,45.95)
  BOTTOM w0.203: v1(206.5,37.85) 205.99,37.85 205.08,38.76 205.08,40.98 203.95,42.11 203.46,42.11 202.87,42.7 202.87,43.19 202.05,44.01 200.69,44.01 199.79,43.11 199.1,43.11 198.82,43.38 198.03,43.38 v1(195.46,45.95)
$51N189948: length 13.3
  TOP w0.152: U3.B11 196.24,49.14 197.62,49.14 197.88,48.87 197.88,48.6 198.1,48.37 199.22,48.37 199.44,48.6 199.44,48.87 199.7,49.14 199.98,49.14 200.24,49.4 200.24,49.67 200.5,49.94 200.78,49.94 201.04,50.2 201.04,52.27 200.51,52.81 200.51,55.22 200.48,55.24 200.48,55.55 R2860.2
$51N189949: length 18.1
  TOP w0.203: v1(185.55,42.75) 185.47,42.75 185.42,42.8 R2861.2 ; U3.C11 v1(196.26,48.35)
  ART04 w0.178: v1(196.26,48.35) 195.9,48.71 194.93,48.71 193.94,49.69 191.43,49.69 190.23,48.5 187.61,48.5 186.44,47.33 186.44,45.05 185.04,43.66 185.04,43.31 185.55,42.8 v1(185.55,42.75)
$51N189950: length 27.6
  TOP w0.203: v1(196.72,34.54) 197,34.26 R2862.2 ; U3.D11 v1(197.06,48.35)
  ART04 w0.178: v1(197.06,48.35) 197.69,48.35 199.54,46.51 199.54,45.95 200.15,45.34 201.73,45.34 203.16,43.91 204.07,43.91 205.74,42.24 205.74,38.99 204.6,37.85 204.6,37.28 202.38,35.06 198.39,35.06 197.61,34.29 196.98,34.29 v1(196.72,34.54)
$51N189951: length 9.4
  TOP w0.203: R2863.2 187.45,46.61 v1(187.58,46.48) ; U3.A10 v1(194.56,47.45)
  ART04 w0.178: v1(194.56,47.45) 192.83,47.45 192.26,48.02 191.27,48.02 190.61,47.36 189.34,47.36 188.47,46.48 v1(187.58,46.48)
$51N189952: length 15.9
  TOP w0.102: v1(195.46,49.15) 195.46,48.35
  TOP w0.203: 195.46,48.35 U3.B10 ; R2864.2 v1(185.45,44.83)
  ART04 w0.178: v1(185.45,44.83) 185.55,44.83 186.06,45.34 186.06,47.49 187.55,48.98 190.07,48.98 191.26,50.16 194.45,50.16 v1(195.46,49.15)
$51N189953: length 16.8
  TOP w0.203: v1(185.67,43.51) 185.37,43.81 R2865.2 ; U3.C10 v1(196.26,47.55)
  ART04 w0.178: v1(185.67,43.51) 186.94,44.78 186.94,47.3 187.77,48.12 190.28,48.12 191.5,49.34 193.84,49.34 194.83,48.35 195.46,48.35 v1(196.26,47.55)
$51N189954: length 19.2
  TOP w0.203: v1(185.73,41.99) 185.55,41.99 185.34,41.78 R2866.2 ; U3.D10 v1(197.06,47.55)
  ART04 w0.102: 195.82,46.4 195.85,46.36 196.69,46.36 196.77,46.28 197.21,46.28 197.51,46.57 197.51,47.11 v1(197.06,47.55)
  ART04 w0.178: 195.82,46.4 193.25,46.4 192.02,47.62 191.39,47.62 190.88,47.12 190.88,44.2 189.99,43.31 187.83,43.31 186.51,41.99 v1(185.73,41.99)
$51N190892: length 7.5
  TOP w0.152: U3.B6 195.44,44.34 194.9,44.34 194.86,44.3 189.76,44.3
  TOP w0.203: R2867.1 189.36,44.7 189.76,44.3
$51N190893: length 10
  TOP w0.127: 189.23,43.31 189.2,43.33 187.6,43.33 187.07,42.8 186.61,42.8 R2872.1
  TOP w0.152: U3.B5 195.47,43.56 194.67,43.56 194.46,43.36
  TOP w0.203: 194.46,43.36 194.41,43.31 189.23,43.31
$51N190894: length 1.8
  TOP w0.203: U3.A5 194.42,43.95 194.28,43.81 R2870.1
$51N190895: length 1.9
  TOP w0.203: U3.A4 194.82,43.15 194.46,42.8 R2871.1
$51N190896: length 3.2
  TOP w0.127: 192.91,41.78 193.4,41.58 194.15,41.58 194.93,42.35 U3.A3
  TOP w0.203: 192.91,41.78 R2868.1
$51N190897: length 1.8
  TOP w0.203: U3.A6 194.68,44.75 194.6,44.83 R2869.1
$51N190904: length 5.6
  TOP w0.152: 194.24,41.27 194.9,41.94 195.2,41.94 195.53,42.27 195.77,42.27 U3.B3
  TOP w0.203: R2873.2 191.26,40.87 191.26,41.02 191.52,41.27 194.24,41.27
$51N190905: length 7.8
  TOP w0.127: 193.93,42.11 193.47,42.11 193.27,42.32 189.23,42.32 R2874.2
  TOP w0.152: 194.44,42.29 194.9,42.75 195.46,42.75
  TOP w0.203: 195.46,42.75 195.86,43.15 U3.B4 ; 194.44,42.29 194.26,42.11 193.93,42.11
$51N218764: length 1.8
  TOP w0.203: U2804.2 R2882.2
$51N218765: length 1.9
  TOP w0.203: R2881.2 5.64,34.11 5.33,34.42 U2804.1
$51N218772: length 1.9
  TOP w0.203: U2803.1 131.51,25.05 131.56,25.1 131.58,25.1 131.7,25.22 R2884.2
$51N218773: length 2.8
  TOP w0.203: R2883.2 132.31,27.71 130.97,26.37 130.45,26.37 U2803.2
$51N218779: length 3
  TOP w0.203: R2885.2 25.22,94.92 26.24,93.9 U2805.2
$51N218780: length 4.6
  TOP w0.203: U2805.1 27.51,93.73 25.37,95.86 R2886.2
$51N221791: length 14.7
  TOP w0.203: v1(187.2,39.95) 186.87,39.62 185.27,39.62 R123.2 ; U3.C5 196.66,43.97 v1(196.27,44.35)
  BOTTOM w0.203: v1(187.2,39.95) 188.52,39.95 189.01,39.75 190.63,39.75 190.88,40 192.91,40 196.27,43.36 v1(196.27,44.35)
$51N221836: length 6
  TOP w0.152: R120.2 191.25,45.34 194.64,45.34 194.82,45.15 196.26,45.15
  TOP w0.203: 196.26,45.15 U3.C6
$51N230666: length 1.9
  TOP w0.203: U3.G1 199.86,39.97 199.52,39.63 R2833.1
$51N230667: length 6.2
  TOP w0.152: R2827.1 198.55,36.73 199.01,37.19 199.01,39.85 199.48,40.32 199.48,41.36 199.67,41.55 U3.G2
$51N230670: length 14.9
  TOP w0.102: 204.32,42.01 204.26,41.95 v1(204.26,41.15)
  TOP w0.203: R2831.1 v1(194.56,35.23) ; 204.32,42.01 U3.N3
  ART04 w0.178: v1(194.56,35.23) 194.89,35.56 197.36,35.56 198.98,37.18 198.98,37.82 199.9,38.73 202.44,38.73 203.56,39.85 203.56,40.45 v1(204.26,41.15)
$51N231127: length 5.8
  TOP w0.152: U3.L2 202.64,41.14 202.64,36.83 202.87,36.6 R2844.1
$51N231129: length 5.5
  TOP w0.152: R2845.1 191.03,53.57 191.49,53.11 193.65,53.11 194.02,52.74 194.02,52.67 194.31,52.37 194.31,51.69 194.84,51.15 U3.A14
$51N231131: length 4.5
  TOP w0.152: R2847.1 203.07,54.23 203.58,53.72 203.58,53.24 203.86,52.96 U3.M15
$51N231578: length 5.7
  TOP w0.152: R2840.1 196.95,38.32 197.99,39.37 197.99,39.62 198.64,40.27 198.64,41.14 U3.F2
$51N231581: length 2
  TOP w0.152: R2838.1 198.5,39.73 199.06,40.29 U3.F1
$51N231582: length 1.9
  TOP w0.203: U3.L1 203.06,39.03 R2837.1
$51N234739: length 5.5
  TOP w0.152: U3.P14 205.05,51.56 205.05,52.86 204.6,53.31 204.6,55.6 R2848.1
$51N234742: length 8.2
  TOP w0.203: R2843.1 v1(199.01,53.19) ; U3.N12 v1(204.27,49.17)
  ART04 w0.203: v1(204.27,49.17) 203.44,49.17 200.53,52.07 199.9,52.07 199.01,52.96 v1(199.01,53.19)
$51N234743: length 2
  TOP w0.203: U3.P15 205.46,52.98 205.11,53.34 R2846.1
$51N235080: length 7.6
  TOP w0.203: U3.P13 v1(205.06,50.75) ; R2842.1 v1(200.03,53.16)
  ART04 w0.203: v1(205.06,50.75) 204.13,50.75 201.27,53.62 200.48,53.62 v1(200.03,53.16)
$51N235403: length 5.4
  TOP w0.152: R2841.1 202.06,52.93 202.64,52.35 202.64,50.93 202.82,50.75 204.27,50.75 U3.N13
$51N235404: length 2.9
  TOP w0.152: R2839.1 204.09,53.34 204.28,53.15 204.28,51.54 U3.N14
$51N243463: length 11.4
  TOP w0.203: U3.C8 196.66,46.38 v1(196.27,46.77) ; R65.2 187.35,47.47 v1(187.57,47.24)
  ART04 w0.178: v1(196.27,46.77) 195.61,46.77 195.01,47.37 195.01,47.63 194.21,48.42 191.15,48.42 190.46,47.74 188.07,47.74 v1(187.57,47.24)
$51N243466: length 5.3
  TOP w0.127: R66.2 208.03,39.39 208.03,39.5 207.39,40.13 207.39,42.44 206.68,43.15 U3.R4
$51N249168: length 8.3
  TOP w0.127: R203.1 190.45,52.02 191.27,52.84 193.54,52.84 193.75,52.63 193.75,52.55 194.04,52.26 194.04,51.57 194.69,50.93 194.69,50.72 U3.A13
$51N251938: length 54.2
  TOP w0.203: v1(195.46,47.54) 195.85,47.15 U3.B9 ; R126.2 v1(176.53,36.42)
  ART03 w0.102: 197.64,48.39 197.23,48.79 196.11,48.79 195.46,48.14 v1(195.46,47.54)
  ART03 w0.127: 195.49,35.47 194.58,34.56
  ART03 w0.178: 194.58,34.56 189.98,34.56 187.68,36.85 181.13,36.85 180.47,36.19 176.76,36.19 v1(176.53,36.42) ; 195.49,35.47 202.25,35.47 203.18,34.54 204.84,34.54 205.33,35.04 205.33,36.05 204.25,37.13 204.25,37.68 203.12,38.81 201.92,38.81 201.74,38.99 201.74,39.56 202.44,40.26 202.44,43.69 200.62,45.51 200.03,45.51 199.52,46.02 199.52,47.35 198.63,48.23 197.79,48.23 197.64,48.39
$51N251939: length 49.3
  TOP w0.203: U3.C9 v1(197.06,46.75) ; R125.2 v1(176.53,37.31)
  ART03 w0.127: 199.39,45.21 200.28,45.21 200.41,45.08
  ART03 w0.178: 199.39,45.21 197.85,46.75 v1(197.06,46.75) ; 200.41,45.08 200.79,44.7 200.79,38.61 200.79,38.61 202.06,37.34 202.69,37.34 203.2,37.85 203.47,37.85 203.87,37.45 203.87,36.98 204.95,35.9 204.95,35.2 204.68,34.92 203.34,34.92 202.38,35.88 200.34,35.88 199.52,36.7 198.66,36.7 197.81,35.85 189.22,35.85 187.84,37.24 180.75,37.24 180.18,36.66 177.71,36.66 177.64,36.74 177.61,36.74 177.04,37.31 v1(176.53,37.31)
$51N262712: length 4.4
  TOP w0.127: U3.B12 195.45,49.96 194.77,49.96 194.06,50.67 194.06,51.18 193.74,51.5 193.74,51.88 193.31,52.31 R268.2
$51N262713: length 3.2
  TOP w0.127: R269.2 193.4,51.46 193.8,51.05 193.8,50.16 194.41,49.55 U3.A12
$51N262907: length 8.4
  TOP w0.203: v1(193.29,55.32) 193.17,55.45 R270.2 ; v1(196.26,49.95) 196.66,49.55 U3.C12
  ART03 w0.178: v1(193.29,55.32) 193.29,52.29 195.63,49.95 v1(196.26,49.95)
$51N266287: length 11.5
  TOP w0.203: v1(197.86,49.95) 198.26,49.55 U3.E12 ; R2878.2 192.19,55.37 v1(192.41,55.37)
  ART03 w0.178: v1(192.41,55.37) 192.41,52.55 195.36,49.6 195.64,49.6 195.73,49.51 197.42,49.51 v1(197.86,49.95)
$51N266288: length 9.1
  TOP w0.203: v1(194.08,55.35) 193.95,55.22 193.95,55.02 193.55,54.61 R2875.2 ; U3.F12 199.06,49.55 v1(198.66,49.95)
  ART04 w0.178: v1(194.08,55.35) 194.18,55.35 195.96,53.56 195.96,53.34 198.66,50.64 v1(198.66,49.95)
$51N266290: length 7.1
  TOP w0.152: R2876.1 193.7,53.59 194.45,52.84 194.45,52.84 194.68,52.62 194.68,51.8 194.91,51.56 197.59,51.56 197.86,51.29 197.86,50.75
  TOP w0.203: U3.E13 198.26,50.35 197.86,50.75
$51N266291: length 46.8
  TOP w0.203: R2826.1 189.28,48.46 189.48,48.26 189.48,47.88 189.71,47.65 C28.1 C27.1 191.29,47.65 v1(191.77,47.17) ; U3.H5 U3.G5 199.76,44.06 199.16,44.06 U3.F5 ; C26.1 v1(207.47,52.96)
  TOP w0.254: v1(202.66,48.35) 202.06,47.75 202.06,45.34 201.5,44.78 v1(200,44.78) 199.86,44.64 U3.G5 ; v1(202.66,48.35) U3.K11 ; v1(202.66,48.35) U3.L11 ; U3.E7 v1(198.66,45.15) U3.E6 ; C25.1 C26.1 ; C31.1 193.78,45.85 v1(193.8,45.87)
  TOP w0.305: v1(208.03,44.07) 208.28,43.81 C30.1 C29.1
  ART03 w0.305: v1(208.03,44.07) 207.77,44.07 205.74,46.1 205.74,46.86 204.25,48.35 v1(202.66,48.35)
  ART04 w0.178: v1(207.47,52.96) 207.05,52.96 206.63,52.54 206.63,49.63 206.38,49.37 206.38,49.04 206.04,48.71 205.68,48.71 205.58,48.81 204.77,48.81 204.31,48.35 v1(202.66,48.35)
  ART04 w0.254: v1(193.8,45.87) 193.35,45.87 193.32,45.85 192.81,45.85
  ART04 w0.305: v1(200,44.78) 199.82,44.78 199.45,45.15 v1(198.66,45.15) 197.92,45.15 197.33,45.74 196.85,45.74 195.43,44.32 193.35,44.32 192.81,44.86 192.81,46.13 v1(191.77,47.17)
$51N266293: length 4.7
  TOP w0.152: U3.D2 197.05,41.15 197.05,40.61 196.47,40.02 196.47,39.42 195.83,38.79 195.83,38.1 195.68,37.95 R2879.2
$51N267635: length 17.5
  TOP w0.203: U3.D4 v1(197.86,42.75) ; v1(189.48,53.47) 189.48,53.72 189.19,54.01 R271.2
  ART03 w0.178: v1(197.86,42.75) 197.33,43.28 195.24,43.28 192.85,45.67 192.85,47.31 192.02,48.13 191.57,48.13 189.74,49.97 189.74,52.2 189.99,52.45 189.99,52.96 v1(189.48,53.47)
$51N267689: length 17.4
  TOP w0.203: v1(197.86,41.95) 197.46,42.35 U3.D3 ; v1(189.48,52.7) 189.19,53 R272.2
  ART03 w0.178: v1(189.48,52.7) 189.36,52.58 189.36,49.81 191.42,47.75 191.9,47.75 192.53,47.12 192.53,45.56 195.67,42.42 195.89,42.42 196.82,41.48 197.39,41.48 v1(197.86,41.95)
$51N275573: length 4.7
  TOP w0.127: R76.1 194.87,35.84 190.88,35.84 TP5.1
$51N275625: length 4.4
  TOP w0.127: TP3.1 188.9,36.75 191.57,36.75 R29.1
$51N277380: length 2.9
  TOP w0.203: R2808.1 187.58,50.55 187.3,50.82 R225.1 TP23.1
$51N277381: length 3.1
  TOP w0.203: R2807.1 192,38.76 191.9,38.86 R226.1 191.16,38.51 190.25,37.59 TP24.1
$52N3046: length 12.8
  TOP w0.203: J803.52 179.78,94.3 v1(179.58,94.11) ; R829.1 R832.1 176.3,86.03 v1(176,86.33)
  ART03 w0.178: v1(176,86.33) 176.38,86.71 176.38,89.93 179.34,92.88 179.34,93.86 v1(179.58,94.11)
$52N3047: length 13.1
  TOP w0.203: v1(178.59,94.13) 179.28,94.82 J803.54 ; R833.1 R830.1 174.52,86.13 v1(174.63,86.23)
  ART03 w0.178: v1(178.59,94.13) 178.59,92.9 175.85,90.16 175.85,87.46 v1(174.63,86.23)
$52N43522: length 1.4
  TOP w0.203: R848.2 191.98,80.04 D801.2
$52N52006: length 13.8
  TOP w0.203: J803.50 180.28,94.93 v1(181.1,94.11) ; R851.1 R852.1 178.29,85.54 178.29,86.23 v1(178.18,86.33)
  ART03 w0.178: v1(181.1,94.11) 176.91,89.92 176.91,87.6 v1(178.18,86.33)
$52N58402: length 5.1
  TOP w0.188: J803.47 181.03,87.27 180.91,87.15 180.91,86.56 181.15,86.31 181.15,84.4 182.02,83.54 C810.2
$52N58403: length 4.8
  TOP w0.188: J803.49 180.53,86.4 180.77,86.15 180.77,84.25 181.1,83.92 C811.2
$52N66878: length 7.9
  TOP w0.191: J803.6 191.28,96.58 191.49,96.8 193.78,96.8 194.44,96.14
  TOP w0.203: R850.1 195.33,95.25 194.44,96.14
$52N80474: length 4.8
  TOP w0.203: Q801.1 190.61,74.69 C802.1 192.16,74.69 192.46,74.98 R822.2 193.11,73.83 R821.2
$52N90661: length 2.6
  TOP w0.203: R230.2 185.55,85.79 185.55,86.13 185.03,86.65 J803.31
$52N90662: length 2.7
  TOP w0.203: J803.29 185.53,86.76 186.38,85.91 R231.2
$52N90958: length 2.1
  TOP w0.203: J803.37 183.53,87.15 183.67,87.01 183.67,86.18 R232.2
$52N90959: length 2.1
  TOP w0.203: R233.2 184.3,86.26 184.3,86.41 184.07,86.65 184.07,87.18 184.03,87.22 J803.35
$53N3925: length 21.2
  TOP w0.188: v1(230.92,23.93) 230.62,23.62 229.71,23.62 229.15,23.06 228.63,23.06 C901.2
  ART04 w0.152: v1(230.92,23.93) 231.3,23.55 240.43,23.55 242.36,21.61 242.36,19.04 243.68,17.72 244.17,17.72 J901.A5
$53N3926: length 22.1
  TOP w0.188: v1(230.92,23.04) 230.72,23.24 229.87,23.24 229.31,22.68 C913.2
  ART04 w0.152: J901.A4 243.3,17.26 243.37,17.5 241.98,18.88 241.98,19.27 241.83,19.42 241.71,19.42 241.55,19.58 241.55,19.8 241.71,19.96 241.83,19.96 241.98,20.11 241.98,20.34 241.83,20.49 241.71,20.49 241.55,20.64 241.55,20.87 241.71,21.02 241.83,21.02 241.98,21.17 241.98,21.46 241.19,22.25 240.97,22.25 240.72,22 240.51,22 240.35,22.16 240.35,22.38 240.6,22.63 240.6,22.84 240.27,23.17 231.05,23.17 v1(230.92,23.04)
$53N3927: length 19
  TOP w0.188: C915.2 228.03,25.65 228.32,25.36 228.55,25.36 v1(228.79,25.6)
  ART04 w0.152: v1(228.79,25.6) 229.05,25.35 229.37,25.35 229.74,24.97 229.74,22.35 230.07,22.02 237.44,22.02 238.13,21.34 238.13,19.23 239.61,17.74 240.02,17.62 240.21,17.64 J901.B5
$53N3928: length 19.5
  TOP w0.188: C916.2 228.32,24.98 228.53,24.98 v1(228.79,24.72)
  ART04 w0.152: J901.B4 239.25,17.56 237.74,19.07 237.74,21.18 237.28,21.64 234.91,21.64 234.76,21.49 234.76,21.21 234.61,21.06 234.38,21.06 234.23,21.21 234.23,21.49 234.08,21.64 233.85,21.64 233.7,21.49 233.7,21.21 233.54,21.06 233.32,21.06 233.16,21.21 233.16,21.49 233.01,21.64 229.92,21.64 229.36,22.19 229.36,24.82 229.21,24.97 229.05,24.97 v1(228.79,24.72)
$53N4325: length 11.4
  TOP w0.188: v1(235.16,24.13) 235.03,24.26 C83.1
  BOTTOM w0.188: v1(235.16,24.13) 235.43,23.85 235.43,23.09 235.73,22.79 235.73,22.41 235.94,22.2 236.32,22.2 236.53,21.99 236.53,21.61 236.74,21.4 237.13,21.4 237.74,20.78 237.74,19.9 237.52,19.67 237.52,19.33 237.74,19.1 237.74,18.76 237.52,18.53 237.52,18.19 237.74,17.96 237.74,17.32 237.42,17 237.15,17 236.85,17.3 J901.C5
$53N4326: length 12
  TOP w0.188: v1(236.04,24.13) 235.99,24.18 C94.1
  BOTTOM w0.188: J901.C4 236.49,17.12 237,16.62 237.58,16.62 238.13,17.16 238.13,20.93 235.81,23.25 235.81,23.9 v1(236.04,24.13)
$53N4327: length 11.8
  TOP w0.188: v1(232.67,24.13) 232.67,24.73 232.59,24.81 C95.1
  BOTTOM w0.188: v1(232.67,24.13) 232.92,23.88 232.92,22.83 233.15,22.6 233.15,22.37 232.89,22.11 232.89,21.87 233.05,21.71 233.29,21.71 233.55,21.97 233.78,21.97 234.24,21.51 234.24,20.43 233.93,20.13 233.93,19.86 234.24,19.56 234.24,19.29 233.93,18.99 233.93,18.72 234.24,18.42 234.24,17.35 233.96,17.07 233.29,17.07 233.05,17.31 J901.D5
$53N4328: length 11.8
  TOP w0.188: C96.1 233.55,24.89 233.55,24.89 v1(233.55,24.13)
  BOTTOM w0.188: v1(233.55,24.13) 233.3,23.88 233.3,22.99 234.62,21.67 234.62,17.19 234.12,16.69 233.13,16.69 232.69,17.12 J901.D4
$55N2035: length 6.8
  TOP w0.203: R1401.1 108.74,150.75 108.99,151 110.44,151 110.46,151.03 113.97,151.03 114.12,151.18 U6.40
$55N9367: length 4.2
  TOP w0.203: U1401.4 99.85,148.39 99.48,148.02 99.48,147.71 99.16,147.4 C1440.1 R1405.2 98.7,146.48 R1406.1
$55N9369: length 1.2
  TOP w0.203: C1434.2 98.83,148.28 99.4,148.85 U1401.3
$55N9370: length 3.5
  TOP w0.203: U1401.1 98.74,150.29 98.58,150.45 98.58,150.67 98.73,150.82 98.83,150.82 99.03,151.03 C1438.2 R1407.1 R1408.2
$55N9373: length 1.7
  TOP w0.203: R1402.1 C1438.1 R1407.2
$59N2622: length 20.3
  TOP w0.203: C1505.2 v1(140.94,175.91)
  TOP w0.254: T1501.10 150.19,177.33 150.54,176.97 150.54,175.67 C1504.2 C1501.2 151.87,176.66 v1(151.74,176.78) ; C1505.2 141.19,176.56 T1501.1 ; T1501.7 147.19,176.14 C1506.2 147.94,175.91 148.23,175.62 C1502.2 148.69,176.66 v1(148.56,176.78) ; T1501.4 144.19,175.81 C1503.2 144.97,175.62 C1507.2 145.26,176.53 v1(145.52,176.78)
$59N14331: length 23.4
  TOP w0.203: C1510.2 C1509.2 v1(208.41,176.95) 208.58,177.12 T1502.7 ; C1513.2 211.96,176.71 v1(211.58,177.1) T1502.10 ; 202.65,176.71 202.65,177.18 v1(202.69,177.22) 202.69,177.29 202.58,177.41 T1502.1 ; 202.65,176.71 203.05,176.71 C1515.2 ; 202.65,176.71 C1512.2 ; C1511.2 205.4,176.15 C1514.2 205.11,176.83 v1(205.49,177.22) 205.58,177.31 T1502.4
  ART03 w0.178: v1(211.58,177.1) 208.56,177.1 v1(208.41,176.95) 208.14,177.22 v1(205.49,177.22) v1(202.69,177.22)
$59N15275: length 24.9
  TOP w0.254: T1503.4 177.38,177.93 177.28,177.82 177.28,176.77 176.58,176.07 C1520.2 176.29,174.65 C1516.2 175.31,175.56 v1(175.57,175.82) ; T1503.10 183.38,177.93 183.28,177.82 183.28,177.11 v1(181.99,175.82) 181.51,175.34 C1519.2 ; T1503.7 180.38,177.03 179.64,176.29 179.64,174.66 C1517.2 C1518.2 178.36,175.56 v1(178.61,175.82) ; v1(172.02,175.82) 172.01,175.81 C1521.2 C1522.2 173.28,176.15 174.28,177.15 174.28,177.52 174.38,177.62 T1503.1
$59N16235: length 17.6
  TOP w0.203: T1504.7 164.51,177.38 165.74,176.15 C1524.2 C1525.2 v1(164.47,176.53)
  TOP w0.254: T1504.4 161.51,177.2 v1(162.18,176.53) C1526.2 ; C1529.2 C1528.2 167.32,176.66 v1(167.13,176.66) 167.13,177.04 167.51,177.42 T1504.10 ; T1504.1 158.51,177.43 157.99,176.91 v1(157.99,176.53) C1523.2 158.97,175.79 C1527.2
$59N94279: length 47
  TOP w0.203: R1503.1 v1(191.64,183.24) ; C1532.1 v1(164.47,197.48) 164.47,198.58 160.15,202.9 160.15,203.76 J1501.18
  ART03 w0.178: v1(191.64,183.24) 191.64,183.69 187.91,187.42 174.65,187.42 173.61,188.47 172.61,188.47 166.05,195.03 165.16,195.03 164.47,195.73 v1(164.47,197.48)
$59N94285: length 62.6
  TOP w0.203: v1(161.42,196.95) 161.57,196.8 C1533.1 163.32,198.33 161.54,200.12 160.04,200.12 159.62,199.69 147.98,199.69 146.8,200.87 J1501.20 ; R1504.1 v1(190.58,183.24)
  ART03 w0.178: v1(161.42,196.95) 162.7,196.95 165,194.65 165.89,194.65 172.66,187.88 173.65,187.88 174.49,187.04 187.62,187.04 190.58,184.07 v1(190.58,183.24)
$59N94881: length 78.5
  TOP w0.203: v1(136.14,198.75) 136.14,196.87 C1530.1 134.67,196.8 132.89,198.58 132.89,199.62 131.67,200.84 131.67,205.3 J1501.24 ; R1501.1 v1(188.47,183.24)
  ART03 w0.178: v1(188.47,183.24) 188.47,184.86 187.05,186.28 174.18,186.28 173.46,186.99 141.94,186.99 135.6,193.33 135.6,198.21 v1(136.14,198.75)
$59N94883: length 77.8
  TOP w0.203: R1502.1 v1(189.53,183.24) ; J1501.22 143.66,204.49 143.66,201.22 142.6,200.15 141.5,200.15 138.15,196.8 C1531.1 137.39,196.8 136.78,197.41 v1(136.78,197.99)
  ART03 w0.178: v1(189.53,183.24) 189.53,184.45 187.32,186.66 174.34,186.66 173.62,187.38 143.08,187.38 138.23,192.23 138.23,196.54 v1(136.78,197.99)
$59N95912: length 51.7
  TOP w0.203: v1(169.04,197.48) 169.8,197.48 170.13,197.15 C1536.1 170.51,196.8 170.69,196.98 170.69,198.12 171.83,199.26 176.91,199.26 178.94,201.29 178.94,204.22 J1502.22 ; R1507.1 v1(193.76,183.24)
  ART03 w0.178: v1(169.04,197.48) 170.13,196.39 170.13,193.02 174.96,188.19 188.49,188.19 193.04,183.64 193.35,183.64 v1(193.76,183.24)
$59N95918: length 43.3
  TOP w0.203: J1502.24 166.07,200.71 168.15,198.63 v1(168.15,196.8) C1537.1 ; R1508.1 v1(192.7,183.24)
  ART03 w0.178: v1(168.15,196.8) 169.06,195.88 169.06,193.55 174.81,187.8 188.13,187.8 v1(192.7,183.24)
$59N96488: length 32
  TOP w0.203: J1502.18 194.74,204.17 194.74,201.09 193.17,199.52 190.63,199.52 189.15,198.04 C1534.1 189.64,197.41 190.12,196.93 v1(190.12,196.49) ; R1505.1 v1(195.88,183.24)
  ART03 w0.178: v1(190.12,196.49) 189.74,196.11 189.74,188.34 193.29,184.78 194.33,184.78 v1(195.88,183.24)
$59N96493: length 32
  TOP w0.203: R1506.1 v1(194.82,183.24) ; C1535.1 v1(188.04,198.09) 186.89,199.24 183.59,199.24 181.82,201.01 J1502.20
  ART03 w0.178: v1(188.04,198.09) 188.04,196.65 188.62,196.06 188.62,188.7 193.17,184.15 193.9,184.15 v1(194.82,183.24)
$60N1213: length 4.5
  TOP w0.203: R3303.2 C3312.1 212.41,23.05 212.6,22.86 212.6,21.46 212.34,21.21 212.34,20.87 212.55,20.67 212.85,20.67 Q3302.1
$60N1214: length 4.1
  TOP w0.203: Q3304.3 179.96,35.64 R3309.2 R3308.1
$60N1215: length 7.7
  TOP w0.203: R3306.1 181.36,37.13 181.27,37.22 ; 181.27,37.22 C3304.1 ; 181.27,37.22 181.22,37.22 180.47,37.97 R3305.2 179.38,38.53 178.64,37.79 Q3304.1
$60N1222: length 3.6
  TOP w0.203: R3302.2 R3301.2 213.21,21.61 214,20.83 214,20.5 214.3,20.19 Q3302.3
$60N1224: length 1.1
  TOP w0.254: R3304.2 218.69,21.72 218.8,21.82 C3303.1
$61N1194: length 1.8
  TOP w0.203: R1003.1 R1004.2 R1002.1
$61N1196: length 8.9
  TOP w0.203: U11.23 180.62,63.63 v1(180.67,63.58) 180.95,63.3 R1006.1 ; R1007.2 v1(176.05,68.12)
  ART03 w0.203: v1(180.67,63.58) 180.59,63.58 v1(176.05,68.12)
$61N1197: length 1.2
  TOP w0.203: U11.35 174.5,68.03 R1007.1
$61N1198: length 2.7
  TOP w0.203: R1004.1 R1003.2 177.17,59.03 177.75,59.62 U11.16
$61N1203: length 2.5
  TOP w0.203: Q1003.1 164.82,71.2 C1001.1 R1015.2
$61N1204: length 3.5
  TOP w0.203: Q1003.3 166.91,73.7 R1012.2 R1009.1
$61N1210: length 0.9
  TOP w0.203: R1011.1 R1008.2
$61N1212: length 2.4
  TOP w0.203: Q1004.1 170.6,71.25 C1002.1 R1009.2
$61N3534: length 3.1
  TOP w0.203: U5.7 202.37,25.08 202.81,24.64 R1021.2 R1017.1
$61N3535: length 10.6
  TOP w0.203: C1014.1 206.22,23.91 C1013.1 205.93,22.21 U1001.1 205.7,22.16 205.02,21.49 205.02,19.73 204.72,19.43 203.51,19.43 202.41,20.52 R1019.1 202.49,21.08 203.1,21.08 R1020.2
$61N3537: length 2.3
  TOP w0.203: U5.5 202.33,22.54 203.06,21.82 R1018.2
$61N3538: length 1.9
  TOP w0.203: R1021.1 202.52,23.82 202.51,23.81 U5.6
$61N12065: length 3.4
  TOP w0.203: R1028.1 174.18,46.97 174.65,47.45 175.36,47.45 175.71,47.8 U1002.23
$61N12066: length 9.2
  TOP w0.203: R1029.1 183.49,48.62 182.55,47.68 181.62,47.68 181.19,47.24 178.84,47.24 178.48,47.6 176.57,47.6 176.36,47.8 U1002.22
$61N12078: length 2.9
  TOP w0.203: U1002.18 178.96,49.92 R1022.1
$61N12079: length 2.7
  TOP w0.203: R1024.1 179.61,50.29 U1002.17
$61N12080: length 2.6
  TOP w0.203: U1002.16 180.26,50.65 R1023.1
$61N12081: length 2.4
  TOP w0.203: U1002.15 180.91,51.02 R1026.1
$61N12082: length 2.4
  TOP w0.203: U1002.14 181.56,51.07 R1025.1
$61N12083: length 2.6
  TOP w0.203: U1002.13 182.21,50.7 R1027.1
$61N12094: length 3.1
  TOP w0.203: R1036.1 177.37,50.57 177.59,50.57 178.31,49.85 U1002.19
$61N14206: length 2.2
  TOP w0.203: U1002.5 177.66,41.82 178.15,41.33 R2849.1
$61N14207: length 2.3
  TOP w0.203: U1002.6 178.31,41.96 179.01,41.26 R2850.2
$61N14208: length 2.4
  TOP w0.203: U1002.7 178.96,42.04 179.86,41.14 R2851.2
$61N14209: length 2.5
  TOP w0.203: R2852.2 180.72,41 179.61,42.1 U1002.8
$61N15063: length 2.1
  TOP w0.203: R73.1 177.01,41.1 U1002.4
$61N18483: length 11
  TOP w0.203: R259.2 183.64,50.5 184.15,49.99 184.15,48.13 183.29,47.27 181.79,47.27 180.26,45.74 U1002.9
$61N18484: length 11
  TOP w0.203: R260.2 184.9,50.87 184.9,50.04 184.56,49.69 184.56,47.9 183.52,46.86 181.99,46.86 180.91,45.78 U1002.10
$61N18485: length 10.8
  TOP w0.203: R261.2 185.31,51.08 185.31,49.76 184.96,49.42 184.96,47.74 183.68,46.46 182.16,46.46 181.56,45.86 U1002.11
$61N21443: length 5.9
  TOP w0.127: R58.1 176.81,53.4 176.15,52.74
  TOP w0.203: 176.15,52.74 176.15,50.8 176.4,50.55 176.75,50.55 177.13,50.16 177.42,50.16 177.66,49.92 U1002.20
$62N1670: length 3.6
  TOP w0.381: Q1102.4 218.74,40.58 219.18,41.02 219.18,41.73 219.56,42.11 R1103.2 R1107.1
$62N1671: length 2.8
  TOP w0.203: Q1105.1 224.68,56.01 224.94,55.75 C1105.1 R1104.2
$62N1672: length 10.8
  TOP w0.381: R1101.2 219.46,55.75 v1(218.95,55.24) ; Q1103.4 218.21,48.23 218.82,47.62 v1(219.2,47.62) 219.47,47.35 R1111.2
  BOTTOM w0.381: v1(218.95,55.24) 218.95,47.87 v1(219.2,47.62)
$62N1673: length 3.8
  TOP w0.381: Q1101.4 225.58,48.54 227.1,50.06 R1108.2 R1110.2
$62N1674: length 1
  TOP w0.381: R1110.1 C1103.2
$62N1675: length 1.1
  TOP w0.381: C1104.2 R1111.1
$62N1681: length 0.8
  TOP w0.381: C1101.1 R1109.2
$62N1682: length 0.8
  TOP w0.381: C1102.1 R1107.2
$62N1688: length 3.8
  TOP w0.381: Q1104.4 226.43,40.58 226.82,40.97 226.82,41.73 227.2,42.11 R1102.2 R1109.1
$62N1689: length 3.2
  TOP w0.203: R1116.2 210.02,56.64 C1106.1 209.75,55.68 209.81,55.62 Q1106.1
$62N1690: length 2.6
  TOP w0.203: R1119.2 C1108.1 216.26,55.5 Q1107.1
$62N1691: length 4
  TOP w0.203: R1118.1 R1115.1 210.54,57.66 211.2,57 211.2,56.79 R1116.1 211.84,56.64 211.96,56.51 Q1107.3
$63N1348: length 4.8
  TOP w0.203: U3001.10 26.43,172.83 25.68,173.58 25.68,175.31 R3006.1 25.88,176.48 R3001.1
$63N1354: length 2.3
  TOP w0.203: U3001.1 26.43,168.44 26.26,168.6 25.53,168.6 R3022.2
$63N1355: length 0.9
  TOP w0.203: R3021.2 R3020.1
$63N1356: length 1.4
  TOP w0.406: C3008.2 C3006.1
$63N1361: length 3.7
  TOP w0.203: C3002.1 C3009.1 28.71,166.23 27.93,167.01 U3001.4
$63N1362: length 3.5
  TOP w0.203: U3001.3 27.43,166.95 26.72,166.24 R3020.2 C3011.1
$63N1363: length 1.1
  TOP w0.203: R3007.1 30.81,174.01 30.85,173.98 C3003.2
$63N1366: length 2.7
  TOP w0.406: 12.32,174.06 12.32,173.86 12.83,173.35 13.54,173.35 13.94,172.95 R3009.2
$63N1373: length 5.3
  TOP w0.203: R3003.1 R3010.2 24.92,165.58 24.85,165.65 C3004.2 26.08,166.18 26.93,167.03 U3001.2
$63N6227: length 2.2
  TOP w0.203: U3002.2 4.28,135.27 4.48,135.06 4.92,135.06 5.12,134.86 R3015.2
$63N6228: length 1.8
  TOP w0.203: R3014.2 4.22,134.74 3.78,135.19 U3002.1
$63N6229: length 4
  TOP w0.203: R3017.2 7.21,136.07 6.74,136.07 6.41,136.4 6.41,137.11 6.21,137.31 5.92,137.31 5.78,137.17 U3002.5
$63N6230: length 3.4
  TOP w0.203: U3002.10 3.78,142.46 3.75,142.49 C3014.1 3.75,143.32 3.94,143.51 R3012.2
$63N6231: length 3.8
  TOP w0.203: R3011.1 4.95,143.53 5.14,143.34 C3014.2 5.14,142.56 4.28,141.69 U3002.9
$63N6232: length 4
  TOP w0.203: R3016.2 6.93,137.44 6.58,137.79 5.48,137.79 5.28,137.59 U3002.4
$63N6233: length 4.9
  TOP w0.203: R3013.1 6.78,143.31 6.78,142.79 6.79,142.77 C3015.1 6.13,142.09 5.28,142.09 4.78,141.58 U3002.8
$63N33494: length 3.7
  TOP w0.203: U3001.8 27.43,173.52 28.13,174.22 C38.2 28.13,174.79 27.76,175.16 R86.1
$63N39199: length 1.1
  TOP w0.203: C3010.2 24.56,175.96 24.61,175.91 C81.1
$63N39814: length 1.7
  TOP w0.203: R132.1 30.87,175.89 30.67,176.1 30.67,176.67 30.62,176.72 C3001.2
$64N2060: length 18
  TOP w0.203: v1(99.06,44.7) 98.11,43.75 R2101.2 ; U2101.1 112.41,46.87 113.06,46.23 v1(113.06,46.13)
  ART03 w0.178: v1(113.06,46.13) 112.49,45.56 108.42,45.56 107.96,45.09 99.45,45.09 v1(99.06,44.7)
$64N79526: length 3.5
  TOP w0.203: Q2101.3 57.53,41.15 C79.1 57.48,41.76 58.18,42.45 R88.1
$64N90990: length 1.3
  TOP w0.203: R189.2 121.43,40.07 U2101.40
$64N121818: length 4.1
  TOP w0.203: R223.2 97.46,51.31 97.12,50.96 R224.2 C121.1 95.69,50.99 X2.3
$64N121819: length 11.6
  TOP w0.203: R224.1 v1(97.12,48.77) 97.17,48.72 R222.2 ; v1(92.22,47.61) C122.1 92.17,48.5 X2.1 91.91,48.78 R206.2
  ART03 w0.178: v1(97.12,48.77) 96.82,49.06 94.98,49.06 93.52,47.61 v1(92.22,47.61)
$64N128273: length 2.6
  TOP w0.203: X2.4 91.95,51.22 R207.2 90.19,51.22 R221.2
$64N151332: length 13.2
  TOP w0.203: v1(114.55,39.88) 115.57,39.88 115.89,39.56 U2101.28 ; U2101.10 112.3,43.27 112.65,42.93 v1(112.65,40.89) 112.63,40.87 U2101.16 ; R337.2 v1(111.1,37.19)
  ART04 w0.203: v1(112.65,40.89) 113.67,39.88 v1(114.55,39.88)
  BOTTOM w0.203: v1(111.1,37.19) 111.1,38.07 112.65,39.62 v1(112.65,40.89)
$65N2030: length 14.6
  TOP w0.203: R3601.2 53.82,16.69 54.08,16.43 C3601.1 54.08,15.53 50.74,12.19 50.74,7.68 49.56,6.51 LED3602.4
$65N2031: length 12.9
  TOP w0.203: R3602.2 51.71,16.95 51.88,16.79 51.88,16.38 51.97,16.29 C3602.1 51.97,14.38 50.04,12.45 50.04,7.75 49.7,7.41 LED3602.3
$65N2035: length 2.7
  TOP w0.203: Q3601.1 54.99,22.25 C3604.1 R3605.2
$65N2036: length 2.6
  TOP w0.203: R3606.2 C3605.1 51.31,22.63 Q3602.1
$65N3589: length 18.7
  TOP w0.203: R3620.1 36.89,18.35 R3607.2 36.16,19.26 35.69,18.8 D3601.1
  TOP w0.508: S3601.2 26.95,11.35 26.95,14.05 28.32,15.42 32.55,15.42 34.07,16.94 D3601.1
$65N5635: length 5
  TOP w0.203: LED3601.3 69.22,7.41 69.74,7.94 C3607.1 71.76,7.05 R3609.2
$65N5639: length 2.9
  TOP w0.203: R3608.2 69.44,6.5 69.44,6.51 LED3601.4
$65N6291: length 9.9
  TOP w0.203: R3621.1 R3613.2 19.3,25.15 20.57,23.88 20.57,19.91 21.01,19.48
  TOP w0.406: D3602.1 v1(20.45,18.8)
  vias: v1(20.45,18.03)
$65N14395: length 12.7
  TOP w0.203: R3614.2 C3611.1 59.59,15.16 59.59,7.14 58.96,6.51 LED3603.4
$65N14396: length 11.3
  TOP w0.203: LED3603.3 58.6,7.41 59.18,8 59.18,15.09 58.45,15.82 C3612.1 R3615.2
$65N14399: length 2.8
  TOP w0.203: Q3605.1 62.23,22.15 62,22.38 C3614.1 R3618.2
$65N14400: length 2.8
  TOP w0.203: R3619.2 C3615.1 58.32,22.41 58.67,22.06 Q3606.1
$65N31335: length 2.7
  TOP w0.203: Q3604.1 73.71,12.01 C3610.1 R3611.2
$66N179178: length 3.6
  TOP w0.203: U2904.10 62.69,151.43 62.31,151.82 R2921.1
$66N179179: length 2.3
  TOP w0.203: R2922.2 61.24,144.25 62.19,145.2 U2904.14
$66N179181: length 4.1
  TOP w0.203: U2903.14 80.55,145.85 80.35,146.05 80.06,146.05 78.94,144.93 78.15,144.93 77.67,144.46 R2923.2
$66N179183: length 2.3
  TOP w0.203: U2904.18 64.19,144.95 64.26,144.88 64.26,144.86 64.97,144.14 64.97,143.79 R2931.2
$66N179184: length 2.4
  TOP w0.203: U2904.19 64.69,145.27 64.77,145.19 64.77,144.93 65.66,144.04 65.66,143.96 R2930.2
$66N179185: length 3
  TOP w0.203: U2904.20 65.19,145.1 65.94,144.35 66.55,144.35 66.75,144.14 R2929.2
$66N179186: length 3.4
  TOP w0.203: R2928.2 67.64,144.27 67.16,144.75 66.12,144.75 65.69,145.18 U2904.21
$66N179206: length 2
  TOP w0.203: U2903.18 82.55,145.14 81.79,144.37 R2934.2
$66N179207: length 1.8
  TOP w0.203: U2903.19 83.05,144.72 82.64,144.31 R2935.2
$66N179210: length 1.7
  TOP w0.203: U2903.20 83.55,144.31 83.5,144.25 R2936.2
$66N179211: length 1.8
  TOP w0.203: R2937.2 84.35,144.58 84.05,144.88 U2903.21
$66N179213: length 1.9
  TOP w0.203: R2938.1 83.31,150.7 83.05,150.44 U2903.6
$66N179214: length 2.1
  TOP w0.203: U2903.5 83.55,149.95 R2939.1
$66N179215: length 4
  TOP w0.203: U2903.4 84.05,149.51 85.48,150.93 86.76,150.93 R2940.1
$66N179216: length 3.3
  TOP w0.203: R2941.1 86.66,150.39 85.51,150.39 84.55,149.44 U2903.3
$66N179223: length 2.4
  TOP w0.203: U2903.2 85.05,149.34 85.32,149.61 86.13,149.61 86.4,149.33 R2932.2
$66N179232: length 2.5
  TOP w0.203: R2942.2 67.31,150.24 66.69,149.62 U2904.2
$66N179233: length 2.1
  TOP w0.203: U2904.15 62.69,144.88 62.31,144.5 R2948.2
$66N179234: length 3.2
  TOP w0.203: R2949.2 79.81,145.14 80.79,145.14 81.05,145.4 U2903.15
$66N179235: length 1.9
  TOP w0.203: R2946.2 63.2,144.27 63.19,144.28 U2904.16
$66N179236: length 2.9
  TOP w0.203: R2947.2 79.76,144.42 80.06,144.73 80.96,144.73 81.55,145.32 U2903.16
$66N179237: length 2.1
  TOP w0.203: U2903.17 82.05,145.25 80.91,144.1 R2945.2
$66N179250: length 3.4
  TOP w0.203: R2952.1 63.19,152.37 U2904.9
$66N179251: length 4.3
  TOP w0.203: U2903.10 81.05,149.3 80.85,149.51 80.23,149.51 78.87,148.14 78.87,147.83 78.62,147.58 R2956.1
$66N179252: length 2.1
  TOP w0.203: R2954.1 81.53,150.75 82.05,150.23 U2903.8
$66N179253: length 4.8
  TOP w0.203: R2955.1 78.16,148.61 78.76,148.61 80.06,149.91 81.33,149.91 81.55,149.69 U2903.9
$66N179254: length 3.5
  TOP w0.203: U2903.7 82.55,150.9 82.14,151.31 82.14,151.54 81.92,151.76 R2953.1
$66N182594: length 2.3
  TOP w0.203: Q2901.1 23.52,135.08 23.51,135.09 23.05,135.09 R2985.2 22.94,135.2 C2921.1
$66N182597: length 8.1
  TOP w0.203: R198.1 R199.1 R2984.1 R2983.1 R2988.1 27.23,133.5 Q2901.3
$66N371722: length 3
  TOP w0.203: U16.10 164.82,41.27 165.35,41.81 165.35,42.65 165.64,42.93 R67.1
$66N371723: length 3.6
  TOP w0.203: U16.14 160.93,42.4 160.2,43.13 159.74,43.13 158.92,43.95 R68.2
$66N371725: length 3.4
  TOP w0.203: 159.64,52.96 160.96,52.96 161.31,52.61 U15.14
$66N371727: length 1.7
  TOP w0.203: R103.2 159.75,40.38 160.35,39.77 U16.18
$66N371729: length 1.7
  TOP w0.203: U16.20 160.13,38.77 159.55,38.18 R71.2
$66N371730: length 1.9
  TOP w0.203: U16.21 160.51,38.27 160.28,38.05 160.28,38.05 159.72,37.48 159.72,37.48 159.69,37.46 159.69,37.43 R70.2
$66N371746: length 1.8
  TOP w0.203: 159.64,48.73 160.08,48.73 160.37,49.02 U15.18
$66N371747: length 2
  TOP w0.203: U15.19 160.58,48.52 159.78,47.72 159.64,47.72
$66N371750: length 2.4
  TOP w0.203: U15.20 160.87,48.02 159.74,46.89 159.74,46.71 159.64,46.61
$66N371751: length 2.9
  TOP w0.203: 159.64,45.55 160.15,46.06 160.15,46.72 160.95,47.52 U15.21
$66N371753: length 1.8
  TOP w0.203: U15.6 165.6,48.52 165.71,48.41 R124.1
$66N371754: length 2.4
  TOP w0.203: U15.5 165.38,48.02 166.32,47.07 R138.1
$66N371755: length 2.8
  TOP w0.203: R139.1 165.56,46.55 165.56,47.04 165.08,47.52 U15.4
$66N371756: length 3.6
  TOP w0.203: R140.1 166.32,44.75 165.13,45.95 165.13,46.86 164.97,47.02 U15.3
$66N371763: length 2.1
  TOP w0.203: R107.2 165.02,45.16 164.57,45.61 U15.2
$66N371772: length 3.2
  TOP w0.203: R141.2 164.72,34.77 164.92,34.98 164.92,36.09 164.19,36.83 U16.2
$66N371773: length 3.1
  TOP w0.203: U16.15 160.61,41.27 160.38,41.5 160.38,42.27 160.17,42.47 159.34,42.47 R148.2
$66N371774: length 2.6
  TOP w0.203: 159.64,51.9 160.16,51.9 160.76,51.31 160.76,50.67 160.91,50.52 U15.15
$66N371775: length 5.7
  TOP w0.203: U16.16 160.52,40.77 159.97,41.33 159.97,41.81 159.77,42.01 157.07,42.01 156.59,42.49 156.59,42.9
$66N371776: length 2
  TOP w0.203: U15.16 160.83,50.02 160,50.84 159.64,50.84
$66N371777: length 1.8
  TOP w0.203: U15.17 160.74,49.52 160.48,49.78 159.64,49.78
$66N371787: length 2.3
  TOP w0.203: R158.1 164.91,40.77 U16.9
$66N371788: length 3.7
  TOP w0.203: R164.1 166.23,52.76 165.41,52.76 165.13,52.48 165.13,50.72 164.92,50.52 U15.10
$66N371789: length 2.3
  TOP w0.203: R160.1 166.29,50.62 165.19,49.52 U15.8
$66N371790: length 3.1
  TOP w0.203: R161.1 165.76,51.79 165.56,51.59 165.56,50.49 165.08,50.02 U15.9
$66N371796: length 2
  TOP w0.203: U15.7 165.27,49.02 165.98,49.72 R159.1
$66N371797: length 1.8
  TOP w0.203: U16.7 165.98,39.77 R166.1
$66N380792: length 2.1
  TOP w0.203: R205.1 165.47,40.27 U16.8
$66N381197: length 2
  TOP w0.203: R218.1 165.49,39.27 U16.6
$66N382007: length 2.8
  TOP w0.203: U16.4 164.85,38.27 165.48,37.64 165.48,37.17 R220.1
$66N382412: length 3.4
  TOP w0.203: U16.3 164.69,37.77 164.97,37.49 164.97,36.78 165.43,36.32 165.43,35.86 165.72,35.58 R237.1
$66N382709: length 2.1
  TOP w0.203: U2904.17 63.69,144.67 64.08,144.27 R274.2
$66N382710: length 3.5
  TOP w0.203: R275.1 64.55,152.05 64.19,151.69 U2904.7
$66N465451: length 1.5
  TOP w0.203: U16.19 159.51,39.27 R288.2
$66N465452: length 2.3
  TOP w0.203: R290.1 164.94,38.77 U16.5
$67N1252: length 3.7
  TOP w0.203: Q3502.1 30.05,149.22 30.02,149.25 C3510.1 29.52,149.73 29.59,149.81 R3506.1 R3505.2
$67N1255: length 4.3
  TOP w0.203: R3502.1 35.26,150.24 35.72,149.77 36.21,149.77 Q3501.4 36.2,149.87 36.2,150.68 C3506.1 R3504.1
$67N1256: length 4.9
  TOP w0.203: Q3502.3 33.33,148.21 33.99,148.88 33.99,149.85 33.73,150.11 33.25,150.11 R3503.2 32.99,150.57 33.7,150.57 33.9,150.77 R3504.2
$67N25225: length 3.3
  TOP w0.203: C3523.1 23.37,138.66 23.41,138.71 Q3503.1 ; C3523.1 R3540.1 ; C3523.1 R3539.2
$67N25229: length 2.9
  TOP w0.203: Q3503.3 26.8,137.69 27.48,137.01 R3538.2 28.07,137.64 R3537.2
$67N65911: length 1
  TOP w0.203: C3502.1 34.69,148.4 R3502.2
$71N1685: length 1.7
  TOP w0.203: R3201.2 163.59,64.06 163.81,64.28 U1.22
$71N1693: length 2.5
  TOP w0.203: U1.16 166.71,67.91 R3222.1
$71N1694: length 13.2
  TOP w0.203: J1.1 169.01,61.29 v1(169.27,61.29)
  TOP w0.305: 167.36,67.59 U1.15 ; v1(169.96,67.82) U1.11
  TOP w0.381: v1(169.96,67.82) 169.96,68.66 169.64,68.99 R3223.2 169.08,68.32 168.63,67.87 167.64,67.87 167.36,67.59
  ART03 w0.508: v1(169.27,61.29) 169.96,61.99 v1(169.96,67.82)
$71N1695: length 1.3
  TOP w0.203: R3223.1 169.05,69.77 R3222.2
$71N10807: length 3.4
  TOP w0.203: C3213.2 158.16,63.71 Q3201.1 158.16,61.65 158.31,61.5 158.31,61.05 R3205.2
$71N10810: length 7.5
  TOP w0.254: C3214.2 156.13,62.17 156.13,61.29 156.6,60.82 R3203.1 156.26,60.48 156.03,60.25 156.03,58.8 R3204.2 156.13,58.47 156.44,58.16 Q3202.4 155.7,57.53 155.32,57.91 R1.1
$71N10812: length 1.8
  TOP w0.203: Q3201.3 157.66,60.55 156.77,59.66 R3203.2
$71N22877: length 5.4
  TOP w0.203: U5.2 197.12,25.08 197.37,25.34 197.37,26.15 197.17,26.35 ; 197.17,26.35 197.3,26.35 197.49,26.54 197.49,27.91 R3217.1 ; 197.17,26.35 U5.1
$71N22878: length 3.2
  TOP w0.203: R3220.2 R3218.2 195.16,23.81 U5.3
$71N22879: length 1
  TOP w0.203: R3219.2 194.31,22.05 R3218.1
$71N29605: length 0.8
  TOP w0.381: R1.2 C109.1
$71N32366: length 3
  TOP w0.203: U3201.3 25.86,48.41 26.06,48.21 R3208.1 ; R3208.1 C3222.1 ; R3208.1 R3214.1
$71N32367: length 2.6
  TOP w0.203: C3215.1 27.31,53.11 27.05,52.86 25.93,52.86 25.86,52.78 U3201.13
$71N32368: length 2.3
  TOP w0.203: U3201.14 25.36,52.99 25.48,53.11 R3213.1 25.5,53.57 C3224.1
$71N36219: length 2.2
  TOP w0.203: R3211.1 24.31,47.07 24.33,47.04 C3222.2 R3208.2
$71N37634: length 4.3
  TOP w0.406: U3202.1 63.76,38.79 62.82,37.85 D15.3
$73N2320: length 5.1
  TOP w0.203: R3404.2 17.55,92.95 17.99,92.52 U10.7 17.98,91.66 17.98,90.74 18.3,90.43 19.06,90.43 19.81,89.68 R3419.1
$73N2325: length 11.2
  TOP w0.203: U3402.4 13.17,54.27 13.02,54.42 C3403.2 12.87,54.93 12.14,54.2 R3401.2 11.68,53.52 11.74,53.47 R3409.1 R3416.1 R3411.1 9.47,52.98 9.25,52.76 9.25,51.7 9.98,50.98 D3401.2
$73N2326: length 2.3
  TOP w0.203: R3426.1 R3405.2 18.49,87.4 U10.3
$73N2329: length 2
  TOP w0.203: R3406.1 17.51,54.72 16.98,54.19 U3402.1
$73N2330: length 1
  TOP w0.203: R3407.2 R3401.1
$73N2331: length 8.5
  TOP w0.203: U3402.7 15.71,47.21 14.99,46.48 14,46.48 R3410.1 13.49,45.49 12.75,44.75 10.36,44.75 9.98,45.14 D3401.1
$73N2332: length 6.6
  TOP w0.203: Q3401.1 18.47,84.47 20.18,82.76 Q3402.3 21.06,82.04 19.89,80.87 R3412.2
$73N2333: length 5.5
  TOP w0.203: Q3402.1 22.02,85 C3401.1 R3413.2
$73N2338: length 1.1
  TOP w0.203: R3415.1 11.68,51.64 11.74,51.69 R3409.2
$73N2339: length 1.1
  TOP w0.203: R3415.2 R3414.1
$73N4160: length 16.7
  TOP w0.203: D3402.1 41.1,18.54 40.68,18.12 R3425.1 40.2,19.21 R3422.2
  TOP w0.406: S3401.2 37.59,11.16 37.59,15.11 38.61,16.13 41.85,16.13 42.26,16.53 42.29,16.53 42.76,17 D3402.1

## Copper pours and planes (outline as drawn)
AGND_AUDIO on TOP: 209.96,13.51 207.75,13.51 207.49,13.77 206.88,13.77 206.73,13.92 206.73,14.4 207.06,14.73 208.59,14.73 208.93,15.07 208.93,16.65 208.99,16.71 210.26,16.71 210.39,16.59 210.39,13.94 ; 4 cut-outs
AGND_AUDIO on TOP: 186.16,26.09 189.38,26.09 190.32,25.15 190.32,24.46 190.17,24.31 189.61,24.31 189.28,23.98 189.28,23.8 187.99,22.5 186.31,22.5 186.04,22.24 186.04,22.21 185.8,21.97 185.78,21.97 185.74,21.93 183.58,21.93 183.41,21.77 183.41,21.44 181.92,19.94 181.92,17.5 181.66,17.25 181.2,17.25 181,17.45 181,20.34 181.86,21.21 181.86,21.77 182.12,22.02 183.03,22.02 183.41,22.4 185.73,22.4 185.93,22.61 185.93,22.99 186.32,23.38 188.46,23.38 188.7,23.62 188.7,24.56 189.23,25.09 189.23,25.4 189.13,25.5 188.85,25.5 188.32,24.97 187.71,24.97 187.55,25.12 187.55,25.6 187.38,25.78 186.49,25.78 185.6,24.89 183.31,24.89 183.19,25.02 183.19,25.55 183.31,25.68 185.75,25.68 ; 3 cut-outs
AGND_AUDIO on TOP: 55.58,121.79 57.46,123.67 61.39,123.67 61.8,123.27 61.8,120.57 60.83,119.61 55.65,119.61 55.58,119.68
AGND_AUDIO on TOP: outline of 107 points within 186.06,1.6 215.67,22.99 ; 7 cut-outs
AGND_AUDIO on ART02: 178.99,25.74 189.31,25.74 189.76,25.29 189.81,25.26 189.87,25.25 191.71,25.25 192.93,24.02 192.95,24.01 192.97,23.99 193.29,23.67 201.54,23.67 203.73,21.48 203.78,21.45 203.84,21.44 215.2,21.44 215.75,20.89 215.75,0.8 215.57,0.59 215.3,0.51 211.39,0.51 211.06,0.63 210.56,1.56 209.9,1.81 207.6,1.81 206.94,1.56 206.6,0.93 206.44,0.63 206.11,0.51 198.39,0.51 198.06,0.63 197.9,0.93 197.56,1.56 196.9,1.81 194.6,1.81 193.94,1.56 193.6,0.93 193.44,0.63 193.11,0.51 186.21,0.51 186.21,6.29 187.43,7.51 187.47,7.56 187.48,7.62 187.48,13.97 187.47,14.03 187.43,14.08 185.53,15.98 185.48,16.02 185.42,16.03 177.86,16.03 177.32,16.57 177.32,19.62 177.91,20.21 177.94,20.26 177.95,20.32 177.95,24.7
AGND_AUDIO on ART03: 57.38,124.08 59.21,124.08 59.72,124.59 61.52,124.59 61.9,124.21 61.9,124.08 62.74,123.24 62.74,121.77 62.41,121.44 61.9,121.44 61.9,121.06 61.39,120.55 57.63,120.55 56.67,121.51 56.67,123.37
AVDDH on TOP (solid shape): 123.52,159.08 123.52,158.55 123.29,158.32 123.29,157.12 123.42,157 124.87,157 125.02,156.84 125.02,156.62 124.89,156.49 122.53,156.49 122.35,156.67 122.35,157.45 123.01,157.45 123.01,157.71 122.53,157.71 122.53,157.45 122.35,157.45 122.35,158.6 122.3,158.65 123.01,158.65 123.01,159.08 122.56,159.08 122.56,158.65 122.3,158.65 122.25,158.7 122.25,159.26 122.33,159.33 123.27,159.33
AVDDH on TOP (solid shape): 131.19,145.24 131.19,145.14 131.14,145.08 129.74,145.08 128.65,143.99 128.65,143.76 128.65,143.73 128.66,143.67 128.67,143.64 128.67,142.6 129.16,142.11 129.16,139.52 129.29,139.39 129.95,139.39 130.23,139.67 130.23,140.03 130.3,140.11 130.86,140.11 130.91,140.06 130.91,138.61 130.89,138.58 130.43,138.58 130.4,138.61 130.4,138.71 130.2,138.91 130.78,138.91 130.78,139.72 130.56,139.72 130.56,138.91 130.2,138.91 130.15,138.96 129.16,138.96 128.88,139.24 128.88,141.27 128.73,141.43 126.34,141.43 125.88,140.97 125.88,139.37 125.86,139.34 125.7,139.34 125.68,139.37 125.68,142.06 126.95,143.33 126.95,144.83 127.41,145.29 131.14,145.29
AVDDH on TOP: 115.09,154.2 115.77,154.2 115.77,153.87 115.75,153.85 114.27,153.85 114.12,153.69 114.12,153.06 114.3,152.88 115.72,152.88 115.72,152.7 113.67,152.7 113.3,153.07 113.3,153.86 113.18,153.97 109.19,153.97 109.07,154.1 109.07,154.66 109.53,155.12 114.17,155.12 ; 3 cut-outs
AVDDL on TOP: 116.13,155.04 116.46,154.71 117.32,154.71 117.4,154.63 118.21,154.63 118.31,154.53 118.31,153.72 117.81,153.21 116.21,153.21 115.95,153.47 115.95,154.18 115.62,154.51 113.92,154.51 113.11,155.32 111.23,155.32 110.92,155.63 110.92,156.31 110.97,156.36 112.65,156.36 112.67,156.34 115.72,156.34 116.13,155.93 ; 5 cut-outs
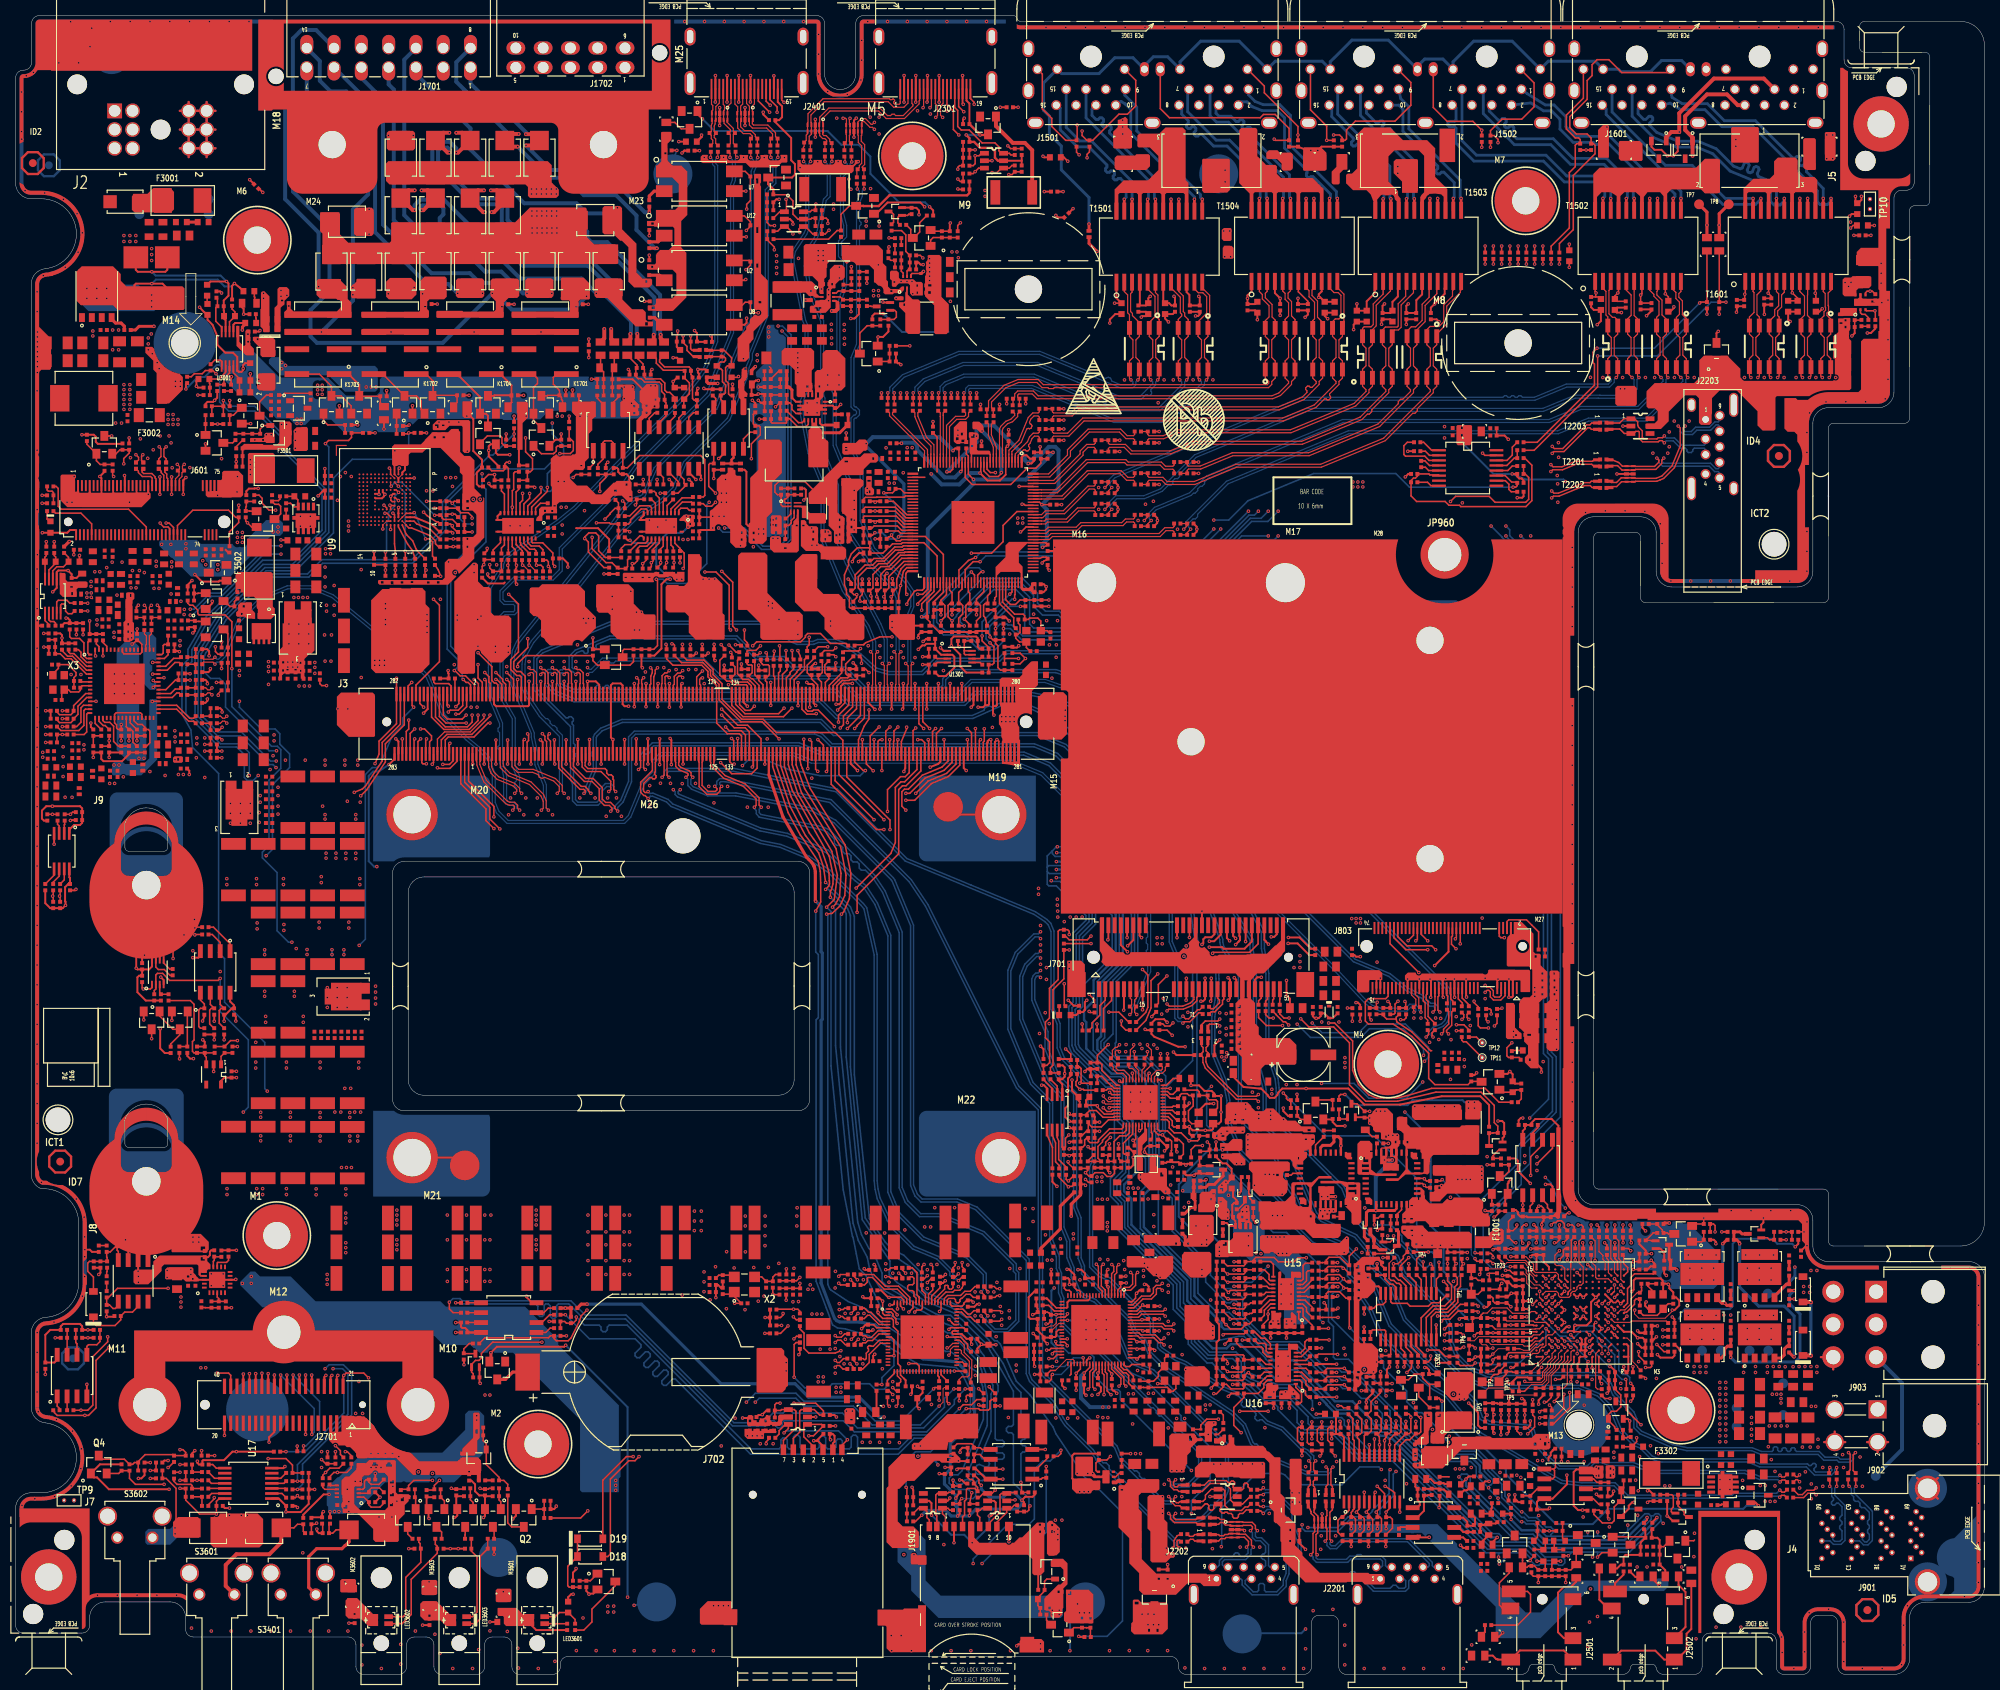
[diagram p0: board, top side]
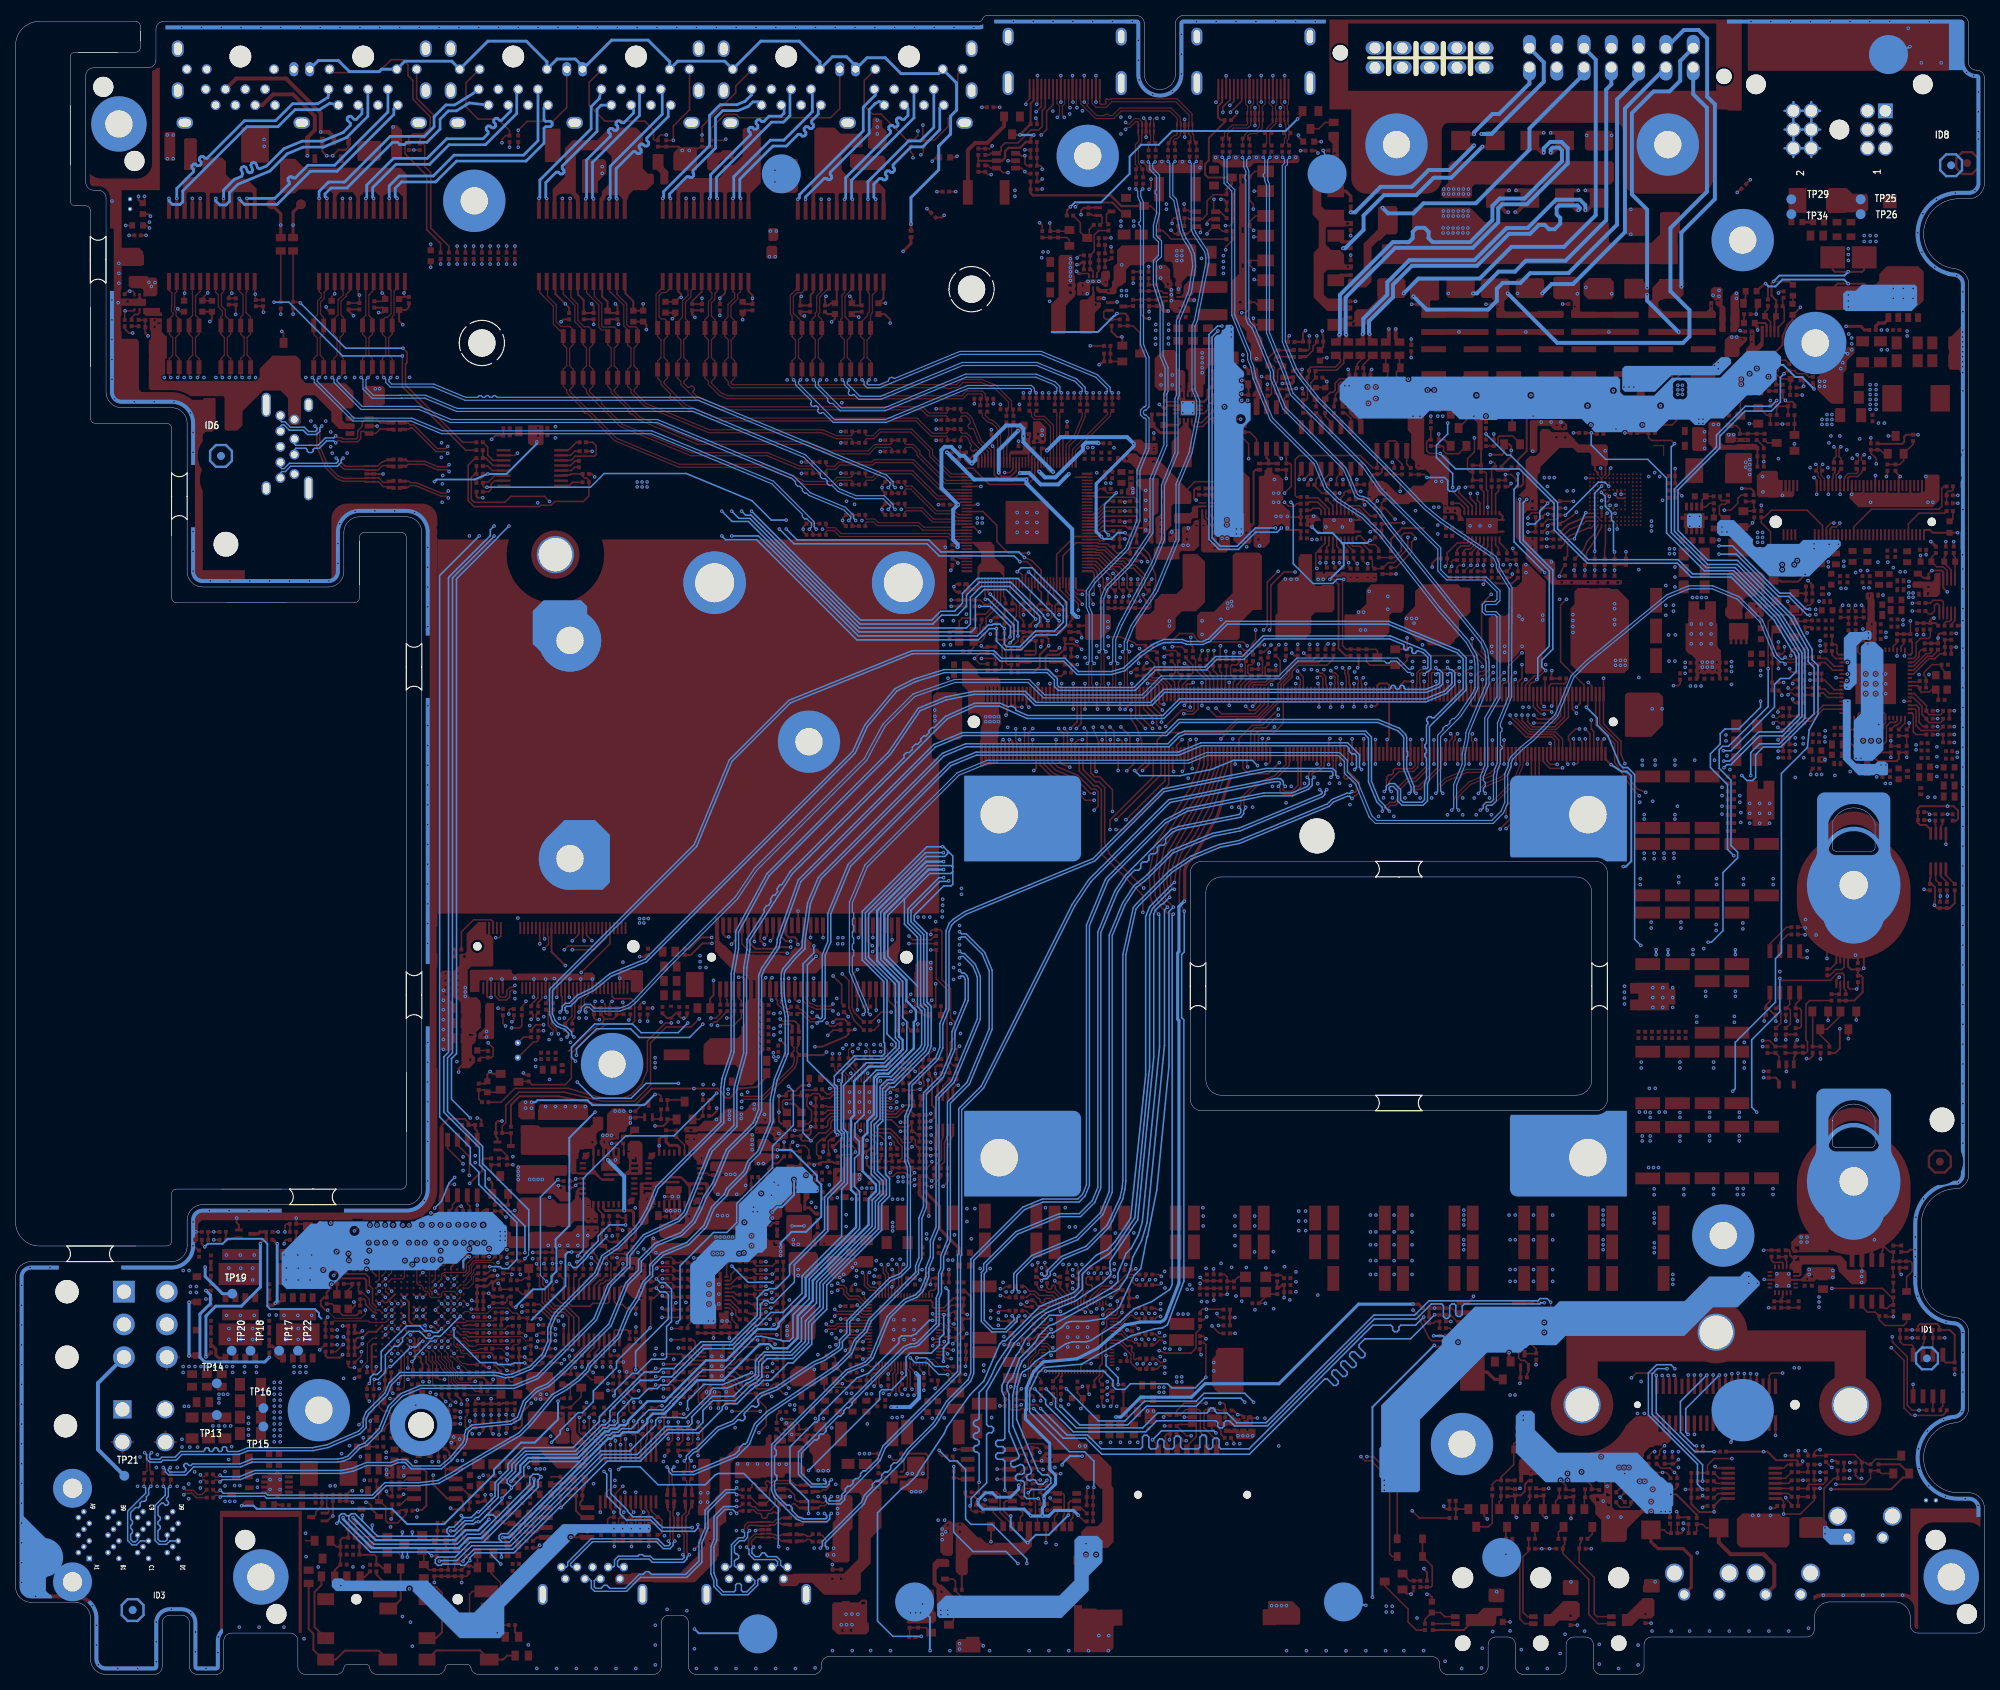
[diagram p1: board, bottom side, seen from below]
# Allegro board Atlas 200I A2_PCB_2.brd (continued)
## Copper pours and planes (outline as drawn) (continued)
DVDDL on TOP (solid shape): 109.27,158.14 109.27,157.17 109.07,156.97 108.76,156.97 108.29,156.5 106.2,156.5 106.02,156.67 106.02,156.74 106.68,156.74 106.68,157.12 106.38,157.12 106.38,156.74 106.02,156.74 106.02,157.33 106.65,157.33 106.65,157.68 106.38,157.68 106.38,157.33 106.02,157.33 106.02,157.86 106.15,157.99 107.75,157.99 108.18,158.42 108.99,158.42
GND on TOP (solid shape): 131.9,4.19 131.9,2.81 128.75,2.81 128.75,4.24 129.06,4.55 131.55,4.55
GND on TOP (solid shape): 33.33,166.65 33.33,164.97 33.07,164.72 31.22,164.72 30.96,164.97 30.96,166.65 31.22,166.9 33.07,166.9
GND on TOP (solid shape): 37.49,159.82 37.49,157.12 37.31,156.95 35.74,156.95 35.66,157.02 35.66,159.61 36.04,159.99 37.31,159.99
GND on TOP (solid shape): 115.32,135.89 115.32,132.84 115.19,132.71 113.41,132.71 112.01,134.11 112.01,135.76 112.27,136.02 115.19,136.02
GND on TOP (solid shape): 137.13,91.08 137.13,90.04 137.16,90.02 137.16,87.12 136.93,86.89 134.87,86.89 134.87,91.57 136.65,91.57
GND on TOP (solid shape): 156.21,183.01 156.21,181.74 156.08,181.61 154.94,181.61 154.81,181.74 154.81,183.01 155.07,183.26 155.96,183.26
GND on TOP (solid shape): 207.92,165 207.92,162.94 207.72,162.74 205.41,162.74 205.16,162.99 205.16,165.02 205.44,165.3 207.62,165.3
GND on TOP (solid shape): 46.08,125.68 46.08,120.37 45.97,120.27 42.72,120.27 41.2,121.79 41.2,125.42 41.73,125.96 45.8,125.96
GND on TOP (solid shape): 91.87,8.37 92.56,8.37 92.56,6.65 92.28,6.37 87.96,6.37 87.76,6.58 87.76,8.41 88.75,9.4 91.87,9.4
GND on TOP (solid shape): 115.7,15.24 116.84,15.24 116.84,14.1 114.94,14.1 114.81,14.22 114.81,15.42 114.97,15.58 115.35,15.58
GND on TOP (solid shape): 134.84,125.54 134.84,120.61 134.14,119.91 131.39,119.91 131.12,120.19 131.14,120.22 131.14,125.32 131.83,126.01 134.37,126.01
GND on TOP (solid shape): 185.42,72.9 185.42,71.12 179.45,71.12 179.07,71.5 179.07,72.9 179.32,73.15 185.17,73.15
GND on TOP (solid shape): 157.73,66.06 157.73,65.4 157.63,65.3 156.31,65.3 155.55,66.06 154.81,66.06 154.58,66.29 154.58,66.73 154.69,66.83 156.97,66.83
GND on TOP (solid shape): 153.16,38.84 153.16,37.26 152.86,36.96 150.01,36.96 149.94,37.03 149.94,39.42 150.03,39.51 151.65,39.51 151.69,39.55 152.45,39.55
GND on TOP (solid shape): 175.29,89.97 175.29,89.13 175.23,89.08 173.69,89.08 173.61,89 173.61,87.68 173.43,87.5 172.24,87.5 172.03,87.71 172.03,90.17 172.21,90.35 174.9,90.35
GND on TOP (solid shape): 226.3,5.3 225.93,5.3 225.9,5.33 225.9,20.2 216.2,20.2 216.2,5.33 216.17,5.3 215.8,5.3 215.8,21 226.3,21
GND on TOP (solid shape): 164.94,27.53 164.94,23.92 164.91,23.89 164.91,21.78 165,21.69 165,20.52 164.87,20.39 163.84,20.39 163.5,20.73 163.5,23.69 163.39,23.8 163.39,27.55 163.48,27.64 164.83,27.64
GND on TOP (solid shape): 153.37,53.97 153.37,51.69 152.58,50.9 150.7,50.9 149.58,52.02 149.58,53.83 149.74,53.98 149.83,54.17 149.84,54.2 153.14,54.2
GND on TOP (solid shape): 154.05,32.38 154.05,32 153.92,31.88 153.67,31.88 153.42,31.62 153.42,29.84 152.53,29.84 152.53,30.48 152.4,30.61 151.77,30.61 151.77,30.99 152.4,30.99 152.53,31.11 152.53,32.13 152.89,32.49 153.95,32.49
GND on TOP (solid shape): 116.75,8.18 116.75,3.33 116.74,3.33 116.74,2.84 112.21,2.84 111.69,3.36 111.69,6.11 111.53,6.27 110.59,6.27 110.57,6.3 110.57,8.28 110.59,8.31 113.8,8.31 113.96,8.46 116.47,8.46
GND on TOP (solid shape): 148.46,53.57 148.46,51.69 147.47,50.7 146.71,50.7 146.33,51.08 145.92,51.08 144.81,52.2 142.67,52.2 142.49,52.37 142.49,53.52 142.62,53.64 144.35,53.64 144.6,53.39 146.33,53.39 146.63,53.7 148.34,53.7
GND on TOP (solid shape): 32.56,176.78 32.56,172.26 32.49,172.19 32.24,172.19 31.82,172.19 31.72,172.29 31.72,172.58 31.39,172.91 31.39,175.17 31.47,175.17 31.47,177.27 31.62,177.42 31.93,177.42
GND on TOP (solid shape): 147.32,22.75 147.32,19.89 147.73,19.48 147.73,16 148.03,15.7 148.54,15.7 148.69,15.54 148.69,15.14 148.51,14.96 148.14,14.96 147.54,14.36 145.75,14.36 145.53,14.58 145.53,18.35 145.16,18.72 145.16,22.75 145.41,23.01 147.06,23.01
GND on TOP (solid shape): 192.3,85.87 192.3,82.99 192.9,82.38 192.98,82.38 193.15,82.2 193.15,81.55 193.09,81.49 191.34,81.49 191.13,81.7 191.13,81.91 192.88,81.91 192.88,82.11 192.3,82.11 192.3,81.91 191.13,81.91 191.13,86.11 191.15,86.14 192.03,86.14
GND on TOP (solid shape): 96.42,143.56 96.42,138.73 98.83,136.32 100.53,136.32 100.97,135.89 100.97,133.1 100.58,132.71 95.78,132.71 95.5,132.99 95.5,134.85 93.78,136.58 92.68,136.58 92.66,136.6 92.66,143.53 93.04,143.92 96.06,143.92
GND on TOP (solid shape): 98.58,41.53 98.58,40.97 99.06,40.49 99.06,36.99 98.84,36.83 98.75,36.57 98.32,36.14 95.15,36.14 95.02,36.27 95.02,41.78 95.12,41.88 98.22,41.88
GND on TOP (solid shape): 161.93,41.6 161.98,41.55 163.17,41.55 163.2,41.58 163.2,42.34 163.27,42.42 164.36,42.42 164.49,42.29 164.49,41.68 164.47,41.66 163.6,41.66 163.55,41.6 163.55,37.52 163.53,37.49 161.57,37.49 161.54,37.52 161.54,42.37 161.6,42.42 161.93,42.42
GND on TOP (solid shape): 162.31,50.85 162.36,50.8 163.55,50.8 163.58,50.82 163.58,51.59 163.65,51.66 164.74,51.66 164.87,51.54 164.87,50.93 164.85,50.9 163.98,50.9 163.93,50.85 163.93,46.76 163.91,46.74 161.95,46.74 161.93,46.76 161.93,51.56 162.03,51.66 162.31,51.66
GND on TOP (solid shape): 205.16,26.62 205.16,25.3 204.98,25.12 204.01,25.12 203.94,25.2 203.94,25.35 204.65,25.35 204.65,25.68 204.17,25.68 204.17,25.35 203.94,25.35 203.94,26.26 204.65,26.26 204.65,26.54 204.11,26.54 204.11,26.26 203.94,26.26 203.94,26.75 204.01,26.82 204.95,26.82
GND on TOP (solid shape): 24.78,55.49 24.78,54.48 24.64,54.34 24.64,54.15 20.09,54.15 19.99,54.25 19.99,54.38 24.31,54.38 24.31,54.89 23.75,54.89 23.75,54.38 19.99,54.38 19.99,54.97 20.47,55.45 20.73,55.45 20.9,55.63 20.9,55.98 21.18,56.26 21.21,56.26 21.46,56.51 23.75,56.51
GND on TOP (solid shape): 94.11,31.24 94.62,31.24 94.62,31.5 95.25,31.5 95.25,31.24 95.63,31.24 95.63,31.5 96.27,31.5 96.27,31.37 96.65,31.37 96.65,31.5 97.23,31.5 97.23,31.22 97.59,31.22 97.59,31.06 97.49,30.96 96.06,30.96 95.99,30.89 95.99,30.28 95.91,30.2 93.86,30.2 93.47,30.59 93.47,31.5 94.11,31.5
GND on TOP (solid shape): 138.18,27.81 138.18,25.98 138.66,25.5 139.26,25.5 139.41,25.65 139.41,26.16 140.28,26.16 140.28,24.51 139.44,24.51 139.41,24.54 139.41,25.09 139.44,25.12 139.39,25.17 138.28,25.17 138.03,25.42 136.12,25.42 135.89,25.65 135.89,26.01 135.9,26.02 135.9,27.83 136.02,27.94 138.05,27.94
GND on TOP (solid shape): 79.27,139.19 79.27,137.36 80.67,135.97 81.89,135.97 82.07,135.79 82.07,132.97 81.92,132.82 77.19,132.82 76.3,133.71 76.3,135.86 75.97,136.19 74.8,136.19 74.52,136.48 74.53,136.55 74.53,136.62 74.51,136.79 74.45,136.94 74.45,139.7 74.6,139.85 78.61,139.85
GND on TOP (solid shape): 163.4,65.61 163.4,64.64 163.3,64.54 162.76,64.54 162.56,64.34 162.56,63.73 162.97,63.32 163.07,63.32 163.07,61.85 162.56,61.34 159.51,61.34 158.62,62.23 158.62,63.93 162.23,63.93 162.23,64.21 161.67,64.21 161.67,63.93 158.62,63.93 158.62,64.31 158.17,64.77 158.17,65.51 158.47,65.81 163.2,65.81
GND on TOP (solid shape): 98.25,148.56 98.25,146.35 98.17,146.28 97.92,146.28 97.92,146.66 97.41,146.66 97.41,146.28 96.98,146.28 96.85,146.41 96.85,147.24 97.92,147.24 97.92,147.57 97.41,147.57 97.41,147.24 96.85,147.24 96.85,148.16 97.89,148.16 97.89,148.44 97.46,148.44 97.46,148.16 96.85,148.16 96.85,148.54 97,148.69 98.12,148.69
GND on TOP (solid shape): 122.02,160.65 122.02,158.04 121.92,157.94 120.55,157.94 120.4,158.09 121.74,158.09 121.74,158.39 121.31,158.39 121.31,158.09 120.4,158.09 120.32,158.17 120.32,158.27 120.93,158.27 120.93,158.7 120.6,158.7 120.6,158.27 120.32,158.27 120.32,158.95 121.69,158.95 121.69,159.28 121.23,159.28 121.23,158.95 120.32,158.95 120.32,159.97 121.11,160.76 121.92,160.76
GND on TOP (solid shape): 29.18,153.8 29.18,151.28 28.91,151 24.64,151 24.38,151.26 24.38,153.19 24.41,153.21 24.61,153.21 24.64,153.19 24.64,151.79 24.66,151.76 24.87,151.76 24.89,151.79 24.89,153.19 24.92,153.21 25.12,153.21 25.12,151.82 25.37,151.82 25.37,153.21 25.63,153.21 25.63,151.82 25.88,151.82 25.88,153.21 26.34,153.21 26.49,153.36 26.49,154.23 26.52,154.25 26.54,154.25 26.7,154.41 28.58,154.41
GND on TOP (solid shape): 132.98,19.71 132.98,19.68 133,19.63 133.03,19.58 133.06,19.53 133.1,19.49 133.15,19.46 133.2,19.43 133.25,19.42 133.28,19.41 133.92,18.77 133.92,15.7 133.49,15.27 132.47,15.27 132.27,15.47 132.27,18.14 133.06,18.14 133.06,18.49 132.57,18.49 132.57,18.14 132.27,18.14 132.27,19.03 133.06,19.03 133.06,19.28 132.57,19.28 132.57,19.03 132.27,19.03 132.27,19.41 132.57,19.71
GND on TOP (solid shape): 188.29,65.02 188.29,62.03 187.93,61.67 183.62,61.67 182.68,60.73 181.46,60.73 181.36,60.83 181.36,61.85 181.41,61.9 181.84,61.9 181.97,62.03 181.97,62.28 182.73,62.28 182.73,62.59 182.19,62.59 182.19,62.28 181.97,62.28 181.97,62.71 182.02,62.76 183.01,62.76 183.39,63.14 183.39,63.91 183.31,63.98 182.02,63.98 181.74,64.26 181.74,64.41 181.74,65.2 181.86,65.33 187.99,65.33
GND on TOP (solid shape): 31.75,19.94 31.75,16.76 31.27,16.28 25.4,16.28 24.99,16.69 24.99,20.19 25.38,20.19 25.49,20.3 25.61,20.22 25.76,20.19 26.02,20.3 26.17,20.62 26.24,20.65 31.04,20.65
GND on TOP (solid shape): 79.38,165.23 79.38,163.47 79.86,162.99 79.86,161.54 79.78,161.47 78.92,161.47 78.74,161.29 77.72,161.29 77.6,161.42 77.6,161.67 79.63,161.67 79.63,161.95 79.22,161.95 79.22,161.67 77.6,161.67 77.6,162.56 79.6,162.56 79.6,162.84 79.22,162.84 79.22,162.56 77.6,162.56 77.6,163.19 77.85,163.45 77.85,165.1 77.47,165.1 77.47,164.85 77.22,164.85 77.09,164.97 77.09,165.35 77.22,165.48 79.12,165.48
GND on TOP (solid shape): 138.23,10.26 138.23,6.6 138.18,6.55 134.8,6.55 134.59,6.76 136.91,6.76 136.91,6.78 138,6.78 138,7.34 137.72,7.34 137.72,6.78 136.91,6.78 136.91,7.39 136.63,7.39 136.63,6.76 134.59,6.76 134.47,6.88 134.47,7.53 134.48,7.54 134.48,7.91 134.72,8.15 134.72,10.18 135.38,10.18 135.38,10.64 134.98,10.64 134.98,10.18 134.72,10.18 134.72,10.85 134.75,10.87 137.62,10.87
GND on TOP (solid shape): 144.35,9.25 147.55,9.25 147.78,9.02 147.78,5.84 147.07,5.13 143.46,5.13 143.13,5.46 146.58,5.46 146.58,5.84 146.33,5.84 146.33,5.46 143.13,5.46 143.1,5.49 145.49,5.49 145.49,5.84 145.24,5.84 145.24,5.49 143.1,5.49 143.05,5.54 143.05,6.12 143.08,6.14 143.08,6.55 143.28,6.76 143.28,8.99 144.02,8.99 144.02,9.32 143.54,9.32 143.54,8.99 143.28,8.99 143.28,9.47 143.41,9.6 143.99,9.6
GND on TOP (solid shape): 58.32,160.72 58.32,158.52 58.32,156.92 58.09,156.69 57.56,156.69 57.33,156.92 57.33,160.04 57.2,160.17 55.65,160.17 55.09,159.61 53.59,159.61 53.49,159.71 53.49,159.89 54.23,159.89 54.23,159.92 54.99,159.92 54.99,160.32 54.69,160.32 54.69,159.92 54.23,159.92 54.23,160.35 53.8,160.35 53.8,159.89 53.49,159.89 53.49,160.32 54.06,160.89 55.19,160.89 55.19,160.91 58.13,160.91
GND on TOP (solid shape): 181.18,56.79 186.44,56.79 186.74,56.49 186.74,54.71 186.69,54.66 179.3,54.66 178.99,54.97 178.99,55.07 179.76,55.07 179.76,55.32 179.38,55.32 179.38,55.07 178.99,55.07 178.99,55.68 178.82,55.85 178.56,55.85 177.7,56.72 177.7,56.87 179.22,56.87 179.22,57.33 178.92,57.33 178.92,56.87 178.28,56.87 178.28,57.33 177.95,57.33 177.95,56.87 177.7,56.87 177.7,57.45 177.83,57.58 180.39,57.58
GND on TOP (solid shape): 160.26,27.1 160.26,25.27 160.13,25.15 157.08,25.15 156.88,25.35 153.88,25.35 153.89,25.42 153.51,25.8 153.12,25.42 153.13,25.35 151.28,25.35 151.23,25.4 151.23,26.5 152,27.28 160.08,27.28
GND on TOP (solid shape): 17.77,170.06 18.37,168.59 19.5,167.46 20.23,167.08 21.03,166.86 21.46,166.43 21.45,166.42 21.45,164.81 19.69,163.04 18.19,163.04 18.09,163.14 18.09,166.95 17.65,167.39 17.65,168.53 16.64,169.54 16.64,170.31 17.53,170.31
GND on TOP (solid shape): 166.22,55.35 169.8,55.35 170.66,56.21 170.82,56.21 171.02,56.01 171.02,54.15 170.65,53.78 170.07,53.78 170.05,53.77 166.17,53.77 165.94,54 163.73,54 163.35,53.62 161.93,53.62 161.54,54 161.46,54 161.14,54.18 160.81,54 160.2,54 160.06,54.14 159.99,54.24 159.88,54.32 159.59,54.61 159.59,56.16 159.79,56.36 165.2,56.36
GND on TOP (solid shape): 198.02,90.04 198.02,89.36 197.99,89.36 197.99,80.21 197.74,79.96 196.72,79.96 196.34,80.34 196.34,86.11 196.75,86.51 196.75,87.12 197.46,87.12 197.46,87.38 196.98,87.38 196.98,87.12 196.75,87.12 196.75,88.01 197.46,88.01 197.46,88.26 196.98,88.26 196.98,88.01 196.75,88.01 196.75,88.9 197.46,88.9 197.46,89.15 196.98,89.15 196.98,88.9 196.75,88.9 196.75,89.77 197.38,89.77 197.38,89.99 197.3,90.07 196.93,90.07 196.93,89.77 196.75,89.77 196.75,90.17 196.85,90.27 196.9,90.27 196.93,90.3 197.76,90.3
GND on TOP (solid shape): 113.28,179.81 113.28,179.17 113.49,178.97 115.16,178.97 115.49,178.64 116.15,178.64 116.36,178.43 116.36,176.94 116.31,176.89 114.99,176.89 114.76,177.11 116,177.11 116,177.39 115.57,177.39 115.57,177.11 114.76,177.11 114.71,177.16 114.71,178.03 115.98,178.03 115.98,178.31 115.54,178.31 115.54,178.03 114.71,178.03 114.71,178.21 114.47,178.45 113.29,178.45 112.9,178.05 112.5,178.05 112.37,178.18 112.37,178.36 112.8,178.36 112.8,178.71 112.6,178.71 112.6,178.36 112.37,178.36 112.37,178.82 112.14,179.04 112.14,179.93 112.29,180.09 113,180.09
GND on TOP (solid shape): 101.42,147.85 101.42,147.62 101.75,147.29 102.72,147.29 102.92,147.09 102.92,145.16 103.1,144.98 103.38,144.98 103.66,144.7 106.12,144.7 106.53,144.3 106.53,143.36 106.17,143 103.96,143 103.51,143.46 103.51,143.61 103,144.12 101.35,144.12 100.71,144.75 100.71,145.47 102.69,145.47 102.69,145.74 102.16,145.74 102.16,145.47 100.71,145.47 100.71,146.46 102.67,146.46 102.67,146.74 102.21,146.74 102.21,146.46 100.71,146.46 100.71,147.29 101.17,147.29 101.17,147.7 100.89,147.7 100.89,147.29 100.71,147.29 100.71,148.01 100.79,148.08 101.19,148.08
GND on TOP (solid shape): 22.81,52.07 22.81,51.54 23.14,51.21 23.14,51.13 23.52,50.75 24.77,50.75 24.84,50.82 24.84,51.64 26.85,51.64 26.87,51.61 26.87,50.8 26.92,50.75 27.81,50.75 27.81,50.49 26.9,50.49 26.87,50.47 26.87,49.61 24.84,49.61 24.84,50.44 24.79,50.49 23.57,50.49 23.5,50.42 21.79,50.42 21.59,50.62 23.01,50.62 23.01,50.85 22.63,50.85 22.63,50.62 21.59,50.62 21.54,50.67 19.3,50.67 19.25,50.72 22.28,50.72 22.28,51.18 21.97,51.18 21.97,50.72 19.25,50.72 19.18,50.8 19.18,51.94 19.46,52.22 19.66,52.22 19.69,52.25 22.63,52.25
GND on TOP (solid shape): 106.35,180.47 106.35,179.22 105.97,178.84 105.66,178.84 105.16,178.33 105.16,177.88 105.08,177.8 104.75,177.8 104.58,177.63 104.58,177.49 104.55,177.49 104.55,175.34 104.52,175.31 104.51,175.31 104.27,175.07 104.27,175.06 103.89,174.68 101.91,174.68 101.85,174.73 101.85,174.93 103.33,174.93 103.33,175.39 102.49,175.39 102.49,174.93 101.85,174.93 101.85,175.44 102.01,175.59 102.36,175.59 102.54,175.77 102.54,176.12 102.69,176.28 103.1,176.28 103.15,176.33 103.78,176.33 103.81,176.35 103.86,176.35 103.86,176.4 104,176.54 104,176.67 104.01,176.67 104.01,177.67 104.22,177.88 104.22,178.21 104.83,178.21 104.83,178.49 104.37,178.49 104.37,178.21 104.22,178.21 104.22,178.82 104.42,179.02 104.42,180.24 105,180.82 105.99,180.82
GND on TOP (solid shape): 158.5,72.9 158.5,72.77 159,72.26 160.05,72.26 160.4,72.62 161.32,72.62 162.46,71.48 162.69,71.48 163.12,71.04 164.16,71.04 164.9,70.31 166.55,70.31 166.75,70.1 166.75,69.57 166.73,69.54 165.18,69.54 165.05,69.67 158.42,69.67 158.39,69.7 166.29,69.7 166.29,69.95 165.51,69.95 165.51,69.7 158.39,69.7 158.12,69.98 158.12,70.48 157.96,70.64 155.17,70.64 155.07,70.74 155.07,70.76 155.8,70.76 155.8,70.81 157.56,70.81 157.56,71.25 157.23,71.25 157.23,70.81 155.8,70.81 155.8,70.84 156.52,70.84 156.52,71.25 156.26,71.25 156.26,70.84 155.8,70.84 155.8,70.99 155.47,70.99 155.47,70.76 155.07,70.76 155.07,71.25 155.19,71.37 155.19,73.02 155.58,73.41 157.99,73.41
GND on TOP (solid shape): 59.31,142.37 59.31,140.21 60.02,139.5 60.71,139.5 60.93,139.27 60.93,136.27 61.37,135.84 63.2,135.84 63.55,135.48 63.55,131.6 63.51,131.56 63.51,130.95 62.99,130.43 62.97,130.43 62.36,129.82 60.91,129.82 59.69,131.04 59.69,131.06 59.58,131.33 59.31,131.45 59.03,131.33 58.93,131.04 58.93,128.52 58.78,128.37 58.06,128.37 58.04,128.35 57.13,128.35 56.67,128.81 56.67,130.78 56.26,131.19 56.26,140.21 57.4,141.35 57.91,141.86 57.91,141.86 58.67,142.62 59.06,142.62
GND on TOP (solid shape): 106.43,168.83 106.43,165.23 105.89,164.69 103.89,164.69 103.61,164.41 103.61,163.88 103.2,163.47 103.2,162.89 104.04,162.89 104.04,162.64 103.48,162.64 103.48,162.38 104.06,162.38 104.06,162.13 103.2,162.13 103.2,161.54 103.12,161.47 101.14,161.47 101.14,162.13 100.28,162.13 100.25,162.15 100.25,162.36 100.28,162.38 100.81,162.38 100.81,162.64 100.3,162.64 100.28,162.66 100.28,162.86 101.09,162.86 101.17,162.94 101.17,163.5 102.34,163.5 102.51,163.68 102.51,163.8 103.05,163.8 103.05,164.46 102.74,164.46 102.74,163.8 102.51,163.8 102.51,165.1 103.2,165.1 103.2,165.35 102.77,165.35 102.77,165.1 102.51,165.1 102.51,165.2 102.49,165.23 102.49,167.03 102.79,167.33 103.23,167.33 103.48,167.59 103.48,169.47 103.91,169.9 105.36,169.9
GND on TOP (solid shape): 192.3,90.4 194.08,90.4 194.23,90.25 194.23,87.65 194.13,87.55 193.12,87.55 193.04,87.63 193.04,88.95 192.96,89.03 178.31,89.03 178.18,89.15 178.18,89.66 178.56,90.04 179.57,90.04 179.58,90 179.71,89.76 179.96,89.66 180.17,89.72 180.31,89.89 180.32,89.92 188.18,89.92 188.31,89.82 188.47,89.79 188.74,89.9 188.85,90.17 188.85,90.21 188.83,90.28 188.98,90.42 192.28,90.42
GND on TOP (solid shape): 7.75,153.82 7.75,153.52 7.62,153.39 7.62,151.76 7.65,151.74 7.82,151.74 7.87,151.79 7.87,153.19 7.9,153.21 8.1,153.21 8.13,153.19 8.13,151.79 8.18,151.74 8.18,151.59 9.34,151.59 9.34,151.7 9.4,151.76 9.4,153.19 9.42,153.21 9.55,153.21 9.6,153.16 9.6,151.82 9.68,151.74 9.68,151.59 10.84,151.59 10.9,151.65 10.9,153.19 10.92,153.21 11.07,153.21 11.13,153.16 11.13,151.64 11.18,151.59 12.34,151.59 12.4,151.65 12.4,153.19 12.42,153.21 12.6,153.21 12.62,153.19 12.62,151.69 12.7,151.61 13.82,151.61 13.89,151.69 13.89,153.19 13.92,153.21 14.1,153.21 14.12,153.19 14.12,151.71 14.22,151.61 15.37,151.61 15.39,151.64 15.39,153.19 15.42,153.21 15.6,153.21 15.62,153.19 15.62,151.69 15.67,151.64 16.84,151.64 16.89,151.69 16.89,153.19 16.92,153.21 17.09,153.21 17.12,153.19 17.12,151.69 17.32,151.49 17.32,150.9 16.15,149.73 8.46,149.73 8.45,149.74 6.62,149.74 5.77,150.6 5.77,153.77 5.92,153.92 7.65,153.92
GND on TOP (solid shape): 108.69,153.11 108.69,152.5 107.92,151.74 107.92,146.47 107.92,146.46 107.92,146.43 107.9,146.41 107.88,146.39 107.85,146.38 107.82,146.37 107.8,146.38 107.67,146.42 107.6,146.43 107.55,146.43 107.5,146.43 107.45,146.41 107.43,146.41 106.91,146.41 106.91,146.02 107.19,146.02 107.19,145.99 107.21,145.93 107.23,145.87 107.25,145.84 107.25,145.75 107.25,145.69 107.27,145.64 107.3,145.59 107.33,145.54 107.35,145.52 107.35,145.35 106.83,145.35 106.83,145.15 106.83,145.14 106.82,145.11 106.81,145.08 106.78,145.06 106.76,145.05 106.73,145.05 106.7,145.06 106.67,145.07 106.58,145.16 106.58,147.04 107.32,147.04 107.32,147.34 106.88,147.34 106.88,147.04 106.58,147.04 106.58,148.01 107.32,148.01 107.32,148.28 106.88,148.28 106.88,148.01 106.58,148.01 106.58,148.51 105.92,149.17 105.92,153.09 106.22,153.39 108.41,153.39
GND on TOP (solid shape): 169.1,61.8 169.16,61.8 169.16,61.66 169.1,61.63 168.55,61.63 168.55,60.95 169.09,60.95 169.11,60.94 169.13,60.93 169.19,60.92 169.24,60.91 169.36,60.92 169.39,60.92 169.42,60.9 169.44,60.88 169.46,60.86 169.47,60.83 169.47,59.36 169.34,59.23 168.75,59.23 168.55,59.04 168.55,58.44 168.45,58.34 167.16,58.34 167.13,58.37 167.13,58.62 167.72,58.62 167.72,58.75 168.35,58.75 168.35,59.13 168.12,59.13 168.12,58.75 167.72,58.75 167.72,58.9 167.36,58.9 167.36,58.62 167.13,58.62 167.13,59.79 167.16,59.82 169.16,59.82 169.16,60.83 168.78,60.83 168.78,59.82 168.53,59.82 168.53,60.83 168.15,60.83 168.15,59.82 167.89,59.82 167.89,60.83 167.51,60.83 167.51,59.82 167.16,59.82 167.21,59.87 167.21,60.75 167.21,60.75 167.21,61.8 167.09,61.8 167.09,61.8 167.09,62.61 169.1,62.61
GND on TOP (solid shape): 9.5,9.53 9.12,9.02 8.99,8.4 8.99,6.3 8.85,5.95 8.5,5.81 8.5,17.34 8.49,17.34 8.5,17.42 8.5,17.6 7.88,18.95 6.5,19.5 2,19.5 1.18,19.33 0.51,18.83 0.51,21.3 9.5,21.3
GND on TOP (solid shape): 30.35,205.71 4.55,205.71 4.55,205.8 2.8,205.8 2.06,205.06 1.05,204.78 1.02,204.78 1.02,196.63 0.76,196.5 0.51,196.34 0.51,204.8 0.65,205.15 1,205.29 1.05,205.29 2.12,205.73 2.56,206.8 2.56,211.8 2.7,212.15 3.05,212.29 30.35,212.29
GND on TOP (solid shape): 177.34,145.6 177.1,144.64 177.03,143.65 183.28,137.4 189.53,143.65 189.45,144.64 189.21,145.6 198.4,145.6 198.4,97.6 134.05,97.6 134.05,117.5 134.9,117.5 135,117.6 135,125.98 134.75,126.24 134.11,126.24 134.05,126.3 134.05,136.6 133.05,136.6 133.05,145.6
GND on TOP (solid shape): outline of 108 points within 89.03,144.53 93.73,154.81
GND on TOP (solid shape): outline of 118 points within 41.78,16.99 50.67,27.49
GND on TOP (solid shape): 102.75,212.29 103.1,212.15 103.24,211.8 103.24,205.3 105.75,202.79 108.26,205.3 108.26,211.8 108.4,212.15 108.75,212.29 110.17,212.29 110.17,211.78 108.77,211.78 108.77,205.3 108.17,203.5 106.62,202.41 104.88,202.41 103.33,203.5 102.73,205.3 102.73,211.78 101.53,211.78 101.53,212.29
GND on TOP (solid shape): outline of 131 points within 173.46,64.64 177.47,72.64
GND on TOP (solid shape): 100.67,194.28 100.7,194.24 100.7,194.18 100.69,194.13 100.69,194.08 100.69,194.04 100.81,193.79 101.07,193.69 101.95,193.69 102.21,193.79 102.33,194.04 102.34,194.08 102.33,194.13 102.32,194.18 102.32,194.24 102.35,194.28 103.33,194.28 103.41,194.25 103.43,194.16 103.42,194.12 103.42,194.04 103.55,193.79 103.8,193.69 104.69,193.69 104.95,193.79 105.07,194.04 105.07,194.12 105.06,194.16 105.08,194.25 105.16,194.28 105.9,194.28 105.98,194.24 105.99,194.15 105.98,194.09 105.97,194.03 105.97,193.99 106.1,193.74 106.35,193.64 107.24,193.64 107.5,193.74 107.62,193.99 107.62,194.03 107.62,194.09 107.6,194.15 107.62,194.24 107.7,194.28 108.23,194.28 108.23,194.11 107.97,193.86 107.97,193.79 107.97,193.78 107.87,193.78 107.6,193.5 107.58,193.5 107.58,193.48 107.49,193.4 107.49,192.86 107.21,192.58 100.71,192.58 100.25,193.04 100.25,194.28
GND on TOP (solid shape): 3,34.26 3.26,33.59 3.89,33.27 3.89,33.27 7.39,31.47 8.8,27.8 7.19,23.91 3.3,22.3 2,22.3 1.93,22.3 1.87,22.29 1.25,21.96 1,21.3 0.51,21.3 0.94,22.35 2,22.79 3.3,22.79 8.28,27.3 4.29,32.71 4.29,32.73 3.84,32.78 2.89,33.27 2.51,34.26
GND on TOP (solid shape): outline of 83 points within 87.86,193.32 98.98,194.94
GND on TOP (solid shape): outline of 296 points within 223.1,140.01 242.99,206.1
GND on TOP (solid shape): 30.41,44.13 34.4,47.93 38.39,44.13 53.6,44.13 53.6,38.06 51.6,30.6 49.6,38.06 49.6,40.14 35.76,40.14 34.4,39.9 33.04,40.14 19.2,40.14 19.2,38.06 17.2,30.6 15.2,38.06 15.2,44.13
GND on TOP (solid shape): 250.5,52.45 251.56,52.01 251.99,50.96 251.99,11.25 251.56,10.19 250.5,9.76 244.9,9.76 243.13,9.02 242.39,7.25 242.39,2 241.95,0.94 240.9,0.51 234.7,0.51 234.35,0.65 234.21,1 234.21,6.6 233.77,7.67 232.7,8.11 231.2,8.11 230.13,7.67 229.69,6.6 229.69,1 229.55,0.65 229.2,0.51 226.8,0.51 226.45,0.65 226.31,1 226.31,4.3 226.21,4.85 225.91,5.32 225.9,5.33 225.9,5.79 225.96,5.88 226.07,5.87 226.62,5.17 226.82,4.3 226.82,1.02 229.18,1.02 229.18,6.6 229.77,8.03 231.2,8.62 232.7,8.62 234.13,8.03 234.72,6.6 234.72,1.02 240.9,1.02 241.6,1.3 241.88,2 241.88,7.25 242.77,9.38 244.9,10.27 250.5,10.27 251.2,10.55 251.48,11.25 251.48,50.96 251.2,51.65 250.5,51.94 246.96,51.94 246.96,52.45
GND on TOP (solid shape): outline of 91 points within 198.4,51.94 238.96,150.2
GND on TOP (solid shape): outline of 124 points within 0.51,34.26 9.14,191.4
GND on BOTTOM (solid shape): 199.89,91.14 199.38,91.14 199.38,125.26 199.89,125.26
GND on BOTTOM (solid shape): 103.02,163.32 103.02,161.65 102.97,161.59 101.32,161.59 101.3,161.74 101.3,163.27 101.33,163.35 103,163.35
GND on BOTTOM (solid shape): 199.89,62.26 200.63,60.48 202.4,59.75 210.39,59.75 210.39,59.24 202.4,59.24 200.27,60.13 199.38,62.26 199.38,83.14 199.89,83.14
GND on BOTTOM (solid shape): 240.39,164.5 239.95,163.45 238.9,163.01 232.5,163.01 230.73,162.27 229.99,160.5 229.99,155.15 229.48,155.15 229.48,160.5 230.37,162.63 232.5,163.52 238.9,163.52 239.6,163.8 239.88,164.5 239.88,177.48 240.39,177.48
GND on BOTTOM (solid shape): 228.5,59.75 229.56,59.31 229.99,58.26 229.99,54.96 230.73,53.18 232.5,52.45 238.96,52.45 238.96,51.94 232.5,51.94 230.37,52.83 229.48,54.96 229.48,55.39 229.51,55.4 229.68,55.54 229.74,55.75 229.68,55.96 229.51,56.1 229.48,56.12 229.48,58.26 229.2,58.95 228.5,59.24 218.39,59.24 218.39,59.75
GND on BOTTOM (solid shape): 250.5,52.45 251.56,52.01 251.99,50.96 251.99,11.25 251.56,10.19 250.5,9.76 247.88,9.76 247.79,9.81 247.8,9.92 247.92,10.09 248.02,10.27 248.16,10.27 248.62,10.72 248.62,12.34 248.41,12.55 246.4,15.12 248.64,17.49 251.48,20.33 251.48,50.96 251.2,51.65 250.5,51.94 246.96,51.94 246.96,52.45
GND on BOTTOM (solid shape): 102.75,212.29 103.1,212.15 103.24,211.8 103.24,205.3 105.75,202.79 108.26,205.3 108.26,211.8 108.4,212.15 108.75,212.29 127,212.29 127,211.78 108.77,211.78 108.77,205.3 105.75,202.28 102.73,205.3 102.73,211.78 84.46,211.78 84.46,212.29
GND on BOTTOM (solid shape): outline of 169 points within 176.28,100.65 185.4,109.6
GND on BOTTOM (solid shape): outline of 199 points within 177.4,128.65 186.18,137.79
GND on BOTTOM (solid shape): 208.4,149.52 210.53,148.63 211.42,146.5 211.42,141.5 211.7,140.8 212.4,140.52 228.5,140.52 229.2,140.8 229.48,141.5 229.48,147.15 229.99,147.15 229.99,141.5 229.56,140.44 228.5,140.01 212.4,140.01 211.35,140.44 210.91,141.5 210.91,146.5 210.17,148.27 208.4,149.01 202.4,149.01 200.63,148.27 199.89,146.5 199.89,133.26 199.38,133.26 199.38,146.5 200.27,148.63 202.4,149.52
GND on BOTTOM (solid shape): outline of 254 points within 196.5,28 204.5,36
GND on BOTTOM (solid shape): 243.08,9.41 243.23,9.29 243.27,9.21 243.24,9.13 242.61,8.28 242.39,7.25 242.39,2 241.95,0.94 240.9,0.51 234.7,0.51 234.35,0.65 234.21,1 234.21,6.6 233.77,7.67 232.7,8.11 231.2,8.11 230.13,7.67 229.69,6.6 229.69,1 229.55,0.65 229.2,0.51 226.8,0.51 226.45,0.65 226.31,1 226.31,4.3 226.21,4.85 225.91,5.32 225.9,5.33 225.9,5.79 225.96,5.88 226.07,5.87 226.62,5.17 226.82,4.3 226.82,1.02 229.18,1.02 229.18,6.6 229.77,8.03 231.2,8.62 232.7,8.62 234.13,8.03 234.72,6.6 234.72,1.02 240.9,1.02 241.6,1.3 241.88,2 241.88,7.25 242.16,8.51 242.94,9.54
GND on BOTTOM (solid shape): outline of 283 points within 10.77,95.25 22.77,113.15
GND on BOTTOM (solid shape): outline of 282 points within 10.77,57.25 22.77,75.15
GND on BOTTOM (solid shape): outline of 120 points within 0.51,20.2 33.02,212.29
GND on ART03 (solid shape): 73.56,124.84 73.22,124.51 65.56,124.51 65.56,127.66 73.56,127.66
GND on ART03 (solid shape): 199.89,91.14 199.41,91.14 199.41,124.81 199.38,124.84 199.38,125.26 199.89,125.26
GND on ART03 (solid shape): 64.85,119.63 64.85,116.46 58.63,116.46 58.5,116.6 58.5,119.81 58.8,120.12 64.36,120.12
GND on ART03 (solid shape): 115.58,127.61 115.58,123.74 115.3,123.47 115.2,123.47 111.21,123.47 111.19,123.49 110.19,123.49 109.8,123.87 109.72,123.99 109.6,124.07 109.12,124.55 109.12,127.49 109.26,127.62 109.92,127.62 109.94,127.65 115.54,127.65
GND on ART03 (solid shape): 90.02,119.83 90.02,116.56 81.08,116.56 80.94,116.68 80.77,116.72 79.88,116.72 79.71,116.68 79.57,116.56 79.27,116.56 79.27,119.95 79.54,120.22 89.63,120.22
GND on ART03 (solid shape): 199.89,62.26 200.04,61.42 200.45,60.67 200.47,60.57 200.38,60.51 200.02,60.51 199.41,61.12 199.41,83.14 199.89,83.14
GND on ART03 (solid shape): 67.26,120.45 67.31,120.39 67.37,120.34 67.48,120.3 67.59,120.29 68.43,120.29 68.54,120.3 68.65,120.34 68.71,120.39 68.76,120.45 73.81,120.45 73.86,120.45 73.86,116.57 73.8,116.51 67.17,116.51 66.87,116.81 66.87,120.23 67.08,120.45
GND on ART03 (solid shape): 15.21,156.16 15.31,156.1 15.43,156.09 15.45,156.09 16.3,156.09 16.32,156.09 16.44,156.1 16.54,156.16 19.66,156.16 20.17,155.65 20.17,155.14 20.37,154.94 20.37,154.33 21.92,152.78 21.92,151.03 21.79,150.9 17.22,150.9 17.09,151.03 17.09,153.36 15.85,153.36 15.01,154.2 14.88,154.2 14.63,154.46 14.63,156.16
GND on ART03 (solid shape): 199.89,62.26 200.04,61.42 200.45,60.67 200.47,60.57 200.38,60.51 200.02,60.51 199.81,60.72 199.55,61.27 199.41,61.87 199.41,83.14 199.89,83.14
GND on ART03 (solid shape): 156.59,90.04 156.59,86.74 156.08,86.23 155.83,86.23 155.83,84.94 155.04,84.15 154.86,84.15 154.71,84.4 154.43,84.5 154.16,84.4 154.01,84.15 152.04,84.15 151.79,84.4 151.79,86.23 149.99,86.23 149.86,86.36 149.86,90.04 149.99,90.17 156.46,90.17
GND on ART03 (solid shape): 158.06,96.98 158.06,93.8 157.96,93.7 157.54,93.7 156.9,94.35 156.9,94.42 156.87,94.57 156.79,94.71 156.47,94.89 156.14,94.71 156.06,94.57 156.04,94.42 156.05,94.32 156.09,94.22 156.09,93.83 156.07,93.78 156.04,93.7 155.09,93.7 154.97,93.83 154.97,97.08 155.09,97.21 157.84,97.21
GND on ART03 (solid shape): 87.71,127.84 87.82,127.57 88.09,127.45 88.28,127.5 88.42,127.63 89.03,127.63 89.03,123.65 88.9,123.52 79.1,123.52 79.1,127.39 79.34,127.63 79.48,127.52 79.66,127.47 80.52,127.47 80.54,127.47 80.72,127.52 80.86,127.63 83.53,127.63 83.66,127.53 83.83,127.5 83.99,127.53 84.12,127.63 85.09,127.63 85.11,127.65 85.18,127.68 85.26,127.64 85.39,127.54 85.55,127.5 85.81,127.6 85.93,127.84 85.94,127.89 87.71,127.89
GND on ART03 (solid shape): 102.75,212.29 103.1,212.15 103.24,211.8 103.24,205.3 105.75,202.79 108.26,205.3 108.26,211.8 108.4,212.15 108.75,212.29 126.75,212.29 126.75,211.78 108.77,211.78 108.77,205.3 105.75,202.28 102.73,205.3 102.73,211.78 84.58,211.78 84.58,212.29
GND on ART03 (solid shape): 234.37,206.1 234.66,205.85 235,205.68 235,194.06 235.01,194.06 235,193.98 235,193.9 235.59,192.49 237,191.9 241.5,191.9 242.01,191.97 242.48,192.16 242.48,194.25 242.99,194.25 242.99,191.4 242.85,191.05 242.5,190.91 241.9,190.91 241.28,190.78 240.77,190.4 240.49,189.93 240.39,189.4 240.39,188.02 240.39,185.48 239.92,185.48 239.92,177.48 240.39,177.48 240.39,164.5 239.95,163.45 238.9,163.01 232.5,163.01 230.73,162.27 229.99,160.5 229.99,155.15 229.5,155.15 229.5,147.15 229.99,147.15 229.99,141.5 229.56,140.44 228.5,140.01 212.21,140.01 212.2,140.02 211.28,140.52 210.91,141.5 210.91,146.5 210.17,148.27 208.4,149.01 202.4,149.01 200.63,148.27 199.89,146.5 199.89,133.26 199.4,133.26 199.4,125.26 199.89,125.26 199.89,91.14 199.41,91.14 199.41,124.81 198.4,125.82 198.4,144.69 198.88,145.17 198.88,149.38 199.48,149.98 199.93,150.14 200.4,150.2 200.47,150.2 205.16,150.2 210,150.2 211.41,149.61 212,148.2 212,141.64 212.01,141.65 228.5,141.65 228.5,160.5 229.67,163.33 232.5,164.5 238.9,164.5 238.9,190.4 234,190.4 234,206.1
GND on ART03 (solid shape): outline of 90 points within 184.86,0.51 251.99,59.75
GND on ART03 (solid shape): outline of 115 points within 0.51,14.43 32.89,212.29
GND on ART04 (solid shape): 102.75,212.29 103.1,212.15 103.24,211.8 103.24,205.3 105.75,202.79 108.26,205.3 108.26,211.8 108.4,212.15 108.75,212.29 127,212.29 127,211.78 108.77,211.78 108.77,205.3 105.75,202.28 102.73,205.3 102.73,211.78 84.58,211.78 84.58,212.29
GND on ART04 (solid shape): 137.39,87.02 137.42,86.99 137.45,86.96 137.46,86.9 137.41,86.87 137.38,86.87 137.11,86.76 137,86.49 137.06,86.27 137.24,86.13 137.3,86.06 137.27,85.97 137.09,85.79 117.91,85.79 117.8,85.77 117.7,85.7 86.08,54.08 86.01,53.98 85.99,53.87 85.99,34.44 86.01,34.33 86.08,34.24 93.57,26.74 93.67,26.68 93.78,26.66 98.07,26.66 98.18,26.68 98.28,26.74 101.71,30.17 101.73,30.17 101.99,30.26 102.15,30.5 102.22,30.57 102.32,30.54 102.95,29.91 102.95,27.96 101.19,26.21 92.53,26.21 85.09,33.65 85.09,55.7 86.39,57 86.5,57.02 86.56,56.93 86.71,56.59 87.05,56.45 87.25,56.49 87.41,56.62 87.49,56.65 87.57,56.62 87.73,56.49 87.94,56.45 88.42,56.93 87.94,57.42 87.73,57.37 87.57,57.25 87.49,57.21 87.41,57.25 87.25,57.37 87.05,57.42 86.96,57.48 86.98,57.59 87.07,57.68 87.09,57.68 87.28,57.73 87.43,57.85 87.5,57.89 87.58,57.85 87.75,57.73 87.95,57.68 88.29,57.82 88.43,58.17 88.36,58.42 88.17,58.59 88.12,58.67 88.15,58.76 99.34,69.95 101.35,69.95 118.42,87.02
GND on ART04 (solid shape): outline of 541 points within 197.36,51.94 242.99,194.25
GND on ART04 (solid shape): outline of 99 points within 171.58,0.51 251.99,52.45
GND on ART04 (solid shape): outline of 120 points within 0.51,14.43 33.02,212.29
GND on TOP: 98.55,171.83 98.55,170.69 99.06,170.18 106.43,170.18 106.68,170.43 106.68,171.83 106.55,171.96 98.68,171.96
GND on TOP: 183.11,79.2 186.49,79.2 187.58,78.1 187.58,77.09 187.07,76.58 184.81,76.58 184.46,76.94 184.46,78.08 184.15,78.38 183.24,78.38 182.98,78.64 182.98,79.07 ; 3 cut-outs
GND on TOP: 160.22,76.53 160.22,74.85 160.71,74.37 160.88,74.37 161.01,74.24 161.37,74.24 161.65,74.52 161.65,76.48 161.44,76.68 160.38,76.68
GND on TOP: 11.07,113.94 12.95,113.94 13.64,114.63 13.94,114.63 14.38,115.06 15.21,115.06 15.49,115.34 15.49,115.93 15.44,115.98 14.5,115.98 14,115.47 10.8,115.47 10.54,115.21 10.54,114.48 ; 2 cut-outs
GND on TOP: 89.28,51.31 89.28,48.64 89.74,48.18 91.49,48.18 92.46,47.22 93.45,47.22 93.6,47.37 93.6,48.06 94.03,48.49 94.03,49.61 94.18,49.76 95.78,49.76 95.91,49.89 96.39,49.89 96.52,49.76 96.52,48.62 97.08,48.06 99.06,48.06 99.39,48.39 99.39,48.95 99.54,49.1 100.69,49.1 100.97,48.82 100.97,47.78 100.28,47.09 96.6,47.09 95.61,46.1 89.59,46.1 88.16,47.52 88.16,52.15 89.03,53.01 90.35,53.01 90.86,52.5 95.35,52.5 95.96,53.11 99.21,53.11 100.25,52.07 100.25,51.26 100.05,51.05 99.49,51.05 99.39,51.16 99.39,51.74 99.31,51.82 89.79,51.82 ; 8 cut-outs
GND on TOP: 10.8,171.7 11.3,171.7 11.53,171.93 11.53,172.69 11.68,172.85 13.34,172.85 13.46,172.72 13.46,171.91 13.72,171.65 15.82,171.65 16.38,172.21 17.65,172.21 17.73,172.14 17.73,171.4 17.78,171.35 17.78,169.82 17.5,169.54 12.07,169.54 11.94,169.42 11.94,167.77 11.81,167.64 10.67,167.64 10.54,167.77 10.54,171.45 ; 1 cut-out
GND on TOP: 133.35,56.74 136.82,56.74 137.17,56.39 138.62,56.39 138.76,56.25 138.76,54.81 138.61,54.66 136.93,54.66 136.8,54.53 135.28,54.53 135.15,54.66 132.79,54.66 132.72,54.74 132.72,55.37 133.35,56.01 ; 3 cut-outs
GND on TOP: 12.62,161.06 14.48,161.06 14.63,160.91 14.63,160.35 14.5,160.22 12.62,160.22 12.5,160.35 12.5,160.93 ; 1 cut-out
GND on TOP: 113.74,157.45 112.65,157.45 112.45,157.66 112.45,158.22 112.34,158.32 111.68,158.32 111.4,158.04 111.4,156.87 111.79,156.49 115.67,156.49 115.82,156.64 115.82,157.2 115.34,157.68 113.97,157.68 ; 5 cut-outs
GND on TOP: 133.78,33.93 135.79,33.93 136.45,33.27 136.45,32.59 136.22,32.36 133.25,32.36 132.97,32.64 132.97,32.74 133.63,33.4 133.63,33.78
GND on TOP: 127.41,136.4 129.95,136.4 130.18,136.17 133.4,136.17 133.88,135.69 133.88,130.56 133.86,130.53 133.86,128.19 133.35,127.69 132.36,127.69 132.18,127.86 131.8,127.86 131.52,128.14 131.52,129.82 131.5,129.82 130.99,130.33 128.65,130.33 128.37,130.61 128.37,131.44 128.24,131.57 127.4,131.57 127.31,131.66 127.31,132.49 127.18,132.62 127.18,136.17 ; 5 cut-outs
GND on TOP: 20.37,136.91 21.77,136.91 22.12,136.55 22.12,136.04 21.56,135.48 21.56,133.1 21.92,132.74 22.86,132.74 23.98,133.86 24.94,133.86 25.25,133.55 25.25,132.26 25.04,132.05 22.61,132.05 22.45,131.9 21.13,131.9 20.42,132.61 20.27,132.61 20.09,132.79 20.09,135.73 20.24,135.89 20.24,136.78 ; 6 cut-outs
GND on TOP: 44.93,77.93 44.37,77.37 31.17,77.37 30.05,78.49 30.05,83.82 30.94,84.71 36.96,84.71 37.44,84.23 37.44,82.24 37.74,81.94 44.6,81.94 44.93,81.61 ; 8 cut-outs
GND on TOP: 166.01,80.16 166.01,78.26 166.83,77.44 170.51,77.44 170.79,77.72 170.79,80.21 170.23,80.77 166.62,80.77
GND on TOP: 126.67,48.72 129.77,48.72 129.97,48.92 129.97,51.03 130.51,51.56 130.51,54.56 132.68,56.73 132.68,57.06 133.02,57.4 133.02,60.2 132.94,60.27 127.33,60.27 127.25,60.2 127.25,51.13 126.59,50.47 126.59,48.79
GND on TOP: 206.88,28.19 206.88,24.51 206.78,24.41 206.78,23.19 206.88,23.09 208.03,23.09 208.33,23.39 208.33,23.72 207.95,24.1 207.95,27.23 208.94,28.22 209.63,28.22 210.01,28.6 210.01,29.59 209.78,29.82 208.18,29.82 207.92,29.57 207.92,28.65 207.62,28.35 207.04,28.35 ; 1 cut-out
GND on TOP: 10.13,138.28 10.13,134.39 10.47,134.06 11.3,134.06 11.43,134.19 11.43,138.12 11.15,138.4 10.26,138.4 ; 2 cut-outs
GND on TOP: 73.74,48.69 73.08,49.35 73.08,59.97 73.34,60.24 78.58,60.24 79.38,59.44 79.38,49.66 78.41,48.69
GND on TOP: 99.8,150.72 99.8,150.22 99.82,150.19 101.02,150.19 101.32,150.49 101.32,150.77 101.07,151.03 100.1,151.03
GND on TOP: 149.78,64.9 150.37,64.9 150.62,64.64 150.62,60.35 150.42,60.15 150.29,60.15 150.29,59.89 150.04,59.64 149.76,59.64 149.5,59.89 149.5,60.58 145.77,60.58 145.47,60.27 142.47,60.27 142.16,60.58 136.4,60.58 136.3,60.68 136.3,61.11 136.6,61.42 136.75,61.42 137.16,61.82 137.26,61.82 137.29,61.85 140.08,61.85 140.34,62.1 141.99,62.1 141.99,61.52 142.32,61.19 144.96,61.19 144.98,61.21 145.16,61.21 145.54,61.59 146.94,61.59 147.19,61.34 149.43,61.34 149.56,61.47 149.56,61.67 149.61,61.72 149.61,64.72 ; 7 cut-outs
GND on TOP: 174.12,35.08 174.12,34.09 174.19,34.01 179.86,34.01 179.93,34.09 179.93,34.77 178.31,36.4 176.94,36.4 175.82,35.28 174.32,35.28 ; 5 cut-outs
GND on TOP: 18.97,119.99 19.08,119.89 19.08,117.63 19.28,117.42 19.91,117.42 20.04,117.55 20.04,117.8 20.24,118.01 20.78,118.01 20.8,118.03 21.23,118.03 21.36,118.16 21.36,119.28 21.49,119.4 21.49,120.83 20.47,121.84 19.13,121.84 18.97,121.69 ; 4 cut-outs
GND on TOP: 95.17,52.81 91.14,52.81 90.83,53.11 90.83,60.07 90.98,60.22 95.73,60.22 96.49,59.46 96.49,54.13
GND on TOP: 24,143.76 26.8,143.76 26.8,143.51 26.54,143.51 26.54,143.13 26.92,143.13 26.92,143.15 27.13,142.95 27.66,142.95 27.79,142.82 27.79,141.66 27.66,141.53 25.83,141.53 25.25,142.11 23.65,142.11 22.07,140.54 14.17,140.54 14.05,140.66 11.96,140.66 11.61,141.02 9.55,141.02 9.4,141.17 9.4,142.9 9.65,143.15 10.54,143.15 11.07,143.69 12.7,143.69 13.18,143.2 18.21,143.2 18.47,142.95 23.55,142.95 24,143.41 ; 8 cut-outs
GND on TOP: 231.65,42.16 233.81,42.16 234.57,41.4 234.57,38.99 233.55,37.97 225.3,37.97 224.79,38.48 222.02,38.48 221.69,38.15 221.69,29.44 220.19,27.94 217.83,27.94 217.83,36.91 217.68,37.06 217.68,37.08 216.28,38.48 214.12,38.48 214,38.61 214,41.15 214.12,41.27 217.17,41.27 217.3,41.15 217.3,40 217.81,39.5 220.22,39.5 220.73,40 220.73,40.89 221.23,41.4 224.54,41.4 224.79,41.15 224.79,40 225.04,39.75 230.51,39.75 231.14,40.39 231.14,41.66
GND on TOP: 198.93,29.36 199.85,29.36 200.05,29.16 200.05,28.07 200.3,27.81 201.45,27.81 201.93,28.3 204.24,28.3 204.33,28.21 204.34,28.21 204.37,28.18 204.37,27.97 204.47,27.87 204.47,27.18 204.43,27.14 204.4,27.14 204.39,27.14 201.9,27.14 201.76,27 201.43,27 201.28,27.15 198.93,27.15 198.73,27.36 198.73,29.16
GND on TOP: 106.99,37.87 106.99,34.77 106.78,34.57 105.41,34.57 105.03,34.95 105.03,38.23 104.8,38.46 104.8,38.89 104.88,38.96 105.89,38.96
GND on TOP: 32.26,130.3 33.27,130.3 33.4,130.17 33.4,127.41 33.66,127.15 34.44,127.15 34.54,127.25 34.54,127.74 34.89,127.74 34.89,128.02 35.9,128.02 35.9,127.74 36.2,127.74 36.2,127.51 36.45,127.25 37.31,127.25 37.44,127.38 37.44,127.73 37.74,127.73 37.74,128.12 37.44,128.12 37.44,130.02 37.52,130.1 38.38,130.1 39.27,129.21 39.27,128.19 39.22,128.14 38.3,128.14 38.2,128.04 38.2,126.77 37.8,126.36 32.64,126.36 32.13,126.87 32.13,130.17 ; 6 cut-outs
GND on TOP: 183.06,158.44 184.46,158.44 184.56,158.55 184.56,160.15 184.47,160.24 183.07,160.24 182.93,160.1 182.93,158.57 ; 2 cut-outs
GND on TOP: 28.96,131.34 28.96,128.02 28.83,127.89 28.27,127.89 28.14,128.02 28.14,131.27 28.14,131.38 28.22,131.45 28.84,131.45
GND on TOP: 156.18,80.01 156.13,79.96 155.93,79.96 155.93,80.24 155.35,80.24 155.19,80.39 154.58,80.39 154.53,80.44 154.53,80.92 154.69,81.08 154.69,85.98 155.32,86.61 156.08,86.61 156.18,86.51 ; 7 cut-outs
GND on TOP: 12.75,132.36 13.41,132.36 13.56,132.51 13.56,134.98 13.89,135.31 13.89,137.62 13.77,137.74 12.75,137.74 12.62,137.62 12.62,134.01 12.37,133.76 12.37,132.74 ; 3 cut-outs
GND on TOP: 44.76,95.78 44.12,95.15 30.51,95.15 29.82,95.83 29.82,97.38 28.68,98.53 26.29,98.53 25.71,99.11 25.71,101.85 26.52,102.67 43.94,102.67 44.76,101.85
GND on TOP: 249.17,52.32 251.1,52.32 251.75,51.77 251.99,50.96 251.99,19.3 242.7,19.3 233.05,28.96 227.61,28.96 225.86,27.2 225.86,21.89 225.3,21.34 224.03,21.34 223.65,21.72 223.65,28.45 224.28,29.08 224.28,30.86 224.66,31.24 242.95,31.24 243.59,31.88 243.59,46.74
GND on TOP: 112.93,153.75 113.03,153.64 113.03,152.76 112.83,152.55 112.45,152.55 112.32,152.42 112.32,151.94 112.17,151.79 111.76,151.79 111.58,151.97 111.58,152.22 111.48,152.32 110.31,152.32 110.08,152.55 110.08,153.21 110.19,153.31 111.07,153.31 111.51,153.75 ; 3 cut-outs
GND on TOP: 185.42,28.19 187.71,28.19 188.09,27.81 194.08,27.81 194.72,28.45 196.8,28.45 197.05,28.2 197.05,27.29 196.65,26.9 194.97,26.9 194.84,26.77 194.84,25.35 194.67,25.17 193.98,25.17 193.84,25.31 193.84,26.02 193.55,26.31 191.57,26.31 191.36,26.11 191.36,25.37 191.34,25.35 190.78,25.35 190.47,25.65 189.99,25.65 189.87,25.78 189.87,26.06 189.61,26.31 186.06,26.31 185.78,26.03 184.4,26.03 184.28,26.16 184.28,27.05 ; 1 cut-out
GND on TOP: 21.64,202.59 24.92,202.59 25.91,201.6 25.91,180.8 25.55,180.44 22.99,180.44 22.23,181.2 22.23,183.34 21.79,183.34 21.69,183.44 21.69,185.29 21.87,185.47 23.98,185.47 24.38,185.88 24.38,186.74 23.75,187.38 22.96,187.38 22.23,188.11 22.23,193.67 20.9,195 20.9,201.85
GND on TOP: 130.1,33.22 130.35,32.97 132.16,32.97 132.31,32.82 132.31,29.69 132.16,29.54 129.36,29.54 126.54,32.36 126.54,38.91 127.64,40 129.16,40 130.1,39.06
GND on TOP: 168.5,93.34 168.5,87.3 167.87,86.66 164.19,86.66 163.7,87.15 163.7,92.89 164.2,93.38 164.88,93.38 165.3,92.96 165.3,92.51 165.68,92.13 167.06,92.13 167.16,92.23 167.16,93.27 167.39,93.5 168.35,93.5
GND on TOP: 6.25,114.53 7.44,114.53 7.57,114.66 7.57,119.71 7.44,119.84 6.07,119.84 5.82,119.58 5.82,119.33 5.39,118.9 4.88,118.9 4.67,118.69 4.67,116.15 4.95,115.87 5.54,115.87 5.82,115.59 5.82,114.96 ; 5 cut-outs
GND on TOP: 68.45,147.98 68.1,147.98 67.95,148.13 67.95,148.61 68.02,148.69 70.13,148.69 70.43,148.39 70.43,146 70.13,145.69 68.94,145.69 68.78,145.85 68.78,147.65 ; 4 cut-outs
GND on TOP: 108.47,60.21 108.52,60.26 108.53,60.25 114.35,60.25 114.35,53.72 113.94,53.31 113.18,53.31 112.82,52.95 109.28,52.95 107.8,51.46 106.55,51.46 106.38,51.28 106.38,47.65 105.89,47.17 105.89,45.69 104.75,44.55 104.75,41.78 104.39,41.43 101.96,41.43 101.35,42.04 101.35,46.68 101.93,47.27 104.08,47.27 104.92,48.11 104.92,51.99 105.79,52.86 106.83,52.86 108.47,54.5
GND on TOP: 3.12,114.68 4.12,114.68 4.24,114.55 4.24,112.17 4.14,112.06 3.23,112.06 3.05,111.89 2.77,111.89 2.72,111.94 2.72,114.76 2.82,114.86 2.95,114.86
GND on TOP: 31.37,122.66 33.3,122.66 33.73,122.22 33.73,118.16 34.32,117.58 44.96,117.58 45.14,117.4 45.14,114.5 44.55,113.92 35.2,113.92 34.24,112.95 34.24,110.34 33.73,109.83 33.73,108.18 33.48,107.92 32.79,107.92 32.65,108.06 32.65,115.71 31.93,116.43 31.52,116.43 31.12,116.84 31.12,122.4 ; 8 cut-outs
GND on TOP: 59.64,48.82 56.03,48.82 55.12,49.73 55.12,59.84 55.54,60.26 60.26,60.26 61.21,59.31 61.21,50.39
GND on TOP: 97.36,183.34 99.62,183.34 99.82,183.13 99.82,179.55 99.57,179.3 98.04,179.3 97.59,178.84 97.28,178.84 97.08,179.04 97.08,183.06
GND on TOP: 108.94,186.66 111.02,186.66 111.18,186.51 111.18,184.23 110.92,183.97 105.46,183.97 105.28,184.15 105.28,184.53 105.41,184.66 106.93,184.66 107.06,184.78 107.06,185.17 107.39,185.5 108.46,185.5 108.81,185.85 108.81,186.54 ; 1 cut-out
GND on TOP: 228.78,35.51 228.78,34.29 228.85,34.21 230.84,34.21 231.09,34.47 231.09,35.28 230.78,35.58 228.85,35.58
GND on TOP: 94.79,167.97 94.79,169.93 94.97,170.1 96.75,170.1 96.93,169.93 96.93,167.82 96.77,167.66 95.1,167.66
GND on TOP: 200.41,38.48 200.66,38.48 200.79,38.35 200.79,37.85 201.17,37.46 201.17,37.21 200.91,37.21 200.91,36.7 200.74,36.52 200.74,35.36 201.42,34.67 201.42,34.42 201.3,34.29 199.7,34.29 199.36,34.62 199.36,38.2 199.77,38.2 199.77,38.1 200.41,38.1
GND on TOP: 38.58,146.07 40.23,146.07 40.77,145.54 40.77,140.94 41.94,139.78 42.72,139.78 42.93,139.57 42.93,128.52 42.8,128.4 41.4,128.4 40.77,129.03 39.68,129.03 39.04,129.67 39.04,131.04 39.09,131.09 39.09,135.15 38.96,135.28 38.96,137.62 37.92,138.66 37.92,144.45 38.38,144.91 38.38,145.87
GND on TOP: 44.76,62.23 43.02,60.49 43.02,50.23 42.09,49.3 32.87,49.3 28.96,53.21 28.96,58.88 26.01,61.82 26.01,64.69 26.9,65.58 43.71,65.58 44.76,64.54
GND on TOP: 120.78,176.5 121.69,176.5 121.95,176.76 121.95,182.65 121.69,182.9 119.86,182.9 119.61,182.65 119.61,182.63 119.38,182.4 119.38,176.4 119.89,175.89 120.17,175.89
GND on TOP: 148.72,57.1 148.87,57.25 148.87,59.97 148.64,60.2 146.84,60.2 145.57,58.93 145.57,57.3 145.85,57.02 146.69,57.02 146.76,57.1
GND on TOP: 113.39,29.36 114.33,30.3 114.73,30.3 114.99,30.56 114.99,33.15 114.86,33.27 113.54,33.27 113.41,33.15 113.41,31.37 113.18,31.14 110.39,31.14 110.36,31.11 108.59,31.11 108.33,30.86 108.33,29.59 108.56,29.36
GND on TOP: outline of 97 points within 136.91,26.36 153.92,41.73 ; 5 cut-outs
GND on BOTTOM: 218.41,34.85 221.21,34.85 221.59,34.47 221.59,30.99 220.98,30.38 218.24,30.38 218.01,30.61 218.01,34.44
GND on BOTTOM: 20.24,206.53 27.2,206.53 27.2,199.19 26.04,198.02 26.04,193.5 21.11,193.5 20.24,194.36
GND on BOTTOM: 21.69,196.95 25.63,196.95 26.39,196.19 26.39,186.61 26.04,186.26 24.1,186.26 23.72,186.64 23.72,190.65 21.11,193.27 21.11,196.37
GND on ART02: outline of 225 points within 0.51,0.51 251.99,212.29 ; 2 cut-outs
GND on ART03: 108.26,206.27 119.43,206.27 119.69,206.02 119.69,190.75 119.43,190.5 119.38,190.5 119,190.12 100.58,190.12 100.2,190.5 99.87,190.5 99.87,197.81 99.19,198.5 99.19,201.29 98.58,201.9 98.2,201.9 97.26,200.96 97.26,198.37 98.63,197 98.63,192.07 97.05,190.5 97.03,190.5 96.27,189.74 87.88,189.74 87.43,190.19 87.43,200.56 85.22,202.77 85.22,206.02 85.47,206.27 103.24,206.27 103.24,205.3 105.75,202.79 108.26,205.3
GND on ART03: 195.99,159.31 209.65,159.31 210.11,159.77 213.13,159.77 220.37,152.53 222.68,152.53 222.68,150.19 222.3,149.81 197.71,149.81 195.99,151.54
GND on ART03: 7.75,203.28 25.53,203.28 28.12,200.68 28.12,189.1 26.64,187.63 26.64,182.4 26.14,181.89 9.4,181.89 8.51,182.78 8.51,186.71 1.7,193.52 1.7,197.23
GND on ART03: 165,27.74 169.37,27.74 169.7,27.41 169.7,26.69 167.77,24.76 163.63,24.76 163.58,24.82 163.58,26.31
GND on ART03: 189.84,86.36 192.15,86.36 192.28,86.49 192.28,89.18 192.15,89.31 189.84,89.31 189.71,89.18 189.71,86.49
GND on ART03: 178.44,89.66 186.33,89.66 186.46,89.53 186.46,86.79 186.92,86.33 186.92,83.74 186.97,83.69 186.97,83.08 186.82,82.93 185.67,82.93 184.86,83.74 184.28,83.74 183.85,83.31 183.85,82.32 184.33,81.84 184.33,81.2 184.18,81.05 181.31,81.05 179.25,83.11 179.25,84.96 179.76,85.47 179.5,85.72 179.5,86.51 178.44,86.51 178.31,86.64 178.31,89.53
GND on ART03: outline of 105 points within 0.51,0.51 185.93,26.42
GND on ART03: 230.96,27.53 237.52,27.53 237.52,22.83 236.58,21.89 228.63,21.89 228.57,21.84 224.33,21.84 224.16,22.02 224.16,22.91 225.25,24 225.25,26.26 225.4,26.42 229.84,26.42
GND on ART03: 90.83,49.89 90.83,46.46 98.27,46.46 98.27,49.89
GND on ART03: 111.48,52.73 121.74,52.73 123.09,51.38 125.25,51.38 126.37,50.27 126.37,48.67 124.89,47.19 122.99,47.19 121.54,48.64 121.54,49 120.98,49.55 117.73,49.55 117.4,49.22 116.66,49.22 116.36,49.53 115.9,49.53 115.65,49.78 115.65,49.86 115.24,50.27 112.12,50.27 112.01,50.16 111.48,50.7
GND on ART03: 106.05,40.87 106.05,39.19 106.38,38.86 108.84,38.86 108.84,40.59 108.56,40.87
GND on ART03: 141.73,86.49 144.4,86.49 144.4,86.74 145.92,86.74 146.69,87.5 148.34,87.5 149.61,86.23 150.75,86.23 150.88,86.36 150.88,89.53 150.24,90.17 149.86,90.17 148.21,88.52 145.16,88.52 144.27,89.41 141.48,89.41 138.43,86.36 137.29,86.36 137.03,86.61 137.03,87.25 141.1,91.31 141.1,94.36 140.59,94.87 135.51,94.87 134.11,93.47 134.11,86.99 135.89,85.22 140.46,85.22
GND on ART04: 7.75,203.28 25.53,203.28 28.12,200.68 28.12,189.05 26.62,187.55 26.62,182.63 26.75,182.5 26.14,181.89 9.4,181.89 8.51,182.78 8.51,186.71 1.7,193.52 1.7,197.23
GND on ART04: outline of 161 points within 86.58,27.24 150.6,87.02 ; 5 cut-outs
GND on ART04: outline of 119 points within 0.51,0.51 217.58,24.64
GND on ART05: outline of 228 points within 0.51,0.51 251.99,212.29 ; 1 cut-out
V11_VDD_CORE on TOP (solid shape): outline of 81 points within 101.7,145.03 110.57,156.64
VCC_5G_1V8 on TOP: 181.36,80.52 185.37,80.52 185.5,80.39 185.5,79.68 185.32,79.5 182.96,79.5 182.75,79.3 182.75,78 182.7,77.95 181.99,77.95 181,78.94 181,80.16 ; 3 cut-outs
VDD on TOP (solid shape): outline of 156 points within 126.11,116.46 131.12,129.95
VDD on ART04 (solid shape): outline of 7982 points within 11.05,121.35 129.29,168.35
VDD on TOP: 12.61,168.95 12.74,168.95 12.85,168.83 16.46,168.83 17.02,168.27 17.02,163.07 16.64,162.69 16.64,160.98 16.31,160.65 15.37,160.65 15.11,160.91 15.11,161.29 15.04,161.37 13.56,161.37 13.35,161.58 11.14,161.58 10.54,162.18 10.54,165.61 12.45,167.51 12.45,168.78 ; 1 cut-out
VDDO2 on TOP: 21.82,116.94 22.71,116.94 22.83,117.07 22.83,120.73 22.71,120.85 22.71,121.21 20.42,123.49 18.09,123.49 18.03,123.44 18.03,123.06 18.82,122.28 20.37,122.28 21.69,120.95 21.69,117.07 ; 3 cut-outs
VDDO3 on BOTTOM (solid shape): 18.16,124.97 18.16,117.37 16.13,115.34 14.14,115.34 14,115.47 13.82,115.52 13.63,115.47 13.49,115.34 12.5,115.34 12.37,115.47 12.37,116.79 12.7,117.12 13.69,117.12 14.02,116.79 16.41,116.79 17.15,117.53 17.15,124.97 17.27,125.09 18.03,125.09
VDDO3 on TOP: 9.6,115.75 13.67,115.75 13.79,115.87 13.79,116.69 13.67,116.81 9.6,116.81 9.47,116.69 9.47,115.87 ; 3 cut-outs
VDDO4 on ART04 (solid shape): 14.67,141.27 14.79,141.23 14.92,141.23 14.99,141.22 15.09,141.24 15.18,141.27 15.68,141.27 15.78,141.24 15.88,141.22 15.95,141.23 16.02,141.25 16.09,141.2 16.18,141.16 16.32,141.02 16.51,140.97 16.7,141.02 16.84,141.15 16.88,141.15 16.97,141.15 18.67,139.45 18.67,139.32 18.36,139.01 17.22,139.01 16.26,139.98 15.62,139.98 15.57,140.03 14.68,140.03 14.33,139.68 14.33,133.91 14.34,133.82 14.38,133.73 14.38,132.66 14.34,132.58 14.33,132.49 14.33,132.33 14.38,132.28 14.38,132.08 18.01,128.45 18.01,128.17 17.83,127.99 16.33,127.99 13.59,130.73 13.59,140.21 13.56,140.21 13.56,140.49 14.35,141.27
VDDO4 on TOP: 17.37,140.36 21.23,140.36 21.31,140.28 21.31,139.27 21.16,139.12 17.37,139.12 17.15,139.34 17.15,140.13 ; 3 cut-outs
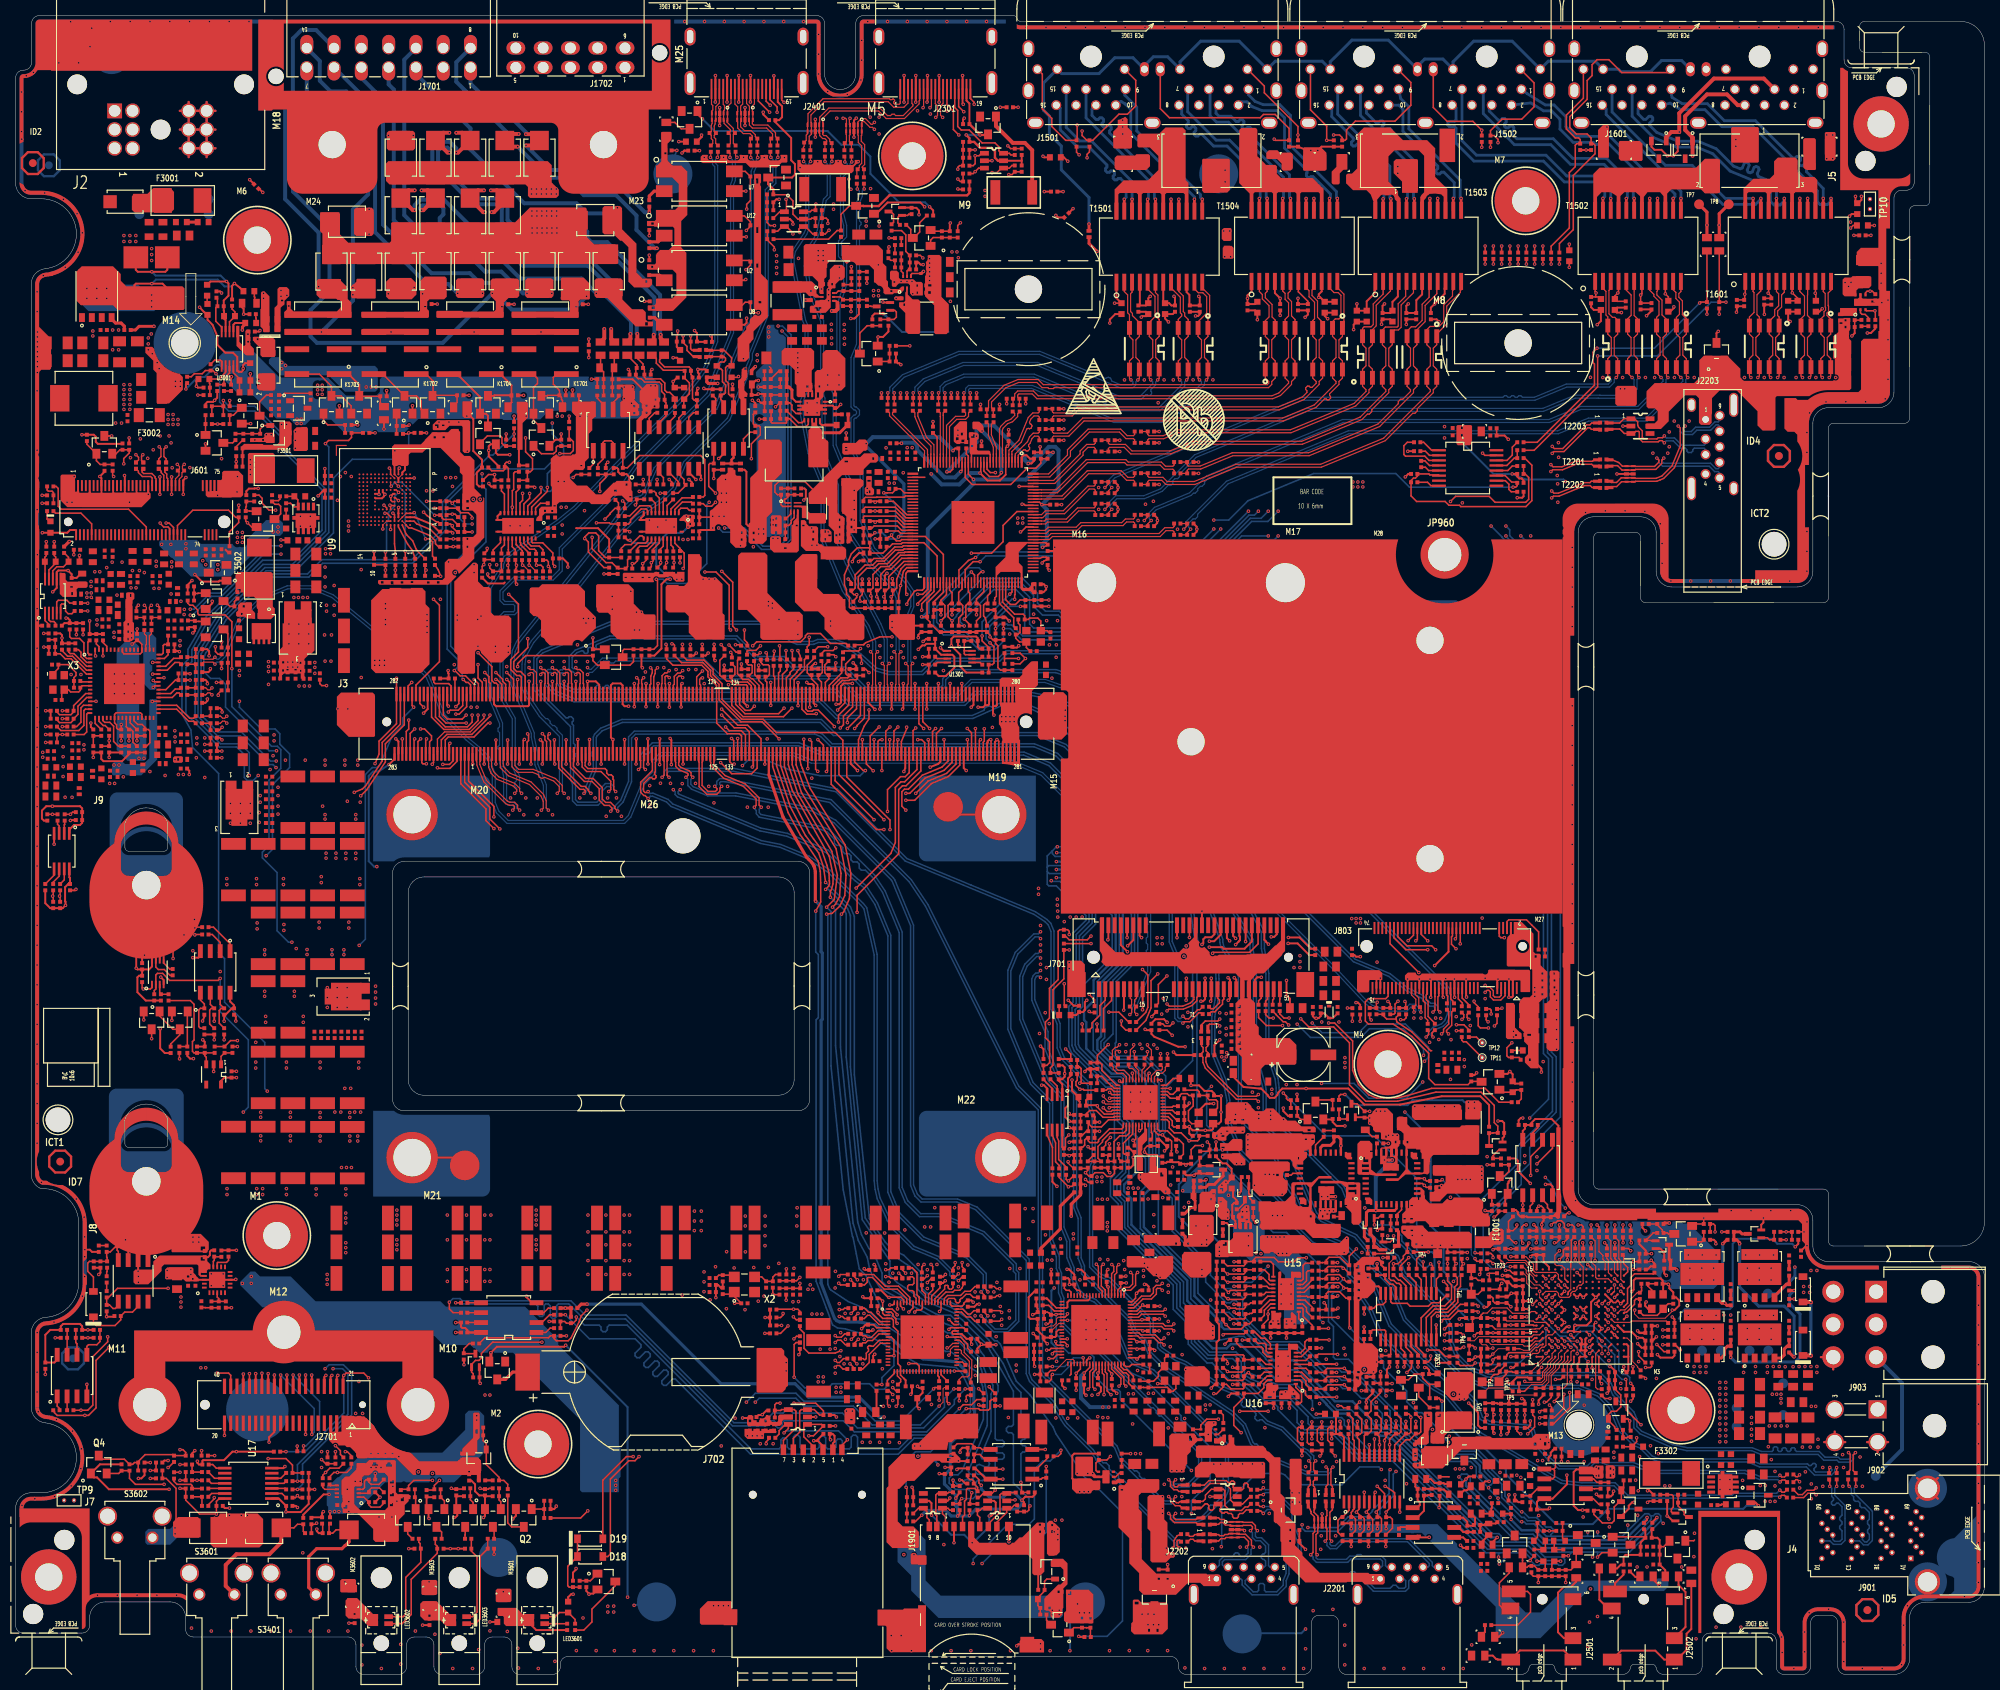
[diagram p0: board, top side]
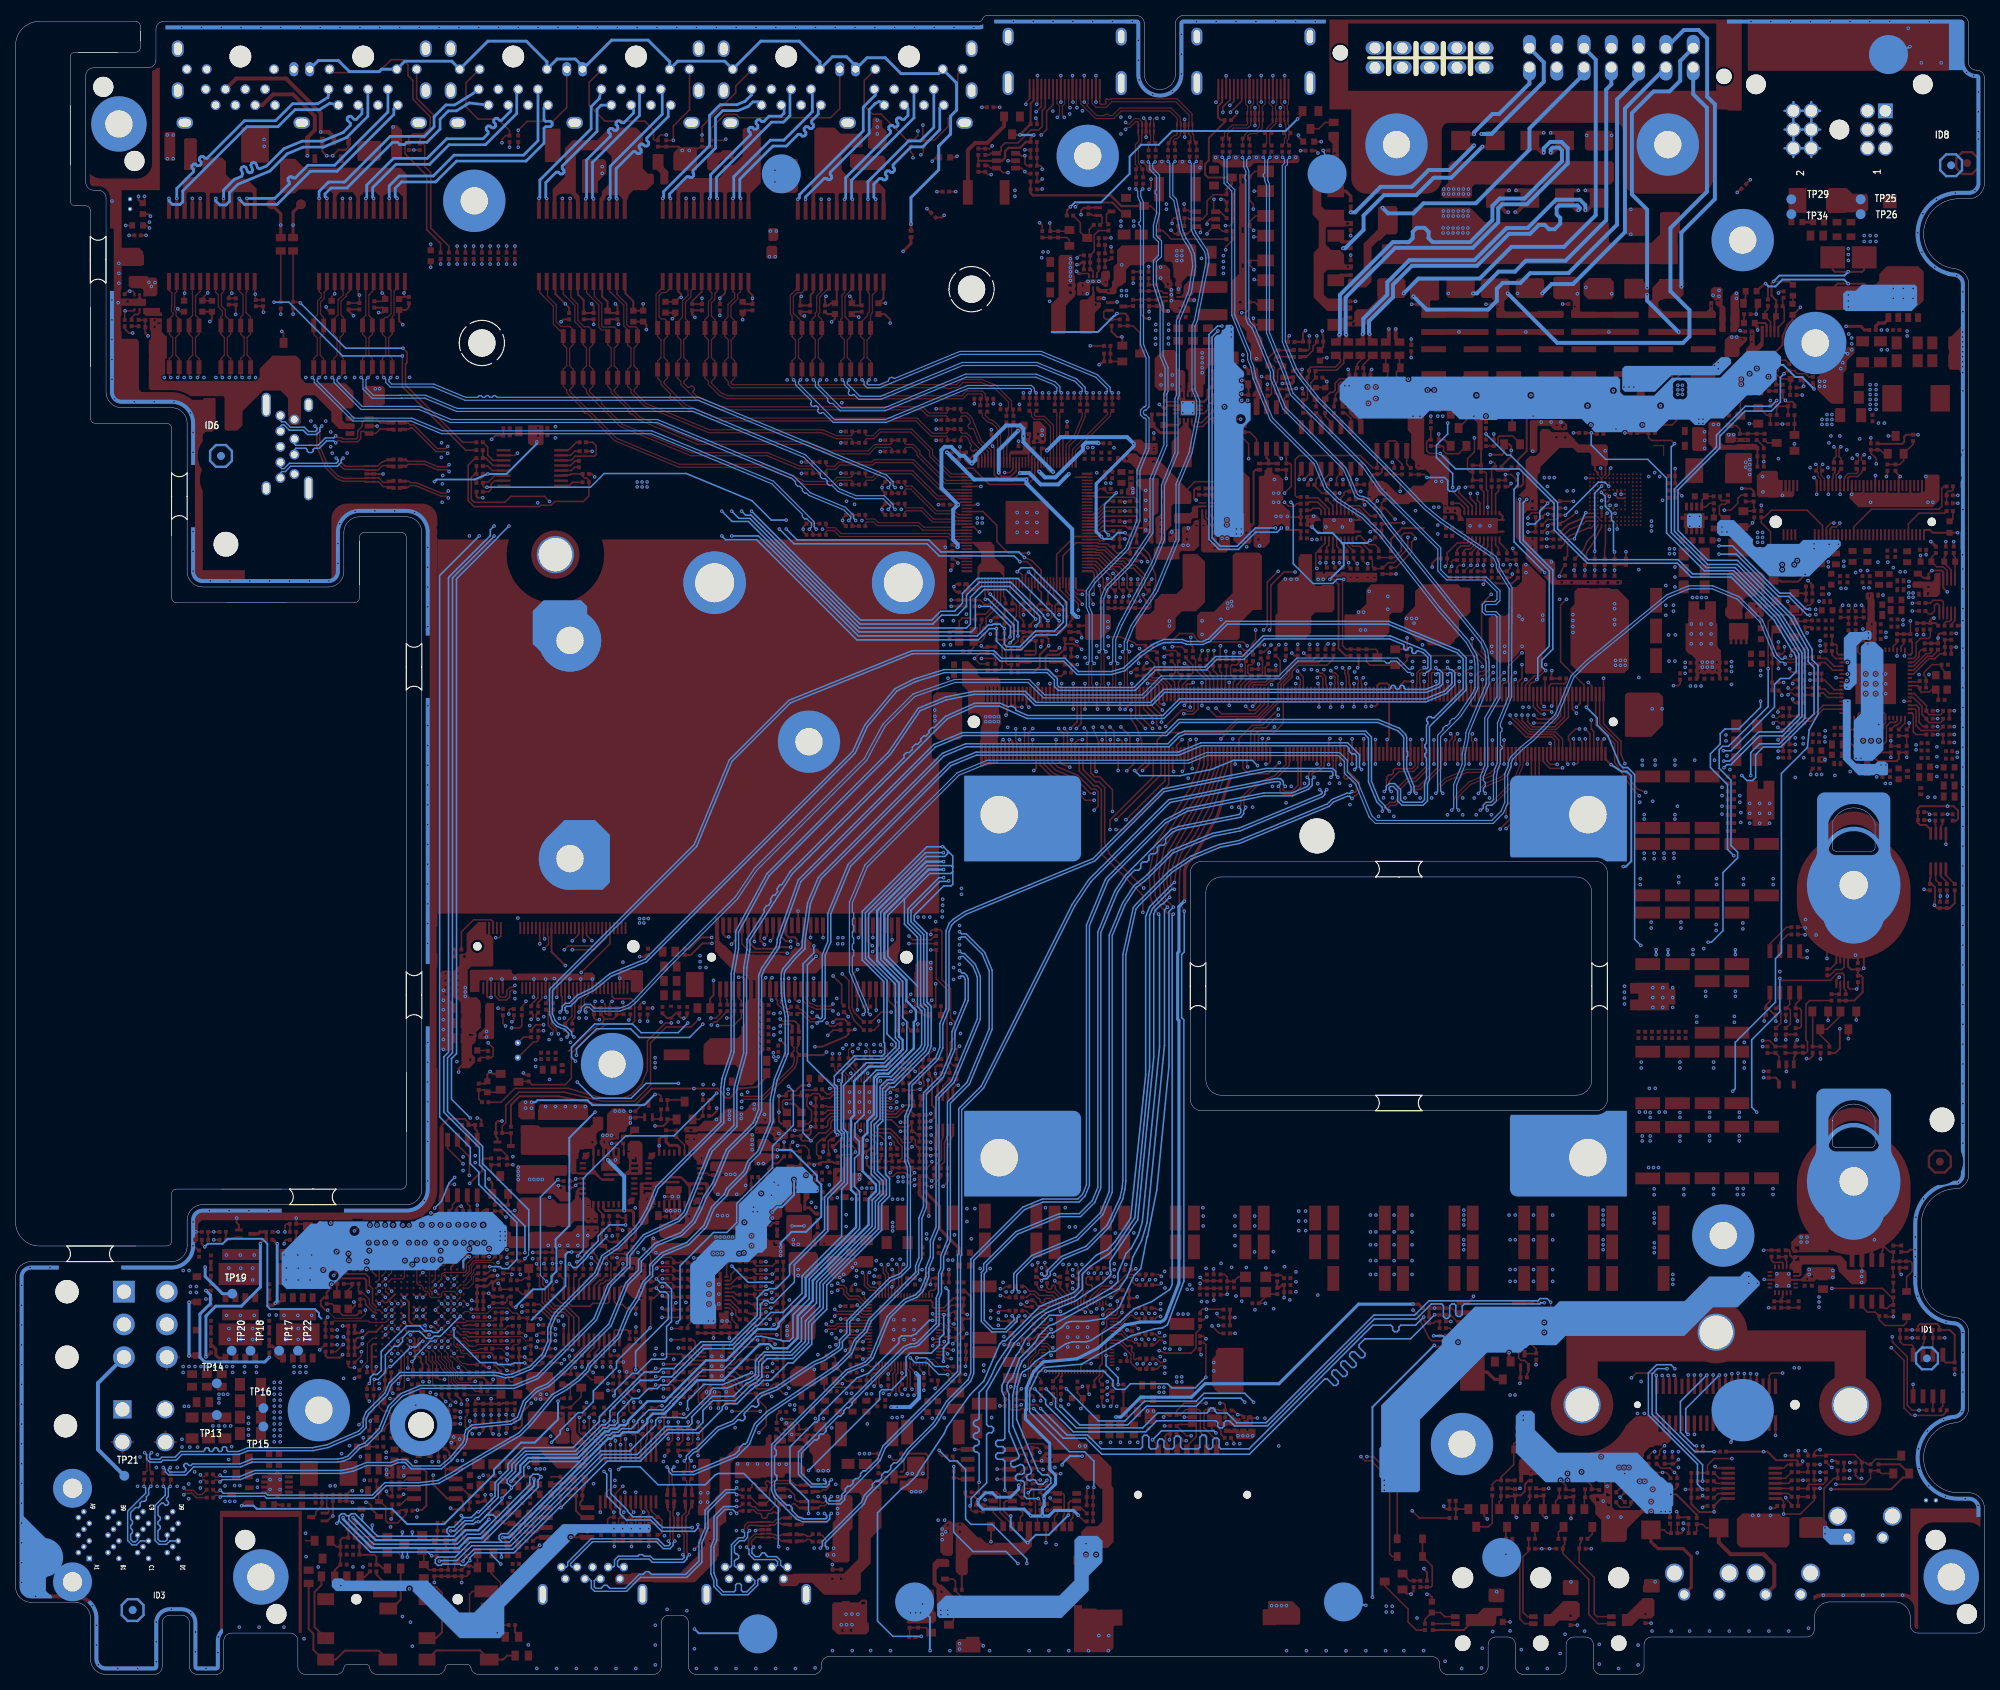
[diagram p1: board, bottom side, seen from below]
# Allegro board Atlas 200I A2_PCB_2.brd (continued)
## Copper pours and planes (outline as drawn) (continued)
VDDO5 on TOP: 20.07,136.07 20.07,137.77 19.81,138.02 19.15,138.02 18.9,137.77 18.9,135.43 17.88,134.42 17.88,134.16 17.58,133.86 17.58,131.17 17.6,131.14 18.01,131.14 18.19,131.32 18.19,132.46 19.39,133.66 19.62,133.66 19.84,133.88 19.84,135.84 ; 3 cut-outs
VDDOX on BOTTOM (solid shape): outline of 460 points within 12.95,117.2 16.76,132.46
VDDOX on TOP: 14.5,117.53 14.5,116.74 14.76,116.48 16.76,116.48 16.97,116.69 16.97,117.7 16.84,117.83 14.81,117.83 ; 1 cut-out
(no net) on TOP: 205.16,26.62 205.16,25.3 204.98,25.12 204.01,25.12 203.94,25.2 203.94,26.75 204.01,26.82 204.95,26.82 ; 2 cut-outs
(no net) on TOP: 202.7,26.79 202.46,26.54 202.13,26.54 202.12,26.55 200.54,26.55 200.48,26.49 200.48,25.76 200.58,25.65 202.26,25.65 202.41,25.5 202.41,25.27 202.57,25.12 203.53,25.12 203.63,25.22 203.63,26.76 203.6,26.79 ; 2 cut-outs
$17I27535\1V8_VDD_0 on TOP: 17.42,116.43 18.57,116.43 18.69,116.56 18.69,122.17 17.88,122.99 17.63,122.99 17.58,122.94 17.58,122.25 17.3,121.97 17.3,116.56 ; 3 cut-outs
$17I27535\1V8_VDD_1 on ART04 (solid shape): outline of 141 points within 14.58,129.49 18.24,139.78
$17I27535\1V8_VDD_1 on TOP: 11.86,139.29 14.3,139.29 14.58,139.01 15.55,139.01 16.13,139.6 16.13,140.26 16.03,140.36 11.89,140.36 11.56,140.69 11.05,140.69 10.95,140.59 10.95,139.9 11.13,139.72 11.43,139.72 ; 3 cut-outs
$17I27535\1V8_VDD_2 on TOP: 10.92,139.52 11.17,139.52 11.17,139.15 11.68,139.15 11.68,139.27 12.47,138.48 12.47,134.26 12.32,134.11 12.32,131.19 12.27,131.14 12.09,131.14 12.07,131.17 12.07,132 11.58,132.49 11.58,138.12 10.85,138.86 10.85,139.45 ; 2 cut-outs
$17I27535\3V3_IO on TOP: 3.48,114.91 4.27,114.91 4.39,115.04 4.39,118.77 4.27,118.9 3.48,118.9 3.23,118.64 3.23,117.2 3.35,117.07 3.35,115.04 ; 3 cut-outs
$17I27535\3V3_VDDIN on TOP: 7.98,113.54 8.92,113.54 9.04,113.66 9.04,117.53 9.47,117.96 9.47,119.84 9.35,119.96 7.98,119.96 7.85,119.84 7.85,113.66 ; 4 cut-outs
$17I27535\3V3_VDDIN on ART04: 9.35,125.17 10.57,125.17 10.69,125.04 10.69,123.92 10.67,123.91 10.52,123.77 10.46,123.57 10.52,123.37 10.67,123.23 10.69,123.22 10.69,119.56 9.2,118.06 8.38,118.06 8.23,118.21 8.23,124.05
$17I27535\3V3_VDDS on TOP (solid shape): 15.24,138.63 15.24,138 15.01,137.77 15.01,137.4 14.99,137.36 14.98,137.31 14.97,137.26 14.96,137.21 14.97,137.16 14.98,137.11 14.99,137.06 15.01,137.02 15.01,135.05 15.18,134.88 15.18,132.83 14.91,132.56 14.88,132.56 14.82,132.55 14.77,132.52 14.72,132.49 14.67,132.46 14.65,132.44 13.97,132.44 13.84,132.56 13.84,132.66 14.5,132.66 14.5,132.97 14.1,132.97 14.1,132.66 13.84,132.66 13.84,133.6 14.53,133.6 14.53,133.91 14.12,133.91 14.12,133.6 13.84,133.6 13.84,134.57 14.53,134.57 14.53,134.87 14.12,134.87 14.12,134.57 13.84,134.57 13.84,134.98 14.07,135.2 14.07,137.9 14.19,138.01 14.19,138.23 14.83,138.23 14.83,138.61 14.5,138.61 14.5,138.23 14.19,138.23 14.19,138.62 14.38,138.81 15.06,138.81
$17I27535\3V3_VDDS on BOTTOM (solid shape): 15.28,133.89 15.42,133.77 15.59,133.73 17.27,133.73 18.03,132.97 18.03,130.15 17.97,130.05 17.86,130.08 17.73,130.17 17.58,130.2 17.31,130.09 17.2,129.82 17.29,129.57 17.53,129.44 17.53,128.7 17.29,128.57 17.2,128.32 17.2,128.27 17.27,128.1 17.41,127.98 17.46,127.9 17.42,127.81 17.31,127.68 17.27,127.51 17.38,127.24 17.65,127.13 17.77,127.14 17.87,127.2 17.98,127.2 18.03,127.11 18.03,126.49 17.84,126.3 17.21,126.3 16.38,127.13 16.38,131.95 15.62,132.71 14.61,132.71 14.48,132.84 14.48,133.73 14.63,133.89
$51I54824\3V3_ADC on TOP: 201.55,38.46 202.08,38.46 202.44,38.1 202.44,36.7 202.97,36.17 202.97,35.33 204.11,34.19 204.11,33.53 203.71,33.53 203.71,32 204.19,32 204.6,31.6 204.6,31.1 204.26,31.1 204.26,30.89 203.89,30.89 203.88,30.89 203.02,30.89 202.21,31.7 202.21,34.34 201.42,35.13 201.42,37.72 201.3,37.85 201.3,38.23 201.55,38.23 ; 1 cut-out
$61I15303\SW on TOP (solid shape): 174.02,68.05 174.02,67.18 173.7,67.18 173.7,67.03 174.02,67.03 174.02,66.28 173.85,66.12 173.85,64.77 174.51,64.25 177.1,64.25 177.1,64.03 175.33,64.03 175.33,63.94 174.51,63.94 173.58,64.12 173.58,64.08 172.82,64.08 172.81,64.1 172.25,64.1 172.09,64.26 172.09,64.41 173.56,64.41 173.56,64.79 172.69,64.79 172.69,64.41 172.09,64.41 172.09,65.07 173.56,65.07 173.56,65.46 172.67,65.46 172.67,65.07 172.09,65.07 172.09,66.17 172.85,66.17 172.85,65.66 173.48,65.66 173.48,66.17 173.05,66.17 173.05,66.38 172.9,66.38 172.9,66.17 172.09,66.17 172.09,68.07 172.47,68.45 173.61,68.45
$71I24443\SW on TOP (solid shape): 170.89,63.14 170.89,63.17 171.62,63.17 171.67,63.12 172.34,63.12 172.47,62.99 172.47,60.88 172.59,60.75 172.59,58.04 172.24,57.68 171.55,57.68 171.32,57.91 171.32,59.25 170.5,60.07 170.5,60.08 170.76,60.08 170.76,60.23 170.5,60.23 170.45,60.27 170.45,60.88 171.56,60.88 171.56,61.18 171.42,61.18 171.42,60.88 170.45,60.88 170.45,60.97 170.61,61.14 170.62,61.85 171.75,61.85 171.75,61.59 171.96,61.59 171.96,62.17 171.93,62.18 171.7,62.2 171.6,62.23 170.94,62.23 170.94,61.85 170.62,61.85 170.62,62.48 170.61,62.48 171.73,62.48 171.93,62.56 171.96,62.59 171.96,62.74 171.83,62.86 170.94,62.86 170.94,62.48 170.61,62.48 169.96,63 167.37,63 167.37,63.31 169.96,63.31
/ALARM_IN2 on TOP (solid shape): 77.78,188.11 77.78,185.39 79.63,183.54 79.63,179.83 80.39,179.07 81.48,179.07 81.64,178.92 81.64,178.31 81.25,177.93 79.32,177.93 78.71,178.54 81.25,178.54 81.25,178.84 80.77,178.84 80.77,178.54 78.71,178.54 78.59,178.66 78.59,183.08 77.75,183.92 77.52,183.92 76.71,184.73 75.51,184.73 75.26,184.99 75.26,188.11 75.51,188.37 77.52,188.37
/ALARM_IN3 on TOP (solid shape): 77.88,178.84 77.88,176.83 77.83,176.78 77.83,176.38 79.07,175.13 80.44,175.13 80.82,174.75 80.82,173.79 81.05,173.56 81.71,173.56 81.76,173.51 81.76,173 81.69,172.92 79.53,172.92 79.4,173.05 81.41,173.05 81.41,173.46 80.75,173.46 80.75,173.05 79.4,173.05 75.87,176.58 74.5,176.58 74.24,176.83 74.24,178.84 74.5,179.09 77.62,179.09
ALARM_OUT0_REF0 on TOP (solid shape): 68.99,178.84 68.99,176.83 68.73,176.58 65.61,176.58 65.35,176.83 65.35,178.84 65.61,179.09 68.73,179.09
ALARM_OUT0_REF0 on TOP (solid shape): 72.2,172.53 72.2,171.92 72.12,171.84 63.77,171.84 63.63,171.98 63.63,172.47 63.75,172.59 72.14,172.59
ALARM_OUT0_REF1 on TOP (solid shape): 73.66,178.38 73.66,176.5 73.53,176.38 72.42,176.38 72.19,176.15 72.19,174.14 72.09,174.04 63.78,174.04 63.63,174.19 63.63,174.7 63.75,174.83 71.02,174.83 71.08,174.89 71.08,175.39 72.06,175.39 72.06,175.72 71.78,175.72 71.78,175.39 71.08,175.39 71.08,175.7 71.09,175.72 71.09,176.12 70.94,176.28 70.05,176.28 69.9,176.43 69.9,176.68 69.93,176.71 69.93,179.04 70.08,179.2 72.85,179.2
ALARM_OUT1_REF0 on TOP (solid shape): 51.41,178.46 51.41,177.01 50.8,176.4 47.85,176.4 47.52,176.73 47.52,178.66 48.01,179.15 50.72,179.15
ALARM_OUT1_REF0 on TOP (solid shape): 52.96,172.51 52.96,172.01 52.81,171.86 44.49,171.86 44.34,172.01 44.34,172.41 44.54,172.62 52.86,172.62
ALARM_OUT1_REF1 on TOP (solid shape): 55.3,179.09 55.3,176.73 54.97,176.4 53.09,176.4 52.78,176.1 52.78,175.16 53.01,174.93 53.01,174.19 52.86,174.04 44.5,174.04 44.35,174.19 44.35,174.73 44.42,174.8 51.74,174.8 51.87,174.93 51.87,175.41 52.65,175.41 52.65,175.77 52.4,175.77 52.4,175.41 51.87,175.41 51.87,178.74 52.45,179.32 55.07,179.32
ALARM_OUT2_REF0 on TOP (solid shape): 60.1,178.84 60.1,176.83 59.84,176.58 56.72,176.58 56.46,176.83 56.46,178.84 56.72,179.09 59.84,179.09
ALARM_OUT2_REF0 on TOP (solid shape): 62.59,172.49 62.59,171.98 62.44,171.84 54.01,171.84 53.92,171.93 53.92,172.51 54,172.59 62.48,172.59
ALARM_OUT2_REF1 on TOP (solid shape): 64.59,178.82 64.59,176.83 64.34,176.58 63.22,176.58 62.66,176.02 62.61,176.02 62.59,176 62.59,174.22 62.41,174.04 54.1,174.04 53.98,174.17 53.98,174.85 54.05,174.93 57.3,174.93 57.4,174.83 61.34,174.83 61.58,175.07 61.58,175.39 62.48,175.39 62.48,175.79 62.26,175.79 62.26,175.39 61.58,175.39 61.58,176.16 60.91,176.83 60.91,178.82 61.16,179.07 64.34,179.07
ALARM_OUT3_REF0 on TOP (solid shape): 43.03,172.57 43.03,171.91 42.95,171.83 34.6,171.83 34.49,171.93 34.49,172.54 34.57,172.62 42.98,172.62
ALARM_OUT3_REF0 on TOP (solid shape): 46.15,178.87 46.15,176.61 46.08,176.53 43.18,176.53 43.03,176.68 43.03,178.08 43.26,178.31 43.33,178.31 43.71,178.69 43.71,178.94 43.82,179.04 45.97,179.04
ALARM_OUT3_REF1 on TOP (solid shape): 42.6,177.9 42.6,176.45 43.08,175.97 43.08,174.09 43.03,174.04 34.52,174.04 34.47,174.09 34.47,174.78 34.8,175.11 34.8,175.46 35.13,175.46 35.13,175.87 34.93,175.87 34.93,175.46 34.8,175.46 34.8,176.1 34.85,176.15 35.26,176.15 35.28,176.12 35.28,175.21 35.64,174.85 41.2,174.85 41.82,175.48 41.82,176.03 41.53,176.33 41.28,176.33 41.1,176.5 39.04,176.5 38.58,176.96 38.58,178.76 38.84,179.02 41.48,179.02
CAN_H_R on TOP (solid shape): 45.92,187.91 45.92,184.78 45.67,184.53 43.66,184.53 43.41,184.78 43.41,187.91 43.66,188.16 45.67,188.16
CAN_L_R on TOP (solid shape): 51.23,197.75 51.23,195.75 50.98,195.49 47.85,195.49 47.6,195.75 47.6,197.75 47.85,198.01 50.98,198.01
GE_RV1 on TOP (solid shape): 150.06,198.07 150.06,191.69 150.43,191.33 150.43,186.66 150.4,186.64 149.97,186.64 149.95,186.66 149.95,189.86 149.76,190.04 147.61,190.04 147.43,189.86 147.43,186.66 147.4,186.64 146.97,186.64 146.95,186.66 146.95,189.86 146.76,190.04 144.61,190.04 144.43,189.86 144.43,186.66 144.4,186.64 143.97,186.64 143.94,186.66 143.94,189.86 143.76,190.04 141.61,190.04 141.43,189.86 141.43,186.66 141.4,186.64 140.97,186.64 140.94,186.66 140.94,190.5 142.11,191.67 145.24,191.67 146.56,192.99 146.56,194.79 145.47,195.88 144.02,195.88 143.87,196.04 143.87,197.41 144.12,197.66 146.69,197.66 147.47,198.45 149.68,198.45
GE_RV2 on TOP (solid shape): 159.26,198.14 159.26,194.77 160.38,193.65 161.57,193.65 161.75,193.47 161.75,192.51 162.28,191.97 166.33,191.97 167.75,190.55 167.75,186.77 167.73,186.74 167.29,186.74 167.27,186.77 167.27,189.96 167.09,190.14 164.93,190.14 164.75,189.97 164.75,186.77 164.73,186.74 164.29,186.74 164.27,186.77 164.27,189.96 164.09,190.14 161.93,190.14 161.75,189.97 161.75,186.77 161.73,186.74 161.29,186.74 161.27,186.77 161.27,189.96 161.09,190.14 158.93,190.14 158.75,189.97 158.75,186.77 158.72,186.74 158.29,186.74 158.27,186.77 158.27,189.97 156.92,191.31 156.92,198.12 157.2,198.4 159,198.4
GE_RV3 on TOP (solid shape): 177.93,196.82 181.03,196.82 182.07,195.78 182.07,192.11 183.63,190.55 183.63,186.77 183.6,186.74 183.17,186.74 183.14,186.77 183.14,189.56 182.83,189.86 182.09,189.97 181.32,189.92 181.22,189.8 181.19,189.8 181.17,189.78 181.04,189.69 180.95,189.56 180.93,189.53 180.91,189.44 180.63,189.1 180.63,186.77 180.6,186.74 180.17,186.74 180.14,186.77 180.14,189.41 180.14,189.51 180.33,189.82 180.65,190.14 180.65,194.82 179.96,195.5 176.84,195.5 176.07,194.74 176.07,191.5 177.3,190.27 177.3,189.75 177.44,189.55 177.63,189.35 177.63,186.77 177.6,186.74 177.17,186.74 177.14,186.77 177.14,188.94 176.86,189.25 176.87,189.29 176.86,189.37 176.84,189.48 176.82,189.51 176.8,189.53 176.78,189.65 176.6,189.78 176.38,189.83 176.33,189.83 176.2,189.8 176.09,189.74 175.68,189.74 175.54,189.8 175.38,189.83 175.23,189.81 175.1,189.75 175.09,189.74 174.63,189.19 174.63,186.77 174.6,186.74 174.17,186.74 174.14,186.77 174.14,188.92 173.79,189.86 173.25,190.4 171.53,190.4 170.64,191.29 170.64,192.33 170.84,192.53 171.4,192.53 172.06,193.19 172.06,197.59 172.92,198.45 176.3,198.45
GE_RV4 on TOP (solid shape): 218.57,194.18 218.57,190.25 218.31,189.99 216.66,189.99 216.15,190.5 212.34,190.5 211.82,189.97 211.82,186.77 211.79,186.74 211.36,186.74 211.34,186.77 211.34,189.64 210.91,190.14 209.3,190.14 208.82,189.53 208.82,186.77 208.79,186.74 208.36,186.74 208.34,186.77 208.34,189.64 207.77,190.14 206.32,190.14 205.82,189.66 205.82,186.77 205.79,186.74 205.36,186.74 205.34,186.77 205.34,189.66 204.57,190.14 203.4,190.14 202.82,189.53 202.82,186.77 202.79,186.74 202.36,186.74 202.34,186.77 202.34,192.48 203.15,193.29 215.52,193.29 216.66,194.44 218.31,194.44
GE_RV5 on TOP (solid shape): 228.55,194.28 228.55,192.71 229.16,192.1 230.68,192.1 231.07,191.71 231.07,186.77 231.05,186.74 230.62,186.74 230.59,186.77 230.59,189.96 230.41,190.14 228.25,190.14 228.07,189.97 228.07,186.77 228.05,186.74 227.62,186.74 227.59,186.77 227.59,189.96 227.41,190.14 225.25,190.14 225.07,189.97 225.07,186.77 225.05,186.74 224.62,186.74 224.59,186.77 224.59,189.96 224.41,190.14 222.25,190.14 222.07,189.97 222.07,186.77 222.05,186.74 221.62,186.74 221.59,186.77 221.59,190.6 222.86,191.87 224.97,191.87 225.53,192.43 225.53,194.11 226.01,194.59 228.24,194.59
HUB_1V2_LX on TOP: 135,40.13 134.24,40.13 133.1,38.99 133.1,37.46 132.59,36.96 131.06,36.96 130.81,36.7 130.81,35.56 131.06,35.31 133.48,35.31 133.6,35.43 133.6,36.4 133.77,36.56 133.77,38.01 134.75,38.99 135.13,38.99 135.13,40
HUB_1V2_SWR on TOP: 125.83,40.74 122.91,40.74 122.68,40.51 122.68,39.73 122.96,39.45 125.93,39.45 126.06,39.57 126.06,40.51
HUB_3V3_LX on TOP: 132.28,49.63 133.55,48.36 133.55,47.93 133.96,47.52 134.44,47.52 134.47,47.5 134.47,47.32 133.58,47.32 133.41,47.48 133.41,47.59 132.21,48.79 131.55,48.79 131.48,48.86 131.48,50.4 131.67,50.6 132.11,50.6 132.28,50.42 ; 2 cut-outs
MAC_GND on TOP (solid shape): 155.73,194.31 155.73,190.42 155.4,190.09 152.4,190.09 152.17,190.32 152.17,194.31 152.3,194.44 155.6,194.44
MAC_GND on TOP (solid shape): 155.96,185.42 155.96,184.02 155.83,183.9 154.94,183.9 154.69,184.15 154.69,185.29 154.94,185.55 155.83,185.55
MAC_GND on TOP (solid shape): 223.57,198.37 223.57,194.06 223.44,193.93 220.14,193.93 220.02,194.06 220.02,198.37 220.14,198.5 223.44,198.5
MAC_GND on TOP (solid shape): 204.34,198.63 204.34,194.56 203.07,194.56 202.95,194.69 202.95,198.12 203.58,198.75 204.22,198.75
MAC_GND on TOP (solid shape): 168.12,195.2 168.12,193.06 167.95,192.89 165.23,192.89 165.13,192.99 165.13,195.78 165.25,195.91 167.41,195.91
MAC_GND on TOP (solid shape): 179.85,194.19 179.85,190.33 179.64,190.12 177.93,190.12 177.93,191.39 176.73,192.58 176.73,194.08 177.04,194.39 179.65,194.39
MAC_GND on TOP (solid shape): 233.43,197.74 233.43,194.44 233.17,194.18 232.16,194.18 232.04,194.3 232.04,194.96 232.03,194.97 232.03,197.74 232.16,197.87 233.3,197.87
MAC_GND on TOP (solid shape): 142.62,199.52 142.62,198.48 143.18,197.92 143.18,195.88 143.05,195.76 140.89,195.76 140.77,195.88 140.77,197.92 141.35,198.5 141.35,199.42 141.85,199.56 142.3,199.84
MAC_GND on ART03 (solid shape): 233.43,211.03 129.29,211.03 129.29,211.54 233.43,211.54
MAC_GND on ART02: 128.27,199.65 128.27,211.78 128.57,211.61 128.91,211.54 128.92,211.54 232.66,211.54 233.5,211.54 233.59,211.53 233.68,211.51 233.68,189.23 233.73,188.99 233.87,188.78 235.08,187.83 235.46,187.45 236.09,187.45 236.22,187.32 236.22,184.41 235.96,184.15 202.08,184.15 201.84,184.1 201.63,183.96 200.42,182.75 188.98,182.75 187.77,183.96 187.56,184.1 187.32,184.15 138.69,184.15 133.81,189.04 133.81,195.76 133.76,196 133.62,196.21 131.89,197.93 131.69,198.07 131.45,198.12 129.8,198.12 ; 1 cut-out
MAC_GND on ART05: 128.27,199.65 128.27,211.78 128.57,211.61 128.91,211.54 128.92,211.54 232.54,211.54 233.5,211.54 233.59,211.53 233.68,211.51 233.68,189.23 233.73,188.99 233.87,188.78 235.2,187.71 236.09,187.32 236.22,187.32 236.22,184.41 235.96,184.15 202.08,184.15 201.84,184.1 201.63,183.96 200.42,182.75 188.98,182.75 187.77,183.96 187.56,184.1 187.32,184.15 138.69,184.15 133.81,189.04 133.81,195.76 133.76,196 133.62,196.21 131.89,197.93 131.69,198.07 131.45,198.12 129.8,198.12 ; 1 cut-out
PHX_GND on TOP (solid shape): 68.76,193.62 68.76,191.39 69.67,190.47 69.67,189.74 69.34,189.41 65.96,189.41 65.71,189.66 65.71,190.8 65.38,191.13 47.96,191.13 47.5,191.59 47.5,193.83 47.8,194.13 68.25,194.13
PHX_GND on TOP (solid shape): 35.1,177.65 35.1,176.83 34.47,176.2 34.47,175.79 33.99,175.31 33.99,172.36 33.83,172.21 33.27,172.21 33.2,172.29 33.2,175.31 33.58,175.69 33.58,175.92 34.32,175.92 34.32,176.35 34.04,176.35 34.04,175.92 33.58,175.92 33.58,177.72 33.83,177.98 34.77,177.98
PHX_GND on TOP (solid shape): 73.25,188.01 73.25,184.4 74.19,183.46 76.89,183.46 77.27,183.08 77.27,181.13 77.06,180.92 39.47,180.92 39.34,181.05 39.34,184.84 39.07,185.11 39.07,187.38 39.24,187.55 41.4,187.55 41.61,187.35 41.61,184.73 42.67,183.67 47.96,183.67 48.18,183.9 48.18,186.16 48.31,186.28 64.06,186.28 65.96,188.19 73.08,188.19
PHX_GND on TOP (solid shape): outline of 293 points within 31.12,189.95 84,212.29
PHX_GND on ART02, ART05: 34.29,212.29 83.19,212.29 83.19,202.56 83.23,202.32 83.37,202.12 86.16,199.33 86.16,176.07 86.22,175.79 86.41,175.57 87.63,174.34 87.63,169.81 87.37,169.54 86.62,169.54 85.59,170.58 85.38,170.72 85.14,170.76 72.34,170.76 72.1,170.72 71.89,170.58 70.5,169.19 35.47,169.19 34.93,169.73 34.93,170.77 34.88,171.01 34.74,171.22 33.48,172.48 33.48,177.34 33.43,177.59 33.29,177.79 27.94,183.14 27.94,187.06 34.1,193.23 34.24,193.43 34.29,193.67
PLLVDDL0 on TOP (solid shape): 104.65,146.56 104.65,146.02 104.64,146.02 104.64,145.36 104.52,145.24 103.38,145.24 103.23,145.39 103.23,145.47 103.91,145.47 103.91,145.77 103.51,145.77 103.51,145.47 103.23,145.47 103.23,145.9 104.55,145.9 104.55,146.23 104.24,146.23 104.24,145.9 103.23,145.9 103.23,146.46 103.91,146.46 103.91,146.76 103.56,146.76 103.56,146.46 103.23,146.46 103.23,146.84 103.3,146.91 104.29,146.91
REFER_2V5 on TOP: 176.94,16.08 177.7,15.32 185.01,15.32 186.31,14.02 186.31,13.84 187.25,12.9 188.06,12.9 188.19,13.03 188.19,14.71 188.37,14.88 188.37,15.75 188.27,15.85 187.63,15.85 187.35,16.13 187.35,17.35 187.3,17.4 186.74,17.4 186.64,17.3 186.64,16.76 186.46,16.59 178.33,16.59 177.85,17.07 177.85,18.06 177.77,18.14 177.04,18.14 176.94,18.03 ; 5 cut-outs
TEC+ on ART03 (solid shape): 226.24,46.33 226.24,42.24 226.11,42.11 221.64,42.11 221.51,42.24 221.51,46.33 221.64,46.46 226.11,46.46
TEC+ on TOP: 236.22,51.56 239.4,51.56 240.28,50.67 240.28,42.93 239.52,42.16 239.31,42.16 238.97,42.28 238.61,42.32 238.25,42.28 237.9,42.16 235.71,42.16 234.95,42.93 229.24,42.93 228.35,43.81 228.35,44.7 227.94,45.11 226.9,45.11 226.57,44.78 226.57,42.42 226.19,42.04 220.98,42.04 220.73,42.29 220.73,48.51 221.36,49.15 224.66,49.15 224.92,48.89 224.92,47.62 225.04,47.5 226.57,47.5 226.59,47.52 228.19,47.52 228.73,46.99 234.82,46.99 235.71,47.88 235.71,51.05 ; 3 cut-outs
TEC+ on BOTTOM: 221.36,40.77 226.19,40.77 226.44,41.02 226.44,46.48 226.19,46.74 221.36,46.74 221.11,46.48 221.11,41.02
TEC- on ART03 (solid shape): 220.47,46.33 220.47,42.24 220.35,42.11 215.06,42.11 214.09,43.08 214.09,46.27 214.28,46.46 220.35,46.46
TEC- on ART04 (solid shape): outline of 721 points within 213.82,41 242.06,51.43
TEC- on TOP: 214.12,49.02 217.17,49.02 217.3,48.89 217.3,47.62 218.06,46.86 220.09,46.86 220.22,46.74 220.22,45.24 220.09,45.11 219.66,45.11 219.08,44.53 219.08,42.29 218.95,42.16 213.49,42.16 213.36,42.29 213.36,44.98 213.89,45.52 213.89,48.79 ; 1 cut-out
TEC- on TOP: 228.6,49.28 229.11,48.77 230.38,48.77 231.52,47.62 234.32,47.62 234.82,48.13 234.82,50.67 233.93,51.56 231.78,51.56 230.25,53.09 229.92,53.09 229.92,53.34 229.36,53.9 228.78,53.9 228.6,53.72 ; 1 cut-out
TEC- on BOTTOM: 242.16,50.96 242.95,50.16 242.95,44.32 241.43,42.8 236.6,42.8 234.78,44.62 234.79,44.76 234.8,44.9 234.3,46.09 233.11,46.59 232.97,46.58 232.83,46.57 231.27,48.13 229.36,48.13 228.85,48.64 228.85,50.29 229.52,50.96 ; 1 cut-out
TEC- on BOTTOM: 220.35,41.4 220.35,46.23 220.09,46.48 214.5,46.48 214.25,46.23 214.25,41.4 214.76,40.89 219.84,40.89
USB1_5V0 on TOP (solid shape): outline of 89 points within 151.44,11.53 175.6,30.76
USB2_5V0 on TOP (solid shape): 146.69,24.95 146.69,23.76 146.21,23.29 144.38,23.29 144.04,22.95 144.04,21.24 144.42,20.86 144.42,14.81 146.3,12.93 152.72,12.93 152.75,12.9 152.8,12.85 152.82,12.83 154.35,12.83 154.61,12.57 154.61,11.61 154.33,11.33 152.35,11.33 151.93,11.75 150.36,11.75 148.82,10.21 144.65,10.21 144.09,10.77 144.09,12.14 146.76,12.14 146.76,12.17 147.88,12.17 147.88,12.62 147.63,12.62 147.63,12.17 146.76,12.17 146.76,12.67 146.48,12.67 146.48,12.14 144.09,12.14 144.09,12.98 142.82,14.25 142.82,17.47 141.44,18.85 141.44,23.6 142.04,23.6 142.04,23.98 141.73,23.98 141.73,23.6 141.44,23.6 141.44,24.15 141.55,24.25 142.18,24.25 142.56,24.63 142.56,24.92 142.7,25.06 146.58,25.06
USB3_5V0 on TOP (solid shape): outline of 147 points within 209.04,159.56 235.41,174.01
USIM0_PWR on TOP (solid shape): 99.7,33.3 99.7,32.74 99.64,32.69 98.53,32.69 98.3,32.46 98.3,32.13 98.04,31.88 97.28,31.88 97.28,32 96.77,32 96.77,31.88 93.98,31.88 93.87,31.99 93.87,32.02 93.8,32.08 93.8,32.23 94.34,32.23 94.34,32.69 94.03,32.69 94.03,32.23 93.8,32.23 93.8,33.02 93.97,33.19 94.62,33.19 94.62,32.61 95.05,32.61 95.05,32.26 96.32,32.26 96.32,32.69 96.04,32.69 96.04,32.26 95.35,32.26 95.35,32.61 95.43,32.61 95.43,32.87 95.6,32.87 95.64,32.85 95.72,32.84 95.79,32.84 95.85,32.85 95.92,32.87 95.98,32.89 96.03,32.92 96.08,32.96 96.13,33.01 96.17,33.06 96.2,33.12 96.22,33.18 96.23,33.24 96.24,33.27 96.52,33.27 96.52,32.89 96.77,32.89 96.77,32.64 97.03,32.38 97.66,32.38 97.79,32.51 97.79,33.15 97.99,33.35 98.5,33.35 98.5,33.35 99.64,33.35
V_3V3_4G on TOP (solid shape): outline of 285 points within 139.04,75.59 164.26,97.1
V_3V3_USBHUB0 on TOP: 113.87,37.19 114.33,37.19 114.4,37.11 114.4,36.5 114.55,36.35 114.55,33.65 114.43,33.53 113.41,33.53 112.75,32.87 112.75,31.83 112.62,31.7 110.24,31.7 109.86,32.08 109.86,34.16 109.98,34.29 111,34.29 111.25,34.04 112.07,34.04 112.14,34.11 113.26,34.11 113.67,34.52 113.67,36.98 ; 1 cut-out
V_3V3_USBHUB0 on TOP: 120.42,46.18 121.03,46.18 121.39,45.82 122.45,45.82 124.08,44.2 125.73,44.2 126.09,43.84 126.09,42.16 124.56,42.16 124.08,42.65 123.72,42.65 122.43,43.94 122.43,44.58 122.3,44.7 121.59,44.7 121.26,45.03 120.6,45.03 120.29,45.34 120.29,45.41 121.06,45.41 121.06,45.54 120.29,45.54 120.29,45.8 121.06,45.8 121.06,45.95 120.29,45.95 120.29,46.05 ; 1 cut-out
V_5V0_HUB on TOP: 140.21,56.26 144.27,56.26 144.53,56.01 144.53,55.12 144.65,54.99 145.92,54.99 146.18,54.74 146.18,53.72 146.05,53.59 145.03,53.59 144.46,54.16 142.18,54.16 141.55,53.54 137.77,53.54 136.63,52.4 134.47,52.4 134.19,52.12 134.19,51.84 134.04,51.69 134.04,48.97 134.49,48.51 134.49,47.7 134.01,47.7 133.71,48.01 133.71,48.64 132.97,49.38 132.97,49.68 133.21,49.92 133.21,52.44 133.45,52.68 133.88,52.68 135.45,54.24 136.87,54.24 137.12,54.5 139.46,54.5 139.95,54.99 139.95,56.01 ; 3 cut-outs
V_5V0_HUB on TOP: 133.07,42.8 133.38,42.49 133.38,40.84 133.5,40.72 134.47,40.72 134.47,40.51 134.42,40.46 134.01,40.46 134.01,40.21 133.68,39.88 131.88,39.88 131.85,39.9 131.44,39.9 131.12,40.23 131.12,42.67 131.24,42.8 ; 3 cut-outs
V_12V0_CON_IN on TOP: 12.42,202.74 15.29,202.74 16.89,201.14 16.89,195.05 16.87,195.02 16.87,188.9 16.89,188.87 16.89,186.82 16.94,186.77 20.96,186.77 21.01,186.71 21.01,185.93 20.96,185.88 16.43,185.88 15.98,185.42 15.98,183.95 16.36,183.57 21.39,183.57 21.82,183.13 21.82,180.75 21.59,180.52 13.31,180.52 12.47,181.36 10.9,181.36 9.12,183.13 9.12,190.17 11.33,192.38 11.33,201.65
V_12V0_CON_IN on BOTTOM: 16.38,202.44 10.16,202.44 9.4,201.68 9.4,191.52 12.73,188.19 12.73,182.45 14.25,180.92 20.88,180.92 22.1,182.14 22.1,188.72 16.89,193.93 16.89,201.93
V_12V0_IN on TOP (solid shape): 33.3,171.2 33.3,169.93 33.35,169.87 33.35,169.19 33.17,169.01 31.62,169.01 31.39,169.24 31.39,170.13 30.56,170.97 30.56,171.17 31.14,171.17 31.14,171.4 30.79,171.4 30.79,171.17 30.56,171.17 30.56,171.58 30.58,171.6 31.34,171.6 31.4,171.66 31.43,171.66 31.5,171.68 31.56,171.7 31.62,171.73 31.68,171.77 31.71,171.79 32.71,171.79
V_12V0_IN on ART04 (solid shape): outline of 683 points within 9.42,171.32 32.77,179.45
V_12V0_IN on TOP: 11.18,174.88 11.56,174.5 11.56,173.46 11.15,173.05 11.15,172.16 11.07,172.08 10.41,172.08 10.16,171.83 10.16,171.58 9.59,171 9.59,166.56 7.62,164.59 7.62,162.18 7.24,161.8 4.45,161.8 4.19,162.05 4.19,166.24 5.59,167.64 5.59,174.37 6.1,174.88 ; 1 cut-out
V_12V0_SENSE on TOP (solid shape): 13.49,179.65 13.49,178.79 14.2,178.08 21.39,178.08 21.67,177.8 21.67,175.18 21.51,175.03 13.11,175.03 12.51,175.63 12.51,175.64 8.38,175.64 7.79,176.24 7.79,179.95 8.48,180.64 12.5,180.64
V_12V0_SENSE on BOTTOM (solid shape): 16.49,177.52 17.72,177.52 18.12,177.11 18.12,175.24 17.77,174.89 9.34,174.89 8.59,175.64 8.59,175.85 8.64,175.89 8.64,178 8.92,178.28 15.72,178.28
V_ADJ_TEC on TOP (solid shape): 190.86,56.97 190.86,55.55 190.42,55.12 189.59,55.12 189.26,54.79 189.21,54.75 189.15,54.69 187.25,54.69 187.17,54.76 187.17,56.21 188.97,56.21 188.97,56.74 189.18,56.74 189.64,57.2 190.63,57.2
V_ADJ_TEC on BOTTOM (solid shape): outline of 2265 points within 189.48,49.45 218.39,59.33
V_ADJ_TEC on ART03 (solid shape): 226.57,54.63 226.57,50.11 226.44,49.99 214.3,49.99 213.82,50.47 213.82,54.63 213.94,54.76 226.44,54.76
V_ADJ_TEC on TOP: 213.49,49.78 219.48,49.78 219.61,49.91 220.35,49.91 220.47,49.78 226.31,49.78 226.57,50.04 226.57,53.21 226.82,53.47 227.71,53.47 227.97,53.72 227.97,54.61 227.71,54.86 213.49,54.86 213.11,54.48 213.11,50.16 ; 2 cut-outs
V_AVDD_1V0_PHY0 on TOP: 148.34,65.3 148.9,65.3 149.35,64.85 149.35,61.7 149.28,61.62 148.69,61.62 148.59,61.72 148.59,62.03 147.98,62.64 147.98,64.95 ; 3 cut-outs
V_AVDD_1V0_PHY0 on BOTTOM: 148.87,62.2 147.75,62.2 147.55,62.41 147.55,65.81 147.83,66.09 147.83,75.44 148.01,75.62 149.05,75.62 149.45,75.21 149.45,68.45 150.01,67.89 150.01,65.99 149.48,65.46 149.45,65.46 149.45,63.88 148.97,63.4 148.97,62.31
V_AVDD_3V3_PHY0 on TOP: 145.03,61.98 145.03,61.59 144.93,61.49 142.47,61.49 142.37,61.59 142.37,63.25 142.42,63.3 143.71,63.3 ; 4 cut-outs
V_BAT_3V0 on ART04 (solid shape): outline of 270 points within 38.35,40.13 61.6,104.01
V_DV11_HUB on TOP: 134.9,38.68 135.33,38.68 135.43,38.58 135.43,35.99 135.69,35.74 135.97,35.74 136.98,34.72 140.59,34.72 140.69,34.62 142.29,34.62 142.75,34.16 149.23,34.16 149.73,34.67 149.73,36.07 149.99,36.32 150.65,36.32 150.77,36.19 150.77,33.62 150.5,33.34 142.3,33.34 142,33.64 136.64,33.64 135.89,34.39 134.11,34.39 134.01,34.29 133.96,34.29 132.97,33.3 130.73,33.3 130.56,33.48 130.56,34.52 130.71,34.67 133.02,34.67 134.29,35.94 134.52,35.94 134.72,36.14 134.72,38.51 ; 3 cut-outs
V_DV11_HUB on TOP: 139.07,48.28 137.69,48.28 137.62,48.36 137.62,48.89 137.45,49.06 137.05,49.06 136.58,49.53 136.4,49.53 136.27,49.66 136.27,50.8 136.32,50.85 136.73,50.85 136.78,50.8 136.78,50.42 136.91,50.29 138.38,50.29 138.56,50.11 138.56,49.68 139.07,49.17 ; 2 cut-outs
V_DV12_HUB on TOP: 122.81,38.79 125.78,38.79 125.98,38.58 125.98,37.46 125.81,37.29 122.96,37.29 122.63,37.62 122.63,38.61
V_DV12_HUB on TOP: 112.19,42.16 111.1,42.16 110.52,41.58 110.52,40 110.01,39.5 109.73,39.5 108,37.77 107.65,37.77 107.52,37.64 107.52,34.7 107.65,34.57 108.61,34.57 108.76,34.72 109.58,34.72 109.86,35 109.86,36.7 110.11,36.96 110.11,37.46 110.77,38.12 111.15,38.12 112.24,39.22 112.24,39.78 111.46,39.78 111.3,39.93 111.3,41.81 111.48,41.99 112.14,41.99 112.19,42.04 ; 1 cut-out
V_DV12_HUB on TOP: 114.58,39.22 114.58,37.92 114.78,37.72 115.34,37.72 115.81,37.25 116.55,37.25 116.84,36.96 116.84,36.12 116.56,35.84 116.56,34.09 116.81,33.83 117.5,33.83 117.81,34.14 117.81,38 117.17,38.63 117.17,39.14 117.15,39.17 116.99,39.17 116.99,38.4 116.84,38.25 115.11,38.25 114.81,38.56 114.81,39.22 ; 1 cut-out
V_DV33_HUB on TOP: 131.37,54.3 134.37,54.3 134.49,54.18 134.49,53.44 133.96,52.91 132.66,52.91 132.18,52.43 132.18,51.21 131.93,50.95 131.56,50.95 131.27,50.66 131.27,48.89 131.14,48.77 130.43,48.77 130.33,48.87 130.33,50.82 130.99,51.49 130.99,53.92 ; 4 cut-outs
V_DVDD_1V0_PHY0 on TOP (solid shape): 146.28,66.32 146.28,65.25 146.56,64.97 147.52,64.97 147.66,64.83 147.66,62.65 148.11,62.2 148.11,61.67 148.03,61.59 147.32,61.59 147.09,61.82 147.73,61.82 147.73,62.05 147.4,62.05 147.4,61.82 147.09,61.82 146.81,62.1 145.42,62.1 143.89,63.63 143.89,63.88 147.19,63.88 147.19,64.39 146.81,64.39 146.81,63.88 143.89,63.88 143.89,64.13 144.1,64.35 145.19,64.35 145.45,64.6 145.45,66.28 145.59,66.42 146.18,66.42
V_DVDD_1V0_PHY0 on ART04 (solid shape): outline of 151 points within 137.95,63.25 144.53,73.35
V_HOT_12V0_D1 on TOP (solid shape): 52.58,138.94 52.58,137.29 53.09,136.78 53.09,129.59 51.94,128.45 46.18,128.45 45.59,129.03 45.59,137.79 47.04,139.24 48.08,139.24 48.16,139.32 52.2,139.32
V_HOT_12V0_D1 on TOP (solid shape): 102.82,143.53 102.82,139.39 103.61,138.61 105.56,138.61 106.1,138.07 106.1,137.32 106.41,137 106.41,136.64 107.04,136.02 108.59,136.02 108.86,135.74 108.86,132.92 108.61,132.66 106.81,132.66 106.71,132.77 105.05,132.77 103.73,134.09 103.73,135.56 102.92,136.37 101.12,136.37 99.95,137.54 99.95,142.75 100.91,143.71 102.64,143.71
V_HOT_12V0_D1 on TOP (solid shape): 87.99,143.31 87.99,141.89 87.83,141.68 87.77,141.42 87.96,140.97 88.41,140.78 88.48,140.79 88.55,140.8 88.58,140.81 88.7,140.69 89.83,140.69 90.67,139.86 90.67,136.14 90.94,135.87 90.93,135.86 90.93,132.89 90.82,132.78 87.19,132.78 86.33,133.63 86.33,135.74 85.83,136.25 85.81,136.23 83.73,136.23 83.36,136.6 83.36,139.52 83.47,139.63 85.75,139.63 85.75,139.65 86.21,140.11 86.21,141.66 86.23,141.73 86.25,141.81 86.25,143.62 86.28,143.66 87.63,143.66
V_HOT_12V0_D1 on TOP (solid shape): 73.03,138.96 73.03,137.03 74.42,135.64 74.42,134.24 74.04,133.86 74.04,133.85 73.69,133.5 73.59,133.42 73.51,133.32 72.68,132.49 72.55,132.49 72.33,132.66 72.06,132.72 71.61,132.53 71.42,132.08 71.43,132 68.53,132 67.96,132.58 67.95,132.59 67.79,132.88 67.49,133.05 67.48,133.06 67.39,133.15 67.39,135.2 66.83,135.76 66.42,135.76 65.91,136.27 65.91,139.2 66.16,139.45 67.11,139.45 67.51,139.85 72.14,139.85
V_HOT_12V0_D1 on TOP (solid shape): 37.97,134.84 38.33,134.84 38.33,131.34 37.82,130.83 37.62,130.83 37.34,130.56 37.34,130.55 37.05,130.26 37.05,130.16 37.03,130.15 37.05,130.15 37.05,128.09 37.08,128.09 37.08,127.51 36.93,127.51 36.93,127.73 36.59,127.73 36.57,127.75 36.57,128.4 34.42,128.4 34.16,128.14 34.16,127.76 33.93,127.76 33.93,127.51 33.78,127.51 33.78,128.63 36.8,128.63 36.8,128.85 36.47,128.85 36.47,128.63 33.78,128.63 33.78,128.65 36.04,128.65 36.04,128.98 35.76,128.98 35.76,128.65 35,128.65 35,128.98 34.75,128.98 34.75,128.65 34.42,128.65 34.42,128.93 34.06,128.93 34.06,128.65 33.78,128.65 33.78,129.64 36.83,129.64 36.83,129.9 36.42,129.9 36.42,129.64 33.78,129.64 33.78,129.69 34.44,129.69 34.44,129.97 33.99,129.97 33.99,129.69 33.78,129.69 33.78,131.37 34.24,131.83 34.24,134.84 34.42,134.84 34.42,135.33 34.65,135.56 37.97,135.56
V_HOT_12V0_D1 on ART04 (solid shape): 51.31,136.7 51.31,136.65 51.69,136.27 54.76,136.27 54.8,136.23 56.11,136.23 56.19,136.19 56.2,136.09 56.17,135.99 56.16,135.89 56.19,135.72 56.28,135.57 56.19,135.42 56.16,135.25 56.64,134.77 57.13,135.25 57.09,135.42 57.01,135.57 57.09,135.72 57.13,135.89 57.11,135.99 57.08,136.09 57.09,136.19 57.18,136.23 59.24,136.23 59.33,136.17 59.31,136.07 59.24,135.95 59.21,135.81 58.9,135.65 58.78,135.33 58.92,134.99 59.26,134.85 59.58,134.97 59.74,135.28 60.05,135.44 60.17,135.76 60.15,135.92 60.07,136.07 60.05,136.17 60.14,136.23 73.83,136.23 74.43,135.63 74.43,134.74 73.07,133.38 50.29,133.38 49.31,134.37 47.17,134.37 46.84,134.7 46.84,137.59 47.09,137.85 50.17,137.85
V_HOT_12V0_D1 on TOP: 45.49,108.31 46.48,107.31 46.48,91.52 44.83,89.86 40.44,89.86 40.06,90.25 30.53,90.25 30.15,90.63 30.15,91.72 30.28,91.85 30.28,92.68 31.22,93.62 44.27,93.62 45.21,94.56 45.21,101.38 42.2,104.39 26.75,104.39 26.04,105.1 26.04,107.26 26.19,107.42 33.63,107.42 33.96,107.75 33.96,109.58 35.15,110.77 44.4,110.77 45.49,109.68
V_HOT_12V0_D1 on BOTTOM: 34.93,135 37.97,135 38.23,134.75 41.77,134.75 45.56,130.96 46.99,130.96 47.75,130.2 47.75,119.13 47.12,118.49 47.12,117.73 46.99,117.6 46.99,117.35 44.07,114.43 44.07,104.52 43.79,104.24 39.93,104.24 39.62,104.55 39.62,110.72 40.21,111.3 40.21,125.12 37.52,127.81 35.64,127.81 34.54,128.9 34.54,134.62
V_HOT_12V0_D1 on BOTTOM: 100.28,142.87 90.25,142.87 86.97,139.6 83.67,139.6 81.28,141.99 75.69,141.99 72.97,139.27 72.97,139.19 72.52,138.73 72.52,135 72.9,134.62 73.91,134.62 75.57,136.27 89.87,136.27 89.92,136.22 97.84,136.22 99.75,134.31 102.26,134.31 102.67,133.91 104.52,133.91 104.9,134.29 104.9,138.25
V_HOT_12V0_D1 on ART03: 36.8,91.77 37.97,91.77 38.1,91.9 38.1,93.45 37.97,93.57 36.8,93.57 36.68,93.45 36.68,91.9
V_HOT_12V0_D1 on ART03: 40.39,91.72 42.39,91.72 42.52,91.85 42.52,93.24 42.39,93.37 40.39,93.37 40.26,93.24 40.26,91.85
V_HOT_12V0_D2 on TOP (solid shape): 153.09,47.29 153.09,45.39 153.82,44.65 153.82,43.15 153.59,42.93 150.19,42.93 149.94,43.18 149.94,47.22 150.09,47.37 153.01,47.37
V_HOT_12V0_D2 on TOP (solid shape): 123.44,30.48 123.27,30.3 120.57,30.3 120.05,29.78 119.62,29.78 119.45,28.8 115.09,28.8 114.94,28.96 114.94,29.46 115.19,29.72 115.82,29.72 119.51,33.4 123.44,33.4
V_HOT_12V0_D2 on ART03 (solid shape): 141.48,33.02 141.48,32.89 141.28,32.7 138.6,32.7 138.54,32.64 138.3,32.64 138.05,32.89 138.05,32.96 138.29,33.2 141.3,33.2
V_HOT_12V0_D2 on ART03 (solid shape): outline of 288 points within 101.4,49.02 140.33,59
V_HOT_12V0_D2 on TOP: 138.28,60.27 141.78,60.27 142.06,59.99 142.06,56.97 141.83,56.74 138.15,56.74 137.95,56.95 137.95,59.94
V_HOT_12V0_D2 on TOP: 137.54,33.15 140.46,33.15 140.84,32.77 140.84,29.46 140.59,29.21 137.29,29.21 137.16,29.34 137.16,32.77
V_HOT_12V0_D2 on TOP: 118.11,56.9 118.47,56.54 122.37,56.54 122.74,56.18 122.74,53.72 122.61,53.59 120.14,53.59 120.02,53.47 120.02,53.24 116.93,53.24 116.9,53.27 116.27,53.27 115.95,53.59 115.95,57.53 116.33,57.91 117.48,57.91 118.11,57.28
V_HOT_12V0_D2 on TOP: 103.42,60.34 104.75,60.34 105.16,59.93 105.16,53.06 104.72,52.63 104.72,52.58 104.39,52.25 104.39,49.91 103.63,49.15 101.47,49.15 101.35,49.28 101.35,52.07 101.73,52.45 102.24,52.45 102.9,53.11 102.9,59.82
V_HOT_12V0_D2 on TOP: 32.37,115.43 31.85,115.95 31.65,115.95 31.32,115.62 31.32,113.51 30.61,112.8 27.03,112.8 27.03,108.2 27.43,107.8 32.06,107.8 32.37,108.11 ; 8 cut-outs
V_HOT_12V0_D2 on TOP: 127.36,46.99 129.03,46.99 129.16,46.86 129.16,44.58 129.79,43.94 129.79,40.54 126.72,40.54 126.62,40.64 126.62,43.81 127.25,44.45 127.25,45.34 127.23,45.34 127.23,46.86
V_HOT_12V0_D2 on TOP: 101.75,35.43 104.39,35.43 104.52,35.56 104.52,37.97 104.11,38.38 101.78,38.38 101.42,38.02 101.42,35.76
V_HOT_12V0_D2 on BOTTOM: 118.75,57.84 123.76,55.44 127.89,51.21 127.89,45.72 127.51,45.34 126.92,45.34 126.37,45.9 126.37,49.4 126.49,49.4 126.42,50.38 126.28,50.59 126.09,51.13 123.24,54.28 119.14,56.4 116.46,56.9 116.33,57.02 116.33,57.66 116.51,57.84
V_HOT_12V0_D2 on BOTTOM: outline of 136 points within 26.79,36.96 104.75,113.59
V_HOT_12V0_D2 on ART04: 103,38.99 104.42,38.99 104.45,38.99 104.55,38.89 104.55,35.05 108.59,31.01 111.23,31.01 112.93,30.78 116.31,29.93 116.46,29.72 116.46,29.21 116.15,28.9 115.98,28.9 114.86,28.7 108.81,28.68 106.91,28.9 106.13,29.2 104.27,31.06 102.74,32.85 102.74,38.73
V_HOT_12V0_D3 on ART03 (solid shape): 32.06,72.44 32.06,68.22 31.93,68.1 30.81,68.1 30.68,68.22 30.68,72.44 30.81,72.57 31.93,72.57
V_HOT_12V0_D3 on ART03 (solid shape): 35.87,72.47 35.87,68.15 35.74,68.02 34.6,68.02 34.47,68.15 34.47,72.47 34.6,72.59 35.74,72.59
V_HOT_12V0_D3 on ART03 (solid shape): 39.37,72.36 39.37,68.25 39.24,68.12 38.48,68.12 38.35,68.25 38.35,72.36 38.48,72.49 39.24,72.49
V_HOT_12V0_D3 on ART03 (solid shape): outline of 248 points within 86.49,55.17 120.78,62
V_HOT_12V0_D3 on TOP: 51.54,59.79 51.54,49.05 51.13,48.64 47.22,48.64 46.58,49.28 46.58,59.79 47,60.21 47.02,60.2 51.13,60.2
V_HOT_12V0_D3 on TOP: 86.31,52.55 86.31,50.49 84.96,49.15 82.8,49.15 82.25,49.71 82.25,60.1 82.41,60.26 87.57,60.26 88.39,59.44 88.39,54.63
V_HOT_12V0_D3 on TOP: 44.65,75.39 44.91,75.13 44.91,68.63 44.3,68.02 27.41,68.02 26.47,68.96 26.47,71.12 26.82,71.48 29.06,71.48 30.12,72.54 30.12,73.84 31.67,75.39
V_HOT_12V0_D3 on TOP: 36.91,85.8 37.69,85.01 37.69,82.6 38.13,82.17 44.68,82.17 44.91,82.4 44.91,83.39 43.46,84.84 43.46,88.82 42.37,89.92 30.41,89.92 30.16,89.67 30.16,87.47 31.83,85.8 ; 8 cut-outs
V_HOT_12V0_D3 on TOP: 120.19,56.92 118.87,56.92 118.49,57.3 118.49,58.67 117.48,59.69 117.48,59.94 117.48,59.95 117.48,60.13 117.64,60.29 122.49,60.29 122.56,60.22 122.56,57.18 122.5,57.12 120.39,57.12
V_HOT_12V0_D3 on TOP: 100.1,53.33 100.1,56.74 99.82,57.02 99.82,59.89 100.2,60.27 102.24,60.27 102.41,60.1 102.41,53.21 102.27,53.07 100.36,53.07
V_HOT_12V0_D3 on TOP: 68.58,48.89 64.67,48.89 64.03,49.53 64.03,60.05 64.24,60.25 68.78,60.25 69.52,59.51 69.52,49.83
V_HOT_12V0_D3 on BOTTOM: 38.1,88.42 42.68,88.42 43,88.09 43,85.49 43.38,85.11 45.55,85.11 45.9,84.76 45.9,73.29 45.09,72.47 45.09,60.88 45.97,59.99 57.17,59.99 57.52,60.07 60.92,60.07 61.6,59.99 73.15,59.99 73.15,59.94 80.14,59.94 80.14,59.99 88.09,59.99 88.39,59.69 88.39,56.21 86.28,54.1 49.66,54.1 49.53,54.23 46.2,54.23 43.76,56.67 43.43,56.67 42.79,57.32 42.76,57.39 42.79,57.46 42.93,57.67 42.97,57.91 42.95,58.08 42.89,58.23 42.95,58.38 42.97,58.55 42.95,58.71 42.89,58.86 42.95,59.02 42.97,59.18 42.34,59.82 41.7,59.18 41.72,59.02 41.79,58.86 41.74,58.75 41.71,58.62 41.64,58.54 41.54,58.57 40.89,59.21 40.89,63.4 39.73,64.57 39.73,80.76 39.82,81.09 39.73,81.42 39.73,82.79 37.78,84.74 37.78,88.09
V_HOT_12V0_D3 on ART04: 65.1,60.88 68.83,60.88 70.36,59.36 70.36,52.02 67.54,49.2 47.7,49.2 43.56,53.34 43.56,65.28 41.92,66.92 41.92,69.48 40.34,71.07 40.34,84.61 40.59,84.86 40.59,88.67 41.15,89.23 44.09,89.23 47.14,86.18 47.14,72.41 48.69,70.87 55.12,70.87
V_HOT_12V_1 on BOTTOM (solid shape): 38.15,148.72 38.15,147.32 37.92,147.09 36.32,147.09 36.25,147.17 36.25,148.79 36.37,148.92 37.95,148.92
V_HOT_12V_1 on TOP: 44.12,84.89 44.4,84.61 46.36,84.61 46.99,85.24 46.99,88.52 46.38,89.13 44.55,89.13 44.12,88.7
V_HOT_12V_1 on TOP: 36.07,149.1 38.33,149.1 38.33,146.41 38.23,146.3 37.97,146.3 37.85,146.18 37.85,145.31 37.08,144.55 37.08,138.81 38.1,137.79 38.1,136.25 34.32,136.25 33.4,137.16 33.4,142.6 35.84,145.03 35.84,146.02 35.69,146.18 34.42,146.18 34.16,146.43 34.16,147 34.8,147 34.8,147.37 35.1,147.37 35.36,147.12 36.02,147.12 36.02,148.13 36.04,148.13 36.04,149.07 ; 1 cut-out
V_HOT_12V_1 on BOTTOM: 38.61,138.18 38.61,136.32 37.67,135.38 35.03,135.38 33.83,134.19 33.83,129.95 37.34,126.44 37.34,126.27 39.95,123.65 39.95,111.68 39.45,111.18 39.45,106.73 38.88,106.15 38.88,103.78 44.04,98.61 44.04,93.47 46.86,90.65 46.86,86.13 46.38,85.65 43.97,85.65 43.43,86.18 43.43,88.42 42.7,89.15 39.03,89.15 34.62,93.56 34.62,100.48 33.83,101.27 33.83,114.26 35.53,115.96 35.53,119.35 32.31,122.58 32.26,122.58 28.27,126.57 28.27,128.55 28.47,128.75 28.47,132.28 34.54,138.35 38.43,138.35
V_HOT_12V_2 on TOP: 30.3,135.03 32.69,135.03 33.05,134.67 33.05,131.98 31.62,130.56 31.62,126.49 31.5,126.36 31.37,126.36 31.24,126.24 31.24,123.82 30.3,122.88 30.3,114.96 30.73,114.53 30.73,113.69 30.51,113.46 27.03,113.46 26.7,113.79 26.7,120.55 27.81,121.67 27.81,123.55 27.28,124.08 27.28,125.42 29.46,127.61 29.46,131.44 28.96,131.95 28.17,131.95 28.02,132.1 28.02,133.02 28.22,133.22 29.79,133.22 30.05,133.48 30.05,134.77 ; 1 cut-out
V_HUB_3V3 on TOP: 108.33,34.29 109.35,34.29 109.6,34.04 109.6,31.75 109.47,31.62 108.46,31.62 108.08,31.24 107.54,31.24 107.54,31.44 107.29,31.44 107.29,31.24 106.93,31.24 106.81,31.37 106.81,31.62 107.06,31.62 107.06,31.88 107.82,31.88 108.2,32.26 108.2,34.16
V_HUB_5V0 on TOP (solid shape): 149.35,56.01 149.35,55.09 149.25,54.99 146.63,54.99 146.48,55.14 149.12,55.14 149.12,55.4 148.72,55.4 148.72,55.14 146.48,55.14 146.28,55.35 144.83,55.35 144.68,55.5 144.68,56.29 144.78,56.39 148.97,56.39
V_LTE_3V3 on TOP (solid shape): 118.75,181.84 118.75,176.71 119.69,175.77 119.69,172.24 119.38,171.93 117.98,171.93 117.81,172.11 117.81,175.62 116.64,176.78 116.64,177.11 117.37,177.11 117.37,177.44 116.92,177.44 116.92,177.11 116.64,177.11 116.64,178.05 117.45,178.05 117.45,178.33 116.94,178.33 116.94,178.05 116.64,178.05 116.64,179.4 116.74,179.5 116.74,179.75 116.75,179.78 116.78,179.82 116.8,179.88 116.81,179.93 116.82,179.98 116.81,180.04 116.8,180.09 116.78,180.14 116.75,180.19 116.74,180.21 116.74,180.68 116.75,180.71 116.77,180.76 116.78,180.82 116.78,180.89 116.77,180.94 116.75,180.99 116.74,181.03 116.74,181.2 116.77,181.23 116.82,181.28 116.87,181.33 116.91,181.39 116.94,181.46 116.97,181.53 116.98,181.6 116.99,181.67 116.99,181.74 116.99,181.81 116.97,181.87 116.95,181.93 116.94,181.96 117.07,182.09 118.49,182.09
V_LTE_3V3 on ART04 (solid shape): outline of 815 points within 116.81,93.14 153.29,182.12
V_LTE_3V3 on TOP: 154.69,80.14 155.07,80.14 155.17,80.03 155.42,80.03 156.08,79.37 156.52,79.37 156.72,79.17 156.72,76.66 156.52,76.45 155.19,76.45 154.31,77.34 154.31,79.88 154.69,79.88
V_LTE_3V3 on ART03: 152.27,100.46 158.65,100.46 160.12,98.98 160.12,82.07 156.62,78.56 154.89,78.56 154.31,79.15 154.31,80.77 158.06,84.53 158.06,90.96 158.32,91.21 158.32,97.28 157.66,97.94 155.5,97.94 154.89,97.33 154.89,90.47 154.71,90.3 149.35,90.3 147.96,88.9 145.21,88.9 144.7,89.41 144.7,89.89 144.91,90.09 145.24,90.09 146.05,90.91 146.05,94.61 146.28,94.84 147.02,94.84 147.75,94.11 150.88,94.11 151.13,94.36 151.13,99.31
V_LTE_3V8 on TOP (solid shape): outline of 151 points within 191.24,77.75 196.44,96.52
V_LTE_3V8 on ART03 (solid shape): 134.35,149.1 138.77,149.1 138.84,149.08 138.9,149.07 138.97,149.08 139.04,149.1 139.46,149.1 139.68,149.02 139.91,149.07 140.38,149.07 140.61,149.02 140.83,149.1 141.25,149.1 141.32,149.08 141.39,149.07 141.45,149.08 141.52,149.1 142.62,149.1 143.59,148.13 143.58,148.08 143.58,148.03 143.69,147.76 143.96,147.65 144.01,147.65 144.06,147.66 148.21,143.51 148.21,132.74 147.83,132.36 146.41,132.36 144.65,134.11 144.4,134.11 143.89,134.62 143.89,142.49 140.72,145.67 130.15,145.67 129.26,146.56 129.26,146.6 129.14,146.85 128.88,146.95 128.77,146.94 128.27,147.45 128.27,149.22 128.65,149.61 133.85,149.61
V_LTE_3V8 on ART04 (solid shape): outline of 535 points within 103.89,147.19 133.99,173.99
V_LTE_3V8 on ART04 (solid shape): outline of 547 points within 171.07,86.49 195.3,99.29
V_LTE_3V8 on TOP: 169.16,97.28 175.26,97.28 175.39,97.15 175.39,94.87 175.37,94.86 175.39,94.84 175.39,94.18 175.22,94.01 174.19,94.01 173.98,94.25 173.7,94.42 173.66,94.46 173.58,94.46 173.57,94.46 173.28,94.5 172.98,94.46 172.97,94.46 172.03,94.46 171.91,94.34 171.91,92.99 171.76,92.84 171.07,92.84 170.94,92.71 170.94,91.82 171.32,91.44 171.32,86.11 170.56,85.34 165.99,85.34 165.61,84.96 165.61,84.71 165.51,84.61 164.39,84.61 164.29,84.71 164.29,86.23 164.39,86.33 168.25,86.33 168.91,86.99 168.91,97.03 ; 7 cut-outs
V_LTE_3V8 on TOP: 96.88,175.13 96.88,172.85 97.51,172.21 106.43,172.21 106.55,172.34 106.55,173.74 105.89,174.4 101.57,174.4 100.74,175.23 96.98,175.23 ; 2 cut-outs
V_LTE_3V8 on ART03: 172.77,95.94 173.23,96.39 173.23,96.42 173.86,97.05 173.86,101.9 172.21,103.56 172.21,111.63 147.07,136.78 145.03,136.78 144.15,135.89 144.15,134.37 168.53,109.98 168.53,100.58 170.56,98.55 170.56,97.28 171.91,95.94
V_LTV_3V3 on TOP (solid shape): 85.37,183.04 86.03,182.38 86.03,176.64 84.33,174.94 81.14,174.94 81.08,175.01 81.08,175.16 81.97,175.16 81.97,175.49 81.41,175.49 81.41,175.16 81.08,175.16 81.08,175.59 81.11,175.62 81.92,175.62 82.14,175.85 82.14,176.46 82.19,176.51 84.23,176.51 84.73,177.02 84.73,179.71 84.25,180.2 81.1,180.2 80.98,180.32 80.98,180.44 81.76,180.44 81.76,180.7 81.33,180.7 81.33,180.44 80.98,180.44 80.98,180.82 81.03,180.88 81.96,180.88 82.19,181.11 82.19,182.28 82.65,182.74 83.77,182.74 84.48,183.45 84.48,183.46 85.37,183.46
V_LTV_3V3 on TOP (solid shape): 84.13,197.76 84.13,196.87 83.62,196.37 83.62,194.19 84.24,193.57 85.37,193.57 86.16,192.79 86.16,187.23 85.37,186.44 85.37,182.38 84.48,182.38 84.48,185.51 84.28,185.72 81.94,185.72 81.86,185.79 81.03,185.79 80.98,185.84 80.98,185.98 81.84,185.98 81.84,186.26 81.33,186.26 81.33,185.98 80.98,185.98 80.98,186.44 81,186.46 81.97,186.46 82.17,186.66 82.17,187.62 82.3,187.75 83.75,187.75 83.89,187.88 84.58,187.88 85.04,188.34 85.04,191.22 84.21,192.05 82.25,192.05 82.22,192.08 82.22,193.51 82.8,194.09 82.8,195.02 83.46,195.02 83.46,195.48 83.21,195.48 83.21,195.02 82.8,195.02 82.8,197.76 82.93,197.89 84,197.89
V_SDCARD_V33 on TOP (solid shape): 122.96,19.51 122.96,17.54 123.61,16.89 125.87,16.89 125.87,16.89 126.33,16.89 126.33,16.89 127.04,16.89 127.05,16.87 127.07,16.82 127.11,16.77 127.15,16.73 127.19,16.7 127.24,16.67 127.29,16.65 127.34,16.64 127.4,16.64 127.46,16.64 127.51,16.65 127.56,16.67 127.61,16.7 127.66,16.73 127.69,16.77 127.73,16.82 127.75,16.87 127.76,16.89 128.05,16.89 128.74,17.58 129.09,17.58 129.68,18.16 131.76,18.16 131.76,18.44 131.28,18.44 131.28,18.16 129.68,18.16 130.59,19.08 131.74,19.08 131.74,19.33 131.23,19.33 131.23,19.08 130.59,19.08 131,19.48 131.79,19.48 131.94,19.33 131.94,13.19 131.48,12.73 130.62,12.73 130.39,12.96 130.39,14.79 129.83,15.34 123.23,15.34 122.16,16.41 122.16,19.54 122.25,19.63 122.83,19.63
V_STBY_1V8 on TOP (solid shape): 161.21,37.19 161.24,37.16 161.93,37.16 161.93,36.58 161.65,36.3 161.65,35.38 161.62,35.36 160.05,35.36 160.02,35.38 160.02,35.48 161.39,35.48 161.39,35.71 160.33,35.71 160.33,35.48 160.02,35.48 160.02,36.14 160.38,36.5 160.38,37.21 160.55,37.39 161.21,37.39
V_STBY_1V8 on TOP (solid shape): 161.6,46.41 162.31,46.41 162.31,45.8 162.23,45.72 162.23,44.4 162.2,44.37 160.76,44.37 160.71,44.42 160.71,44.58 162.1,44.58 162.1,45.08 161.85,45.08 161.85,44.58 160.71,44.58 160.71,44.6 161.11,44.6 161.11,45.08 160.86,45.08 160.86,44.6 160.71,44.6 160.71,45.19 161.04,45.52 161.04,46.63 161.6,46.63
V_STBY_1V8 on TOP (solid shape): 33.22,159.08 33.22,158.01 33.2,157.99 32.13,157.99 32.02,158.1 30.09,158.1 30.07,158.11 30.07,158.24 31.85,158.24 31.85,158.47 31.42,158.47 31.42,158.24 30.07,158.24 30.07,158.27 30.76,158.27 30.76,158.44 30.4,158.44 30.4,158.27 30.07,158.27 30.07,158.5 30.2,158.62 31.75,158.62 31.9,158.77 31.9,159.03 32.16,159.28 33.02,159.28
V_STBY_1V8 on TOP (solid shape): outline of 90 points within 77.88,140.11 85.8,141.44
V_STBY_1V8 on TOP (solid shape): outline of 106 points within 92.58,168.4 96.48,192.51
V_STBY_1V8 on ART03 (solid shape): outline of 1798 points within 59.46,25.22 162.36,81.13
V_STBY_1V8 on ART04 (solid shape): outline of 161 points within 23.37,20.47 34.93,39.81
V_STBY_1V8 on TOP: 23.83,50.22 23.9,50.29 24.46,50.29 24.51,50.24 24.51,50.01 23.9,50.01 23.9,49.73 24.51,49.73 24.51,49.53 24.77,49.28 24.97,49.28 24.99,49.25 24.99,48.56 24.33,47.9 24.33,47.68 24.13,47.47 23.34,47.47 22.73,46.86 20.24,46.86 19.61,47.5 19.61,50.14 19.72,50.25 21.34,50.25 21.37,50.22 ; 3 cut-outs
V_STBY_1V8 on TOP: 19.05,117.2 19.71,117.2 19.89,117.02 19.89,116.66 20.09,116.46 21.21,116.46 21.21,116.2 21.84,116.2 21.84,115.14 21.59,114.88 20.32,114.88 19.02,116.18 19.02,117.17 ; 1 cut-out
V_STBY_1V8 on TOP: 183.24,78.1 183.74,78.1 183.85,78 183.85,77.09 184.28,76.66 184.28,76.2 184.02,75.95 182.07,75.95 181.86,76.15 181.86,77.49 181.99,77.62 182.75,77.62 ; 1 cut-out
V_STBY_1V8 on TOP: 69.9,150.09 70.57,150.09 72.19,148.46 72.19,143.97 74.62,141.54 75.36,141.54 76.09,140.81 77.93,140.81 78.03,140.71 78.03,140.33 78.18,140.18 78.18,140.08 78.11,140.01 73.95,140.01 73.84,140.12 73.84,140.13 73.76,140.21 67.54,140.21 67.12,139.79 65.91,139.79 65.06,138.94 65.02,138.94 64.9,138.81 63.75,138.81 62.87,139.7 62.13,139.7 62.05,139.78 62.05,140.97 62.2,141.12 68.43,141.12 68.45,141.15 68.45,140.84 69.09,140.84 69.09,141.54 71.27,141.54 71.38,141.64 71.38,143.22 70.75,143.85 69.33,143.85 67.77,145.41 66.55,145.41 66.5,145.47 66.5,146.56 66.74,146.8 67.42,146.8 67.56,146.94 67.56,147.24 67.74,147.42 68.45,147.42 68.55,147.32 68.55,145.62 68.98,145.2 70.36,145.2 71.02,145.87 71.02,148.22 69.72,149.52 69.72,149.91 ; 8 cut-outs
V_STBY_1V8 on TOP: 85.42,147.01 86.94,147.01 87.12,146.84 87.15,146.84 87.15,145.49 86.92,145.26 85.09,145.26 84.91,145.44 84.91,146 85.17,146.25 85.17,146.76 ; 1 cut-out
V_STBY_1V8 on TOP: 9.5,140.74 10.57,140.74 10.69,140.61 10.69,138.91 10.57,138.79 10.37,138.79 10.37,139.15 9.91,139.15 9.91,138.84 9.37,139.37 9.37,140.61 ; 1 cut-out
V_STBY_1V8 on BOTTOM: outline of 100 points within 9.27,34.65 61.09,159.38 ; 1 cut-out
V_STBY_1V8 on BOTTOM: 84.4,140.13 85.57,140.13 87.38,141.93 87.38,145.47 86.72,146.13 85.12,146.13 83.85,144.86 83.85,140.69
V_STBY_1V8 on BOTTOM: 73.87,160.04 73.21,160.71 71.58,160.71 70.61,161.67 69.34,161.67 69.2,161.53 69.2,160.9 69.27,160.83 69.27,159.92 69.62,159.56 72.1,159.56 72.51,159.15 72.51,158.1 72.36,157.96 72.36,154.89 69.22,151.74 69.22,149.73 69.7,149.25 70.71,149.25 71.76,150.29 71.76,151.67 73.87,153.78
V_STBY_1V8 on ART03: 65.91,160.78 54.51,160.78 53.24,159.51 42.42,159.51 40.26,161.67 34.67,161.67 33.02,160.02 33.02,159 32.77,158.75 32.18,158.75 31.93,159 31.93,161.34 33.53,162.94 41.02,162.94 42.42,161.54 52.32,161.54 53.72,162.94 91.87,162.94 92.99,164.06 92.99,168.81 93.22,169.04 93.98,169.04 94.11,168.91 94.11,163.22 92.18,161.29 70.36,161.29 70.23,161.16 66.29,161.16
V_STBY_1V8 on ART03: 31.24,27.56 31.75,27.56 33.78,25.53 36.07,25.53 36.83,24.76 38.48,24.76 38.81,24.43 38.81,22.73 38.43,22.73 37.82,22.12 37.82,21.67 37.69,21.54 35.69,21.54 30.73,26.49 30.73,27.05
V_STBY_1V8 on ART04: 161.09,54 161.09,55.42 160.55,55.96 160.55,59.99 161.49,60.93 164.16,60.93 171.15,67.92 178.23,67.92 184.76,74.45 184.76,76.31 184.35,76.72 184.04,76.72 182.09,74.78 176.7,72.48 175.95,71.73 175.08,71.73 173.51,70.15 169.77,70.15 162.13,62.51 161.67,62.51 160.7,62.12 158.39,59.82 158.39,54.41 159.13,53.67 160.76,53.67
V_STBY_1V8 on ART04: 162.05,45.69 160.71,45.69 160.07,45.06 160.07,44.37 160.81,43.64 160.81,36.12 160.93,35.99 161.67,35.99 161.75,36.07 161.75,41.22 162.23,41.71 162.23,45.52
V_STBY_3V3 on TOP (solid shape): 43.66,12.09 43.66,10.67 43.51,10.52 41.76,10.52 41.63,10.64 41.63,12.04 41.83,12.24 43.51,12.24
V_STBY_3V3 on TOP (solid shape): 58.52,163.19 58.52,161.44 58.24,161.16 57.56,161.16 57.3,161.42 57.3,163.25 57.38,163.32 58.39,163.32
V_STBY_3V3 on TOP (solid shape): 63.6,10.85 63.6,9.42 63.45,9.27 61.7,9.27 61.57,9.4 61.57,10.79 61.77,11 63.45,11
V_STBY_3V3 on TOP (solid shape): 54.08,11.96 54.08,10.34 53.92,10.18 52.17,10.18 52.04,10.31 52.04,11.96 52.2,12.12 53.92,12.12
V_STBY_3V3 on TOP (solid shape): 65.71,163.1 65.71,161.21 65.02,160.53 65.02,157.1 64.35,157.1 64.35,161.85 64.31,161.85 64.26,161.9 64.26,163.25 64.29,163.27 65.54,163.27
